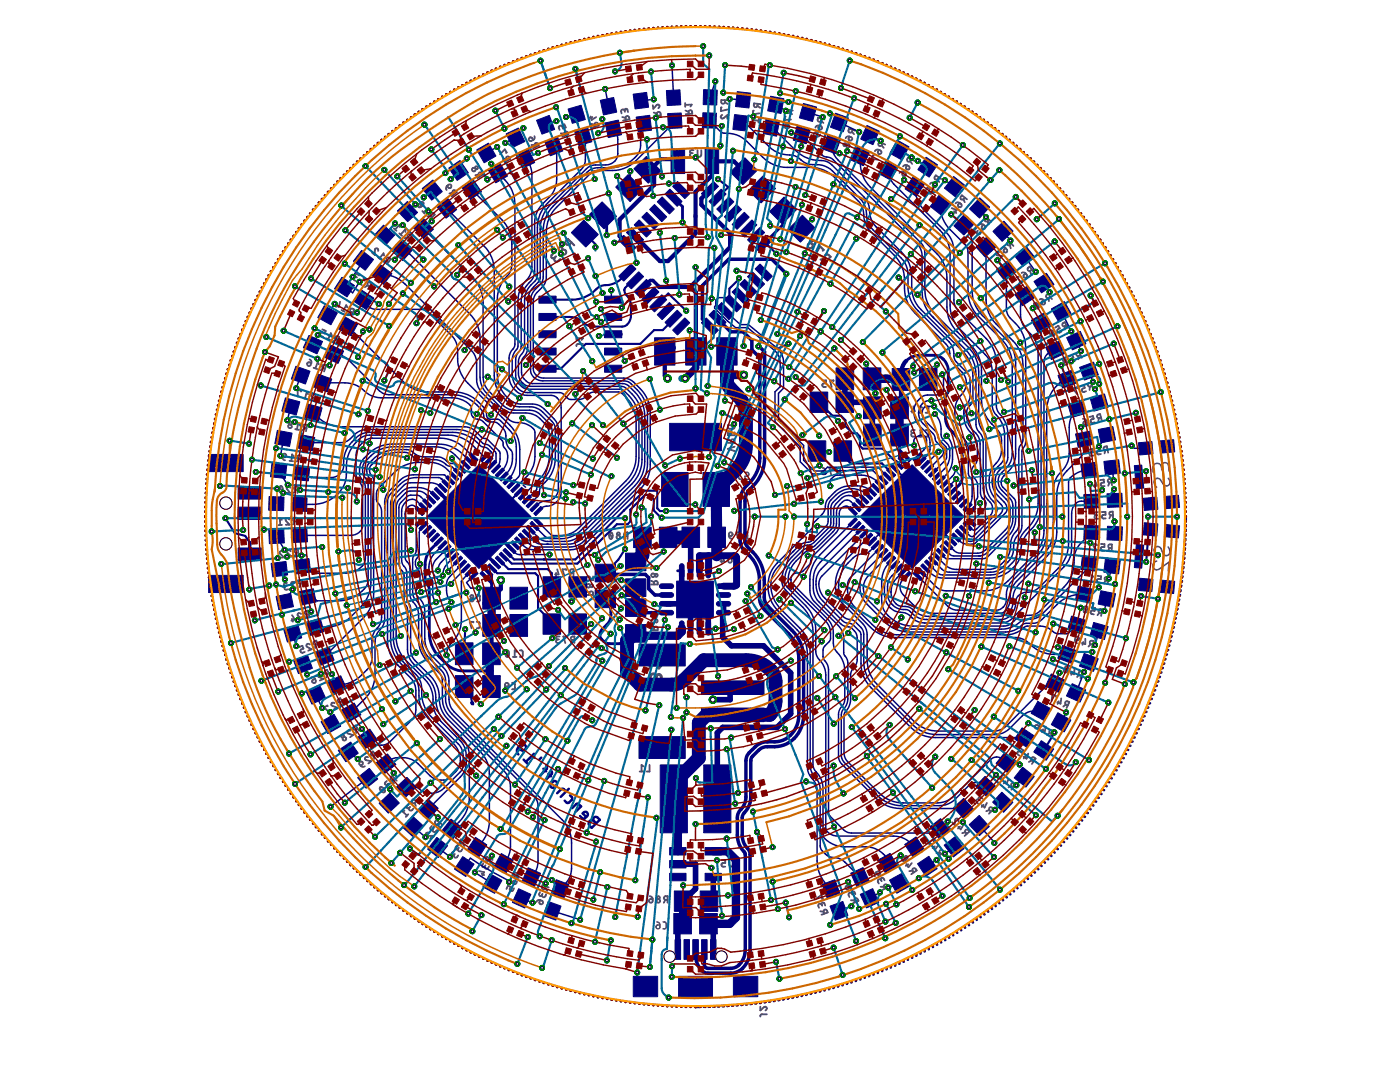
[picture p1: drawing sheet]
<svg xmlns="http://www.w3.org/2000/svg" width="279mm" height="216mm" viewBox="0 0 279 216" stroke-linecap="round" stroke-linejoin="round" font-family="sans-serif">
<g fill="none" stroke="#505050" stroke-width=".36">
<path d="M89.2 37.1l.3-.2a.37 .37 0 0 1 .5 0 .37 .37 0 0 1 0 .5 .37 .37 0 0 1-.5 0zM89.2 37.1l-.2 .5 .1 .3M90.3 38.5l-.6 .1M90.6 38.8l-.2-.3a.36 .36 0 0 1 0-.5 .36 .36 0 0 1 .5 .1l.3 .3-1.1 .8M95.5 34.9l-.6 .1M95.8 35.2l-.2-.3a.36 .36 0 0 1 .1-.5 .36 .36 0 0 1 .5 .1l.2 .3-1.1 .8M101 31.7h-.6M101 30.5l.1-.1-.3-.6-1 1M101.2 32.1l-.2-.4a.36 .36 0 0 1 .2-.4 .36 .36 0 0 1 .5 .1l.1 .3-1.1 .7M105.6 27.5l.4-.1 .4 .6-.6 .1-.2-.2zM106 28.9l.7 .1M106.7 27.2v.3l-.3 .5"/>
<path d="M106.9 29.4l-.2-.7 .4-.2 .4 .5-1.1 .6M111.9 26.6l.7 .1M112.6 24.8l.3 .6-.5 .3-.3-.6h-.4l-.2 .3 .2 .5M112.7 27.1l-.1-.4a.36 .36 0 0 1 .2-.4 .36 .36 0 0 1 .5 .2l.1 .3-1.2 .5M117.9 23.2l.2 .7 .9-.5M118 24.7l.6 .1M118.2 23.4l-.6 .1M118.8 25.3l-.1-.4a.37 .37 0 0 1 .2-.4 .37 .37 0 0 1 .5 .2l.1 .4-1.3 .3M124.2 23.3l.6 .2M124.7 22.1a.36 .36 0 0 0-.5-.3 .36 .36 0 0 0-.2 .5v.3M124.7 22.3v-.4l.2-.2 .3 .1 .1 .6M124.9 23.9v-.6l.4-.1 .3 .6-1.2 .3"/>
<path d="M130.3 21l.1 .7 .6-.7a.36 .36 0 0 1 .6 0 .36 .36 0 0 1-.2 .6M130.5 22.5l.6 .2M131.1 23.1v-.4a.36 .36 0 0 1 .3-.4 .36 .36 0 0 1 .4 .3l.1 .4-1.3 .2M136.7 20.6l.1 .7M136.8 20.9h1.2l-.2 .4M136.8 22.1l.6 .2M137.4 22.7l.1-.6a.36 .36 0 0 1 .4-.1 .36 .36 0 0 1 .2 .4l.1 .3-1.4 .1M138 30.6a.36 .36 0 0 0-.3 .3 .36 .36 0 0 0 .3 .4h.4M138.4 30h-.4l-.3 .2 .1 .3 .5 .1M139.2 30v.9a.37 .37 0 0 0 .4 .4 .37 .37 0 0 0 .4-.4v-.9M144 21.4h-.1v.8l1.3-.4M144.1 22.9a.36 .36 0 0 0-.3 .5 .36 .36 0 0 0 .6 .2l.8-.6-.1 .7"/>
<path d="M144.7 20v.4a.37 .37 0 0 1-.4 .3 .37 .37 0 0 1-.4-.4l.1-.3h1.3M144.7 20.4l.5 .3M150.4 23.6l-.3 .3 1.3 .2M150.5 22.1h-.2l-.1 .7 1.4-.2M151.2 21.1l.5 .4M151.2 20.7v.4a.37 .37 0 0 1-.4 .3 .37 .37 0 0 1-.4-.4l.1-.4 1.3 .2M151.4 23.7v.7M156.3 25a.73 .73 0 0 1 1.2 .4 .73 .73 0 0 1-1.2-.4zM156.8 23.3l-.1-.1-.2 .8 1.4-.1M157.4 25l-.9 .4M157.6 22.4l.5 .4M157.6 21.9l-.2 .6-.3 .1-.2-.3v-.5l1.3 .3"/>
<path d="M162.5 26.5l.3-.1 .3 .2-.1 .6-.6-.3zM163.4 25.1h.4a.37 .37 0 0 1 .3 .5 .37 .37 0 0 1-.5 .3 .37 .37 0 0 1-.3-.4zM163.4 25.1l-.5 .1-.2 .3M163.7 26.8l-.2 .3-.5 .1M163.9 24.1l.4 .4M164 23.7l-.1 .3a.36 .36 0 0 1-.5 .3 .36 .36 0 0 1-.2-.5l.1-.3 1.2 .3M169.5 27.2l.3 .2a.36 .36 0 0 1 .3 .4 .36 .36 0 0 1-.5 .3 .36 .36 0 0 1-.2-.5zM169.5 27.2h-.4l-.3 .4M170 26.3l.5 .5M170.1 25.9l-.1 .3a.37 .37 0 0 1-.4 .3 .37 .37 0 0 1-.3-.5l.2-.3 1.2 .4M174.4 31.1l-.2-.1-.3 .7 1.4 .2M175.4 29.9l.3 .1a.37 .37 0 0 1 .2 .5 .37 .37 0 0 1-.5 .2 .37 .37 0 0 1-.2-.4z"/>
<path d="M175.4 29.9h-.5l-.3 .3M175.9 29l.5 .5M176.1 28.6l-.4 .5-.4-.1 .2-.7 1.2 .6M180.3 34.3l.3 .2a.36 .36 0 0 1 .2 .5 .36 .36 0 0 1-.5 .1 .36 .36 0 0 1-.2-.4zM180.3 34.3h-.5l-.3 .2M181 33l.4 .2a.37 .37 0 0 1 .1 .4 .37 .37 0 0 1-.5 .2 .37 .37 0 0 1-.2-.4zM181 33l-.3-.1-.5 .3M181.7 32.2l.3 .5M181.9 31.8l-.2 .3a.36 .36 0 0 1-.5 .1 .36 .36 0 0 1-.1-.5l.1-.3 1.2 .7M184.7 38.1l.4-.7 .5 .4-.2 .3a.36 .36 0 0 0 .1 .5 .36 .36 0 0 0 .4-.1l.3-.3M186.4 36.5l.3 .2a.37 .37 0 0 1 .1 .5 .37 .37 0 0 1-.4 .2 .37 .37 0 0 1-.2-.5zM186.4 36.5l-.3-.1-.5 .3"/>
<path d="M187.1 35.8l.3 .5M187.3 35.4l-.4 .5-.4-.3 .3-.6 1 .7M192.3 39.8l.2 .5M192.5 39.4l-.5 .4a.35 .35 0 0 1-.3-.2 .35 .35 0 0 1 0-.3l.3-.3 1 .8M71.1 55.2a.37 .37 0 0 0-.6 .2 .37 .37 0 0 0 .2 .5l.3 .1M71.6 56.5l.6 .4M71.7 55l-.5-.3-.2 .1-.1 .3 .3 .3M72.8 56l-.2-.4-.7 1.1M73.4 56.9l-.6 .4M73.8 57.2l-.5-.5 .2-.4 .6 .3-.7 1.1M75.5 50.1a.35 .35 0 0 0-.3-.5 .35 .35 0 0 0-.4 .3v1l-.5-.4M75.5 51.4l.5 .4"/>
<path d="M76.6 51l-.1-.5-.8 1.1M77.2 52l-.6 .3M77.6 52.2l-.3-.2a.37 .37 0 0 1-.1-.5 .37 .37 0 0 1 .5-.1l.3 .3-.8 1M78.6 45.6l.5 .5M79.7 46.6l.5 .5M79.8 45.3l-.1-.5-.9 1M80.9 46.3l-.1-.5-.8 1M81.4 47.3l-.6 .2M81.7 47.6l-.4-.5 .3-.4 .6 .4-.9 .9M83.8 40.6l.4-.3 .3 .1a.78 .78 0 0 1-1 .9v-.3zM84.1 40.4l-.2 .9M84.3 42.1l.5 .6"/>
<path d="M85.5 42v-.5l-1 .9M85.9 43l-.6 .2M86.2 43.3l-.2-.2a.37 .37 0 0 1 0-.6 .37 .37 0 0 1 .5 0l.3 .3-1 .9M189.9 41.5l1 .4-.4 .6M190.4 42.1l.4 .4M191.5 40.5l.3 .2a.37 .37 0 0 1 .1 .5 .37 .37 0 0 1-.5 .1 .37 .37 0 0 1-.2-.5zM191.5 40.5l-.3-.1-.5 .2M194.8 45.5l-.3 .5v.2l.4 .1 .3-.3M195 46.2a.37 .37 0 0 0 0 .5 .37 .37 0 0 0 .6 0l.2-.3M196.3 44.8l.2 .3a.36 .36 0 0 1 .1 .5 .36 .36 0 0 1-.5 0 .36 .36 0 0 1-.1-.5zM196.3 44.8l-.5-.1-.3 .2M197.1 44.2l.2 .6"/>
<path d="M197.4 43.8l-.6 .4-.3-.3 .3-.6 1 .9M199.4 50.3a.36 .36 0 0 0-.6 .2 .36 .36 0 0 0 .3 .5l1 .1-.5 .5M199.9 49.5l.3-.2 .5 .2M200.4 49.8l.3-.3 .2 .3a.36 .36 0 0 1 0 .5 .36 .36 0 0 1-.5 0 .36 .36 0 0 1 0-.5zM201.5 48.9l.2 .7M201.8 48.6l-.5 .4-.3-.4 .4-.5 .8 1M203.3 55.3h-.4l.8 1M203.9 54.5l.5-.1 .3 .2M204 56.1l-.6 .4M204.3 54.9l.4-.3 .2 .2a.37 .37 0 0 1-.2 .6 .37 .37 0 0 1-.4-.5zM205.6 54l.1 .7M206 53.8l-.3 .2a.36 .36 0 0 1-.6-.1 .36 .36 0 0 1 .1-.5l.3-.2 .8 1"/>
<path d="M207.5 59.8l.4-.2 .4 .3M209.3 59.5v.6M209.6 59.2l-.3 .2a.37 .37 0 0 1-.5-.1 .37 .37 0 0 1 .1-.5l.3-.2 .7 1.1M60.1 78.1v-.1l-.7-.2v1.3M60.5 79.4l.7 .2M61.4 72.3l.7 .2-.1 .3a.37 .37 0 0 1-.6 .1 .37 .37 0 0 1 0-.6zM61.5 78.7l-.3-.4-.3 1.2M61.8 71.7l.3 .4v.4M62.4 79.4l-.5 .4M62.6 73.4l.7 .2M62.8 79.5l-.6-.3 .1-.5 .7 .1-.4 1.2M63.6 72.7l-.2-.4-.5 1.2"/>
<path d="M64.3 65.7l.7 .3-.2 .5-.4-.1a.37 .37 0 0 0-.4 .2 .37 .37 0 0 0 .1 .4l.4 .2M64.5 73.4l-.5 .5M64.9 73.6l-.6-.4 .2-.4 .6 .1-.4 1.2M65.2 67.5l.6 .3M66.2 66.9l-.2-.4-.5 1.2M67 67.7l-.5 .4M67.3 60.7l-.2 .6M67.4 67.9l-.3-.1a.37 .37 0 0 1-.2-.5 .37 .37 0 0 1 .5-.2l.3 .1-.5 1.2M67.9 60.2l-.3 1.1-.6-.4M68.2 61.9l.6 .3M69.3 61.3l-.2-.4-.6 1.1M70 62.2l-.6 .4"/>
<path d="M70.4 62.4l-.5-.4 .1-.3 .3-.1 .4 .2-.6 1.1M115 67.1v.7M115 67.5h1.4l-.3 .3M116.4 68.6l-1.2 .1-.2 .4M164.1 75.9h.7v.6h-.4a.37 .37 0 0 0-.3 .4 .37 .37 0 0 0 .3 .3h.4M166.3 76.1v-.2h-.7l.4 1.3M167.4 76.6l-.3 .6M167.8 76.6h-.4a.37 .37 0 0 1-.3-.3 .37 .37 0 0 1 .3-.4h.4v1.3M173.9 74.9h.7v.6h-.4a.36 .36 0 0 0-.3 .4 .36 .36 0 0 0 .3 .3h.4M175.4 76.2h.7M176.1 75.2l-.3-.3v1.3M176.6 75.5l.6-.1v.4a.37 .37 0 0 1-.5 .3 .37 .37 0 0 1-.1-.6z"/>
<path d="M176.6 74.8l.4 .2 .2 .4M176.8 74.9l.4 .1 .2 .2v.9l-.6 .1M178 76.1h.7M178.7 75.1l-.4-.3v1.3M179.4 74.8l.4 .1 .1 .2v.9l-.5 .1M206.4 60.9l.9 .2M206.5 60.5a.77 .77 0 0 1 .7 1 .75 .75 0 0 1-.7-1zM207.9 60.2l.4-.3 .2 .3a.37 .37 0 0 1-.1 .5 .37 .37 0 0 1-.5 0 .37 .37 0 0 1 0-.5zM209.5 66a.37 .37 0 0 1 .6 0 .37 .37 0 0 1-.1 .5l-.4 .2-.2-.4zM209.6 66.7l.3 .3h.5M210.6 65.4l.6-.4 .3 .5-.4 .2a.37 .37 0 0 0-.1 .5 .37 .37 0 0 0 .5 .2l.4-.3M212.5 65.1v.7"/>
<path d="M212.9 64.9l-.7 .2-.2-.4 .5-.4 .6 1.1M213.3 71.1l.7-.3 .2 .6-.4 .1a.37 .37 0 0 0-.1 .5 .37 .37 0 0 0 .4 .2l.4-.2M214.9 77.5v-.2l-.7 .3 .8 1.1M215.2 71v.7M215.6 77.1l.7-.3 .2 .6-.4 .1a.37 .37 0 0 0-.2 .5 .37 .37 0 0 0 .4 .2l.4-.1M215.6 70.9l-.3 .1a.36 .36 0 0 1-.5-.2 .36 .36 0 0 1 .2-.4l.3-.2 .6 1.2M217.5 77.2l-.1 .6M217.9 77l-.3 .1a.36 .36 0 0 1-.5-.2 .36 .36 0 0 1 .2-.4l.4-.2 .4 1.3M55.8 97.3l.5 .7M55.9 97h.1a.66 .66 0 0 1 .4 .6 .66 .66 0 0 1-.5 .7l-.2-.7zM56.4 91.2v.4l.5 .2M56.5 90.6a.37 .37 0 0 1 .6 .2 .37 .37 0 0 1-.3 .4h-.4z"/>
<path d="M57.8 91.9l.7 .1M57.9 97.3a.36 .36 0 0 0-.5-.3 .36 .36 0 0 0-.1 .6l.6 .7h-.7M58.6 91l-.3-.3-.2 1.3M58.9 85.6l.7 .2M58.9 97.8l-.3 .6M59.4 97.8h-.4a.36 .36 0 0 1-.3-.4 .36 .36 0 0 1 .3-.3h.4v1.3M59.6 91.6l-.4 .5M59.8 84.8l-.3-.4-.2 1.3M60 91.6h-.3a.36 .36 0 0 1-.3-.4 .36 .36 0 0 1 .4-.4l.3 .1-.1 1.3M60.7 85.4l-.4 .5M61.2 85.5l-.4-.1a.37 .37 0 0 1-.3-.4 .37 .37 0 0 1 .4-.3l.4 .1-.2 1.2M145.3 88.4h1.3v-.4a.37 .37 0 0 0-.4-.3 .37 .37 0 0 0-.3 .3v.4"/>
<path d="M145.3 86.3v.5h1.3v-.5M145.3 87.7l.6 .2M146 86.4v.4M146.6 84.8l-.1 .7-.9 .1-.3-.2v-.6h.7v.2M146.6 89.1l-1.3 .5 1.3 .4M164.1 94l.6-.1v.4a.38 .38 0 0 1-.5 .3 .38 .38 0 0 1-.1-.6zM164.1 93.4l.4 .1 .2 .4M166.2 93.5v-.1h-.7l.4 1.3M167.3 94.1l-.3 .6M167.7 94.1h-.4a.36 .36 0 0 1-.3-.4 .36 .36 0 0 1 .3-.3h.4v1.3M182.1 81.8v.6M182.2 86.4a.37 .37 0 0 0-.4 .4 .37 .37 0 0 0 .4 .3h.4"/>
<path d="M182.3 81.1l.3 1h-.8M182.6 85.8h-.6l-.2 .2 .2 .4h.4M183.3 87.1h.8M183.3 82.4h.8M184.1 86.1l-.4-.3v1.3M184.1 81.3l-.4-.2v1.3M184.7 85.8h.4l.2 .3-.1 .9-.5 .1M184.7 81.1h.4l.2 .2-.1 1-.5 .1M216.1 83.6l.5 .1 .2 .3M216.3 84.2l.5-.2 .1 .3a.38 .38 0 0 1-.4 .5 .38 .38 0 0 1-.2-.6zM217.3 89.7l.7-.1 .1 .6-.4 .1a.37 .37 0 0 0-.2 .4 .37 .37 0 0 0 .3 .3l.4-.1M217.4 83.2l.7-.2 .2 .6-.5 .1a.38 .38 0 0 0-.1 .4 .38 .38 0 0 0 .4 .3l.4-.1"/>
<path d="M218.4 96.7l.1 .5M218.5 95.9l.4 1-.7 .1M218.7 89.5l.8-.2 .1 .6-.5 .1a.36 .36 0 0 0-.2 .4 .36 .36 0 0 0 .4 .3l.4-.1M219.3 83.4l-.1 .7M219.6 95.8l.7-.1v.6h-.4a.37 .37 0 0 0-.2 .4 .37 .37 0 0 0 .3 .3h.5M219.7 83.3l-.6 .1-.2-.3 .1-.3 .5-.2 .4 1.3M220.6 89.8l-.2 .7M221 89.7l-.3 .1a.36 .36 0 0 1-.5-.3 .36 .36 0 0 1 .3-.4l.4-.1 .2 1.3M221.4 96.3l-.2 .6M221.8 96.2l-.3 .1a.36 .36 0 0 1-.4-.3 .36 .36 0 0 1 .3-.4l.3-.1 .2 1.3M56.2 103.7l-.3-.2v1.3M56.3 104.8h-.8"/>
<path d="M56.5 110.2a.35 .35 0 0 0-.5-.2 .35 .35 0 0 0 0 .6l.7 .6-.8 .1M57 117l-.3 .3a.35 .35 0 0 0 .5 .4l.4-.1M57.3 116.3l-.6 .2-.1 .2 .1 .2h.6M57.7 103.7a.36 .36 0 0 0-.5-.3 .36 .36 0 0 0-.1 .6l.7 .7h-.8M58 110a.36 .36 0 0 0-.5-.2 .36 .36 0 0 0-.1 .6l.7 .6-.7 .1M58.8 104.1l-.3 .5M58.8 116.3a.36 .36 0 0 0-.6-.2 .36 .36 0 0 0 .1 .6l.7 .6-.7 .2M59.1 110.3l-.2 .6M59.2 104l-.4 .1a.37 .37 0 0 1-.3-.4 .37 .37 0 0 1 .3-.4h.4v1.3M59.5 110.3l-.6-.1-.1-.5 .6-.2 .2 1.3M59.9 116.5l-.2 .7M60.3 116.4l-.3 .1a.36 .36 0 0 1-.5-.3 .36 .36 0 0 1 .3-.4l.4-.1 .3 1.3"/>
<path d="M95.2 118.7h.4l.2 .3v.8l-.6 .2M111 114.3v.6M111.2 113.6l.3 1h-.7M113 113.7v-.1h-.8l.4 1.3M114 114.3l-.3 .6M114.4 114.3h-.3a.36 .36 0 0 1-.4-.3 .36 .36 0 0 1 .4-.4h.3v1.3M117.1 118.7h1.3v-.4a.36 .36 0 0 0-.4-.3 .36 .36 0 0 0-.4 .3v.4M117.1 118l.5 .3M118.4 115v.8h-.6v-.5a.38 .38 0 0 0-.4-.3 .38 .38 0 0 0-.3 .3v.5M121.6 106.5l.6 .8M121.7 106.3h.1a.69 .69 0 0 1 .5 .6 .69 .69 0 0 1-.4 .6 .82 .82 0 0 1-.2-1.2zM124.8 107l-.3 .5"/>
<path d="M125.2 107h-.3a.36 .36 0 0 1-.4-.4 .36 .36 0 0 1 .4-.4h.3v1.3M130 116.6h1.3v-.3a.36 .36 0 0 0-.4-.4 .36 .36 0 0 0-.4 .4v.3M130 115.9l.5 .3M130 113.3h1.3l-.3 .4M130 112.9v.8M144 111.7v.6M144.2 111l.3 1h-.7M145.3 111v.9a.36 .36 0 0 0 .4 .4 .36 .36 0 0 0 .3-.4v-.9M145.5 106.9l.2 .5 .3 .1M145.6 106.3a.37 .37 0 0 1 .5 .1 .37 .37 0 0 1-.2 .5h-.4zM147.7 106.4v-.2h-.7l.3 1.3M148.7 106.9l-.3 .6"/>
<path d="M149.2 106.9h-.4a.36 .36 0 0 1-.4-.3 .36 .36 0 0 1 .4-.4h.4v1.3M217.4 116l.7 .1M218.2 115.1l-.3-.3-.2 1.3M218.8 102.8l-.3 .1-.1 .4 .3 .2h.5M218.9 108.8a.35 .35 0 0 0-.5-.3 .35 .35 0 0 0-.1 .6l.6 .7h-.7M219 114.9l.8 .1-.1 .6-.6-.1-.2 .4 .1 .3 .6 .1M219.1 102.2l-.5 .1-.2 .1 .2 .4h.4M219.7 108.5l.7 .1v.6l-.4-.1a.38 .38 0 0 0-.3 .4 .38 .38 0 0 0 .2 .4h.5M219.9 102.2h.7v.5h-.4a.37 .37 0 0 0-.3 .4 .37 .37 0 0 0 .3 .4l.5-.1M220.7 115.8l-.4 .6M221.1 115.9l-.6-.2 .1-.5h.6l-.2 1.3M221.4 109.3l-.3 .6"/>
<path d="M221.7 102.8l-.3 .6M221.9 109.4l-.4-.1a.36 .36 0 0 1-.3-.3 .36 .36 0 0 1 .3-.4h.4l-.1 1.3M222.1 102.8l-.7-.1v-.5l.7-.1v1.3M58.3 123.5l.1 .6M58.3 122.7l.5 .9-.7 .2M59.7 129.1l.6-.2 .3 .5-.5 .2a.38 .38 0 0 0-.1 .4 .38 .38 0 0 0 .4 .3l.4-.2M60.1 122.5a.36 .36 0 0 0-.6-.1 .36 .36 0 0 0 .1 .6l.8 .5-.7 .2M61.2 122.6l-.1 .7M61.6 122.5l-.5 .1a.35 .35 0 0 1-.3-.3 .35 .35 0 0 1 .3-.4l.3-.1 .4 1.3M61.8 128.6a.36 .36 0 0 0-.5-.1 .36 .36 0 0 0 .1 .6l.8 .5-.7 .2M62.1 135.2l.3-.1 .4 .3M62.4 135.7l.4-.3 .2 .4a.37 .37 0 0 1-.4 .5 .37 .37 0 0 1-.2-.6z"/>
<path d="M62.9 128.7v.6M63.4 128.5l-.4 .1a.36 .36 0 0 1-.4-.2 .36 .36 0 0 1 .2-.4l.3-.2 .5 1.3M64.1 134.6a.36 .36 0 0 0-.6-.1 .36 .36 0 0 0 .1 .6l.9 .4-.7 .3M65.2 134.5v.7M65.6 134.3l-.3 .2a.37 .37 0 0 1-.5-.2 .37 .37 0 0 1 .2-.5l.3-.1 .5 1.2M68.3 140l-.4 .1a.37 .37 0 0 1-.4-.1 .37 .37 0 0 1 .1-.5l.3-.2 .6 1.2M94.5 124.2v-.1h-.8l.4 1.3M95.1 124.1h.5l.1 .3v.8l-.6 .2M100.8 137l.2 .4 .4 .1M100.9 136.4a.36 .36 0 0 1 .6 0 .36 .36 0 0 1-.3 .6h-.4zM100.9 130.1l.6 .7M101 129.9l.2-.1a.78 .78 0 0 1 0 1.3 .83 .83 0 0 1-.2-1.2z"/>
<path d="M102.2 136.2l.4 .1 .2 .2-.1 .9-.5 .1M102.4 131.1h.7M103.1 130.1l-.4-.3v1.3M103.8 129.8h.4l.1 .3v.8l-.5 .2M111.3 127.6a.36 .36 0 0 0-.3 .4 .36 .36 0 0 0 .3 .3h.4M111.7 127h-.4l-.3 .2v.3l.5 .1M113.2 127.1v-.1h-.8l.4 1.3M114.2 127.7l-.3 .6M114.6 127.7h-.3a.37 .37 0 0 1-.4-.3 .37 .37 0 0 1 .4-.4h.3v1.3M130 125.8h1.3v-.4a.36 .36 0 0 0-.4-.4 .36 .36 0 0 0-.4 .4v.4M130 122v.8l.7-.6a.36 .36 0 0 1 .5 .1 .36 .36 0 0 1-.2 .5M130 125l.5 .3"/>
<path d="M210.7 139v-.1l-.6-.3-.3 1.3M211.3 139.9l-.2 .6M211.8 139.4l-.2 1-.6-.3M214 134.1l-.2 .6M214.4 133.5v1.1l-.7-.3M214.5 127.6l.2 .6 .2 .2M214.7 127.1a.37 .37 0 0 1 .6 .2 .37 .37 0 0 1-.3 .5l-.5-.2zM215.4 134.6l-.5 .5M215.8 134.8l-.5-.3v-.4l.3-.1 .5 .1-.5 1.2M216.2 128.1l-.2 .6M216.4 121.2l.4 .8M216.5 121.1l.2-.1a.76 .76 0 0 1-.2 1.2l-.2-.1-.1-.3z"/>
<path d="M216.6 127.5v1l-.7-.2M217.7 128.5l-.5 .5M217.8 121.2l.8 .1-.2 .6-.4-.1a.36 .36 0 0 0-.3 .3 .36 .36 0 0 0 .2 .4l.4 .1M218.1 128.7l-.6-.4 .1-.4h.7l-.4 1.3M219.4 122.2l-.4 .5M219.9 122.3l-.7-.2 .1-.5h.7l-.2 1.3M65.4 140.9l-.1-.1-.6 .3 1 1M66.8 140.3a.36 .36 0 0 0-.6 0 .36 .36 0 0 0 .2 .6l.9 .3-.7 .3M67.9 140.2v.6M69.9 145.8a.36 .36 0 0 0-.6 .1 .36 .36 0 0 0 .3 .5l.9 .3-.6 .4M71 145.6l.1 .7M71.4 145.4l-.3 .2a.36 .36 0 0 1-.6-.1 .36 .36 0 0 1 .2-.5l.3-.2 .7 1"/>
<path d="M71.8 152a.37 .37 0 0 1 .5 .1 .37 .37 0 0 1 0 .4l-.3 .3-.3-.4zM72 152.8l.3 .2 .5-.1M73.4 151.1a.36 .36 0 0 0-.5 .1 .36 .36 0 0 0 .3 .5l.9 .2-.6 .4M74.5 150.8l.2 .6M74.9 150.5l-.3 .2a.36 .36 0 0 1-.5 0 .36 .36 0 0 1 0-.5l.3-.3 .8 1.1M75.8 157.5l1 .1M75.9 157.1a.78 .78 0 0 1 .9 1 .75 .75 0 0 1-.9-1zM77.2 155.8l-.3 .3a.29 .29 0 0 0 0 .4 .29 .29 0 0 0 .4 .1l.2-.2M77.3 156.5l-.1 .3 .3 .3 .6-.3M78.5 155.7l.1 .6M78.8 155.4l-.3 .2a.36 .36 0 0 1-.5 0 .36 .36 0 0 1 0-.5l.3-.3 .9 1M83.1 159.9l-.6 .4-.3-.2v-.3l.3-.4 1 .9"/>
<path d="M127.7 153.9h.7M128.4 152.9l-.4-.3v1.3M129.6 152.6v1.3h-.5M195.4 159.6a.37 .37 0 0 0-.5 0 .37 .37 0 0 0 0 .5l.3 .2M196.1 159.4l-.4-.4-.3 .1-.1 .3 .3 .3M199.5 155l-.4 .4M200.1 154.5l-.4 1-.6-.5M200.7 155.9l-.4 .4M201.3 155.4l-.4 1-.6-.4M201.9 156.8l-.6 .3M202.2 157.1l-.4-.5 .3-.3 .5 .2-.8 1.1M203.6 149.3l.6 .4-.3 .5-.5-.3-.4 .2v.3l.5 .4"/>
<path d="M204.6 150.9l-.3 .4M205.2 150.4l-.3 1-.6-.4M205.9 151.7l-.6 .3M206.3 152l-.3-.3a.36 .36 0 0 1-.1-.5 .36 .36 0 0 1 .5 0l.3 .2-.8 1M206.7 144.7h.3l.4 .2-.2 .3a.38 .38 0 0 1-.6 .1 .38 .38 0 0 1 .1-.6zM207.2 144.1l.2 .3v.5M208.2 145.5l-.3 .5M208.7 145l-.2 1-.7-.3M209.5 146.3l-.5 .3M209.9 146.5l-.5-.5 .2-.3 .6 .2-.6 1.1M212.7 140.6l-.5 .4M213.1 140.8l-.3-.2a.36 .36 0 0 1-.2-.5 .36 .36 0 0 1 .5-.1l.3 .1-.5 1.2"/>
<path d="M80.7 161.8l-.4 .1 .9 .9M81.5 162.5l-.5 .5M81.5 160.5l-.3 .4v.3l.4 .1 .3-.3M81.7 161.2l-.1 .3 .2 .2h.3l.4-.3M82.8 160.2l.2 .6M85.5 166.2a.36 .36 0 0 0-.5 .2 .36 .36 0 0 0 .3 .4h1l-.4 .5M86.2 164.8l-.3 .4v.3l.4 .1 .3-.3M86.4 165.4v.2a.36 .36 0 0 0 .2 .4 .36 .36 0 0 0 .4-.1l.2-.3M87.4 164.4l.3 .6M87.7 164.1l-.3 .3a.37 .37 0 0 1-.5 0 .37 .37 0 0 1 0-.5l.2-.3 1 .8M90.4 170l-.3 .5v.2h.4l.3-.3M90.6 170.6l.1 .4 .3 .2 .4-.5"/>
<path d="M91.2 168.7l-.3 .5 .1 .2 .3 .1 .3-.3M91.5 169.4v.4l.3 .1 .5-.5M92.4 168.3l.3 .5M92.6 167.9l-.2 .3a.36 .36 0 0 1-.5 .1 .36 .36 0 0 1-.1-.5l.2-.3 1.1 .7M95.6 173.8l1 .3-.3 .6M96.1 174.3l.5 .3M96.5 172.3l-.3 .3a.29 .29 0 0 0 .2 .4 .29 .29 0 0 0 .4-.1l.1-.2M96.8 172.8a.36 .36 0 0 0 .1 .5 .36 .36 0 0 0 .5-.1l.2-.3M97.6 171.7l.4 .5M97.8 171.3l-.4 .5-.3-.1-.2-.3 .3-.4 1.1 .6M102 175.3l-.2 .6 .1 .2h.4l.2-.4M102.6 177.2l-.3 .6-.4-.1-.2-.2 .2-.5-.5-.3-.3 .7"/>
<path d="M103.1 174.7l.4 .5M103.2 175.9l-.4 .5-.4-.2v-.3M103.3 174.3l-.2 .3a.37 .37 0 0 1-.5 .2 .37 .37 0 0 1-.2-.5l.2-.3 1.2 .6M107.8 178l-.2 .5 .1 .3 .4-.1 .2-.3M107.8 179.6l.3 .1a.36 .36 0 0 1 .3 .5 .36 .36 0 0 1-.5 .2 .36 .36 0 0 1-.2-.4zM107.8 179.6l-.5 .1-.2 .3M108.8 177.3l.4 .5M108.9 176.9l-.1 .3a.36 .36 0 0 1-.4 .2 .36 .36 0 0 1-.3-.4l.2-.4 1.2 .5M109 178.5l-.4 .5h-.3l-.1-.5M129.6 179.5l.7-.1v.4a.38 .38 0 0 1-.6 .3 .38 .38 0 0 1-.1-.6zM129.7 178.8l.5 .3 .1 .3M132.8 179.6l-.3 .5"/>
<path d="M133.2 179.6h-.4a.37 .37 0 0 1-.3-.4 .37 .37 0 0 1 .3-.4h.4v1.3M144 171.6h.7v.6h-.4a.38 .38 0 0 0-.3 .4 .38 .38 0 0 0 .3 .3h.4M145.5 171.6v1a.36 .36 0 0 0 .4 .3 .36 .36 0 0 0 .4-.3v-1M164 179.3h.2l-.3-.7-1.1 .8M169.8 179.6l.7 .1M170 178.3l-.2-.2-.3 .1-.2 .3 .2 .5M170.7 178.4l-.3-.5a.29 .29 0 0 0-.3 0 .29 .29 0 0 0-.1 .4l.1 .2M174.8 174.1l.3-.2a.37 .37 0 0 1 .5 .1 .37 .37 0 0 1-.1 .5 .37 .37 0 0 1-.5 0zM174.8 174.1l-.3 .4 .1 .4M175.9 175.6l-.3-.1h-.3l-.1 .3 .2 .5M176.4 176.9l-.7 .1M176.5 175.7l-.3-.5h-.3l-.1 .2 .2 .4"/>
<path d="M176.6 177.3l-.2-.5 .1-.2 .3-.2 .4 .6-1.1 .6M180.2 171.2l.6-.4 .3 .1a.7 .7 0 0 1-.4 .7 .7 .7 0 0 1-.7 0zM180.7 170.9l-.3 .8M181.3 172.4l-.5 .4M182 172.2l-.7 .8-.4-.6M182.1 173.7l-.6 .1M182.3 174.1l-.2-.3a.37 .37 0 0 1 .1-.5 .37 .37 0 0 1 .6 .1l.1 .3-1 .7M185.1 167.9l.4 .6M186.3 167.9v-.5l-1 .8M186.6 168.9l-.5 .3M187.3 168.6l-.7 .9-.4-.6M187.5 170.1l-.6 .1"/>
<path d="M187.8 170.5l-.2-.3a.37 .37 0 0 1 0-.6 .37 .37 0 0 1 .6 .1l.2 .3-1.1 .8M191.3 163.9a.36 .36 0 0 0-.2-.5 .36 .36 0 0 0-.5 .3l-.1 .9-.5-.5M191.6 164.9l-.4 .4M192.3 164.6l-.6 .9-.5-.5M192.6 166.1l-.6 .1M192.9 166.4l-.2-.3a.36 .36 0 0 1 0-.5 .36 .36 0 0 1 .5 0l.3 .3-1 .9M196.3 160.6l-.4 .4M197 160.2l-.5 .9-.6-.4M197.4 161.6l-.6 .3M197.8 161.9l-.4-.5 .3-.3 .5 .3-.8 1M163.7 181.8l.6 .1M164 180.6l-.2-.3-.5 .2 .1 .6"/>
<path d="M164.5 182.3l-.1-.3a.36 .36 0 0 1 .2-.5 .36 .36 0 0 1 .5 .2l.1 .4-1.2 .4M164.7 180.7l-.2-.5-.3-.1-.2 .2 .1 .4M170.6 180l-.1-.3a.36 .36 0 0 1 .2-.5 .36 .36 0 0 1 .5 .2l.1 .3-1.2 .6M151.7 200.9v.7l.8-.6a.36 .36 0 0 1 .5 .1 .36 .36 0 0 1-.2 .5M153 202.4h-1.1l-.2 .4"/>
<circle cx="94.6" cy="33.8" r=".37"/>
<circle cx="95.1" cy="33.5" r=".3"/>
<circle cx="168.6" cy="28.9" r=".29"/>
<circle cx="169.2" cy="29.1" r=".36"/>
<circle cx="212.4" cy="71.9" r=".28"/>
<circle cx="212.7" cy="72.5" r=".36"/>
<circle cx="57.9" cy="85.1" r=".37"/>
<circle cx="58" cy="84.4" r=".29"/>
<circle cx="94.2" cy="119.7" r=".36"/>
<circle cx="94.2" cy="119" r=".29"/>
<circle cx="117.4" cy="116.9" r=".36"/>
<circle cx="118.1" cy="116.9" r=".29"/>
<circle cx="123.4" cy="106.5" r=".29"/>
<circle cx="123.4" cy="107.2" r=".37"/>
<circle cx="130.3" cy="114.8" r=".36"/>
<circle cx="131" cy="114.8" r=".29"/>
<circle cx="130.3" cy="123.9" r=".36"/>
<circle cx="131" cy="123.9" r=".29"/>
<circle cx="212.6" cy="133.8" r=".37"/>
<circle cx="212.9" cy="133.2" r=".3"/>
<circle cx="68.4" cy="146.9" r=".29"/>
<circle cx="68.7" cy="147.4" r=".36"/>
<circle cx="131.4" cy="179.8" r=".36"/>
<circle cx="131.4" cy="179.1" r=".29"/>
<circle cx="169.1" cy="177.1" r=".36"/>
<circle cx="169.7" cy="176.8" r=".28"/>
</g>
<path d="M129.8 132.1v1.2M129.8 132.7h2.2l-.5 .6M129.9 134.7a.61 .61 0 0 1 .7-.2 .61 .61 0 0 1 .4 .6 .5 .5 0 0 1 .5-.5 .5 .5 0 0 1 .5 .5v.6h-2.2zM131 135.1v.6" fill="none" stroke="#505050" stroke-width=".57"/>
<path d="M148 94.3h-.4l-.2 .3 .1 .9 .5 .1M148.7 94.3h.6l.1 .3-.1 .4h-.6v.6h.7M231.8 93.2a.88 .88 0 0 0-.9-.7 .88 .88 0 0 0-.8 .9v.9M231.9 93.8l-.1-.7a.71 .71 0 0 1 .6-.8 .71 .71 0 0 1 .8 .6l.1 1.1M233.2 95.4a.79 .79 0 0 1 .2 1.1 .79 .79 0 0 1-1.1 .3l-.7-1a.76 .76 0 0 0-1.1-.1 .76 .76 0 0 0 0 1.1l.3 .4M230.8 112a.86 .86 0 0 0-.7 1.1 .86 .86 0 0 0 1.3 .4l1.9-1.3-.1 1.7M233.1 109.1a.97 .97 0 0 1 .4 1 .97 .97 0 0 1-.8 .8l-.5-.3-.5-1.1a.76 .76 0 0 0-1.1-.4 .76 .76 0 0 0-.2 1.1l.1 .3M131 184.7l.7-.1v.4a.39 .39 0 0 1-.5 .3 .39 .39 0 0 1-.2-.6zM131.1 184l.5 .2 .1 .4M132.3 184h.5l.1 .3v.9l-.6 .1" fill="none" stroke="#505050" stroke-width=".3"/>
<g fill="none" stroke="#505050" stroke-width=".42">
<path d="M110.5 50.5l-.4 .4a.4 .4 0 0 0 0 .5 .4 .4 0 0 0 .6 0l.3-.2M110.7 51.4a.49 .49 0 0 0 0 .7 .49 .49 0 0 0 .7 0l.4-.4M113.6 48.8l.3 .8M114 48.4l-.3 .3a.51 .51 0 0 1-.7 0 .51 .51 0 0 1 0-.7l.3-.3 1.3 1.2M164.2 50l.2-.1-.7-.7-1 1.6M164.6 51.5l-.8 .3M165 52l-.3-.4a.49 .49 0 0 1 0-.7 .49 .49 0 0 1 .7 0l.4 .3-1.3 1.3"/>
<circle cx="111.9" cy="49.7" r=".4"/>
<circle cx="112.5" cy="50.3" r=".5"/>
<circle cx="161.7" cy="49" r=".5"/>
<circle cx="162.3" cy="48.4" r=".4"/>
</g>
<g fill="none" stroke="#000080" stroke-width=".49">
<path d="M103.5 149.1l-.3 .7 .3 .7M103.9 148.7a.63 .63 0 0 1 .9 0 .63 .63 0 0 1 .1 .8 .63 .63 0 0 1-.9 .1l-.5-.5zM104.5 151.6l.9 .9M106.6 151.2v-.8l-1.7 1.6M108 151.2l-.3 .3M108.4 153.4l.6 .5M109 152.8l.2 .6-1.5 1.4M109.4 154.4l.6 .5M110 153.8l.2 .5-1.5 1.5M110.3 156a.51 .51 0 0 1 .7 0 .51 .51 0 0 1 0 .7l-.3 .4a.5 .5 0 0 1-.7 0 .5 .5 0 0 1 0-.8zM113 157.9l-.6-.5h-.3l-.9 .9M113.5 157.4l-1.6 1.6"/>
<path d="M113.7 158.7l.5 .5-.1 .4-.8 .6-.6-.4M114.2 161.3l1.1-1 .7 .6-1.1 1.1M115.8 162.8l.7 .6 .7-.6a.53 .53 0 0 0-.1-.8 .53 .53 0 0 0-.8 .3l.7 .7M117.7 163.8l.5-.1 .4 .2a.5 .5 0 0 1-.1-.8 .5 .5 0 0 1 .8 0l.4 .5-1.6 1.6-.6-.7v-.4zM118.6 163.9l.4 .4"/>
</g>
<g fill="#000080" stroke="#000080" stroke-width=".2">
<path d="M95.6 92.7l10.4 10.4-10.4 10.3-10.4-10.3z"/>
<path d="M101.2 97.1l1.4-1.4 .4 .4-1.4 1.4z"/>
<path d="M101.9 97.9l1.4-1.4 .5 .4-1.5 1.4z"/>
<path d="M102.7 98.6l1.4-1.4 .4 .4-1.4 1.5z"/>
<path d="M103.4 99.4l1.5-1.4 .4 .4-1.4 1.4z"/>
<path d="M104.2 100.2l1.4-1.4 .5 .4-1.5 1.4z"/>
<path d="M105 100.9l1.4-1.4 .4 .4-1.4 1.5z"/>
<path d="M105.7 101.7l1.5-1.4 .4 .4-1.4 1.4z"/>
<path d="M106.5 102.5l1.4-1.5 .5 .5-1.5 1.4z"/>
<path d="M100.4 96.3l1.4-1.4 .4 .4-1.4 1.5z"/>
<path d="M101 94.1l.5 .5-1.5 1.4-.4-.4z"/>
<path d="M98.8 94.8l1.5-1.4 .4 .4-1.4 1.4z"/>
<path d="M98.1 94l1.4-1.4 .4 .4-1.4 1.5z"/>
<path d="M97.3 93.3l1.4-1.5 .4 .5-1.4 1.4z"/>
<path d="M96.5 92.5l1.5-1.4 .4 .4-1.4 1.4z"/>
<path d="M95.8 91.7l1.4-1.4 .4 .4-1.4 1.5z"/>
<path d="M88.2 110l1.4-1.4 .4 .5-1.4 1.4z"/>
<path d="M87.4 109.3l1.4-1.4 .5 .4-1.5 1.4z"/>
<path d="M86.7 108.5l1.4-1.4 .4 .4-1.4 1.4z"/>
<path d="M85.9 107.8l1.4-1.5 .4 .5-1.4 1.4z"/>
<path d="M85.1 107l1.5-1.4 .4 .4-1.4 1.4z"/>
<path d="M84.3 106.2l1.5-1.4 .4 .4-1.4 1.4z"/>
<path d="M83.6 105.5l1.4-1.5 .4 .5-1.4 1.4z"/>
<path d="M82.8 104.7l1.4-1.4 .5 .4-1.5 1.4z"/>
<path d="M89 110.8l1.4-1.4 .4 .4-1.4 1.5z"/>
<path d="M89.7 111.6l1.4-1.4 .5 .4-1.5 1.4z"/>
<path d="M90.5 112.4l1.4-1.5 .4 .5-1.4 1.4z"/>
<path d="M92.7 111.7l.4 .4-1.4 1.4-.4-.4z"/>
<path d="M92 113.9l1.5-1.4 .4 .4-1.4 1.4z"/>
<path d="M92.8 114.7l1.4-1.5 .4 .5-1.4 1.4z"/>
<path d="M93.6 115.4l1.4-1.4 .4 .4-1.4 1.4z"/>
<path d="M101.6 108.6l1.4 1.4-.4 .5-1.4-1.4z"/>
<path d="M100.8 109.4l1.4 1.4-.4 .5-1.4-1.5z"/>
<path d="M100 110.2l1.5 1.4-.5 .4-1.4-1.4z"/>
<path d="M99.3 110.9l1.4 1.5-.4 .4-1.5-1.4z"/>
<path d="M98.5 111.7l1.4 1.4-.4 .4-1.4-1.4z"/>
<path d="M97.7 112.5l1.4 1.4-.4 .4-1.4-1.4z"/>
<path d="M97 113.2l1.4 1.5-.4 .4-1.5-1.4z"/>
<path d="M96.2 114l1.4 1.4-.4 .4-1.4-1.4z"/>
<path d="M102.3 107.9l1.5 1.4-.5 .4-1.4-1.4z"/>
<path d="M103.1 107.1l1.4 1.4-.4 .4-1.4-1.4z"/>
<path d="M103.9 106.3l1.4 1.5-.4 .4-1.5-1.4z"/>
<path d="M104.6 105.6l1.5 1.4-.5 .4-1.4-1.4z"/>
<path d="M105.4 104.8l1.4 1.4-.4 .4-1.4-1.4z"/>
<path d="M106.2 104l1.4 1.5-.4 .4-1.5-1.4z"/>
<path d="M106.9 103.3l1.5 1.4-.5 .4-1.4-1.4z"/>
<path d="M88.6 95.7l1.4 1.4-.4 .4-1.4-1.4z"/>
<path d="M89.4 94.9l1.4 1.4-.4 .5-1.4-1.5z"/>
<path d="M90.1 94.1l1.5 1.5-.5 .4-1.4-1.4z"/>
<path d="M90.9 93.4l1.4 1.4-.4 .4-1.4-1.4z"/>
<path d="M91.3 93l.4-.4 1.4 1.4-.4 .5z"/>
<path d="M92 92.3l.5-.5 1.4 1.5-.4 .4z"/>
<path d="M93.2 91.1l1.4 1.4-.4 .4-1.4-1.4z"/>
<path d="M93.6 90.7l.4-.4 1.4 1.4-.4 .5z"/>
<path d="M87.8 96.5l1.5 1.4-.5 .4-1.4-1.4z"/>
<path d="M86.7 97.6l.4-.4 1.4 1.4-.4 .5z"/>
<path d="M86.3 98l1.4 1.4-.4 .4-1.4-1.4z"/>
<path d="M85.1 99.2l.5-.4 1.4 1.4-.4 .4z"/>
<path d="M84.3 99.9l.5-.4 1.4 1.4-.4 .5z"/>
<path d="M84 100.3l1.4 1.4-.4 .4-1.4-1.4z"/>
<path d="M82.8 101.5l.4-.5 1.5 1.5-.5 .4z"/>
<path d="M171.7 103.1l10.3-10.4 10.4 10.4-10.4 10.3z"/>
<path d="M174.6 110l1.5-1.4 .4 .5-1.5 1.4z"/>
<path d="M173.9 109.3l1.4-1.4 .4 .4-1.4 1.4z"/>
<path d="M173.1 108.5l1.4-1.4 .4 .4-1.4 1.4z"/>
<path d="M172.3 107.8l1.5-1.5 .4 .5-1.4 1.4z"/>
<path d="M171.6 107l1.4-1.4 .4 .4-1.4 1.4z"/>
<path d="M170.8 106.2l1.4-1.4 .4 .4-1.4 1.4z"/>
<path d="M170 105.5l1.4-1.5 .5 .5-1.4 1.4z"/>
<path d="M169.3 104.7l1.4-1.4 .4 .4-1.4 1.4z"/>
<path d="M175.4 110.8l1.4-1.4 .4 .4-1.4 1.5z"/>
<path d="M176.2 111.6l1.4-1.4 .4 .4-1.4 1.4z"/>
<path d="M176.9 112.4l1.5-1.5 .4 .5-1.4 1.4z"/>
<path d="M177.7 113.1l1.4-1.4 .4 .4-1.4 1.4z"/>
<path d="M178.5 113.9l1.4-1.4 .4 .4-1.4 1.4z"/>
<path d="M179.2 114.7l1.5-1.5 .4 .5-1.4 1.4z"/>
<path d="M180 115.4l1.4-1.4 .4 .4-1.4 1.4z"/>
<path d="M187.6 97.1l1.4-1.4 .4 .4-1.4 1.4z"/>
<path d="M188.4 97.9l1.4-1.4 .4 .4-1.4 1.4z"/>
<path d="M189.1 98.6l1.4-1.4 .5 .4-1.5 1.5z"/>
<path d="M189.9 99.4l1.4-1.4 .4 .4-1.4 1.4z"/>
<path d="M190.6 100.2l1.5-1.4 .4 .4-1.4 1.4z"/>
<path d="M191.4 100.9l1.4-1.4 .5 .4-1.4 1.5z"/>
<path d="M192.2 101.7l1.4-1.4 .4 .4-1.4 1.4z"/>
<path d="M193 102.5l1.4-1.5 .4 .5-1.4 1.4z"/>
<path d="M188.2 94.9l.5 .4-1.5 1.5-.4-.5z"/>
<path d="M186.1 95.6l1.4-1.5 .4 .5-1.4 1.4z"/>
<path d="M185.3 94.8l1.4-1.4 .4 .4-1.4 1.4z"/>
<path d="M184.5 94l1.4-1.4 .5 .4-1.5 1.5z"/>
<path d="M183.7 93.3l1.5-1.5 .4 .5-1.4 1.4z"/>
<path d="M183 92.5l1.4-1.4 .4 .4-1.4 1.4z"/>
<path d="M182.2 91.7l1.4-1.4 .5 .4-1.5 1.5z"/>
<path d="M175 95.7l1.5 1.4-.4 .4-1.5-1.4z"/>
<path d="M175.8 94.9l1.4 1.4-.4 .5-1.4-1.5z"/>
<path d="M176.2 94.6l.4-.5 1.4 1.5-.4 .4z"/>
<path d="M176.9 93.8l.5-.4 1.4 1.4-.4 .4z"/>
<path d="M177.7 93l.4-.4 1.4 1.4-.4 .5z"/>
<path d="M178.5 92.3l.4-.5 1.4 1.5-.4 .4z"/>
<path d="M179.7 91.1l1.4 1.4-.4 .4-1.5-1.4z"/>
<path d="M180 90.7l.4-.4 1.4 1.4-.4 .5z"/>
<path d="M173.9 96.9l.4-.4 1.4 1.4-.4 .4z"/>
<path d="M173.1 97.6l.4-.4 1.4 1.4-.4 .5z"/>
<path d="M172.3 98.4l.5-.4 1.4 1.4-.4 .4z"/>
<path d="M171.6 99.2l.4-.4 1.4 1.4-.4 .4z"/>
<path d="M170.8 99.9l.4-.4 1.4 1.4-.4 .5z"/>
<path d="M170.5 100.3l1.4 1.4-.5 .4-1.4-1.4z"/>
<path d="M169.3 101.5l.4-.5 1.4 1.5-.4 .4z"/>
<path d="M187.6 109.1l.4-.5 1.4 1.4-.4 .5z"/>
<path d="M186.8 109.8l.4-.4 1.5 1.4-.5 .5z"/>
<path d="M186.1 110.6l.4-.4 1.4 1.4-.4 .4z"/>
<path d="M185.7 110.9l1.4 1.5-.4 .4-1.4-1.4z"/>
<path d="M184.5 112.1l.4-.4 1.5 1.4-.5 .4z"/>
<path d="M183.7 112.9l.5-.4 1.4 1.4-.4 .4z"/>
<path d="M183 113.7l.4-.5 1.4 1.5-.4 .4z"/>
<path d="M182.2 114.4l.4-.4 1.5 1.4-.5 .4z"/>
<path d="M188.4 108.3l.4-.4 1.4 1.4-.4 .4z"/>
<path d="M189.1 107.5l.4-.4 1.5 1.4-.5 .4z"/>
<path d="M189.9 106.8l.4-.5 1.4 1.5-.4 .4z"/>
<path d="M190.6 106l.5-.4 1.4 1.4-.4 .4z"/>
<path d="M191.4 105.2l.5-.4 1.4 1.4-.5 .4z"/>
<path d="M192.2 104.5l.4-.5 1.4 1.5-.4 .4z"/>
<path d="M193 103.7l.4-.4 1.4 1.4-.4 .4z"/>
<path d="M133.2 22.7l2.8-.2 .1 3-2.7 .2z"/>
<path d="M133 18.1l2.7-.2 .2 3-2.7 .2z"/>
<path d="M127 23.4l2.7-.4 .3 3-2.6 .3z"/>
<path d="M126.4 18.8l2.7-.4 .3 3-2.7 .3z"/>
<path d="M120.8 24.5l2.6-.5 .6 2.9-2.6 .6z"/>
<path d="M119.8 20l2.7-.5 .6 2.9-2.7 .5z"/>
<path d="M114.7 26.2l2.6-.8 .8 2.9-2.6 .7z"/>
<path d="M113.4 21.8l2.6-.8 .8 2.9-2.6 .7z"/>
<path d="M108.7 28.3l2.6-1 1 2.8-2.5 1z"/>
<path d="M107.1 24l2.5-1 1.1 2.8-2.5 1z"/>
<path d="M103 30.9l2.4-1.2 1.3 2.7-2.4 1.2z"/>
<path d="M101 26.7l2.5-1.2 1.2 2.8-2.4 1.1z"/>
<path d="M97.5 33.9l2.3-1.3 1.5 2.5-2.4 1.4z"/>
<path d="M95.1 29.9l2.4-1.3 1.5 2.5-2.4 1.4z"/>
<path d="M92.2 37.4l2.2-1.6 1.7 2.5-2.2 1.5z"/>
<path d="M89.6 33.5l2.2-1.5 1.7 2.5-2.3 1.5z"/>
<path d="M87.2 41.2l2.1-1.7 1.8 2.3-2.1 1.7z"/>
<path d="M84.3 37.6l2.1-1.7 1.9 2.3-2.2 1.7z"/>
<path d="M82.5 45.4l2-1.8 2 2.1-2 1.9z"/>
<path d="M79.3 42.1l2-1.9 2 2.2-1.9 1.8z"/>
<path d="M80 48l2.2 2-1.8 2-2.3-2z"/>
<path d="M76.5 44.9l2.3 2-1.9 2-2.2-2z"/>
<path d="M75.8 52.8l2.4 1.8-1.7 2.1-2.3-1.8z"/>
<path d="M72.2 50l2.3 1.8-1.6 2.1-2.4-1.8z"/>
<path d="M72.1 57.8l2.5 1.7-1.5 2.3-2.5-1.7z"/>
<path d="M68.2 55.3l2.5 1.7-1.4 2.2-2.5-1.6z"/>
<path d="M68.8 63.2l2.6 1.4-1.3 2.4-2.6-1.4z"/>
<path d="M64.7 61l2.6 1.4-1.3 2.4-2.6-1.4z"/>
<path d="M65.8 68.8l2.8 1.2-1.1 2.5-2.8-1.2z"/>
<path d="M61.7 66.9l2.7 1.2-1.1 2.5-2.8-1.2z"/>
<path d="M63.4 74.6l2.8 1-.9 2.6-2.8-1z"/>
<path d="M59.1 73.1l2.8 1-.9 2.5-2.9-1z"/>
<path d="M61.4 80.6l2.9 .8-.7 2.6-2.9-.8z"/>
<path d="M57 79.4l2.8 .8-.7 2.6-2.9-.8z"/>
<path d="M59.9 86.7l2.9 .6-.5 2.6-2.9-.5z"/>
<path d="M55.4 85.9l2.9 .5-.5 2.7-3-.6z"/>
<path d="M58.8 92.9l3 .4-.3 2.7-3-.3z"/>
<path d="M54.3 92.5l2.9 .3-.3 2.7-2.9-.4z"/>
<path d="M58.3 99.2l3 .1-.1 2.7-3-.1z"/>
<path d="M53.7 99.1l3 .1-.1 2.7-3-.1z"/>
<path d="M58.3 105.5l2.9-.1 .2 2.7-3 .1z"/>
<path d="M53.6 105.8l3-.2 .1 2.7-2.9 .2z"/>
<path d="M58.7 111.8l3-.3 .3 2.7-3 .3z"/>
<path d="M54.1 112.4l3-.4 .3 2.7-3 .4z"/>
<path d="M59.6 118.1l2.9-.6 .6 2.6-2.9 .6z"/>
<path d="M55.1 119l2.9-.6 .6 2.7-3 .6z"/>
<path d="M61 124.2l2.9-.8 .8 2.6-2.9 .8z"/>
<path d="M56.6 125.5l2.9-.8 .7 2.6-2.8 .8z"/>
<path d="M62.9 130.2l2.8-1 1 2.5-2.8 1.1z"/>
<path d="M58.6 131.9l2.8-1.1 1 2.5-2.8 1.1z"/>
<path d="M65.3 136.1l2.7-1.3 1.1 2.5-2.7 1.3z"/>
<path d="M61.1 138l2.7-1.2 1.2 2.4-2.7 1.3z"/>
<path d="M68.1 141.7l2.6-1.4 1.3 2.3-2.6 1.5z"/>
<path d="M64.1 144l2.6-1.5 1.3 2.4-2.6 1.5z"/>
<path d="M71.3 147.2l2.5-1.7 1.5 2.2-2.4 1.7z"/>
<path d="M67.5 149.7l2.5-1.6 1.5 2.2-2.5 1.7z"/>
<path d="M75 152.3l2.3-1.9 1.7 2.1-2.3 1.9z"/>
<path d="M71.4 155.2l2.3-1.9 1.7 2.1-2.3 1.9z"/>
<path d="M79 157.1l2.2-2 1.9 2-2.2 2z"/>
<path d="M75.6 160.3l2.2-2.1 1.9 2-2.2 2.1z"/>
<path d="M85.4 159.4l2.1 1.9-2.1 2.2-2-1.9z"/>
<path d="M82.3 162.9l2 1.8-2 2.2-2-1.8z"/>
<path d="M90 163.4l2.2 1.7-1.9 2.4-2.1-1.7z"/>
<path d="M87.2 167.1l2.1 1.7-1.8 2.3-2.2-1.7z"/>
<path d="M94.9 167.1l2.3 1.5-1.7 2.5-2.2-1.5z"/>
<path d="M92.4 170.9l2.2 1.5-1.6 2.5-2.3-1.5z"/>
<path d="M100 170.3l2.4 1.3-1.4 2.6-2.4-1.3z"/>
<path d="M97.8 174.3l2.4 1.4-1.5 2.6-2.3-1.3z"/>
<path d="M105.4 173.1l2.5 1.2-1.3 2.7-2.4-1.1z"/>
<path d="M103.5 177.3l2.5 1.2-1.3 2.7-2.4-1.1z"/>
<path d="M111 175.5l2.5 1-1 2.8-2.5-.9z"/>
<path d="M109.4 179.9l2.6 .9-1.1 2.8-2.5-.9z"/>
<path d="M164.1 176.5l2.5-1 1 2.9-2.5 .9z"/>
<path d="M165.7 180.8l2.5-.9 1 2.8-2.5 .9z"/>
<path d="M169.8 174.2l2.5-1.1 1.2 2.7-2.5 1.2z"/>
<path d="M171.7 178.5l2.5-1.2 1.2 2.7-2.5 1.2z"/>
<path d="M175.3 171.6l2.4-1.3 1.4 2.6-2.4 1.3z"/>
<path d="M177.5 175.6l2.4-1.3 1.4 2.6-2.3 1.3z"/>
<path d="M180.6 168.5l2.2-1.5 1.7 2.5-2.3 1.5z"/>
<path d="M183.1 172.4l2.3-1.5 1.6 2.4-2.2 1.5z"/>
<path d="M185.6 165l2.1-1.7 1.8 2.4-2.1 1.7z"/>
<path d="M188.4 168.7l2.2-1.7 1.8 2.3-2.1 1.7z"/>
<path d="M190.3 161.1l2-1.8 2 2.2-2 1.8z"/>
<path d="M193.4 164.5l2-1.8 2 2.2-1.9 1.9z"/>
<path d="M196.6 154.9l2.2 2.1-1.9 1.9-2.2-2z"/>
<path d="M199.9 158.1l2.2 2-1.8 2-2.2-2z"/>
<path d="M200.5 150.2l2.3 1.9-1.7 2.1-2.3-1.9z"/>
<path d="M204.1 153.1l2.3 1.8-1.7 2.2-2.3-1.9z"/>
<path d="M204 145.2l2.5 1.7-1.5 2.2-2.5-1.6z"/>
<path d="M207.8 147.8l2.5 1.7-1.5 2.2-2.5-1.6z"/>
<path d="M207.1 140l2.6 1.4-1.3 2.4-2.6-1.5z"/>
<path d="M211.1 142.2l2.6 1.5-1.3 2.3-2.6-1.4z"/>
<path d="M209.8 134.5l2.7 1.2-1.1 2.5-2.7-1.3z"/>
<path d="M214 136.4l2.7 1.3-1.2 2.4-2.7-1.2z"/>
<path d="M212 128.8l2.8 1-.9 2.6-2.8-1.1z"/>
<path d="M216.4 130.4l2.8 1-1 2.6-2.8-1.1z"/>
<path d="M213.8 122.9l2.9 .9-.7 2.6-2.9-.8z"/>
<path d="M218.3 124.2l2.8 .8-.7 2.6-2.8-.8z"/>
<path d="M215.2 117l2.9 .6-.5 2.6-2.9-.6z"/>
<path d="M219.7 117.9l2.9 .6-.5 2.6-2.9-.6z"/>
<path d="M216 110.9l3 .4-.3 2.7-3-.4z"/>
<path d="M220.6 111.5l3 .3-.4 2.7-2.9-.3z"/>
<path d="M216.4 104.8l3 .1-.1 2.8-3-.2z"/>
<path d="M221 105l3 .1-.1 2.7-3-.1z"/>
<path d="M216.3 98.7l3-.1 .1 2.7-3 .1z"/>
<path d="M220.9 98.5l3-.1 .1 2.7-3 .1z"/>
<path d="M215.7 92.6l3-.3 .3 2.7-3 .3z"/>
<path d="M220.3 92.1l3-.4 .3 2.7-3 .4z"/>
<path d="M214.7 86.6l2.9-.6 .5 2.7-2.9 .6z"/>
<path d="M219.2 85.7l2.9-.6 .5 2.7-2.9 .6z"/>
<path d="M213.1 80.7l2.9-.8 .7 2.6-2.8 .8z"/>
<path d="M217.6 79.4l2.8-.8 .8 2.6-2.9 .8z"/>
<path d="M211.1 74.9l2.8-1 1 2.5-2.8 1z"/>
<path d="M215.5 73.3l2.7-1 1 2.5-2.8 1z"/>
<path d="M208.7 69.3l2.7-1.2 1.1 2.4-2.7 1.3z"/>
<path d="M212.9 67.4l2.7-1.3 1.1 2.5-2.7 1.2z"/>
<path d="M205.8 63.9l2.6-1.5 1.3 2.4-2.6 1.5z"/>
<path d="M209.8 61.6l2.6-1.4 1.4 2.3-2.6 1.5z"/>
<path d="M202.5 58.8l2.5-1.7 1.5 2.3-2.5 1.6z"/>
<path d="M206.4 56.2l2.4-1.7 1.6 2.3-2.5 1.6z"/>
<path d="M198.8 53.9l2.4-1.9 1.7 2.1-2.4 1.9z"/>
<path d="M202.5 51l2.3-1.8 1.7 2.1-2.4 1.8z"/>
<path d="M194.8 49.3l2.2-2 1.8 2-2.2 2z"/>
<path d="M198.2 46.2l2.1-2.1 1.9 2-2.2 2.1z"/>
<path d="M192.4 42.9l2 1.8-2 2.2-2-1.8z"/>
<path d="M195.5 39.5l2 1.8-2 2.2-2-1.8z"/>
<path d="M187.5 38.8l2.1 1.7-1.8 2.4-2.1-1.7z"/>
<path d="M190.3 35.2l2.2 1.7-1.9 2.3-2.1-1.7z"/>
<path d="M182.3 35.2l2.2 1.5-1.6 2.5-2.3-1.5z"/>
<path d="M184.8 31.4l2.3 1.5-1.7 2.4-2.2-1.5z"/>
<path d="M176.8 32l2.4 1.3-1.5 2.6-2.4-1.3z"/>
<path d="M179 28l2.4 1.3-1.4 2.6-2.4-1.3z"/>
<path d="M171.1 29.2l2.4 1.2-1.2 2.7-2.5-1.2z"/>
<path d="M173 25l2.5 1.2-1.3 2.7-2.4-1.2z"/>
<path d="M165.2 26.9l2.5 1-1 2.7-2.6-.9z"/>
<path d="M166.8 22.6l2.5 .9-1 2.8-2.6-.9z"/>
<path d="M159.1 25.1l2.6 .7-.8 2.9-2.6-.7z"/>
<path d="M160.3 20.6l2.7 .8-.8 2.8-2.7-.7z"/>
<path d="M152.9 23.7l2.7 .5-.6 3-2.7-.6z"/>
<path d="M153.8 19.2l2.6 .5-.5 2.9-2.7-.5z"/>
<path d="M146.6 22.9l2.7 .3-.3 2.9-2.7-.3z"/>
<path d="M147.1 18.3l2.7 .3-.3 2.9-2.7-.2z"/>
<path d="M140.3 22.5l2.7 .1-.1 3-2.7-.1z"/>
<path d="M140.4 17.9l2.8 .1-.2 3-2.7-.1z"/>
<path d="M135 116h7.4v7.3h-7.4z"/>
<path d="M131.8 152.6h5.4v13.6h-5.4z"/>
<path d="M140.4 152.6h5.5v13.6h-5.5z"/>
<path d="M140 135.9h12.5v2.7h-12.5z"/>
<path d="M140 141.3h12.5v2.7h-12.5z"/>
<path d="M127.5 128.5h9.3v4.4h-9.3z"/>
<path d="M127.5 147h9.3v4.3h-9.3z"/>
<path d="M136.1 105.2h3.5v4h-3.5z"/>
<path d="M141.3 105.2h3.5v4h-3.5z"/>
<path d="M126.4 105.2h3.6v4.1h-3.6z"/>
<path d="M131.6 105.2h3.5v4.1h-3.5z"/>
<path d="M124.8 110.4h4.1v3.5h-4.1z"/>
<path d="M124.8 115.5h4.1v3.5h-4.1z"/>
<path d="M124.8 119.5h4.1v3.5h-4.1z"/>
<path d="M124.8 124.6h4.1v3.5h-4.1z"/>
<path d="M140.3 94.3h5.3v6.7h-5.3z"/>
<path d="M132 94.3h5.3v6.7h-5.3z"/>
<path d="M133.6 174.3h3.3v1.4h-3.3z"/>
<path d="M133.6 171.7h3.3v1.5h-3.3z"/>
<path d="M133.6 169.1h3.3v1.5h-3.3z"/>
<path d="M140.7 169.1h3.3v1.5h-3.3z"/>
<path d="M140.7 174.3h3.3v1.4h-3.3z"/>
<path d="M139.6 182.3h3.6v4.1h-3.6z"/>
<path d="M134.5 182.3h3.5v4.1h-3.5z"/>
<path d="M139.7 177.8h3.6v4h-3.6z"/>
<path d="M134.6 177.8h3.5v4h-3.5z"/>
<path d="M138.3 187.5h1.1v3.9h-1.1z"/>
<path d="M140 187.5h1.1v3.9h-1.1z"/>
<path d="M141.8 187.5h1.1v3.9h-1.1z"/>
<path d="M136.5 187.5h1.1v3.9h-1.1z"/>
<path d="M134.7 187.5h1.1v3.9h-1.1z"/>
<path d="M146.4 194.8h4.8v4.1h-4.8z"/>
<path d="M135.4 194.8h6.8v4.1h-6.8z"/>
<path d="M126.4 194.8h4.9v4.1h-4.9z"/>
<path d="M130.6 67.4h4.1v5.5h-4.1z"/>
<path d="M136.8 67.4h4.1v5.5h-4.1z"/>
<path d="M143 67.4h4.1v5.5h-4.1z"/>
<path d="M133.6 84.5h10.4v5.4h-10.4z"/>
<path d="M123.5 47.9l1-.9 2.4 2.4-1 1z"/>
<path d="M125 46.4l1-1 2.4 2.5-.9 .9z"/>
<path d="M127.6 43.9l2.4 2.4-1 1-2.4-2.4z"/>
<path d="M128.1 43.3l1-.9 2.4 2.4-1 1z"/>
<path d="M130.6 40.8l2.5 2.5-1 .9-2.5-2.4z"/>
<path d="M131.2 40.3l.9-1 2.5 2.4-1 1z"/>
<path d="M132.7 38.7l1-1 2.4 2.5-1 1z"/>
<path d="M134.2 37.2l1-1 2.4 2.5-.9 .9z"/>
<path d="M142.4 36.2l1 1-2.5 2.4-.9-.9z"/>
<path d="M143.9 37.7l1 1-2.4 2.5-1-1z"/>
<path d="M143 41.7l2.5-2.4 1 1-2.5 2.4z"/>
<path d="M147 40.8l1 1-2.5 2.4-.9-.9z"/>
<path d="M146.1 44.8l2.4-2.4 1 .9-2.4 2.5z"/>
<path d="M150.1 43.9l.9 1-2.4 2.4-1-1z"/>
<path d="M151.6 45.4l1 1-2.4 2.4-1-.9z"/>
<path d="M150.7 49.4l2.4-2.4 1 .9-2.4 2.5z"/>
<path d="M150.7 53.7l1-1 2.4 2.4-1 1z"/>
<path d="M149.2 55.2l1-1 2.4 2.5-1 .9z"/>
<path d="M147.6 56.7l1-.9 2.4 2.4-.9 1z"/>
<path d="M146.1 58.3l1-1 2.4 2.4-1 1z"/>
<path d="M144.6 59.8l.9-1 2.5 2.5-1 .9z"/>
<path d="M143 61.3l1-.9 2.5 2.4-1 1z"/>
<path d="M141.5 62.9l1-1 2.4 2.4-1 1z"/>
<path d="M140 64.4l.9-1 2.5 2.5-1 .9z"/>
<path d="M134.2 65.9l2.5-2.5 .9 1-2.4 2.4z"/>
<path d="M132.7 64.3l2.4-2.4 1 1-2.4 2.4z"/>
<path d="M133.6 60.4l1 .9-2.5 2.5-.9-1z"/>
<path d="M129.6 61.3l2.5-2.5 1 1-2.5 2.4z"/>
<path d="M128.1 59.7l2.4-2.4 1 1-2.4 2.4z"/>
<path d="M129 55.8l1 .9-2.4 2.5-1-1z"/>
<path d="M125 56.7l2.5-2.5 .9 1-2.4 2.4z"/>
<path d="M123.5 55.1l2.4-2.4 1 1-2.4 2.4z"/>
<path d="M140.7 29.8h2.7v4.8h-2.7z"/>
<path d="M133.9 29.8h2.7v4.8h-2.7z"/>
<path d="M126.5 33.7l2.5-2.5 2.9 2.9-2.5 2.5z"/>
<path d="M122.9 37.3l2.5-2.5 2.8 2.9-2.4 2.5z"/>
<path d="M145.8 34.4l2.8-2.9 2.5 2.5-2.8 2.9z"/>
<path d="M149.4 38l2.9-2.9 2.5 2.5-2.9 2.9z"/>
<path d="M96.4 122.6h3.5v4.4h-3.5z"/>
<path d="M101.8 122.6h3.5v4.4h-3.5z"/>
<path d="M96.4 117.2h3.5v4.3h-3.5z"/>
<path d="M101.8 117.2h3.5v4.3h-3.5z"/>
<path d="M96.3 134.8h3.5v4.4h-3.5z"/>
<path d="M90.9 134.8h3.5v4.4h-3.5z"/>
<path d="M96.3 128.3h3.5v4.3h-3.5z"/>
<path d="M90.9 128.3h3.5v4.3h-3.5z"/>
<path d="M113.5 122.5h3.6v4.1h-3.6z"/>
<path d="M108.4 122.5h3.5v4.1h-3.5z"/>
<path d="M108.4 115.1h3.5v4h-3.5z"/>
<path d="M113.5 115.1h3.6v4h-3.6z"/>
<path d="M177.8 84.6h3.5v4.4h-3.5z"/>
<path d="M172.3 84.6h3.6v4.4h-3.6z"/>
<path d="M177.8 79.2h3.5v4.3h-3.5z"/>
<path d="M172.3 79.2h3.6v4.3h-3.6z"/>
<path d="M178.1 73.5h3.5v4.4h-3.5z"/>
<path d="M183.5 73.5h3.5v4.4h-3.5z"/>
<path d="M172.3 73.4h3.5v4.4h-3.5z"/>
<path d="M166.9 73.4h3.5v4.4h-3.5z"/>
<path d="M166.8 78.2h3.5v4.1h-3.5z"/>
<path d="M161.7 78.2h3.5v4.1h-3.5z"/>
<path d="M166.4 88h3.5v4h-3.5z"/>
<path d="M161.3 88h3.5v4h-3.5z"/>
<path d="M107.5 66h3.5v1.4h-3.5z"/>
<path d="M107.5 69.4h3.5v1.4h-3.5z"/>
<path d="M107.5 72.9h3.5v1.4h-3.5z"/>
<path d="M107.5 62.5h3.5v1.4h-3.5z"/>
<path d="M107.5 59.1h3.5v1.4h-3.5z"/>
<path d="M120.6 59.1h3.5v1.4h-3.5z"/>
<path d="M120.6 62.5h3.5v1.4h-3.5z"/>
<path d="M120.6 66h3.5v1.4h-3.5z"/>
<path d="M120.6 69.4h3.5v1.4h-3.5z"/>
<path d="M120.6 72.9h3.5v1.4h-3.5z"/>
<path d="M118.8 112.6h4v3.5h-4z"/>
<path d="M118.8 117.7h4v3.5h-4z"/>
<path d="M47.5 101.2h4.6v2.5h-4.6z"/>
<path d="M47.5 97.1h4.6v2.5h-4.6z"/>
<path d="M47.5 109.3h4.6v2.5h-4.6z"/>
<path d="M41.6 114.8h6.9v3.4h-6.9z"/>
<path d="M41.6 90.7h6.9v3.4h-6.9z"/>
<path d="M232.7 104.7l2.7 .2-.2 2.4-2.7-.2z"/>
<path d="M228.4 104.3l2.7 .2-.2 2.5-2.7-.3z"/>
<path d="M226.8 108.6l1.5 .2-.4 4.6-1.5-.2z"/>
<path d="M227.4 115.4l2.7 .2-.2 2.4-2.7-.2z"/>
<path d="M231.7 115.8l2.7 .2-.2 2.4-2.7-.2z"/>
<path d="M231.5 88l2.7-.3 .2 2.5-2.7 .2z"/>
<path d="M227.2 88.3l2.7-.2 .2 2.5-2.7 .2z"/>
<path d="M226.4 92.9l1.5-.1 .4 4.6-1.5 .1z"/>
<path d="M228.2 99.4l2.7-.2 .2 2.4-2.7 .3z"/>
<path d="M232.5 99.1l2.7-.3 .2 2.4-2.7 .3z"/>
<path d="M156.5 39.3l2.5 2.5-2.9 2.9-2.5-2.5z"/>
<path d="M157.2 45.8l2.9-2.9 2.5 2.5-2.9 2.9z"/>
<path d="M117.7 42.8l2.5-2.5 2.8 2.9-2.5 2.5z"/>
<path d="M114 46.4l2.5-2.5 2.9 2.9-2.5 2.5z"/>
</g>
<g fill="#000080" stroke="#000080" stroke-width=".2">
<path d="M143 116.7l.4-.2h1.9a.47 .47 0 0 1 .5 .5 .47 .47 0 0 1-.5 .4h-1.9a.47 .47 0 0 1-.4-.7z" fill-rule="evenodd"/>
<path d="M143 118.5l.4-.2h1.9a.47 .47 0 0 1 .5 .4 .47 .47 0 0 1-.5 .5h-1.9a.47 .47 0 0 1-.4-.7z" fill-rule="evenodd"/>
<path d="M143 120.2l.4-.2h1.9a.47 .47 0 0 1 .5 .5 .47 .47 0 0 1-.5 .4h-1.9a.47 .47 0 0 1-.4-.7z" fill-rule="evenodd"/>
<path d="M143 122l.4-.2h1.9a.47 .47 0 0 1 .5 .5 .47 .47 0 0 1-.5 .4h-1.9a.47 .47 0 0 1-.4-.7z" fill-rule="evenodd"/>
<path d="M141.1 124a.47 .47 0 0 1 .7 .4v1.9a.47 .47 0 0 1-.4 .4 .47 .47 0 0 1-.5-.4v-1.9z" fill-rule="evenodd"/>
<path d="M139.4 124a.47 .47 0 0 1 .7 .4v1.9a.47 .47 0 0 1-.5 .4 .47 .47 0 0 1-.5-.4v-1.9z" fill-rule="evenodd"/>
<path d="M137.6 124a.47 .47 0 0 1 .7 .4v1.9a.47 .47 0 0 1-.5 .4 .47 .47 0 0 1-.4-.4v-1.9z" fill-rule="evenodd"/>
<path d="M135.8 124a.47 .47 0 0 1 .7 .4v1.9a.47 .47 0 0 1-.4 .4 .47 .47 0 0 1-.5-.4v-1.9z" fill-rule="evenodd"/>
<path d="M131.7 122l.4-.2h1.9a.47 .47 0 0 1 .4 .5 .47 .47 0 0 1-.4 .4h-1.9a.47 .47 0 0 1-.4-.7z" fill-rule="evenodd"/>
<path d="M131.7 120.2l.4-.2h1.9a.47 .47 0 0 1 .4 .5 .47 .47 0 0 1-.4 .4h-1.9a.47 .47 0 0 1-.4-.7z" fill-rule="evenodd"/>
<path d="M131.7 118.5l.4-.2h1.9a.47 .47 0 0 1 .4 .4 .47 .47 0 0 1-.4 .5h-1.9a.47 .47 0 0 1-.4-.7z" fill-rule="evenodd"/>
<path d="M131.7 116.7l.4-.2h1.9a.47 .47 0 0 1 .4 .5 .47 .47 0 0 1-.4 .4h-1.9a.47 .47 0 0 1-.4-.7z" fill-rule="evenodd"/>
<path d="M135.8 112.5a.47 .47 0 0 1 .7 .4v1.9a.47 .47 0 0 1-.4 .5 .47 .47 0 0 1-.5-.5v-1.9z" fill-rule="evenodd"/>
<path d="M137.6 112.5a.47 .47 0 0 1 .7 .4v1.9a.47 .47 0 0 1-.5 .5 .47 .47 0 0 1-.4-.5v-1.9z" fill-rule="evenodd"/>
<path d="M139.4 112.5a.47 .47 0 0 1 .7 .4v1.9a.47 .47 0 0 1-.5 .5 .47 .47 0 0 1-.5-.5v-1.9z" fill-rule="evenodd"/>
<path d="M141.1 112.5a.47 .47 0 0 1 .7 .4v1.9a.47 .47 0 0 1-.4 .5 .47 .47 0 0 1-.5-.5v-1.9z" fill-rule="evenodd"/>
</g>
<g fill="none" stroke="#000080" stroke-width=".3">
<path d="M120.8 17.7l.7 3.5M130.5 19.8l-2.6 .3M134.1 13.1l.3 6.4M142.7 16.2l-1 3.2M145.6 19.7l2.7 .2M86.3 37.9l-1.7 1.5M91.5 34l-1.6 1.8M94.1 37.8l6 6a6.9 6.9 0 0 1 2.1 4.9M99.2 29.3l-2.1 1.2M99.4 34.5a8.7 8.7 0 0 1 3.2 4.9l.2 1.4v27.9l-.1 .5-.8 1.1-.3 .8v4a3.9 3.9 0 0 0 3.6 3.8h4.8a2.26 2.26 0 0 1 2 2.5v16.9a3.1 3.1 0 0 1-3.3 2.7 2.03 2.03 0 0 0-1.3 1M102.9 27.5l-2.1 1M104.8 31.6a4.4 4.4 0 0 1 1.4 3.2v18.5l-.2 1-.4 .9a7 7 0 0 0-2.2 4.7v9.2l-.1 .4-.5 .6a3.1 3.1 0 0 0-.6 1.8v2.7a3.5 3.5 0 0 0 3.1 3.7l6.6 .1a2.22 2.22 0 0 1 1.3 1l.7 .3a3.8 3.8 0 0 0 2.7-.3l1.2-1 .6-.2h5.2a2.34 2.34 0 0 1 1.4 1.1 6.9 6.9 0 0 1 2 4.8v7a6.9 6.9 0 0 1-2.1 4.8l-9.4 9.5a6 6 0 0 1-5.3 1.4l-2.8-2.6"/>
<path d="M110.5 29.2l.5 .6 .1 .8v5.2l-.3 1.6a4.4 4.4 0 0 1-1.2 2 7 7 0 0 0-2.9 4.5v10.2l-.1 .9-.4 .8a5.9 5.9 0 0 0-2.2 4.4v8.9l-.1 .6-.7 1-.3 .7v3.4a2.99 2.99 0 0 0 2.5 2.9h18.3a2.3 2.3 0 0 1 1.8 1.2 7 7 0 0 1 2 4.9v7.6a7 7 0 0 1-2 4.9l-9.6 9.5-1.5 1.1a8.6 8.6 0 0 1-4.8 .6l-1-.6-1.9-2M111 24.2l-2.1 .7M115.1 22.8l-2.1 .5M116.4 27.2l.3 .5 .1 .6v4l-.3 .8-.5 .7-6.7 6.8a6.7 6.7 0 0 0-2 4.8l-.1 9.8a2.88 2.88 0 0 1-1.3 1.7l-.3 .4a4 4 0 0 0-.9 2.6v9.3a3.3 3.3 0 0 1-1 2l-.2 .7v2.6a2.54 2.54 0 0 0 2.4 2.6h18.3a7.3 7.3 0 0 1 3.9 6.3v8.3a6.8 6.8 0 0 1-2 4.9l-10.1 10.1a4.6 4.6 0 0 1-3.3 1.3h-3.8l-.8-.2-.7-.5M122.4 25.7a2.86 2.86 0 0 1 .9 2.2v2.8a2.32 2.32 0 0 1-2.4 2.2l-2.5 .1-1.1 .4-7.5 7.5a7 7 0 0 0-2 4.9v9.6l-.2 .7a5.1 5.1 0 0 0-2.3 4v9.2l-.3 1.3-.9 1.4v2.3a2.47 2.47 0 0 0 2.2 2.2l18.3 .1a3.6 3.6 0 0 1 2.1 1.6 6.7 6.7 0 0 1 2 4.9v9a6.7 6.7 0 0 1-2 4.9l-10.5 10.4-.8 .6a3.8 3.8 0 0 1-2.1 .6l-5.8-.1-.9-.5-1.5-1.5M128.5 24.7l-.4 .5-.2 .7-.1 3.1a5 5 0 0 1-4 4.2 11.4 11.4 0 0 1-4.5 .3l-.9 .1-.9 .4-7.1 7.1a7 7 0 0 0-2 4.9l-.1 9.9a4.8 4.8 0 0 1-1.7 2.2l-.5 .7-.2 1.3v13.6a2.32 2.32 0 0 0 2.4 2.3h16.2l1 .2a8 8 0 0 1 3.7 6.5v9.7a6.7 6.7 0 0 1-2 4.9l-11 11a4 4 0 0 1-2.5 .9l-6.9-.1-.9-.4-1.5-1.4M134.7 24.1l-.2 .4-7.6 7.6a6.6 6.6 0 0 1-4.7 1.9h-2.9a2.09 2.09 0 0 0-1.5 .6l-6.7 6.8a6.9 6.9 0 0 0-2.1 4.8v9.5a5.3 5.3 0 0 1-2.1 3l-.3 .7-.2 .8v13.3a1.99 1.99 0 0 0 2.1 1.9h16l.8 .2a9.8 9.8 0 0 1 4 4.2l.5 2v10.9a6.7 6.7 0 0 1-2 4.9l-10.8 10.8-1 .7-1 .4-1.2 .2h-7.8a3.6 3.6 0 0 1-2.4-1.7M141.6 24l2.2 2.3a1.43 1.43 0 0 0 1.3 .3h.6a5.5 5.5 0 0 1 3.4 1.6l3.1 3.2a7 7 0 0 0 4.9 2h4.6a6.8 6.8 0 0 1 4.9 2l5 5 .6 1.4 .2 1a4.7 4.7 0 0 0 1.4 3.4l4.7 4.8a7.6 7.6 0 0 1 2 6.5 7 7 0 0 0 2 4.9l6.5 6.5 .4 .8 .1 .8a2.79 2.79 0 0 0 .9 2.2 6.2 6.2 0 0 1 2.3 2.7 3.5 3.5 0 0 1-1.2 3.8 7.2 7.2 0 0 0 0 7.2l1.1 1.4 .5 1.1 .2 5.6 .7 1.5v3M147.8 24.5l.7 .1 .6 .3 4.3 4.3a6.1 6.1 0 0 0 4.7 1.8 4 4 0 0 1 2.1 1.2 5 5 0 0 0 3.4 .7l1.1 .3 1 .5 6 5.9 .6 1a7.7 7.7 0 0 1 .8 3.3 4.4 4.4 0 0 0 1.1 2l5.7 5.6a4.6 4.6 0 0 1 1.3 3.2 11 11 0 0 0 .5 5.1l1.1 1.7 6.6 6.7a4 4 0 0 1 1 3.2l.2 .6 2.4 2.3 .5 .9 .1 3.9a2.47 2.47 0 0 1-.9 1.8 5.3 5.3 0 0 0 1.7 6.1l.4 .8 .2 .8 .1 2.9-.2 .7-.7 1-.3 .9M153.9 25.4l.5 .3 4.4 4.3a7.4 7.4 0 0 0 5.6 2.1 2.89 2.89 0 0 1 1.6 .8l6.7 6.8a4.5 4.5 0 0 1 .9 3 4.4 4.4 0 0 0 1.3 2.6l5 5a6.8 6.8 0 0 1 2 4.9 8 8 0 0 0 1.4 6l8.8 8.9a6.8 6.8 0 0 1 2.1 4.9v4.6l-.4 1a2.65 2.65 0 0 0-.8 2.9l.4 1.4 .6 .8a3.4 3.4 0 0 1 1.6 2.8l.1 9.8 .1 .7 .4 .5M154.8 20.9l2 1.2M160 26.9l4.3 4.2 1.4 .4 .6 .4 17 17 .4 .8 .3 .9v7.7a6.9 6.9 0 0 0 2 4.8l6.8 6.7a6.9 6.9 0 0 1 2 4.9v10a3.6 3.6 0 0 0 1.1 2.2l.3 1.3v9.3a4 4 0 0 0 1.6 2.9 2.14 2.14 0 0 1-.1 2.4l-2.8 2.7-.5 .3a1.7 1.7 0 0 1-1.3-.9"/>
<path d="M161.2 22.4l3 .9M165.9 28.8a4.5 4.5 0 0 0 1.3 3.1l16.5 16.5a2.73 2.73 0 0 1 .9 2v7.4a7 7 0 0 0 2 4.9l6.7 6.7a7 7 0 0 1 2 4.8v9.5a4.4 4.4 0 0 0 1.4 3l.1 .5v9.4a5.2 5.2 0 0 0 1.8 3.8 1.77 1.77 0 0 1-.1 2.4l-4.3 4.2h-.6l-1.3-1.3M167.5 24.4l4 1.9M171.7 31.2a7.5 7.5 0 0 0 2 6.2l13.3 13.2a6.8 6.8 0 0 1 2 4.9v5.8a6.9 6.9 0 0 0 2 4.9l2.9 2.8a6.9 6.9 0 0 1 2 4.9v5.8a7.7 7.7 0 0 0 3 5.9 3.1 3.1 0 0 1 1 2.2 7.1 7.1 0 0 1-.3 3.4l-.8 1.3M173.6 27l2.1 1.1M177.3 34l.3 1.5 .8 1.3 9.2 9.1a6.8 6.8 0 0 1 2 4.9v10.1a6.9 6.9 0 0 0 2 4.8l5 5.1a4.7 4.7 0 0 1 1.4 3.3v6.7l.2 .9 .3 .8a5.9 5.9 0 0 1 2 4.3v3.9l-.1 .8a4.6 4.6 0 0 1-1.6 2 4.4 4.4 0 0 0 .9 6 2.27 2.27 0 0 1 1.2 2.5l-6.2 6.3a3 3 0 0 1-3.9-1M179.5 29.9l2.4 1.5M182.6 37.2a7 7 0 0 0 2 4.9l4.2 4.3 .8 .9 .5 1 .3 1.7v10.3a2.92 2.92 0 0 0 .9 1.7l5.5 5.6a7 7 0 0 1 2 4.8v8.5l.3 1.1a6.8 6.8 0 0 1 2 4.4v4.9a3.2 3.2 0 0 1-1.7 2.6 3.3 3.3 0 0 0 .1 4.4 5.4 5.4 0 0 1 2 2.4l.1 .9a5.7 5.7 0 0 1-.5 3.5l-4.4 4.6-.6 .4-1 .3-3.8-.1a3.3 3.3 0 0 1-1.9-1.5h-.1M182.6 37.2h.1M183.1 32.1l2 1.3M188.6 36l1.9 1.2M71.8 56.2l-1.4 2.2-1.7-1.1"/>
<path d="M72.5 51.9l-2.1 3.3M72.6 59.8a2.72 2.72 0 0 0 2.5 1.9h8.8l.8 .1 .9 .6 4.9 4.9a5.5 5.5 0 0 1 .8 4.3 6.8 6.8 0 0 0 2 4.8l8.4 8.4a6.9 6.9 0 0 1 2 4.9v5.1l-.3 .4-1.3 1.4M76.2 54.8a6.5 6.5 0 0 1 4.6 1.9l13.6 13.6 .4 .8 .3 .9v4.2l.6 1.4 .6 .9 5 5 .7 .5 .9 .3a4.1 4.1 0 0 1 3.8 1.6l.1 5.2-.4 1.9-.9 1.6-2.7 2.8M78.8 44.6l-2 2.3M80.2 50l.7 .1 .9 .6 12 12a7 7 0 0 1 2 4.8v7.7a4.6 4.6 0 0 0 1.4 3.3l3.2 3.2 .8 .4 1.3 .3a7.9 7.9 0 0 1 4 .3 5.1 5.1 0 0 1 3.2 4.2v3.9a6.8 6.8 0 0 1-2.1 4.8l-3.2 3.3M82.9 40.8l-1.6 1.4M84.5 45.6l9.9 9.9a6.8 6.8 0 0 1 2 4.9v14.9l.3 1.5 .8 1.2 2.9 2.9 .7 .5 1.2 .4 3.4 .1a3.1 3.1 0 0 1 2.2 .8l1.8 2 .4 .7 .1 .7v5.1a7.3 7.3 0 0 1-2.8 5.6l-.3 .9-2 2M89.2 41.5l7.4 7.6a6.8 6.8 0 0 1 2 4.9v21a6.9 6.9 0 0 0 4.2 6l.9 .2a6.7 6.7 0 0 1 3.4 .2l1.2 .8 1.8 1.9 .6 .9 .1 6.3a7.5 7.5 0 0 1-2.9 5.8l-.4 1.7-1.6 1.6M102.2 48.7v4.1l-.5 1.6a7.6 7.6 0 0 0-2.4 5.4v14.9a6.2 6.2 0 0 0 4.1 5.9h3.3l.8 .3 1.1 .7 2 2 .5 .7 .3 1.4v11.8a2.44 2.44 0 0 1-2.6 2.4 3.3 3.3 0 0 0-2.1 1.3M102.2 48.7h.1M122 57.9v1.5l.4 .4M125.2 48.7v.1"/>
<path d="M162.1 43.8h-.3l-1.9 1.8M187.6 40.9a6.9 6.9 0 0 0 2.1 4.9l2.9 3 .5 1 .1 8.4a6.9 6.9 0 0 0 2 4.9l4.8 4.7a7 7 0 0 1 2 4.9v18.4a5.3 5.3 0 0 1-2.3 3.5 2.44 2.44 0 0 0 .2 3.2l1.6 1.6a2.06 2.06 0 0 1 .6 1.5 7.6 7.6 0 0 1-.3 4.1l-.9 1.4-3.8 3.8-.6 .5-1.2 .2M192.4 44.9l1.1 1.5 .5 1.8v9.8a6.9 6.9 0 0 0 2 4.9l4.7 4.7a6.8 6.8 0 0 1 2 4.8v18.2a5.6 5.6 0 0 1-2.4 4.4M195.5 41.5l1.3 1.8M196.8 49.3v10.5a6.9 6.9 0 0 0 2 4.9l3.3 3.3a6.8 6.8 0 0 1 2.1 4.9v14.9l-.2 .5-.6 .9-.1 .5v15l-.3 1.1a4.4 4.4 0 0 0-1.4 3.8 5 5 0 0 1-4.4 4h-6.3l-1.3-.2a7.2 7.2 0 0 1-2.6-2.3M200.2 46.1l1.5 1.9M200.9 54v7.6l.1 .8a4.8 4.8 0 0 0 1.7 2.1 6.9 6.9 0 0 1 2 4.9v18.8l-.1 .6-.5 .8-.2 .4v14.9l-.2 1.2a4.5 4.5 0 0 0-1.5 3.8 5.6 5.6 0 0 1-3.2 4l-1.3 .3h-8.6l-.9-.4-2-1.9M204.5 51.2l2.2 3M204.5 59.1l-.5 .7a7.3 7.3 0 0 0 .3 5.2l.7 .9a5.5 5.5 0 0 1 2.2 4.4v30.1a7.6 7.6 0 0 1-2.9 5.8 6.5 6.5 0 0 0-1.4 4.3 6.3 6.3 0 0 1-5.2 4.2h-9.8l-.8-.4-1.7-1.7M208.3 56.5l1.2 1.8M60 74.8l-.9 2.6M63.4 66.8l-.9 2"/>
<path d="M64.3 76.4h4.6a5.9 5.9 0 0 1 4.3 2 4.8 4.8 0 0 0 2.9 1h14.1a4.7 4.7 0 0 1 3.9 1.8v1.3a1.44 1.44 0 0 0 1.6 1.2l.7 .4 3.9 4a2.07 2.07 0 0 0 .8 1.8 3.8 3.8 0 0 1-1.3 4.4M66.7 70.7l1.6 .3 .9 .5 6.5 6.5 1.1 .6 .8 .2h12.7a7.1 7.1 0 0 1 6.1 3.7l.1 .3a1.47 1.47 0 0 0 2 1.4h.3a3.4 3.4 0 0 1 2.2 3.9l.3 .8 .6 .9a3.2 3.2 0 0 1 .2 2.8l-.4 1.1-1.2 1.4M66.8 60.6l-1.4 2.3M69.4 65.1l11.1 11.1a6.8 6.8 0 0 0 4.9 2h5.2a7.4 7.4 0 0 1 6.4 3.9l.1 1 .4 .4 .3 .2h1.6l1.5 1.2a6.1 6.1 0 0 1 2.1 4.3 9.6 9.6 0 0 1-.6 5l-1.1 1.6M119.9 66.8l-.4 .2M122.4 63.2l-2.5 1M144.7 62.1l3.1 2.7h1.6l5.8 4.8 .7 .8 .5 1.5v5.5l-1 1.1v5.4l5 5v2.9l2.1 2.2h1.9l.7-.8h10.1l1.9 1.9M146.3 60.5l-1.2-1.1h-1.7l-.5 .5v1l-.3 .3v.3l2.6 2.6 1.6 1.3h2.4l5.5 4.7 .7 1 .3 1.3v4.8l-1 1v5.9l5 5.1v2.9l2.4 2.5h2.7l.6-.7h8.8l2 1.9h.1M174.7 78.5l-.6 2.9M185.9 79.9a2.59 2.59 0 0 0-2.5 1.7 2.59 2.59 0 0 0 .8 2.9l2.2 2.2 .4 1.3 1.1 1.2a1.3 1.3 0 0 1 0 1.9l-2.5 2.4M187 72.7l-1.7 3M188 74.7l.3 .6v2.5l-.1 .3-.4 .4a3.8 3.8 0 0 1-2.7 .3 3.5 3.5 0 0 0-2.2 5.4l.7 .9a4.5 4.5 0 0 1 1.9 5.2l-1.6 1.7"/>
<path d="M207.8 64.4v36.4a7.5 7.5 0 0 1-2.9 5.8l-.6 1-.5 1.8a5.7 5.7 0 0 1-4.5 5.7l-1.9 .3h-9.2a4.6 4.6 0 0 1-3.5-2M210.6 69.9a2.38 2.38 0 0 0-2.3 2.3v33.7a6.7 6.7 0 0 1-2 4.8l-5.1 5.2a7 7 0 0 1-4.9 2h-7.5l-.9-.1-1.1-.7-2.9-2.9M211.8 62.1l2 4M213 75.6a2.5 2.5 0 0 0-2.1 1.3 6.9 6.9 0 0 0-2 4.9v24.4a6.7 6.7 0 0 1-2 4.8l-4.9 5a4.8 4.8 0 0 0-1.2 4 2.05 2.05 0 0 1-2 1.8h-7.7l-1.3-.3-.7-.6-6-6M214.8 68l.9 2.1M217.3 74.1l.8 2.1M218.5 77.7l.9 2.6M55.6 94l1.8 2.7M56.5 98.3l-1.4 2.2M56.6 87.5l-.6 3.7v-.2M58 81.1l-.7 2.8M61.1 88.3h6.8l.9-.1a5.3 5.3 0 0 0 2.3-1.8l1.2-.6 .9-.1h18a6.7 6.7 0 0 1 5.2 2.8l1.1 .4 1.4 1.3 .1 1.8-.8 .8"/>
<path d="M62.5 82.3a7.4 7.4 0 0 0 5.7 2.9h25a5 5 0 0 1 3 2.1l1 .3 2.5 2.5a3.7 3.7 0 0 1-.7 3.4M86 99.7a4.5 4.5 0 0 0-1.9-1.6l-2.5-.1-.7 .4a4.6 4.6 0 0 0-1.7 2.1l-.1 .8v25.8a6.7 6.7 0 0 0 1.9 4.7l3.8 3.8a6.3 6.3 0 0 1 1.7 5.2l.2 1.1 .9 1.6 4.2 4.2a5.9 5.9 0 0 1 .7 6.5l-.6 .8-6.5 6.5M86.8 98.9a5.2 5.2 0 0 0-6.2-1.1l-.3 .2a4.1 4.1 0 0 0-1.8 2.5v26.7a7 7 0 0 0 2 4.9l2.9 2.9 .5 .9 .2 .9a7.8 7.8 0 0 0 2.1 6.4l5.2 5.2 .8 1.1a6.8 6.8 0 0 1 .2 3.2l-.3 1-3.4 3.5a3.7 3.7 0 0 1-5.2 .1l-.6-.2h-1.9M88 95.5h.1M88.3 97.4l-1.1-.8-.9-.2h-4.8l-.9 .5-2.2 2.1-.3 .8-.1 .8v26.9a7 7 0 0 0 2 4.9l2.7 2.8a4.9 4.9 0 0 1 .9 3.7 6.4 6.4 0 0 0 1.8 4.4l5.1 5a4.1 4.1 0 0 1 .5 5.7l-1.3 1.2a3.3 3.3 0 0 1-3.9-.4l-2.3-2.4a5 5 0 0 0-5.8-.7l-.7 .7M89.1 96.6l-1.4-1.3h-4.7a4.5 4.5 0 0 0-3.1 1.3l-2.1 2.1-.4 1.1-.1 28a6.8 6.8 0 0 0 2.1 4.9l2.5 2.5 .8 1.2 .3 1.4v4.3l-.6 1.2-4.5 4.7a3.2 3.2 0 0 1-4.6-.6M89.9 95.8l-1.3-1.1h-6.1l-1 .2-1.3 .6-2.5 2.5a3.1 3.1 0 0 0-.9 2.1v23.3l-.1 .8-.4 .8a4.3 4.3 0 0 0-1.5 3v6.5a6.7 6.7 0 0 1-2 4.9l-2.7 2.8M90.7 95.1a7.7 7.7 0 0 0-3.3-2.6 10 10 0 0 0-4.5-.2l-1.3 .3-1.9 .8-1 .9-3.3 3.3a3 3 0 0 0-.2 2.3l.7 1.1 .3 1.2v21l-.4 1.4-1.1 1.5-.3 .8-.3 5.2a7.5 7.5 0 0 1-4.1 4.1l-1.3 .3-1.5 .2M91.4 94.3l-1.3-1.2a2.76 2.76 0 0 1-1.8-.9l-1.2-.5h-3.6l-.9-.4-.8-.7a5.2 5.2 0 0 0-3.7-.2 6.4 6.4 0 0 0-4.3 3 2.1 2.1 0 0 0 .7 1.9l.1 .6v22.4a7 7 0 0 1-2 4.9l-7.8 7.8M92.2 93.5a2.48 2.48 0 0 0-2.4-1.1l-1.8-1.1-3.4-.1a3.4 3.4 0 0 1-2.5-1.2l-.3-.1a10.5 10.5 0 0 0-5.2 .3l-1.2 .7-1 .8a2.64 2.64 0 0 0-.4 4.1v20.4a7 7 0 0 1-2 4.9 12.6 12.6 0 0 1-3.6 3.2l-1.3 .5a12.4 12.4 0 0 1-4.3 .3M92.9 92.8l-.2-.1a10.2 10.2 0 0 0-3.4-3l-1.2-.4-1.3-.1h-8.4a6.9 6.9 0 0 0-6 3.8v1.4l.5 .9a2.06 2.06 0 0 1 .6 1.5l-.1 19.3a5.2 5.2 0 0 1-3.3 3.3l-2 .5h-4.8M93.7 92a8.1 8.1 0 0 0-5.6-3.4h-9.8a7.2 7.2 0 0 0-6.4 4.2 3.4 3.4 0 0 0 .9 3.7l.1 .8v14a2.94 2.94 0 0 1-2.2 2.7l-1.8 .4h-5.7l-1.6-.5-1.3-.9"/>
<path d="M94.5 91.2a11.2 11.2 0 0 0-4-3.2l-2-.5-14.2-.1a3.8 3.8 0 0 0-3.2 3.4v3.9l.1 .7 .3 .5a2.74 2.74 0 0 1 .9 2v7a2.18 2.18 0 0 1-2.4 1.9h-10.2M96.7 91.2l-2.4-2.4a6.8 6.8 0 0 0-4.9-2h-15.7a5.2 5.2 0 0 0-4 3.6l-.3 .6a13.3 13.3 0 0 0-.3 4.2 6.7 6.7 0 0 1-6.7 5.4h-2.6M97.5 92l.8-1v-.4l-.3-.5a1.86 1.86 0 0 0-1.6-.9l-.2-.1a9.3 9.3 0 0 0-4.5-2.7l-1.4-.1h-17.1a6.4 6.4 0 0 0-4.5 4.6l-.1 1.2a2.58 2.58 0 0 1-2.5 3.2l-4.3-.1-.9-.2-.7-.5M104.4 96.8l.5 .4M163 90h2.3l.2 .2M172.5 99.7a3.2 3.2 0 0 0-5.1-.6l-1.2 1.1-.3 .8-.2 3.8-3.2 3.4a3.5 3.5 0 0 1-2.1 .7l-.5 .4a12.7 12.7 0 0 0-3.1 3.5 4.5 4.5 0 0 0-.3 4.6l2.2 2.3M173.2 98.9a4.5 4.5 0 0 0-6.4-.1 3.1 3.1 0 0 0-1.5 2.4v2.8l-.3 .8-3.2 3.3-1.3 .2a4.9 4.9 0 0 0-2.3 1.8M174 98.1a5.9 5.9 0 0 0-6.6-.6l-.8 .7a4.5 4.5 0 0 0-1.8 2.1l-.3 1.8-2 2.1-.3 .5-.1 .6-7 7.1a6.9 6.9 0 0 0 .2 9.5l3.8 3.8a7 7 0 0 1 2 4.9v22.5a4.5 4.5 0 0 0 1.5 3l.4 .8 .1 .8v14.1a7.3 7.3 0 0 0 2.8 5.6M175.6 96.6l-.5-.5a4.5 4.5 0 0 0-3.2-1.3h-4.8a1.86 1.86 0 0 0-1.4 1.2v1M182.4 88.9a1.5 1.5 0 0 1 .4-1.6 1.5 1.5 0 0 1 1.6-.4l.1 .1a2.08 2.08 0 0 1-.1 2.8l-1.1 1.1-.2 .3M186.4 81.1h-1.5a1.74 1.74 0 0 0-.3 2.8l2.3 2.4 .6 1.5 1.4 1.6v1.8l-.1 .5-2.6 2.6M186.6 82.6a5.2 5.2 0 0 1 1.2 4.4 3.4 3.4 0 0 0 1.4 1.8 4.6 4.6 0 0 1-.8 4.8l-1.4 1.5"/>
<path d="M187.3 90.1l-2.6 2.7M188.9 87l.9 1.2a8.9 8.9 0 0 1 .1 4.6l-.1 .5a6.9 6.9 0 0 1-2.1 2.5M190.7 93.4l-.1 .7-.3 .7-1.8 1.8M190.8 95.6l-1.4 1.4-.1 .4M193.9 94.1l.1 .7a4 4 0 0 1 1.1 2.2v2.1a2.7 2.7 0 0 0-.4 1.9l-.8 1M193.9 94.1h.1M194 99a3.1 3.1 0 0 1-.9 2.2M194 99h.1M196 99.3l.2 .2M196.2 99.5a1.45 1.45 0 0 1 0 2.4l-2.3 2.3M198.8 92.5a5.6 5.6 0 0 0 1 8.2l.3 .6a1.35 1.35 0 0 1-.4 1.2l-5.2 5.2a1.25 1.25 0 0 1-1.8 0l-1.1-1.2M198.8 92.5h.1"/>
<path d="M200.3 95a1.7 1.7 0 0 0-.1 2.3l2.2 2.1 .3 .6-.1 4.5-.6 1.6-.7 .8-4.2 4.2-.7 .4h-7.5l-1.2-1.2M213.6 95.4l-.3 .8v12.3a6.9 6.9 0 0 1-2.1 4.9l-3.7 3.8a3.9 3.9 0 0 1-2.9 1 2.23 2.23 0 0 0-1.9 2.7 3.2 3.2 0 0 1-2.8 2.7h-15a4.5 4.5 0 0 1-3.4-1.7l-.6-.3a3.4 3.4 0 0 1-3.8-3.1 3.9 3.9 0 0 1 .9-3.6l1.4-1.5M213.6 95.4h.1M214.9 81.6a5.2 5.2 0 0 0-1.5 3.6v5.3a5.5 5.5 0 0 1-2.1 4.2l-.8 1.4-.3 1.1v8.6a6.8 6.8 0 0 1-2 4.9l-5.3 5.3a4.8 4.8 0 0 0-1.3 3.9 2.61 2.61 0 0 1-2 2.5h-13.2a6 6 0 0 1-4.2-1.8l-1.9-1.8a2.38 2.38 0 0 1 .6-3.9M216.4 87.6a5.3 5.3 0 0 1-.3 3l-3.2 3.4a7 7 0 0 0-2 4.8v7.4a6.9 6.9 0 0 1-2 4.8l-5.5 5.5a5 5 0 0 0-1.3 4.2 2.82 2.82 0 0 1-2.9 2.3h-13.9a4.8 4.8 0 0 1-3.5-1.6 3.4 3.4 0 0 0-2.1-.4 2.85 2.85 0 0 1-1.9-2.9M217.4 93.8l-1.8 .3-1.1 .5-.9 .8M220.9 86.7l-1.6 2.4M221.9 93.3l.4 2.5M222.3 97.6l.2 2.2M225.8 88.9l.6 .6h2.3M55.2 107l1.6 2.7M55.8 113.6l.5 .5 .6 1.5"/>
<path d="M58.4 117.6l-1.2 2.1-.4 .3M61.4 119.1l.8 .1 1.1 .7M63.3 119.9h.1M83.7 102l-.9-1a1.06 1.06 0 0 0-1.6 .5l-.3 1.1v8.6l.1 .7 .5 .5 .3 .6v5.6a3.6 3.6 0 0 0 1.2 2.3l.4 .9 .1 1v4.9a5.8 5.8 0 0 0 1.8 4.2l2.4 2.4a1.96 1.96 0 0 1 .6 1.4v4.3l.3 1.1 .5 1.1 .7 .8 10.7 10.8a4.6 4.6 0 0 1 1.4 3.2v12a4.7 4.7 0 0 1-1.4 3.3M83.7 104.2l-.4 .6-.2 .7v4.4l-.7 1.7v6.7l.1 .7a5.5 5.5 0 0 1 1.7 3.6v5l.1 1.2 .7 1.7 3.4 3.6 .4 .8 .1 .8v4.3l.6 1.6 .7 .9 16.4 16.3 .5 .8 .3 1.2v11a4.5 4.5 0 0 1-1.4 3.3M84.5 101.2l-1.3-1.2a1.83 1.83 0 0 0-2.8 .9l-.2 1.1v9.8l.1 .7 .6 .8 .3 .7v5.8l.6 1 .2 .6v8.8l.3 .8 .5 .8 3.1 3.1a6.6 6.6 0 0 1 1.8 5.2 5.6 5.6 0 0 0 1.7 3.4l6.5 6.5a6.2 6.2 0 0 1 1.8 4.3v9.5a7.1 7.1 0 0 1-2.5 5.3M84.5 104.9l-.6 .7-.2 .5v4.2l-.2 .6a1.89 1.89 0 0 0 0 2.8 3.5 3.5 0 0 1 .3 2.5l-.1 .7a1.59 1.59 0 0 0-.5 1.9 4.2 4.2 0 0 1 1.6 3.2v5.4a4.9 4.9 0 0 0 1.4 3.5l2.6 2.7 .5 .8 .3 1v4.6l.3 .9 .4 .8 21.8 21.8a6.7 6.7 0 0 1 2 4.7v5a5.1 5.1 0 0 1-2.3 4.2M85.3 100.4l-1.3-1.3a2.18 2.18 0 0 0-2-.3l-.9 .3-1.2 1.4-.3 .5v11.4a3.3 3.3 0 0 0 .9 2l.1 5.8 .1 .3 .5 .6 .1 .5v8l.2 1 .6 1.4 3.3 3.3a6 6 0 0 1 1.6 5l.1 .6a5.9 5.9 0 0 0 1.7 3l3.4 3.5a4.7 4.7 0 0 1 1.5 3.4v8.3a6.9 6.9 0 0 1-2 4.9l-1.5 1.5M88.3 108.8a7.8 7.8 0 0 0-2.4 2.9 5.6 5.6 0 0 0 0 3.5l.4 .7 .2 3.3 .5 1M89.1 109.6l-2 2a2.61 2.61 0 0 0-.1 3.7l.9 .8M89.9 110.3l-2 2.1-.4 .7-.1 .7M90.7 111.1a6.2 6.2 0 0 0-2.2 2.8l-.1 1"/>
<path d="M91.4 111.9l-1.7 1.7-.2 .4M92.2 112.6l-2.5 2.5a4.3 4.3 0 0 0-.1 4.4l.5 .7M92.9 113.4l-2.7 2.7-.2 .4M93.7 114.2l-1.6 1.8v7.7a6.5 6.5 0 0 1-2.3 4.9l-.4 .8-.3 1.3M94.5 114.9l-1.4 1.3 .8 1.1h1.6M95.6 103.1l.8 6.9M102.1 109.6a2.19 2.19 0 0 0 1.3 1l6.3 .1M105.9 105.7l1.5 1.6M106.6 108h.1M107.4 107.3h.1M120.8 114.3l.3 .3M137.8 107.2h.1"/>
<path d="M137.8 112.7v1.2M158.2 110.1l-2.8 2.9a6.1 6.1 0 0 0 .5 8.6l3.8 3.8a7 7 0 0 1 2 4.9v22.4l.1 .9 .3 .8a4.6 4.6 0 0 1 1.6 3.1v11.3a3.3 3.3 0 0 0 3.2 2.4 3.2 3.2 0 0 1 1.7 .8l3 3M158.4 110l-.2 .1M158.5 119.5l.2 .2M158.7 119.7a8.8 8.8 0 0 1 3.4 5l.1 1.4v26.4l.3 1a6.2 6.2 0 0 1 1.8 3.8v9.2a2.46 2.46 0 0 0 1.8 1.9l1.9 .5 4.8 .1a4.5 4.5 0 0 1 4.4 2.9v.3M170.2 102l-.8-.8a1.31 1.31 0 0 0-1.9 1.3l-.1 2.6-.4 1-4.7 4.7a2.23 2.23 0 0 0-.6 1.6l-1.4 1.5-.4 .3a2.2 2.2 0 0 0-1.8 .7l-.3 .8 .2 .6 7.1 7.2 .9 1.3a7 7 0 0 1 .3 3.5l.3 1.2a6.7 6.7 0 0 1 2 3.7v6.8l-.3 .6-.7 .9-.2 .7v9.1l.6 1.1 6.8 6.9a6.9 6.9 0 0 0 4.9 2h12.6M170.2 104.2l-6.6 6.5a7 7 0 0 0-2 4.9 6.2 6.2 0 0 0 .4 3.7l.5 .7 5.1 5.2 .7 1.3 .1 4 .7 1 .1 .7v7.3l-.3 1.3-.7 .9-.3 .9 .1 8.7 .5 .8 6.6 6.6a7 7 0 0 0 4.9 2.1h7.5a4.5 4.5 0 0 0 3.1-1.4l3.2-3 .7-.3 1.5 .1M170.9 101.2l-1.1-1.1a1.43 1.43 0 0 0-2.2 .6l-.4 .6-.2 .7-.1 2.8-.4 1-3.6 3.7-.7 .3-1.2 .2-.5 .3a9.7 9.7 0 0 0-2.7 3.2l-.5 1.7a1.94 1.94 0 0 0 .5 1.7l6.9 7a3.8 3.8 0 0 1 .8 4.1l-1.2 1.3v1.7v.4l.9 1.4 .2 .8v28.5l.1 .6 2.9 2.9 1.2 .6h16.4a2.77 2.77 0 0 0 1.6-.8M170.9 104.9l-7.5 7.7a6.6 6.6 0 0 0-1.1 5.3l.3 1 .5 .9 4.6 4.6 .9 .6a2.37 2.37 0 0 1 2.5 2.2l-.1 4.8-.3 .9-.7 .8-.2 .7v5.1a4.7 4.7 0 0 1-1.3 3l-.1 7.8 .3 1 .4 .7 6.3 6.2a7 7 0 0 0 4.9 2h7.3l1.5-.5 1.4-.9 7.2-7.3a1.71 1.71 0 0 1 2.5 .1l.6 .6M171.7 100.4a3.4 3.4 0 0 0-1.9-1.5h-.9a3.6 3.6 0 0 0-2 1.6l-.5 .9-.1 3.4-.2 .6-3.4 3.5-.6 .3-.6 .1a1.87 1.87 0 0 0-1.4 .6 9.5 9.5 0 0 0-3.2 4l-.2 .7a2.6 2.6 0 0 0 .4 2.6l3.7 3.6a7 7 0 0 1 2 4.9v4.6l.3 .7 .4 .7M171.7 105.7l-7.8 7.9a4.8 4.8 0 0 0 .4 6.4l4.1 4.1 1.8 .5 1.5 1.6 .1 .4v5.7a6.8 6.8 0 0 0 2 4.9l8 8a6.8 6.8 0 0 0 4.9 2h17.8M172.5 106.5l-8.4 8.4a3.1 3.1 0 0 0 .5 4.4l4 4 1.6 .4 .4 .3a3.7 3.7 0 0 1 1.7 2.2l.1 5.8a6.9 6.9 0 0 0 2 4.9l6.6 6.6a7.7 7.7 0 0 0 5.9 3.1h11.7l1-.2 1.5-.7 2.9-2.8 1.1-.8a5.3 5.3 0 0 1 2.7-.2"/>
<path d="M173.2 107.3l-4.5 4.5a6.4 6.4 0 0 0-.4 8.8l3.8 3.8a3.2 3.2 0 0 1 1 2.3v5a6.8 6.8 0 0 0 2 4.9l7.3 7.3a7 7 0 0 0 4.8 2h11.2l1.3-.3 1.2-.8 7.6-7.6 .7-.5 1.4-.4M174.8 108.8a4.8 4.8 0 0 1-2 1.6l-1.1 .2a6.7 6.7 0 0 0-4 8.1l.9 1.4 5.1 5.1a6.9 6.9 0 0 0 4.9 2h24a4.7 4.7 0 0 1 3.5 1.8l1.1 .8 1.2 .5a11.6 11.6 0 0 0 4.6 .3M175.6 109.6l-.3 .1-5.8 5.8a5.2 5.2 0 0 0 1.1 5.7l3.5 3.4a6.9 6.9 0 0 0 4.8 2.1h22a5.3 5.3 0 0 0 3.7-1.6l.4-.2h2.6a4.6 4.6 0 0 1 3 1.4l.6 .1h1.9l1.8-1.7M176.3 110.3l-3.7 3.7a5 5 0 0 0 .4 6.5l3.6 3.6a6.9 6.9 0 0 0 4.8 2h19.3a5.5 5.5 0 0 0 3.6-1.6l.6-.1a3.4 3.4 0 0 0 3-.8l3-3a6.9 6.9 0 0 1 5.5-2M177.1 111.1l-3.7 3.7a3.5 3.5 0 0 0-.1 5l3.7 3.7a6.8 6.8 0 0 0 4.9 2h17.9a5.8 5.8 0 0 0 4.2-1.8l.3-.1a4.2 4.2 0 0 0 3.6-1l8.9-8.9 .4-.6 .2-.7M177.8 118.1h.1M180.1 114.2a6.2 6.2 0 0 0-2.2 2.9l-.1 1M181.6 102.4a3.4 3.4 0 0 1-3 1.1l-.5 .3-4.1 4.2M188.5 109.6l1.2 1.1 .4 .2h5.6M217.8 106.2a9.8 9.8 0 0 0-3.1 3.7l-.3 1.2a7.6 7.6 0 0 1-2.1 6.1l-4.7 4.7-.8 .5-.9 .3a4.5 4.5 0 0 0-4.2 1.8l-.6 .3-.8 .1h-18.1a6.5 6.5 0 0 1-6.1-4l-.1-1v-3.9a5.6 5.6 0 0 1 1.9-4.1M217.8 100h-2a2.18 2.18 0 0 0-1.9 2.5l-.1 7.5-.2 1.1-.5 1.1-.7 .9-10.6 10.5-1.2 .6-.9 .1h-15.2a4 4 0 0 1-3.1-1.6l-.8-.4a3.9 3.9 0 0 1-3.3-1.4 6.6 6.6 0 0 1 .2-6.9l1.1-1.4M220.9 119.5l-.5 2.4"/>
<path d="M221.9 113l-.6 2.4M222.4 104.1l.1 2.3M58.4 126.4l.7 2.5M60.5 132.6l.8 2M63 138.6l1.3 2.7M97.7 135.8l.4 1.2M136.3 120.5l2.4-.9-.9 .9M163.5 131.7h.1M163.6 131.7l.9 1.4 .3 1.6v30.6a2.32 2.32 0 0 0 2.4 1.5h11.1a5.3 5.3 0 0 1 4.2 2.2M216.3 134.1l-1.5 4.2M218 130.1l-.7 2.1M219.4 125.9l-.9 2.8"/>
<path d="M65.9 142.1l.1 2.4M69.5 150l1.9 1.4M73.4 155.3l-7.4 5.7M77.9 157.5l-.2 2.8M204.4 155.1l-1.6 1.6M212.8 142.2l-1 1.9M82.3 164.9l2.6 2.1M87.3 169.1l2.5 1.9M92.7 172.9l1.2-1.7 4.4 2.8 3.4 1.9-.1 .1M94.8 174.1l3.5 2.2M104.1 179.3l2.2 .8M175.6 178.1l-2.1 1.1"/>
<path d="M179.4 176.3l-2.1 .8M186.9 171.6l-1.8 1.2M190.4 169l-1.8 1.3M195.4 164.7l3 3.5M200.1 160.1l-1.5 1.5M110.2 181.7l5.6 1.8M169.9 180.8l-2.5 .9"/>
</g>
<g fill="none" stroke="#000080" stroke-width=".42">
<path d="M87.5 19.7l-.1 .1M88.3 19.3h-.1M89.1 18.8h-.1M89.9 18.3l-.1 .1M90.7 17.8l-.1 .1M91.5 17.4h-.1M92.4 17h-.2M93.2 16.5l-.1 .1M94 16.1h-.1M94.8 15.7h-.1M95.7 15.2l-.1 .1M96.5 14.8l-.1 .1"/>
<path d="M97.3 14.4l-.1 .1M98.2 14.1h-.1M99 13.7h-.1M99.9 13.3h-.1M100.7 12.9l-.1 .1M101.6 12.6h-.1M102.5 12.2l-.1 .1M103.3 11.9h-.1M104.2 11.5l-.1 .1M105.1 11.2l-.1 .1M105.9 10.9h.1M106.8 10.6h-.1"/>
<path d="M107.7 10.3h-.1M108.6 10h-.1M109.5 9.7l-.1 .1M110.4 9.4l-.1 .1M111.3 9.2h-.2M112.1 8.9v.1M113.1 8.7h-.2M113.9 8.4h.1M114.9 8.2h-.2M115.8 8h-.1M116.6 7.7v.1M117.6 7.6h-.1"/>
<path d="M118.5 7.3l-.1 .1M119.4 7.2h-.1M120.3 7h-.1M121.2 6.8h-.1M122.1 6.6l-.1 .1M123 6.5h.1M124 6.3l-.1 .1M124.9 6.2h-.1M125.8 6.1h-.1M126.6 6h.1M127.6 5.9h.1M128.5 5.8h.1"/>
<path d="M129.5 5.7h-.1M130.5 5.6h-.2M131.3 5.5h.1M132.2 5.4h.1M133.1 5.4h.1M134 5.3h.2M135 5.3h.1M135.9 5.2h.1M136.8 5.2h.1M137.8 5.2h.1M138.7 5.2h.2M139.7 5.2h.1"/>
<path d="M140.7 5.2h.1M141.6 5.2h.1M142.5 5.3h.1M143.5 5.3h.1M144.4 5.4h.1M145.3 5.4h.1M146.3 5.5h.1M147.2 5.6h.1M148.1 5.7h.1M149 5.8h.1M150 5.9h.1M150.9 6h.1"/>
<path d="M151.8 6.1h.1M152.7 6.2h.1M153.6 6.3l.2 .1M154.6 6.5h.1M155.5 6.6l.1 .1M156.4 6.8h.1M157.3 7h.1M158.2 7.2h.1M159.2 7.3v.1M160.1 7.6h.1M161 7.7l.1 .1M161.9 8h.1"/>
<path d="M162.8 8.2h.1M163.7 8.4h.1M164.6 8.7h.1M165.5 8.9l.1 .1M166.4 9.2h.1M167.3 9.4l.1 .1M168.1 9.7l.2 .1M169 10h.1M169.9 10.3h.1M170.8 10.6h.1M171.7 10.9h.1M172.6 11.2l.1 .1"/>
<path d="M173.4 11.5l.1 .1M174.3 11.9h.1M175.2 12.2l.1 .1M176 12.6h.1M176.9 12.9l.1 .1M177.7 13.3h.1M178.6 13.7h.1M179.5 14.1h.1M180.3 14.4l.1 .1M181.1 14.8l.1 .1M182 15.2l.1 .1M182.8 15.7h.1"/>
<path d="M183.6 16.1h.1M184.4 16.5l.2 .1M185.3 17h.1M186.1 17.4h.1M186.9 17.8l.1 .1M187.7 18.3l.1 .1M188.5 18.8h.1M189.3 19.3h.1M190.1 19.7l.1 .1M64.3 39.7h-.1M64.9 38.9l-.1 .1M65.5 38.2l-.1 .1"/>
<path d="M66.1 37.5l-.1 .1M66.7 36.9h.1M67.4 36.2l-.1 .1M68 35.5l-.1 .1M68.7 34.8l-.1 .1M69.3 34.2h-.1M70 33.5l-.1 .1M70.6 32.9h.1M71.3 32.2l-.1 .1M72 31.6h-.1M72.7 30.9l-.1 .1M73.4 30.3l-.1 .1"/>
<path d="M74.1 29.7l-.1 .1M74.8 29.1l-.1 .1M75.5 28.5l-.1 .1M76.2 27.9l-.1 .1M76.9 27.3h-.1M77.6 26.7l-.1 .1M78.3 26.1v.1M79.1 25.5l-.1 .1M79.8 25l-.1 .1M80.6 24.4l-.1 .1M81.3 23.9h-.1M82.1 23.3l-.1 .1"/>
<path d="M82.8 22.8l-.1 .1M83.6 22.3h-.1M84.4 21.8h-.1M85.2 21.2l-.1 .1M85.9 20.7v.1M86.7 20.2l-.1 .1M125.8 34.2l-.2 3.3M142.1 32.2h1.4M143.3 35.8l2.1 1.5-2.2 2.2M190.9 20.2l.1 .1M191.7 20.7l.1 .1M192.5 21.2l.1 .1"/>
<path d="M193.3 21.8h.1M194 22.3h.1M194.8 22.8l.1 .1M195.5 23.3l.1 .1M196.3 23.9h.1M197.1 24.4v.1M197.8 25l.1 .1M198.5 25.5l.1 .1M199.3 26.1v.1M200 26.7l.1 .1M200.7 27.3h.1M201.4 27.9l.1 .1"/>
<path d="M202.2 28.5v.1M202.9 29.1v.1M203.6 29.7v.1M204.3 30.3v.1M205 30.9v.1M205.6 31.6h.1M206.3 32.2l.1 .1M207 32.9h.1M207.6 33.5l.1 .1M208.3 34.2h.1M209 34.8v.1M209.6 35.5l.1 .1"/>
<path d="M210.2 36.2l.1 .1M210.9 36.9h.1M211.5 37.5l.1 .1M212.1 38.2l.1 .1M212.7 38.9l.1 .1M213.3 39.7h.1M51 59.8v.1M51.4 59v.1M51.9 58.2l-.1 .1M52.3 57.3l-.1 .1M52.7 56.5v.1M53.2 55.7l-.1 .1"/>
<path d="M53.6 54.9v.1M54.1 54.1l-.1 .1M54.6 53.3l-.1 .1M55 52.5v.1M55.5 51.7v.1M56 50.9v.1M56.5 50.1v.1M57 49.3v.1M57.5 48.6h.1M58.1 47.8l-.1 .1M58.6 47l-.1 .1M59.1 46.3v.1"/>
<path d="M59.7 45.5l-.1 .1M60.2 44.8h.1M60.8 44l-.1 .1M61.3 43.3h.1M61.9 42.5l-.1 .1M62.5 41.8l-.1 .1M63.1 41.1l-.1 .1M63.7 40.4h-.1M116.7 46.6l2.1 2.1v.6M125.2 54.4a5.6 5.6 0 0 1-4.8 2.5l-.7 .3a9.5 9.5 0 0 1-4.2 2.5l-1.3 .1h-4.9M126.7 55.9l-.7 .3-1.2 1.2a1.46 1.46 0 0 0 .5 1.9l.3 .4a5.6 5.6 0 0 1 .3 3.2 2.1 2.1 0 0 1-1.7 2.3h-5.8l-1.2-.3a5.1 5.1 0 0 0-3.5-1.7h-4.4M147.5 55.5l.1 .1-2 2v2.2l.7 .7"/>
<path d="M152.4 48.7h.6l1.9 1.9M214 40.4h.1M214.5 41.1l.1 .1M215.1 41.8l.1 .1M215.7 42.5l.1 .1M216.3 43.3h.1M216.8 44l.1 .1M217.4 44.8h.1M218 45.5v.1M218.5 46.3v.1M219 47l.1 .1M219.6 47.8v.1"/>
<path d="M220.1 48.6h.1M220.6 49.3l.1 .1M221.1 50.1l.1 .1M221.6 50.9l.1 .1M222.1 51.7l.1 .1M222.6 52.5v.1M223.1 53.3v.1M223.5 54.1l.1 .1M224 54.9v.1M224.5 55.7v.1M224.9 56.5v.1M225.3 57.3l.1 .1"/>
<path d="M225.8 58.2v.1M226.2 59v.1M226.6 59.8l.1 .1M43.7 79.9v.1M43.9 79v.1M44.2 78.1v.1M44.4 77.2v.1M44.7 76.3l-.1 .1M44.9 75.4v.1M45.2 74.5v.1M45.5 73.6l-.1 .1M45.8 72.8l-.1 .1"/>
<path d="M46.1 71.9l-.1 .1M46.4 71l-.1 .1M46.7 70.1l-.1 .1M47 69.2l-.1 .1M47.3 68.4v.1M47.6 67.5v.1M48 66.6l-.1 .1M48.3 65.8v.1M48.7 64.9v.1M49.1 64.1l-.1 .1M49.4 63.2v.1M49.8 62.4v.1"/>
<path d="M50.2 61.5v.1M50.6 60.7v.1M109.3 73.6h2.6M111.9 73.6h.1M131.3 60.5l2.1-1.9 3.5 3.4M134.4 63.7l-2.1 2.2h-1.8l-2.7 2.7h-10.9l-5 5M157.4 68.6l-2.2 1M172.9 72.6l1.1 3M227 60.7l.1 .1M227.4 61.5l.1 .1M227.8 62.4v.1M228.2 63.2v.1"/>
<path d="M228.6 64.1v.1M228.9 64.9l.1 .1M229.3 65.8v.1M229.6 66.6l.1 .1M230 67.5v.1M230.3 68.4l.1 .1M230.7 69.2v.1M231 70.1v.1M231.3 71v.1M231.6 71.9v.1M231.9 72.8v.1M232.2 73.6v.1"/>
<path d="M232.4 74.5l.1 .1M232.7 75.4v.1M233 76.3v.1M233.2 77.2v.1M233.4 78.1l.1 .1M233.7 79v.1M233.9 79.9v.1M41 99.3v.1M41.1 98.3v.1M41.1 97.4v.1M41.2 96.5v.1M41.2 95.5v.1"/>
<path d="M41.3 94.6v.1M41.4 93.7v.1M41.5 92.8v.1M41.6 91.8v.1M41.7 90.9v.1M41.8 90v.1M42 89.1l-.1 .1M42.1 88.1v.1M42.2 87.2v.1M42.4 86.3v.1M42.6 85.4l-.1 .1M42.7 84.5v.1"/>
<path d="M42.9 83.6v.1M43.1 82.7h.1M43.3 81.7v.1M43.5 80.8v.1M103.6 98.1l-4.9 5M163 90l-.3 .3M163.4 80.3l2.7 2.7h1.7l.9 .9v1.1l1.5 1.5h.8l.6 .6v1.9l.6 .5h3.9l3.3 3.3M168.2 90v.9l1.6 1.6h6.2l1.9 1.8M178.6 93.5l2.9 3v5.9M228.7 89.5h.1M234.1 80.8v.1M234.3 81.7v.1"/>
<path d="M234.5 82.7h.1M234.7 83.6v.1M234.9 84.5v.1M235.1 85.4v.1M235.2 86.3v.1M235.4 87.2v.1M235.5 88.1v.1M235.7 89.1v.1M235.8 90v.1M235.9 90.9v.1M236 91.8l.1 .1M236.1 92.8v.1"/>
<path d="M236.2 93.7v.1M236.3 94.6v.1M236.4 95.5v.1M236.5 96.5v.1M236.5 97.4v.1M236.6 98.3v.1M236.6 99.3v.1M40.9 103v.2M41 101.1v.1M41 102v.2M41 104v.1M41 104.9v.2"/>
<path d="M41 100.2v.1M41 105.9v.1M41 106.8v.1M41.1 107.7v.1M41.1 108.7v.1M41.2 109.6v.1M41.2 110.5v.1M41.3 111.4v.1M41.4 112.4v.1M41.5 113.3v.1M41.6 114.2v.1M41.7 115.1v.2"/>
<path d="M41.8 116.1v.1M41.9 117l.1 .1M42.1 117.9v.1M42.2 118.9h.1M42.4 119.8v.1M45 103.4l1.9 3 2 .5 .9 1.3M90.2 100.7l5.4 2.4 3.2 3.4M98.2 113.4l1 1h7.6l.6 .5v6.4l2.7 2.8v.4M99.8 111.9l1.7 1.7h7.8l.8 .8v2.7M115.3 116v2.8l-1.2 1.2M118.6 109.1l-3.4 3.4h-13.1l-1.3-1.4h-.3M118.7 109.1h-.1"/>
<path d="M124.5 101.9l-9.7 9.7h-12.2l-1.3-1.3M124.5 101.9l4.1-4h2.6v3.5l.5 .6h1.2M124.6 101.8l-.1 .1M124.8 109.6l-1.4 2.1-2.6 2.6M132.1 103.3h-.2l-1.4-1.5v-2.1l-1-1h-.7l-3 3v2.4l-.6 .5h-2.1l-4.5 4.5M180 101h.2l1.3 1.4M181.5 101h1.5l7 7M181.5 102.4l.5 .5v.2M229.6 105.7l-.4 .3-.5 6.1M235.4 119.6v.1M235.5 118.7v.1M235.7 117.8l-.1 .1"/>
<path d="M235.8 116.8v.1M235.9 115.9v.1M236 115v.1M236.1 114v.2M236.2 113.1v.1M236.3 112.2v.1M236.4 111.3v.1M236.5 110.3v.1M236.5 109.4v.1M236.6 108.5v.1M236.6 107.5v.1M236.6 100.2v.1"/>
<path d="M236.6 106.6v.1M236.7 101.1v.1M236.7 102v.2M236.7 104.7v.1M236.7 105.6v.1M236.7 103v.9M42.5 120.7l.1 .1M42.7 121.6v.1M42.9 122.5v.1M43.1 123.4v.1M43.3 124.3v.1M43.5 125.2v.1"/>
<path d="M43.7 126.1v.1M43.9 127v.1M44.2 128h.1M44.4 128.8v.1M44.6 129.7l.1 .1M44.9 130.6v.1M45.2 131.5v.1M45.4 132.4l.1 .1M45.7 133.3l.1 .1M46 134.2l.1 .1M46.3 135.1l.1 .1M46.6 136h.1"/>
<path d="M46.9 136.8l.1 .1M47.3 137.7v.1M47.6 138.6v.1M47.9 139.4l.1 .1M92.6 137l.2 .1a4.8 4.8 0 0 1 1.4 3.4l-.1-.3M92.8 125.5l-.2 5M97.7 135.9l.4 1.1M97.7 129.7l.4 .8M229.9 139.4v.1M230.3 138.5l-.1 .1M230.6 137.7l-.1 .1M230.9 136.8v.1"/>
<path d="M231.2 135.9v.1M231.5 135v.1M231.8 134.1v.1M232.1 133.2v.1M232.4 132.4l-.1 .1M232.6 131.5v.1M232.9 130.6v.1M233.2 129.7l-.1 .1M233.4 128.8v.1M233.7 127.8l-.1 .2M233.9 126.9l-.1 .1M234.1 126v.1"/>
<path d="M234.3 125.1v.1M234.5 124.2v.1M234.7 123.3v.1M234.9 122.4v.1M235.1 121.5l-.1 .1M235.2 120.5v.1M48.3 140.3v.1M48.7 141.2h.1M49 142l.1 .1M49.4 142.9v.1M49.8 143.7v.1M50.2 144.5v.2"/>
<path d="M50.6 145.4v.1M51 146.2v.1M51.4 147.1v.1M51.8 147.9l.1 .1M52.2 148.7l.1 .1M52.7 149.5v.1M53.1 150.4l.1 .1M53.6 151.2v.1M54 152l.1 .1M54.5 152.8l.1 .1M55 153.6v.1M55.5 154.4v.1"/>
<path d="M56 155.2v.1M56.5 156h.1M57 156.7v.1M57.5 157.5v.1M58 158.3l.1 .1M58.5 159l.1 .1M59.1 159.8v.1M70.1 142.2h1.1M94.1 140.2h.3v.4M94.1 140.2v.1M135.3 159.3l-.8 .1M196 156.2l.7 .7"/>
<path d="M210.4 146.2l-2.1 3.6M218.8 159.9l-.1 .1M219.3 159.2v.1M219.9 158.4l-.1 .1M220.4 157.6l-.1 .1M220.9 156.8v.1M221.4 156.1h.1M221.9 155.3l-.1 .1M222.4 154.5v.1M222.9 153.7l-.1 .1M223.4 152.9l-.1 .1M223.8 152.1h.1"/>
<path d="M224.3 151.2l-.1 .1M224.7 150.4v.1M225.2 149.6l-.1 .1M225.6 148.8v.1M226.1 147.9l-.1 .1M226.5 147.1l-.1 .1M226.9 146.3l-.1 .1M227.3 145.4l-.1 .1M227.7 144.6l-.1 .1M228.1 143.7l-.1 .1M228.5 142.9l-.1 .1M228.8 142v.1"/>
<path d="M229.2 141.1v.1M229.6 140.3l-.1 .1M59.6 160.6l.1 .1M60.2 161.3v.1M60.7 162.1l.1 .1M61.3 162.8v.1M61.8 163.5l.1 .1M62.4 164.3l.1 .1M63 165l.1 .1M63.6 165.7l.1 .1M64.2 166.4l.1 .1M64.8 167.1l.1 .1"/>
<path d="M65.4 167.8l.1 .1M66 168.5l.1 .1M66.7 169.2v.1M67.3 169.9l.1 .1M67.9 170.6h.1M68.6 171.3h.1M69.2 171.9l.1 .1M69.9 172.6l.1 .1M70.6 173.2v.1M71.2 173.9h.1M71.9 174.5l.1 .1M72.6 175.2h.1"/>
<path d="M73.3 175.8h.1M74 176.4l.1 .1M74.7 177l.1 .1M75.4 177.6l.1 .1M76.1 178.2l.1 .1M76.8 178.8l.1 .1M77.5 179.4l.1 .1M78.3 180h.1M200.2 179.6v.1M201 179l-.1 .1M201.7 178.4l-.1 .1M202.4 177.8l-.1 .1"/>
<path d="M203.1 177.2l-.1 .1M203.8 176.6v.1M204.5 176l-.1 .1M205.2 175.4h-.1M205.9 174.7l-.1 .1M206.6 174.1l-.1 .1M207.3 173.4l-.1 .1M207.9 172.8h-.1M208.6 172.1l-.1 .1M209.2 171.4v.1M209.9 170.8l-.1 .1M210.5 170.1v.1"/>
<path d="M211.2 169.4l-.1 .1M211.8 168.7l-.1 .1M212.4 168l-.1 .1M213 167.3v.1M213.6 166.6v.1M214.2 165.9v.1M214.8 165.2h.1M215.4 164.4l-.1 .1M216 163.7l-.1 .1M216.6 163h-.1M217.1 162.2v.1M217.7 161.5h-.1"/>
<path d="M218.2 160.7v.1M79 180.6h.1M79.7 181.1l.1 .1M80.5 181.7h.1M81.2 182.2l.1 .1M82 182.8h.1M82.7 183.3l.1 .1M83.5 183.8l.1 .1M84.3 184.4h.1M85.1 184.9h.1M85.9 185.4h.1M86.6 185.9h.1"/>
<path d="M87.4 186.4h.1M88.2 186.9h.1M89 187.3l.1 .1M89.8 187.8l.1 .1M90.6 188.3h.1M91.4 188.7l.1 .1M92.2 189.2h.2M93.1 189.6l.1 .1M93.9 190l.1 .1M94.7 190.5h.1M95.6 190.9h.1M96.4 191.3h.1"/>
<path d="M97.2 191.7h.1M98.1 192.1h.1M98.9 192.4l.1 .1M99.8 192.8l.1 .1M100.6 193.2h.1M101.5 193.5l.1 .1M102.4 193.9l.1 .1M103.2 194.2l.1 .1M104.1 194.6h.1M105 194.9h.1M105.9 195.2v.1M106.7 195.5l.1 .1"/>
<path d="M107.6 195.8l.1 .1M108.5 196.1l.1 .1M109.4 196.4h.1M110.3 196.7h.1M111.1 197h.2M112.1 197.2v.1M112.9 197.5h.2M113.9 197.7h.1M114.7 198h.2M115.7 198.2h.1M116.6 198.4h.1M117.5 198.6h.1"/>
<path d="M118.4 198.8h.1M119.3 199h.1M120.2 199.2h.1M121.1 199.3h.1M122 199.5h.1M123 199.6v.1M123.9 199.8h.1M124.8 199.9l.1 .1M153.6 199.9h-.1M154.5 199.8h-.1M155.4 199.6h-.1M156.4 199.5h-.1"/>
<path d="M157.3 199.3h-.1M158.2 199.1l-.1 .1M159.1 198.9l-.1 .1M160 198.8h-.1M161 198.5l-.2 .1M161.9 198.3l-.1 .1M162.8 198.1h-.1M163.7 197.9h-.1M164.6 197.7h-.1M165.5 197.4h-.1M166.4 197.1l-.1 .1M167.3 196.9h-.1"/>
<path d="M168.2 196.6h-.1M169.1 196.3l-.1 .1M170 196l-.1 .1M170.9 195.7l-.1 .1M171.7 195.5h-.1M172.6 195.1l-.1 .1M173.5 194.8h-.1M174.4 194.5h-.1M175.2 194.1v.1M176.1 193.8h-.1M177 193.4l-.1 .1M177.8 193.1h-.1"/>
<path d="M178.7 192.7h-.1M179.6 192.3l-.1 .1M180.4 191.9l-.1 .1M181.3 191.5l-.2 .1M182.1 191.1l-.1 .1M182.9 190.7l-.1 .1M183.8 190.3h-.1M184.6 189.8l-.1 .1M185.4 189.4l-.1 .1M186.2 189h.1M187.1 188.5l-.1 .1M187.9 188l-.1 .1"/>
<path d="M188.7 187.6h-.1M189.5 187.1l-.1 .1M190.3 186.6l-.1 .1M191.1 186.1l-.1 .1M191.9 185.6l-.1 .1M192.7 185.1l-.1 .1M193.4 184.6v.1M194.2 184.1h-.1M195 183.5l-.1 .1M195.8 183l-.1 .1M196.5 182.5h-.1M197.3 181.9l-.1 .1"/>
<path d="M198 181.4h.1M198.8 180.8h-.1M199.5 180.2l-.1 .1M125.7 200.1h.1M126.6 200.2h.1M127.6 200.3h.1M128.5 200.4h.1M129.4 200.5h.1M130.3 200.6h.2M131.3 200.7h.1M132.2 200.7h.1M133.1 200.8h.1"/>
<path d="M134 200.8h.2M135 200.9h.1M135.9 200.9h.1M136.8 200.9h.1M137.8 200.9h.1M138.7 201h.9M140.4 200.9h.1M141.4 200.9h.1M142.4 200.9h-.1M143.2 200.9h.2M144.2 200.8h.1M145.1 200.8h.1"/>
<path d="M146 200.7h.2M147 200.7h.1M147.9 200.6h.1M148.8 200.5h.1M149.9 200.4h-.1M150.8 200.3h-.1M151.7 200.2h-.1M152.7 200l-.1 .1"/>
</g>
<g fill="none" stroke="#000080" stroke-width="1.1">
<path d="M138.8 70l.1 .1M168.6 75.6v4.7h5.5l.2 .1M174.1 81.4v5.4M136.1 113.9v3.1l.1 .2M137.8 107.2v6.7M138.7 118.9l.6 .3 .3 .6v5.5M138.7 118.9a2.64 2.64 0 0 1 2.7 2.7v3.7M138.7 118.9v.7M133 120.5h3.3M137.8 120.5v4.8M138.4 120.5l.5 .1 .4 .3 .3 .7M144.4 120.5v1.8l-.2 .1v4.7l1.8 1.8h6.4l5.4 5.4v8.1l-2.7 2.7h-10.9l-1 1.1v13.2"/>
<path d="M146.2 137.2h-.5v2.4h-3.4M134.5 159.4v5.4M135.3 172.4h3.5v5l-2.6 2.5v4.4M142.3 175v4l-.8 .8M135.8 184.3h.4M136.2 184.3l-.6 .3-.3 .4v4.5M141.8 184.3h-.4l.7 .3 .2 .4v4.5"/>
</g>
<path d="M134.2 69.4l-1.5 .7M138.9 70.1v3.3l-2.2 2.1M139.6 113.9v-3h7l.3 .1 .1 .3v5.4l-.5 .3h-2.1M141.4 110.9v3" fill="none" stroke="#000080" stroke-width="1.4"/>
<g fill="none" stroke="#000080" stroke-width="1.7">
<path d="M148.5 74.8h-2.3l-1.1 1.1M174 75.6h4.8l.5 .1 .5 .3M179.5 81.4v5.4M126.9 117.3v3.9l1.1 1.1M97.1 120.4l1-1v5.4M97.7 129.7v6.2M98 135.5l-.3 .3M136.1 125.3v.7l-.9 .9h-7.8l-.5-.5M133.4 157.4l1.9 1.9v10.6M136.3 179.8v4.7M142.3 169.9h2.9l1.7 1.7v11.5l-1.3 1.2h-3.8M136.3 184.2l-.1 .1"/>
<path d="M141.4 184.3h.1"/>
</g>
<path d="M135.2 113.9h.9" fill="none" stroke="#000080" stroke-width=".55"/>
<path d="M145.1 70.1v5.8l.1 .7 .5 .8a8.6 8.6 0 0 1 2.9 3.7l.2 1.2 .1 6.6a6.8 6.8 0 0 1-2 4.8l-4 4M128.2 107.2v3.6l-1.4 1.4M133.3 107.2h4.5M137.9 107.2h-.1M126.9 126.4h-.3l-1.5 1.4v6.2l2.6 2.6h6.4l1.3-.2 1.2-.8 3.8-3.9h8.6a6.2 6.2 0 0 1 5.6 3.3l.2 1-.1 4.4-.2 1-.9 1.2h-12.6l-1.5 1.6v7.1l-6.1 6.1" fill="none" stroke="#000080" stroke-width="2.8"/>
<g fill="none" stroke="#000080" stroke-width=".85">
<path d="M129.5 34.2l1 1v1.7l-6.8 6.9v3.3l1.5 1.6M135.3 32.2l-.5-.5h-2.9l-2.1 2.2h-.6M141.7 37.9l-1.7 1.7v1.3l5.7 5.7v2.7l-7.9 8M142.4 32.2h-.3v2.9l-3.3 3.2v8.3l-5.5 5.5h-1.6l-5-5M143.5 32.2h3l1.9 2M122.3 59.7l.1 .1M131.6 57.2l6.2 .1M137.8 57.3l1.1 1.1v11.7M122.4 66.7h1.5M132.7 70.1v4.9l.5 .5M134.4 63.6v.1M180.8 72l-.3 .4a5.1 5.1 0 0 0-.7 3.3v5.4l-.3 .3"/>
<path d="M168.6 80.3h4.4l1.1 1.1M179.5 81.4h.1M99.9 115.8v1.7l-1.8 1.9M98.1 124.8v5.7"/>
</g>
<g fill="none" stroke="#000080" stroke-width=".7">
<path d="M131.6 57.2l-1.3-1.2h-.5l-1.5 1.5M156.9 54.6l-2.8-2.9h-8.7l-5.2 5.3v6.6l1.5 1.5M138.9 70.1l-.1 .1M143.2 63.6l2.6 2.6h2.5l1.8 1.7v1.9l1.5 1.6v20a7.8 7.8 0 0 1-3 5.9 4.3 4.3 0 0 0-.9 2.7v7.9l.1 .8a4.7 4.7 0 0 0 1.7 2.1 6.8 6.8 0 0 1 2.1 4.9v3.9l.4 1.3 .6 .8 4.8 4.8a6.9 6.9 0 0 1 2 4.9v11.3a5.3 5.3 0 0 1-6.3 5.3l-1.3 .3a6.8 6.8 0 0 0-2.5 2.2l-.3 .6-.1 .6v7.3a4.5 4.5 0 0 1-1.5 3.1l-.2 .7v3.8a5.6 5.6 0 0 0 1.5 3.7v19.2a3.4 3.4 0 0 1-2.9 3.7h-4.5l-.5-.2-.2-.5v-3M151.4 69.1l1.2 1.1v21.2a8.6 8.6 0 0 1-3.2 6.5l-.5 .8-.2 .9v8.6a3.5 3.5 0 0 0 1.5 2 7.8 7.8 0 0 1 2.3 5.5v3.9l.3 .8 .5 .6 4.8 4.8a7.8 7.8 0 0 1 2.3 5.6v11.3a6.2 6.2 0 0 1-7.3 6.3l-.7 .1a4.9 4.9 0 0 0-2.2 1.8l-.4 .8v7.3a5.5 5.5 0 0 1-1.6 3.7l-.1 3.9a4.7 4.7 0 0 0 1.5 3.2l.1 .7v19a4.4 4.4 0 0 1-3.9 4.7h-4.5a2.78 2.78 0 0 1-2.3-2.5l-.2-2.2M87.6 98.1l2.6 2.6M179.5 89.8v.1M49.8 108.2v2.4M95.4 110h1l2.6 2.6M95.6 103.1h3.1M99.1 106.5h-.3l.4 .2 2.9 2.9M121.1 114.6h7.7l.7 .7v2.2l1.2 1.2h2.3"/>
<path d="M128 122.3h5"/>
</g>
<path d="M134.4 39.5l1.8 1.7v3.2M120.4 43l.7 .7v3.2M156.3 42v2.8l-3.9 3.9v.2M134.4 63.7v.1M180.8 72l.8-.6 1.4-.5h3.5a3.1 3.1 0 0 1 2.8 3.2l-.1 4-.5 1.1v4.8a4.6 4.6 0 0 0 1.8 2.6l1 1.7 .4 1.3 .1 1.4v4.3l-.1 .6-.3 .6-1.6 1.6M179.5 89.8l1.4 1.4M179.5 86.8v4.6l.6 .6M87.6 108a6 6 0 0 0-2.8 4.7l.1 3.3 .7 1.1 .1 .6v8.5a6.8 6.8 0 0 0 2 4.9 6.7 6.7 0 0 0 3.7 2.7l6.3 .1M96.7 114.9l1.4 1.5M97.5 114.2l.6 .6v5.5M120.8 119.5a4 4 0 0 1-.6 6 1.58 1.58 0 0 0 .5 2.7l.6 .2h2.7l1.1-.6M120.8 113.2v1.1" fill="none" stroke="#000080" stroke-width=".57"/>
<path d="M142.9 97.7l.1 13.2" fill="none" stroke="#000080" stroke-width="2.2"/>
<path d="M129.2 33.9l1.5 1.4M135.3 32.2l-.4 .3M141.7 37.4v.5" fill="none" stroke="#000080" stroke-width=".36"/>
<circle cx="134.1" cy="13.1" r=".49" fill="#008000" stroke="#008000" stroke-width=".2"/>
<circle cx="134.1" cy="13.1" r=".28" fill="#fff" stroke="#000" stroke-width=".2"/>
<circle cx="114.4" cy="100.2" r=".49" fill="#008000" stroke="#008000" stroke-width=".2"/>
<circle cx="114.4" cy="100.2" r=".28" fill="#fff" stroke="#000" stroke-width=".2"/>
<circle cx="116.8" cy="100.5" r=".49" fill="#008000" stroke="#008000" stroke-width=".2"/>
<circle cx="116.8" cy="100.5" r=".28" fill="#fff" stroke="#000" stroke-width=".2"/>
<circle cx="141.5" cy="11.1" r=".49" fill="#008000" stroke="#008000" stroke-width=".2"/>
<circle cx="141.5" cy="11.1" r=".28" fill="#fff" stroke="#000" stroke-width=".2"/>
<circle cx="52.9" cy="70.3" r=".49" fill="#008000" stroke="#008000" stroke-width=".2"/>
<circle cx="52.9" cy="70.3" r=".28" fill="#fff" stroke="#000" stroke-width=".2"/>
<circle cx="71.3" cy="62.4" r=".49" fill="#008000" stroke="#008000" stroke-width=".2"/>
<circle cx="71.3" cy="62.4" r=".28" fill="#fff" stroke="#000" stroke-width=".2"/>
<circle cx="58.9" cy="57.1" r=".49" fill="#008000" stroke="#008000" stroke-width=".2"/>
<circle cx="58.9" cy="57.1" r=".28" fill="#fff" stroke="#000" stroke-width=".2"/>
<circle cx="87.4" cy="163.1" r=".49" fill="#008000" stroke="#008000" stroke-width=".2"/>
<circle cx="87.4" cy="163.1" r=".28" fill="#fff" stroke="#000" stroke-width=".2"/>
<circle cx="79.9" cy="170.2" r=".49" fill="#008000" stroke="#008000" stroke-width=".2"/>
<circle cx="79.9" cy="170.2" r=".28" fill="#fff" stroke="#000" stroke-width=".2"/>
<circle cx="78.1" cy="172.2" r=".49" fill="#008000" stroke="#008000" stroke-width=".2"/>
<circle cx="78.1" cy="172.2" r=".28" fill="#fff" stroke="#000" stroke-width=".2"/>
<circle cx="121.5" cy="38.6" r=".49" fill="#008000" stroke="#008000" stroke-width=".2"/>
<circle cx="121.5" cy="38.6" r=".28" fill="#fff" stroke="#000" stroke-width=".2"/>
<circle cx="122.6" cy="48.4" r=".49" fill="#008000" stroke="#008000" stroke-width=".2"/>
<circle cx="122.6" cy="48.4" r=".28" fill="#fff" stroke="#000" stroke-width=".2"/>
<circle cx="114.8" cy="13.7" r=".49" fill="#008000" stroke="#008000" stroke-width=".2"/>
<circle cx="114.8" cy="13.7" r=".28" fill="#fff" stroke="#000" stroke-width=".2"/>
<circle cx="76.3" cy="126.5" r=".49" fill="#008000" stroke="#008000" stroke-width=".2"/>
<circle cx="76.3" cy="126.5" r=".28" fill="#fff" stroke="#000" stroke-width=".2"/>
<circle cx="95.5" cy="117.3" r=".49" fill="#008000" stroke="#008000" stroke-width=".2"/>
<circle cx="95.5" cy="117.3" r=".28" fill="#fff" stroke="#000" stroke-width=".2"/>
<circle cx="95.9" cy="140.5" r=".49" fill="#008000" stroke="#008000" stroke-width=".2"/>
<circle cx="95.9" cy="140.5" r=".28" fill="#fff" stroke="#000" stroke-width=".2"/>
<circle cx="89.5" cy="121.4" r=".49" fill="#008000" stroke="#008000" stroke-width=".2"/>
<circle cx="89.5" cy="121.4" r=".28" fill="#fff" stroke="#000" stroke-width=".2"/>
<circle cx="52.2" cy="135.8" r=".49" fill="#008000" stroke="#008000" stroke-width=".2"/>
<circle cx="52.2" cy="135.8" r=".28" fill="#fff" stroke="#000" stroke-width=".2"/>
<circle cx="90.9" cy="124.7" r=".49" fill="#008000" stroke="#008000" stroke-width=".2"/>
<circle cx="90.9" cy="124.7" r=".28" fill="#fff" stroke="#000" stroke-width=".2"/>
<circle cx="117.2" cy="112.7" r=".49" fill="#008000" stroke="#008000" stroke-width=".2"/>
<circle cx="117.2" cy="112.7" r=".28" fill="#fff" stroke="#000" stroke-width=".2"/>
<circle cx="122.7" cy="14.2" r=".49" fill="#008000" stroke="#008000" stroke-width=".2"/>
<circle cx="122.7" cy="14.2" r=".28" fill="#fff" stroke="#000" stroke-width=".2"/>
<circle cx="123.7" cy="10.5" r=".49" fill="#008000" stroke="#008000" stroke-width=".2"/>
<circle cx="123.7" cy="10.5" r=".28" fill="#fff" stroke="#000" stroke-width=".2"/>
<circle cx="49.7" cy="88.5" r=".49" fill="#008000" stroke="#008000" stroke-width=".2"/>
<circle cx="49.7" cy="88.5" r=".28" fill="#fff" stroke="#000" stroke-width=".2"/>
<circle cx="96.1" cy="182.6" r=".49" fill="#008000" stroke="#008000" stroke-width=".2"/>
<circle cx="96.1" cy="182.6" r=".28" fill="#fff" stroke="#000" stroke-width=".2"/>
<circle cx="94.3" cy="185.8" r=".49" fill="#008000" stroke="#008000" stroke-width=".2"/>
<circle cx="94.3" cy="185.8" r=".28" fill="#fff" stroke="#000" stroke-width=".2"/>
<circle cx="78.8" cy="51.8" r=".49" fill="#008000" stroke="#008000" stroke-width=".2"/>
<circle cx="78.8" cy="51.8" r=".28" fill="#fff" stroke="#000" stroke-width=".2"/>
<circle cx="68.1" cy="41" r=".49" fill="#008000" stroke="#008000" stroke-width=".2"/>
<circle cx="68.1" cy="41" r=".28" fill="#fff" stroke="#000" stroke-width=".2"/>
<circle cx="78.6" cy="154.2" r=".49" fill="#008000" stroke="#008000" stroke-width=".2"/>
<circle cx="78.6" cy="154.2" r=".28" fill="#fff" stroke="#000" stroke-width=".2"/>
<circle cx="68.1" cy="165.1" r=".49" fill="#008000" stroke="#008000" stroke-width=".2"/>
<circle cx="68.1" cy="165.1" r=".28" fill="#fff" stroke="#000" stroke-width=".2"/>
<circle cx="87.8" cy="147.5" r=".49" fill="#008000" stroke="#008000" stroke-width=".2"/>
<circle cx="87.8" cy="147.5" r=".28" fill="#fff" stroke="#000" stroke-width=".2"/>
<circle cx="86.6" cy="57.1" r=".49" fill="#008000" stroke="#008000" stroke-width=".2"/>
<circle cx="86.6" cy="57.1" r=".28" fill="#fff" stroke="#000" stroke-width=".2"/>
<circle cx="100.4" cy="47.4" r=".49" fill="#008000" stroke="#008000" stroke-width=".2"/>
<circle cx="100.4" cy="47.4" r=".28" fill="#fff" stroke="#000" stroke-width=".2"/>
<circle cx="99.2" cy="45.9" r=".49" fill="#008000" stroke="#008000" stroke-width=".2"/>
<circle cx="99.2" cy="45.9" r=".28" fill="#fff" stroke="#000" stroke-width=".2"/>
<circle cx="45.8" cy="87.9" r=".49" fill="#008000" stroke="#008000" stroke-width=".2"/>
<circle cx="45.8" cy="87.9" r=".28" fill="#fff" stroke="#000" stroke-width=".2"/>
<circle cx="141.2" cy="47.3" r=".49" fill="#008000" stroke="#008000" stroke-width=".2"/>
<circle cx="141.2" cy="47.3" r=".28" fill="#fff" stroke="#000" stroke-width=".2"/>
<circle cx="140.3" cy="9.2" r=".49" fill="#008000" stroke="#008000" stroke-width=".2"/>
<circle cx="140.3" cy="9.2" r=".28" fill="#fff" stroke="#000" stroke-width=".2"/>
<circle cx="100.6" cy="127.9" r=".49" fill="#008000" stroke="#008000" stroke-width=".2"/>
<circle cx="100.6" cy="127.9" r=".28" fill="#fff" stroke="#000" stroke-width=".2"/>
<circle cx="89.1" cy="130.7" r=".49" fill="#008000" stroke="#008000" stroke-width=".2"/>
<circle cx="89.1" cy="130.7" r=".28" fill="#fff" stroke="#000" stroke-width=".2"/>
<circle cx="57.7" cy="150.4" r=".49" fill="#008000" stroke="#008000" stroke-width=".2"/>
<circle cx="57.7" cy="150.4" r=".28" fill="#fff" stroke="#000" stroke-width=".2"/>
<circle cx="123.9" cy="121.4" r=".49" fill="#008000" stroke="#008000" stroke-width=".2"/>
<circle cx="123.9" cy="121.4" r=".28" fill="#fff" stroke="#000" stroke-width=".2"/>
<circle cx="80.6" cy="176.6" r=".49" fill="#008000" stroke="#008000" stroke-width=".2"/>
<circle cx="80.6" cy="176.6" r=".28" fill="#fff" stroke="#000" stroke-width=".2"/>
<circle cx="107.7" cy="88.4" r=".49" fill="#008000" stroke="#008000" stroke-width=".2"/>
<circle cx="107.7" cy="88.4" r=".28" fill="#fff" stroke="#000" stroke-width=".2"/>
<circle cx="122" cy="95" r=".49" fill="#008000" stroke="#008000" stroke-width=".2"/>
<circle cx="122" cy="95" r=".28" fill="#fff" stroke="#000" stroke-width=".2"/>
<circle cx="123.8" cy="112.9" r=".49" fill="#008000" stroke="#008000" stroke-width=".2"/>
<circle cx="123.8" cy="112.9" r=".28" fill="#fff" stroke="#000" stroke-width=".2"/>
<circle cx="109.8" cy="17.6" r=".49" fill="#008000" stroke="#008000" stroke-width=".2"/>
<circle cx="109.8" cy="17.6" r=".28" fill="#fff" stroke="#000" stroke-width=".2"/>
<circle cx="107.9" cy="12.1" r=".49" fill="#008000" stroke="#008000" stroke-width=".2"/>
<circle cx="107.9" cy="12.1" r=".28" fill="#fff" stroke="#000" stroke-width=".2"/>
<circle cx="48.5" cy="105.8" r=".49" fill="#008000" stroke="#008000" stroke-width=".2"/>
<circle cx="48.5" cy="105.8" r=".28" fill="#fff" stroke="#000" stroke-width=".2"/>
<circle cx="105.3" cy="187" r=".49" fill="#008000" stroke="#008000" stroke-width=".2"/>
<circle cx="105.3" cy="187" r=".28" fill="#fff" stroke="#000" stroke-width=".2"/>
<circle cx="103.3" cy="192.3" r=".49" fill="#008000" stroke="#008000" stroke-width=".2"/>
<circle cx="103.3" cy="192.3" r=".28" fill="#fff" stroke="#000" stroke-width=".2"/>
<circle cx="86.1" cy="44.2" r=".49" fill="#008000" stroke="#008000" stroke-width=".2"/>
<circle cx="86.1" cy="44.2" r=".28" fill="#fff" stroke="#000" stroke-width=".2"/>
<circle cx="91.2" cy="54.8" r=".49" fill="#008000" stroke="#008000" stroke-width=".2"/>
<circle cx="91.2" cy="54.8" r=".28" fill="#fff" stroke="#000" stroke-width=".2"/>
<circle cx="114.8" cy="78.6" r=".49" fill="#008000" stroke="#008000" stroke-width=".2"/>
<circle cx="114.8" cy="78.6" r=".28" fill="#fff" stroke="#000" stroke-width=".2"/>
<circle cx="72.9" cy="33.1" r=".49" fill="#008000" stroke="#008000" stroke-width=".2"/>
<circle cx="72.9" cy="33.1" r=".28" fill="#fff" stroke="#000" stroke-width=".2"/>
<circle cx="72.2" cy="145.5" r=".49" fill="#008000" stroke="#008000" stroke-width=".2"/>
<circle cx="72.2" cy="145.5" r=".28" fill="#fff" stroke="#000" stroke-width=".2"/>
<circle cx="58.9" cy="156.4" r=".49" fill="#008000" stroke="#008000" stroke-width=".2"/>
<circle cx="58.9" cy="156.4" r=".28" fill="#fff" stroke="#000" stroke-width=".2"/>
<circle cx="42.2" cy="106" r=".49" fill="#008000" stroke="#008000" stroke-width=".2"/>
<circle cx="42.2" cy="106" r=".28" fill="#fff" stroke="#000" stroke-width=".2"/>
<circle cx="95" cy="154.8" r=".49" fill="#008000" stroke="#008000" stroke-width=".2"/>
<circle cx="95" cy="154.8" r=".28" fill="#fff" stroke="#000" stroke-width=".2"/>
<circle cx="109" cy="137.6" r=".49" fill="#008000" stroke="#008000" stroke-width=".2"/>
<circle cx="109" cy="137.6" r=".28" fill="#fff" stroke="#000" stroke-width=".2"/>
<circle cx="73" cy="173" r=".49" fill="#008000" stroke="#008000" stroke-width=".2"/>
<circle cx="73" cy="173" r=".28" fill="#fff" stroke="#000" stroke-width=".2"/>
<circle cx="98.6" cy="145.5" r=".49" fill="#008000" stroke="#008000" stroke-width=".2"/>
<circle cx="98.6" cy="145.5" r=".28" fill="#fff" stroke="#000" stroke-width=".2"/>
<circle cx="100.1" cy="146.9" r=".49" fill="#008000" stroke="#008000" stroke-width=".2"/>
<circle cx="100.1" cy="146.9" r=".28" fill="#fff" stroke="#000" stroke-width=".2"/>
<circle cx="84.1" cy="118.1" r=".49" fill="#008000" stroke="#008000" stroke-width=".2"/>
<circle cx="84.1" cy="118.1" r=".28" fill="#fff" stroke="#000" stroke-width=".2"/>
<circle cx="46.1" cy="128.3" r=".49" fill="#008000" stroke="#008000" stroke-width=".2"/>
<circle cx="46.1" cy="128.3" r=".28" fill="#fff" stroke="#000" stroke-width=".2"/>
<circle cx="138.8" cy="53.3" r=".49" fill="#008000" stroke="#008000" stroke-width=".2"/>
<circle cx="138.8" cy="53.3" r=".28" fill="#fff" stroke="#000" stroke-width=".2"/>
<circle cx="112.8" cy="133.3" r=".49" fill="#008000" stroke="#008000" stroke-width=".2"/>
<circle cx="112.8" cy="133.3" r=".28" fill="#fff" stroke="#000" stroke-width=".2"/>
<circle cx="128.8" cy="141.8" r=".49" fill="#008000" stroke="#008000" stroke-width=".2"/>
<circle cx="128.8" cy="141.8" r=".28" fill="#fff" stroke="#000" stroke-width=".2"/>
<circle cx="133.3" cy="125.2" r=".49" fill="#008000" stroke="#008000" stroke-width=".2"/>
<circle cx="133.3" cy="125.2" r=".28" fill="#fff" stroke="#000" stroke-width=".2"/>
<circle cx="138.8" cy="77.5" r=".49" fill="#008000" stroke="#008000" stroke-width=".2"/>
<circle cx="138.8" cy="77.5" r=".28" fill="#fff" stroke="#000" stroke-width=".2"/>
<circle cx="120.3" cy="84.8" r=".49" fill="#008000" stroke="#008000" stroke-width=".2"/>
<circle cx="120.3" cy="84.8" r=".28" fill="#fff" stroke="#000" stroke-width=".2"/>
<circle cx="90" cy="116.5" r=".49" fill="#008000" stroke="#008000" stroke-width=".2"/>
<circle cx="90" cy="116.5" r=".28" fill="#fff" stroke="#000" stroke-width=".2"/>
<circle cx="98.9" cy="22.1" r=".49" fill="#008000" stroke="#008000" stroke-width=".2"/>
<circle cx="98.9" cy="22.1" r=".28" fill="#fff" stroke="#000" stroke-width=".2"/>
<circle cx="100.7" cy="25.7" r=".49" fill="#008000" stroke="#008000" stroke-width=".2"/>
<circle cx="100.7" cy="25.7" r=".28" fill="#fff" stroke="#000" stroke-width=".2"/>
<circle cx="49.8" cy="117.6" r=".49" fill="#008000" stroke="#008000" stroke-width=".2"/>
<circle cx="49.8" cy="117.6" r=".28" fill="#fff" stroke="#000" stroke-width=".2"/>
<circle cx="53.7" cy="116.8" r=".49" fill="#008000" stroke="#008000" stroke-width=".2"/>
<circle cx="53.7" cy="116.8" r=".28" fill="#fff" stroke="#000" stroke-width=".2"/>
<circle cx="121.1" cy="191.6" r=".49" fill="#008000" stroke="#008000" stroke-width=".2"/>
<circle cx="121.1" cy="191.6" r=".28" fill="#fff" stroke="#000" stroke-width=".2"/>
<circle cx="121.9" cy="187.6" r=".49" fill="#008000" stroke="#008000" stroke-width=".2"/>
<circle cx="121.9" cy="187.6" r=".28" fill="#fff" stroke="#000" stroke-width=".2"/>
<circle cx="97.3" cy="35.8" r=".49" fill="#008000" stroke="#008000" stroke-width=".2"/>
<circle cx="97.3" cy="35.8" r=".28" fill="#fff" stroke="#000" stroke-width=".2"/>
<circle cx="93.6" cy="29.9" r=".49" fill="#008000" stroke="#008000" stroke-width=".2"/>
<circle cx="93.6" cy="29.9" r=".28" fill="#fff" stroke="#000" stroke-width=".2"/>
<circle cx="66.2" cy="134.5" r=".49" fill="#008000" stroke="#008000" stroke-width=".2"/>
<circle cx="66.2" cy="134.5" r=".28" fill="#fff" stroke="#000" stroke-width=".2"/>
<circle cx="60.2" cy="138.4" r=".49" fill="#008000" stroke="#008000" stroke-width=".2"/>
<circle cx="60.2" cy="138.4" r=".28" fill="#fff" stroke="#000" stroke-width=".2"/>
<circle cx="83.1" cy="64.5" r=".49" fill="#008000" stroke="#008000" stroke-width=".2"/>
<circle cx="83.1" cy="64.5" r=".28" fill="#fff" stroke="#000" stroke-width=".2"/>
<circle cx="68.8" cy="52.6" r=".49" fill="#008000" stroke="#008000" stroke-width=".2"/>
<circle cx="68.8" cy="52.6" r=".28" fill="#fff" stroke="#000" stroke-width=".2"/>
<circle cx="105.3" cy="161.9" r=".49" fill="#008000" stroke="#008000" stroke-width=".2"/>
<circle cx="105.3" cy="161.9" r=".28" fill="#fff" stroke="#000" stroke-width=".2"/>
<circle cx="118.2" cy="143.7" r=".49" fill="#008000" stroke="#008000" stroke-width=".2"/>
<circle cx="118.2" cy="143.7" r=".28" fill="#fff" stroke="#000" stroke-width=".2"/>
<circle cx="108.7" cy="163.6" r=".49" fill="#008000" stroke="#008000" stroke-width=".2"/>
<circle cx="108.7" cy="163.6" r=".28" fill="#fff" stroke="#000" stroke-width=".2"/>
<circle cx="100.5" cy="180.4" r=".49" fill="#008000" stroke="#008000" stroke-width=".2"/>
<circle cx="100.5" cy="180.4" r=".28" fill="#fff" stroke="#000" stroke-width=".2"/>
<circle cx="82" cy="105.7" r=".49" fill="#008000" stroke="#008000" stroke-width=".2"/>
<circle cx="82" cy="105.7" r=".28" fill="#fff" stroke="#000" stroke-width=".2"/>
<circle cx="52.7" cy="105.7" r=".49" fill="#008000" stroke="#008000" stroke-width=".2"/>
<circle cx="52.7" cy="105.7" r=".28" fill="#fff" stroke="#000" stroke-width=".2"/>
<circle cx="124.1" cy="61.4" r=".49" fill="#008000" stroke="#008000" stroke-width=".2"/>
<circle cx="124.1" cy="61.4" r=".28" fill="#fff" stroke="#000" stroke-width=".2"/>
<circle cx="111" cy="21.4" r=".49" fill="#008000" stroke="#008000" stroke-width=".2"/>
<circle cx="111" cy="21.4" r=".28" fill="#fff" stroke="#000" stroke-width=".2"/>
<circle cx="124.7" cy="72" r=".49" fill="#008000" stroke="#008000" stroke-width=".2"/>
<circle cx="124.7" cy="72" r=".28" fill="#fff" stroke="#000" stroke-width=".2"/>
<circle cx="119.9" cy="61.7" r=".49" fill="#008000" stroke="#008000" stroke-width=".2"/>
<circle cx="119.9" cy="61.7" r=".28" fill="#fff" stroke="#000" stroke-width=".2"/>
<circle cx="132.5" cy="110" r=".49" fill="#008000" stroke="#008000" stroke-width=".2"/>
<circle cx="132.5" cy="110" r=".28" fill="#fff" stroke="#000" stroke-width=".2"/>
<circle cx="100.8" cy="137.8" r=".49" fill="#008000" stroke="#008000" stroke-width=".2"/>
<circle cx="100.8" cy="137.8" r=".28" fill="#fff" stroke="#000" stroke-width=".2"/>
<circle cx="113.2" cy="147.8" r=".49" fill="#008000" stroke="#008000" stroke-width=".2"/>
<circle cx="113.2" cy="147.8" r=".28" fill="#fff" stroke="#000" stroke-width=".2"/>
<circle cx="90.1" cy="120.2" r=".49" fill="#008000" stroke="#008000" stroke-width=".2"/>
<circle cx="90.1" cy="120.2" r=".28" fill="#fff" stroke="#000" stroke-width=".2"/>
<circle cx="57.7" cy="132" r=".49" fill="#008000" stroke="#008000" stroke-width=".2"/>
<circle cx="57.7" cy="132" r=".28" fill="#fff" stroke="#000" stroke-width=".2"/>
<circle cx="86.1" cy="29.8" r=".49" fill="#008000" stroke="#008000" stroke-width=".2"/>
<circle cx="86.1" cy="29.8" r=".28" fill="#fff" stroke="#000" stroke-width=".2"/>
<circle cx="88.9" cy="34.5" r=".49" fill="#008000" stroke="#008000" stroke-width=".2"/>
<circle cx="88.9" cy="34.5" r=".28" fill="#fff" stroke="#000" stroke-width=".2"/>
<circle cx="50.9" cy="123.8" r=".49" fill="#008000" stroke="#008000" stroke-width=".2"/>
<circle cx="50.9" cy="123.8" r=".28" fill="#fff" stroke="#000" stroke-width=".2"/>
<circle cx="56.3" cy="122.6" r=".49" fill="#008000" stroke="#008000" stroke-width=".2"/>
<circle cx="56.3" cy="122.6" r=".28" fill="#fff" stroke="#000" stroke-width=".2"/>
<circle cx="129.7" cy="193" r=".49" fill="#008000" stroke="#008000" stroke-width=".2"/>
<circle cx="129.7" cy="193" r=".28" fill="#fff" stroke="#000" stroke-width=".2"/>
<circle cx="130.2" cy="187.5" r=".49" fill="#008000" stroke="#008000" stroke-width=".2"/>
<circle cx="130.2" cy="187.5" r=".28" fill="#fff" stroke="#000" stroke-width=".2"/>
<circle cx="107.4" cy="30.5" r=".49" fill="#008000" stroke="#008000" stroke-width=".2"/>
<circle cx="107.4" cy="30.5" r=".28" fill="#fff" stroke="#000" stroke-width=".2"/>
<circle cx="104.5" cy="25.5" r=".49" fill="#008000" stroke="#008000" stroke-width=".2"/>
<circle cx="104.5" cy="25.5" r=".28" fill="#fff" stroke="#000" stroke-width=".2"/>
<circle cx="62.1" cy="122" r=".49" fill="#008000" stroke="#008000" stroke-width=".2"/>
<circle cx="62.1" cy="122" r=".28" fill="#fff" stroke="#000" stroke-width=".2"/>
<circle cx="76.7" cy="75.9" r=".49" fill="#008000" stroke="#008000" stroke-width=".2"/>
<circle cx="76.7" cy="75.9" r=".28" fill="#fff" stroke="#000" stroke-width=".2"/>
<circle cx="62.8" cy="65.5" r=".49" fill="#008000" stroke="#008000" stroke-width=".2"/>
<circle cx="62.8" cy="65.5" r=".28" fill="#fff" stroke="#000" stroke-width=".2"/>
<circle cx="119" cy="167.9" r=".49" fill="#008000" stroke="#008000" stroke-width=".2"/>
<circle cx="119" cy="167.9" r=".28" fill="#fff" stroke="#000" stroke-width=".2"/>
<circle cx="114" cy="184.2" r=".49" fill="#008000" stroke="#008000" stroke-width=".2"/>
<circle cx="114" cy="184.2" r=".28" fill="#fff" stroke="#000" stroke-width=".2"/>
<circle cx="82.8" cy="93.6" r=".49" fill="#008000" stroke="#008000" stroke-width=".2"/>
<circle cx="82.8" cy="93.6" r=".28" fill="#fff" stroke="#000" stroke-width=".2"/>
<circle cx="55.1" cy="89.5" r=".49" fill="#008000" stroke="#008000" stroke-width=".2"/>
<circle cx="55.1" cy="89.5" r=".28" fill="#fff" stroke="#000" stroke-width=".2"/>
<circle cx="118.2" cy="72.1" r=".49" fill="#008000" stroke="#008000" stroke-width=".2"/>
<circle cx="118.2" cy="72.1" r=".28" fill="#fff" stroke="#000" stroke-width=".2"/>
<circle cx="113.6" cy="65.1" r=".49" fill="#008000" stroke="#008000" stroke-width=".2"/>
<circle cx="113.6" cy="65.1" r=".28" fill="#fff" stroke="#000" stroke-width=".2"/>
<circle cx="137.6" cy="65.9" r=".49" fill="#008000" stroke="#008000" stroke-width=".2"/>
<circle cx="137.6" cy="65.9" r=".28" fill="#fff" stroke="#000" stroke-width=".2"/>
<circle cx="93.2" cy="31.6" r=".49" fill="#008000" stroke="#008000" stroke-width=".2"/>
<circle cx="93.2" cy="31.6" r=".28" fill="#fff" stroke="#000" stroke-width=".2"/>
<circle cx="134" cy="145.6" r=".49" fill="#008000" stroke="#008000" stroke-width=".2"/>
<circle cx="134" cy="145.6" r=".28" fill="#fff" stroke="#000" stroke-width=".2"/>
<circle cx="127" cy="102.7" r=".49" fill="#008000" stroke="#008000" stroke-width=".2"/>
<circle cx="127" cy="102.7" r=".28" fill="#fff" stroke="#000" stroke-width=".2"/>
<circle cx="55.1" cy="116.6" r=".49" fill="#008000" stroke="#008000" stroke-width=".2"/>
<circle cx="55.1" cy="116.6" r=".28" fill="#fff" stroke="#000" stroke-width=".2"/>
<circle cx="89.5" cy="114" r=".49" fill="#008000" stroke="#008000" stroke-width=".2"/>
<circle cx="89.5" cy="114" r=".28" fill="#fff" stroke="#000" stroke-width=".2"/>
<circle cx="79.3" cy="35.2" r=".49" fill="#008000" stroke="#008000" stroke-width=".2"/>
<circle cx="79.3" cy="35.2" r=".28" fill="#fff" stroke="#000" stroke-width=".2"/>
<circle cx="85.5" cy="42.2" r=".49" fill="#008000" stroke="#008000" stroke-width=".2"/>
<circle cx="85.5" cy="42.2" r=".28" fill="#fff" stroke="#000" stroke-width=".2"/>
<circle cx="55.5" cy="138" r=".49" fill="#008000" stroke="#008000" stroke-width=".2"/>
<circle cx="55.5" cy="138" r=".28" fill="#fff" stroke="#000" stroke-width=".2"/>
<circle cx="64.1" cy="134.5" r=".49" fill="#008000" stroke="#008000" stroke-width=".2"/>
<circle cx="64.1" cy="134.5" r=".28" fill="#fff" stroke="#000" stroke-width=".2"/>
<circle cx="119.4" cy="26.6" r=".49" fill="#008000" stroke="#008000" stroke-width=".2"/>
<circle cx="119.4" cy="26.6" r=".28" fill="#fff" stroke="#000" stroke-width=".2"/>
<circle cx="120.2" cy="23.8" r=".49" fill="#008000" stroke="#008000" stroke-width=".2"/>
<circle cx="120.2" cy="23.8" r=".28" fill="#fff" stroke="#000" stroke-width=".2"/>
<circle cx="60.2" cy="110.8" r=".49" fill="#008000" stroke="#008000" stroke-width=".2"/>
<circle cx="60.2" cy="110.8" r=".28" fill="#fff" stroke="#000" stroke-width=".2"/>
<circle cx="57.3" cy="111.1" r=".49" fill="#008000" stroke="#008000" stroke-width=".2"/>
<circle cx="57.3" cy="111.1" r=".28" fill="#fff" stroke="#000" stroke-width=".2"/>
<circle cx="127.3" cy="182.9" r=".49" fill="#008000" stroke="#008000" stroke-width=".2"/>
<circle cx="127.3" cy="182.9" r=".28" fill="#fff" stroke="#000" stroke-width=".2"/>
<circle cx="72.5" cy="89.7" r=".49" fill="#008000" stroke="#008000" stroke-width=".2"/>
<circle cx="72.5" cy="89.7" r=".28" fill="#fff" stroke="#000" stroke-width=".2"/>
<circle cx="58.8" cy="84.2" r=".49" fill="#008000" stroke="#008000" stroke-width=".2"/>
<circle cx="58.8" cy="84.2" r=".28" fill="#fff" stroke="#000" stroke-width=".2"/>
<circle cx="81.2" cy="91.4" r=".49" fill="#008000" stroke="#008000" stroke-width=".2"/>
<circle cx="81.2" cy="91.4" r=".28" fill="#fff" stroke="#000" stroke-width=".2"/>
<circle cx="85.9" cy="82.4" r=".49" fill="#008000" stroke="#008000" stroke-width=".2"/>
<circle cx="85.9" cy="82.4" r=".28" fill="#fff" stroke="#000" stroke-width=".2"/>
<circle cx="84" cy="81.9" r=".49" fill="#008000" stroke="#008000" stroke-width=".2"/>
<circle cx="84" cy="81.9" r=".28" fill="#fff" stroke="#000" stroke-width=".2"/>
<circle cx="105" cy="72.8" r=".49" fill="#008000" stroke="#008000" stroke-width=".2"/>
<circle cx="105" cy="72.8" r=".28" fill="#fff" stroke="#000" stroke-width=".2"/>
<circle cx="80.4" cy="44.9" r=".49" fill="#008000" stroke="#008000" stroke-width=".2"/>
<circle cx="80.4" cy="44.9" r=".28" fill="#fff" stroke="#000" stroke-width=".2"/>
<circle cx="141.5" cy="91.2" r=".49" fill="#008000" stroke="#008000" stroke-width=".2"/>
<circle cx="141.5" cy="91.2" r=".28" fill="#fff" stroke="#000" stroke-width=".2"/>
<circle cx="135.7" cy="91.5" r=".49" fill="#008000" stroke="#008000" stroke-width=".2"/>
<circle cx="135.7" cy="91.5" r=".28" fill="#fff" stroke="#000" stroke-width=".2"/>
<circle cx="132.7" cy="92.9" r=".49" fill="#008000" stroke="#008000" stroke-width=".2"/>
<circle cx="132.7" cy="92.9" r=".28" fill="#fff" stroke="#000" stroke-width=".2"/>
<circle cx="98" cy="32.7" r=".49" fill="#008000" stroke="#008000" stroke-width=".2"/>
<circle cx="98" cy="32.7" r=".28" fill="#fff" stroke="#000" stroke-width=".2"/>
<circle cx="122.8" cy="183" r=".49" fill="#008000" stroke="#008000" stroke-width=".2"/>
<circle cx="122.8" cy="183" r=".28" fill="#fff" stroke="#000" stroke-width=".2"/>
<circle cx="131.6" cy="140.7" r=".49" fill="#008000" stroke="#008000" stroke-width=".2"/>
<circle cx="131.6" cy="140.7" r=".28" fill="#fff" stroke="#000" stroke-width=".2"/>
<circle cx="88.4" cy="114.9" r=".49" fill="#008000" stroke="#008000" stroke-width=".2"/>
<circle cx="88.4" cy="114.9" r=".28" fill="#fff" stroke="#000" stroke-width=".2"/>
<circle cx="59.4" cy="123.8" r=".49" fill="#008000" stroke="#008000" stroke-width=".2"/>
<circle cx="59.4" cy="123.8" r=".28" fill="#fff" stroke="#000" stroke-width=".2"/>
<circle cx="68.9" cy="46" r=".49" fill="#008000" stroke="#008000" stroke-width=".2"/>
<circle cx="68.9" cy="46" r=".28" fill="#fff" stroke="#000" stroke-width=".2"/>
<circle cx="82" cy="56.4" r=".49" fill="#008000" stroke="#008000" stroke-width=".2"/>
<circle cx="82" cy="56.4" r=".28" fill="#fff" stroke="#000" stroke-width=".2"/>
<circle cx="62" cy="150.5" r=".49" fill="#008000" stroke="#008000" stroke-width=".2"/>
<circle cx="62" cy="150.5" r=".28" fill="#fff" stroke="#000" stroke-width=".2"/>
<circle cx="76.2" cy="141.5" r=".49" fill="#008000" stroke="#008000" stroke-width=".2"/>
<circle cx="76.2" cy="141.5" r=".28" fill="#fff" stroke="#000" stroke-width=".2"/>
<circle cx="144" cy="25.1" r=".49" fill="#008000" stroke="#008000" stroke-width=".2"/>
<circle cx="144" cy="25.1" r=".28" fill="#fff" stroke="#000" stroke-width=".2"/>
<circle cx="143.8" cy="29.1" r=".49" fill="#008000" stroke="#008000" stroke-width=".2"/>
<circle cx="143.8" cy="29.1" r=".28" fill="#fff" stroke="#000" stroke-width=".2"/>
<circle cx="59.9" cy="97.8" r=".49" fill="#008000" stroke="#008000" stroke-width=".2"/>
<circle cx="59.9" cy="97.8" r=".28" fill="#fff" stroke="#000" stroke-width=".2"/>
<circle cx="71.2" cy="100.1" r=".49" fill="#008000" stroke="#008000" stroke-width=".2"/>
<circle cx="71.2" cy="100.1" r=".28" fill="#fff" stroke="#000" stroke-width=".2"/>
<circle cx="118.4" cy="179.5" r=".49" fill="#008000" stroke="#008000" stroke-width=".2"/>
<circle cx="118.4" cy="179.5" r=".28" fill="#fff" stroke="#000" stroke-width=".2"/>
<circle cx="119.8" cy="174" r=".49" fill="#008000" stroke="#008000" stroke-width=".2"/>
<circle cx="119.8" cy="174" r=".28" fill="#fff" stroke="#000" stroke-width=".2"/>
<circle cx="92.7" cy="69.9" r=".49" fill="#008000" stroke="#008000" stroke-width=".2"/>
<circle cx="92.7" cy="69.9" r=".28" fill="#fff" stroke="#000" stroke-width=".2"/>
<circle cx="80.4" cy="58.6" r=".49" fill="#008000" stroke="#008000" stroke-width=".2"/>
<circle cx="80.4" cy="58.6" r=".28" fill="#fff" stroke="#000" stroke-width=".2"/>
<circle cx="129.3" cy="159.1" r=".49" fill="#008000" stroke="#008000" stroke-width=".2"/>
<circle cx="129.3" cy="159.1" r=".28" fill="#fff" stroke="#000" stroke-width=".2"/>
<circle cx="126.8" cy="175.6" r=".49" fill="#008000" stroke="#008000" stroke-width=".2"/>
<circle cx="126.8" cy="175.6" r=".28" fill="#fff" stroke="#000" stroke-width=".2"/>
<circle cx="98" cy="82.7" r=".49" fill="#008000" stroke="#008000" stroke-width=".2"/>
<circle cx="98" cy="82.7" r=".28" fill="#fff" stroke="#000" stroke-width=".2"/>
<circle cx="100.2" cy="73.7" r=".49" fill="#008000" stroke="#008000" stroke-width=".2"/>
<circle cx="100.2" cy="73.7" r=".28" fill="#fff" stroke="#000" stroke-width=".2"/>
<circle cx="109.3" cy="80.6" r=".49" fill="#008000" stroke="#008000" stroke-width=".2"/>
<circle cx="109.3" cy="80.6" r=".28" fill="#fff" stroke="#000" stroke-width=".2"/>
<circle cx="116.4" cy="74" r=".49" fill="#008000" stroke="#008000" stroke-width=".2"/>
<circle cx="116.4" cy="74" r=".28" fill="#fff" stroke="#000" stroke-width=".2"/>
<circle cx="124.4" cy="84.5" r=".49" fill="#008000" stroke="#008000" stroke-width=".2"/>
<circle cx="124.4" cy="84.5" r=".28" fill="#fff" stroke="#000" stroke-width=".2"/>
<circle cx="138.7" cy="100.7" r=".49" fill="#008000" stroke="#008000" stroke-width=".2"/>
<circle cx="138.7" cy="100.7" r=".28" fill="#fff" stroke="#000" stroke-width=".2"/>
<circle cx="120.2" cy="131.8" r=".49" fill="#008000" stroke="#008000" stroke-width=".2"/>
<circle cx="120.2" cy="131.8" r=".28" fill="#fff" stroke="#000" stroke-width=".2"/>
<circle cx="99.9" cy="165.4" r=".49" fill="#008000" stroke="#008000" stroke-width=".2"/>
<circle cx="99.9" cy="165.4" r=".28" fill="#fff" stroke="#000" stroke-width=".2"/>
<circle cx="87.4" cy="113.8" r=".49" fill="#008000" stroke="#008000" stroke-width=".2"/>
<circle cx="87.4" cy="113.8" r=".28" fill="#fff" stroke="#000" stroke-width=".2"/>
<circle cx="66.9" cy="118.4" r=".49" fill="#008000" stroke="#008000" stroke-width=".2"/>
<circle cx="66.9" cy="118.4" r=".28" fill="#fff" stroke="#000" stroke-width=".2"/>
<circle cx="65.5" cy="98.2" r=".49" fill="#008000" stroke="#008000" stroke-width=".2"/>
<circle cx="65.5" cy="98.2" r=".28" fill="#fff" stroke="#000" stroke-width=".2"/>
<circle cx="62.1" cy="55.6" r=".49" fill="#008000" stroke="#008000" stroke-width=".2"/>
<circle cx="62.1" cy="55.6" r=".28" fill="#fff" stroke="#000" stroke-width=".2"/>
<circle cx="77.6" cy="65" r=".49" fill="#008000" stroke="#008000" stroke-width=".2"/>
<circle cx="77.6" cy="65" r=".28" fill="#fff" stroke="#000" stroke-width=".2"/>
<circle cx="68.8" cy="160.2" r=".49" fill="#008000" stroke="#008000" stroke-width=".2"/>
<circle cx="68.8" cy="160.2" r=".28" fill="#fff" stroke="#000" stroke-width=".2"/>
<circle cx="62" cy="84.8" r=".49" fill="#008000" stroke="#008000" stroke-width=".2"/>
<circle cx="62" cy="84.8" r=".28" fill="#fff" stroke="#000" stroke-width=".2"/>
<circle cx="68.7" cy="86.4" r=".49" fill="#008000" stroke="#008000" stroke-width=".2"/>
<circle cx="68.7" cy="86.4" r=".28" fill="#fff" stroke="#000" stroke-width=".2"/>
<circle cx="108.9" cy="176.3" r=".49" fill="#008000" stroke="#008000" stroke-width=".2"/>
<circle cx="108.9" cy="176.3" r=".28" fill="#fff" stroke="#000" stroke-width=".2"/>
<circle cx="111.7" cy="169.4" r=".49" fill="#008000" stroke="#008000" stroke-width=".2"/>
<circle cx="111.7" cy="169.4" r=".28" fill="#fff" stroke="#000" stroke-width=".2"/>
<circle cx="138.8" cy="31.4" r=".49" fill="#008000" stroke="#008000" stroke-width=".2"/>
<circle cx="138.8" cy="31.4" r=".28" fill="#fff" stroke="#000" stroke-width=".2"/>
<circle cx="101.4" cy="60.2" r=".49" fill="#008000" stroke="#008000" stroke-width=".2"/>
<circle cx="101.4" cy="60.2" r=".28" fill="#fff" stroke="#000" stroke-width=".2"/>
<circle cx="91.5" cy="48.9" r=".49" fill="#008000" stroke="#008000" stroke-width=".2"/>
<circle cx="91.5" cy="48.9" r=".28" fill="#fff" stroke="#000" stroke-width=".2"/>
<circle cx="117.4" cy="155.7" r=".49" fill="#008000" stroke="#008000" stroke-width=".2"/>
<circle cx="117.4" cy="155.7" r=".28" fill="#fff" stroke="#000" stroke-width=".2"/>
<circle cx="96.2" cy="85.7" r=".49" fill="#008000" stroke="#008000" stroke-width=".2"/>
<circle cx="96.2" cy="85.7" r=".28" fill="#fff" stroke="#000" stroke-width=".2"/>
<circle cx="101.9" cy="88" r=".49" fill="#008000" stroke="#008000" stroke-width=".2"/>
<circle cx="101.9" cy="88" r=".28" fill="#fff" stroke="#000" stroke-width=".2"/>
<circle cx="104.3" cy="83.4" r=".49" fill="#008000" stroke="#008000" stroke-width=".2"/>
<circle cx="104.3" cy="83.4" r=".28" fill="#fff" stroke="#000" stroke-width=".2"/>
<circle cx="118.3" cy="91.5" r=".49" fill="#008000" stroke="#008000" stroke-width=".2"/>
<circle cx="118.3" cy="91.5" r=".28" fill="#fff" stroke="#000" stroke-width=".2"/>
<circle cx="111.4" cy="121.7" r=".49" fill="#008000" stroke="#008000" stroke-width=".2"/>
<circle cx="111.4" cy="121.7" r=".28" fill="#fff" stroke="#000" stroke-width=".2"/>
<circle cx="130.6" cy="120.5" r=".49" fill="#008000" stroke="#008000" stroke-width=".2"/>
<circle cx="130.6" cy="120.5" r=".28" fill="#fff" stroke="#000" stroke-width=".2"/>
<circle cx="124" cy="115.8" r=".49" fill="#008000" stroke="#008000" stroke-width=".2"/>
<circle cx="124" cy="115.8" r=".28" fill="#fff" stroke="#000" stroke-width=".2"/>
<circle cx="71.6" cy="111.7" r=".49" fill="#008000" stroke="#008000" stroke-width=".2"/>
<circle cx="71.6" cy="111.7" r=".28" fill="#fff" stroke="#000" stroke-width=".2"/>
<circle cx="67.5" cy="110" r=".49" fill="#008000" stroke="#008000" stroke-width=".2"/>
<circle cx="67.5" cy="110" r=".28" fill="#fff" stroke="#000" stroke-width=".2"/>
<circle cx="87.9" cy="116.1" r=".49" fill="#008000" stroke="#008000" stroke-width=".2"/>
<circle cx="87.9" cy="116.1" r=".28" fill="#fff" stroke="#000" stroke-width=".2"/>
<circle cx="69.2" cy="120.8" r=".49" fill="#008000" stroke="#008000" stroke-width=".2"/>
<circle cx="69.2" cy="120.8" r=".28" fill="#fff" stroke="#000" stroke-width=".2"/>
<circle cx="72.4" cy="76" r=".49" fill="#008000" stroke="#008000" stroke-width=".2"/>
<circle cx="72.4" cy="76" r=".28" fill="#fff" stroke="#000" stroke-width=".2"/>
<circle cx="83.2" cy="148.3" r=".49" fill="#008000" stroke="#008000" stroke-width=".2"/>
<circle cx="83.2" cy="148.3" r=".28" fill="#fff" stroke="#000" stroke-width=".2"/>
<circle cx="113" cy="98.3" r=".49" fill="#008000" stroke="#008000" stroke-width=".2"/>
<circle cx="113" cy="98.3" r=".28" fill="#fff" stroke="#000" stroke-width=".2"/>
<circle cx="90.2" cy="91.5" r=".49" fill="#008000" stroke="#008000" stroke-width=".2"/>
<circle cx="90.2" cy="91.5" r=".28" fill="#fff" stroke="#000" stroke-width=".2"/>
<circle cx="74.8" cy="167" r=".49" fill="#008000" stroke="#008000" stroke-width=".2"/>
<circle cx="74.8" cy="167" r=".28" fill="#fff" stroke="#000" stroke-width=".2"/>
<circle cx="105.1" cy="137.5" r=".49" fill="#008000" stroke="#008000" stroke-width=".2"/>
<circle cx="105.1" cy="137.5" r=".28" fill="#fff" stroke="#000" stroke-width=".2"/>
<circle cx="99.5" cy="143" r=".49" fill="#008000" stroke="#008000" stroke-width=".2"/>
<circle cx="99.5" cy="143" r=".28" fill="#fff" stroke="#000" stroke-width=".2"/>
<circle cx="85.9" cy="156.2" r=".49" fill="#008000" stroke="#008000" stroke-width=".2"/>
<circle cx="85.9" cy="156.2" r=".28" fill="#fff" stroke="#000" stroke-width=".2"/>
<circle cx="74.4" cy="124.5" r=".49" fill="#008000" stroke="#008000" stroke-width=".2"/>
<circle cx="74.4" cy="124.5" r=".28" fill="#fff" stroke="#000" stroke-width=".2"/>
<circle cx="93" cy="118.2" r=".49" fill="#008000" stroke="#008000" stroke-width=".2"/>
<circle cx="93" cy="118.2" r=".28" fill="#fff" stroke="#000" stroke-width=".2"/>
<circle cx="95.1" cy="82.6" r=".49" fill="#008000" stroke="#008000" stroke-width=".2"/>
<circle cx="95.1" cy="82.6" r=".28" fill="#fff" stroke="#000" stroke-width=".2"/>
<circle cx="56.6" cy="66" r=".49" fill="#008000" stroke="#008000" stroke-width=".2"/>
<circle cx="56.6" cy="66" r=".28" fill="#fff" stroke="#000" stroke-width=".2"/>
<circle cx="65.8" cy="72.9" r=".49" fill="#008000" stroke="#008000" stroke-width=".2"/>
<circle cx="65.8" cy="72.9" r=".28" fill="#fff" stroke="#000" stroke-width=".2"/>
<circle cx="117.4" cy="51.5" r=".49" fill="#008000" stroke="#008000" stroke-width=".2"/>
<circle cx="117.4" cy="51.5" r=".28" fill="#fff" stroke="#000" stroke-width=".2"/>
<circle cx="120.2" cy="58.5" r=".49" fill="#008000" stroke="#008000" stroke-width=".2"/>
<circle cx="120.2" cy="58.5" r=".28" fill="#fff" stroke="#000" stroke-width=".2"/>
<circle cx="123.2" cy="35.1" r=".49" fill="#008000" stroke="#008000" stroke-width=".2"/>
<circle cx="123.2" cy="35.1" r=".28" fill="#fff" stroke="#000" stroke-width=".2"/>
<circle cx="127" cy="52.4" r=".49" fill="#008000" stroke="#008000" stroke-width=".2"/>
<circle cx="127" cy="52.4" r=".28" fill="#fff" stroke="#000" stroke-width=".2"/>
<circle cx="118.9" cy="55.1" r=".49" fill="#008000" stroke="#008000" stroke-width=".2"/>
<circle cx="118.9" cy="55.1" r=".28" fill="#fff" stroke="#000" stroke-width=".2"/>
<circle cx="87" cy="120.2" r=".49" fill="#008000" stroke="#008000" stroke-width=".2"/>
<circle cx="87" cy="120.2" r=".28" fill="#fff" stroke="#000" stroke-width=".2"/>
<circle cx="130.5" cy="19.8" r=".49" fill="#008000" stroke="#008000" stroke-width=".2"/>
<circle cx="130.5" cy="19.8" r=".28" fill="#fff" stroke="#000" stroke-width=".2"/>
<circle cx="129.9" cy="14.3" r=".49" fill="#008000" stroke="#008000" stroke-width=".2"/>
<circle cx="129.9" cy="14.3" r=".28" fill="#fff" stroke="#000" stroke-width=".2"/>
<circle cx="120.8" cy="17.7" r=".49" fill="#008000" stroke="#008000" stroke-width=".2"/>
<circle cx="120.8" cy="17.7" r=".28" fill="#fff" stroke="#000" stroke-width=".2"/>
<circle cx="113" cy="23.3" r=".49" fill="#008000" stroke="#008000" stroke-width=".2"/>
<circle cx="113" cy="23.3" r=".28" fill="#fff" stroke="#000" stroke-width=".2"/>
<circle cx="118.7" cy="35.7" r=".49" fill="#008000" stroke="#008000" stroke-width=".2"/>
<circle cx="118.7" cy="35.7" r=".28" fill="#fff" stroke="#000" stroke-width=".2"/>
<circle cx="71.5" cy="82.7" r=".49" fill="#008000" stroke="#008000" stroke-width=".2"/>
<circle cx="71.5" cy="82.7" r=".28" fill="#fff" stroke="#000" stroke-width=".2"/>
<circle cx="52" cy="76.9" r=".49" fill="#008000" stroke="#008000" stroke-width=".2"/>
<circle cx="52" cy="76.9" r=".28" fill="#fff" stroke="#000" stroke-width=".2"/>
<circle cx="111" cy="24.2" r=".49" fill="#008000" stroke="#008000" stroke-width=".2"/>
<circle cx="111" cy="24.2" r=".28" fill="#fff" stroke="#000" stroke-width=".2"/>
<circle cx="117.4" cy="43.5" r=".49" fill="#008000" stroke="#008000" stroke-width=".2"/>
<circle cx="117.4" cy="43.5" r=".28" fill="#fff" stroke="#000" stroke-width=".2"/>
<circle cx="75.8" cy="95.2" r=".49" fill="#008000" stroke="#008000" stroke-width=".2"/>
<circle cx="75.8" cy="95.2" r=".28" fill="#fff" stroke="#000" stroke-width=".2"/>
<circle cx="50.3" cy="91.7" r=".49" fill="#008000" stroke="#008000" stroke-width=".2"/>
<circle cx="50.3" cy="91.7" r=".28" fill="#fff" stroke="#000" stroke-width=".2"/>
<circle cx="100.8" cy="28.5" r=".49" fill="#008000" stroke="#008000" stroke-width=".2"/>
<circle cx="100.8" cy="28.5" r=".28" fill="#fff" stroke="#000" stroke-width=".2"/>
<circle cx="51.1" cy="94.2" r=".49" fill="#008000" stroke="#008000" stroke-width=".2"/>
<circle cx="51.1" cy="94.2" r=".28" fill="#fff" stroke="#000" stroke-width=".2"/>
<circle cx="112.1" cy="48.7" r=".49" fill="#008000" stroke="#008000" stroke-width=".2"/>
<circle cx="112.1" cy="48.7" r=".28" fill="#fff" stroke="#000" stroke-width=".2"/>
<circle cx="76.5" cy="97.7" r=".49" fill="#008000" stroke="#008000" stroke-width=".2"/>
<circle cx="76.5" cy="97.7" r=".28" fill="#fff" stroke="#000" stroke-width=".2"/>
<circle cx="93.5" cy="182.3" r=".49" fill="#008000" stroke="#008000" stroke-width=".2"/>
<circle cx="93.5" cy="182.3" r=".28" fill="#fff" stroke="#000" stroke-width=".2"/>
<circle cx="98.1" cy="170.8" r=".49" fill="#008000" stroke="#008000" stroke-width=".2"/>
<circle cx="98.1" cy="170.8" r=".28" fill="#fff" stroke="#000" stroke-width=".2"/>
<circle cx="99.2" cy="29.3" r=".49" fill="#008000" stroke="#008000" stroke-width=".2"/>
<circle cx="99.2" cy="29.3" r=".28" fill="#fff" stroke="#000" stroke-width=".2"/>
<circle cx="131" cy="163.2" r=".49" fill="#008000" stroke="#008000" stroke-width=".2"/>
<circle cx="131" cy="163.2" r=".28" fill="#fff" stroke="#000" stroke-width=".2"/>
<circle cx="127.2" cy="194.1" r=".49" fill="#008000" stroke="#008000" stroke-width=".2"/>
<circle cx="127.2" cy="194.1" r=".28" fill="#fff" stroke="#000" stroke-width=".2"/>
<circle cx="110.6" cy="50" r=".49" fill="#008000" stroke="#008000" stroke-width=".2"/>
<circle cx="110.6" cy="50" r=".28" fill="#fff" stroke="#000" stroke-width=".2"/>
<circle cx="110.1" cy="175.6" r=".49" fill="#008000" stroke="#008000" stroke-width=".2"/>
<circle cx="110.1" cy="175.6" r=".28" fill="#fff" stroke="#000" stroke-width=".2"/>
<circle cx="107.7" cy="186.8" r=".49" fill="#008000" stroke="#008000" stroke-width=".2"/>
<circle cx="107.7" cy="186.8" r=".28" fill="#fff" stroke="#000" stroke-width=".2"/>
<circle cx="89.9" cy="35.8" r=".49" fill="#008000" stroke="#008000" stroke-width=".2"/>
<circle cx="89.9" cy="35.8" r=".28" fill="#fff" stroke="#000" stroke-width=".2"/>
<circle cx="84.7" cy="24.9" r=".49" fill="#008000" stroke="#008000" stroke-width=".2"/>
<circle cx="84.7" cy="24.9" r=".28" fill="#fff" stroke="#000" stroke-width=".2"/>
<circle cx="43.9" cy="97" r=".49" fill="#008000" stroke="#008000" stroke-width=".2"/>
<circle cx="43.9" cy="97" r=".28" fill="#fff" stroke="#000" stroke-width=".2"/>
<circle cx="55.3" cy="97.5" r=".49" fill="#008000" stroke="#008000" stroke-width=".2"/>
<circle cx="55.3" cy="97.5" r=".28" fill="#fff" stroke="#000" stroke-width=".2"/>
<circle cx="55.4" cy="111.4" r=".49" fill="#008000" stroke="#008000" stroke-width=".2"/>
<circle cx="55.4" cy="111.4" r=".28" fill="#fff" stroke="#000" stroke-width=".2"/>
<circle cx="44.2" cy="112.5" r=".49" fill="#008000" stroke="#008000" stroke-width=".2"/>
<circle cx="44.2" cy="112.5" r=".28" fill="#fff" stroke="#000" stroke-width=".2"/>
<circle cx="110.1" cy="187.6" r=".49" fill="#008000" stroke="#008000" stroke-width=".2"/>
<circle cx="110.1" cy="187.6" r=".28" fill="#fff" stroke="#000" stroke-width=".2"/>
<circle cx="108.2" cy="193.1" r=".49" fill="#008000" stroke="#008000" stroke-width=".2"/>
<circle cx="108.2" cy="193.1" r=".28" fill="#fff" stroke="#000" stroke-width=".2"/>
<circle cx="121.2" cy="177" r=".49" fill="#008000" stroke="#008000" stroke-width=".2"/>
<circle cx="121.2" cy="177" r=".28" fill="#fff" stroke="#000" stroke-width=".2"/>
<circle cx="118.7" cy="187.9" r=".49" fill="#008000" stroke="#008000" stroke-width=".2"/>
<circle cx="118.7" cy="187.9" r=".28" fill="#fff" stroke="#000" stroke-width=".2"/>
<circle cx="84.6" cy="39.4" r=".49" fill="#008000" stroke="#008000" stroke-width=".2"/>
<circle cx="84.6" cy="39.4" r=".28" fill="#fff" stroke="#000" stroke-width=".2"/>
<circle cx="101.6" cy="57.2" r=".49" fill="#008000" stroke="#008000" stroke-width=".2"/>
<circle cx="101.6" cy="57.2" r=".28" fill="#fff" stroke="#000" stroke-width=".2"/>
<circle cx="101.1" cy="148.8" r=".49" fill="#008000" stroke="#008000" stroke-width=".2"/>
<circle cx="101.1" cy="148.8" r=".28" fill="#fff" stroke="#000" stroke-width=".2"/>
<circle cx="81.8" cy="169.3" r=".49" fill="#008000" stroke="#008000" stroke-width=".2"/>
<circle cx="81.8" cy="169.3" r=".28" fill="#fff" stroke="#000" stroke-width=".2"/>
<circle cx="82.9" cy="40.8" r=".49" fill="#008000" stroke="#008000" stroke-width=".2"/>
<circle cx="82.9" cy="40.8" r=".28" fill="#fff" stroke="#000" stroke-width=".2"/>
<circle cx="76.7" cy="33.9" r=".49" fill="#008000" stroke="#008000" stroke-width=".2"/>
<circle cx="76.7" cy="33.9" r=".28" fill="#fff" stroke="#000" stroke-width=".2"/>
<circle cx="53.1" cy="67.2" r=".49" fill="#008000" stroke="#008000" stroke-width=".2"/>
<circle cx="53.1" cy="67.2" r=".28" fill="#fff" stroke="#000" stroke-width=".2"/>
<circle cx="63.4" cy="71.6" r=".49" fill="#008000" stroke="#008000" stroke-width=".2"/>
<circle cx="63.4" cy="71.6" r=".28" fill="#fff" stroke="#000" stroke-width=".2"/>
<circle cx="73.7" cy="65.7" r=".49" fill="#008000" stroke="#008000" stroke-width=".2"/>
<circle cx="73.7" cy="65.7" r=".28" fill="#fff" stroke="#000" stroke-width=".2"/>
<circle cx="84.5" cy="51.8" r=".49" fill="#008000" stroke="#008000" stroke-width=".2"/>
<circle cx="84.5" cy="51.8" r=".28" fill="#fff" stroke="#000" stroke-width=".2"/>
<circle cx="78.8" cy="44.6" r=".49" fill="#008000" stroke="#008000" stroke-width=".2"/>
<circle cx="78.8" cy="44.6" r=".28" fill="#fff" stroke="#000" stroke-width=".2"/>
<circle cx="70.4" cy="55.2" r=".49" fill="#008000" stroke="#008000" stroke-width=".2"/>
<circle cx="70.4" cy="55.2" r=".28" fill="#fff" stroke="#000" stroke-width=".2"/>
<circle cx="72.4" cy="66.1" r=".49" fill="#008000" stroke="#008000" stroke-width=".2"/>
<circle cx="72.4" cy="66.1" r=".28" fill="#fff" stroke="#000" stroke-width=".2"/>
<circle cx="75.6" cy="60.7" r=".49" fill="#008000" stroke="#008000" stroke-width=".2"/>
<circle cx="75.6" cy="60.7" r=".28" fill="#fff" stroke="#000" stroke-width=".2"/>
<circle cx="130.9" cy="23.5" r=".49" fill="#008000" stroke="#008000" stroke-width=".2"/>
<circle cx="130.9" cy="23.5" r=".28" fill="#fff" stroke="#000" stroke-width=".2"/>
<circle cx="132.1" cy="35.2" r=".49" fill="#008000" stroke="#008000" stroke-width=".2"/>
<circle cx="132.1" cy="35.2" r=".28" fill="#fff" stroke="#000" stroke-width=".2"/>
<circle cx="71.8" cy="56.2" r=".49" fill="#008000" stroke="#008000" stroke-width=".2"/>
<circle cx="71.8" cy="56.2" r=".28" fill="#fff" stroke="#000" stroke-width=".2"/>
<circle cx="132.3" cy="25.4" r=".49" fill="#008000" stroke="#008000" stroke-width=".2"/>
<circle cx="132.3" cy="25.4" r=".28" fill="#fff" stroke="#000" stroke-width=".2"/>
<circle cx="133.5" cy="36.6" r=".49" fill="#008000" stroke="#008000" stroke-width=".2"/>
<circle cx="133.5" cy="36.6" r=".28" fill="#fff" stroke="#000" stroke-width=".2"/>
<circle cx="66.8" cy="60.6" r=".49" fill="#008000" stroke="#008000" stroke-width=".2"/>
<circle cx="66.8" cy="60.6" r=".28" fill="#fff" stroke="#000" stroke-width=".2"/>
<circle cx="130.3" cy="39.1" r=".49" fill="#008000" stroke="#008000" stroke-width=".2"/>
<circle cx="130.3" cy="39.1" r=".28" fill="#fff" stroke="#000" stroke-width=".2"/>
<circle cx="129.1" cy="27.8" r=".49" fill="#008000" stroke="#008000" stroke-width=".2"/>
<circle cx="129.1" cy="27.8" r=".28" fill="#fff" stroke="#000" stroke-width=".2"/>
<circle cx="63.4" cy="66.8" r=".49" fill="#008000" stroke="#008000" stroke-width=".2"/>
<circle cx="63.4" cy="66.8" r=".28" fill="#fff" stroke="#000" stroke-width=".2"/>
<circle cx="71.5" cy="71.2" r=".49" fill="#008000" stroke="#008000" stroke-width=".2"/>
<circle cx="71.5" cy="71.2" r=".28" fill="#fff" stroke="#000" stroke-width=".2"/>
<circle cx="77.6" cy="60.6" r=".49" fill="#008000" stroke="#008000" stroke-width=".2"/>
<circle cx="77.6" cy="60.6" r=".28" fill="#fff" stroke="#000" stroke-width=".2"/>
<circle cx="115.8" cy="183.5" r=".49" fill="#008000" stroke="#008000" stroke-width=".2"/>
<circle cx="115.8" cy="183.5" r=".28" fill="#fff" stroke="#000" stroke-width=".2"/>
<circle cx="132.7" cy="123.7" r=".49" fill="#008000" stroke="#008000" stroke-width=".2"/>
<circle cx="132.7" cy="123.7" r=".28" fill="#fff" stroke="#000" stroke-width=".2"/>
<circle cx="119.4" cy="111.7" r=".49" fill="#008000" stroke="#008000" stroke-width=".2"/>
<circle cx="119.4" cy="111.7" r=".28" fill="#fff" stroke="#000" stroke-width=".2"/>
<circle cx="129.9" cy="103" r=".49" fill="#008000" stroke="#008000" stroke-width=".2"/>
<circle cx="129.9" cy="103" r=".28" fill="#fff" stroke="#000" stroke-width=".2"/>
<circle cx="59.1" cy="77.4" r=".49" fill="#008000" stroke="#008000" stroke-width=".2"/>
<circle cx="59.1" cy="77.4" r=".28" fill="#fff" stroke="#000" stroke-width=".2"/>
<circle cx="73.4" cy="82" r=".49" fill="#008000" stroke="#008000" stroke-width=".2"/>
<circle cx="73.4" cy="82" r=".28" fill="#fff" stroke="#000" stroke-width=".2"/>
<circle cx="57.3" cy="83.9" r=".49" fill="#008000" stroke="#008000" stroke-width=".2"/>
<circle cx="57.3" cy="83.9" r=".28" fill="#fff" stroke="#000" stroke-width=".2"/>
<circle cx="73.7" cy="88.5" r=".49" fill="#008000" stroke="#008000" stroke-width=".2"/>
<circle cx="73.7" cy="88.5" r=".28" fill="#fff" stroke="#000" stroke-width=".2"/>
<circle cx="56" cy="91" r=".49" fill="#008000" stroke="#008000" stroke-width=".2"/>
<circle cx="56" cy="91" r=".28" fill="#fff" stroke="#000" stroke-width=".2"/>
<circle cx="75" cy="93.7" r=".49" fill="#008000" stroke="#008000" stroke-width=".2"/>
<circle cx="75" cy="93.7" r=".28" fill="#fff" stroke="#000" stroke-width=".2"/>
<circle cx="106.3" cy="163" r=".49" fill="#008000" stroke="#008000" stroke-width=".2"/>
<circle cx="106.3" cy="163" r=".28" fill="#fff" stroke="#000" stroke-width=".2"/>
<circle cx="111.4" cy="153.4" r=".49" fill="#008000" stroke="#008000" stroke-width=".2"/>
<circle cx="111.4" cy="153.4" r=".28" fill="#fff" stroke="#000" stroke-width=".2"/>
<circle cx="57.4" cy="96.7" r=".49" fill="#008000" stroke="#008000" stroke-width=".2"/>
<circle cx="57.4" cy="96.7" r=".28" fill="#fff" stroke="#000" stroke-width=".2"/>
<circle cx="69.4" cy="97.4" r=".49" fill="#008000" stroke="#008000" stroke-width=".2"/>
<circle cx="69.4" cy="97.4" r=".28" fill="#fff" stroke="#000" stroke-width=".2"/>
<circle cx="75.8" cy="132.7" r=".49" fill="#008000" stroke="#008000" stroke-width=".2"/>
<circle cx="75.8" cy="132.7" r=".28" fill="#fff" stroke="#000" stroke-width=".2"/>
<circle cx="117.1" cy="166.1" r=".49" fill="#008000" stroke="#008000" stroke-width=".2"/>
<circle cx="117.1" cy="166.1" r=".28" fill="#fff" stroke="#000" stroke-width=".2"/>
<circle cx="120.6" cy="155.8" r=".49" fill="#008000" stroke="#008000" stroke-width=".2"/>
<circle cx="120.6" cy="155.8" r=".28" fill="#fff" stroke="#000" stroke-width=".2"/>
<circle cx="56.5" cy="98.3" r=".49" fill="#008000" stroke="#008000" stroke-width=".2"/>
<circle cx="56.5" cy="98.3" r=".28" fill="#fff" stroke="#000" stroke-width=".2"/>
<circle cx="68.3" cy="99.3" r=".49" fill="#008000" stroke="#008000" stroke-width=".2"/>
<circle cx="68.3" cy="99.3" r=".28" fill="#fff" stroke="#000" stroke-width=".2"/>
<circle cx="78.9" cy="140" r=".49" fill="#008000" stroke="#008000" stroke-width=".2"/>
<circle cx="78.9" cy="140" r=".28" fill="#fff" stroke="#000" stroke-width=".2"/>
<circle cx="81.9" cy="137.9" r=".49" fill="#008000" stroke="#008000" stroke-width=".2"/>
<circle cx="81.9" cy="137.9" r=".28" fill="#fff" stroke="#000" stroke-width=".2"/>
<circle cx="108.9" cy="147.5" r=".49" fill="#008000" stroke="#008000" stroke-width=".2"/>
<circle cx="108.9" cy="147.5" r=".28" fill="#fff" stroke="#000" stroke-width=".2"/>
<circle cx="102.8" cy="156.5" r=".49" fill="#008000" stroke="#008000" stroke-width=".2"/>
<circle cx="102.8" cy="156.5" r=".28" fill="#fff" stroke="#000" stroke-width=".2"/>
<circle cx="56.8" cy="109.7" r=".49" fill="#008000" stroke="#008000" stroke-width=".2"/>
<circle cx="56.8" cy="109.7" r=".28" fill="#fff" stroke="#000" stroke-width=".2"/>
<circle cx="64.3" cy="109.2" r=".49" fill="#008000" stroke="#008000" stroke-width=".2"/>
<circle cx="64.3" cy="109.2" r=".28" fill="#fff" stroke="#000" stroke-width=".2"/>
<circle cx="76.5" cy="144.5" r=".49" fill="#008000" stroke="#008000" stroke-width=".2"/>
<circle cx="76.5" cy="144.5" r=".28" fill="#fff" stroke="#000" stroke-width=".2"/>
<circle cx="85" cy="138.7" r=".49" fill="#008000" stroke="#008000" stroke-width=".2"/>
<circle cx="85" cy="138.7" r=".28" fill="#fff" stroke="#000" stroke-width=".2"/>
<circle cx="59.1" cy="128.9" r=".49" fill="#008000" stroke="#008000" stroke-width=".2"/>
<circle cx="59.1" cy="128.9" r=".28" fill="#fff" stroke="#000" stroke-width=".2"/>
<circle cx="87.4" cy="118.3" r=".49" fill="#008000" stroke="#008000" stroke-width=".2"/>
<circle cx="87.4" cy="118.3" r=".28" fill="#fff" stroke="#000" stroke-width=".2"/>
<circle cx="58.4" cy="117.6" r=".49" fill="#008000" stroke="#008000" stroke-width=".2"/>
<circle cx="58.4" cy="117.6" r=".28" fill="#fff" stroke="#000" stroke-width=".2"/>
<circle cx="83.8" cy="112.5" r=".49" fill="#008000" stroke="#008000" stroke-width=".2"/>
<circle cx="83.8" cy="112.5" r=".28" fill="#fff" stroke="#000" stroke-width=".2"/>
<circle cx="82" cy="109.8" r=".49" fill="#008000" stroke="#008000" stroke-width=".2"/>
<circle cx="82" cy="109.8" r=".28" fill="#fff" stroke="#000" stroke-width=".2"/>
<circle cx="56.9" cy="115.6" r=".49" fill="#008000" stroke="#008000" stroke-width=".2"/>
<circle cx="56.9" cy="115.6" r=".28" fill="#fff" stroke="#000" stroke-width=".2"/>
<circle cx="132.9" cy="56" r=".49" fill="#008000" stroke="#008000" stroke-width=".2"/>
<circle cx="132.9" cy="56" r=".28" fill="#fff" stroke="#000" stroke-width=".2"/>
<circle cx="131.7" cy="46.4" r=".49" fill="#008000" stroke="#008000" stroke-width=".2"/>
<circle cx="131.7" cy="46.4" r=".28" fill="#fff" stroke="#000" stroke-width=".2"/>
<circle cx="61.3" cy="134.6" r=".49" fill="#008000" stroke="#008000" stroke-width=".2"/>
<circle cx="61.3" cy="134.6" r=".28" fill="#fff" stroke="#000" stroke-width=".2"/>
<circle cx="80" cy="126.9" r=".49" fill="#008000" stroke="#008000" stroke-width=".2"/>
<circle cx="80" cy="126.9" r=".28" fill="#fff" stroke="#000" stroke-width=".2"/>
<circle cx="112.5" cy="46.5" r=".49" fill="#008000" stroke="#008000" stroke-width=".2"/>
<circle cx="112.5" cy="46.5" r=".28" fill="#fff" stroke="#000" stroke-width=".2"/>
<circle cx="119" cy="60.2" r=".49" fill="#008000" stroke="#008000" stroke-width=".2"/>
<circle cx="119" cy="60.2" r=".28" fill="#fff" stroke="#000" stroke-width=".2"/>
<circle cx="135.6" cy="58.8" r=".49" fill="#008000" stroke="#008000" stroke-width=".2"/>
<circle cx="135.6" cy="58.8" r=".28" fill="#fff" stroke="#000" stroke-width=".2"/>
<circle cx="134.6" cy="47.5" r=".49" fill="#008000" stroke="#008000" stroke-width=".2"/>
<circle cx="134.6" cy="47.5" r=".28" fill="#fff" stroke="#000" stroke-width=".2"/>
<circle cx="64.3" cy="141.3" r=".49" fill="#008000" stroke="#008000" stroke-width=".2"/>
<circle cx="64.3" cy="141.3" r=".28" fill="#fff" stroke="#000" stroke-width=".2"/>
<circle cx="83" cy="130.2" r=".49" fill="#008000" stroke="#008000" stroke-width=".2"/>
<circle cx="83" cy="130.2" r=".28" fill="#fff" stroke="#000" stroke-width=".2"/>
<circle cx="111.9" cy="50.6" r=".49" fill="#008000" stroke="#008000" stroke-width=".2"/>
<circle cx="111.9" cy="50.6" r=".28" fill="#fff" stroke="#000" stroke-width=".2"/>
<circle cx="119.1" cy="63.3" r=".49" fill="#008000" stroke="#008000" stroke-width=".2"/>
<circle cx="119.1" cy="63.3" r=".28" fill="#fff" stroke="#000" stroke-width=".2"/>
<circle cx="142" cy="59.6" r=".49" fill="#008000" stroke="#008000" stroke-width=".2"/>
<circle cx="142" cy="59.6" r=".28" fill="#fff" stroke="#000" stroke-width=".2"/>
<circle cx="142.6" cy="49.4" r=".49" fill="#008000" stroke="#008000" stroke-width=".2"/>
<circle cx="142.6" cy="49.4" r=".28" fill="#fff" stroke="#000" stroke-width=".2"/>
<circle cx="97.3" cy="75.2" r=".49" fill="#008000" stroke="#008000" stroke-width=".2"/>
<circle cx="97.3" cy="75.2" r=".28" fill="#fff" stroke="#000" stroke-width=".2"/>
<circle cx="103.7" cy="79.4" r=".49" fill="#008000" stroke="#008000" stroke-width=".2"/>
<circle cx="103.7" cy="79.4" r=".28" fill="#fff" stroke="#000" stroke-width=".2"/>
<circle cx="65.9" cy="142.1" r=".49" fill="#008000" stroke="#008000" stroke-width=".2"/>
<circle cx="65.9" cy="142.1" r=".28" fill="#fff" stroke="#000" stroke-width=".2"/>
<circle cx="94.9" cy="126.2" r=".49" fill="#008000" stroke="#008000" stroke-width=".2"/>
<circle cx="94.9" cy="126.2" r=".28" fill="#fff" stroke="#000" stroke-width=".2"/>
<circle cx="103.2" cy="133.2" r=".49" fill="#008000" stroke="#008000" stroke-width=".2"/>
<circle cx="103.2" cy="133.2" r=".28" fill="#fff" stroke="#000" stroke-width=".2"/>
<circle cx="110.2" cy="127.3" r=".49" fill="#008000" stroke="#008000" stroke-width=".2"/>
<circle cx="110.2" cy="127.3" r=".28" fill="#fff" stroke="#000" stroke-width=".2"/>
<circle cx="71.4" cy="151.4" r=".49" fill="#008000" stroke="#008000" stroke-width=".2"/>
<circle cx="71.4" cy="151.4" r=".28" fill="#fff" stroke="#000" stroke-width=".2"/>
<circle cx="100.8" cy="130.1" r=".49" fill="#008000" stroke="#008000" stroke-width=".2"/>
<circle cx="100.8" cy="130.1" r=".28" fill="#fff" stroke="#000" stroke-width=".2"/>
<circle cx="111.9" cy="138.7" r=".49" fill="#008000" stroke="#008000" stroke-width=".2"/>
<circle cx="111.9" cy="138.7" r=".28" fill="#fff" stroke="#000" stroke-width=".2"/>
<circle cx="120.1" cy="129.3" r=".49" fill="#008000" stroke="#008000" stroke-width=".2"/>
<circle cx="120.1" cy="129.3" r=".28" fill="#fff" stroke="#000" stroke-width=".2"/>
<circle cx="66" cy="161" r=".49" fill="#008000" stroke="#008000" stroke-width=".2"/>
<circle cx="66" cy="161" r=".28" fill="#fff" stroke="#000" stroke-width=".2"/>
<circle cx="82.7" cy="176.9" r=".49" fill="#008000" stroke="#008000" stroke-width=".2"/>
<circle cx="82.7" cy="176.9" r=".28" fill="#fff" stroke="#000" stroke-width=".2"/>
<circle cx="109.6" cy="132.9" r=".49" fill="#008000" stroke="#008000" stroke-width=".2"/>
<circle cx="109.6" cy="132.9" r=".28" fill="#fff" stroke="#000" stroke-width=".2"/>
<circle cx="118" cy="124.5" r=".49" fill="#008000" stroke="#008000" stroke-width=".2"/>
<circle cx="118" cy="124.5" r=".28" fill="#fff" stroke="#000" stroke-width=".2"/>
<circle cx="77.9" cy="157.5" r=".49" fill="#008000" stroke="#008000" stroke-width=".2"/>
<circle cx="77.9" cy="157.5" r=".28" fill="#fff" stroke="#000" stroke-width=".2"/>
<circle cx="104.6" cy="94.2" r=".49" fill="#008000" stroke="#008000" stroke-width=".2"/>
<circle cx="104.6" cy="94.2" r=".28" fill="#fff" stroke="#000" stroke-width=".2"/>
<circle cx="114.4" cy="96.8" r=".49" fill="#008000" stroke="#008000" stroke-width=".2"/>
<circle cx="114.4" cy="96.8" r=".28" fill="#fff" stroke="#000" stroke-width=".2"/>
<circle cx="84.9" cy="167" r=".49" fill="#008000" stroke="#008000" stroke-width=".2"/>
<circle cx="84.9" cy="167" r=".28" fill="#fff" stroke="#000" stroke-width=".2"/>
<circle cx="120.2" cy="123.4" r=".49" fill="#008000" stroke="#008000" stroke-width=".2"/>
<circle cx="120.2" cy="123.4" r=".28" fill="#fff" stroke="#000" stroke-width=".2"/>
<circle cx="118.2" cy="84.8" r=".49" fill="#008000" stroke="#008000" stroke-width=".2"/>
<circle cx="118.2" cy="84.8" r=".28" fill="#fff" stroke="#000" stroke-width=".2"/>
<circle cx="108.2" cy="90.7" r=".49" fill="#008000" stroke="#008000" stroke-width=".2"/>
<circle cx="108.2" cy="90.7" r=".28" fill="#fff" stroke="#000" stroke-width=".2"/>
<circle cx="117.9" cy="94.7" r=".49" fill="#008000" stroke="#008000" stroke-width=".2"/>
<circle cx="117.9" cy="94.7" r=".28" fill="#fff" stroke="#000" stroke-width=".2"/>
<circle cx="89.8" cy="171" r=".49" fill="#008000" stroke="#008000" stroke-width=".2"/>
<circle cx="89.8" cy="171" r=".28" fill="#fff" stroke="#000" stroke-width=".2"/>
<circle cx="121.9" cy="126.4" r=".49" fill="#008000" stroke="#008000" stroke-width=".2"/>
<circle cx="121.9" cy="126.4" r=".28" fill="#fff" stroke="#000" stroke-width=".2"/>
<circle cx="131.7" cy="81.7" r=".49" fill="#008000" stroke="#008000" stroke-width=".2"/>
<circle cx="131.7" cy="81.7" r=".28" fill="#fff" stroke="#000" stroke-width=".2"/>
<circle cx="129.7" cy="75.6" r=".49" fill="#008000" stroke="#008000" stroke-width=".2"/>
<circle cx="129.7" cy="75.6" r=".28" fill="#fff" stroke="#000" stroke-width=".2"/>
<circle cx="114.2" cy="84.5" r=".49" fill="#008000" stroke="#008000" stroke-width=".2"/>
<circle cx="114.2" cy="84.5" r=".28" fill="#fff" stroke="#000" stroke-width=".2"/>
<circle cx="123.1" cy="91.3" r=".49" fill="#008000" stroke="#008000" stroke-width=".2"/>
<circle cx="123.1" cy="91.3" r=".28" fill="#fff" stroke="#000" stroke-width=".2"/>
<circle cx="101.6" cy="176" r=".49" fill="#008000" stroke="#008000" stroke-width=".2"/>
<circle cx="101.6" cy="176" r=".28" fill="#fff" stroke="#000" stroke-width=".2"/>
<circle cx="123.8" cy="125.3" r=".49" fill="#008000" stroke="#008000" stroke-width=".2"/>
<circle cx="123.8" cy="125.3" r=".28" fill="#fff" stroke="#000" stroke-width=".2"/>
<circle cx="112.9" cy="99.5" r=".49" fill="#008000" stroke="#008000" stroke-width=".2"/>
<circle cx="112.9" cy="99.5" r=".28" fill="#fff" stroke="#000" stroke-width=".2"/>
<circle cx="108.6" cy="98.8" r=".49" fill="#008000" stroke="#008000" stroke-width=".2"/>
<circle cx="108.6" cy="98.8" r=".28" fill="#fff" stroke="#000" stroke-width=".2"/>
<circle cx="94.8" cy="174.1" r=".49" fill="#008000" stroke="#008000" stroke-width=".2"/>
<circle cx="94.8" cy="174.1" r=".28" fill="#fff" stroke="#000" stroke-width=".2"/>
<circle cx="123.7" cy="123.6" r=".49" fill="#008000" stroke="#008000" stroke-width=".2"/>
<circle cx="123.7" cy="123.6" r=".28" fill="#fff" stroke="#000" stroke-width=".2"/>
<circle cx="131" cy="113.3" r=".49" fill="#008000" stroke="#008000" stroke-width=".2"/>
<circle cx="131" cy="113.3" r=".28" fill="#fff" stroke="#000" stroke-width=".2"/>
<circle cx="106.3" cy="180.1" r=".49" fill="#008000" stroke="#008000" stroke-width=".2"/>
<circle cx="106.3" cy="180.1" r=".28" fill="#fff" stroke="#000" stroke-width=".2"/>
<circle cx="124.1" cy="118.8" r=".49" fill="#008000" stroke="#008000" stroke-width=".2"/>
<circle cx="124.1" cy="118.8" r=".28" fill="#fff" stroke="#000" stroke-width=".2"/>
<circle cx="118.7" cy="110.7" r=".49" fill="#008000" stroke="#008000" stroke-width=".2"/>
<circle cx="118.7" cy="110.7" r=".28" fill="#fff" stroke="#000" stroke-width=".2"/>
<circle cx="128" cy="101.3" r=".49" fill="#008000" stroke="#008000" stroke-width=".2"/>
<circle cx="128" cy="101.3" r=".28" fill="#fff" stroke="#000" stroke-width=".2"/>
<circle cx="221.2" cy="140.2" r=".49" fill="#008000" stroke="#008000" stroke-width=".2"/>
<circle cx="221.2" cy="140.2" r=".28" fill="#fff" stroke="#000" stroke-width=".2"/>
<circle cx="211.5" cy="134.2" r=".49" fill="#008000" stroke="#008000" stroke-width=".2"/>
<circle cx="211.5" cy="134.2" r=".28" fill="#fff" stroke="#000" stroke-width=".2"/>
<circle cx="195.9" cy="129" r=".49" fill="#008000" stroke="#008000" stroke-width=".2"/>
<circle cx="195.9" cy="129" r=".28" fill="#fff" stroke="#000" stroke-width=".2"/>
<circle cx="202.7" cy="39.3" r=".49" fill="#008000" stroke="#008000" stroke-width=".2"/>
<circle cx="202.7" cy="39.3" r=".28" fill="#fff" stroke="#000" stroke-width=".2"/>
<circle cx="183.1" cy="58.8" r=".49" fill="#008000" stroke="#008000" stroke-width=".2"/>
<circle cx="183.1" cy="58.8" r=".28" fill="#fff" stroke="#000" stroke-width=".2"/>
<circle cx="180.4" cy="35.9" r=".49" fill="#008000" stroke="#008000" stroke-width=".2"/>
<circle cx="180.4" cy="35.9" r=".28" fill="#fff" stroke="#000" stroke-width=".2"/>
<circle cx="177.8" cy="39.7" r=".49" fill="#008000" stroke="#008000" stroke-width=".2"/>
<circle cx="177.8" cy="39.7" r=".28" fill="#fff" stroke="#000" stroke-width=".2"/>
<circle cx="191.6" cy="50.4" r=".49" fill="#008000" stroke="#008000" stroke-width=".2"/>
<circle cx="191.6" cy="50.4" r=".28" fill="#fff" stroke="#000" stroke-width=".2"/>
<circle cx="154.2" cy="169" r=".49" fill="#008000" stroke="#008000" stroke-width=".2"/>
<circle cx="154.2" cy="169" r=".28" fill="#fff" stroke="#000" stroke-width=".2"/>
<circle cx="198.4" cy="83.7" r=".49" fill="#008000" stroke="#008000" stroke-width=".2"/>
<circle cx="198.4" cy="83.7" r=".28" fill="#fff" stroke="#000" stroke-width=".2"/>
<circle cx="166.4" cy="152.8" r=".49" fill="#008000" stroke="#008000" stroke-width=".2"/>
<circle cx="166.4" cy="152.8" r=".28" fill="#fff" stroke="#000" stroke-width=".2"/>
<circle cx="168.3" cy="158.3" r=".49" fill="#008000" stroke="#008000" stroke-width=".2"/>
<circle cx="168.3" cy="158.3" r=".28" fill="#fff" stroke="#000" stroke-width=".2"/>
<circle cx="179.3" cy="55.4" r=".49" fill="#008000" stroke="#008000" stroke-width=".2"/>
<circle cx="179.3" cy="55.4" r=".28" fill="#fff" stroke="#000" stroke-width=".2"/>
<circle cx="190.8" cy="95.6" r=".49" fill="#008000" stroke="#008000" stroke-width=".2"/>
<circle cx="190.8" cy="95.6" r=".28" fill="#fff" stroke="#000" stroke-width=".2"/>
<circle cx="201" cy="95.9" r=".49" fill="#008000" stroke="#008000" stroke-width=".2"/>
<circle cx="201" cy="95.9" r=".28" fill="#fff" stroke="#000" stroke-width=".2"/>
<circle cx="214.7" cy="152.1" r=".49" fill="#008000" stroke="#008000" stroke-width=".2"/>
<circle cx="214.7" cy="152.1" r=".28" fill="#fff" stroke="#000" stroke-width=".2"/>
<circle cx="198.3" cy="143" r=".49" fill="#008000" stroke="#008000" stroke-width=".2"/>
<circle cx="198.3" cy="143" r=".28" fill="#fff" stroke="#000" stroke-width=".2"/>
<circle cx="210.5" cy="48.2" r=".49" fill="#008000" stroke="#008000" stroke-width=".2"/>
<circle cx="210.5" cy="48.2" r=".28" fill="#fff" stroke="#000" stroke-width=".2"/>
<circle cx="195.7" cy="59.5" r=".49" fill="#008000" stroke="#008000" stroke-width=".2"/>
<circle cx="195.7" cy="59.5" r=".28" fill="#fff" stroke="#000" stroke-width=".2"/>
<circle cx="215.7" cy="121.3" r=".49" fill="#008000" stroke="#008000" stroke-width=".2"/>
<circle cx="215.7" cy="121.3" r=".28" fill="#fff" stroke="#000" stroke-width=".2"/>
<circle cx="169.1" cy="30.2" r=".49" fill="#008000" stroke="#008000" stroke-width=".2"/>
<circle cx="169.1" cy="30.2" r=".28" fill="#fff" stroke="#000" stroke-width=".2"/>
<circle cx="166.3" cy="36.8" r=".49" fill="#008000" stroke="#008000" stroke-width=".2"/>
<circle cx="166.3" cy="36.8" r=".28" fill="#fff" stroke="#000" stroke-width=".2"/>
<circle cx="142" cy="173.2" r=".49" fill="#008000" stroke="#008000" stroke-width=".2"/>
<circle cx="142" cy="173.2" r=".28" fill="#fff" stroke="#000" stroke-width=".2"/>
<circle cx="177.5" cy="144.6" r=".49" fill="#008000" stroke="#008000" stroke-width=".2"/>
<circle cx="177.5" cy="144.6" r=".28" fill="#fff" stroke="#000" stroke-width=".2"/>
<circle cx="186" cy="157.2" r=".49" fill="#008000" stroke="#008000" stroke-width=".2"/>
<circle cx="186" cy="157.2" r=".28" fill="#fff" stroke="#000" stroke-width=".2"/>
<circle cx="160.6" cy="50.6" r=".49" fill="#008000" stroke="#008000" stroke-width=".2"/>
<circle cx="160.6" cy="50.6" r=".28" fill="#fff" stroke="#000" stroke-width=".2"/>
<circle cx="182.6" cy="118" r=".49" fill="#008000" stroke="#008000" stroke-width=".2"/>
<circle cx="182.6" cy="118" r=".28" fill="#fff" stroke="#000" stroke-width=".2"/>
<circle cx="161.2" cy="110.9" r=".49" fill="#008000" stroke="#008000" stroke-width=".2"/>
<circle cx="161.2" cy="110.9" r=".28" fill="#fff" stroke="#000" stroke-width=".2"/>
<circle cx="167.2" cy="84" r=".49" fill="#008000" stroke="#008000" stroke-width=".2"/>
<circle cx="167.2" cy="84" r=".28" fill="#fff" stroke="#000" stroke-width=".2"/>
<circle cx="160.1" cy="86.8" r=".49" fill="#008000" stroke="#008000" stroke-width=".2"/>
<circle cx="160.1" cy="86.8" r=".28" fill="#fff" stroke="#000" stroke-width=".2"/>
<circle cx="149.4" cy="77.7" r=".49" fill="#008000" stroke="#008000" stroke-width=".2"/>
<circle cx="149.4" cy="77.7" r=".28" fill="#fff" stroke="#000" stroke-width=".2"/>
<circle cx="210" cy="94.4" r=".49" fill="#008000" stroke="#008000" stroke-width=".2"/>
<circle cx="210" cy="94.4" r=".28" fill="#fff" stroke="#000" stroke-width=".2"/>
<circle cx="205.9" cy="93.9" r=".49" fill="#008000" stroke="#008000" stroke-width=".2"/>
<circle cx="205.9" cy="93.9" r=".28" fill="#fff" stroke="#000" stroke-width=".2"/>
<circle cx="190.7" cy="93.4" r=".49" fill="#008000" stroke="#008000" stroke-width=".2"/>
<circle cx="190.7" cy="93.4" r=".28" fill="#fff" stroke="#000" stroke-width=".2"/>
<circle cx="208.4" cy="119.6" r=".49" fill="#008000" stroke="#008000" stroke-width=".2"/>
<circle cx="208.4" cy="119.6" r=".28" fill="#fff" stroke="#000" stroke-width=".2"/>
<circle cx="206.7" cy="126.2" r=".49" fill="#008000" stroke="#008000" stroke-width=".2"/>
<circle cx="206.7" cy="126.2" r=".28" fill="#fff" stroke="#000" stroke-width=".2"/>
<circle cx="206.7" cy="162.7" r=".49" fill="#008000" stroke="#008000" stroke-width=".2"/>
<circle cx="206.7" cy="162.7" r=".28" fill="#fff" stroke="#000" stroke-width=".2"/>
<circle cx="193.9" cy="151.7" r=".49" fill="#008000" stroke="#008000" stroke-width=".2"/>
<circle cx="193.9" cy="151.7" r=".28" fill="#fff" stroke="#000" stroke-width=".2"/>
<circle cx="217.7" cy="59" r=".49" fill="#008000" stroke="#008000" stroke-width=".2"/>
<circle cx="217.7" cy="59" r=".28" fill="#fff" stroke="#000" stroke-width=".2"/>
<circle cx="203.6" cy="68.4" r=".49" fill="#008000" stroke="#008000" stroke-width=".2"/>
<circle cx="203.6" cy="68.4" r=".28" fill="#fff" stroke="#000" stroke-width=".2"/>
<circle cx="136.3" cy="176.7" r=".49" fill="#008000" stroke="#008000" stroke-width=".2"/>
<circle cx="136.3" cy="176.7" r=".28" fill="#fff" stroke="#000" stroke-width=".2"/>
<circle cx="217.6" cy="108.3" r=".49" fill="#008000" stroke="#008000" stroke-width=".2"/>
<circle cx="217.6" cy="108.3" r=".28" fill="#fff" stroke="#000" stroke-width=".2"/>
<circle cx="206.5" cy="106.3" r=".49" fill="#008000" stroke="#008000" stroke-width=".2"/>
<circle cx="206.5" cy="106.3" r=".28" fill="#fff" stroke="#000" stroke-width=".2"/>
<circle cx="212.1" cy="108" r=".49" fill="#008000" stroke="#008000" stroke-width=".2"/>
<circle cx="212.1" cy="108" r=".28" fill="#fff" stroke="#000" stroke-width=".2"/>
<circle cx="157.9" cy="26.4" r=".49" fill="#008000" stroke="#008000" stroke-width=".2"/>
<circle cx="157.9" cy="26.4" r=".28" fill="#fff" stroke="#000" stroke-width=".2"/>
<circle cx="157.8" cy="32.1" r=".49" fill="#008000" stroke="#008000" stroke-width=".2"/>
<circle cx="157.8" cy="32.1" r=".28" fill="#fff" stroke="#000" stroke-width=".2"/>
<circle cx="188.8" cy="130.2" r=".49" fill="#008000" stroke="#008000" stroke-width=".2"/>
<circle cx="188.8" cy="130.2" r=".28" fill="#fff" stroke="#000" stroke-width=".2"/>
<circle cx="179.9" cy="123.2" r=".49" fill="#008000" stroke="#008000" stroke-width=".2"/>
<circle cx="179.9" cy="123.2" r=".28" fill="#fff" stroke="#000" stroke-width=".2"/>
<circle cx="203.2" cy="137.8" r=".49" fill="#008000" stroke="#008000" stroke-width=".2"/>
<circle cx="203.2" cy="137.8" r=".28" fill="#fff" stroke="#000" stroke-width=".2"/>
<circle cx="143.9" cy="46.9" r=".49" fill="#008000" stroke="#008000" stroke-width=".2"/>
<circle cx="143.9" cy="46.9" r=".28" fill="#fff" stroke="#000" stroke-width=".2"/>
<circle cx="146.3" cy="30.1" r=".49" fill="#008000" stroke="#008000" stroke-width=".2"/>
<circle cx="146.3" cy="30.1" r=".28" fill="#fff" stroke="#000" stroke-width=".2"/>
<circle cx="151.8" cy="122.9" r=".49" fill="#008000" stroke="#008000" stroke-width=".2"/>
<circle cx="151.8" cy="122.9" r=".28" fill="#fff" stroke="#000" stroke-width=".2"/>
<circle cx="149.1" cy="118.4" r=".49" fill="#008000" stroke="#008000" stroke-width=".2"/>
<circle cx="149.1" cy="118.4" r=".28" fill="#fff" stroke="#000" stroke-width=".2"/>
<circle cx="158.5" cy="103.1" r=".49" fill="#008000" stroke="#008000" stroke-width=".2"/>
<circle cx="158.5" cy="103.1" r=".28" fill="#fff" stroke="#000" stroke-width=".2"/>
<circle cx="212" cy="103.1" r=".49" fill="#008000" stroke="#008000" stroke-width=".2"/>
<circle cx="212" cy="103.1" r=".28" fill="#fff" stroke="#000" stroke-width=".2"/>
<circle cx="158.8" cy="75.2" r=".49" fill="#008000" stroke="#008000" stroke-width=".2"/>
<circle cx="158.8" cy="75.2" r=".28" fill="#fff" stroke="#000" stroke-width=".2"/>
<circle cx="183.5" cy="44.9" r=".49" fill="#008000" stroke="#008000" stroke-width=".2"/>
<circle cx="183.5" cy="44.9" r=".28" fill="#fff" stroke="#000" stroke-width=".2"/>
<circle cx="188.9" cy="87" r=".49" fill="#008000" stroke="#008000" stroke-width=".2"/>
<circle cx="188.9" cy="87" r=".28" fill="#fff" stroke="#000" stroke-width=".2"/>
<circle cx="157.1" cy="97" r=".49" fill="#008000" stroke="#008000" stroke-width=".2"/>
<circle cx="157.1" cy="97" r=".28" fill="#fff" stroke="#000" stroke-width=".2"/>
<circle cx="198.4" cy="171" r=".49" fill="#008000" stroke="#008000" stroke-width=".2"/>
<circle cx="198.4" cy="171" r=".28" fill="#fff" stroke="#000" stroke-width=".2"/>
<circle cx="192.2" cy="164.1" r=".49" fill="#008000" stroke="#008000" stroke-width=".2"/>
<circle cx="192.2" cy="164.1" r=".28" fill="#fff" stroke="#000" stroke-width=".2"/>
<circle cx="222.3" cy="68.6" r=".49" fill="#008000" stroke="#008000" stroke-width=".2"/>
<circle cx="222.3" cy="68.6" r=".28" fill="#fff" stroke="#000" stroke-width=".2"/>
<circle cx="213.8" cy="72.1" r=".49" fill="#008000" stroke="#008000" stroke-width=".2"/>
<circle cx="213.8" cy="72.1" r=".28" fill="#fff" stroke="#000" stroke-width=".2"/>
<circle cx="156.8" cy="180.1" r=".49" fill="#008000" stroke="#008000" stroke-width=".2"/>
<circle cx="156.8" cy="180.1" r=".28" fill="#fff" stroke="#000" stroke-width=".2"/>
<circle cx="157.5" cy="183" r=".49" fill="#008000" stroke="#008000" stroke-width=".2"/>
<circle cx="157.5" cy="183" r=".28" fill="#fff" stroke="#000" stroke-width=".2"/>
<circle cx="217.5" cy="96.5" r=".49" fill="#008000" stroke="#008000" stroke-width=".2"/>
<circle cx="217.5" cy="96.5" r=".28" fill="#fff" stroke="#000" stroke-width=".2"/>
<circle cx="219.9" cy="97.8" r=".49" fill="#008000" stroke="#008000" stroke-width=".2"/>
<circle cx="219.9" cy="97.8" r=".28" fill="#fff" stroke="#000" stroke-width=".2"/>
<circle cx="150.3" cy="23.2" r=".49" fill="#008000" stroke="#008000" stroke-width=".2"/>
<circle cx="150.3" cy="23.2" r=".28" fill="#fff" stroke="#000" stroke-width=".2"/>
<circle cx="205.2" cy="116.5" r=".49" fill="#008000" stroke="#008000" stroke-width=".2"/>
<circle cx="205.2" cy="116.5" r=".28" fill="#fff" stroke="#000" stroke-width=".2"/>
<circle cx="219.3" cy="117.2" r=".49" fill="#008000" stroke="#008000" stroke-width=".2"/>
<circle cx="219.3" cy="117.2" r=".28" fill="#fff" stroke="#000" stroke-width=".2"/>
<circle cx="147.4" cy="37.7" r=".49" fill="#008000" stroke="#008000" stroke-width=".2"/>
<circle cx="147.4" cy="37.7" r=".28" fill="#fff" stroke="#000" stroke-width=".2"/>
<circle cx="193.4" cy="118.9" r=".49" fill="#008000" stroke="#008000" stroke-width=".2"/>
<circle cx="193.4" cy="118.9" r=".28" fill="#fff" stroke="#000" stroke-width=".2"/>
<circle cx="204.5" cy="119.2" r=".49" fill="#008000" stroke="#008000" stroke-width=".2"/>
<circle cx="204.5" cy="119.2" r=".28" fill="#fff" stroke="#000" stroke-width=".2"/>
<circle cx="175.3" cy="130.9" r=".49" fill="#008000" stroke="#008000" stroke-width=".2"/>
<circle cx="175.3" cy="130.9" r=".28" fill="#fff" stroke="#000" stroke-width=".2"/>
<circle cx="203.5" cy="152.5" r=".49" fill="#008000" stroke="#008000" stroke-width=".2"/>
<circle cx="203.5" cy="152.5" r=".28" fill="#fff" stroke="#000" stroke-width=".2"/>
<circle cx="135" cy="141.3" r=".49" fill="#008000" stroke="#008000" stroke-width=".2"/>
<circle cx="135" cy="141.3" r=".28" fill="#fff" stroke="#000" stroke-width=".2"/>
<circle cx="141.9" cy="69.2" r=".49" fill="#008000" stroke="#008000" stroke-width=".2"/>
<circle cx="141.9" cy="69.2" r=".28" fill="#fff" stroke="#000" stroke-width=".2"/>
<circle cx="169.3" cy="126.3" r=".49" fill="#008000" stroke="#008000" stroke-width=".2"/>
<circle cx="169.3" cy="126.3" r=".28" fill="#fff" stroke="#000" stroke-width=".2"/>
<circle cx="186.6" cy="82.6" r=".49" fill="#008000" stroke="#008000" stroke-width=".2"/>
<circle cx="186.6" cy="82.6" r=".28" fill="#fff" stroke="#000" stroke-width=".2"/>
<circle cx="146.5" cy="125.5" r=".49" fill="#008000" stroke="#008000" stroke-width=".2"/>
<circle cx="146.5" cy="125.5" r=".28" fill="#fff" stroke="#000" stroke-width=".2"/>
<circle cx="143.5" cy="114" r=".49" fill="#008000" stroke="#008000" stroke-width=".2"/>
<circle cx="143.5" cy="114" r=".28" fill="#fff" stroke="#000" stroke-width=".2"/>
<circle cx="171.4" cy="83" r=".49" fill="#008000" stroke="#008000" stroke-width=".2"/>
<circle cx="171.4" cy="83" r=".28" fill="#fff" stroke="#000" stroke-width=".2"/>
<circle cx="188.1" cy="178.8" r=".49" fill="#008000" stroke="#008000" stroke-width=".2"/>
<circle cx="188.1" cy="178.8" r=".28" fill="#fff" stroke="#000" stroke-width=".2"/>
<circle cx="183.4" cy="175.2" r=".49" fill="#008000" stroke="#008000" stroke-width=".2"/>
<circle cx="183.4" cy="175.2" r=".28" fill="#fff" stroke="#000" stroke-width=".2"/>
<circle cx="226.7" cy="82.4" r=".49" fill="#008000" stroke="#008000" stroke-width=".2"/>
<circle cx="226.7" cy="82.4" r=".28" fill="#fff" stroke="#000" stroke-width=".2"/>
<circle cx="221.4" cy="83.7" r=".49" fill="#008000" stroke="#008000" stroke-width=".2"/>
<circle cx="221.4" cy="83.7" r=".28" fill="#fff" stroke="#000" stroke-width=".2"/>
<circle cx="144.7" cy="13" r=".49" fill="#008000" stroke="#008000" stroke-width=".2"/>
<circle cx="144.7" cy="13" r=".28" fill="#fff" stroke="#000" stroke-width=".2"/>
<circle cx="144.3" cy="18.5" r=".49" fill="#008000" stroke="#008000" stroke-width=".2"/>
<circle cx="144.3" cy="18.5" r=".28" fill="#fff" stroke="#000" stroke-width=".2"/>
<circle cx="169.3" cy="176" r=".49" fill="#008000" stroke="#008000" stroke-width=".2"/>
<circle cx="169.3" cy="176" r=".28" fill="#fff" stroke="#000" stroke-width=".2"/>
<circle cx="171.5" cy="181.4" r=".49" fill="#008000" stroke="#008000" stroke-width=".2"/>
<circle cx="171.5" cy="181.4" r=".28" fill="#fff" stroke="#000" stroke-width=".2"/>
<circle cx="215.7" cy="85.2" r=".49" fill="#008000" stroke="#008000" stroke-width=".2"/>
<circle cx="215.7" cy="85.2" r=".28" fill="#fff" stroke="#000" stroke-width=".2"/>
<circle cx="201.4" cy="128.9" r=".49" fill="#008000" stroke="#008000" stroke-width=".2"/>
<circle cx="201.4" cy="128.9" r=".28" fill="#fff" stroke="#000" stroke-width=".2"/>
<circle cx="217.1" cy="135.4" r=".49" fill="#008000" stroke="#008000" stroke-width=".2"/>
<circle cx="217.1" cy="135.4" r=".28" fill="#fff" stroke="#000" stroke-width=".2"/>
<circle cx="160.7" cy="38.9" r=".49" fill="#008000" stroke="#008000" stroke-width=".2"/>
<circle cx="160.7" cy="38.9" r=".28" fill="#fff" stroke="#000" stroke-width=".2"/>
<circle cx="194.8" cy="112.5" r=".49" fill="#008000" stroke="#008000" stroke-width=".2"/>
<circle cx="194.8" cy="112.5" r=".28" fill="#fff" stroke="#000" stroke-width=".2"/>
<circle cx="222.5" cy="116.5" r=".49" fill="#008000" stroke="#008000" stroke-width=".2"/>
<circle cx="222.5" cy="116.5" r=".28" fill="#fff" stroke="#000" stroke-width=".2"/>
<circle cx="166.7" cy="139.1" r=".49" fill="#008000" stroke="#008000" stroke-width=".2"/>
<circle cx="166.7" cy="139.1" r=".28" fill="#fff" stroke="#000" stroke-width=".2"/>
<circle cx="147" cy="54" r=".49" fill="#008000" stroke="#008000" stroke-width=".2"/>
<circle cx="147" cy="54" r=".28" fill="#fff" stroke="#000" stroke-width=".2"/>
<circle cx="157.4" cy="20.3" r=".49" fill="#008000" stroke="#008000" stroke-width=".2"/>
<circle cx="157.4" cy="20.3" r=".28" fill="#fff" stroke="#000" stroke-width=".2"/>
<circle cx="149.9" cy="117.2" r=".49" fill="#008000" stroke="#008000" stroke-width=".2"/>
<circle cx="149.9" cy="117.2" r=".28" fill="#fff" stroke="#000" stroke-width=".2"/>
<circle cx="150.6" cy="103.1" r=".49" fill="#008000" stroke="#008000" stroke-width=".2"/>
<circle cx="150.6" cy="103.1" r=".28" fill="#fff" stroke="#000" stroke-width=".2"/>
<circle cx="156.7" cy="103.1" r=".49" fill="#008000" stroke="#008000" stroke-width=".2"/>
<circle cx="156.7" cy="103.1" r=".28" fill="#fff" stroke="#000" stroke-width=".2"/>
<circle cx="163.5" cy="134.9" r=".49" fill="#008000" stroke="#008000" stroke-width=".2"/>
<circle cx="163.5" cy="134.9" r=".28" fill="#fff" stroke="#000" stroke-width=".2"/>
<circle cx="137" cy="142.2" r=".49" fill="#008000" stroke="#008000" stroke-width=".2"/>
<circle cx="137" cy="142.2" r=".28" fill="#fff" stroke="#000" stroke-width=".2"/>
<circle cx="186.4" cy="81.1" r=".49" fill="#008000" stroke="#008000" stroke-width=".2"/>
<circle cx="186.4" cy="81.1" r=".28" fill="#fff" stroke="#000" stroke-width=".2"/>
<circle cx="137" cy="139.1" r=".49" fill="#008000" stroke="#008000" stroke-width=".2"/>
<circle cx="137" cy="139.1" r=".28" fill="#fff" stroke="#000" stroke-width=".2"/>
<circle cx="219.4" cy="76.6" r=".49" fill="#008000" stroke="#008000" stroke-width=".2"/>
<circle cx="219.4" cy="76.6" r=".28" fill="#fff" stroke="#000" stroke-width=".2"/>
<circle cx="165.6" cy="22.6" r=".49" fill="#008000" stroke="#008000" stroke-width=".2"/>
<circle cx="165.6" cy="22.6" r=".28" fill="#fff" stroke="#000" stroke-width=".2"/>
<circle cx="189.3" cy="171.3" r=".49" fill="#008000" stroke="#008000" stroke-width=".2"/>
<circle cx="189.3" cy="171.3" r=".28" fill="#fff" stroke="#000" stroke-width=".2"/>
<circle cx="178.8" cy="184.1" r=".49" fill="#008000" stroke="#008000" stroke-width=".2"/>
<circle cx="178.8" cy="184.1" r=".28" fill="#fff" stroke="#000" stroke-width=".2"/>
<circle cx="176.8" cy="180.3" r=".49" fill="#008000" stroke="#008000" stroke-width=".2"/>
<circle cx="176.8" cy="180.3" r=".28" fill="#fff" stroke="#000" stroke-width=".2"/>
<circle cx="228.7" cy="94" r=".49" fill="#008000" stroke="#008000" stroke-width=".2"/>
<circle cx="228.7" cy="94" r=".28" fill="#fff" stroke="#000" stroke-width=".2"/>
<circle cx="224.5" cy="94.5" r=".49" fill="#008000" stroke="#008000" stroke-width=".2"/>
<circle cx="224.5" cy="94.5" r=".28" fill="#fff" stroke="#000" stroke-width=".2"/>
<circle cx="156.4" cy="14.5" r=".49" fill="#008000" stroke="#008000" stroke-width=".2"/>
<circle cx="156.4" cy="14.5" r=".28" fill="#fff" stroke="#000" stroke-width=".2"/>
<circle cx="155.7" cy="18.6" r=".49" fill="#008000" stroke="#008000" stroke-width=".2"/>
<circle cx="155.7" cy="18.6" r=".28" fill="#fff" stroke="#000" stroke-width=".2"/>
<circle cx="179.7" cy="170.7" r=".49" fill="#008000" stroke="#008000" stroke-width=".2"/>
<circle cx="179.7" cy="170.7" r=".28" fill="#fff" stroke="#000" stroke-width=".2"/>
<circle cx="182.1" cy="177.6" r=".49" fill="#008000" stroke="#008000" stroke-width=".2"/>
<circle cx="182.1" cy="177.6" r=".28" fill="#fff" stroke="#000" stroke-width=".2"/>
<circle cx="211.8" cy="72.9" r=".49" fill="#008000" stroke="#008000" stroke-width=".2"/>
<circle cx="211.8" cy="72.9" r=".28" fill="#fff" stroke="#000" stroke-width=".2"/>
<circle cx="219.4" cy="72.6" r=".49" fill="#008000" stroke="#008000" stroke-width=".2"/>
<circle cx="219.4" cy="72.6" r=".28" fill="#fff" stroke="#000" stroke-width=".2"/>
<circle cx="194.5" cy="141.7" r=".49" fill="#008000" stroke="#008000" stroke-width=".2"/>
<circle cx="194.5" cy="141.7" r=".28" fill="#fff" stroke="#000" stroke-width=".2"/>
<circle cx="208.7" cy="153.4" r=".49" fill="#008000" stroke="#008000" stroke-width=".2"/>
<circle cx="208.7" cy="153.4" r=".28" fill="#fff" stroke="#000" stroke-width=".2"/>
<circle cx="171.1" cy="43.4" r=".49" fill="#008000" stroke="#008000" stroke-width=".2"/>
<circle cx="171.1" cy="43.4" r=".28" fill="#fff" stroke="#000" stroke-width=".2"/>
<circle cx="179.6" cy="27.2" r=".49" fill="#008000" stroke="#008000" stroke-width=".2"/>
<circle cx="179.6" cy="27.2" r=".28" fill="#fff" stroke="#000" stroke-width=".2"/>
<circle cx="195.6" cy="100.4" r=".49" fill="#008000" stroke="#008000" stroke-width=".2"/>
<circle cx="195.6" cy="100.4" r=".28" fill="#fff" stroke="#000" stroke-width=".2"/>
<circle cx="225" cy="103.1" r=".49" fill="#008000" stroke="#008000" stroke-width=".2"/>
<circle cx="225" cy="103.1" r=".28" fill="#fff" stroke="#000" stroke-width=".2"/>
<circle cx="157.8" cy="131.8" r=".49" fill="#008000" stroke="#008000" stroke-width=".2"/>
<circle cx="157.8" cy="131.8" r=".28" fill="#fff" stroke="#000" stroke-width=".2"/>
<circle cx="156.7" cy="145.5" r=".49" fill="#008000" stroke="#008000" stroke-width=".2"/>
<circle cx="156.7" cy="145.5" r=".28" fill="#fff" stroke="#000" stroke-width=".2"/>
<circle cx="159.2" cy="62.2" r=".49" fill="#008000" stroke="#008000" stroke-width=".2"/>
<circle cx="159.2" cy="62.2" r=".28" fill="#fff" stroke="#000" stroke-width=".2"/>
<circle cx="144.5" cy="92.3" r=".49" fill="#008000" stroke="#008000" stroke-width=".2"/>
<circle cx="144.5" cy="92.3" r=".28" fill="#fff" stroke="#000" stroke-width=".2"/>
<circle cx="185.9" cy="79.9" r=".49" fill="#008000" stroke="#008000" stroke-width=".2"/>
<circle cx="185.9" cy="79.9" r=".28" fill="#fff" stroke="#000" stroke-width=".2"/>
<circle cx="215.6" cy="64.1" r=".49" fill="#008000" stroke="#008000" stroke-width=".2"/>
<circle cx="215.6" cy="64.1" r=".28" fill="#fff" stroke="#000" stroke-width=".2"/>
<circle cx="165.7" cy="184.6" r=".49" fill="#008000" stroke="#008000" stroke-width=".2"/>
<circle cx="165.7" cy="184.6" r=".28" fill="#fff" stroke="#000" stroke-width=".2"/>
<circle cx="166.4" cy="189.1" r=".49" fill="#008000" stroke="#008000" stroke-width=".2"/>
<circle cx="166.4" cy="189.1" r=".28" fill="#fff" stroke="#000" stroke-width=".2"/>
<circle cx="168.2" cy="194.5" r=".49" fill="#008000" stroke="#008000" stroke-width=".2"/>
<circle cx="168.2" cy="194.5" r=".28" fill="#fff" stroke="#000" stroke-width=".2"/>
<circle cx="229.1" cy="103.1" r=".49" fill="#008000" stroke="#008000" stroke-width=".2"/>
<circle cx="229.1" cy="103.1" r=".28" fill="#fff" stroke="#000" stroke-width=".2"/>
<circle cx="234.9" cy="103.1" r=".49" fill="#008000" stroke="#008000" stroke-width=".2"/>
<circle cx="234.9" cy="103.1" r=".28" fill="#fff" stroke="#000" stroke-width=".2"/>
<circle cx="167.8" cy="17.5" r=".49" fill="#008000" stroke="#008000" stroke-width=".2"/>
<circle cx="167.8" cy="17.5" r=".28" fill="#fff" stroke="#000" stroke-width=".2"/>
<circle cx="169.6" cy="12.1" r=".49" fill="#008000" stroke="#008000" stroke-width=".2"/>
<circle cx="169.6" cy="12.1" r=".28" fill="#fff" stroke="#000" stroke-width=".2"/>
<circle cx="189.1" cy="163.9" r=".49" fill="#008000" stroke="#008000" stroke-width=".2"/>
<circle cx="189.1" cy="163.9" r=".28" fill="#fff" stroke="#000" stroke-width=".2"/>
<circle cx="199.6" cy="177.5" r=".49" fill="#008000" stroke="#008000" stroke-width=".2"/>
<circle cx="199.6" cy="177.5" r=".28" fill="#fff" stroke="#000" stroke-width=".2"/>
<circle cx="206.1" cy="61.5" r=".49" fill="#008000" stroke="#008000" stroke-width=".2"/>
<circle cx="206.1" cy="61.5" r=".28" fill="#fff" stroke="#000" stroke-width=".2"/>
<circle cx="220.5" cy="52.5" r=".49" fill="#008000" stroke="#008000" stroke-width=".2"/>
<circle cx="220.5" cy="52.5" r=".28" fill="#fff" stroke="#000" stroke-width=".2"/>
<circle cx="186.6" cy="151" r=".49" fill="#008000" stroke="#008000" stroke-width=".2"/>
<circle cx="186.6" cy="151" r=".28" fill="#fff" stroke="#000" stroke-width=".2"/>
<circle cx="181.8" cy="50.7" r=".49" fill="#008000" stroke="#008000" stroke-width=".2"/>
<circle cx="181.8" cy="50.7" r=".28" fill="#fff" stroke="#000" stroke-width=".2"/>
<circle cx="167.8" cy="67.9" r=".49" fill="#008000" stroke="#008000" stroke-width=".2"/>
<circle cx="167.8" cy="67.9" r=".28" fill="#fff" stroke="#000" stroke-width=".2"/>
<circle cx="199.5" cy="28.6" r=".49" fill="#008000" stroke="#008000" stroke-width=".2"/>
<circle cx="199.5" cy="28.6" r=".28" fill="#fff" stroke="#000" stroke-width=".2"/>
<circle cx="193.5" cy="87.3" r=".49" fill="#008000" stroke="#008000" stroke-width=".2"/>
<circle cx="193.5" cy="87.3" r=".28" fill="#fff" stroke="#000" stroke-width=".2"/>
<circle cx="231.6" cy="78.2" r=".49" fill="#008000" stroke="#008000" stroke-width=".2"/>
<circle cx="231.6" cy="78.2" r=".28" fill="#fff" stroke="#000" stroke-width=".2"/>
<circle cx="187.3" cy="90.1" r=".49" fill="#008000" stroke="#008000" stroke-width=".2"/>
<circle cx="187.3" cy="90.1" r=".28" fill="#fff" stroke="#000" stroke-width=".2"/>
<circle cx="136.3" cy="143.2" r=".49" fill="#008000" stroke="#008000" stroke-width=".2"/>
<circle cx="136.3" cy="143.2" r=".28" fill="#fff" stroke="#000" stroke-width=".2"/>
<circle cx="133.5" cy="199.1" r=".49" fill="#008000" stroke="#008000" stroke-width=".2"/>
<circle cx="133.5" cy="199.1" r=".28" fill="#fff" stroke="#000" stroke-width=".2"/>
<circle cx="164.5" cy="125.8" r=".49" fill="#008000" stroke="#008000" stroke-width=".2"/>
<circle cx="164.5" cy="125.8" r=".28" fill="#fff" stroke="#000" stroke-width=".2"/>
<circle cx="157.9" cy="120.3" r=".49" fill="#008000" stroke="#008000" stroke-width=".2"/>
<circle cx="157.9" cy="120.3" r=".28" fill="#fff" stroke="#000" stroke-width=".2"/>
<circle cx="133.9" cy="143.1" r=".49" fill="#008000" stroke="#008000" stroke-width=".2"/>
<circle cx="133.9" cy="143.1" r=".28" fill="#fff" stroke="#000" stroke-width=".2"/>
<circle cx="137.6" cy="128.5" r=".49" fill="#008000" stroke="#008000" stroke-width=".2"/>
<circle cx="137.6" cy="128.5" r=".28" fill="#fff" stroke="#000" stroke-width=".2"/>
<circle cx="154.7" cy="98.7" r=".49" fill="#008000" stroke="#008000" stroke-width=".2"/>
<circle cx="154.7" cy="98.7" r=".28" fill="#fff" stroke="#000" stroke-width=".2"/>
<circle cx="154.9" cy="191.9" r=".49" fill="#008000" stroke="#008000" stroke-width=".2"/>
<circle cx="154.9" cy="191.9" r=".28" fill="#fff" stroke="#000" stroke-width=".2"/>
<circle cx="155.6" cy="195.3" r=".49" fill="#008000" stroke="#008000" stroke-width=".2"/>
<circle cx="155.6" cy="195.3" r=".28" fill="#fff" stroke="#000" stroke-width=".2"/>
<circle cx="227.7" cy="118.9" r=".49" fill="#008000" stroke="#008000" stroke-width=".2"/>
<circle cx="227.7" cy="118.9" r=".28" fill="#fff" stroke="#000" stroke-width=".2"/>
<circle cx="231.1" cy="119.5" r=".49" fill="#008000" stroke="#008000" stroke-width=".2"/>
<circle cx="231.1" cy="119.5" r=".28" fill="#fff" stroke="#000" stroke-width=".2"/>
<circle cx="181.5" cy="23.5" r=".49" fill="#008000" stroke="#008000" stroke-width=".2"/>
<circle cx="181.5" cy="23.5" r=".28" fill="#fff" stroke="#000" stroke-width=".2"/>
<circle cx="183.1" cy="20.5" r=".49" fill="#008000" stroke="#008000" stroke-width=".2"/>
<circle cx="183.1" cy="20.5" r=".28" fill="#fff" stroke="#000" stroke-width=".2"/>
<circle cx="198.8" cy="154.6" r=".49" fill="#008000" stroke="#008000" stroke-width=".2"/>
<circle cx="198.8" cy="154.6" r=".28" fill="#fff" stroke="#000" stroke-width=".2"/>
<circle cx="199.1" cy="51.9" r=".49" fill="#008000" stroke="#008000" stroke-width=".2"/>
<circle cx="199.1" cy="51.9" r=".28" fill="#fff" stroke="#000" stroke-width=".2"/>
<circle cx="191.4" cy="60.3" r=".49" fill="#008000" stroke="#008000" stroke-width=".2"/>
<circle cx="191.4" cy="60.3" r=".28" fill="#fff" stroke="#000" stroke-width=".2"/>
<circle cx="211.3" cy="43.7" r=".49" fill="#008000" stroke="#008000" stroke-width=".2"/>
<circle cx="211.3" cy="43.7" r=".28" fill="#fff" stroke="#000" stroke-width=".2"/>
<circle cx="178.2" cy="158.2" r=".49" fill="#008000" stroke="#008000" stroke-width=".2"/>
<circle cx="178.2" cy="158.2" r=".28" fill="#fff" stroke="#000" stroke-width=".2"/>
<circle cx="173" cy="150.9" r=".49" fill="#008000" stroke="#008000" stroke-width=".2"/>
<circle cx="173" cy="150.9" r=".28" fill="#fff" stroke="#000" stroke-width=".2"/>
<circle cx="188" cy="74.7" r=".49" fill="#008000" stroke="#008000" stroke-width=".2"/>
<circle cx="188" cy="74.7" r=".28" fill="#fff" stroke="#000" stroke-width=".2"/>
<circle cx="176.9" cy="77.8" r=".49" fill="#008000" stroke="#008000" stroke-width=".2"/>
<circle cx="176.9" cy="77.8" r=".28" fill="#fff" stroke="#000" stroke-width=".2"/>
<circle cx="170.6" cy="116.2" r=".49" fill="#008000" stroke="#008000" stroke-width=".2"/>
<circle cx="170.6" cy="116.2" r=".28" fill="#fff" stroke="#000" stroke-width=".2"/>
<circle cx="226.2" cy="136.2" r=".49" fill="#008000" stroke="#008000" stroke-width=".2"/>
<circle cx="226.2" cy="136.2" r=".28" fill="#fff" stroke="#000" stroke-width=".2"/>
<circle cx="154.2" cy="85.2" r=".49" fill="#008000" stroke="#008000" stroke-width=".2"/>
<circle cx="154.2" cy="85.2" r=".28" fill="#fff" stroke="#000" stroke-width=".2"/>
<circle cx="156.6" cy="79.7" r=".49" fill="#008000" stroke="#008000" stroke-width=".2"/>
<circle cx="156.6" cy="79.7" r=".28" fill="#fff" stroke="#000" stroke-width=".2"/>
<circle cx="163.5" cy="86.9" r=".49" fill="#008000" stroke="#008000" stroke-width=".2"/>
<circle cx="163.5" cy="86.9" r=".28" fill="#fff" stroke="#000" stroke-width=".2"/>
<circle cx="220.1" cy="56.2" r=".49" fill="#008000" stroke="#008000" stroke-width=".2"/>
<circle cx="220.1" cy="56.2" r=".28" fill="#fff" stroke="#000" stroke-width=".2"/>
<circle cx="166.5" cy="69.5" r=".49" fill="#008000" stroke="#008000" stroke-width=".2"/>
<circle cx="166.5" cy="69.5" r=".28" fill="#fff" stroke="#000" stroke-width=".2"/>
<circle cx="211.1" cy="162.8" r=".49" fill="#008000" stroke="#008000" stroke-width=".2"/>
<circle cx="211.1" cy="162.8" r=".28" fill="#fff" stroke="#000" stroke-width=".2"/>
<circle cx="193.5" cy="179.2" r=".49" fill="#008000" stroke="#008000" stroke-width=".2"/>
<circle cx="193.5" cy="179.2" r=".28" fill="#fff" stroke="#000" stroke-width=".2"/>
<circle cx="183.5" cy="141.4" r=".49" fill="#008000" stroke="#008000" stroke-width=".2"/>
<circle cx="183.5" cy="141.4" r=".28" fill="#fff" stroke="#000" stroke-width=".2"/>
<circle cx="182.4" cy="88.9" r=".49" fill="#008000" stroke="#008000" stroke-width=".2"/>
<circle cx="182.4" cy="88.9" r=".28" fill="#fff" stroke="#000" stroke-width=".2"/>
<circle cx="161.1" cy="95.4" r=".49" fill="#008000" stroke="#008000" stroke-width=".2"/>
<circle cx="161.1" cy="95.4" r=".28" fill="#fff" stroke="#000" stroke-width=".2"/>
<circle cx="134.1" cy="192.8" r=".49" fill="#008000" stroke="#008000" stroke-width=".2"/>
<circle cx="134.1" cy="192.8" r=".28" fill="#fff" stroke="#000" stroke-width=".2"/>
<circle cx="134.1" cy="194.9" r=".49" fill="#008000" stroke="#008000" stroke-width=".2"/>
<circle cx="134.1" cy="194.9" r=".28" fill="#fff" stroke="#000" stroke-width=".2"/>
<circle cx="224.5" cy="136.5" r=".49" fill="#008000" stroke="#008000" stroke-width=".2"/>
<circle cx="224.5" cy="136.5" r=".28" fill="#fff" stroke="#000" stroke-width=".2"/>
<circle cx="205.2" cy="144.3" r=".49" fill="#008000" stroke="#008000" stroke-width=".2"/>
<circle cx="205.2" cy="144.3" r=".28" fill="#fff" stroke="#000" stroke-width=".2"/>
<circle cx="217.3" cy="151.7" r=".49" fill="#008000" stroke="#008000" stroke-width=".2"/>
<circle cx="217.3" cy="151.7" r=".28" fill="#fff" stroke="#000" stroke-width=".2"/>
<circle cx="189.8" cy="42.8" r=".49" fill="#008000" stroke="#008000" stroke-width=".2"/>
<circle cx="189.8" cy="42.8" r=".28" fill="#fff" stroke="#000" stroke-width=".2"/>
<circle cx="197.7" cy="35.9" r=".49" fill="#008000" stroke="#008000" stroke-width=".2"/>
<circle cx="197.7" cy="35.9" r=".28" fill="#fff" stroke="#000" stroke-width=".2"/>
<circle cx="199.5" cy="34" r=".49" fill="#008000" stroke="#008000" stroke-width=".2"/>
<circle cx="199.5" cy="34" r=".28" fill="#fff" stroke="#000" stroke-width=".2"/>
<circle cx="166.5" cy="165" r=".49" fill="#008000" stroke="#008000" stroke-width=".2"/>
<circle cx="166.5" cy="165" r=".28" fill="#fff" stroke="#000" stroke-width=".2"/>
<circle cx="176.7" cy="187.2" r=".49" fill="#008000" stroke="#008000" stroke-width=".2"/>
<circle cx="176.7" cy="187.2" r=".28" fill="#fff" stroke="#000" stroke-width=".2"/>
<circle cx="199.8" cy="75.8" r=".49" fill="#008000" stroke="#008000" stroke-width=".2"/>
<circle cx="199.8" cy="75.8" r=".28" fill="#fff" stroke="#000" stroke-width=".2"/>
<circle cx="223" cy="65.1" r=".49" fill="#008000" stroke="#008000" stroke-width=".2"/>
<circle cx="223" cy="65.1" r=".28" fill="#fff" stroke="#000" stroke-width=".2"/>
<circle cx="160.9" cy="155.9" r=".49" fill="#008000" stroke="#008000" stroke-width=".2"/>
<circle cx="160.9" cy="155.9" r=".28" fill="#fff" stroke="#000" stroke-width=".2"/>
<circle cx="176.8" cy="62.1" r=".49" fill="#008000" stroke="#008000" stroke-width=".2"/>
<circle cx="176.8" cy="62.1" r=".28" fill="#fff" stroke="#000" stroke-width=".2"/>
<circle cx="163.1" cy="105" r=".49" fill="#008000" stroke="#008000" stroke-width=".2"/>
<circle cx="163.1" cy="105" r=".28" fill="#fff" stroke="#000" stroke-width=".2"/>
<circle cx="161.1" cy="104.6" r=".49" fill="#008000" stroke="#008000" stroke-width=".2"/>
<circle cx="161.1" cy="104.6" r=".28" fill="#fff" stroke="#000" stroke-width=".2"/>
<circle cx="231.1" cy="110.8" r=".49" fill="#008000" stroke="#008000" stroke-width=".2"/>
<circle cx="231.1" cy="110.8" r=".28" fill="#fff" stroke="#000" stroke-width=".2"/>
<circle cx="169.9" cy="180.8" r=".49" fill="#008000" stroke="#008000" stroke-width=".2"/>
<circle cx="169.9" cy="180.8" r=".28" fill="#fff" stroke="#000" stroke-width=".2"/>
<circle cx="170.9" cy="187.8" r=".49" fill="#008000" stroke="#008000" stroke-width=".2"/>
<circle cx="170.9" cy="187.8" r=".28" fill="#fff" stroke="#000" stroke-width=".2"/>
<circle cx="175.6" cy="178.1" r=".49" fill="#008000" stroke="#008000" stroke-width=".2"/>
<circle cx="175.6" cy="178.1" r=".28" fill="#fff" stroke="#000" stroke-width=".2"/>
<circle cx="176.7" cy="183.9" r=".49" fill="#008000" stroke="#008000" stroke-width=".2"/>
<circle cx="176.7" cy="183.9" r=".28" fill="#fff" stroke="#000" stroke-width=".2"/>
<circle cx="177.3" cy="177.1" r=".49" fill="#008000" stroke="#008000" stroke-width=".2"/>
<circle cx="177.3" cy="177.1" r=".28" fill="#fff" stroke="#000" stroke-width=".2"/>
<circle cx="178.9" cy="180.5" r=".49" fill="#008000" stroke="#008000" stroke-width=".2"/>
<circle cx="178.9" cy="180.5" r=".28" fill="#fff" stroke="#000" stroke-width=".2"/>
<circle cx="186.9" cy="171.6" r=".49" fill="#008000" stroke="#008000" stroke-width=".2"/>
<circle cx="186.9" cy="171.6" r=".28" fill="#fff" stroke="#000" stroke-width=".2"/>
<circle cx="193.4" cy="181" r=".49" fill="#008000" stroke="#008000" stroke-width=".2"/>
<circle cx="193.4" cy="181" r=".28" fill="#fff" stroke="#000" stroke-width=".2"/>
<circle cx="210.5" cy="40.6" r=".49" fill="#008000" stroke="#008000" stroke-width=".2"/>
<circle cx="210.5" cy="40.6" r=".28" fill="#fff" stroke="#000" stroke-width=".2"/>
<circle cx="206.9" cy="43.8" r=".49" fill="#008000" stroke="#008000" stroke-width=".2"/>
<circle cx="206.9" cy="43.8" r=".28" fill="#fff" stroke="#000" stroke-width=".2"/>
<circle cx="188.6" cy="170.3" r=".49" fill="#008000" stroke="#008000" stroke-width=".2"/>
<circle cx="188.6" cy="170.3" r=".28" fill="#fff" stroke="#000" stroke-width=".2"/>
<circle cx="170" cy="145.1" r=".49" fill="#008000" stroke="#008000" stroke-width=".2"/>
<circle cx="170" cy="145.1" r=".28" fill="#fff" stroke="#000" stroke-width=".2"/>
<circle cx="224.7" cy="127.4" r=".49" fill="#008000" stroke="#008000" stroke-width=".2"/>
<circle cx="224.7" cy="127.4" r=".28" fill="#fff" stroke="#000" stroke-width=".2"/>
<circle cx="188.7" cy="118.9" r=".49" fill="#008000" stroke="#008000" stroke-width=".2"/>
<circle cx="188.7" cy="118.9" r=".28" fill="#fff" stroke="#000" stroke-width=".2"/>
<circle cx="198.4" cy="168.2" r=".49" fill="#008000" stroke="#008000" stroke-width=".2"/>
<circle cx="198.4" cy="168.2" r=".28" fill="#fff" stroke="#000" stroke-width=".2"/>
<circle cx="220.6" cy="136.2" r=".49" fill="#008000" stroke="#008000" stroke-width=".2"/>
<circle cx="220.6" cy="136.2" r=".28" fill="#fff" stroke="#000" stroke-width=".2"/>
<circle cx="186.6" cy="36.8" r=".49" fill="#008000" stroke="#008000" stroke-width=".2"/>
<circle cx="186.6" cy="36.8" r=".28" fill="#fff" stroke="#000" stroke-width=".2"/>
<circle cx="192.2" cy="28.9" r=".49" fill="#008000" stroke="#008000" stroke-width=".2"/>
<circle cx="192.2" cy="28.9" r=".28" fill="#fff" stroke="#000" stroke-width=".2"/>
<circle cx="198.6" cy="161.6" r=".49" fill="#008000" stroke="#008000" stroke-width=".2"/>
<circle cx="198.6" cy="161.6" r=".28" fill="#fff" stroke="#000" stroke-width=".2"/>
<circle cx="189.8" cy="151.4" r=".49" fill="#008000" stroke="#008000" stroke-width=".2"/>
<circle cx="189.8" cy="151.4" r=".28" fill="#fff" stroke="#000" stroke-width=".2"/>
<circle cx="150.5" cy="31.8" r=".49" fill="#008000" stroke="#008000" stroke-width=".2"/>
<circle cx="150.5" cy="31.8" r=".28" fill="#fff" stroke="#000" stroke-width=".2"/>
<circle cx="153.6" cy="13" r=".49" fill="#008000" stroke="#008000" stroke-width=".2"/>
<circle cx="153.6" cy="13" r=".28" fill="#fff" stroke="#000" stroke-width=".2"/>
<circle cx="167.5" cy="30.6" r=".49" fill="#008000" stroke="#008000" stroke-width=".2"/>
<circle cx="167.5" cy="30.6" r=".28" fill="#fff" stroke="#000" stroke-width=".2"/>
<circle cx="170.5" cy="19.6" r=".49" fill="#008000" stroke="#008000" stroke-width=".2"/>
<circle cx="170.5" cy="19.6" r=".28" fill="#fff" stroke="#000" stroke-width=".2"/>
<circle cx="202.8" cy="156.7" r=".49" fill="#008000" stroke="#008000" stroke-width=".2"/>
<circle cx="202.8" cy="156.7" r=".28" fill="#fff" stroke="#000" stroke-width=".2"/>
<circle cx="167.3" cy="126.9" r=".49" fill="#008000" stroke="#008000" stroke-width=".2"/>
<circle cx="167.3" cy="126.9" r=".28" fill="#fff" stroke="#000" stroke-width=".2"/>
<circle cx="159.9" cy="29.2" r=".49" fill="#008000" stroke="#008000" stroke-width=".2"/>
<circle cx="159.9" cy="29.2" r=".28" fill="#fff" stroke="#000" stroke-width=".2"/>
<circle cx="148.4" cy="69" r=".49" fill="#008000" stroke="#008000" stroke-width=".2"/>
<circle cx="148.4" cy="69" r=".28" fill="#fff" stroke="#000" stroke-width=".2"/>
<circle cx="156.3" cy="29.2" r=".49" fill="#008000" stroke="#008000" stroke-width=".2"/>
<circle cx="156.3" cy="29.2" r=".28" fill="#fff" stroke="#000" stroke-width=".2"/>
<circle cx="158.8" cy="18.2" r=".49" fill="#008000" stroke="#008000" stroke-width=".2"/>
<circle cx="158.8" cy="18.2" r=".28" fill="#fff" stroke="#000" stroke-width=".2"/>
<circle cx="210.4" cy="146.2" r=".49" fill="#008000" stroke="#008000" stroke-width=".2"/>
<circle cx="210.4" cy="146.2" r=".28" fill="#fff" stroke="#000" stroke-width=".2"/>
<circle cx="189.3" cy="133.5" r=".49" fill="#008000" stroke="#008000" stroke-width=".2"/>
<circle cx="189.3" cy="133.5" r=".28" fill="#fff" stroke="#000" stroke-width=".2"/>
<circle cx="153.7" cy="45" r=".49" fill="#008000" stroke="#008000" stroke-width=".2"/>
<circle cx="153.7" cy="45" r=".28" fill="#fff" stroke="#000" stroke-width=".2"/>
<circle cx="212.8" cy="142.2" r=".49" fill="#008000" stroke="#008000" stroke-width=".2"/>
<circle cx="212.8" cy="142.2" r=".28" fill="#fff" stroke="#000" stroke-width=".2"/>
<circle cx="216.3" cy="134.1" r=".49" fill="#008000" stroke="#008000" stroke-width=".2"/>
<circle cx="216.3" cy="134.1" r=".28" fill="#fff" stroke="#000" stroke-width=".2"/>
<circle cx="210.1" cy="131.6" r=".49" fill="#008000" stroke="#008000" stroke-width=".2"/>
<circle cx="210.1" cy="131.6" r=".28" fill="#fff" stroke="#000" stroke-width=".2"/>
<circle cx="218" cy="130.1" r=".49" fill="#008000" stroke="#008000" stroke-width=".2"/>
<circle cx="218" cy="130.1" r=".28" fill="#fff" stroke="#000" stroke-width=".2"/>
<circle cx="211.1" cy="129.2" r=".49" fill="#008000" stroke="#008000" stroke-width=".2"/>
<circle cx="211.1" cy="129.2" r=".28" fill="#fff" stroke="#000" stroke-width=".2"/>
<circle cx="143.1" cy="171.7" r=".49" fill="#008000" stroke="#008000" stroke-width=".2"/>
<circle cx="143.1" cy="171.7" r=".28" fill="#fff" stroke="#000" stroke-width=".2"/>
<circle cx="144.1" cy="182.7" r=".49" fill="#008000" stroke="#008000" stroke-width=".2"/>
<circle cx="144.1" cy="182.7" r=".28" fill="#fff" stroke="#000" stroke-width=".2"/>
<circle cx="218.5" cy="128.7" r=".49" fill="#008000" stroke="#008000" stroke-width=".2"/>
<circle cx="218.5" cy="128.7" r=".28" fill="#fff" stroke="#000" stroke-width=".2"/>
<circle cx="210.2" cy="124.4" r=".49" fill="#008000" stroke="#008000" stroke-width=".2"/>
<circle cx="210.2" cy="124.4" r=".28" fill="#fff" stroke="#000" stroke-width=".2"/>
<circle cx="154.2" cy="175.9" r=".49" fill="#008000" stroke="#008000" stroke-width=".2"/>
<circle cx="154.2" cy="175.9" r=".28" fill="#fff" stroke="#000" stroke-width=".2"/>
<circle cx="155.2" cy="181.4" r=".49" fill="#008000" stroke="#008000" stroke-width=".2"/>
<circle cx="155.2" cy="181.4" r=".28" fill="#fff" stroke="#000" stroke-width=".2"/>
<circle cx="151.1" cy="166" r=".49" fill="#008000" stroke="#008000" stroke-width=".2"/>
<circle cx="151.1" cy="166" r=".28" fill="#fff" stroke="#000" stroke-width=".2"/>
<circle cx="153.9" cy="179.6" r=".49" fill="#008000" stroke="#008000" stroke-width=".2"/>
<circle cx="153.9" cy="179.6" r=".28" fill="#fff" stroke="#000" stroke-width=".2"/>
<circle cx="220.4" cy="121.9" r=".49" fill="#008000" stroke="#008000" stroke-width=".2"/>
<circle cx="220.4" cy="121.9" r=".28" fill="#fff" stroke="#000" stroke-width=".2"/>
<circle cx="197.3" cy="116.3" r=".49" fill="#008000" stroke="#008000" stroke-width=".2"/>
<circle cx="197.3" cy="116.3" r=".28" fill="#fff" stroke="#000" stroke-width=".2"/>
<circle cx="150.3" cy="161.9" r=".49" fill="#008000" stroke="#008000" stroke-width=".2"/>
<circle cx="150.3" cy="161.9" r=".28" fill="#fff" stroke="#000" stroke-width=".2"/>
<circle cx="145" cy="167.3" r=".49" fill="#008000" stroke="#008000" stroke-width=".2"/>
<circle cx="145" cy="167.3" r=".28" fill="#fff" stroke="#000" stroke-width=".2"/>
<circle cx="145.3" cy="178.7" r=".49" fill="#008000" stroke="#008000" stroke-width=".2"/>
<circle cx="145.3" cy="178.7" r=".28" fill="#fff" stroke="#000" stroke-width=".2"/>
<circle cx="221.3" cy="115.4" r=".49" fill="#008000" stroke="#008000" stroke-width=".2"/>
<circle cx="221.3" cy="115.4" r=".28" fill="#fff" stroke="#000" stroke-width=".2"/>
<circle cx="199.6" cy="111.1" r=".49" fill="#008000" stroke="#008000" stroke-width=".2"/>
<circle cx="199.6" cy="111.1" r=".28" fill="#fff" stroke="#000" stroke-width=".2"/>
<circle cx="138.8" cy="164.4" r=".49" fill="#008000" stroke="#008000" stroke-width=".2"/>
<circle cx="138.8" cy="164.4" r=".28" fill="#fff" stroke="#000" stroke-width=".2"/>
<circle cx="222.4" cy="104.1" r=".49" fill="#008000" stroke="#008000" stroke-width=".2"/>
<circle cx="222.4" cy="104.1" r=".28" fill="#fff" stroke="#000" stroke-width=".2"/>
<circle cx="207.5" cy="105.2" r=".49" fill="#008000" stroke="#008000" stroke-width=".2"/>
<circle cx="207.5" cy="105.2" r=".28" fill="#fff" stroke="#000" stroke-width=".2"/>
<circle cx="222.3" cy="97.6" r=".49" fill="#008000" stroke="#008000" stroke-width=".2"/>
<circle cx="222.3" cy="97.6" r=".28" fill="#fff" stroke="#000" stroke-width=".2"/>
<circle cx="205.4" cy="99.7" r=".49" fill="#008000" stroke="#008000" stroke-width=".2"/>
<circle cx="205.4" cy="99.7" r=".28" fill="#fff" stroke="#000" stroke-width=".2"/>
<circle cx="222.3" cy="95.8" r=".49" fill="#008000" stroke="#008000" stroke-width=".2"/>
<circle cx="222.3" cy="95.8" r=".28" fill="#fff" stroke="#000" stroke-width=".2"/>
<circle cx="202.3" cy="96.9" r=".49" fill="#008000" stroke="#008000" stroke-width=".2"/>
<circle cx="202.3" cy="96.9" r=".28" fill="#fff" stroke="#000" stroke-width=".2"/>
<circle cx="158.7" cy="37.3" r=".49" fill="#008000" stroke="#008000" stroke-width=".2"/>
<circle cx="158.7" cy="37.3" r=".28" fill="#fff" stroke="#000" stroke-width=".2"/>
<circle cx="155.7" cy="47.8" r=".49" fill="#008000" stroke="#008000" stroke-width=".2"/>
<circle cx="155.7" cy="47.8" r=".28" fill="#fff" stroke="#000" stroke-width=".2"/>
<circle cx="219.3" cy="89.1" r=".49" fill="#008000" stroke="#008000" stroke-width=".2"/>
<circle cx="219.3" cy="89.1" r=".28" fill="#fff" stroke="#000" stroke-width=".2"/>
<circle cx="205.3" cy="90" r=".49" fill="#008000" stroke="#008000" stroke-width=".2"/>
<circle cx="205.3" cy="90" r=".28" fill="#fff" stroke="#000" stroke-width=".2"/>
<circle cx="201.2" cy="76.1" r=".49" fill="#008000" stroke="#008000" stroke-width=".2"/>
<circle cx="201.2" cy="76.1" r=".28" fill="#fff" stroke="#000" stroke-width=".2"/>
<circle cx="156.9" cy="50.3" r=".49" fill="#008000" stroke="#008000" stroke-width=".2"/>
<circle cx="156.9" cy="50.3" r=".28" fill="#fff" stroke="#000" stroke-width=".2"/>
<circle cx="160" cy="40.9" r=".49" fill="#008000" stroke="#008000" stroke-width=".2"/>
<circle cx="160" cy="40.9" r=".28" fill="#fff" stroke="#000" stroke-width=".2"/>
<circle cx="218.5" cy="77.7" r=".49" fill="#008000" stroke="#008000" stroke-width=".2"/>
<circle cx="218.5" cy="77.7" r=".28" fill="#fff" stroke="#000" stroke-width=".2"/>
<circle cx="197.4" cy="85.6" r=".49" fill="#008000" stroke="#008000" stroke-width=".2"/>
<circle cx="197.4" cy="85.6" r=".28" fill="#fff" stroke="#000" stroke-width=".2"/>
<circle cx="195.7" cy="68.1" r=".49" fill="#008000" stroke="#008000" stroke-width=".2"/>
<circle cx="195.7" cy="68.1" r=".28" fill="#fff" stroke="#000" stroke-width=".2"/>
<circle cx="191.3" cy="70.8" r=".49" fill="#008000" stroke="#008000" stroke-width=".2"/>
<circle cx="191.3" cy="70.8" r=".28" fill="#fff" stroke="#000" stroke-width=".2"/>
<circle cx="170.9" cy="47.6" r=".49" fill="#008000" stroke="#008000" stroke-width=".2"/>
<circle cx="170.9" cy="47.6" r=".28" fill="#fff" stroke="#000" stroke-width=".2"/>
<circle cx="165.7" cy="56.6" r=".49" fill="#008000" stroke="#008000" stroke-width=".2"/>
<circle cx="165.7" cy="56.6" r=".28" fill="#fff" stroke="#000" stroke-width=".2"/>
<circle cx="218.1" cy="76.2" r=".49" fill="#008000" stroke="#008000" stroke-width=".2"/>
<circle cx="218.1" cy="76.2" r=".28" fill="#fff" stroke="#000" stroke-width=".2"/>
<circle cx="200.4" cy="82.2" r=".49" fill="#008000" stroke="#008000" stroke-width=".2"/>
<circle cx="200.4" cy="82.2" r=".28" fill="#fff" stroke="#000" stroke-width=".2"/>
<circle cx="196.8" cy="76" r=".49" fill="#008000" stroke="#008000" stroke-width=".2"/>
<circle cx="196.8" cy="76" r=".28" fill="#fff" stroke="#000" stroke-width=".2"/>
<circle cx="215.7" cy="70.1" r=".49" fill="#008000" stroke="#008000" stroke-width=".2"/>
<circle cx="215.7" cy="70.1" r=".28" fill="#fff" stroke="#000" stroke-width=".2"/>
<circle cx="191.5" cy="81.3" r=".49" fill="#008000" stroke="#008000" stroke-width=".2"/>
<circle cx="191.5" cy="81.3" r=".28" fill="#fff" stroke="#000" stroke-width=".2"/>
<circle cx="213.8" cy="66.1" r=".49" fill="#008000" stroke="#008000" stroke-width=".2"/>
<circle cx="213.8" cy="66.1" r=".28" fill="#fff" stroke="#000" stroke-width=".2"/>
<circle cx="191.6" cy="77.3" r=".49" fill="#008000" stroke="#008000" stroke-width=".2"/>
<circle cx="191.6" cy="77.3" r=".28" fill="#fff" stroke="#000" stroke-width=".2"/>
<circle cx="193.9" cy="82.5" r=".49" fill="#008000" stroke="#008000" stroke-width=".2"/>
<circle cx="193.9" cy="82.5" r=".28" fill="#fff" stroke="#000" stroke-width=".2"/>
<circle cx="191.5" cy="83.4" r=".49" fill="#008000" stroke="#008000" stroke-width=".2"/>
<circle cx="191.5" cy="83.4" r=".28" fill="#fff" stroke="#000" stroke-width=".2"/>
<circle cx="209.5" cy="58.3" r=".49" fill="#008000" stroke="#008000" stroke-width=".2"/>
<circle cx="209.5" cy="58.3" r=".28" fill="#fff" stroke="#000" stroke-width=".2"/>
<circle cx="182.4" cy="74.3" r=".49" fill="#008000" stroke="#008000" stroke-width=".2"/>
<circle cx="182.4" cy="74.3" r=".28" fill="#fff" stroke="#000" stroke-width=".2"/>
<circle cx="145" cy="149.5" r=".49" fill="#008000" stroke="#008000" stroke-width=".2"/>
<circle cx="145" cy="149.5" r=".28" fill="#fff" stroke="#000" stroke-width=".2"/>
<circle cx="146.7" cy="160.3" r=".49" fill="#008000" stroke="#008000" stroke-width=".2"/>
<circle cx="146.7" cy="160.3" r=".28" fill="#fff" stroke="#000" stroke-width=".2"/>
<circle cx="206.7" cy="54.2" r=".49" fill="#008000" stroke="#008000" stroke-width=".2"/>
<circle cx="206.7" cy="54.2" r=".28" fill="#fff" stroke="#000" stroke-width=".2"/>
<circle cx="182.2" cy="73.1" r=".49" fill="#008000" stroke="#008000" stroke-width=".2"/>
<circle cx="182.2" cy="73.1" r=".28" fill="#fff" stroke="#000" stroke-width=".2"/>
<circle cx="181.2" cy="131.6" r=".49" fill="#008000" stroke="#008000" stroke-width=".2"/>
<circle cx="181.2" cy="131.6" r=".28" fill="#fff" stroke="#000" stroke-width=".2"/>
<circle cx="177.8" cy="129.2" r=".49" fill="#008000" stroke="#008000" stroke-width=".2"/>
<circle cx="177.8" cy="129.2" r=".28" fill="#fff" stroke="#000" stroke-width=".2"/>
<circle cx="147.3" cy="158.2" r=".49" fill="#008000" stroke="#008000" stroke-width=".2"/>
<circle cx="147.3" cy="158.2" r=".28" fill="#fff" stroke="#000" stroke-width=".2"/>
<circle cx="145.9" cy="147.2" r=".49" fill="#008000" stroke="#008000" stroke-width=".2"/>
<circle cx="145.9" cy="147.2" r=".28" fill="#fff" stroke="#000" stroke-width=".2"/>
<circle cx="201.7" cy="48" r=".49" fill="#008000" stroke="#008000" stroke-width=".2"/>
<circle cx="201.7" cy="48" r=".28" fill="#fff" stroke="#000" stroke-width=".2"/>
<circle cx="176.1" cy="70.3" r=".49" fill="#008000" stroke="#008000" stroke-width=".2"/>
<circle cx="176.1" cy="70.3" r=".28" fill="#fff" stroke="#000" stroke-width=".2"/>
<circle cx="166.4" cy="144.4" r=".49" fill="#008000" stroke="#008000" stroke-width=".2"/>
<circle cx="166.4" cy="144.4" r=".28" fill="#fff" stroke="#000" stroke-width=".2"/>
<circle cx="163.1" cy="139.3" r=".49" fill="#008000" stroke="#008000" stroke-width=".2"/>
<circle cx="163.1" cy="139.3" r=".28" fill="#fff" stroke="#000" stroke-width=".2"/>
<circle cx="141.8" cy="145.3" r=".49" fill="#008000" stroke="#008000" stroke-width=".2"/>
<circle cx="141.8" cy="145.3" r=".28" fill="#fff" stroke="#000" stroke-width=".2"/>
<circle cx="138.9" cy="155.3" r=".49" fill="#008000" stroke="#008000" stroke-width=".2"/>
<circle cx="138.9" cy="155.3" r=".28" fill="#fff" stroke="#000" stroke-width=".2"/>
<circle cx="196.8" cy="43.3" r=".49" fill="#008000" stroke="#008000" stroke-width=".2"/>
<circle cx="196.8" cy="43.3" r=".28" fill="#fff" stroke="#000" stroke-width=".2"/>
<circle cx="172.2" cy="68.3" r=".49" fill="#008000" stroke="#008000" stroke-width=".2"/>
<circle cx="172.2" cy="68.3" r=".28" fill="#fff" stroke="#000" stroke-width=".2"/>
<circle cx="170.6" cy="139.3" r=".49" fill="#008000" stroke="#008000" stroke-width=".2"/>
<circle cx="170.6" cy="139.3" r=".28" fill="#fff" stroke="#000" stroke-width=".2"/>
<circle cx="166.9" cy="134.9" r=".49" fill="#008000" stroke="#008000" stroke-width=".2"/>
<circle cx="166.9" cy="134.9" r=".28" fill="#fff" stroke="#000" stroke-width=".2"/>
<circle cx="188.6" cy="36" r=".49" fill="#008000" stroke="#008000" stroke-width=".2"/>
<circle cx="188.6" cy="36" r=".28" fill="#fff" stroke="#000" stroke-width=".2"/>
<circle cx="166.1" cy="65.3" r=".49" fill="#008000" stroke="#008000" stroke-width=".2"/>
<circle cx="166.1" cy="65.3" r=".28" fill="#fff" stroke="#000" stroke-width=".2"/>
<circle cx="157.5" cy="73.3" r=".49" fill="#008000" stroke="#008000" stroke-width=".2"/>
<circle cx="157.5" cy="73.3" r=".28" fill="#fff" stroke="#000" stroke-width=".2"/>
<circle cx="164.4" cy="62.1" r=".49" fill="#008000" stroke="#008000" stroke-width=".2"/>
<circle cx="164.4" cy="62.1" r=".28" fill="#fff" stroke="#000" stroke-width=".2"/>
<circle cx="163.8" cy="66.1" r=".49" fill="#008000" stroke="#008000" stroke-width=".2"/>
<circle cx="163.8" cy="66.1" r=".28" fill="#fff" stroke="#000" stroke-width=".2"/>
<circle cx="157.4" cy="75.6" r=".49" fill="#008000" stroke="#008000" stroke-width=".2"/>
<circle cx="157.4" cy="75.6" r=".28" fill="#fff" stroke="#000" stroke-width=".2"/>
<circle cx="183.1" cy="32.1" r=".49" fill="#008000" stroke="#008000" stroke-width=".2"/>
<circle cx="183.1" cy="32.1" r=".28" fill="#fff" stroke="#000" stroke-width=".2"/>
<circle cx="154.5" cy="76.1" r=".49" fill="#008000" stroke="#008000" stroke-width=".2"/>
<circle cx="154.5" cy="76.1" r=".28" fill="#fff" stroke="#000" stroke-width=".2"/>
<circle cx="159.7" cy="67.1" r=".49" fill="#008000" stroke="#008000" stroke-width=".2"/>
<circle cx="159.7" cy="67.1" r=".28" fill="#fff" stroke="#000" stroke-width=".2"/>
<circle cx="181.9" cy="31.4" r=".49" fill="#008000" stroke="#008000" stroke-width=".2"/>
<circle cx="181.9" cy="31.4" r=".28" fill="#fff" stroke="#000" stroke-width=".2"/>
<circle cx="164" cy="128" r=".49" fill="#008000" stroke="#008000" stroke-width=".2"/>
<circle cx="164" cy="128" r=".28" fill="#fff" stroke="#000" stroke-width=".2"/>
<circle cx="155.6" cy="119.6" r=".49" fill="#008000" stroke="#008000" stroke-width=".2"/>
<circle cx="155.6" cy="119.6" r=".28" fill="#fff" stroke="#000" stroke-width=".2"/>
<circle cx="175.7" cy="28.1" r=".49" fill="#008000" stroke="#008000" stroke-width=".2"/>
<circle cx="175.7" cy="28.1" r=".28" fill="#fff" stroke="#000" stroke-width=".2"/>
<circle cx="144.2" cy="82.4" r=".49" fill="#008000" stroke="#008000" stroke-width=".2"/>
<circle cx="144.2" cy="82.4" r=".28" fill="#fff" stroke="#000" stroke-width=".2"/>
<circle cx="160.4" cy="115.1" r=".49" fill="#008000" stroke="#008000" stroke-width=".2"/>
<circle cx="160.4" cy="115.1" r=".28" fill="#fff" stroke="#000" stroke-width=".2"/>
<circle cx="153.4" cy="110.8" r=".49" fill="#008000" stroke="#008000" stroke-width=".2"/>
<circle cx="153.4" cy="110.8" r=".28" fill="#fff" stroke="#000" stroke-width=".2"/>
<circle cx="142.8" cy="125.4" r=".49" fill="#008000" stroke="#008000" stroke-width=".2"/>
<circle cx="142.8" cy="125.4" r=".28" fill="#fff" stroke="#000" stroke-width=".2"/>
<circle cx="143.3" cy="134.9" r=".49" fill="#008000" stroke="#008000" stroke-width=".2"/>
<circle cx="143.3" cy="134.9" r=".28" fill="#fff" stroke="#000" stroke-width=".2"/>
<circle cx="171.5" cy="26.3" r=".49" fill="#008000" stroke="#008000" stroke-width=".2"/>
<circle cx="171.5" cy="26.3" r=".28" fill="#fff" stroke="#000" stroke-width=".2"/>
<circle cx="155.2" cy="66.6" r=".49" fill="#008000" stroke="#008000" stroke-width=".2"/>
<circle cx="155.2" cy="66.6" r=".28" fill="#fff" stroke="#000" stroke-width=".2"/>
<circle cx="175" cy="120" r=".49" fill="#008000" stroke="#008000" stroke-width=".2"/>
<circle cx="175" cy="120" r=".28" fill="#fff" stroke="#000" stroke-width=".2"/>
<circle cx="168.2" cy="116.7" r=".49" fill="#008000" stroke="#008000" stroke-width=".2"/>
<circle cx="168.2" cy="116.7" r=".28" fill="#fff" stroke="#000" stroke-width=".2"/>
<circle cx="155.2" cy="129.6" r=".49" fill="#008000" stroke="#008000" stroke-width=".2"/>
<circle cx="155.2" cy="129.6" r=".28" fill="#fff" stroke="#000" stroke-width=".2"/>
<circle cx="148.8" cy="119.9" r=".49" fill="#008000" stroke="#008000" stroke-width=".2"/>
<circle cx="148.8" cy="119.9" r=".28" fill="#fff" stroke="#000" stroke-width=".2"/>
<circle cx="164.2" cy="23.3" r=".49" fill="#008000" stroke="#008000" stroke-width=".2"/>
<circle cx="164.2" cy="23.3" r=".28" fill="#fff" stroke="#000" stroke-width=".2"/>
<circle cx="151.8" cy="63.9" r=".49" fill="#008000" stroke="#008000" stroke-width=".2"/>
<circle cx="151.8" cy="63.9" r=".28" fill="#fff" stroke="#000" stroke-width=".2"/>
<circle cx="174.7" cy="123.7" r=".49" fill="#008000" stroke="#008000" stroke-width=".2"/>
<circle cx="174.7" cy="123.7" r=".28" fill="#fff" stroke="#000" stroke-width=".2"/>
<circle cx="165.2" cy="118.2" r=".49" fill="#008000" stroke="#008000" stroke-width=".2"/>
<circle cx="165.2" cy="118.2" r=".28" fill="#fff" stroke="#000" stroke-width=".2"/>
<circle cx="156.8" cy="22.1" r=".49" fill="#008000" stroke="#008000" stroke-width=".2"/>
<circle cx="156.8" cy="22.1" r=".28" fill="#fff" stroke="#000" stroke-width=".2"/>
<circle cx="144.7" cy="79.9" r=".49" fill="#008000" stroke="#008000" stroke-width=".2"/>
<circle cx="144.7" cy="79.9" r=".28" fill="#fff" stroke="#000" stroke-width=".2"/>
<circle cx="146.5" cy="84.6" r=".49" fill="#008000" stroke="#008000" stroke-width=".2"/>
<circle cx="146.5" cy="84.6" r=".28" fill="#fff" stroke="#000" stroke-width=".2"/>
<circle cx="143.2" cy="92.9" r=".49" fill="#008000" stroke="#008000" stroke-width=".2"/>
<circle cx="143.2" cy="92.9" r=".28" fill="#fff" stroke="#000" stroke-width=".2"/>
<circle cx="145.6" cy="19.7" r=".49" fill="#008000" stroke="#008000" stroke-width=".2"/>
<circle cx="145.6" cy="19.7" r=".28" fill="#fff" stroke="#000" stroke-width=".2"/>
<circle cx="141.2" cy="77" r=".49" fill="#008000" stroke="#008000" stroke-width=".2"/>
<circle cx="141.2" cy="77" r=".28" fill="#fff" stroke="#000" stroke-width=".2"/>
<circle cx="163.6" cy="92.9" r=".49" fill="#008000" stroke="#008000" stroke-width=".2"/>
<circle cx="163.6" cy="92.9" r=".28" fill="#fff" stroke="#000" stroke-width=".2"/>
<circle cx="159.8" cy="94.4" r=".49" fill="#008000" stroke="#008000" stroke-width=".2"/>
<circle cx="159.8" cy="94.4" r=".28" fill="#fff" stroke="#000" stroke-width=".2"/>
<circle cx="158.5" cy="100.5" r=".49" fill="#008000" stroke="#008000" stroke-width=".2"/>
<circle cx="158.5" cy="100.5" r=".28" fill="#fff" stroke="#000" stroke-width=".2"/>
<circle cx="146.5" cy="101.9" r=".49" fill="#008000" stroke="#008000" stroke-width=".2"/>
<circle cx="146.5" cy="101.9" r=".28" fill="#fff" stroke="#000" stroke-width=".2"/>
<circle cx="142.7" cy="16.2" r=".49" fill="#008000" stroke="#008000" stroke-width=".2"/>
<circle cx="142.7" cy="16.2" r=".28" fill="#fff" stroke="#000" stroke-width=".2"/>
<circle cx="141.1" cy="78.5" r=".49" fill="#008000" stroke="#008000" stroke-width=".2"/>
<circle cx="141.1" cy="78.5" r=".28" fill="#fff" stroke="#000" stroke-width=".2"/>
<circle cx="163.9" cy="100.1" r=".49" fill="#008000" stroke="#008000" stroke-width=".2"/>
<circle cx="163.9" cy="100.1" r=".28" fill="#fff" stroke="#000" stroke-width=".2"/>
<circle cx="109.7" cy="110.7" r=".49" fill="#008000" stroke="#008000" stroke-width=".2"/>
<circle cx="109.7" cy="110.7" r=".28" fill="#fff" stroke="#000" stroke-width=".2"/>
<circle cx="142.3" cy="139.6" r=".72" fill="#008000" stroke="#008000" stroke-width=".2"/>
<circle cx="142.3" cy="139.6" r=".47" fill="#fff" stroke="#000" stroke-width=".2"/>
<circle cx="174.7" cy="78.5" r=".49" fill="#008000" stroke="#008000" stroke-width=".2"/>
<circle cx="174.7" cy="78.5" r=".28" fill="#fff" stroke="#000" stroke-width=".2"/>
<circle cx="187" cy="72.7" r=".49" fill="#008000" stroke="#008000" stroke-width=".2"/>
<circle cx="187" cy="72.7" r=".28" fill="#fff" stroke="#000" stroke-width=".2"/>
<circle cx="136.9" cy="62" r=".49" fill="#008000" stroke="#008000" stroke-width=".2"/>
<circle cx="136.9" cy="62" r=".28" fill="#fff" stroke="#000" stroke-width=".2"/>
<circle cx="143.3" cy="35.8" r=".49" fill="#008000" stroke="#008000" stroke-width=".2"/>
<circle cx="143.3" cy="35.8" r=".28" fill="#fff" stroke="#000" stroke-width=".2"/>
<circle cx="125.8" cy="34.2" r=".49" fill="#008000" stroke="#008000" stroke-width=".2"/>
<circle cx="125.8" cy="34.2" r=".28" fill="#fff" stroke="#000" stroke-width=".2"/>
<circle cx="119.9" cy="64.2" r=".49" fill="#008000" stroke="#008000" stroke-width=".2"/>
<circle cx="119.9" cy="64.2" r=".28" fill="#fff" stroke="#000" stroke-width=".2"/>
<circle cx="119.5" cy="67" r=".49" fill="#008000" stroke="#008000" stroke-width=".2"/>
<circle cx="119.5" cy="67" r=".28" fill="#fff" stroke="#000" stroke-width=".2"/>
<circle cx="92.8" cy="125.5" r=".49" fill="#008000" stroke="#008000" stroke-width=".2"/>
<circle cx="92.8" cy="125.5" r=".28" fill="#fff" stroke="#000" stroke-width=".2"/>
<circle cx="133.2" cy="75.5" r=".72" fill="#008000" stroke="#008000" stroke-width=".2"/>
<circle cx="133.2" cy="75.5" r=".47" fill="#fff" stroke="#000" stroke-width=".2"/>
<circle cx="172.9" cy="72.6" r=".49" fill="#008000" stroke="#008000" stroke-width=".2"/>
<circle cx="172.9" cy="72.6" r=".28" fill="#fff" stroke="#000" stroke-width=".2"/>
<circle cx="148.5" cy="74.8" r=".72" fill="#008000" stroke="#008000" stroke-width=".2"/>
<circle cx="148.5" cy="74.8" r=".47" fill="#fff" stroke="#000" stroke-width=".2"/>
<circle cx="99.9" cy="115.8" r=".72" fill="#008000" stroke="#008000" stroke-width=".2"/>
<circle cx="99.9" cy="115.8" r=".47" fill="#fff" stroke="#000" stroke-width=".2"/>
<circle cx="136.7" cy="75.5" r=".72" fill="#008000" stroke="#008000" stroke-width=".2"/>
<circle cx="136.7" cy="75.5" r=".47" fill="#fff" stroke="#000" stroke-width=".2"/>
<circle cx="118.8" cy="49.3" r=".49" fill="#008000" stroke="#008000" stroke-width=".2"/>
<circle cx="118.8" cy="49.3" r=".28" fill="#fff" stroke="#000" stroke-width=".2"/>
<circle cx="114.1" cy="120" r=".49" fill="#008000" stroke="#008000" stroke-width=".2"/>
<circle cx="114.1" cy="120" r=".28" fill="#fff" stroke="#000" stroke-width=".2"/>
<circle cx="162.1" cy="43.8" r=".49" fill="#008000" stroke="#008000" stroke-width=".2"/>
<circle cx="162.1" cy="43.8" r=".28" fill="#fff" stroke="#000" stroke-width=".2"/>
<circle cx="165.5" cy="90.2" r=".49" fill="#008000" stroke="#008000" stroke-width=".2"/>
<circle cx="165.5" cy="90.2" r=".28" fill="#fff" stroke="#000" stroke-width=".2"/>
<circle cx="122" cy="57.9" r=".49" fill="#008000" stroke="#008000" stroke-width=".2"/>
<circle cx="122" cy="57.9" r=".28" fill="#fff" stroke="#000" stroke-width=".2"/>
<circle cx="165.7" cy="97" r=".49" fill="#008000" stroke="#008000" stroke-width=".2"/>
<circle cx="165.7" cy="97" r=".28" fill="#fff" stroke="#000" stroke-width=".2"/>
<circle cx="151.4" cy="69.1" r=".49" fill="#008000" stroke="#008000" stroke-width=".2"/>
<circle cx="151.4" cy="69.1" r=".28" fill="#fff" stroke="#000" stroke-width=".2"/>
<circle cx="156.9" cy="54.6" r=".49" fill="#008000" stroke="#008000" stroke-width=".2"/>
<circle cx="156.9" cy="54.6" r=".28" fill="#fff" stroke="#000" stroke-width=".2"/>
<circle cx="147.5" cy="55.5" r=".49" fill="#008000" stroke="#008000" stroke-width=".2"/>
<circle cx="147.5" cy="55.5" r=".28" fill="#fff" stroke="#000" stroke-width=".2"/>
<circle cx="132.9" cy="102" r=".49" fill="#008000" stroke="#008000" stroke-width=".2"/>
<circle cx="132.9" cy="102" r=".28" fill="#fff" stroke="#000" stroke-width=".2"/>
<circle cx="132.1" cy="103.3" r=".49" fill="#008000" stroke="#008000" stroke-width=".2"/>
<circle cx="132.1" cy="103.3" r=".28" fill="#fff" stroke="#000" stroke-width=".2"/>
<circle cx="157.4" cy="68.6" r=".49" fill="#008000" stroke="#008000" stroke-width=".2"/>
<circle cx="157.4" cy="68.6" r=".28" fill="#fff" stroke="#000" stroke-width=".2"/>
<circle cx="124.8" cy="103.4" r=".49" fill="#008000" stroke="#008000" stroke-width=".2"/>
<circle cx="124.8" cy="103.4" r=".28" fill="#fff" stroke="#000" stroke-width=".2"/>
<circle cx="45" cy="103.4" r=".49" fill="#008000" stroke="#008000" stroke-width=".2"/>
<circle cx="45" cy="103.4" r=".28" fill="#fff" stroke="#000" stroke-width=".2"/>
<circle cx="124.8" cy="109.6" r=".49" fill="#008000" stroke="#008000" stroke-width=".2"/>
<circle cx="124.8" cy="109.6" r=".28" fill="#fff" stroke="#000" stroke-width=".2"/>
<circle cx="154.9" cy="50.6" r=".49" fill="#008000" stroke="#008000" stroke-width=".2"/>
<circle cx="154.9" cy="50.6" r=".28" fill="#fff" stroke="#000" stroke-width=".2"/>
<circle cx="228.7" cy="112.1" r=".49" fill="#008000" stroke="#008000" stroke-width=".2"/>
<circle cx="228.7" cy="112.1" r=".28" fill="#fff" stroke="#000" stroke-width=".2"/>
<circle cx="195.3" cy="109" r=".49" fill="#008000" stroke="#008000" stroke-width=".2"/>
<circle cx="195.3" cy="109" r=".28" fill="#fff" stroke="#000" stroke-width=".2"/>
<circle cx="121.1" cy="46.9" r=".49" fill="#008000" stroke="#008000" stroke-width=".2"/>
<circle cx="121.1" cy="46.9" r=".28" fill="#fff" stroke="#000" stroke-width=".2"/>
<circle cx="136.2" cy="44.4" r=".49" fill="#008000" stroke="#008000" stroke-width=".2"/>
<circle cx="136.2" cy="44.4" r=".28" fill="#fff" stroke="#000" stroke-width=".2"/>
<circle cx="225.8" cy="88.9" r=".49" fill="#008000" stroke="#008000" stroke-width=".2"/>
<circle cx="225.8" cy="88.9" r=".28" fill="#fff" stroke="#000" stroke-width=".2"/>
<circle cx="194.8" cy="94.2" r=".49" fill="#008000" stroke="#008000" stroke-width=".2"/>
<circle cx="194.8" cy="94.2" r=".28" fill="#fff" stroke="#000" stroke-width=".2"/>
<g fill="none" stroke="#069" stroke-width=".42">
<path d="M107.9 12.1l1.9 5.5M108.6 14.3l.2 .5M114.8 13.7l9.2 34.4-1.4 .3M123.7 10.5l.3 1.9a1.57 1.57 0 0 1-1.3 1.8M129.9 14.3l.6 5.5M140.3 9.2v3.5l1.2 1.1-.7 31 .4 2.5M144.7 13l-.4 5.5M153.6 13l-.1-.3-3 19.1M156.4 14.5l-.7 4.1M158.8 18.2l-2.4 10.4M169.6 12.1l-1.8 5.4M170.5 19.6l-3.9 10.3 .7 .7h.2"/>
<path d="M72.9 33.1l9.2 9.6M76.7 33.9l6.2 6.9M79.3 35.2l6.2 7M84.6 39.4l1.3-1.1 15.9 19.1M84.7 24.9l6.8 9.7-1.6 1.2M86.1 29.8l3.1 4.3-.3 .4M89.5 23.3l7 11.3M91.7 32.4l.2 .4M91.9 32.8l13.5 19.8 8.3 12.6M93.2 31.6l-1.3 1.2M96.2 34.1l.8 1.3M96.7 34.9l.3 .5"/>
<path d="M97 35.4l.3 .4M98 32.7l31.8 54.9M98.9 22.1l1.8 3.6M99.2 29.3l11 20.1M100.8 28.5l1.3 .6 .9 1.1 9.1 18.5M104.5 25.5l-.5 .3 1.9 4.1M105.8 29.7l.1 .2M105.9 29.9l.5 1 1-.4M111 21.4l.5 1.2 8.1 23.1 4.8 14.9-.3 .8M111 24.2a1.73 1.73 0 0 0-1.4 .8v.7l6.4 16.5M113 23.3a1.92 1.92 0 0 1 2.3 1.3l3.4 11.1M120.2 23.8l.2 .8a1.52 1.52 0 0 1-1 2"/>
<path d="M123.2 35.1l3.8 17.3M129.1 27.8l-.2 .1 1.4 11.2M130.8 23.4l1.3 11.8M130.8 23.4h.1M130.8 23.4l.1 .1M130.9 23.4v.1M132.3 25.4a1.56 1.56 0 0 1 1.6 1.8l.7 9.2-.1 .2h-1M144 25.1v-.1l-.3 4.4M146.3 30.1l-1.4 15-1 1.8M150.3 23.2l-.9-.1-6 44.9-.4 .8-.5 .3-.6 .1M156.4 28.6l-.1 .5M156.4 28.6l-3.3 15 .7 .7-.1 .7"/>
<path d="M157.4 20.3l-2.1 .1-6.5 34-1.8-.4M157.9 26.4l1.4 .4-1.5 5.3M158.7 37.3l.1-.2-3.1 10.7M159.9 29.2l-11.6 38.9 .1 .9M165.6 22.6l.5 .1-5.4 16.2M169.1 30.2l-19.7 47.5M179.6 27.2l.1-.2-8.6 16.4-1.8-.9-.4 .1-.2 .3-9.5 19.3v.4l-14.7 29.2v.5M180.4 35.9l-2.5 4.1-.1-.3M183.1 20.5l-1.6 3M187.1 36h.1M187.1 36l-.5 .8M192.3 28.8l-5.2 7.2"/>
<path d="M199.5 34l-8.5 9.6M199.5 28.6l-23.4 29.1M202.7 39.3l-19.7 19.7 .1-.2M58.9 57.1l9.1 5.3a3.1 3.1 0 0 0 3.3 0M62.1 55.6l15.7 9.5M68.1 41l11.3 9.8M68.8 52.6l13.8 9.8a1.47 1.47 0 0 1 .5 2.1M68.9 46l13.1 10.4M70.4 55.2l-1 1.4 6.2 4.1M78.8 44.6l-.9 1.1 6.6 6.1M79.4 50.8l.1 .1-.7 .9M79.4 50.8l7.4 6.5"/>
<path d="M80.4 44.9l9.7 9.6v.5a1.32 1.32 0 0 0 1.1 .8l15.4 15.3-1.6 1.7M80.4 58.6l13.2 10M82.1 42.7l.1 .1M82.1 42.7l2 2.1M83.7 44.4l.4 .4M84.1 44.8l.6 .6M84.7 45.4l7.5 7.8M86.1 44.2l-1.4 1.2M92.2 53.2l6.7 7.1M92.2 53.2l-1 1.6M93.2 50.8l-1.7-1.9 9.9 11.3M99.2 45.9l1.2 1.5-.3-.2"/>
<path d="M100.2 47.2l.2 .2M110.2 49.4l.1 .2M110.2 49.4l.4 .6M110.3 49.6h.1M110.6 49.4l-.3 .2M111.9 50.6l6.1 12.2 1.1 .5M112.5 46.5l6.5 13.7M116 42.2h.1M116 42.2l1.4 1.3M117.4 51.5l2.9 7.1M131.7 46.4l1.2 9.6M134.6 47.5l1 11.3"/>
<path d="M138.8 53.3v24.2M142.6 49.4v2l-.6 8.2M160 40.9l-3.1 9.4M170.6 48l.3-.4-5.2 9M176.1 57.7l-.2 .4M176.1 57.7l-8.3 10.2M183.5 44.9l-23.9 31.2-.8-.9M189.8 42.8l1.1 .9-15.2 17.5M196.8 43.3l-24.8 25.1 .2-.1M199.1 51.9l.9 1.2M200 53.1l-8.6 7.2M201.7 48l-12.3 10.9-13.4 11.4 .1-.2v.2"/>
<path d="M206.7 54.2l-20.5 15-4.2 3.4 .2 .5M209.5 58.3a1.76 1.76 0 0 0-1.2-1.3l-.8 .2-18 12.3M210.5 48.2l-14.8 11.3M210.5 40.6l-3.6 3.2M211.4 43.7l-11.4 9.4M217.7 59l.7 1.3-14.8 8.1M220.3 56.1l-42.1 24.3-1.3-2.6M220.5 52.5l-14.4 9M52 76.9l19.5 5.8M53.1 67.2l10.3 4.4M56.6 66l10.2 4.5M59.1 77.4l14.3 4.6"/>
<path d="M62.7 65.4l.4 .3M62.8 65.5l.3 .2M63.1 65.7l13.5 6.5a1.67 1.67 0 0 1 .8 2.2l-.7 1.5M63.4 66.8l8.3 4-.2 .4M66.8 70.5l7.6 3.4a1.39 1.39 0 0 1 .4 1.7l.4 .6 2 1a1.39 1.39 0 0 0 1.7-.9l.6-.2h.5l14.7 6.3M66.8 70.5l-1 2.4M72.4 76l29.5 12M93.6 68.6l15.7 12M93.6 68.6l-.9 1.3M97.3 75.2l6.4 4.2M98.9 60.3l16.4 16.7 .2 .4v.5l-.7 .7v.7l5.5 5.5M98.9 60.3l.1 .1"/>
<path d="M113.6 65.1l.1 .1M113.7 65.2l4.5 6.9M116.3 73.9l20.7 26.8M119.9 61.7l4.8 10.3M129.9 76.2l1.8 5.5M166.5 69.5l-6 7.4-1.7 .1-2.2 2.7h.2l-3.6 4.7 1 .8M175.7 61.2h.1M175.7 61.2l1.1 .9M189.5 69.5l-.3 .1M189.5 69.5l-7.1 4.8M196 67.9l-5 3.1 .3-.2M201.6 69.5l-11.4 6.2"/>
<path d="M201.9 69.3l-.3 .2M211.8 72.9l.8 2.3 1.3-.5M213.8 66.1l-22.2 11.2M214.2 74.5l-.3 .2M215.6 64.1l-11.4 5.6-2.6-.2M215.7 70.1l-6.7 2.7-.8 1.6-16.9 7M218.1 76.2l-17.3 6-.8-.1M218.5 77.7l.5 1.3-21.6 6.6M219.4 76.6a1.08 1.08 0 0 0 0-1.2 1.08 1.08 0 0 0-1.1-.5l-.7 .1-5.4 1.9-.9-.1a2.47 2.47 0 0 0-2-.3l-11.8 4.5-2.2 2.2-3.8 1.6-3.4-2.2-1.7-1.6M219.4 72.6l-5.5 2.1M222.3 68.6l-8.5 3.5M223 65.1l-23.2 10.7"/>
<path d="M231.6 78.2l-37.8 10.2M43.9 97l1.3-.1 10.1 .6M45.8 87.9l.6 .1M46.2 88h.2M46.4 88l3.3 .5M50.5 91.8l25.3 3.4M50.7 94.1l25.7 2.4 .1 1.2M55.1 89.5l-.1-.2 27.8 4.3M56 91l19 2.7M56.5 98.3l2.6 .7 9.2 .3M57.3 83.9l.8-.7 .7-.1 10.7 2.5a1.92 1.92 0 0 1 1.3 2.2l2.9 .7M57.4 96.7l12 .7"/>
<path d="M58.8 84.2a1.31 1.31 0 0 1 1.2 1.7 1.9 1.9 0 0 0 2.1 1.8l19.1 3.7M59.9 97.8l9.8 .5a1.59 1.59 0 0 1 1.5 1.8M62 84.8l7.1 1.7M84 81.9l1.9 .5M90.2 91.5a3.4 3.4 0 0 0 2.6 2.5l20.2 4.3M94.7 82.4l.1 .1M94.7 82.4l.4 .2M104.3 83.4l14 8.1M104.6 94.2h.1M104.6 94.2l9.8 2.6M107.7 88.4l14.3 6.9M108.2 90.7l9.7 4"/>
<path d="M108.6 98.8l4.3 .7M114.2 84.5l8.9 6.8M122 95v.3M122 95.3h.1M129.8 87.6v.1M129.8 87.6l2.9 5.3 3-1.4M167.2 84a1.83 1.83 0 0 0-2.7-.6l-4.4 3.4M182.4 88.9l-.9-.1-20.4 6.6M186.6 82.6l-14.6 5.9-2.5-4.2 1.9-1.3M193.5 87.3l.3 1.1M193.8 88.4l-37.4 10-1.7 .3M193.9 82.5l-2.4 .9"/>
<path d="M217.5 96.5l.2 1.5 2.2-.2M219.3 89.1l-.3-1.9-13.7 2.8M222.3 95.8l-1.3-1-18.7 2.1M222.3 97.6l-1 1.4-5.8 .4-.9-1.2-6.6 .5-2.6 1M226.7 82.4l-11 2.8M228.7 94l-4.2 .5M48.5 105.8l-6.3 .2M50.7 117.3l-.1 .1M50.7 117.3l-.9 .3M52 111.7l-6.6 .8h-1.2M52.1 111.7h-.1M52.7 105.7h-.2l28-1.1a1.25 1.25 0 0 1 1.5 1.1"/>
<path d="M53.7 116.8l-3 .5M55.4 111.4l-3.4 .3M58.7 111l2.3-.2-3.7 .3M64.3 109.2l.1-.1-7.6 .6M64.4 113.2l-8 1.1 .1 1 .4 .3M64.6 113.2h-.2M67.5 110l2.2-.2a1.7 1.7 0 0 1 1.9 1.9M82 109.8l-3.4 .4-1.2 1.6-5.9 .9-1.1-.4-6 .9M82.3 119.8l-20.6 6.3a3.1 3.1 0 0 0-2.4 1.4l-.2 .7v.7M82.9 119.6l-.6 .2M83.7 118.2l-37.6 10.1M83.8 112.5a1.21 1.21 0 0 1-.9 1.4l-23 4.7a1.25 1.25 0 0 1-1.5-1"/>
<path d="M84.1 118.1l-.4 .1M87.4 118.3l-5.1 1.5M88.4 114.9l-24.4 5.6-.6 2.2-4 1.1M90 116.5l-6.3 1.7M93 118.2h-.4l-13.7 4.8-.3 .2-1.4 .5-2.8 .8M95.5 117.3a1.7 1.7 0 0 1-.9 2.2l-42.4 16.3M114.4 100.2l2.4 .3M120.9 105.8l-41.4 5.4 .2 1.2-20.5 3.5-.9 .7-1.2 .2-.2 .2-.4 .1-1.4-.5M121 105.8h-.1M123.8 112.9l-3.2 1.9h-1.3l-19.7 11.4M124 115.8l-.7-.3-10.5 8.1-1.4-1.9M124.1 118.8a9 9 0 0 1 3.3 11l-10.1 23.7-.2 .2-10.8 26v.4"/>
<path d="M127 102.7v1.7l-.3 .4-5.8 1M128 101.3l.8 .3 .2 2.6-10.3 6.5M129.9 103v1.6l-2.5 2.5-6.5 3-1.5 1.6M132.5 110l-31.8 27.9M137 100.6l1.7 .1M143.5 114l-1.1 .5 2.8 11.4M149.1 118.4v.2l2.7 4.3M149.9 117.2l.4 .4v.1M150.1 117.5l.2 .2M150.3 117.7l40.1 52.3M150.6 103.1h6.1M158.5 103.1h53.5"/>
<path d="M161.1 104.6l-.1 1.4 2 .2 .1-1.2 68.2 5.8M161.2 110.9l.1-.3 15.9 5.4M170.6 116.2l22.7 9.4 .5-1.4 32.6 12M177 116h.2M177.2 116a765.2 765.2 0 0 0 29.3 10.2M188.7 118.9l.4 .1M189.1 119l15.2 4.9 3.4-1.3 17 4.8M193.4 118.9l.4-1.1 8.5 2.2M194.8 112.5l28.1 4.3-.4-.3M195.6 100.4l.1 1.2 29.3-1.1v2.6M197.3 116.3l20.9 4.1-.2 1 2.4 .5M199.3 111h.2"/>
<path d="M199.5 111l20.4 2.7 .9 .5 .4 .5 .1 .7M199.5 111l.1 .1M204.5 119.2l-.2 1.4-2-.6M205.2 116.5l12.5 2.3 1.6-1.6M206.5 106.3l-.1 1.4 5.5 .3M209.1 119.8l6.6 1.5M211.9 108l5.7 .3M212.1 108h-.2M222.4 104.1a1.18 1.18 0 0 1-1 1.5l-13.6-.3-.3-.1M227.7 118.9l3.4 .6M229.1 103.1h5.8M56.1 122.4l-5.2 1.4"/>
<path d="M56.1 122.4l.2 .2M58.7 121.8l-.4 .1M58.7 121.8l-2.6 .6M61.8 121.1l-3.1 .7M61.8 121.1h.1M61.8 121.1l.3 .9M64.1 134.5l-8.6 3.5M66.2 134.5l.5 .9-6.7 3.1M79.4 127.2l-18.1 7.4M79.7 139.4h.1M79.7 139.4l-.8 .6M80 126.9l-.6 .3"/>
<path d="M81.9 137.9l-2.2 1.5M82.4 130.6l-17.5 8.8-.4 .4a1.37 1.37 0 0 0-.2 1.5M83 130.2l-.7 .4M85 138.7l-8.5 5.8M89.1 130.7l.7 1.1M89.8 131.8l-32.1 18.6M90.5 137.5l-19.1 13.9M91.3 136.9l-.8 .6M94.9 126.2l-29 15.9M99.6 126.2l-9.8 5.6M99.6 126.2l1 1.7M100.8 130.1l-10.3 7.4"/>
<path d="M105.1 137.5l-30.3 29.5M109.6 132.9a5.6 5.6 0 0 1-2.8 2.1l-1.4 .6-3.8 3.2-1.4 .5-.8 .4-3.4 3.2M109.6 132.9h-.1M110.2 127.3l-7 5.9M112.8 133.3v.3M112.8 133.6l-12.8 13.4M113 133.3l-.2 .3M116.5 132.8h.1M118 124.5l-8.4 8.4M119 131.7l-.2 .9-3.5 5.6-.4 .5-3.4 1.9-.6 .7-21.1 29.7M119 131.7h.1M120.1 129.3l-.6-.4-36.8 48"/>
<path d="M120.2 123.4h.1l-20.6 22.3-6.1 6.8-.7 1.2a7 7 0 0 0-.1 3.4l-.3 .8-.4 .8-4.7 6-.5-.1-2 2.4M120.2 131.8l-20.4 33.9 .1-.3M121.2 132.2l-19.9 33.8-.6 .4a1.55 1.55 0 0 0-1.3 .3l-4.6 7.4M121.6 131.5l-.4 .7M121.9 126.4l-1 1.4a1.74 1.74 0 0 0 .3 1.5v.5l-.2 .4-1.6 .7-.3 .3-.1 .5M123.7 123.6a2.44 2.44 0 0 0-1.1 1.7l.4 1.2-.3 .7v2.3l-1.5 2.7M123.8 125.3l.1 .1 1.6 5.5v.5l-6.7 13.2a1.67 1.67 0 0 1-1.5 .5l-.6 .4-3.9 7.7-11.2 22.8M123.9 121.4l-43.1 55.3-.2-.1M130.6 120.5l1.2 .6-15.9 38.4a258.3 258.3 0 0 1-7 16.4v.4M132 129.9l-3.2 11.9M132 129.9h.1M132.7 123.7l-16.9 59.8"/>
<path d="M133.3 125.2l-1.3 4.7M137.6 128.5l-1.8-.2-1.9 14.8M137.6 128.5h.1M157.6 120.1l.3 .2M157.7 120.1l.2 .2M157.8 131.8l-2.7 1.6a3 3 0 0 0-1.8 4l7 17.1-.5 1.4 8.3 22.1-2.4 6.6M157.9 120.3l6.6 5.5M163.1 139.3l3.4 5.2M166.6 134.6l4 4.7M166.9 134.9h.1M167.4 126.9l30.1 24.3 .5 1.4 4.8 4.1M169.3 126.3l34.2 26.2"/>
<path d="M170.6 139.3h.1M177.5 129.1l3.7 2.5M178.9 124.8h.1M179 124.8l9.7 5.4M179.9 123.2l-.9 1.6M188.7 130.2l14.5 7.6M188.7 130.2h.1M189.3 133.5l21.1 12.7M195.9 129l14.9 6.6M201.4 128.9l15.7 6.5M202.3 120v.1M206.5 126.2l.1 .1"/>
<path d="M206.7 126.2h-.2M210.1 131.6l6.3 2.5M210.2 124.4l1 .3 .3 .4 6.4 1.8a1.19 1.19 0 0 1 .6 1.8M210.8 135.6l10.4 4.6M211.1 129.2l2.5 .9h4.4M211.5 134.2l-.7 1.4M62.9 150h-.1M62.9 150l-.9 .6M72.2 145.5l.9 1.3-14.2 9.6M76.2 141.5l.4-.1-13.7 8.6M78.6 154.2l.6 .9M79.2 155.1l-11.1 10"/>
<path d="M83.2 148.3l-14.4 11.9M87.8 147.5l-8.6 7.6M96 142.9l-16.8 16-1.3-1.4M96.1 142.8l-.1 .1M98.5 145.5l-25.5 27.5M98.5 145.5h.1M98.6 145.3l-.1 .2M100 147l-6 6.8 1 1M100.1 146.9l-.1 .1M101.1 148.8l-11.9 14.8M108.9 147.5l-6.1 9M109.9 156.2h.1"/>
<path d="M111.4 153.4l-4.6 8.7M113.6 147l-8.3 14.9M113.6 147l-.4 .8M118.2 143.7l-1.6-.8-.6 .1-2.4 4M120.5 155.9l-2.1 6.4M129.3 159.1l-2.5 16.8M131.6 140.7l-4.9 21.6-4 20.8M134 145.6l-3.8 41.9M136.3 143.2a873 873 0 0 0-3.2 46.2l-.7 .3-.3 .7v6.8l.1 .7a2.57 2.57 0 0 0 1.3 1.2M138.9 155.3h.1M141.8 145.3l.4 10.8h-2.7l-.5-.4-.1-.4M145 149.5l.3 .5"/>
<path d="M145.2 149.4l.1 .6M145.3 150l1.2 8.8M145.9 147.2h-.3l1.9 10.9-.2 .1M146.4 158.3l.3 2M160.9 155.9l1.6 .4 14.3 31.2M166.4 152.8l-.1 1.1 .2 1.1 1.6 3.1M168.1 158.1l.2 .3M168.1 158.1l.2 .2M170 145.1l18.6 25.2M172.6 150.2l.4 .6v.2l19.2 26.3M177.5 144.6a2 2 0 0 0-.1 2.8l8.6 9.8M183.5 141.4l13.1 10.6 .4 1.1 13 10.8 1.1-1.1"/>
<path d="M186.6 151a2.27 2.27 0 0 0 0 3.2l2.6 2.7a4.8 4.8 0 0 1-.5 7.4l10.9 13.2M189.8 151.4v-.1l9.1 8.4a.87 .87 0 0 1 .1 1.3l-.4 .6M193.9 151.7l12.8 11M194.5 141.7l-.8 1.1 15 10.6M198.3 143l-.1-.1 14.5 9.6 .9 .2a1.32 1.32 0 0 0 1.1-.6M205.2 144.3l12.1 7.4M73 173l-.1 .1M73 173h.1M87.4 163.1l-.9-.6-8.4 9.7M89.2 163.6l-5.6 6.9h-.3l-1.5-1.2M89.2 163.6h.1M97.6 171.7h.1"/>
<path d="M97.6 171.7a1.72 1.72 0 0 1 .7 2.4l-3.6 6.2M98.1 170.8l-.7 .8 .2 .1M106.8 162.1h.1M106.8 162.1l-.5 .9M108.7 163.6l-8.2 16.8M110.1 175.6l.5 .7a2.54 2.54 0 0 1-.4 1.9l-2.8 7.7v.5l.3 .4M117.7 164.5h.1M117.7 164.5l-.6 1.6M118.4 162.3h.1M118.4 162.3l-.7 2.2M119 167.9l-4.7 16.4-.3-.1M119.8 174l-1.4 5.5"/>
<path d="M121.2 177l-2.4 10.8M131 163.2l.3 .2-4.1 30.7M143.1 171.7l.7 9.4 .2 .2 .1 1.4h-.2M145 167.3l.1 .6M145.1 167.7v.2M145.1 167.9l1.2 10.8h-1M150.3 161.9l3.6 17.9M154.2 175.9l1 5.5M169.3 176l2.2 5.4M175.6 178.1l-.6 1.8 1.7 4M177.3 177.1l1.6 3.4M179.7 170.7l-.6 .7v.9l3 5.3"/>
<path d="M183.4 175.2a1.99 1.99 0 0 1 2.8 .6l1.9 3M186.9 171.6l6.5 9.4M190.4 170l.1 .2M190.4 170v.2l-1.1 1.1M192.2 164.1l6.2 6.9M192.2 177.3h.1M192.2 177.3l1.3 1.9M94.7 180.3l-.2 .3M94.7 180.3l-1.2 2M96.1 182.6l-1.8 3.2M105.3 187l-2 5.3M108.5 192.7l-.1 .2"/>
<path d="M108.5 192.7l-.3 .4M110.1 187.6l-1.6 5.1M121.9 187.6l-.8 4M130.2 187.5h.1M130.2 187.5l-.5 5.5zM134.1 192.8v2.1M154.9 191.9l.7 3.4M156.8 180.1l.7 2.9M166.4 189.1l1.8 5.4M169.9 180.8a1.2 1.2 0 0 0-1.1 1.6l2.1 5.4M176.8 180.3l2 3.8"/>
</g>
<g fill="none" stroke="#069" stroke-width=".3">
<path d="M191 43.6l-.6 .7M211.3 43.7h.1M129.7 75.6l.2 .6M190.2 75.7l-.5 .6a3.5 3.5 0 0 1-3.8 3.6M50.3 91.7l.3 .1M65.2 98.1l.3 .1M188.9 87l-1.4 1.5-29 8.6-1.4-.1M190.7 93.4a2.55 2.55 0 0 0 2.8 2l12.4-1.5v.8l4.1-.3M190.8 95.6l1.4 .8 1.5 .3 7.3-.8M66.9 118.4h.1M87.4 113.8l-20.5 4.6M87.9 116.1l-18.7 4.7"/>
<path d="M88.8 110l.7 4M117.2 112.7h.2l-26.5 12M137 100.6v.1M208.4 119.6l.7 .2M90.1 120.2l-32.4 11.8M111.9 138.7v.1M137 139.1v3.1M146.4 125.8l.1-.3-1.3 .4M120.6 155.8l-.1 .1M146.4 158.2l.1 .7M118.8 187.8l-.1 .1"/>
</g>
<path d="M158.8 18.2v.1" fill="none" stroke="#069" stroke-width=".57"/>
<circle cx="166.9" cy="134.9" r=".29" fill="#069"/>
<path d="M166.9 134.9h.1" fill="none" stroke="#069" stroke-width=".57"/>
<g fill="none" stroke="#069" stroke-width=".42">
<path d="M87.5 19.7l-.1 .1M88.3 19.3h-.1M89.1 18.8h-.1M89.9 18.3l-.1 .1M90.7 17.8l-.1 .1M91.5 17.4h-.1M92.4 17h-.2M93.2 16.5l-.1 .1M94 16.1h-.1M94.8 15.7h-.1M95.7 15.2l-.1 .1M96.5 14.8l-.1 .1"/>
<path d="M97.3 14.4l-.1 .1M98.2 14.1h-.1M99 13.7h-.1M99.9 13.3h-.1M100.7 12.9l-.1 .1M101.6 12.6h-.1M102.5 12.2l-.1 .1M103.3 11.9h-.1M104.2 11.5l-.1 .1M105.1 11.2l-.1 .1M105.9 10.9h.1M106.8 10.6h-.1"/>
<path d="M107.7 10.3h-.1M108.6 10h-.1M109.5 9.7l-.1 .1M110.4 9.4l-.1 .1M111.3 9.2h-.2M112.1 8.9v.1M113.1 8.7h-.2M113.9 8.4h.1M114.9 8.2h-.2M115.8 8h-.1M116.6 7.7v.1M117.6 7.6h-.1"/>
<path d="M118.5 7.3l-.1 .1M119.4 7.2h-.1M120.3 7h-.1M121.2 6.8h-.1M122.1 6.6l-.1 .1M123 6.5h.1M124 6.3l-.1 .1M124.9 6.2h-.1M125.8 6.1h-.1M126.6 6h.1M127.6 5.9h.1M128.5 5.8h.1"/>
<path d="M129.5 5.7h-.1M130.5 5.6h-.2M131.3 5.5h.1M132.2 5.4h.1M133.1 5.4h.1M134 5.3h.2M135 5.3h.1M135.9 5.2h.1M136.8 5.2h.1M137.8 5.2h.1M138.7 5.2h.2M139.7 5.2h.1"/>
<path d="M140.7 5.2h.1M141.6 5.2h.1M142.5 5.3h.1M142.7 16.2l-.7 30.4 .3 .9-.8 2.1-.5 10.3-.4 1-.8 16.8 1.3 .8M143.5 5.3h.1M144.4 5.4h.1M145.3 5.4h.1M145.6 19.7l-1.6 23.3-.9 .9-.2 3.3 1.3 2.5-1.8 17.7-1.5 1.3v.9l1 1.8-.7 5.6M146.3 5.5h.1M147.2 5.6h.1M148.1 5.7h.1M149 5.8h.1"/>
<path d="M150 5.9h.1M150.9 6h.1M151.8 6.1h.1M152.7 6.2h.1M153.6 6.3l.2 .1M154.6 6.5h.1M155.5 6.6l.1 .1M156.4 6.8h.1M157.3 7h.1M158.2 7.2h.1M159.2 7.3v.1M160.1 7.6h.1"/>
<path d="M161 7.7l.1 .1M161.9 8h.1M162.8 8.2h.1M163.7 8.4h.1M164.6 8.7h.1M165.5 8.9l.1 .1M166.4 9.2h.1M167.3 9.4l.1 .1M168.1 9.7l.2 .1M169 10h.1M169.9 10.3h.1M170.8 10.6h.1"/>
<path d="M171.7 10.9h.1M172.6 11.2l.1 .1M173.4 11.5l.1 .1M174.3 11.9h.1M175.2 12.2l.1 .1M176 12.6h.1M176.9 12.9l.1 .1M177.7 13.3h.1M178.6 13.7h.1M179.5 14.1h.1M180.3 14.4l.1 .1M181.1 14.8l.1 .1"/>
<path d="M182 15.2l.1 .1M182.8 15.7h.1M183.6 16.1h.1M184.4 16.5l.2 .1M185.3 17h.1M186.1 17.4h.1M186.9 17.8l.1 .1M187.7 18.3l.1 .1M188.5 18.8h.1M189.3 19.3h.1M190.1 19.7l.1 .1M64.3 39.7h-.1"/>
<path d="M64.9 38.9l-.1 .1M65.5 38.2l-.1 .1M66.1 37.5l-.1 .1M66.7 36.9h.1M67.4 36.2l-.1 .1M68 35.5l-.1 .1M68.7 34.8l-.1 .1M69.3 34.2h-.1M70 33.5l-.1 .1M70.6 32.9h.1M71.3 32.2l-.1 .1M72 31.6h-.1"/>
<path d="M72.7 30.9l-.1 .1M73.4 30.3l-.1 .1M74.1 29.7l-.1 .1M74.8 29.1l-.1 .1M75.5 28.5l-.1 .1M76.2 27.9l-.1 .1M76.9 27.3h-.1M77.6 26.7l-.1 .1M78.3 26.1v.1M79.1 25.5l-.1 .1M79.8 25l-.1 .1M80.6 24.4l-.1 .1"/>
<path d="M81.3 23.9h-.1M82.1 23.3l-.1 .1M82.8 22.8l-.1 .1M83.6 22.3h-.1M84.4 21.8h-.1M85.2 21.2l-.1 .1M85.9 20.7v.1M86.7 20.2l-.1 .1M156.8 22.1l-.2 .2v1.3l-11.9 55.3v1M164.2 23.3l-12.4 40.8M168.1 38.4l-5.1 11.6v.7l-6.5 14.7 .2 .2-8.4 16.9a1.75 1.75 0 0 1-2.4 .8M168.3 37.8l-.2 .6"/>
<path d="M171.5 26.3l-.6 2.8-15.7 37.5M175.7 28.1a2.67 2.67 0 0 0-3.6 1.3l-4 9M181.9 31.4l-1.2-.8-6.5 11.3M183.1 32.1l1.7 1.2 .1 .5-.1 .6-23.6 35.6-3.8 5.7v-.1M188.6 36l-1.8 2.3-1.5 .1-12.3 17.5-6.9 9.4M190.9 20.2l.1 .1M191.7 20.7l.1 .1M192.5 21.2l.1 .1M193.3 21.8h.1M194 22.3h.1M194.8 22.8l.1 .1M195.5 23.3l.1 .1"/>
<path d="M196.3 23.9h.1M197.1 24.4v.1M197.8 25l.1 .1M198.5 25.5l.1 .1M199.3 26.1v.1M200 26.7l.1 .1M200.7 27.3h.1M201.4 27.9l.1 .1M202.2 28.5v.1M202.9 29.1v.1M203.6 29.7v.1M204.3 30.3v.1"/>
<path d="M205 30.9v.1M205.6 31.6h.1M206.3 32.2l.1 .1M207 32.9h.1M207.6 33.5l.1 .1M208.3 34.2h.1M209 34.8v.1M209.6 35.5l.1 .1M210.2 36.2l.1 .1M210.9 36.9h.1M211.5 37.5l.1 .1M212.1 38.2l.1 .1"/>
<path d="M212.7 38.9l.1 .1M213.3 39.7h.1M51 59.8v.1M51.4 59v.1M51.9 58.2l-.1 .1M52.3 57.3l-.1 .1M52.7 56.5v.1M53.2 55.7l-.1 .1M53.6 54.9v.1M54.1 54.1l-.1 .1M54.6 53.3l-.1 .1M55 52.5v.1"/>
<path d="M55.5 51.7v.1M56 50.9v.1M56.5 50.1v.1M57 49.3v.1M57.5 48.6h.1M58.1 47.8l-.1 .1M58.6 47l-.1 .1M59.1 46.3v.1M59.7 45.5l-.1 .1M60.2 44.8h.1M60.8 44l-.1 .1M61.3 43.3h.1"/>
<path d="M61.9 42.5l-.1 .1M62.5 41.8l-.1 .1M63.1 41.1l-.1 .1M63.7 40.4h-.1M118.8 49.3v.7M147.5 55.5l-5.7 34.1 1 1.6-3.1 10.4-.4 .4h-6.4M174.2 41.9l-2 3.5-1.7-1-3.9 7.4-6.8 12.6-.1 2.7M174.2 41.9l-.2 .4M214 40.4h.1M214.5 41.1l.1 .1M215.1 41.8l.1 .1M215.7 42.5l.1 .1"/>
<path d="M216.3 43.3h.1M216.8 44l.1 .1M217.4 44.8h.1M218 45.5v.1M218.5 46.3v.1M219 47l.1 .1M219.6 47.8v.1M220.1 48.6h.1M220.6 49.3l.1 .1M221.1 50.1l.1 .1M221.6 50.9l.1 .1M222.1 51.7l.1 .1"/>
<path d="M222.6 52.5v.1M223.1 53.3v.1M223.5 54.1l.1 .1M224 54.9v.1M224.5 55.7v.1M224.9 56.5v.1M225.3 57.3l.1 .1M225.8 58.2v.1M226.2 59v.1M226.6 59.8l.1 .1M43.7 79.9v.1M43.9 79v.1"/>
<path d="M44.2 78.1v.1M44.4 77.2v.1M44.7 76.3l-.1 .1M44.9 75.4v.1M45.2 74.5v.1M45.5 73.6l-.1 .1M45.8 72.8l-.1 .1M46.1 71.9l-.1 .1M46.4 71l-.1 .1M46.7 70.1l-.1 .1M47 69.2l-.1 .1M47.3 68.4v.1"/>
<path d="M47.6 67.5v.1M48 66.6l-.1 .1M48.3 65.8v.1M48.7 64.9v.1M49.1 64.1l-.1 .1M49.4 63.2v.1M49.8 62.4v.1M50.2 61.5v.1M50.6 60.7v.1M155.5 74.3l-.1 .2M155.5 74.3l-1 1.8M157.4 68.6l-1.7 2.6-10.4 22.4-2.4 .7-2.5 8-1 1h-7.3"/>
<path d="M159.6 67.3l-4.1 7M159.7 67.1l-.1 .2M164.4 62.1l-6.9 11.2M227 60.7l.1 .1M227.4 61.5l.1 .1M227.8 62.4v.1M228.2 63.2v.1M228.6 64.1v.1M228.9 64.9l.1 .1M229.3 65.8v.1M229.6 66.6l.1 .1M230 67.5v.1"/>
<path d="M230.3 68.4l.1 .1M230.7 69.2v.1M231 70.1v.1M231.3 71v.1M231.6 71.9v.1M231.9 72.8v.1M232.2 73.6v.1M232.4 74.5l.1 .1M232.7 75.4v.1M233 76.3v.1M233.2 77.2v.1M233.4 78.1l.1 .1"/>
<path d="M233.7 79v.1M233.9 79.9v.1M41 99.3v.1M41.1 98.3v.1M41.1 97.4v.1M41.2 96.5v.1M41.2 95.5v.1M41.3 94.6v.1M41.4 93.7v.1M41.5 92.8v.1M41.6 91.8v.1M41.7 90.9v.1"/>
<path d="M41.8 90v.1M42 89.1l-.1 .1M42.1 88.1v.1M42.2 87.2v.1M42.4 86.3v.1M42.6 85.4l-.1 .1M42.7 84.5v.1M42.9 83.6v.1M43.1 82.7h.1M43.3 81.7v.1M43.5 80.8v.1M144.2 82.4l1.7 .9"/>
<path d="M145.8 83.2l.1 .1M146.5 84.6l-3.3 8.3M163.6 92.9l-3.8 1.5M196.8 93.9h-.5M196.8 93.9l-2 .3M225.8 88.9l-29 5M234.1 80.8v.1M234.3 81.7v.1M234.5 82.7h.1M234.7 83.6v.1M234.9 84.5v.1M235.1 85.4v.1"/>
<path d="M235.2 86.3v.1M235.4 87.2v.1M235.5 88.1v.1M235.7 89.1v.1M235.8 90v.1M235.9 90.9v.1M236 91.8l.1 .1M236.1 92.8v.1M236.2 93.7v.1M236.3 94.6v.1M236.4 95.5v.1M236.5 96.5v.1"/>
<path d="M236.5 97.4v.1M236.6 98.3v.1M236.6 99.3v.1M40.9 103v.2M41 101.1v.1M41 102v.2M41 104v.1M41 104.9v.2M41 100.2v.1M41 105.9v.1M41 106.8v.1M41.1 107.7v.1"/>
<path d="M41.1 108.7v.1M41.2 109.6v.1M41.2 110.5v.1M41.3 111.4v.1M41.4 112.4v.1M41.5 113.3v.1M41.6 114.2v.1M41.7 115.1v.2M41.8 116.1v.1M41.9 117l.1 .1M42.1 117.9v.1M42.2 118.9h.1"/>
<path d="M42.4 119.8v.1M45 103.4h79.8M114.7 119.6h-.9l-.2 .2v.4l.4 .1 .1-.3M146.5 101.9h.6zM148.8 119.9l5.3 9.3 1.1 .4M153.4 110.7l.7 .5M153.4 110.8l.7 .4M154.1 111.2l6.3 3.9M155.6 119.6l8.4 8.4M163.9 100.1l-5.4 .4-11.4 1.4M165.1 118.1l9.6 5.6M168.2 116.7l6.8 3.3"/>
<path d="M195.3 109l2.7 .3M196.7 109.1l1.3 .2M198 109.3l30.7 2.8M228.6 112.1h.1M235.2 119.8v.1M235.4 118.9h.1M235.5 117.9v.1M235.7 117v.1M235.8 116.1v.1M235.9 115.1v.2M236.1 114.2l-.1 .1M236.1 113.3v.1"/>
<path d="M236.2 112.4v.1M236.3 111.4v.1M236.4 110.5v.1M236.5 109.6v.1M236.5 108.7v.1M236.6 107.7v.1M236.6 106.8v.1M236.6 100.2v.1M236.6 105.9v.1M236.7 101.1v.1M236.7 102v.2M236.7 104v.1"/>
<path d="M236.7 104.9v.2M236.7 103v.2M42.5 120.7l.1 .1M42.7 121.6v.1M42.9 122.5v.1M43.1 123.4v.1M43.3 124.3v.1M43.5 125.2v.1M43.7 126.1v.1M43.9 127v.1M44.2 128h.1M44.4 128.8v.1"/>
<path d="M44.6 129.7l.1 .1M44.9 130.6v.1M45.2 131.5v.1M45.4 132.4l.1 .1M45.7 133.3l.1 .1M46 134.2l.1 .1M46.3 135.1l.1 .1M46.6 136h.1M46.9 136.8l.1 .1M47.3 137.7v.1M47.6 138.6v.1M47.9 139.4l.1 .1"/>
<path d="M142.8 125.4l-.8 .1 1.4 9.8M229.7 139.4l-.1 .1M230 138.6v.1M230.4 137.7l-.1 .1M230.7 136.8v.1M231 136h.1M231.3 135.1v.1M231.6 134.2v.1M231.9 133.3v.1M232.2 132.4v.1M232.5 131.5l-.1 .1M232.7 130.6v.1"/>
<path d="M233 129.7v.1M233.2 128.8v.1M233.5 128h-.1M233.7 127v.1M233.9 126.1v.1M234.1 125.2v.1M234.3 124.3v.1M234.5 123.4v.1M234.7 122.5v.1M234.9 121.6v.1M235.1 120.7v.1M48.3 140.3v.1"/>
<path d="M48.7 141.2h.1M49 142l.1 .1M49.4 142.9v.1M49.8 143.7v.1M50.2 144.5v.2M50.6 145.4v.1M51 146.2v.1M51.4 147.1v.1M51.8 147.9l.1 .1M52.2 148.7l.1 .1M52.7 149.5v.1M53.1 150.4l.1 .1"/>
<path d="M53.6 151.2v.1M54 152l.1 .1M54.5 152.8l.1 .1M55 153.6v.1M55.5 154.4v.1M56 155.2v.1M56.5 156h.1M57 156.7v.1M57.5 157.5v.1M58 158.3l.1 .1M58.5 159l.1 .1M59.1 159.8v.1"/>
<path d="M218.5 159.8v.1M219.1 159l-.1 .1M219.6 158.3v.1M220.1 157.5v.1M220.7 156.7l-.1 .1M221.2 156h-.1M221.7 155.2l-.1 .1M222.2 154.4l-.1 .1M222.6 153.6v.1M223.1 152.8v.1M223.6 152l-.1 .1M224 151.2v.1"/>
<path d="M224.5 150.4v.1M224.9 149.5v.1M225.4 148.7l-.1 .1M225.8 147.9v.1M226.2 147.1v.1M226.7 146.2l-.1 .1M227.1 145.4l-.1 .1M227.5 144.5l-.1 .2M227.8 143.7v.1M228.2 142.9v.1M228.6 142v.1M229 141.2h-.1"/>
<path d="M229.3 140.3v.1M59.6 160.6l.1 .1M60.2 161.3v.1M60.7 162.1l.1 .1M61.3 162.8v.1M61.8 163.5l.1 .1M62.4 164.3l.1 .1M63 165l.1 .1M63.6 165.7l.1 .1M64.2 166.4l.1 .1M64.8 167.1l.1 .1M65.4 167.8l.1 .1"/>
<path d="M66 168.5l.1 .1M66.7 169.2v.1M67.3 169.9l.1 .1M67.9 170.6h.1M68.6 171.3h.1M69.2 171.9l.1 .1M69.9 172.6l.1 .1M70.6 173.2v.1M71.2 173.9h.1M71.9 174.5l.1 .1M72.6 175.2h.1M73.3 175.8h.1"/>
<path d="M74 176.4l.1 .1M74.7 177l.1 .1M75.4 177.6l.1 .1M76.1 178.2l.1 .1M76.8 178.8l.1 .1M77.5 179.4l.1 .1M78.3 180h.1M199.3 180h.1M200.1 179.4l-.1 .1M200.8 178.8l-.1 .1M201.5 178.2l-.1 .1M202.2 177.6v.1"/>
<path d="M202.9 177v.1M203.6 176.4v.1M204.3 175.8h.1M205 175.2h.1M205.7 174.5l-.1 .1M206.4 173.9h-.1M207.1 173.2l-.1 .1M207.7 172.6l-.1 .1M208.4 171.9l-.1 .1M209 171.3h.1M209.7 170.6h-.1M210.3 169.9l-.1 .1"/>
<path d="M210.9 169.2v.1M211.6 168.5l-.1 .1M212.2 167.8l-.1 .1M212.8 167.1l-.1 .1M213.4 166.4l-.1 .1M214 165.7v.1M214.6 165l-.1 .1M215.2 164.3l-.1 .1M215.8 163.5l-.1 .1M216.3 162.8v.1M216.9 162.1l-.1 .1M217.5 161.3l-.1 .1"/>
<path d="M218 160.6v.1M79 180.6h.1M79.7 181.1l.1 .1M80.5 181.7h.1M81.2 182.2l.1 .1M82 182.8h.1M82.7 183.3l.1 .1M83.5 183.8l.1 .1M84.3 184.4h.1M85.1 184.9h.1M85.9 185.4h.1M86.6 185.9h.1"/>
<path d="M87.4 186.4h.1M88.2 186.9h.1M89 187.3l.1 .1M89.8 187.8l.1 .1M90.6 188.3h.1M91.4 188.7l.1 .1M92.2 189.2h.2M93.1 189.6l.1 .1M93.9 190l.1 .1M94.7 190.5h.1M95.6 190.9h.1M96.4 191.3h.1"/>
<path d="M97.2 191.7h.1M98.1 192.1h.1M98.9 192.4l.1 .1M99.8 192.8l.1 .1M100.6 193.2h.1M101.5 193.5l.1 .1M102.4 193.9l.1 .1M103.2 194.2l.1 .1M104.1 194.6h.1M105 194.9h.1M105.9 195.2v.1M106.7 195.5l.1 .1"/>
<path d="M107.6 195.8l.1 .1M108.5 196.1l.1 .1M109.4 196.4h.1M110.3 196.7h.1M111.1 197h.2M112.1 197.2v.1M112.9 197.5h.2M113.9 197.7h.1M114.7 198h.2M115.7 198.2h.1M116.6 198.4h.1M117.5 198.6h.1"/>
<path d="M118.4 198.8h.1M119.3 199h.1M120.2 199.2h.1M121.1 199.3h.1M122 199.5h.1M123 199.6v.1M123.9 199.8h.1M124.8 199.9l.1 .1M152.8 199.9l-.1 .1M153.8 199.8h-.2M154.7 199.6l-.1 .1M155.6 199.5h-.1"/>
<path d="M156.5 199.3h-.1M157.4 199.2h-.1M158.3 199h-.1M159.2 198.8h.1M160.1 198.6h.1M161.1 198.4h-.1M162 198.2h-.1M162.9 198h-.1M163.8 197.7h-.1M164.7 197.5h-.1M165.6 197.2l-.1 .1M166.5 197h-.1"/>
<path d="M167.4 196.7h-.1M168.3 196.4h-.2M169.1 196.1l-.1 .1M170 195.8l-.1 .1M170.9 195.5l-.1 .1M171.8 195.2l-.1 .1M172.7 194.9h-.1M173.5 194.6h-.1M174.4 194.2l-.1 .1M175.3 193.9l-.1 .1M176.1 193.5l-.1 .1M177 193.2h-.1"/>
<path d="M177.8 192.8l-.1 .1M178.7 192.4l-.1 .1M179.5 192.1h.1M180.4 191.7h-.1M181.2 191.3h-.1M182.1 190.9h-.1M182.9 190.5h-.1M183.7 190l-.1 .1M184.6 189.6l-.2 .1M185.4 189.2h-.1M186.2 188.7l-.1 .1M187 188.3h-.1"/>
<path d="M187.8 187.8l-.1 .1M188.6 187.3l-.1 .1M189.4 186.9h-.1M190.2 186.4h-.1M191 185.9h-.1M191.8 185.4h-.1M192.6 184.9h-.1M193.3 184.4h.1M194.1 183.8l-.1 .1M194.9 183.3l-.1 .1M195.6 182.8h-.1M196.4 182.2l-.1 .1"/>
<path d="M197.1 181.7h.1M197.9 181.1l-.1 .1M198.6 180.6h-.1M125.7 200.1h.1M126.6 200.2h.1M127.6 200.3h.1M128.5 200.4h.1M129.4 200.5h.1M130.3 200.6h.2M131.3 200.7h.1M132.2 200.7h.1M133.1 200.8h.1"/>
<path d="M134 200.8h.2M135 200.9h.1M135.9 200.9h.1M136.8 200.9h.1M137.8 200.9h.1M138.7 201h.2M139.7 200.9h.1M140.7 200.9h.1M141.6 200.9h.1M142.5 200.9h.1M143.5 200.8h.1M144.4 200.8h.1"/>
<path d="M145.3 200.7h.1M146.3 200.7h.1M147.3 200.6h-.1M148.2 200.5h-.1M149 200.4h.1M150 200.3h.1M150.9 200.2h.1M151.9 200.1h-.1"/>
</g>
<path d="M122.3 57.6l-.3 .3M161.8 43.6l.3 .2M119.9 64.2l.7 1.7a.87 .87 0 0 1-.2 .9 .87 .87 0 0 1-.9 .2M187 72.7l-7.4 4.3a1.96 1.96 0 0 1-2-.9 2.48 2.48 0 0 0-3.8 1.4l.9 1M165.5 90.2v.2M166.3 96.9l-.6 .1" fill="none" stroke="#069" stroke-width=".3"/>
<path d="M136.1 75.5h.6" fill="none" stroke="#069" stroke-width="1.4"/>
<path d="M156.9 54.6l-5.5 14.5" fill="none" stroke="#069" stroke-width=".7"/>
<circle cx="134.1" cy="13.1" r=".49" fill="#008000" stroke="#008000" stroke-width=".2"/>
<circle cx="134.1" cy="13.1" r=".28" fill="#fff" stroke="#000" stroke-width=".2"/>
<circle cx="114.4" cy="100.2" r=".49" fill="#008000" stroke="#008000" stroke-width=".2"/>
<circle cx="114.4" cy="100.2" r=".28" fill="#fff" stroke="#000" stroke-width=".2"/>
<circle cx="116.8" cy="100.5" r=".49" fill="#008000" stroke="#008000" stroke-width=".2"/>
<circle cx="116.8" cy="100.5" r=".28" fill="#fff" stroke="#000" stroke-width=".2"/>
<circle cx="141.5" cy="11.1" r=".49" fill="#008000" stroke="#008000" stroke-width=".2"/>
<circle cx="141.5" cy="11.1" r=".28" fill="#fff" stroke="#000" stroke-width=".2"/>
<circle cx="52.9" cy="70.3" r=".49" fill="#008000" stroke="#008000" stroke-width=".2"/>
<circle cx="52.9" cy="70.3" r=".28" fill="#fff" stroke="#000" stroke-width=".2"/>
<circle cx="71.3" cy="62.4" r=".49" fill="#008000" stroke="#008000" stroke-width=".2"/>
<circle cx="71.3" cy="62.4" r=".28" fill="#fff" stroke="#000" stroke-width=".2"/>
<circle cx="58.9" cy="57.1" r=".49" fill="#008000" stroke="#008000" stroke-width=".2"/>
<circle cx="58.9" cy="57.1" r=".28" fill="#fff" stroke="#000" stroke-width=".2"/>
<circle cx="87.4" cy="163.1" r=".49" fill="#008000" stroke="#008000" stroke-width=".2"/>
<circle cx="87.4" cy="163.1" r=".28" fill="#fff" stroke="#000" stroke-width=".2"/>
<circle cx="79.9" cy="170.2" r=".49" fill="#008000" stroke="#008000" stroke-width=".2"/>
<circle cx="79.9" cy="170.2" r=".28" fill="#fff" stroke="#000" stroke-width=".2"/>
<circle cx="78.1" cy="172.2" r=".49" fill="#008000" stroke="#008000" stroke-width=".2"/>
<circle cx="78.1" cy="172.2" r=".28" fill="#fff" stroke="#000" stroke-width=".2"/>
<circle cx="121.5" cy="38.6" r=".49" fill="#008000" stroke="#008000" stroke-width=".2"/>
<circle cx="121.5" cy="38.6" r=".28" fill="#fff" stroke="#000" stroke-width=".2"/>
<circle cx="122.6" cy="48.4" r=".49" fill="#008000" stroke="#008000" stroke-width=".2"/>
<circle cx="122.6" cy="48.4" r=".28" fill="#fff" stroke="#000" stroke-width=".2"/>
<circle cx="114.8" cy="13.7" r=".49" fill="#008000" stroke="#008000" stroke-width=".2"/>
<circle cx="114.8" cy="13.7" r=".28" fill="#fff" stroke="#000" stroke-width=".2"/>
<circle cx="76.3" cy="126.5" r=".49" fill="#008000" stroke="#008000" stroke-width=".2"/>
<circle cx="76.3" cy="126.5" r=".28" fill="#fff" stroke="#000" stroke-width=".2"/>
<circle cx="95.5" cy="117.3" r=".49" fill="#008000" stroke="#008000" stroke-width=".2"/>
<circle cx="95.5" cy="117.3" r=".28" fill="#fff" stroke="#000" stroke-width=".2"/>
<circle cx="95.9" cy="140.5" r=".49" fill="#008000" stroke="#008000" stroke-width=".2"/>
<circle cx="95.9" cy="140.5" r=".28" fill="#fff" stroke="#000" stroke-width=".2"/>
<circle cx="89.5" cy="121.4" r=".49" fill="#008000" stroke="#008000" stroke-width=".2"/>
<circle cx="89.5" cy="121.4" r=".28" fill="#fff" stroke="#000" stroke-width=".2"/>
<circle cx="52.2" cy="135.8" r=".49" fill="#008000" stroke="#008000" stroke-width=".2"/>
<circle cx="52.2" cy="135.8" r=".28" fill="#fff" stroke="#000" stroke-width=".2"/>
<circle cx="90.9" cy="124.7" r=".49" fill="#008000" stroke="#008000" stroke-width=".2"/>
<circle cx="90.9" cy="124.7" r=".28" fill="#fff" stroke="#000" stroke-width=".2"/>
<circle cx="117.2" cy="112.7" r=".49" fill="#008000" stroke="#008000" stroke-width=".2"/>
<circle cx="117.2" cy="112.7" r=".28" fill="#fff" stroke="#000" stroke-width=".2"/>
<circle cx="122.7" cy="14.2" r=".49" fill="#008000" stroke="#008000" stroke-width=".2"/>
<circle cx="122.7" cy="14.2" r=".28" fill="#fff" stroke="#000" stroke-width=".2"/>
<circle cx="123.7" cy="10.5" r=".49" fill="#008000" stroke="#008000" stroke-width=".2"/>
<circle cx="123.7" cy="10.5" r=".28" fill="#fff" stroke="#000" stroke-width=".2"/>
<circle cx="49.7" cy="88.5" r=".49" fill="#008000" stroke="#008000" stroke-width=".2"/>
<circle cx="49.7" cy="88.5" r=".28" fill="#fff" stroke="#000" stroke-width=".2"/>
<circle cx="96.1" cy="182.6" r=".49" fill="#008000" stroke="#008000" stroke-width=".2"/>
<circle cx="96.1" cy="182.6" r=".28" fill="#fff" stroke="#000" stroke-width=".2"/>
<circle cx="94.3" cy="185.8" r=".49" fill="#008000" stroke="#008000" stroke-width=".2"/>
<circle cx="94.3" cy="185.8" r=".28" fill="#fff" stroke="#000" stroke-width=".2"/>
<circle cx="78.8" cy="51.8" r=".49" fill="#008000" stroke="#008000" stroke-width=".2"/>
<circle cx="78.8" cy="51.8" r=".28" fill="#fff" stroke="#000" stroke-width=".2"/>
<circle cx="68.1" cy="41" r=".49" fill="#008000" stroke="#008000" stroke-width=".2"/>
<circle cx="68.1" cy="41" r=".28" fill="#fff" stroke="#000" stroke-width=".2"/>
<circle cx="78.6" cy="154.2" r=".49" fill="#008000" stroke="#008000" stroke-width=".2"/>
<circle cx="78.6" cy="154.2" r=".28" fill="#fff" stroke="#000" stroke-width=".2"/>
<circle cx="68.1" cy="165.1" r=".49" fill="#008000" stroke="#008000" stroke-width=".2"/>
<circle cx="68.1" cy="165.1" r=".28" fill="#fff" stroke="#000" stroke-width=".2"/>
<circle cx="87.8" cy="147.5" r=".49" fill="#008000" stroke="#008000" stroke-width=".2"/>
<circle cx="87.8" cy="147.5" r=".28" fill="#fff" stroke="#000" stroke-width=".2"/>
<circle cx="86.6" cy="57.1" r=".49" fill="#008000" stroke="#008000" stroke-width=".2"/>
<circle cx="86.6" cy="57.1" r=".28" fill="#fff" stroke="#000" stroke-width=".2"/>
<circle cx="100.4" cy="47.4" r=".49" fill="#008000" stroke="#008000" stroke-width=".2"/>
<circle cx="100.4" cy="47.4" r=".28" fill="#fff" stroke="#000" stroke-width=".2"/>
<circle cx="99.2" cy="45.9" r=".49" fill="#008000" stroke="#008000" stroke-width=".2"/>
<circle cx="99.2" cy="45.9" r=".28" fill="#fff" stroke="#000" stroke-width=".2"/>
<circle cx="45.8" cy="87.9" r=".49" fill="#008000" stroke="#008000" stroke-width=".2"/>
<circle cx="45.8" cy="87.9" r=".28" fill="#fff" stroke="#000" stroke-width=".2"/>
<circle cx="141.2" cy="47.3" r=".49" fill="#008000" stroke="#008000" stroke-width=".2"/>
<circle cx="141.2" cy="47.3" r=".28" fill="#fff" stroke="#000" stroke-width=".2"/>
<circle cx="140.3" cy="9.2" r=".49" fill="#008000" stroke="#008000" stroke-width=".2"/>
<circle cx="140.3" cy="9.2" r=".28" fill="#fff" stroke="#000" stroke-width=".2"/>
<circle cx="100.6" cy="127.9" r=".49" fill="#008000" stroke="#008000" stroke-width=".2"/>
<circle cx="100.6" cy="127.9" r=".28" fill="#fff" stroke="#000" stroke-width=".2"/>
<circle cx="89.1" cy="130.7" r=".49" fill="#008000" stroke="#008000" stroke-width=".2"/>
<circle cx="89.1" cy="130.7" r=".28" fill="#fff" stroke="#000" stroke-width=".2"/>
<circle cx="57.7" cy="150.4" r=".49" fill="#008000" stroke="#008000" stroke-width=".2"/>
<circle cx="57.7" cy="150.4" r=".28" fill="#fff" stroke="#000" stroke-width=".2"/>
<circle cx="123.9" cy="121.4" r=".49" fill="#008000" stroke="#008000" stroke-width=".2"/>
<circle cx="123.9" cy="121.4" r=".28" fill="#fff" stroke="#000" stroke-width=".2"/>
<circle cx="80.6" cy="176.6" r=".49" fill="#008000" stroke="#008000" stroke-width=".2"/>
<circle cx="80.6" cy="176.6" r=".28" fill="#fff" stroke="#000" stroke-width=".2"/>
<circle cx="107.7" cy="88.4" r=".49" fill="#008000" stroke="#008000" stroke-width=".2"/>
<circle cx="107.7" cy="88.4" r=".28" fill="#fff" stroke="#000" stroke-width=".2"/>
<circle cx="122" cy="95" r=".49" fill="#008000" stroke="#008000" stroke-width=".2"/>
<circle cx="122" cy="95" r=".28" fill="#fff" stroke="#000" stroke-width=".2"/>
<circle cx="123.8" cy="112.9" r=".49" fill="#008000" stroke="#008000" stroke-width=".2"/>
<circle cx="123.8" cy="112.9" r=".28" fill="#fff" stroke="#000" stroke-width=".2"/>
<circle cx="109.8" cy="17.6" r=".49" fill="#008000" stroke="#008000" stroke-width=".2"/>
<circle cx="109.8" cy="17.6" r=".28" fill="#fff" stroke="#000" stroke-width=".2"/>
<circle cx="107.9" cy="12.1" r=".49" fill="#008000" stroke="#008000" stroke-width=".2"/>
<circle cx="107.9" cy="12.1" r=".28" fill="#fff" stroke="#000" stroke-width=".2"/>
<circle cx="48.5" cy="105.8" r=".49" fill="#008000" stroke="#008000" stroke-width=".2"/>
<circle cx="48.5" cy="105.8" r=".28" fill="#fff" stroke="#000" stroke-width=".2"/>
<circle cx="105.3" cy="187" r=".49" fill="#008000" stroke="#008000" stroke-width=".2"/>
<circle cx="105.3" cy="187" r=".28" fill="#fff" stroke="#000" stroke-width=".2"/>
<circle cx="103.3" cy="192.3" r=".49" fill="#008000" stroke="#008000" stroke-width=".2"/>
<circle cx="103.3" cy="192.3" r=".28" fill="#fff" stroke="#000" stroke-width=".2"/>
<circle cx="86.1" cy="44.2" r=".49" fill="#008000" stroke="#008000" stroke-width=".2"/>
<circle cx="86.1" cy="44.2" r=".28" fill="#fff" stroke="#000" stroke-width=".2"/>
<circle cx="91.2" cy="54.8" r=".49" fill="#008000" stroke="#008000" stroke-width=".2"/>
<circle cx="91.2" cy="54.8" r=".28" fill="#fff" stroke="#000" stroke-width=".2"/>
<circle cx="114.8" cy="78.6" r=".49" fill="#008000" stroke="#008000" stroke-width=".2"/>
<circle cx="114.8" cy="78.6" r=".28" fill="#fff" stroke="#000" stroke-width=".2"/>
<circle cx="72.9" cy="33.1" r=".49" fill="#008000" stroke="#008000" stroke-width=".2"/>
<circle cx="72.9" cy="33.1" r=".28" fill="#fff" stroke="#000" stroke-width=".2"/>
<circle cx="72.2" cy="145.5" r=".49" fill="#008000" stroke="#008000" stroke-width=".2"/>
<circle cx="72.2" cy="145.5" r=".28" fill="#fff" stroke="#000" stroke-width=".2"/>
<circle cx="58.9" cy="156.4" r=".49" fill="#008000" stroke="#008000" stroke-width=".2"/>
<circle cx="58.9" cy="156.4" r=".28" fill="#fff" stroke="#000" stroke-width=".2"/>
<circle cx="42.2" cy="106" r=".49" fill="#008000" stroke="#008000" stroke-width=".2"/>
<circle cx="42.2" cy="106" r=".28" fill="#fff" stroke="#000" stroke-width=".2"/>
<circle cx="95" cy="154.8" r=".49" fill="#008000" stroke="#008000" stroke-width=".2"/>
<circle cx="95" cy="154.8" r=".28" fill="#fff" stroke="#000" stroke-width=".2"/>
<circle cx="109" cy="137.6" r=".49" fill="#008000" stroke="#008000" stroke-width=".2"/>
<circle cx="109" cy="137.6" r=".28" fill="#fff" stroke="#000" stroke-width=".2"/>
<circle cx="73" cy="173" r=".49" fill="#008000" stroke="#008000" stroke-width=".2"/>
<circle cx="73" cy="173" r=".28" fill="#fff" stroke="#000" stroke-width=".2"/>
<circle cx="98.6" cy="145.5" r=".49" fill="#008000" stroke="#008000" stroke-width=".2"/>
<circle cx="98.6" cy="145.5" r=".28" fill="#fff" stroke="#000" stroke-width=".2"/>
<circle cx="100.1" cy="146.9" r=".49" fill="#008000" stroke="#008000" stroke-width=".2"/>
<circle cx="100.1" cy="146.9" r=".28" fill="#fff" stroke="#000" stroke-width=".2"/>
<circle cx="84.1" cy="118.1" r=".49" fill="#008000" stroke="#008000" stroke-width=".2"/>
<circle cx="84.1" cy="118.1" r=".28" fill="#fff" stroke="#000" stroke-width=".2"/>
<circle cx="46.1" cy="128.3" r=".49" fill="#008000" stroke="#008000" stroke-width=".2"/>
<circle cx="46.1" cy="128.3" r=".28" fill="#fff" stroke="#000" stroke-width=".2"/>
<circle cx="138.8" cy="53.3" r=".49" fill="#008000" stroke="#008000" stroke-width=".2"/>
<circle cx="138.8" cy="53.3" r=".28" fill="#fff" stroke="#000" stroke-width=".2"/>
<circle cx="112.8" cy="133.3" r=".49" fill="#008000" stroke="#008000" stroke-width=".2"/>
<circle cx="112.8" cy="133.3" r=".28" fill="#fff" stroke="#000" stroke-width=".2"/>
<circle cx="128.8" cy="141.8" r=".49" fill="#008000" stroke="#008000" stroke-width=".2"/>
<circle cx="128.8" cy="141.8" r=".28" fill="#fff" stroke="#000" stroke-width=".2"/>
<circle cx="133.3" cy="125.2" r=".49" fill="#008000" stroke="#008000" stroke-width=".2"/>
<circle cx="133.3" cy="125.2" r=".28" fill="#fff" stroke="#000" stroke-width=".2"/>
<circle cx="138.8" cy="77.5" r=".49" fill="#008000" stroke="#008000" stroke-width=".2"/>
<circle cx="138.8" cy="77.5" r=".28" fill="#fff" stroke="#000" stroke-width=".2"/>
<circle cx="120.3" cy="84.8" r=".49" fill="#008000" stroke="#008000" stroke-width=".2"/>
<circle cx="120.3" cy="84.8" r=".28" fill="#fff" stroke="#000" stroke-width=".2"/>
<circle cx="90" cy="116.5" r=".49" fill="#008000" stroke="#008000" stroke-width=".2"/>
<circle cx="90" cy="116.5" r=".28" fill="#fff" stroke="#000" stroke-width=".2"/>
<circle cx="98.9" cy="22.1" r=".49" fill="#008000" stroke="#008000" stroke-width=".2"/>
<circle cx="98.9" cy="22.1" r=".28" fill="#fff" stroke="#000" stroke-width=".2"/>
<circle cx="100.7" cy="25.7" r=".49" fill="#008000" stroke="#008000" stroke-width=".2"/>
<circle cx="100.7" cy="25.7" r=".28" fill="#fff" stroke="#000" stroke-width=".2"/>
<circle cx="49.8" cy="117.6" r=".49" fill="#008000" stroke="#008000" stroke-width=".2"/>
<circle cx="49.8" cy="117.6" r=".28" fill="#fff" stroke="#000" stroke-width=".2"/>
<circle cx="53.7" cy="116.8" r=".49" fill="#008000" stroke="#008000" stroke-width=".2"/>
<circle cx="53.7" cy="116.8" r=".28" fill="#fff" stroke="#000" stroke-width=".2"/>
<circle cx="121.1" cy="191.6" r=".49" fill="#008000" stroke="#008000" stroke-width=".2"/>
<circle cx="121.1" cy="191.6" r=".28" fill="#fff" stroke="#000" stroke-width=".2"/>
<circle cx="121.9" cy="187.6" r=".49" fill="#008000" stroke="#008000" stroke-width=".2"/>
<circle cx="121.9" cy="187.6" r=".28" fill="#fff" stroke="#000" stroke-width=".2"/>
<circle cx="97.3" cy="35.8" r=".49" fill="#008000" stroke="#008000" stroke-width=".2"/>
<circle cx="97.3" cy="35.8" r=".28" fill="#fff" stroke="#000" stroke-width=".2"/>
<circle cx="93.6" cy="29.9" r=".49" fill="#008000" stroke="#008000" stroke-width=".2"/>
<circle cx="93.6" cy="29.9" r=".28" fill="#fff" stroke="#000" stroke-width=".2"/>
<circle cx="66.2" cy="134.5" r=".49" fill="#008000" stroke="#008000" stroke-width=".2"/>
<circle cx="66.2" cy="134.5" r=".28" fill="#fff" stroke="#000" stroke-width=".2"/>
<circle cx="60.2" cy="138.4" r=".49" fill="#008000" stroke="#008000" stroke-width=".2"/>
<circle cx="60.2" cy="138.4" r=".28" fill="#fff" stroke="#000" stroke-width=".2"/>
<circle cx="83.1" cy="64.5" r=".49" fill="#008000" stroke="#008000" stroke-width=".2"/>
<circle cx="83.1" cy="64.5" r=".28" fill="#fff" stroke="#000" stroke-width=".2"/>
<circle cx="68.8" cy="52.6" r=".49" fill="#008000" stroke="#008000" stroke-width=".2"/>
<circle cx="68.8" cy="52.6" r=".28" fill="#fff" stroke="#000" stroke-width=".2"/>
<circle cx="105.3" cy="161.9" r=".49" fill="#008000" stroke="#008000" stroke-width=".2"/>
<circle cx="105.3" cy="161.9" r=".28" fill="#fff" stroke="#000" stroke-width=".2"/>
<circle cx="118.2" cy="143.7" r=".49" fill="#008000" stroke="#008000" stroke-width=".2"/>
<circle cx="118.2" cy="143.7" r=".28" fill="#fff" stroke="#000" stroke-width=".2"/>
<circle cx="108.7" cy="163.6" r=".49" fill="#008000" stroke="#008000" stroke-width=".2"/>
<circle cx="108.7" cy="163.6" r=".28" fill="#fff" stroke="#000" stroke-width=".2"/>
<circle cx="100.5" cy="180.4" r=".49" fill="#008000" stroke="#008000" stroke-width=".2"/>
<circle cx="100.5" cy="180.4" r=".28" fill="#fff" stroke="#000" stroke-width=".2"/>
<circle cx="82" cy="105.7" r=".49" fill="#008000" stroke="#008000" stroke-width=".2"/>
<circle cx="82" cy="105.7" r=".28" fill="#fff" stroke="#000" stroke-width=".2"/>
<circle cx="52.7" cy="105.7" r=".49" fill="#008000" stroke="#008000" stroke-width=".2"/>
<circle cx="52.7" cy="105.7" r=".28" fill="#fff" stroke="#000" stroke-width=".2"/>
<circle cx="124.1" cy="61.4" r=".49" fill="#008000" stroke="#008000" stroke-width=".2"/>
<circle cx="124.1" cy="61.4" r=".28" fill="#fff" stroke="#000" stroke-width=".2"/>
<circle cx="111" cy="21.4" r=".49" fill="#008000" stroke="#008000" stroke-width=".2"/>
<circle cx="111" cy="21.4" r=".28" fill="#fff" stroke="#000" stroke-width=".2"/>
<circle cx="124.7" cy="72" r=".49" fill="#008000" stroke="#008000" stroke-width=".2"/>
<circle cx="124.7" cy="72" r=".28" fill="#fff" stroke="#000" stroke-width=".2"/>
<circle cx="119.9" cy="61.7" r=".49" fill="#008000" stroke="#008000" stroke-width=".2"/>
<circle cx="119.9" cy="61.7" r=".28" fill="#fff" stroke="#000" stroke-width=".2"/>
<circle cx="132.5" cy="110" r=".49" fill="#008000" stroke="#008000" stroke-width=".2"/>
<circle cx="132.5" cy="110" r=".28" fill="#fff" stroke="#000" stroke-width=".2"/>
<circle cx="100.8" cy="137.8" r=".49" fill="#008000" stroke="#008000" stroke-width=".2"/>
<circle cx="100.8" cy="137.8" r=".28" fill="#fff" stroke="#000" stroke-width=".2"/>
<circle cx="113.2" cy="147.8" r=".49" fill="#008000" stroke="#008000" stroke-width=".2"/>
<circle cx="113.2" cy="147.8" r=".28" fill="#fff" stroke="#000" stroke-width=".2"/>
<circle cx="90.1" cy="120.2" r=".49" fill="#008000" stroke="#008000" stroke-width=".2"/>
<circle cx="90.1" cy="120.2" r=".28" fill="#fff" stroke="#000" stroke-width=".2"/>
<circle cx="57.7" cy="132" r=".49" fill="#008000" stroke="#008000" stroke-width=".2"/>
<circle cx="57.7" cy="132" r=".28" fill="#fff" stroke="#000" stroke-width=".2"/>
<circle cx="86.1" cy="29.8" r=".49" fill="#008000" stroke="#008000" stroke-width=".2"/>
<circle cx="86.1" cy="29.8" r=".28" fill="#fff" stroke="#000" stroke-width=".2"/>
<circle cx="88.9" cy="34.5" r=".49" fill="#008000" stroke="#008000" stroke-width=".2"/>
<circle cx="88.9" cy="34.5" r=".28" fill="#fff" stroke="#000" stroke-width=".2"/>
<circle cx="50.9" cy="123.8" r=".49" fill="#008000" stroke="#008000" stroke-width=".2"/>
<circle cx="50.9" cy="123.8" r=".28" fill="#fff" stroke="#000" stroke-width=".2"/>
<circle cx="56.3" cy="122.6" r=".49" fill="#008000" stroke="#008000" stroke-width=".2"/>
<circle cx="56.3" cy="122.6" r=".28" fill="#fff" stroke="#000" stroke-width=".2"/>
<circle cx="129.7" cy="193" r=".49" fill="#008000" stroke="#008000" stroke-width=".2"/>
<circle cx="129.7" cy="193" r=".28" fill="#fff" stroke="#000" stroke-width=".2"/>
<circle cx="130.2" cy="187.5" r=".49" fill="#008000" stroke="#008000" stroke-width=".2"/>
<circle cx="130.2" cy="187.5" r=".28" fill="#fff" stroke="#000" stroke-width=".2"/>
<circle cx="107.4" cy="30.5" r=".49" fill="#008000" stroke="#008000" stroke-width=".2"/>
<circle cx="107.4" cy="30.5" r=".28" fill="#fff" stroke="#000" stroke-width=".2"/>
<circle cx="104.5" cy="25.5" r=".49" fill="#008000" stroke="#008000" stroke-width=".2"/>
<circle cx="104.5" cy="25.5" r=".28" fill="#fff" stroke="#000" stroke-width=".2"/>
<circle cx="62.1" cy="122" r=".49" fill="#008000" stroke="#008000" stroke-width=".2"/>
<circle cx="62.1" cy="122" r=".28" fill="#fff" stroke="#000" stroke-width=".2"/>
<circle cx="76.7" cy="75.9" r=".49" fill="#008000" stroke="#008000" stroke-width=".2"/>
<circle cx="76.7" cy="75.9" r=".28" fill="#fff" stroke="#000" stroke-width=".2"/>
<circle cx="62.8" cy="65.5" r=".49" fill="#008000" stroke="#008000" stroke-width=".2"/>
<circle cx="62.8" cy="65.5" r=".28" fill="#fff" stroke="#000" stroke-width=".2"/>
<circle cx="119" cy="167.9" r=".49" fill="#008000" stroke="#008000" stroke-width=".2"/>
<circle cx="119" cy="167.9" r=".28" fill="#fff" stroke="#000" stroke-width=".2"/>
<circle cx="114" cy="184.2" r=".49" fill="#008000" stroke="#008000" stroke-width=".2"/>
<circle cx="114" cy="184.2" r=".28" fill="#fff" stroke="#000" stroke-width=".2"/>
<circle cx="82.8" cy="93.6" r=".49" fill="#008000" stroke="#008000" stroke-width=".2"/>
<circle cx="82.8" cy="93.6" r=".28" fill="#fff" stroke="#000" stroke-width=".2"/>
<circle cx="55.1" cy="89.5" r=".49" fill="#008000" stroke="#008000" stroke-width=".2"/>
<circle cx="55.1" cy="89.5" r=".28" fill="#fff" stroke="#000" stroke-width=".2"/>
<circle cx="118.2" cy="72.1" r=".49" fill="#008000" stroke="#008000" stroke-width=".2"/>
<circle cx="118.2" cy="72.1" r=".28" fill="#fff" stroke="#000" stroke-width=".2"/>
<circle cx="113.6" cy="65.1" r=".49" fill="#008000" stroke="#008000" stroke-width=".2"/>
<circle cx="113.6" cy="65.1" r=".28" fill="#fff" stroke="#000" stroke-width=".2"/>
<circle cx="137.6" cy="65.9" r=".49" fill="#008000" stroke="#008000" stroke-width=".2"/>
<circle cx="137.6" cy="65.9" r=".28" fill="#fff" stroke="#000" stroke-width=".2"/>
<circle cx="93.2" cy="31.6" r=".49" fill="#008000" stroke="#008000" stroke-width=".2"/>
<circle cx="93.2" cy="31.6" r=".28" fill="#fff" stroke="#000" stroke-width=".2"/>
<circle cx="134" cy="145.6" r=".49" fill="#008000" stroke="#008000" stroke-width=".2"/>
<circle cx="134" cy="145.6" r=".28" fill="#fff" stroke="#000" stroke-width=".2"/>
<circle cx="127" cy="102.7" r=".49" fill="#008000" stroke="#008000" stroke-width=".2"/>
<circle cx="127" cy="102.7" r=".28" fill="#fff" stroke="#000" stroke-width=".2"/>
<circle cx="55.1" cy="116.6" r=".49" fill="#008000" stroke="#008000" stroke-width=".2"/>
<circle cx="55.1" cy="116.6" r=".28" fill="#fff" stroke="#000" stroke-width=".2"/>
<circle cx="89.5" cy="114" r=".49" fill="#008000" stroke="#008000" stroke-width=".2"/>
<circle cx="89.5" cy="114" r=".28" fill="#fff" stroke="#000" stroke-width=".2"/>
<circle cx="79.3" cy="35.2" r=".49" fill="#008000" stroke="#008000" stroke-width=".2"/>
<circle cx="79.3" cy="35.2" r=".28" fill="#fff" stroke="#000" stroke-width=".2"/>
<circle cx="85.5" cy="42.2" r=".49" fill="#008000" stroke="#008000" stroke-width=".2"/>
<circle cx="85.5" cy="42.2" r=".28" fill="#fff" stroke="#000" stroke-width=".2"/>
<circle cx="55.5" cy="138" r=".49" fill="#008000" stroke="#008000" stroke-width=".2"/>
<circle cx="55.5" cy="138" r=".28" fill="#fff" stroke="#000" stroke-width=".2"/>
<circle cx="64.1" cy="134.5" r=".49" fill="#008000" stroke="#008000" stroke-width=".2"/>
<circle cx="64.1" cy="134.5" r=".28" fill="#fff" stroke="#000" stroke-width=".2"/>
<circle cx="119.4" cy="26.6" r=".49" fill="#008000" stroke="#008000" stroke-width=".2"/>
<circle cx="119.4" cy="26.6" r=".28" fill="#fff" stroke="#000" stroke-width=".2"/>
<circle cx="120.2" cy="23.8" r=".49" fill="#008000" stroke="#008000" stroke-width=".2"/>
<circle cx="120.2" cy="23.8" r=".28" fill="#fff" stroke="#000" stroke-width=".2"/>
<circle cx="60.2" cy="110.8" r=".49" fill="#008000" stroke="#008000" stroke-width=".2"/>
<circle cx="60.2" cy="110.8" r=".28" fill="#fff" stroke="#000" stroke-width=".2"/>
<circle cx="57.3" cy="111.1" r=".49" fill="#008000" stroke="#008000" stroke-width=".2"/>
<circle cx="57.3" cy="111.1" r=".28" fill="#fff" stroke="#000" stroke-width=".2"/>
<circle cx="127.3" cy="182.9" r=".49" fill="#008000" stroke="#008000" stroke-width=".2"/>
<circle cx="127.3" cy="182.9" r=".28" fill="#fff" stroke="#000" stroke-width=".2"/>
<circle cx="72.5" cy="89.7" r=".49" fill="#008000" stroke="#008000" stroke-width=".2"/>
<circle cx="72.5" cy="89.7" r=".28" fill="#fff" stroke="#000" stroke-width=".2"/>
<circle cx="58.8" cy="84.2" r=".49" fill="#008000" stroke="#008000" stroke-width=".2"/>
<circle cx="58.8" cy="84.2" r=".28" fill="#fff" stroke="#000" stroke-width=".2"/>
<circle cx="81.2" cy="91.4" r=".49" fill="#008000" stroke="#008000" stroke-width=".2"/>
<circle cx="81.2" cy="91.4" r=".28" fill="#fff" stroke="#000" stroke-width=".2"/>
<circle cx="85.9" cy="82.4" r=".49" fill="#008000" stroke="#008000" stroke-width=".2"/>
<circle cx="85.9" cy="82.4" r=".28" fill="#fff" stroke="#000" stroke-width=".2"/>
<circle cx="84" cy="81.9" r=".49" fill="#008000" stroke="#008000" stroke-width=".2"/>
<circle cx="84" cy="81.9" r=".28" fill="#fff" stroke="#000" stroke-width=".2"/>
<circle cx="105" cy="72.8" r=".49" fill="#008000" stroke="#008000" stroke-width=".2"/>
<circle cx="105" cy="72.8" r=".28" fill="#fff" stroke="#000" stroke-width=".2"/>
<circle cx="80.4" cy="44.9" r=".49" fill="#008000" stroke="#008000" stroke-width=".2"/>
<circle cx="80.4" cy="44.9" r=".28" fill="#fff" stroke="#000" stroke-width=".2"/>
<circle cx="141.5" cy="91.2" r=".49" fill="#008000" stroke="#008000" stroke-width=".2"/>
<circle cx="141.5" cy="91.2" r=".28" fill="#fff" stroke="#000" stroke-width=".2"/>
<circle cx="135.7" cy="91.5" r=".49" fill="#008000" stroke="#008000" stroke-width=".2"/>
<circle cx="135.7" cy="91.5" r=".28" fill="#fff" stroke="#000" stroke-width=".2"/>
<circle cx="132.7" cy="92.9" r=".49" fill="#008000" stroke="#008000" stroke-width=".2"/>
<circle cx="132.7" cy="92.9" r=".28" fill="#fff" stroke="#000" stroke-width=".2"/>
<circle cx="98" cy="32.7" r=".49" fill="#008000" stroke="#008000" stroke-width=".2"/>
<circle cx="98" cy="32.7" r=".28" fill="#fff" stroke="#000" stroke-width=".2"/>
<circle cx="122.8" cy="183" r=".49" fill="#008000" stroke="#008000" stroke-width=".2"/>
<circle cx="122.8" cy="183" r=".28" fill="#fff" stroke="#000" stroke-width=".2"/>
<circle cx="131.6" cy="140.7" r=".49" fill="#008000" stroke="#008000" stroke-width=".2"/>
<circle cx="131.6" cy="140.7" r=".28" fill="#fff" stroke="#000" stroke-width=".2"/>
<circle cx="88.4" cy="114.9" r=".49" fill="#008000" stroke="#008000" stroke-width=".2"/>
<circle cx="88.4" cy="114.9" r=".28" fill="#fff" stroke="#000" stroke-width=".2"/>
<circle cx="59.4" cy="123.8" r=".49" fill="#008000" stroke="#008000" stroke-width=".2"/>
<circle cx="59.4" cy="123.8" r=".28" fill="#fff" stroke="#000" stroke-width=".2"/>
<circle cx="68.9" cy="46" r=".49" fill="#008000" stroke="#008000" stroke-width=".2"/>
<circle cx="68.9" cy="46" r=".28" fill="#fff" stroke="#000" stroke-width=".2"/>
<circle cx="82" cy="56.4" r=".49" fill="#008000" stroke="#008000" stroke-width=".2"/>
<circle cx="82" cy="56.4" r=".28" fill="#fff" stroke="#000" stroke-width=".2"/>
<circle cx="62" cy="150.5" r=".49" fill="#008000" stroke="#008000" stroke-width=".2"/>
<circle cx="62" cy="150.5" r=".28" fill="#fff" stroke="#000" stroke-width=".2"/>
<circle cx="76.2" cy="141.5" r=".49" fill="#008000" stroke="#008000" stroke-width=".2"/>
<circle cx="76.2" cy="141.5" r=".28" fill="#fff" stroke="#000" stroke-width=".2"/>
<circle cx="144" cy="25.1" r=".49" fill="#008000" stroke="#008000" stroke-width=".2"/>
<circle cx="144" cy="25.1" r=".28" fill="#fff" stroke="#000" stroke-width=".2"/>
<circle cx="143.8" cy="29.1" r=".49" fill="#008000" stroke="#008000" stroke-width=".2"/>
<circle cx="143.8" cy="29.1" r=".28" fill="#fff" stroke="#000" stroke-width=".2"/>
<circle cx="59.9" cy="97.8" r=".49" fill="#008000" stroke="#008000" stroke-width=".2"/>
<circle cx="59.9" cy="97.8" r=".28" fill="#fff" stroke="#000" stroke-width=".2"/>
<circle cx="71.2" cy="100.1" r=".49" fill="#008000" stroke="#008000" stroke-width=".2"/>
<circle cx="71.2" cy="100.1" r=".28" fill="#fff" stroke="#000" stroke-width=".2"/>
<circle cx="118.4" cy="179.5" r=".49" fill="#008000" stroke="#008000" stroke-width=".2"/>
<circle cx="118.4" cy="179.5" r=".28" fill="#fff" stroke="#000" stroke-width=".2"/>
<circle cx="119.8" cy="174" r=".49" fill="#008000" stroke="#008000" stroke-width=".2"/>
<circle cx="119.8" cy="174" r=".28" fill="#fff" stroke="#000" stroke-width=".2"/>
<circle cx="92.7" cy="69.9" r=".49" fill="#008000" stroke="#008000" stroke-width=".2"/>
<circle cx="92.7" cy="69.9" r=".28" fill="#fff" stroke="#000" stroke-width=".2"/>
<circle cx="80.4" cy="58.6" r=".49" fill="#008000" stroke="#008000" stroke-width=".2"/>
<circle cx="80.4" cy="58.6" r=".28" fill="#fff" stroke="#000" stroke-width=".2"/>
<circle cx="129.3" cy="159.1" r=".49" fill="#008000" stroke="#008000" stroke-width=".2"/>
<circle cx="129.3" cy="159.1" r=".28" fill="#fff" stroke="#000" stroke-width=".2"/>
<circle cx="126.8" cy="175.6" r=".49" fill="#008000" stroke="#008000" stroke-width=".2"/>
<circle cx="126.8" cy="175.6" r=".28" fill="#fff" stroke="#000" stroke-width=".2"/>
<circle cx="98" cy="82.7" r=".49" fill="#008000" stroke="#008000" stroke-width=".2"/>
<circle cx="98" cy="82.7" r=".28" fill="#fff" stroke="#000" stroke-width=".2"/>
<circle cx="100.2" cy="73.7" r=".49" fill="#008000" stroke="#008000" stroke-width=".2"/>
<circle cx="100.2" cy="73.7" r=".28" fill="#fff" stroke="#000" stroke-width=".2"/>
<circle cx="109.3" cy="80.6" r=".49" fill="#008000" stroke="#008000" stroke-width=".2"/>
<circle cx="109.3" cy="80.6" r=".28" fill="#fff" stroke="#000" stroke-width=".2"/>
<circle cx="116.4" cy="74" r=".49" fill="#008000" stroke="#008000" stroke-width=".2"/>
<circle cx="116.4" cy="74" r=".28" fill="#fff" stroke="#000" stroke-width=".2"/>
<circle cx="124.4" cy="84.5" r=".49" fill="#008000" stroke="#008000" stroke-width=".2"/>
<circle cx="124.4" cy="84.5" r=".28" fill="#fff" stroke="#000" stroke-width=".2"/>
<circle cx="138.7" cy="100.7" r=".49" fill="#008000" stroke="#008000" stroke-width=".2"/>
<circle cx="138.7" cy="100.7" r=".28" fill="#fff" stroke="#000" stroke-width=".2"/>
<circle cx="120.2" cy="131.8" r=".49" fill="#008000" stroke="#008000" stroke-width=".2"/>
<circle cx="120.2" cy="131.8" r=".28" fill="#fff" stroke="#000" stroke-width=".2"/>
<circle cx="99.9" cy="165.4" r=".49" fill="#008000" stroke="#008000" stroke-width=".2"/>
<circle cx="99.9" cy="165.4" r=".28" fill="#fff" stroke="#000" stroke-width=".2"/>
<circle cx="87.4" cy="113.8" r=".49" fill="#008000" stroke="#008000" stroke-width=".2"/>
<circle cx="87.4" cy="113.8" r=".28" fill="#fff" stroke="#000" stroke-width=".2"/>
<circle cx="66.9" cy="118.4" r=".49" fill="#008000" stroke="#008000" stroke-width=".2"/>
<circle cx="66.9" cy="118.4" r=".28" fill="#fff" stroke="#000" stroke-width=".2"/>
<circle cx="65.5" cy="98.2" r=".49" fill="#008000" stroke="#008000" stroke-width=".2"/>
<circle cx="65.5" cy="98.2" r=".28" fill="#fff" stroke="#000" stroke-width=".2"/>
<circle cx="62.1" cy="55.6" r=".49" fill="#008000" stroke="#008000" stroke-width=".2"/>
<circle cx="62.1" cy="55.6" r=".28" fill="#fff" stroke="#000" stroke-width=".2"/>
<circle cx="77.6" cy="65" r=".49" fill="#008000" stroke="#008000" stroke-width=".2"/>
<circle cx="77.6" cy="65" r=".28" fill="#fff" stroke="#000" stroke-width=".2"/>
<circle cx="68.8" cy="160.2" r=".49" fill="#008000" stroke="#008000" stroke-width=".2"/>
<circle cx="68.8" cy="160.2" r=".28" fill="#fff" stroke="#000" stroke-width=".2"/>
<circle cx="62" cy="84.8" r=".49" fill="#008000" stroke="#008000" stroke-width=".2"/>
<circle cx="62" cy="84.8" r=".28" fill="#fff" stroke="#000" stroke-width=".2"/>
<circle cx="68.7" cy="86.4" r=".49" fill="#008000" stroke="#008000" stroke-width=".2"/>
<circle cx="68.7" cy="86.4" r=".28" fill="#fff" stroke="#000" stroke-width=".2"/>
<circle cx="108.9" cy="176.3" r=".49" fill="#008000" stroke="#008000" stroke-width=".2"/>
<circle cx="108.9" cy="176.3" r=".28" fill="#fff" stroke="#000" stroke-width=".2"/>
<circle cx="111.7" cy="169.4" r=".49" fill="#008000" stroke="#008000" stroke-width=".2"/>
<circle cx="111.7" cy="169.4" r=".28" fill="#fff" stroke="#000" stroke-width=".2"/>
<circle cx="138.8" cy="31.4" r=".49" fill="#008000" stroke="#008000" stroke-width=".2"/>
<circle cx="138.8" cy="31.4" r=".28" fill="#fff" stroke="#000" stroke-width=".2"/>
<circle cx="101.4" cy="60.2" r=".49" fill="#008000" stroke="#008000" stroke-width=".2"/>
<circle cx="101.4" cy="60.2" r=".28" fill="#fff" stroke="#000" stroke-width=".2"/>
<circle cx="91.5" cy="48.9" r=".49" fill="#008000" stroke="#008000" stroke-width=".2"/>
<circle cx="91.5" cy="48.9" r=".28" fill="#fff" stroke="#000" stroke-width=".2"/>
<circle cx="117.4" cy="155.7" r=".49" fill="#008000" stroke="#008000" stroke-width=".2"/>
<circle cx="117.4" cy="155.7" r=".28" fill="#fff" stroke="#000" stroke-width=".2"/>
<circle cx="96.2" cy="85.7" r=".49" fill="#008000" stroke="#008000" stroke-width=".2"/>
<circle cx="96.2" cy="85.7" r=".28" fill="#fff" stroke="#000" stroke-width=".2"/>
<circle cx="101.9" cy="88" r=".49" fill="#008000" stroke="#008000" stroke-width=".2"/>
<circle cx="101.9" cy="88" r=".28" fill="#fff" stroke="#000" stroke-width=".2"/>
<circle cx="104.3" cy="83.4" r=".49" fill="#008000" stroke="#008000" stroke-width=".2"/>
<circle cx="104.3" cy="83.4" r=".28" fill="#fff" stroke="#000" stroke-width=".2"/>
<circle cx="118.3" cy="91.5" r=".49" fill="#008000" stroke="#008000" stroke-width=".2"/>
<circle cx="118.3" cy="91.5" r=".28" fill="#fff" stroke="#000" stroke-width=".2"/>
<circle cx="111.4" cy="121.7" r=".49" fill="#008000" stroke="#008000" stroke-width=".2"/>
<circle cx="111.4" cy="121.7" r=".28" fill="#fff" stroke="#000" stroke-width=".2"/>
<circle cx="130.6" cy="120.5" r=".49" fill="#008000" stroke="#008000" stroke-width=".2"/>
<circle cx="130.6" cy="120.5" r=".28" fill="#fff" stroke="#000" stroke-width=".2"/>
<circle cx="124" cy="115.8" r=".49" fill="#008000" stroke="#008000" stroke-width=".2"/>
<circle cx="124" cy="115.8" r=".28" fill="#fff" stroke="#000" stroke-width=".2"/>
<circle cx="71.6" cy="111.7" r=".49" fill="#008000" stroke="#008000" stroke-width=".2"/>
<circle cx="71.6" cy="111.7" r=".28" fill="#fff" stroke="#000" stroke-width=".2"/>
<circle cx="67.5" cy="110" r=".49" fill="#008000" stroke="#008000" stroke-width=".2"/>
<circle cx="67.5" cy="110" r=".28" fill="#fff" stroke="#000" stroke-width=".2"/>
<circle cx="87.9" cy="116.1" r=".49" fill="#008000" stroke="#008000" stroke-width=".2"/>
<circle cx="87.9" cy="116.1" r=".28" fill="#fff" stroke="#000" stroke-width=".2"/>
<circle cx="69.2" cy="120.8" r=".49" fill="#008000" stroke="#008000" stroke-width=".2"/>
<circle cx="69.2" cy="120.8" r=".28" fill="#fff" stroke="#000" stroke-width=".2"/>
<circle cx="72.4" cy="76" r=".49" fill="#008000" stroke="#008000" stroke-width=".2"/>
<circle cx="72.4" cy="76" r=".28" fill="#fff" stroke="#000" stroke-width=".2"/>
<circle cx="83.2" cy="148.3" r=".49" fill="#008000" stroke="#008000" stroke-width=".2"/>
<circle cx="83.2" cy="148.3" r=".28" fill="#fff" stroke="#000" stroke-width=".2"/>
<circle cx="113" cy="98.3" r=".49" fill="#008000" stroke="#008000" stroke-width=".2"/>
<circle cx="113" cy="98.3" r=".28" fill="#fff" stroke="#000" stroke-width=".2"/>
<circle cx="90.2" cy="91.5" r=".49" fill="#008000" stroke="#008000" stroke-width=".2"/>
<circle cx="90.2" cy="91.5" r=".28" fill="#fff" stroke="#000" stroke-width=".2"/>
<circle cx="74.8" cy="167" r=".49" fill="#008000" stroke="#008000" stroke-width=".2"/>
<circle cx="74.8" cy="167" r=".28" fill="#fff" stroke="#000" stroke-width=".2"/>
<circle cx="105.1" cy="137.5" r=".49" fill="#008000" stroke="#008000" stroke-width=".2"/>
<circle cx="105.1" cy="137.5" r=".28" fill="#fff" stroke="#000" stroke-width=".2"/>
<circle cx="99.5" cy="143" r=".49" fill="#008000" stroke="#008000" stroke-width=".2"/>
<circle cx="99.5" cy="143" r=".28" fill="#fff" stroke="#000" stroke-width=".2"/>
<circle cx="85.9" cy="156.2" r=".49" fill="#008000" stroke="#008000" stroke-width=".2"/>
<circle cx="85.9" cy="156.2" r=".28" fill="#fff" stroke="#000" stroke-width=".2"/>
<circle cx="74.4" cy="124.5" r=".49" fill="#008000" stroke="#008000" stroke-width=".2"/>
<circle cx="74.4" cy="124.5" r=".28" fill="#fff" stroke="#000" stroke-width=".2"/>
<circle cx="93" cy="118.2" r=".49" fill="#008000" stroke="#008000" stroke-width=".2"/>
<circle cx="93" cy="118.2" r=".28" fill="#fff" stroke="#000" stroke-width=".2"/>
<circle cx="95.1" cy="82.6" r=".49" fill="#008000" stroke="#008000" stroke-width=".2"/>
<circle cx="95.1" cy="82.6" r=".28" fill="#fff" stroke="#000" stroke-width=".2"/>
<circle cx="56.6" cy="66" r=".49" fill="#008000" stroke="#008000" stroke-width=".2"/>
<circle cx="56.6" cy="66" r=".28" fill="#fff" stroke="#000" stroke-width=".2"/>
<circle cx="65.8" cy="72.9" r=".49" fill="#008000" stroke="#008000" stroke-width=".2"/>
<circle cx="65.8" cy="72.9" r=".28" fill="#fff" stroke="#000" stroke-width=".2"/>
<circle cx="117.4" cy="51.5" r=".49" fill="#008000" stroke="#008000" stroke-width=".2"/>
<circle cx="117.4" cy="51.5" r=".28" fill="#fff" stroke="#000" stroke-width=".2"/>
<circle cx="120.2" cy="58.5" r=".49" fill="#008000" stroke="#008000" stroke-width=".2"/>
<circle cx="120.2" cy="58.5" r=".28" fill="#fff" stroke="#000" stroke-width=".2"/>
<circle cx="123.2" cy="35.1" r=".49" fill="#008000" stroke="#008000" stroke-width=".2"/>
<circle cx="123.2" cy="35.1" r=".28" fill="#fff" stroke="#000" stroke-width=".2"/>
<circle cx="127" cy="52.4" r=".49" fill="#008000" stroke="#008000" stroke-width=".2"/>
<circle cx="127" cy="52.4" r=".28" fill="#fff" stroke="#000" stroke-width=".2"/>
<circle cx="118.9" cy="55.1" r=".49" fill="#008000" stroke="#008000" stroke-width=".2"/>
<circle cx="118.9" cy="55.1" r=".28" fill="#fff" stroke="#000" stroke-width=".2"/>
<circle cx="87" cy="120.2" r=".49" fill="#008000" stroke="#008000" stroke-width=".2"/>
<circle cx="87" cy="120.2" r=".28" fill="#fff" stroke="#000" stroke-width=".2"/>
<circle cx="130.5" cy="19.8" r=".49" fill="#008000" stroke="#008000" stroke-width=".2"/>
<circle cx="130.5" cy="19.8" r=".28" fill="#fff" stroke="#000" stroke-width=".2"/>
<circle cx="129.9" cy="14.3" r=".49" fill="#008000" stroke="#008000" stroke-width=".2"/>
<circle cx="129.9" cy="14.3" r=".28" fill="#fff" stroke="#000" stroke-width=".2"/>
<circle cx="120.8" cy="17.7" r=".49" fill="#008000" stroke="#008000" stroke-width=".2"/>
<circle cx="120.8" cy="17.7" r=".28" fill="#fff" stroke="#000" stroke-width=".2"/>
<circle cx="113" cy="23.3" r=".49" fill="#008000" stroke="#008000" stroke-width=".2"/>
<circle cx="113" cy="23.3" r=".28" fill="#fff" stroke="#000" stroke-width=".2"/>
<circle cx="118.7" cy="35.7" r=".49" fill="#008000" stroke="#008000" stroke-width=".2"/>
<circle cx="118.7" cy="35.7" r=".28" fill="#fff" stroke="#000" stroke-width=".2"/>
<circle cx="71.5" cy="82.7" r=".49" fill="#008000" stroke="#008000" stroke-width=".2"/>
<circle cx="71.5" cy="82.7" r=".28" fill="#fff" stroke="#000" stroke-width=".2"/>
<circle cx="52" cy="76.9" r=".49" fill="#008000" stroke="#008000" stroke-width=".2"/>
<circle cx="52" cy="76.9" r=".28" fill="#fff" stroke="#000" stroke-width=".2"/>
<circle cx="111" cy="24.2" r=".49" fill="#008000" stroke="#008000" stroke-width=".2"/>
<circle cx="111" cy="24.2" r=".28" fill="#fff" stroke="#000" stroke-width=".2"/>
<circle cx="117.4" cy="43.5" r=".49" fill="#008000" stroke="#008000" stroke-width=".2"/>
<circle cx="117.4" cy="43.5" r=".28" fill="#fff" stroke="#000" stroke-width=".2"/>
<circle cx="75.8" cy="95.2" r=".49" fill="#008000" stroke="#008000" stroke-width=".2"/>
<circle cx="75.8" cy="95.2" r=".28" fill="#fff" stroke="#000" stroke-width=".2"/>
<circle cx="50.3" cy="91.7" r=".49" fill="#008000" stroke="#008000" stroke-width=".2"/>
<circle cx="50.3" cy="91.7" r=".28" fill="#fff" stroke="#000" stroke-width=".2"/>
<circle cx="100.8" cy="28.5" r=".49" fill="#008000" stroke="#008000" stroke-width=".2"/>
<circle cx="100.8" cy="28.5" r=".28" fill="#fff" stroke="#000" stroke-width=".2"/>
<circle cx="51.1" cy="94.2" r=".49" fill="#008000" stroke="#008000" stroke-width=".2"/>
<circle cx="51.1" cy="94.2" r=".28" fill="#fff" stroke="#000" stroke-width=".2"/>
<circle cx="112.1" cy="48.7" r=".49" fill="#008000" stroke="#008000" stroke-width=".2"/>
<circle cx="112.1" cy="48.7" r=".28" fill="#fff" stroke="#000" stroke-width=".2"/>
<circle cx="76.5" cy="97.7" r=".49" fill="#008000" stroke="#008000" stroke-width=".2"/>
<circle cx="76.5" cy="97.7" r=".28" fill="#fff" stroke="#000" stroke-width=".2"/>
<circle cx="93.5" cy="182.3" r=".49" fill="#008000" stroke="#008000" stroke-width=".2"/>
<circle cx="93.5" cy="182.3" r=".28" fill="#fff" stroke="#000" stroke-width=".2"/>
<circle cx="98.1" cy="170.8" r=".49" fill="#008000" stroke="#008000" stroke-width=".2"/>
<circle cx="98.1" cy="170.8" r=".28" fill="#fff" stroke="#000" stroke-width=".2"/>
<circle cx="99.2" cy="29.3" r=".49" fill="#008000" stroke="#008000" stroke-width=".2"/>
<circle cx="99.2" cy="29.3" r=".28" fill="#fff" stroke="#000" stroke-width=".2"/>
<circle cx="131" cy="163.2" r=".49" fill="#008000" stroke="#008000" stroke-width=".2"/>
<circle cx="131" cy="163.2" r=".28" fill="#fff" stroke="#000" stroke-width=".2"/>
<circle cx="127.2" cy="194.1" r=".49" fill="#008000" stroke="#008000" stroke-width=".2"/>
<circle cx="127.2" cy="194.1" r=".28" fill="#fff" stroke="#000" stroke-width=".2"/>
<circle cx="110.6" cy="50" r=".49" fill="#008000" stroke="#008000" stroke-width=".2"/>
<circle cx="110.6" cy="50" r=".28" fill="#fff" stroke="#000" stroke-width=".2"/>
<circle cx="110.1" cy="175.6" r=".49" fill="#008000" stroke="#008000" stroke-width=".2"/>
<circle cx="110.1" cy="175.6" r=".28" fill="#fff" stroke="#000" stroke-width=".2"/>
<circle cx="107.7" cy="186.8" r=".49" fill="#008000" stroke="#008000" stroke-width=".2"/>
<circle cx="107.7" cy="186.8" r=".28" fill="#fff" stroke="#000" stroke-width=".2"/>
<circle cx="89.9" cy="35.8" r=".49" fill="#008000" stroke="#008000" stroke-width=".2"/>
<circle cx="89.9" cy="35.8" r=".28" fill="#fff" stroke="#000" stroke-width=".2"/>
<circle cx="84.7" cy="24.9" r=".49" fill="#008000" stroke="#008000" stroke-width=".2"/>
<circle cx="84.7" cy="24.9" r=".28" fill="#fff" stroke="#000" stroke-width=".2"/>
<circle cx="43.9" cy="97" r=".49" fill="#008000" stroke="#008000" stroke-width=".2"/>
<circle cx="43.9" cy="97" r=".28" fill="#fff" stroke="#000" stroke-width=".2"/>
<circle cx="55.3" cy="97.5" r=".49" fill="#008000" stroke="#008000" stroke-width=".2"/>
<circle cx="55.3" cy="97.5" r=".28" fill="#fff" stroke="#000" stroke-width=".2"/>
<circle cx="55.4" cy="111.4" r=".49" fill="#008000" stroke="#008000" stroke-width=".2"/>
<circle cx="55.4" cy="111.4" r=".28" fill="#fff" stroke="#000" stroke-width=".2"/>
<circle cx="44.2" cy="112.5" r=".49" fill="#008000" stroke="#008000" stroke-width=".2"/>
<circle cx="44.2" cy="112.5" r=".28" fill="#fff" stroke="#000" stroke-width=".2"/>
<circle cx="110.1" cy="187.6" r=".49" fill="#008000" stroke="#008000" stroke-width=".2"/>
<circle cx="110.1" cy="187.6" r=".28" fill="#fff" stroke="#000" stroke-width=".2"/>
<circle cx="108.2" cy="193.1" r=".49" fill="#008000" stroke="#008000" stroke-width=".2"/>
<circle cx="108.2" cy="193.1" r=".28" fill="#fff" stroke="#000" stroke-width=".2"/>
<circle cx="121.2" cy="177" r=".49" fill="#008000" stroke="#008000" stroke-width=".2"/>
<circle cx="121.2" cy="177" r=".28" fill="#fff" stroke="#000" stroke-width=".2"/>
<circle cx="118.7" cy="187.9" r=".49" fill="#008000" stroke="#008000" stroke-width=".2"/>
<circle cx="118.7" cy="187.9" r=".28" fill="#fff" stroke="#000" stroke-width=".2"/>
<circle cx="84.6" cy="39.4" r=".49" fill="#008000" stroke="#008000" stroke-width=".2"/>
<circle cx="84.6" cy="39.4" r=".28" fill="#fff" stroke="#000" stroke-width=".2"/>
<circle cx="101.6" cy="57.2" r=".49" fill="#008000" stroke="#008000" stroke-width=".2"/>
<circle cx="101.6" cy="57.2" r=".28" fill="#fff" stroke="#000" stroke-width=".2"/>
<circle cx="101.1" cy="148.8" r=".49" fill="#008000" stroke="#008000" stroke-width=".2"/>
<circle cx="101.1" cy="148.8" r=".28" fill="#fff" stroke="#000" stroke-width=".2"/>
<circle cx="81.8" cy="169.3" r=".49" fill="#008000" stroke="#008000" stroke-width=".2"/>
<circle cx="81.8" cy="169.3" r=".28" fill="#fff" stroke="#000" stroke-width=".2"/>
<circle cx="82.9" cy="40.8" r=".49" fill="#008000" stroke="#008000" stroke-width=".2"/>
<circle cx="82.9" cy="40.8" r=".28" fill="#fff" stroke="#000" stroke-width=".2"/>
<circle cx="76.7" cy="33.9" r=".49" fill="#008000" stroke="#008000" stroke-width=".2"/>
<circle cx="76.7" cy="33.9" r=".28" fill="#fff" stroke="#000" stroke-width=".2"/>
<circle cx="53.1" cy="67.2" r=".49" fill="#008000" stroke="#008000" stroke-width=".2"/>
<circle cx="53.1" cy="67.2" r=".28" fill="#fff" stroke="#000" stroke-width=".2"/>
<circle cx="63.4" cy="71.6" r=".49" fill="#008000" stroke="#008000" stroke-width=".2"/>
<circle cx="63.4" cy="71.6" r=".28" fill="#fff" stroke="#000" stroke-width=".2"/>
<circle cx="73.7" cy="65.7" r=".49" fill="#008000" stroke="#008000" stroke-width=".2"/>
<circle cx="73.7" cy="65.7" r=".28" fill="#fff" stroke="#000" stroke-width=".2"/>
<circle cx="84.5" cy="51.8" r=".49" fill="#008000" stroke="#008000" stroke-width=".2"/>
<circle cx="84.5" cy="51.8" r=".28" fill="#fff" stroke="#000" stroke-width=".2"/>
<circle cx="78.8" cy="44.6" r=".49" fill="#008000" stroke="#008000" stroke-width=".2"/>
<circle cx="78.8" cy="44.6" r=".28" fill="#fff" stroke="#000" stroke-width=".2"/>
<circle cx="70.4" cy="55.2" r=".49" fill="#008000" stroke="#008000" stroke-width=".2"/>
<circle cx="70.4" cy="55.2" r=".28" fill="#fff" stroke="#000" stroke-width=".2"/>
<circle cx="72.4" cy="66.1" r=".49" fill="#008000" stroke="#008000" stroke-width=".2"/>
<circle cx="72.4" cy="66.1" r=".28" fill="#fff" stroke="#000" stroke-width=".2"/>
<circle cx="75.6" cy="60.7" r=".49" fill="#008000" stroke="#008000" stroke-width=".2"/>
<circle cx="75.6" cy="60.7" r=".28" fill="#fff" stroke="#000" stroke-width=".2"/>
<circle cx="130.9" cy="23.5" r=".49" fill="#008000" stroke="#008000" stroke-width=".2"/>
<circle cx="130.9" cy="23.5" r=".28" fill="#fff" stroke="#000" stroke-width=".2"/>
<circle cx="132.1" cy="35.2" r=".49" fill="#008000" stroke="#008000" stroke-width=".2"/>
<circle cx="132.1" cy="35.2" r=".28" fill="#fff" stroke="#000" stroke-width=".2"/>
<circle cx="71.8" cy="56.2" r=".49" fill="#008000" stroke="#008000" stroke-width=".2"/>
<circle cx="71.8" cy="56.2" r=".28" fill="#fff" stroke="#000" stroke-width=".2"/>
<circle cx="132.3" cy="25.4" r=".49" fill="#008000" stroke="#008000" stroke-width=".2"/>
<circle cx="132.3" cy="25.4" r=".28" fill="#fff" stroke="#000" stroke-width=".2"/>
<circle cx="133.5" cy="36.6" r=".49" fill="#008000" stroke="#008000" stroke-width=".2"/>
<circle cx="133.5" cy="36.6" r=".28" fill="#fff" stroke="#000" stroke-width=".2"/>
<circle cx="66.8" cy="60.6" r=".49" fill="#008000" stroke="#008000" stroke-width=".2"/>
<circle cx="66.8" cy="60.6" r=".28" fill="#fff" stroke="#000" stroke-width=".2"/>
<circle cx="130.3" cy="39.1" r=".49" fill="#008000" stroke="#008000" stroke-width=".2"/>
<circle cx="130.3" cy="39.1" r=".28" fill="#fff" stroke="#000" stroke-width=".2"/>
<circle cx="129.1" cy="27.8" r=".49" fill="#008000" stroke="#008000" stroke-width=".2"/>
<circle cx="129.1" cy="27.8" r=".28" fill="#fff" stroke="#000" stroke-width=".2"/>
<circle cx="63.4" cy="66.8" r=".49" fill="#008000" stroke="#008000" stroke-width=".2"/>
<circle cx="63.4" cy="66.8" r=".28" fill="#fff" stroke="#000" stroke-width=".2"/>
<circle cx="71.5" cy="71.2" r=".49" fill="#008000" stroke="#008000" stroke-width=".2"/>
<circle cx="71.5" cy="71.2" r=".28" fill="#fff" stroke="#000" stroke-width=".2"/>
<circle cx="77.6" cy="60.6" r=".49" fill="#008000" stroke="#008000" stroke-width=".2"/>
<circle cx="77.6" cy="60.6" r=".28" fill="#fff" stroke="#000" stroke-width=".2"/>
<circle cx="115.8" cy="183.5" r=".49" fill="#008000" stroke="#008000" stroke-width=".2"/>
<circle cx="115.8" cy="183.5" r=".28" fill="#fff" stroke="#000" stroke-width=".2"/>
<circle cx="132.7" cy="123.7" r=".49" fill="#008000" stroke="#008000" stroke-width=".2"/>
<circle cx="132.7" cy="123.7" r=".28" fill="#fff" stroke="#000" stroke-width=".2"/>
<circle cx="119.4" cy="111.7" r=".49" fill="#008000" stroke="#008000" stroke-width=".2"/>
<circle cx="119.4" cy="111.7" r=".28" fill="#fff" stroke="#000" stroke-width=".2"/>
<circle cx="129.9" cy="103" r=".49" fill="#008000" stroke="#008000" stroke-width=".2"/>
<circle cx="129.9" cy="103" r=".28" fill="#fff" stroke="#000" stroke-width=".2"/>
<circle cx="59.1" cy="77.4" r=".49" fill="#008000" stroke="#008000" stroke-width=".2"/>
<circle cx="59.1" cy="77.4" r=".28" fill="#fff" stroke="#000" stroke-width=".2"/>
<circle cx="73.4" cy="82" r=".49" fill="#008000" stroke="#008000" stroke-width=".2"/>
<circle cx="73.4" cy="82" r=".28" fill="#fff" stroke="#000" stroke-width=".2"/>
<circle cx="57.3" cy="83.9" r=".49" fill="#008000" stroke="#008000" stroke-width=".2"/>
<circle cx="57.3" cy="83.9" r=".28" fill="#fff" stroke="#000" stroke-width=".2"/>
<circle cx="73.7" cy="88.5" r=".49" fill="#008000" stroke="#008000" stroke-width=".2"/>
<circle cx="73.7" cy="88.5" r=".28" fill="#fff" stroke="#000" stroke-width=".2"/>
<circle cx="56" cy="91" r=".49" fill="#008000" stroke="#008000" stroke-width=".2"/>
<circle cx="56" cy="91" r=".28" fill="#fff" stroke="#000" stroke-width=".2"/>
<circle cx="75" cy="93.7" r=".49" fill="#008000" stroke="#008000" stroke-width=".2"/>
<circle cx="75" cy="93.7" r=".28" fill="#fff" stroke="#000" stroke-width=".2"/>
<circle cx="106.3" cy="163" r=".49" fill="#008000" stroke="#008000" stroke-width=".2"/>
<circle cx="106.3" cy="163" r=".28" fill="#fff" stroke="#000" stroke-width=".2"/>
<circle cx="111.4" cy="153.4" r=".49" fill="#008000" stroke="#008000" stroke-width=".2"/>
<circle cx="111.4" cy="153.4" r=".28" fill="#fff" stroke="#000" stroke-width=".2"/>
<circle cx="57.4" cy="96.7" r=".49" fill="#008000" stroke="#008000" stroke-width=".2"/>
<circle cx="57.4" cy="96.7" r=".28" fill="#fff" stroke="#000" stroke-width=".2"/>
<circle cx="69.4" cy="97.4" r=".49" fill="#008000" stroke="#008000" stroke-width=".2"/>
<circle cx="69.4" cy="97.4" r=".28" fill="#fff" stroke="#000" stroke-width=".2"/>
<circle cx="75.8" cy="132.7" r=".49" fill="#008000" stroke="#008000" stroke-width=".2"/>
<circle cx="75.8" cy="132.7" r=".28" fill="#fff" stroke="#000" stroke-width=".2"/>
<circle cx="117.1" cy="166.1" r=".49" fill="#008000" stroke="#008000" stroke-width=".2"/>
<circle cx="117.1" cy="166.1" r=".28" fill="#fff" stroke="#000" stroke-width=".2"/>
<circle cx="120.6" cy="155.8" r=".49" fill="#008000" stroke="#008000" stroke-width=".2"/>
<circle cx="120.6" cy="155.8" r=".28" fill="#fff" stroke="#000" stroke-width=".2"/>
<circle cx="56.5" cy="98.3" r=".49" fill="#008000" stroke="#008000" stroke-width=".2"/>
<circle cx="56.5" cy="98.3" r=".28" fill="#fff" stroke="#000" stroke-width=".2"/>
<circle cx="68.3" cy="99.3" r=".49" fill="#008000" stroke="#008000" stroke-width=".2"/>
<circle cx="68.3" cy="99.3" r=".28" fill="#fff" stroke="#000" stroke-width=".2"/>
<circle cx="78.9" cy="140" r=".49" fill="#008000" stroke="#008000" stroke-width=".2"/>
<circle cx="78.9" cy="140" r=".28" fill="#fff" stroke="#000" stroke-width=".2"/>
<circle cx="81.9" cy="137.9" r=".49" fill="#008000" stroke="#008000" stroke-width=".2"/>
<circle cx="81.9" cy="137.9" r=".28" fill="#fff" stroke="#000" stroke-width=".2"/>
<circle cx="108.9" cy="147.5" r=".49" fill="#008000" stroke="#008000" stroke-width=".2"/>
<circle cx="108.9" cy="147.5" r=".28" fill="#fff" stroke="#000" stroke-width=".2"/>
<circle cx="102.8" cy="156.5" r=".49" fill="#008000" stroke="#008000" stroke-width=".2"/>
<circle cx="102.8" cy="156.5" r=".28" fill="#fff" stroke="#000" stroke-width=".2"/>
<circle cx="56.8" cy="109.7" r=".49" fill="#008000" stroke="#008000" stroke-width=".2"/>
<circle cx="56.8" cy="109.7" r=".28" fill="#fff" stroke="#000" stroke-width=".2"/>
<circle cx="64.3" cy="109.2" r=".49" fill="#008000" stroke="#008000" stroke-width=".2"/>
<circle cx="64.3" cy="109.2" r=".28" fill="#fff" stroke="#000" stroke-width=".2"/>
<circle cx="76.5" cy="144.5" r=".49" fill="#008000" stroke="#008000" stroke-width=".2"/>
<circle cx="76.5" cy="144.5" r=".28" fill="#fff" stroke="#000" stroke-width=".2"/>
<circle cx="85" cy="138.7" r=".49" fill="#008000" stroke="#008000" stroke-width=".2"/>
<circle cx="85" cy="138.7" r=".28" fill="#fff" stroke="#000" stroke-width=".2"/>
<circle cx="59.1" cy="128.9" r=".49" fill="#008000" stroke="#008000" stroke-width=".2"/>
<circle cx="59.1" cy="128.9" r=".28" fill="#fff" stroke="#000" stroke-width=".2"/>
<circle cx="87.4" cy="118.3" r=".49" fill="#008000" stroke="#008000" stroke-width=".2"/>
<circle cx="87.4" cy="118.3" r=".28" fill="#fff" stroke="#000" stroke-width=".2"/>
<circle cx="58.4" cy="117.6" r=".49" fill="#008000" stroke="#008000" stroke-width=".2"/>
<circle cx="58.4" cy="117.6" r=".28" fill="#fff" stroke="#000" stroke-width=".2"/>
<circle cx="83.8" cy="112.5" r=".49" fill="#008000" stroke="#008000" stroke-width=".2"/>
<circle cx="83.8" cy="112.5" r=".28" fill="#fff" stroke="#000" stroke-width=".2"/>
<circle cx="82" cy="109.8" r=".49" fill="#008000" stroke="#008000" stroke-width=".2"/>
<circle cx="82" cy="109.8" r=".28" fill="#fff" stroke="#000" stroke-width=".2"/>
<circle cx="56.9" cy="115.6" r=".49" fill="#008000" stroke="#008000" stroke-width=".2"/>
<circle cx="56.9" cy="115.6" r=".28" fill="#fff" stroke="#000" stroke-width=".2"/>
<circle cx="132.9" cy="56" r=".49" fill="#008000" stroke="#008000" stroke-width=".2"/>
<circle cx="132.9" cy="56" r=".28" fill="#fff" stroke="#000" stroke-width=".2"/>
<circle cx="131.7" cy="46.4" r=".49" fill="#008000" stroke="#008000" stroke-width=".2"/>
<circle cx="131.7" cy="46.4" r=".28" fill="#fff" stroke="#000" stroke-width=".2"/>
<circle cx="61.3" cy="134.6" r=".49" fill="#008000" stroke="#008000" stroke-width=".2"/>
<circle cx="61.3" cy="134.6" r=".28" fill="#fff" stroke="#000" stroke-width=".2"/>
<circle cx="80" cy="126.9" r=".49" fill="#008000" stroke="#008000" stroke-width=".2"/>
<circle cx="80" cy="126.9" r=".28" fill="#fff" stroke="#000" stroke-width=".2"/>
<circle cx="112.5" cy="46.5" r=".49" fill="#008000" stroke="#008000" stroke-width=".2"/>
<circle cx="112.5" cy="46.5" r=".28" fill="#fff" stroke="#000" stroke-width=".2"/>
<circle cx="119" cy="60.2" r=".49" fill="#008000" stroke="#008000" stroke-width=".2"/>
<circle cx="119" cy="60.2" r=".28" fill="#fff" stroke="#000" stroke-width=".2"/>
<circle cx="135.6" cy="58.8" r=".49" fill="#008000" stroke="#008000" stroke-width=".2"/>
<circle cx="135.6" cy="58.8" r=".28" fill="#fff" stroke="#000" stroke-width=".2"/>
<circle cx="134.6" cy="47.5" r=".49" fill="#008000" stroke="#008000" stroke-width=".2"/>
<circle cx="134.6" cy="47.5" r=".28" fill="#fff" stroke="#000" stroke-width=".2"/>
<circle cx="64.3" cy="141.3" r=".49" fill="#008000" stroke="#008000" stroke-width=".2"/>
<circle cx="64.3" cy="141.3" r=".28" fill="#fff" stroke="#000" stroke-width=".2"/>
<circle cx="83" cy="130.2" r=".49" fill="#008000" stroke="#008000" stroke-width=".2"/>
<circle cx="83" cy="130.2" r=".28" fill="#fff" stroke="#000" stroke-width=".2"/>
<circle cx="111.9" cy="50.6" r=".49" fill="#008000" stroke="#008000" stroke-width=".2"/>
<circle cx="111.9" cy="50.6" r=".28" fill="#fff" stroke="#000" stroke-width=".2"/>
<circle cx="119.1" cy="63.3" r=".49" fill="#008000" stroke="#008000" stroke-width=".2"/>
<circle cx="119.1" cy="63.3" r=".28" fill="#fff" stroke="#000" stroke-width=".2"/>
<circle cx="142" cy="59.6" r=".49" fill="#008000" stroke="#008000" stroke-width=".2"/>
<circle cx="142" cy="59.6" r=".28" fill="#fff" stroke="#000" stroke-width=".2"/>
<circle cx="142.6" cy="49.4" r=".49" fill="#008000" stroke="#008000" stroke-width=".2"/>
<circle cx="142.6" cy="49.4" r=".28" fill="#fff" stroke="#000" stroke-width=".2"/>
<circle cx="97.3" cy="75.2" r=".49" fill="#008000" stroke="#008000" stroke-width=".2"/>
<circle cx="97.3" cy="75.2" r=".28" fill="#fff" stroke="#000" stroke-width=".2"/>
<circle cx="103.7" cy="79.4" r=".49" fill="#008000" stroke="#008000" stroke-width=".2"/>
<circle cx="103.7" cy="79.4" r=".28" fill="#fff" stroke="#000" stroke-width=".2"/>
<circle cx="65.9" cy="142.1" r=".49" fill="#008000" stroke="#008000" stroke-width=".2"/>
<circle cx="65.9" cy="142.1" r=".28" fill="#fff" stroke="#000" stroke-width=".2"/>
<circle cx="94.9" cy="126.2" r=".49" fill="#008000" stroke="#008000" stroke-width=".2"/>
<circle cx="94.9" cy="126.2" r=".28" fill="#fff" stroke="#000" stroke-width=".2"/>
<circle cx="103.2" cy="133.2" r=".49" fill="#008000" stroke="#008000" stroke-width=".2"/>
<circle cx="103.2" cy="133.2" r=".28" fill="#fff" stroke="#000" stroke-width=".2"/>
<circle cx="110.2" cy="127.3" r=".49" fill="#008000" stroke="#008000" stroke-width=".2"/>
<circle cx="110.2" cy="127.3" r=".28" fill="#fff" stroke="#000" stroke-width=".2"/>
<circle cx="71.4" cy="151.4" r=".49" fill="#008000" stroke="#008000" stroke-width=".2"/>
<circle cx="71.4" cy="151.4" r=".28" fill="#fff" stroke="#000" stroke-width=".2"/>
<circle cx="100.8" cy="130.1" r=".49" fill="#008000" stroke="#008000" stroke-width=".2"/>
<circle cx="100.8" cy="130.1" r=".28" fill="#fff" stroke="#000" stroke-width=".2"/>
<circle cx="111.9" cy="138.7" r=".49" fill="#008000" stroke="#008000" stroke-width=".2"/>
<circle cx="111.9" cy="138.7" r=".28" fill="#fff" stroke="#000" stroke-width=".2"/>
<circle cx="120.1" cy="129.3" r=".49" fill="#008000" stroke="#008000" stroke-width=".2"/>
<circle cx="120.1" cy="129.3" r=".28" fill="#fff" stroke="#000" stroke-width=".2"/>
<circle cx="66" cy="161" r=".49" fill="#008000" stroke="#008000" stroke-width=".2"/>
<circle cx="66" cy="161" r=".28" fill="#fff" stroke="#000" stroke-width=".2"/>
<circle cx="82.7" cy="176.9" r=".49" fill="#008000" stroke="#008000" stroke-width=".2"/>
<circle cx="82.7" cy="176.9" r=".28" fill="#fff" stroke="#000" stroke-width=".2"/>
<circle cx="109.6" cy="132.9" r=".49" fill="#008000" stroke="#008000" stroke-width=".2"/>
<circle cx="109.6" cy="132.9" r=".28" fill="#fff" stroke="#000" stroke-width=".2"/>
<circle cx="118" cy="124.5" r=".49" fill="#008000" stroke="#008000" stroke-width=".2"/>
<circle cx="118" cy="124.5" r=".28" fill="#fff" stroke="#000" stroke-width=".2"/>
<circle cx="77.9" cy="157.5" r=".49" fill="#008000" stroke="#008000" stroke-width=".2"/>
<circle cx="77.9" cy="157.5" r=".28" fill="#fff" stroke="#000" stroke-width=".2"/>
<circle cx="104.6" cy="94.2" r=".49" fill="#008000" stroke="#008000" stroke-width=".2"/>
<circle cx="104.6" cy="94.2" r=".28" fill="#fff" stroke="#000" stroke-width=".2"/>
<circle cx="114.4" cy="96.8" r=".49" fill="#008000" stroke="#008000" stroke-width=".2"/>
<circle cx="114.4" cy="96.8" r=".28" fill="#fff" stroke="#000" stroke-width=".2"/>
<circle cx="84.9" cy="167" r=".49" fill="#008000" stroke="#008000" stroke-width=".2"/>
<circle cx="84.9" cy="167" r=".28" fill="#fff" stroke="#000" stroke-width=".2"/>
<circle cx="120.2" cy="123.4" r=".49" fill="#008000" stroke="#008000" stroke-width=".2"/>
<circle cx="120.2" cy="123.4" r=".28" fill="#fff" stroke="#000" stroke-width=".2"/>
<circle cx="118.2" cy="84.8" r=".49" fill="#008000" stroke="#008000" stroke-width=".2"/>
<circle cx="118.2" cy="84.8" r=".28" fill="#fff" stroke="#000" stroke-width=".2"/>
<circle cx="108.2" cy="90.7" r=".49" fill="#008000" stroke="#008000" stroke-width=".2"/>
<circle cx="108.2" cy="90.7" r=".28" fill="#fff" stroke="#000" stroke-width=".2"/>
<circle cx="117.9" cy="94.7" r=".49" fill="#008000" stroke="#008000" stroke-width=".2"/>
<circle cx="117.9" cy="94.7" r=".28" fill="#fff" stroke="#000" stroke-width=".2"/>
<circle cx="89.8" cy="171" r=".49" fill="#008000" stroke="#008000" stroke-width=".2"/>
<circle cx="89.8" cy="171" r=".28" fill="#fff" stroke="#000" stroke-width=".2"/>
<circle cx="121.9" cy="126.4" r=".49" fill="#008000" stroke="#008000" stroke-width=".2"/>
<circle cx="121.9" cy="126.4" r=".28" fill="#fff" stroke="#000" stroke-width=".2"/>
<circle cx="131.7" cy="81.7" r=".49" fill="#008000" stroke="#008000" stroke-width=".2"/>
<circle cx="131.7" cy="81.7" r=".28" fill="#fff" stroke="#000" stroke-width=".2"/>
<circle cx="129.7" cy="75.6" r=".49" fill="#008000" stroke="#008000" stroke-width=".2"/>
<circle cx="129.7" cy="75.6" r=".28" fill="#fff" stroke="#000" stroke-width=".2"/>
<circle cx="114.2" cy="84.5" r=".49" fill="#008000" stroke="#008000" stroke-width=".2"/>
<circle cx="114.2" cy="84.5" r=".28" fill="#fff" stroke="#000" stroke-width=".2"/>
<circle cx="123.1" cy="91.3" r=".49" fill="#008000" stroke="#008000" stroke-width=".2"/>
<circle cx="123.1" cy="91.3" r=".28" fill="#fff" stroke="#000" stroke-width=".2"/>
<circle cx="101.6" cy="176" r=".49" fill="#008000" stroke="#008000" stroke-width=".2"/>
<circle cx="101.6" cy="176" r=".28" fill="#fff" stroke="#000" stroke-width=".2"/>
<circle cx="123.8" cy="125.3" r=".49" fill="#008000" stroke="#008000" stroke-width=".2"/>
<circle cx="123.8" cy="125.3" r=".28" fill="#fff" stroke="#000" stroke-width=".2"/>
<circle cx="112.9" cy="99.5" r=".49" fill="#008000" stroke="#008000" stroke-width=".2"/>
<circle cx="112.9" cy="99.5" r=".28" fill="#fff" stroke="#000" stroke-width=".2"/>
<circle cx="108.6" cy="98.8" r=".49" fill="#008000" stroke="#008000" stroke-width=".2"/>
<circle cx="108.6" cy="98.8" r=".28" fill="#fff" stroke="#000" stroke-width=".2"/>
<circle cx="94.8" cy="174.1" r=".49" fill="#008000" stroke="#008000" stroke-width=".2"/>
<circle cx="94.8" cy="174.1" r=".28" fill="#fff" stroke="#000" stroke-width=".2"/>
<circle cx="123.7" cy="123.6" r=".49" fill="#008000" stroke="#008000" stroke-width=".2"/>
<circle cx="123.7" cy="123.6" r=".28" fill="#fff" stroke="#000" stroke-width=".2"/>
<circle cx="131" cy="113.3" r=".49" fill="#008000" stroke="#008000" stroke-width=".2"/>
<circle cx="131" cy="113.3" r=".28" fill="#fff" stroke="#000" stroke-width=".2"/>
<circle cx="106.3" cy="180.1" r=".49" fill="#008000" stroke="#008000" stroke-width=".2"/>
<circle cx="106.3" cy="180.1" r=".28" fill="#fff" stroke="#000" stroke-width=".2"/>
<circle cx="124.1" cy="118.8" r=".49" fill="#008000" stroke="#008000" stroke-width=".2"/>
<circle cx="124.1" cy="118.8" r=".28" fill="#fff" stroke="#000" stroke-width=".2"/>
<circle cx="118.7" cy="110.7" r=".49" fill="#008000" stroke="#008000" stroke-width=".2"/>
<circle cx="118.7" cy="110.7" r=".28" fill="#fff" stroke="#000" stroke-width=".2"/>
<circle cx="128" cy="101.3" r=".49" fill="#008000" stroke="#008000" stroke-width=".2"/>
<circle cx="128" cy="101.3" r=".28" fill="#fff" stroke="#000" stroke-width=".2"/>
<circle cx="221.2" cy="140.2" r=".49" fill="#008000" stroke="#008000" stroke-width=".2"/>
<circle cx="221.2" cy="140.2" r=".28" fill="#fff" stroke="#000" stroke-width=".2"/>
<circle cx="211.5" cy="134.2" r=".49" fill="#008000" stroke="#008000" stroke-width=".2"/>
<circle cx="211.5" cy="134.2" r=".28" fill="#fff" stroke="#000" stroke-width=".2"/>
<circle cx="195.9" cy="129" r=".49" fill="#008000" stroke="#008000" stroke-width=".2"/>
<circle cx="195.9" cy="129" r=".28" fill="#fff" stroke="#000" stroke-width=".2"/>
<circle cx="202.7" cy="39.3" r=".49" fill="#008000" stroke="#008000" stroke-width=".2"/>
<circle cx="202.7" cy="39.3" r=".28" fill="#fff" stroke="#000" stroke-width=".2"/>
<circle cx="183.1" cy="58.8" r=".49" fill="#008000" stroke="#008000" stroke-width=".2"/>
<circle cx="183.1" cy="58.8" r=".28" fill="#fff" stroke="#000" stroke-width=".2"/>
<circle cx="180.4" cy="35.9" r=".49" fill="#008000" stroke="#008000" stroke-width=".2"/>
<circle cx="180.4" cy="35.9" r=".28" fill="#fff" stroke="#000" stroke-width=".2"/>
<circle cx="177.8" cy="39.7" r=".49" fill="#008000" stroke="#008000" stroke-width=".2"/>
<circle cx="177.8" cy="39.7" r=".28" fill="#fff" stroke="#000" stroke-width=".2"/>
<circle cx="191.6" cy="50.4" r=".49" fill="#008000" stroke="#008000" stroke-width=".2"/>
<circle cx="191.6" cy="50.4" r=".28" fill="#fff" stroke="#000" stroke-width=".2"/>
<circle cx="154.2" cy="169" r=".49" fill="#008000" stroke="#008000" stroke-width=".2"/>
<circle cx="154.2" cy="169" r=".28" fill="#fff" stroke="#000" stroke-width=".2"/>
<circle cx="198.4" cy="83.7" r=".49" fill="#008000" stroke="#008000" stroke-width=".2"/>
<circle cx="198.4" cy="83.7" r=".28" fill="#fff" stroke="#000" stroke-width=".2"/>
<circle cx="166.4" cy="152.8" r=".49" fill="#008000" stroke="#008000" stroke-width=".2"/>
<circle cx="166.4" cy="152.8" r=".28" fill="#fff" stroke="#000" stroke-width=".2"/>
<circle cx="168.3" cy="158.3" r=".49" fill="#008000" stroke="#008000" stroke-width=".2"/>
<circle cx="168.3" cy="158.3" r=".28" fill="#fff" stroke="#000" stroke-width=".2"/>
<circle cx="179.3" cy="55.4" r=".49" fill="#008000" stroke="#008000" stroke-width=".2"/>
<circle cx="179.3" cy="55.4" r=".28" fill="#fff" stroke="#000" stroke-width=".2"/>
<circle cx="190.8" cy="95.6" r=".49" fill="#008000" stroke="#008000" stroke-width=".2"/>
<circle cx="190.8" cy="95.6" r=".28" fill="#fff" stroke="#000" stroke-width=".2"/>
<circle cx="201" cy="95.9" r=".49" fill="#008000" stroke="#008000" stroke-width=".2"/>
<circle cx="201" cy="95.9" r=".28" fill="#fff" stroke="#000" stroke-width=".2"/>
<circle cx="214.7" cy="152.1" r=".49" fill="#008000" stroke="#008000" stroke-width=".2"/>
<circle cx="214.7" cy="152.1" r=".28" fill="#fff" stroke="#000" stroke-width=".2"/>
<circle cx="198.3" cy="143" r=".49" fill="#008000" stroke="#008000" stroke-width=".2"/>
<circle cx="198.3" cy="143" r=".28" fill="#fff" stroke="#000" stroke-width=".2"/>
<circle cx="210.5" cy="48.2" r=".49" fill="#008000" stroke="#008000" stroke-width=".2"/>
<circle cx="210.5" cy="48.2" r=".28" fill="#fff" stroke="#000" stroke-width=".2"/>
<circle cx="195.7" cy="59.5" r=".49" fill="#008000" stroke="#008000" stroke-width=".2"/>
<circle cx="195.7" cy="59.5" r=".28" fill="#fff" stroke="#000" stroke-width=".2"/>
<circle cx="215.7" cy="121.3" r=".49" fill="#008000" stroke="#008000" stroke-width=".2"/>
<circle cx="215.7" cy="121.3" r=".28" fill="#fff" stroke="#000" stroke-width=".2"/>
<circle cx="169.1" cy="30.2" r=".49" fill="#008000" stroke="#008000" stroke-width=".2"/>
<circle cx="169.1" cy="30.2" r=".28" fill="#fff" stroke="#000" stroke-width=".2"/>
<circle cx="166.3" cy="36.8" r=".49" fill="#008000" stroke="#008000" stroke-width=".2"/>
<circle cx="166.3" cy="36.8" r=".28" fill="#fff" stroke="#000" stroke-width=".2"/>
<circle cx="142" cy="173.2" r=".49" fill="#008000" stroke="#008000" stroke-width=".2"/>
<circle cx="142" cy="173.2" r=".28" fill="#fff" stroke="#000" stroke-width=".2"/>
<circle cx="177.5" cy="144.6" r=".49" fill="#008000" stroke="#008000" stroke-width=".2"/>
<circle cx="177.5" cy="144.6" r=".28" fill="#fff" stroke="#000" stroke-width=".2"/>
<circle cx="186" cy="157.2" r=".49" fill="#008000" stroke="#008000" stroke-width=".2"/>
<circle cx="186" cy="157.2" r=".28" fill="#fff" stroke="#000" stroke-width=".2"/>
<circle cx="160.6" cy="50.6" r=".49" fill="#008000" stroke="#008000" stroke-width=".2"/>
<circle cx="160.6" cy="50.6" r=".28" fill="#fff" stroke="#000" stroke-width=".2"/>
<circle cx="182.6" cy="118" r=".49" fill="#008000" stroke="#008000" stroke-width=".2"/>
<circle cx="182.6" cy="118" r=".28" fill="#fff" stroke="#000" stroke-width=".2"/>
<circle cx="161.2" cy="110.9" r=".49" fill="#008000" stroke="#008000" stroke-width=".2"/>
<circle cx="161.2" cy="110.9" r=".28" fill="#fff" stroke="#000" stroke-width=".2"/>
<circle cx="167.2" cy="84" r=".49" fill="#008000" stroke="#008000" stroke-width=".2"/>
<circle cx="167.2" cy="84" r=".28" fill="#fff" stroke="#000" stroke-width=".2"/>
<circle cx="160.1" cy="86.8" r=".49" fill="#008000" stroke="#008000" stroke-width=".2"/>
<circle cx="160.1" cy="86.8" r=".28" fill="#fff" stroke="#000" stroke-width=".2"/>
<circle cx="149.4" cy="77.7" r=".49" fill="#008000" stroke="#008000" stroke-width=".2"/>
<circle cx="149.4" cy="77.7" r=".28" fill="#fff" stroke="#000" stroke-width=".2"/>
<circle cx="210" cy="94.4" r=".49" fill="#008000" stroke="#008000" stroke-width=".2"/>
<circle cx="210" cy="94.4" r=".28" fill="#fff" stroke="#000" stroke-width=".2"/>
<circle cx="205.9" cy="93.9" r=".49" fill="#008000" stroke="#008000" stroke-width=".2"/>
<circle cx="205.9" cy="93.9" r=".28" fill="#fff" stroke="#000" stroke-width=".2"/>
<circle cx="190.7" cy="93.4" r=".49" fill="#008000" stroke="#008000" stroke-width=".2"/>
<circle cx="190.7" cy="93.4" r=".28" fill="#fff" stroke="#000" stroke-width=".2"/>
<circle cx="208.4" cy="119.6" r=".49" fill="#008000" stroke="#008000" stroke-width=".2"/>
<circle cx="208.4" cy="119.6" r=".28" fill="#fff" stroke="#000" stroke-width=".2"/>
<circle cx="206.7" cy="126.2" r=".49" fill="#008000" stroke="#008000" stroke-width=".2"/>
<circle cx="206.7" cy="126.2" r=".28" fill="#fff" stroke="#000" stroke-width=".2"/>
<circle cx="206.7" cy="162.7" r=".49" fill="#008000" stroke="#008000" stroke-width=".2"/>
<circle cx="206.7" cy="162.7" r=".28" fill="#fff" stroke="#000" stroke-width=".2"/>
<circle cx="193.9" cy="151.7" r=".49" fill="#008000" stroke="#008000" stroke-width=".2"/>
<circle cx="193.9" cy="151.7" r=".28" fill="#fff" stroke="#000" stroke-width=".2"/>
<circle cx="217.7" cy="59" r=".49" fill="#008000" stroke="#008000" stroke-width=".2"/>
<circle cx="217.7" cy="59" r=".28" fill="#fff" stroke="#000" stroke-width=".2"/>
<circle cx="203.6" cy="68.4" r=".49" fill="#008000" stroke="#008000" stroke-width=".2"/>
<circle cx="203.6" cy="68.4" r=".28" fill="#fff" stroke="#000" stroke-width=".2"/>
<circle cx="136.3" cy="176.7" r=".49" fill="#008000" stroke="#008000" stroke-width=".2"/>
<circle cx="136.3" cy="176.7" r=".28" fill="#fff" stroke="#000" stroke-width=".2"/>
<circle cx="217.6" cy="108.3" r=".49" fill="#008000" stroke="#008000" stroke-width=".2"/>
<circle cx="217.6" cy="108.3" r=".28" fill="#fff" stroke="#000" stroke-width=".2"/>
<circle cx="206.5" cy="106.3" r=".49" fill="#008000" stroke="#008000" stroke-width=".2"/>
<circle cx="206.5" cy="106.3" r=".28" fill="#fff" stroke="#000" stroke-width=".2"/>
<circle cx="212.1" cy="108" r=".49" fill="#008000" stroke="#008000" stroke-width=".2"/>
<circle cx="212.1" cy="108" r=".28" fill="#fff" stroke="#000" stroke-width=".2"/>
<circle cx="157.9" cy="26.4" r=".49" fill="#008000" stroke="#008000" stroke-width=".2"/>
<circle cx="157.9" cy="26.4" r=".28" fill="#fff" stroke="#000" stroke-width=".2"/>
<circle cx="157.8" cy="32.1" r=".49" fill="#008000" stroke="#008000" stroke-width=".2"/>
<circle cx="157.8" cy="32.1" r=".28" fill="#fff" stroke="#000" stroke-width=".2"/>
<circle cx="188.8" cy="130.2" r=".49" fill="#008000" stroke="#008000" stroke-width=".2"/>
<circle cx="188.8" cy="130.2" r=".28" fill="#fff" stroke="#000" stroke-width=".2"/>
<circle cx="179.9" cy="123.2" r=".49" fill="#008000" stroke="#008000" stroke-width=".2"/>
<circle cx="179.9" cy="123.2" r=".28" fill="#fff" stroke="#000" stroke-width=".2"/>
<circle cx="203.2" cy="137.8" r=".49" fill="#008000" stroke="#008000" stroke-width=".2"/>
<circle cx="203.2" cy="137.8" r=".28" fill="#fff" stroke="#000" stroke-width=".2"/>
<circle cx="143.9" cy="46.9" r=".49" fill="#008000" stroke="#008000" stroke-width=".2"/>
<circle cx="143.9" cy="46.9" r=".28" fill="#fff" stroke="#000" stroke-width=".2"/>
<circle cx="146.3" cy="30.1" r=".49" fill="#008000" stroke="#008000" stroke-width=".2"/>
<circle cx="146.3" cy="30.1" r=".28" fill="#fff" stroke="#000" stroke-width=".2"/>
<circle cx="151.8" cy="122.9" r=".49" fill="#008000" stroke="#008000" stroke-width=".2"/>
<circle cx="151.8" cy="122.9" r=".28" fill="#fff" stroke="#000" stroke-width=".2"/>
<circle cx="149.1" cy="118.4" r=".49" fill="#008000" stroke="#008000" stroke-width=".2"/>
<circle cx="149.1" cy="118.4" r=".28" fill="#fff" stroke="#000" stroke-width=".2"/>
<circle cx="158.5" cy="103.1" r=".49" fill="#008000" stroke="#008000" stroke-width=".2"/>
<circle cx="158.5" cy="103.1" r=".28" fill="#fff" stroke="#000" stroke-width=".2"/>
<circle cx="212" cy="103.1" r=".49" fill="#008000" stroke="#008000" stroke-width=".2"/>
<circle cx="212" cy="103.1" r=".28" fill="#fff" stroke="#000" stroke-width=".2"/>
<circle cx="158.8" cy="75.2" r=".49" fill="#008000" stroke="#008000" stroke-width=".2"/>
<circle cx="158.8" cy="75.2" r=".28" fill="#fff" stroke="#000" stroke-width=".2"/>
<circle cx="183.5" cy="44.9" r=".49" fill="#008000" stroke="#008000" stroke-width=".2"/>
<circle cx="183.5" cy="44.9" r=".28" fill="#fff" stroke="#000" stroke-width=".2"/>
<circle cx="188.9" cy="87" r=".49" fill="#008000" stroke="#008000" stroke-width=".2"/>
<circle cx="188.9" cy="87" r=".28" fill="#fff" stroke="#000" stroke-width=".2"/>
<circle cx="157.1" cy="97" r=".49" fill="#008000" stroke="#008000" stroke-width=".2"/>
<circle cx="157.1" cy="97" r=".28" fill="#fff" stroke="#000" stroke-width=".2"/>
<circle cx="198.4" cy="171" r=".49" fill="#008000" stroke="#008000" stroke-width=".2"/>
<circle cx="198.4" cy="171" r=".28" fill="#fff" stroke="#000" stroke-width=".2"/>
<circle cx="192.2" cy="164.1" r=".49" fill="#008000" stroke="#008000" stroke-width=".2"/>
<circle cx="192.2" cy="164.1" r=".28" fill="#fff" stroke="#000" stroke-width=".2"/>
<circle cx="222.3" cy="68.6" r=".49" fill="#008000" stroke="#008000" stroke-width=".2"/>
<circle cx="222.3" cy="68.6" r=".28" fill="#fff" stroke="#000" stroke-width=".2"/>
<circle cx="213.8" cy="72.1" r=".49" fill="#008000" stroke="#008000" stroke-width=".2"/>
<circle cx="213.8" cy="72.1" r=".28" fill="#fff" stroke="#000" stroke-width=".2"/>
<circle cx="156.8" cy="180.1" r=".49" fill="#008000" stroke="#008000" stroke-width=".2"/>
<circle cx="156.8" cy="180.1" r=".28" fill="#fff" stroke="#000" stroke-width=".2"/>
<circle cx="157.5" cy="183" r=".49" fill="#008000" stroke="#008000" stroke-width=".2"/>
<circle cx="157.5" cy="183" r=".28" fill="#fff" stroke="#000" stroke-width=".2"/>
<circle cx="217.5" cy="96.5" r=".49" fill="#008000" stroke="#008000" stroke-width=".2"/>
<circle cx="217.5" cy="96.5" r=".28" fill="#fff" stroke="#000" stroke-width=".2"/>
<circle cx="219.9" cy="97.8" r=".49" fill="#008000" stroke="#008000" stroke-width=".2"/>
<circle cx="219.9" cy="97.8" r=".28" fill="#fff" stroke="#000" stroke-width=".2"/>
<circle cx="150.3" cy="23.2" r=".49" fill="#008000" stroke="#008000" stroke-width=".2"/>
<circle cx="150.3" cy="23.2" r=".28" fill="#fff" stroke="#000" stroke-width=".2"/>
<circle cx="205.2" cy="116.5" r=".49" fill="#008000" stroke="#008000" stroke-width=".2"/>
<circle cx="205.2" cy="116.5" r=".28" fill="#fff" stroke="#000" stroke-width=".2"/>
<circle cx="219.3" cy="117.2" r=".49" fill="#008000" stroke="#008000" stroke-width=".2"/>
<circle cx="219.3" cy="117.2" r=".28" fill="#fff" stroke="#000" stroke-width=".2"/>
<circle cx="147.4" cy="37.7" r=".49" fill="#008000" stroke="#008000" stroke-width=".2"/>
<circle cx="147.4" cy="37.7" r=".28" fill="#fff" stroke="#000" stroke-width=".2"/>
<circle cx="193.4" cy="118.9" r=".49" fill="#008000" stroke="#008000" stroke-width=".2"/>
<circle cx="193.4" cy="118.9" r=".28" fill="#fff" stroke="#000" stroke-width=".2"/>
<circle cx="204.5" cy="119.2" r=".49" fill="#008000" stroke="#008000" stroke-width=".2"/>
<circle cx="204.5" cy="119.2" r=".28" fill="#fff" stroke="#000" stroke-width=".2"/>
<circle cx="175.3" cy="130.9" r=".49" fill="#008000" stroke="#008000" stroke-width=".2"/>
<circle cx="175.3" cy="130.9" r=".28" fill="#fff" stroke="#000" stroke-width=".2"/>
<circle cx="203.5" cy="152.5" r=".49" fill="#008000" stroke="#008000" stroke-width=".2"/>
<circle cx="203.5" cy="152.5" r=".28" fill="#fff" stroke="#000" stroke-width=".2"/>
<circle cx="135" cy="141.3" r=".49" fill="#008000" stroke="#008000" stroke-width=".2"/>
<circle cx="135" cy="141.3" r=".28" fill="#fff" stroke="#000" stroke-width=".2"/>
<circle cx="141.9" cy="69.2" r=".49" fill="#008000" stroke="#008000" stroke-width=".2"/>
<circle cx="141.9" cy="69.2" r=".28" fill="#fff" stroke="#000" stroke-width=".2"/>
<circle cx="169.3" cy="126.3" r=".49" fill="#008000" stroke="#008000" stroke-width=".2"/>
<circle cx="169.3" cy="126.3" r=".28" fill="#fff" stroke="#000" stroke-width=".2"/>
<circle cx="186.6" cy="82.6" r=".49" fill="#008000" stroke="#008000" stroke-width=".2"/>
<circle cx="186.6" cy="82.6" r=".28" fill="#fff" stroke="#000" stroke-width=".2"/>
<circle cx="146.5" cy="125.5" r=".49" fill="#008000" stroke="#008000" stroke-width=".2"/>
<circle cx="146.5" cy="125.5" r=".28" fill="#fff" stroke="#000" stroke-width=".2"/>
<circle cx="143.5" cy="114" r=".49" fill="#008000" stroke="#008000" stroke-width=".2"/>
<circle cx="143.5" cy="114" r=".28" fill="#fff" stroke="#000" stroke-width=".2"/>
<circle cx="171.4" cy="83" r=".49" fill="#008000" stroke="#008000" stroke-width=".2"/>
<circle cx="171.4" cy="83" r=".28" fill="#fff" stroke="#000" stroke-width=".2"/>
<circle cx="188.1" cy="178.8" r=".49" fill="#008000" stroke="#008000" stroke-width=".2"/>
<circle cx="188.1" cy="178.8" r=".28" fill="#fff" stroke="#000" stroke-width=".2"/>
<circle cx="183.4" cy="175.2" r=".49" fill="#008000" stroke="#008000" stroke-width=".2"/>
<circle cx="183.4" cy="175.2" r=".28" fill="#fff" stroke="#000" stroke-width=".2"/>
<circle cx="226.7" cy="82.4" r=".49" fill="#008000" stroke="#008000" stroke-width=".2"/>
<circle cx="226.7" cy="82.4" r=".28" fill="#fff" stroke="#000" stroke-width=".2"/>
<circle cx="221.4" cy="83.7" r=".49" fill="#008000" stroke="#008000" stroke-width=".2"/>
<circle cx="221.4" cy="83.7" r=".28" fill="#fff" stroke="#000" stroke-width=".2"/>
<circle cx="144.7" cy="13" r=".49" fill="#008000" stroke="#008000" stroke-width=".2"/>
<circle cx="144.7" cy="13" r=".28" fill="#fff" stroke="#000" stroke-width=".2"/>
<circle cx="144.3" cy="18.5" r=".49" fill="#008000" stroke="#008000" stroke-width=".2"/>
<circle cx="144.3" cy="18.5" r=".28" fill="#fff" stroke="#000" stroke-width=".2"/>
<circle cx="169.3" cy="176" r=".49" fill="#008000" stroke="#008000" stroke-width=".2"/>
<circle cx="169.3" cy="176" r=".28" fill="#fff" stroke="#000" stroke-width=".2"/>
<circle cx="171.5" cy="181.4" r=".49" fill="#008000" stroke="#008000" stroke-width=".2"/>
<circle cx="171.5" cy="181.4" r=".28" fill="#fff" stroke="#000" stroke-width=".2"/>
<circle cx="215.7" cy="85.2" r=".49" fill="#008000" stroke="#008000" stroke-width=".2"/>
<circle cx="215.7" cy="85.2" r=".28" fill="#fff" stroke="#000" stroke-width=".2"/>
<circle cx="201.4" cy="128.9" r=".49" fill="#008000" stroke="#008000" stroke-width=".2"/>
<circle cx="201.4" cy="128.9" r=".28" fill="#fff" stroke="#000" stroke-width=".2"/>
<circle cx="217.1" cy="135.4" r=".49" fill="#008000" stroke="#008000" stroke-width=".2"/>
<circle cx="217.1" cy="135.4" r=".28" fill="#fff" stroke="#000" stroke-width=".2"/>
<circle cx="160.7" cy="38.9" r=".49" fill="#008000" stroke="#008000" stroke-width=".2"/>
<circle cx="160.7" cy="38.9" r=".28" fill="#fff" stroke="#000" stroke-width=".2"/>
<circle cx="194.8" cy="112.5" r=".49" fill="#008000" stroke="#008000" stroke-width=".2"/>
<circle cx="194.8" cy="112.5" r=".28" fill="#fff" stroke="#000" stroke-width=".2"/>
<circle cx="222.5" cy="116.5" r=".49" fill="#008000" stroke="#008000" stroke-width=".2"/>
<circle cx="222.5" cy="116.5" r=".28" fill="#fff" stroke="#000" stroke-width=".2"/>
<circle cx="166.7" cy="139.1" r=".49" fill="#008000" stroke="#008000" stroke-width=".2"/>
<circle cx="166.7" cy="139.1" r=".28" fill="#fff" stroke="#000" stroke-width=".2"/>
<circle cx="147" cy="54" r=".49" fill="#008000" stroke="#008000" stroke-width=".2"/>
<circle cx="147" cy="54" r=".28" fill="#fff" stroke="#000" stroke-width=".2"/>
<circle cx="157.4" cy="20.3" r=".49" fill="#008000" stroke="#008000" stroke-width=".2"/>
<circle cx="157.4" cy="20.3" r=".28" fill="#fff" stroke="#000" stroke-width=".2"/>
<circle cx="149.9" cy="117.2" r=".49" fill="#008000" stroke="#008000" stroke-width=".2"/>
<circle cx="149.9" cy="117.2" r=".28" fill="#fff" stroke="#000" stroke-width=".2"/>
<circle cx="150.6" cy="103.1" r=".49" fill="#008000" stroke="#008000" stroke-width=".2"/>
<circle cx="150.6" cy="103.1" r=".28" fill="#fff" stroke="#000" stroke-width=".2"/>
<circle cx="156.7" cy="103.1" r=".49" fill="#008000" stroke="#008000" stroke-width=".2"/>
<circle cx="156.7" cy="103.1" r=".28" fill="#fff" stroke="#000" stroke-width=".2"/>
<circle cx="163.5" cy="134.9" r=".49" fill="#008000" stroke="#008000" stroke-width=".2"/>
<circle cx="163.5" cy="134.9" r=".28" fill="#fff" stroke="#000" stroke-width=".2"/>
<circle cx="137" cy="142.2" r=".49" fill="#008000" stroke="#008000" stroke-width=".2"/>
<circle cx="137" cy="142.2" r=".28" fill="#fff" stroke="#000" stroke-width=".2"/>
<circle cx="186.4" cy="81.1" r=".49" fill="#008000" stroke="#008000" stroke-width=".2"/>
<circle cx="186.4" cy="81.1" r=".28" fill="#fff" stroke="#000" stroke-width=".2"/>
<circle cx="137" cy="139.1" r=".49" fill="#008000" stroke="#008000" stroke-width=".2"/>
<circle cx="137" cy="139.1" r=".28" fill="#fff" stroke="#000" stroke-width=".2"/>
<circle cx="219.4" cy="76.6" r=".49" fill="#008000" stroke="#008000" stroke-width=".2"/>
<circle cx="219.4" cy="76.6" r=".28" fill="#fff" stroke="#000" stroke-width=".2"/>
<circle cx="165.6" cy="22.6" r=".49" fill="#008000" stroke="#008000" stroke-width=".2"/>
<circle cx="165.6" cy="22.6" r=".28" fill="#fff" stroke="#000" stroke-width=".2"/>
<circle cx="189.3" cy="171.3" r=".49" fill="#008000" stroke="#008000" stroke-width=".2"/>
<circle cx="189.3" cy="171.3" r=".28" fill="#fff" stroke="#000" stroke-width=".2"/>
<circle cx="178.8" cy="184.1" r=".49" fill="#008000" stroke="#008000" stroke-width=".2"/>
<circle cx="178.8" cy="184.1" r=".28" fill="#fff" stroke="#000" stroke-width=".2"/>
<circle cx="176.8" cy="180.3" r=".49" fill="#008000" stroke="#008000" stroke-width=".2"/>
<circle cx="176.8" cy="180.3" r=".28" fill="#fff" stroke="#000" stroke-width=".2"/>
<circle cx="228.7" cy="94" r=".49" fill="#008000" stroke="#008000" stroke-width=".2"/>
<circle cx="228.7" cy="94" r=".28" fill="#fff" stroke="#000" stroke-width=".2"/>
<circle cx="224.5" cy="94.5" r=".49" fill="#008000" stroke="#008000" stroke-width=".2"/>
<circle cx="224.5" cy="94.5" r=".28" fill="#fff" stroke="#000" stroke-width=".2"/>
<circle cx="156.4" cy="14.5" r=".49" fill="#008000" stroke="#008000" stroke-width=".2"/>
<circle cx="156.4" cy="14.5" r=".28" fill="#fff" stroke="#000" stroke-width=".2"/>
<circle cx="155.7" cy="18.6" r=".49" fill="#008000" stroke="#008000" stroke-width=".2"/>
<circle cx="155.7" cy="18.6" r=".28" fill="#fff" stroke="#000" stroke-width=".2"/>
<circle cx="179.7" cy="170.7" r=".49" fill="#008000" stroke="#008000" stroke-width=".2"/>
<circle cx="179.7" cy="170.7" r=".28" fill="#fff" stroke="#000" stroke-width=".2"/>
<circle cx="182.1" cy="177.6" r=".49" fill="#008000" stroke="#008000" stroke-width=".2"/>
<circle cx="182.1" cy="177.6" r=".28" fill="#fff" stroke="#000" stroke-width=".2"/>
<circle cx="211.8" cy="72.9" r=".49" fill="#008000" stroke="#008000" stroke-width=".2"/>
<circle cx="211.8" cy="72.9" r=".28" fill="#fff" stroke="#000" stroke-width=".2"/>
<circle cx="219.4" cy="72.6" r=".49" fill="#008000" stroke="#008000" stroke-width=".2"/>
<circle cx="219.4" cy="72.6" r=".28" fill="#fff" stroke="#000" stroke-width=".2"/>
<circle cx="194.5" cy="141.7" r=".49" fill="#008000" stroke="#008000" stroke-width=".2"/>
<circle cx="194.5" cy="141.7" r=".28" fill="#fff" stroke="#000" stroke-width=".2"/>
<circle cx="208.7" cy="153.4" r=".49" fill="#008000" stroke="#008000" stroke-width=".2"/>
<circle cx="208.7" cy="153.4" r=".28" fill="#fff" stroke="#000" stroke-width=".2"/>
<circle cx="171.1" cy="43.4" r=".49" fill="#008000" stroke="#008000" stroke-width=".2"/>
<circle cx="171.1" cy="43.4" r=".28" fill="#fff" stroke="#000" stroke-width=".2"/>
<circle cx="179.6" cy="27.2" r=".49" fill="#008000" stroke="#008000" stroke-width=".2"/>
<circle cx="179.6" cy="27.2" r=".28" fill="#fff" stroke="#000" stroke-width=".2"/>
<circle cx="195.6" cy="100.4" r=".49" fill="#008000" stroke="#008000" stroke-width=".2"/>
<circle cx="195.6" cy="100.4" r=".28" fill="#fff" stroke="#000" stroke-width=".2"/>
<circle cx="225" cy="103.1" r=".49" fill="#008000" stroke="#008000" stroke-width=".2"/>
<circle cx="225" cy="103.1" r=".28" fill="#fff" stroke="#000" stroke-width=".2"/>
<circle cx="157.8" cy="131.8" r=".49" fill="#008000" stroke="#008000" stroke-width=".2"/>
<circle cx="157.8" cy="131.8" r=".28" fill="#fff" stroke="#000" stroke-width=".2"/>
<circle cx="156.7" cy="145.5" r=".49" fill="#008000" stroke="#008000" stroke-width=".2"/>
<circle cx="156.7" cy="145.5" r=".28" fill="#fff" stroke="#000" stroke-width=".2"/>
<circle cx="159.2" cy="62.2" r=".49" fill="#008000" stroke="#008000" stroke-width=".2"/>
<circle cx="159.2" cy="62.2" r=".28" fill="#fff" stroke="#000" stroke-width=".2"/>
<circle cx="144.5" cy="92.3" r=".49" fill="#008000" stroke="#008000" stroke-width=".2"/>
<circle cx="144.5" cy="92.3" r=".28" fill="#fff" stroke="#000" stroke-width=".2"/>
<circle cx="185.9" cy="79.9" r=".49" fill="#008000" stroke="#008000" stroke-width=".2"/>
<circle cx="185.9" cy="79.9" r=".28" fill="#fff" stroke="#000" stroke-width=".2"/>
<circle cx="215.6" cy="64.1" r=".49" fill="#008000" stroke="#008000" stroke-width=".2"/>
<circle cx="215.6" cy="64.1" r=".28" fill="#fff" stroke="#000" stroke-width=".2"/>
<circle cx="165.7" cy="184.6" r=".49" fill="#008000" stroke="#008000" stroke-width=".2"/>
<circle cx="165.7" cy="184.6" r=".28" fill="#fff" stroke="#000" stroke-width=".2"/>
<circle cx="166.4" cy="189.1" r=".49" fill="#008000" stroke="#008000" stroke-width=".2"/>
<circle cx="166.4" cy="189.1" r=".28" fill="#fff" stroke="#000" stroke-width=".2"/>
<circle cx="168.2" cy="194.5" r=".49" fill="#008000" stroke="#008000" stroke-width=".2"/>
<circle cx="168.2" cy="194.5" r=".28" fill="#fff" stroke="#000" stroke-width=".2"/>
<circle cx="229.1" cy="103.1" r=".49" fill="#008000" stroke="#008000" stroke-width=".2"/>
<circle cx="229.1" cy="103.1" r=".28" fill="#fff" stroke="#000" stroke-width=".2"/>
<circle cx="234.9" cy="103.1" r=".49" fill="#008000" stroke="#008000" stroke-width=".2"/>
<circle cx="234.9" cy="103.1" r=".28" fill="#fff" stroke="#000" stroke-width=".2"/>
<circle cx="167.8" cy="17.5" r=".49" fill="#008000" stroke="#008000" stroke-width=".2"/>
<circle cx="167.8" cy="17.5" r=".28" fill="#fff" stroke="#000" stroke-width=".2"/>
<circle cx="169.6" cy="12.1" r=".49" fill="#008000" stroke="#008000" stroke-width=".2"/>
<circle cx="169.6" cy="12.1" r=".28" fill="#fff" stroke="#000" stroke-width=".2"/>
<circle cx="189.1" cy="163.9" r=".49" fill="#008000" stroke="#008000" stroke-width=".2"/>
<circle cx="189.1" cy="163.9" r=".28" fill="#fff" stroke="#000" stroke-width=".2"/>
<circle cx="199.6" cy="177.5" r=".49" fill="#008000" stroke="#008000" stroke-width=".2"/>
<circle cx="199.6" cy="177.5" r=".28" fill="#fff" stroke="#000" stroke-width=".2"/>
<circle cx="206.1" cy="61.5" r=".49" fill="#008000" stroke="#008000" stroke-width=".2"/>
<circle cx="206.1" cy="61.5" r=".28" fill="#fff" stroke="#000" stroke-width=".2"/>
<circle cx="220.5" cy="52.5" r=".49" fill="#008000" stroke="#008000" stroke-width=".2"/>
<circle cx="220.5" cy="52.5" r=".28" fill="#fff" stroke="#000" stroke-width=".2"/>
<circle cx="186.6" cy="151" r=".49" fill="#008000" stroke="#008000" stroke-width=".2"/>
<circle cx="186.6" cy="151" r=".28" fill="#fff" stroke="#000" stroke-width=".2"/>
<circle cx="181.8" cy="50.7" r=".49" fill="#008000" stroke="#008000" stroke-width=".2"/>
<circle cx="181.8" cy="50.7" r=".28" fill="#fff" stroke="#000" stroke-width=".2"/>
<circle cx="167.8" cy="67.9" r=".49" fill="#008000" stroke="#008000" stroke-width=".2"/>
<circle cx="167.8" cy="67.9" r=".28" fill="#fff" stroke="#000" stroke-width=".2"/>
<circle cx="199.5" cy="28.6" r=".49" fill="#008000" stroke="#008000" stroke-width=".2"/>
<circle cx="199.5" cy="28.6" r=".28" fill="#fff" stroke="#000" stroke-width=".2"/>
<circle cx="193.5" cy="87.3" r=".49" fill="#008000" stroke="#008000" stroke-width=".2"/>
<circle cx="193.5" cy="87.3" r=".28" fill="#fff" stroke="#000" stroke-width=".2"/>
<circle cx="231.6" cy="78.2" r=".49" fill="#008000" stroke="#008000" stroke-width=".2"/>
<circle cx="231.6" cy="78.2" r=".28" fill="#fff" stroke="#000" stroke-width=".2"/>
<circle cx="187.3" cy="90.1" r=".49" fill="#008000" stroke="#008000" stroke-width=".2"/>
<circle cx="187.3" cy="90.1" r=".28" fill="#fff" stroke="#000" stroke-width=".2"/>
<circle cx="136.3" cy="143.2" r=".49" fill="#008000" stroke="#008000" stroke-width=".2"/>
<circle cx="136.3" cy="143.2" r=".28" fill="#fff" stroke="#000" stroke-width=".2"/>
<circle cx="133.5" cy="199.1" r=".49" fill="#008000" stroke="#008000" stroke-width=".2"/>
<circle cx="133.5" cy="199.1" r=".28" fill="#fff" stroke="#000" stroke-width=".2"/>
<circle cx="164.5" cy="125.8" r=".49" fill="#008000" stroke="#008000" stroke-width=".2"/>
<circle cx="164.5" cy="125.8" r=".28" fill="#fff" stroke="#000" stroke-width=".2"/>
<circle cx="157.9" cy="120.3" r=".49" fill="#008000" stroke="#008000" stroke-width=".2"/>
<circle cx="157.9" cy="120.3" r=".28" fill="#fff" stroke="#000" stroke-width=".2"/>
<circle cx="133.9" cy="143.1" r=".49" fill="#008000" stroke="#008000" stroke-width=".2"/>
<circle cx="133.9" cy="143.1" r=".28" fill="#fff" stroke="#000" stroke-width=".2"/>
<circle cx="137.6" cy="128.5" r=".49" fill="#008000" stroke="#008000" stroke-width=".2"/>
<circle cx="137.6" cy="128.5" r=".28" fill="#fff" stroke="#000" stroke-width=".2"/>
<circle cx="154.7" cy="98.7" r=".49" fill="#008000" stroke="#008000" stroke-width=".2"/>
<circle cx="154.7" cy="98.7" r=".28" fill="#fff" stroke="#000" stroke-width=".2"/>
<circle cx="154.9" cy="191.9" r=".49" fill="#008000" stroke="#008000" stroke-width=".2"/>
<circle cx="154.9" cy="191.9" r=".28" fill="#fff" stroke="#000" stroke-width=".2"/>
<circle cx="155.6" cy="195.3" r=".49" fill="#008000" stroke="#008000" stroke-width=".2"/>
<circle cx="155.6" cy="195.3" r=".28" fill="#fff" stroke="#000" stroke-width=".2"/>
<circle cx="227.7" cy="118.9" r=".49" fill="#008000" stroke="#008000" stroke-width=".2"/>
<circle cx="227.7" cy="118.9" r=".28" fill="#fff" stroke="#000" stroke-width=".2"/>
<circle cx="231.1" cy="119.5" r=".49" fill="#008000" stroke="#008000" stroke-width=".2"/>
<circle cx="231.1" cy="119.5" r=".28" fill="#fff" stroke="#000" stroke-width=".2"/>
<circle cx="181.5" cy="23.5" r=".49" fill="#008000" stroke="#008000" stroke-width=".2"/>
<circle cx="181.5" cy="23.5" r=".28" fill="#fff" stroke="#000" stroke-width=".2"/>
<circle cx="183.1" cy="20.5" r=".49" fill="#008000" stroke="#008000" stroke-width=".2"/>
<circle cx="183.1" cy="20.5" r=".28" fill="#fff" stroke="#000" stroke-width=".2"/>
<circle cx="198.8" cy="154.6" r=".49" fill="#008000" stroke="#008000" stroke-width=".2"/>
<circle cx="198.8" cy="154.6" r=".28" fill="#fff" stroke="#000" stroke-width=".2"/>
<circle cx="199.1" cy="51.9" r=".49" fill="#008000" stroke="#008000" stroke-width=".2"/>
<circle cx="199.1" cy="51.9" r=".28" fill="#fff" stroke="#000" stroke-width=".2"/>
<circle cx="191.4" cy="60.3" r=".49" fill="#008000" stroke="#008000" stroke-width=".2"/>
<circle cx="191.4" cy="60.3" r=".28" fill="#fff" stroke="#000" stroke-width=".2"/>
<circle cx="211.3" cy="43.7" r=".49" fill="#008000" stroke="#008000" stroke-width=".2"/>
<circle cx="211.3" cy="43.7" r=".28" fill="#fff" stroke="#000" stroke-width=".2"/>
<circle cx="178.2" cy="158.2" r=".49" fill="#008000" stroke="#008000" stroke-width=".2"/>
<circle cx="178.2" cy="158.2" r=".28" fill="#fff" stroke="#000" stroke-width=".2"/>
<circle cx="173" cy="150.9" r=".49" fill="#008000" stroke="#008000" stroke-width=".2"/>
<circle cx="173" cy="150.9" r=".28" fill="#fff" stroke="#000" stroke-width=".2"/>
<circle cx="188" cy="74.7" r=".49" fill="#008000" stroke="#008000" stroke-width=".2"/>
<circle cx="188" cy="74.7" r=".28" fill="#fff" stroke="#000" stroke-width=".2"/>
<circle cx="176.9" cy="77.8" r=".49" fill="#008000" stroke="#008000" stroke-width=".2"/>
<circle cx="176.9" cy="77.8" r=".28" fill="#fff" stroke="#000" stroke-width=".2"/>
<circle cx="170.6" cy="116.2" r=".49" fill="#008000" stroke="#008000" stroke-width=".2"/>
<circle cx="170.6" cy="116.2" r=".28" fill="#fff" stroke="#000" stroke-width=".2"/>
<circle cx="226.2" cy="136.2" r=".49" fill="#008000" stroke="#008000" stroke-width=".2"/>
<circle cx="226.2" cy="136.2" r=".28" fill="#fff" stroke="#000" stroke-width=".2"/>
<circle cx="154.2" cy="85.2" r=".49" fill="#008000" stroke="#008000" stroke-width=".2"/>
<circle cx="154.2" cy="85.2" r=".28" fill="#fff" stroke="#000" stroke-width=".2"/>
<circle cx="156.6" cy="79.7" r=".49" fill="#008000" stroke="#008000" stroke-width=".2"/>
<circle cx="156.6" cy="79.7" r=".28" fill="#fff" stroke="#000" stroke-width=".2"/>
<circle cx="163.5" cy="86.9" r=".49" fill="#008000" stroke="#008000" stroke-width=".2"/>
<circle cx="163.5" cy="86.9" r=".28" fill="#fff" stroke="#000" stroke-width=".2"/>
<circle cx="220.1" cy="56.2" r=".49" fill="#008000" stroke="#008000" stroke-width=".2"/>
<circle cx="220.1" cy="56.2" r=".28" fill="#fff" stroke="#000" stroke-width=".2"/>
<circle cx="166.5" cy="69.5" r=".49" fill="#008000" stroke="#008000" stroke-width=".2"/>
<circle cx="166.5" cy="69.5" r=".28" fill="#fff" stroke="#000" stroke-width=".2"/>
<circle cx="211.1" cy="162.8" r=".49" fill="#008000" stroke="#008000" stroke-width=".2"/>
<circle cx="211.1" cy="162.8" r=".28" fill="#fff" stroke="#000" stroke-width=".2"/>
<circle cx="193.5" cy="179.2" r=".49" fill="#008000" stroke="#008000" stroke-width=".2"/>
<circle cx="193.5" cy="179.2" r=".28" fill="#fff" stroke="#000" stroke-width=".2"/>
<circle cx="183.5" cy="141.4" r=".49" fill="#008000" stroke="#008000" stroke-width=".2"/>
<circle cx="183.5" cy="141.4" r=".28" fill="#fff" stroke="#000" stroke-width=".2"/>
<circle cx="182.4" cy="88.9" r=".49" fill="#008000" stroke="#008000" stroke-width=".2"/>
<circle cx="182.4" cy="88.9" r=".28" fill="#fff" stroke="#000" stroke-width=".2"/>
<circle cx="161.1" cy="95.4" r=".49" fill="#008000" stroke="#008000" stroke-width=".2"/>
<circle cx="161.1" cy="95.4" r=".28" fill="#fff" stroke="#000" stroke-width=".2"/>
<circle cx="134.1" cy="192.8" r=".49" fill="#008000" stroke="#008000" stroke-width=".2"/>
<circle cx="134.1" cy="192.8" r=".28" fill="#fff" stroke="#000" stroke-width=".2"/>
<circle cx="134.1" cy="194.9" r=".49" fill="#008000" stroke="#008000" stroke-width=".2"/>
<circle cx="134.1" cy="194.9" r=".28" fill="#fff" stroke="#000" stroke-width=".2"/>
<circle cx="224.5" cy="136.5" r=".49" fill="#008000" stroke="#008000" stroke-width=".2"/>
<circle cx="224.5" cy="136.5" r=".28" fill="#fff" stroke="#000" stroke-width=".2"/>
<circle cx="205.2" cy="144.3" r=".49" fill="#008000" stroke="#008000" stroke-width=".2"/>
<circle cx="205.2" cy="144.3" r=".28" fill="#fff" stroke="#000" stroke-width=".2"/>
<circle cx="217.3" cy="151.7" r=".49" fill="#008000" stroke="#008000" stroke-width=".2"/>
<circle cx="217.3" cy="151.7" r=".28" fill="#fff" stroke="#000" stroke-width=".2"/>
<circle cx="189.8" cy="42.8" r=".49" fill="#008000" stroke="#008000" stroke-width=".2"/>
<circle cx="189.8" cy="42.8" r=".28" fill="#fff" stroke="#000" stroke-width=".2"/>
<circle cx="197.7" cy="35.9" r=".49" fill="#008000" stroke="#008000" stroke-width=".2"/>
<circle cx="197.7" cy="35.9" r=".28" fill="#fff" stroke="#000" stroke-width=".2"/>
<circle cx="199.5" cy="34" r=".49" fill="#008000" stroke="#008000" stroke-width=".2"/>
<circle cx="199.5" cy="34" r=".28" fill="#fff" stroke="#000" stroke-width=".2"/>
<circle cx="166.5" cy="165" r=".49" fill="#008000" stroke="#008000" stroke-width=".2"/>
<circle cx="166.5" cy="165" r=".28" fill="#fff" stroke="#000" stroke-width=".2"/>
<circle cx="176.7" cy="187.2" r=".49" fill="#008000" stroke="#008000" stroke-width=".2"/>
<circle cx="176.7" cy="187.2" r=".28" fill="#fff" stroke="#000" stroke-width=".2"/>
<circle cx="199.8" cy="75.8" r=".49" fill="#008000" stroke="#008000" stroke-width=".2"/>
<circle cx="199.8" cy="75.8" r=".28" fill="#fff" stroke="#000" stroke-width=".2"/>
<circle cx="223" cy="65.1" r=".49" fill="#008000" stroke="#008000" stroke-width=".2"/>
<circle cx="223" cy="65.1" r=".28" fill="#fff" stroke="#000" stroke-width=".2"/>
<circle cx="160.9" cy="155.9" r=".49" fill="#008000" stroke="#008000" stroke-width=".2"/>
<circle cx="160.9" cy="155.9" r=".28" fill="#fff" stroke="#000" stroke-width=".2"/>
<circle cx="176.8" cy="62.1" r=".49" fill="#008000" stroke="#008000" stroke-width=".2"/>
<circle cx="176.8" cy="62.1" r=".28" fill="#fff" stroke="#000" stroke-width=".2"/>
<circle cx="163.1" cy="105" r=".49" fill="#008000" stroke="#008000" stroke-width=".2"/>
<circle cx="163.1" cy="105" r=".28" fill="#fff" stroke="#000" stroke-width=".2"/>
<circle cx="161.1" cy="104.6" r=".49" fill="#008000" stroke="#008000" stroke-width=".2"/>
<circle cx="161.1" cy="104.6" r=".28" fill="#fff" stroke="#000" stroke-width=".2"/>
<circle cx="231.1" cy="110.8" r=".49" fill="#008000" stroke="#008000" stroke-width=".2"/>
<circle cx="231.1" cy="110.8" r=".28" fill="#fff" stroke="#000" stroke-width=".2"/>
<circle cx="169.9" cy="180.8" r=".49" fill="#008000" stroke="#008000" stroke-width=".2"/>
<circle cx="169.9" cy="180.8" r=".28" fill="#fff" stroke="#000" stroke-width=".2"/>
<circle cx="170.9" cy="187.8" r=".49" fill="#008000" stroke="#008000" stroke-width=".2"/>
<circle cx="170.9" cy="187.8" r=".28" fill="#fff" stroke="#000" stroke-width=".2"/>
<circle cx="175.6" cy="178.1" r=".49" fill="#008000" stroke="#008000" stroke-width=".2"/>
<circle cx="175.6" cy="178.1" r=".28" fill="#fff" stroke="#000" stroke-width=".2"/>
<circle cx="176.7" cy="183.9" r=".49" fill="#008000" stroke="#008000" stroke-width=".2"/>
<circle cx="176.7" cy="183.9" r=".28" fill="#fff" stroke="#000" stroke-width=".2"/>
<circle cx="177.3" cy="177.1" r=".49" fill="#008000" stroke="#008000" stroke-width=".2"/>
<circle cx="177.3" cy="177.1" r=".28" fill="#fff" stroke="#000" stroke-width=".2"/>
<circle cx="178.9" cy="180.5" r=".49" fill="#008000" stroke="#008000" stroke-width=".2"/>
<circle cx="178.9" cy="180.5" r=".28" fill="#fff" stroke="#000" stroke-width=".2"/>
<circle cx="186.9" cy="171.6" r=".49" fill="#008000" stroke="#008000" stroke-width=".2"/>
<circle cx="186.9" cy="171.6" r=".28" fill="#fff" stroke="#000" stroke-width=".2"/>
<circle cx="193.4" cy="181" r=".49" fill="#008000" stroke="#008000" stroke-width=".2"/>
<circle cx="193.4" cy="181" r=".28" fill="#fff" stroke="#000" stroke-width=".2"/>
<circle cx="210.5" cy="40.6" r=".49" fill="#008000" stroke="#008000" stroke-width=".2"/>
<circle cx="210.5" cy="40.6" r=".28" fill="#fff" stroke="#000" stroke-width=".2"/>
<circle cx="206.9" cy="43.8" r=".49" fill="#008000" stroke="#008000" stroke-width=".2"/>
<circle cx="206.9" cy="43.8" r=".28" fill="#fff" stroke="#000" stroke-width=".2"/>
<circle cx="188.6" cy="170.3" r=".49" fill="#008000" stroke="#008000" stroke-width=".2"/>
<circle cx="188.6" cy="170.3" r=".28" fill="#fff" stroke="#000" stroke-width=".2"/>
<circle cx="170" cy="145.1" r=".49" fill="#008000" stroke="#008000" stroke-width=".2"/>
<circle cx="170" cy="145.1" r=".28" fill="#fff" stroke="#000" stroke-width=".2"/>
<circle cx="224.7" cy="127.4" r=".49" fill="#008000" stroke="#008000" stroke-width=".2"/>
<circle cx="224.7" cy="127.4" r=".28" fill="#fff" stroke="#000" stroke-width=".2"/>
<circle cx="188.7" cy="118.9" r=".49" fill="#008000" stroke="#008000" stroke-width=".2"/>
<circle cx="188.7" cy="118.9" r=".28" fill="#fff" stroke="#000" stroke-width=".2"/>
<circle cx="198.4" cy="168.2" r=".49" fill="#008000" stroke="#008000" stroke-width=".2"/>
<circle cx="198.4" cy="168.2" r=".28" fill="#fff" stroke="#000" stroke-width=".2"/>
<circle cx="220.6" cy="136.2" r=".49" fill="#008000" stroke="#008000" stroke-width=".2"/>
<circle cx="220.6" cy="136.2" r=".28" fill="#fff" stroke="#000" stroke-width=".2"/>
<circle cx="186.6" cy="36.8" r=".49" fill="#008000" stroke="#008000" stroke-width=".2"/>
<circle cx="186.6" cy="36.8" r=".28" fill="#fff" stroke="#000" stroke-width=".2"/>
<circle cx="192.2" cy="28.9" r=".49" fill="#008000" stroke="#008000" stroke-width=".2"/>
<circle cx="192.2" cy="28.9" r=".28" fill="#fff" stroke="#000" stroke-width=".2"/>
<circle cx="198.6" cy="161.6" r=".49" fill="#008000" stroke="#008000" stroke-width=".2"/>
<circle cx="198.6" cy="161.6" r=".28" fill="#fff" stroke="#000" stroke-width=".2"/>
<circle cx="189.8" cy="151.4" r=".49" fill="#008000" stroke="#008000" stroke-width=".2"/>
<circle cx="189.8" cy="151.4" r=".28" fill="#fff" stroke="#000" stroke-width=".2"/>
<circle cx="150.5" cy="31.8" r=".49" fill="#008000" stroke="#008000" stroke-width=".2"/>
<circle cx="150.5" cy="31.8" r=".28" fill="#fff" stroke="#000" stroke-width=".2"/>
<circle cx="153.6" cy="13" r=".49" fill="#008000" stroke="#008000" stroke-width=".2"/>
<circle cx="153.6" cy="13" r=".28" fill="#fff" stroke="#000" stroke-width=".2"/>
<circle cx="167.5" cy="30.6" r=".49" fill="#008000" stroke="#008000" stroke-width=".2"/>
<circle cx="167.5" cy="30.6" r=".28" fill="#fff" stroke="#000" stroke-width=".2"/>
<circle cx="170.5" cy="19.6" r=".49" fill="#008000" stroke="#008000" stroke-width=".2"/>
<circle cx="170.5" cy="19.6" r=".28" fill="#fff" stroke="#000" stroke-width=".2"/>
<circle cx="202.8" cy="156.7" r=".49" fill="#008000" stroke="#008000" stroke-width=".2"/>
<circle cx="202.8" cy="156.7" r=".28" fill="#fff" stroke="#000" stroke-width=".2"/>
<circle cx="167.3" cy="126.9" r=".49" fill="#008000" stroke="#008000" stroke-width=".2"/>
<circle cx="167.3" cy="126.9" r=".28" fill="#fff" stroke="#000" stroke-width=".2"/>
<circle cx="159.9" cy="29.2" r=".49" fill="#008000" stroke="#008000" stroke-width=".2"/>
<circle cx="159.9" cy="29.2" r=".28" fill="#fff" stroke="#000" stroke-width=".2"/>
<circle cx="148.4" cy="69" r=".49" fill="#008000" stroke="#008000" stroke-width=".2"/>
<circle cx="148.4" cy="69" r=".28" fill="#fff" stroke="#000" stroke-width=".2"/>
<circle cx="156.3" cy="29.2" r=".49" fill="#008000" stroke="#008000" stroke-width=".2"/>
<circle cx="156.3" cy="29.2" r=".28" fill="#fff" stroke="#000" stroke-width=".2"/>
<circle cx="158.8" cy="18.2" r=".49" fill="#008000" stroke="#008000" stroke-width=".2"/>
<circle cx="158.8" cy="18.2" r=".28" fill="#fff" stroke="#000" stroke-width=".2"/>
<circle cx="210.4" cy="146.2" r=".49" fill="#008000" stroke="#008000" stroke-width=".2"/>
<circle cx="210.4" cy="146.2" r=".28" fill="#fff" stroke="#000" stroke-width=".2"/>
<circle cx="189.3" cy="133.5" r=".49" fill="#008000" stroke="#008000" stroke-width=".2"/>
<circle cx="189.3" cy="133.5" r=".28" fill="#fff" stroke="#000" stroke-width=".2"/>
<circle cx="153.7" cy="45" r=".49" fill="#008000" stroke="#008000" stroke-width=".2"/>
<circle cx="153.7" cy="45" r=".28" fill="#fff" stroke="#000" stroke-width=".2"/>
<circle cx="212.8" cy="142.2" r=".49" fill="#008000" stroke="#008000" stroke-width=".2"/>
<circle cx="212.8" cy="142.2" r=".28" fill="#fff" stroke="#000" stroke-width=".2"/>
<circle cx="216.3" cy="134.1" r=".49" fill="#008000" stroke="#008000" stroke-width=".2"/>
<circle cx="216.3" cy="134.1" r=".28" fill="#fff" stroke="#000" stroke-width=".2"/>
<circle cx="210.1" cy="131.6" r=".49" fill="#008000" stroke="#008000" stroke-width=".2"/>
<circle cx="210.1" cy="131.6" r=".28" fill="#fff" stroke="#000" stroke-width=".2"/>
<circle cx="218" cy="130.1" r=".49" fill="#008000" stroke="#008000" stroke-width=".2"/>
<circle cx="218" cy="130.1" r=".28" fill="#fff" stroke="#000" stroke-width=".2"/>
<circle cx="211.1" cy="129.2" r=".49" fill="#008000" stroke="#008000" stroke-width=".2"/>
<circle cx="211.1" cy="129.2" r=".28" fill="#fff" stroke="#000" stroke-width=".2"/>
<circle cx="143.1" cy="171.7" r=".49" fill="#008000" stroke="#008000" stroke-width=".2"/>
<circle cx="143.1" cy="171.7" r=".28" fill="#fff" stroke="#000" stroke-width=".2"/>
<circle cx="144.1" cy="182.7" r=".49" fill="#008000" stroke="#008000" stroke-width=".2"/>
<circle cx="144.1" cy="182.7" r=".28" fill="#fff" stroke="#000" stroke-width=".2"/>
<circle cx="218.5" cy="128.7" r=".49" fill="#008000" stroke="#008000" stroke-width=".2"/>
<circle cx="218.5" cy="128.7" r=".28" fill="#fff" stroke="#000" stroke-width=".2"/>
<circle cx="210.2" cy="124.4" r=".49" fill="#008000" stroke="#008000" stroke-width=".2"/>
<circle cx="210.2" cy="124.4" r=".28" fill="#fff" stroke="#000" stroke-width=".2"/>
<circle cx="154.2" cy="175.9" r=".49" fill="#008000" stroke="#008000" stroke-width=".2"/>
<circle cx="154.2" cy="175.9" r=".28" fill="#fff" stroke="#000" stroke-width=".2"/>
<circle cx="155.2" cy="181.4" r=".49" fill="#008000" stroke="#008000" stroke-width=".2"/>
<circle cx="155.2" cy="181.4" r=".28" fill="#fff" stroke="#000" stroke-width=".2"/>
<circle cx="151.1" cy="166" r=".49" fill="#008000" stroke="#008000" stroke-width=".2"/>
<circle cx="151.1" cy="166" r=".28" fill="#fff" stroke="#000" stroke-width=".2"/>
<circle cx="153.9" cy="179.6" r=".49" fill="#008000" stroke="#008000" stroke-width=".2"/>
<circle cx="153.9" cy="179.6" r=".28" fill="#fff" stroke="#000" stroke-width=".2"/>
<circle cx="220.4" cy="121.9" r=".49" fill="#008000" stroke="#008000" stroke-width=".2"/>
<circle cx="220.4" cy="121.9" r=".28" fill="#fff" stroke="#000" stroke-width=".2"/>
<circle cx="197.3" cy="116.3" r=".49" fill="#008000" stroke="#008000" stroke-width=".2"/>
<circle cx="197.3" cy="116.3" r=".28" fill="#fff" stroke="#000" stroke-width=".2"/>
<circle cx="150.3" cy="161.9" r=".49" fill="#008000" stroke="#008000" stroke-width=".2"/>
<circle cx="150.3" cy="161.9" r=".28" fill="#fff" stroke="#000" stroke-width=".2"/>
<circle cx="145" cy="167.3" r=".49" fill="#008000" stroke="#008000" stroke-width=".2"/>
<circle cx="145" cy="167.3" r=".28" fill="#fff" stroke="#000" stroke-width=".2"/>
<circle cx="145.3" cy="178.7" r=".49" fill="#008000" stroke="#008000" stroke-width=".2"/>
<circle cx="145.3" cy="178.7" r=".28" fill="#fff" stroke="#000" stroke-width=".2"/>
<circle cx="221.3" cy="115.4" r=".49" fill="#008000" stroke="#008000" stroke-width=".2"/>
<circle cx="221.3" cy="115.4" r=".28" fill="#fff" stroke="#000" stroke-width=".2"/>
<circle cx="199.6" cy="111.1" r=".49" fill="#008000" stroke="#008000" stroke-width=".2"/>
<circle cx="199.6" cy="111.1" r=".28" fill="#fff" stroke="#000" stroke-width=".2"/>
<circle cx="138.8" cy="164.4" r=".49" fill="#008000" stroke="#008000" stroke-width=".2"/>
<circle cx="138.8" cy="164.4" r=".28" fill="#fff" stroke="#000" stroke-width=".2"/>
<circle cx="222.4" cy="104.1" r=".49" fill="#008000" stroke="#008000" stroke-width=".2"/>
<circle cx="222.4" cy="104.1" r=".28" fill="#fff" stroke="#000" stroke-width=".2"/>
<circle cx="207.5" cy="105.2" r=".49" fill="#008000" stroke="#008000" stroke-width=".2"/>
<circle cx="207.5" cy="105.2" r=".28" fill="#fff" stroke="#000" stroke-width=".2"/>
<circle cx="222.3" cy="97.6" r=".49" fill="#008000" stroke="#008000" stroke-width=".2"/>
<circle cx="222.3" cy="97.6" r=".28" fill="#fff" stroke="#000" stroke-width=".2"/>
<circle cx="205.4" cy="99.7" r=".49" fill="#008000" stroke="#008000" stroke-width=".2"/>
<circle cx="205.4" cy="99.7" r=".28" fill="#fff" stroke="#000" stroke-width=".2"/>
<circle cx="222.3" cy="95.8" r=".49" fill="#008000" stroke="#008000" stroke-width=".2"/>
<circle cx="222.3" cy="95.8" r=".28" fill="#fff" stroke="#000" stroke-width=".2"/>
<circle cx="202.3" cy="96.9" r=".49" fill="#008000" stroke="#008000" stroke-width=".2"/>
<circle cx="202.3" cy="96.9" r=".28" fill="#fff" stroke="#000" stroke-width=".2"/>
<circle cx="158.7" cy="37.3" r=".49" fill="#008000" stroke="#008000" stroke-width=".2"/>
<circle cx="158.7" cy="37.3" r=".28" fill="#fff" stroke="#000" stroke-width=".2"/>
<circle cx="155.7" cy="47.8" r=".49" fill="#008000" stroke="#008000" stroke-width=".2"/>
<circle cx="155.7" cy="47.8" r=".28" fill="#fff" stroke="#000" stroke-width=".2"/>
<circle cx="219.3" cy="89.1" r=".49" fill="#008000" stroke="#008000" stroke-width=".2"/>
<circle cx="219.3" cy="89.1" r=".28" fill="#fff" stroke="#000" stroke-width=".2"/>
<circle cx="205.3" cy="90" r=".49" fill="#008000" stroke="#008000" stroke-width=".2"/>
<circle cx="205.3" cy="90" r=".28" fill="#fff" stroke="#000" stroke-width=".2"/>
<circle cx="201.2" cy="76.1" r=".49" fill="#008000" stroke="#008000" stroke-width=".2"/>
<circle cx="201.2" cy="76.1" r=".28" fill="#fff" stroke="#000" stroke-width=".2"/>
<circle cx="156.9" cy="50.3" r=".49" fill="#008000" stroke="#008000" stroke-width=".2"/>
<circle cx="156.9" cy="50.3" r=".28" fill="#fff" stroke="#000" stroke-width=".2"/>
<circle cx="160" cy="40.9" r=".49" fill="#008000" stroke="#008000" stroke-width=".2"/>
<circle cx="160" cy="40.9" r=".28" fill="#fff" stroke="#000" stroke-width=".2"/>
<circle cx="218.5" cy="77.7" r=".49" fill="#008000" stroke="#008000" stroke-width=".2"/>
<circle cx="218.5" cy="77.7" r=".28" fill="#fff" stroke="#000" stroke-width=".2"/>
<circle cx="197.4" cy="85.6" r=".49" fill="#008000" stroke="#008000" stroke-width=".2"/>
<circle cx="197.4" cy="85.6" r=".28" fill="#fff" stroke="#000" stroke-width=".2"/>
<circle cx="195.7" cy="68.1" r=".49" fill="#008000" stroke="#008000" stroke-width=".2"/>
<circle cx="195.7" cy="68.1" r=".28" fill="#fff" stroke="#000" stroke-width=".2"/>
<circle cx="191.3" cy="70.8" r=".49" fill="#008000" stroke="#008000" stroke-width=".2"/>
<circle cx="191.3" cy="70.8" r=".28" fill="#fff" stroke="#000" stroke-width=".2"/>
<circle cx="170.9" cy="47.6" r=".49" fill="#008000" stroke="#008000" stroke-width=".2"/>
<circle cx="170.9" cy="47.6" r=".28" fill="#fff" stroke="#000" stroke-width=".2"/>
<circle cx="165.7" cy="56.6" r=".49" fill="#008000" stroke="#008000" stroke-width=".2"/>
<circle cx="165.7" cy="56.6" r=".28" fill="#fff" stroke="#000" stroke-width=".2"/>
<circle cx="218.1" cy="76.2" r=".49" fill="#008000" stroke="#008000" stroke-width=".2"/>
<circle cx="218.1" cy="76.2" r=".28" fill="#fff" stroke="#000" stroke-width=".2"/>
<circle cx="200.4" cy="82.2" r=".49" fill="#008000" stroke="#008000" stroke-width=".2"/>
<circle cx="200.4" cy="82.2" r=".28" fill="#fff" stroke="#000" stroke-width=".2"/>
<circle cx="196.8" cy="76" r=".49" fill="#008000" stroke="#008000" stroke-width=".2"/>
<circle cx="196.8" cy="76" r=".28" fill="#fff" stroke="#000" stroke-width=".2"/>
<circle cx="215.7" cy="70.1" r=".49" fill="#008000" stroke="#008000" stroke-width=".2"/>
<circle cx="215.7" cy="70.1" r=".28" fill="#fff" stroke="#000" stroke-width=".2"/>
<circle cx="191.5" cy="81.3" r=".49" fill="#008000" stroke="#008000" stroke-width=".2"/>
<circle cx="191.5" cy="81.3" r=".28" fill="#fff" stroke="#000" stroke-width=".2"/>
<circle cx="213.8" cy="66.1" r=".49" fill="#008000" stroke="#008000" stroke-width=".2"/>
<circle cx="213.8" cy="66.1" r=".28" fill="#fff" stroke="#000" stroke-width=".2"/>
<circle cx="191.6" cy="77.3" r=".49" fill="#008000" stroke="#008000" stroke-width=".2"/>
<circle cx="191.6" cy="77.3" r=".28" fill="#fff" stroke="#000" stroke-width=".2"/>
<circle cx="193.9" cy="82.5" r=".49" fill="#008000" stroke="#008000" stroke-width=".2"/>
<circle cx="193.9" cy="82.5" r=".28" fill="#fff" stroke="#000" stroke-width=".2"/>
<circle cx="191.5" cy="83.4" r=".49" fill="#008000" stroke="#008000" stroke-width=".2"/>
<circle cx="191.5" cy="83.4" r=".28" fill="#fff" stroke="#000" stroke-width=".2"/>
<circle cx="209.5" cy="58.3" r=".49" fill="#008000" stroke="#008000" stroke-width=".2"/>
<circle cx="209.5" cy="58.3" r=".28" fill="#fff" stroke="#000" stroke-width=".2"/>
<circle cx="182.4" cy="74.3" r=".49" fill="#008000" stroke="#008000" stroke-width=".2"/>
<circle cx="182.4" cy="74.3" r=".28" fill="#fff" stroke="#000" stroke-width=".2"/>
<circle cx="145" cy="149.5" r=".49" fill="#008000" stroke="#008000" stroke-width=".2"/>
<circle cx="145" cy="149.5" r=".28" fill="#fff" stroke="#000" stroke-width=".2"/>
<circle cx="146.7" cy="160.3" r=".49" fill="#008000" stroke="#008000" stroke-width=".2"/>
<circle cx="146.7" cy="160.3" r=".28" fill="#fff" stroke="#000" stroke-width=".2"/>
<circle cx="206.7" cy="54.2" r=".49" fill="#008000" stroke="#008000" stroke-width=".2"/>
<circle cx="206.7" cy="54.2" r=".28" fill="#fff" stroke="#000" stroke-width=".2"/>
<circle cx="182.2" cy="73.1" r=".49" fill="#008000" stroke="#008000" stroke-width=".2"/>
<circle cx="182.2" cy="73.1" r=".28" fill="#fff" stroke="#000" stroke-width=".2"/>
<circle cx="181.2" cy="131.6" r=".49" fill="#008000" stroke="#008000" stroke-width=".2"/>
<circle cx="181.2" cy="131.6" r=".28" fill="#fff" stroke="#000" stroke-width=".2"/>
<circle cx="177.8" cy="129.2" r=".49" fill="#008000" stroke="#008000" stroke-width=".2"/>
<circle cx="177.8" cy="129.2" r=".28" fill="#fff" stroke="#000" stroke-width=".2"/>
<circle cx="147.3" cy="158.2" r=".49" fill="#008000" stroke="#008000" stroke-width=".2"/>
<circle cx="147.3" cy="158.2" r=".28" fill="#fff" stroke="#000" stroke-width=".2"/>
<circle cx="145.9" cy="147.2" r=".49" fill="#008000" stroke="#008000" stroke-width=".2"/>
<circle cx="145.9" cy="147.2" r=".28" fill="#fff" stroke="#000" stroke-width=".2"/>
<circle cx="201.7" cy="48" r=".49" fill="#008000" stroke="#008000" stroke-width=".2"/>
<circle cx="201.7" cy="48" r=".28" fill="#fff" stroke="#000" stroke-width=".2"/>
<circle cx="176.1" cy="70.3" r=".49" fill="#008000" stroke="#008000" stroke-width=".2"/>
<circle cx="176.1" cy="70.3" r=".28" fill="#fff" stroke="#000" stroke-width=".2"/>
<circle cx="166.4" cy="144.4" r=".49" fill="#008000" stroke="#008000" stroke-width=".2"/>
<circle cx="166.4" cy="144.4" r=".28" fill="#fff" stroke="#000" stroke-width=".2"/>
<circle cx="163.1" cy="139.3" r=".49" fill="#008000" stroke="#008000" stroke-width=".2"/>
<circle cx="163.1" cy="139.3" r=".28" fill="#fff" stroke="#000" stroke-width=".2"/>
<circle cx="141.8" cy="145.3" r=".49" fill="#008000" stroke="#008000" stroke-width=".2"/>
<circle cx="141.8" cy="145.3" r=".28" fill="#fff" stroke="#000" stroke-width=".2"/>
<circle cx="138.9" cy="155.3" r=".49" fill="#008000" stroke="#008000" stroke-width=".2"/>
<circle cx="138.9" cy="155.3" r=".28" fill="#fff" stroke="#000" stroke-width=".2"/>
<circle cx="196.8" cy="43.3" r=".49" fill="#008000" stroke="#008000" stroke-width=".2"/>
<circle cx="196.8" cy="43.3" r=".28" fill="#fff" stroke="#000" stroke-width=".2"/>
<circle cx="172.2" cy="68.3" r=".49" fill="#008000" stroke="#008000" stroke-width=".2"/>
<circle cx="172.2" cy="68.3" r=".28" fill="#fff" stroke="#000" stroke-width=".2"/>
<circle cx="170.6" cy="139.3" r=".49" fill="#008000" stroke="#008000" stroke-width=".2"/>
<circle cx="170.6" cy="139.3" r=".28" fill="#fff" stroke="#000" stroke-width=".2"/>
<circle cx="166.9" cy="134.9" r=".49" fill="#008000" stroke="#008000" stroke-width=".2"/>
<circle cx="166.9" cy="134.9" r=".28" fill="#fff" stroke="#000" stroke-width=".2"/>
<circle cx="188.6" cy="36" r=".49" fill="#008000" stroke="#008000" stroke-width=".2"/>
<circle cx="188.6" cy="36" r=".28" fill="#fff" stroke="#000" stroke-width=".2"/>
<circle cx="166.1" cy="65.3" r=".49" fill="#008000" stroke="#008000" stroke-width=".2"/>
<circle cx="166.1" cy="65.3" r=".28" fill="#fff" stroke="#000" stroke-width=".2"/>
<circle cx="157.5" cy="73.3" r=".49" fill="#008000" stroke="#008000" stroke-width=".2"/>
<circle cx="157.5" cy="73.3" r=".28" fill="#fff" stroke="#000" stroke-width=".2"/>
<circle cx="164.4" cy="62.1" r=".49" fill="#008000" stroke="#008000" stroke-width=".2"/>
<circle cx="164.4" cy="62.1" r=".28" fill="#fff" stroke="#000" stroke-width=".2"/>
<circle cx="163.8" cy="66.1" r=".49" fill="#008000" stroke="#008000" stroke-width=".2"/>
<circle cx="163.8" cy="66.1" r=".28" fill="#fff" stroke="#000" stroke-width=".2"/>
<circle cx="157.4" cy="75.6" r=".49" fill="#008000" stroke="#008000" stroke-width=".2"/>
<circle cx="157.4" cy="75.6" r=".28" fill="#fff" stroke="#000" stroke-width=".2"/>
<circle cx="183.1" cy="32.1" r=".49" fill="#008000" stroke="#008000" stroke-width=".2"/>
<circle cx="183.1" cy="32.1" r=".28" fill="#fff" stroke="#000" stroke-width=".2"/>
<circle cx="154.5" cy="76.1" r=".49" fill="#008000" stroke="#008000" stroke-width=".2"/>
<circle cx="154.5" cy="76.1" r=".28" fill="#fff" stroke="#000" stroke-width=".2"/>
<circle cx="159.7" cy="67.1" r=".49" fill="#008000" stroke="#008000" stroke-width=".2"/>
<circle cx="159.7" cy="67.1" r=".28" fill="#fff" stroke="#000" stroke-width=".2"/>
<circle cx="181.9" cy="31.4" r=".49" fill="#008000" stroke="#008000" stroke-width=".2"/>
<circle cx="181.9" cy="31.4" r=".28" fill="#fff" stroke="#000" stroke-width=".2"/>
<circle cx="164" cy="128" r=".49" fill="#008000" stroke="#008000" stroke-width=".2"/>
<circle cx="164" cy="128" r=".28" fill="#fff" stroke="#000" stroke-width=".2"/>
<circle cx="155.6" cy="119.6" r=".49" fill="#008000" stroke="#008000" stroke-width=".2"/>
<circle cx="155.6" cy="119.6" r=".28" fill="#fff" stroke="#000" stroke-width=".2"/>
<circle cx="175.7" cy="28.1" r=".49" fill="#008000" stroke="#008000" stroke-width=".2"/>
<circle cx="175.7" cy="28.1" r=".28" fill="#fff" stroke="#000" stroke-width=".2"/>
<circle cx="144.2" cy="82.4" r=".49" fill="#008000" stroke="#008000" stroke-width=".2"/>
<circle cx="144.2" cy="82.4" r=".28" fill="#fff" stroke="#000" stroke-width=".2"/>
<circle cx="160.4" cy="115.1" r=".49" fill="#008000" stroke="#008000" stroke-width=".2"/>
<circle cx="160.4" cy="115.1" r=".28" fill="#fff" stroke="#000" stroke-width=".2"/>
<circle cx="153.4" cy="110.8" r=".49" fill="#008000" stroke="#008000" stroke-width=".2"/>
<circle cx="153.4" cy="110.8" r=".28" fill="#fff" stroke="#000" stroke-width=".2"/>
<circle cx="142.8" cy="125.4" r=".49" fill="#008000" stroke="#008000" stroke-width=".2"/>
<circle cx="142.8" cy="125.4" r=".28" fill="#fff" stroke="#000" stroke-width=".2"/>
<circle cx="143.3" cy="134.9" r=".49" fill="#008000" stroke="#008000" stroke-width=".2"/>
<circle cx="143.3" cy="134.9" r=".28" fill="#fff" stroke="#000" stroke-width=".2"/>
<circle cx="171.5" cy="26.3" r=".49" fill="#008000" stroke="#008000" stroke-width=".2"/>
<circle cx="171.5" cy="26.3" r=".28" fill="#fff" stroke="#000" stroke-width=".2"/>
<circle cx="155.2" cy="66.6" r=".49" fill="#008000" stroke="#008000" stroke-width=".2"/>
<circle cx="155.2" cy="66.6" r=".28" fill="#fff" stroke="#000" stroke-width=".2"/>
<circle cx="175" cy="120" r=".49" fill="#008000" stroke="#008000" stroke-width=".2"/>
<circle cx="175" cy="120" r=".28" fill="#fff" stroke="#000" stroke-width=".2"/>
<circle cx="168.2" cy="116.7" r=".49" fill="#008000" stroke="#008000" stroke-width=".2"/>
<circle cx="168.2" cy="116.7" r=".28" fill="#fff" stroke="#000" stroke-width=".2"/>
<circle cx="155.2" cy="129.6" r=".49" fill="#008000" stroke="#008000" stroke-width=".2"/>
<circle cx="155.2" cy="129.6" r=".28" fill="#fff" stroke="#000" stroke-width=".2"/>
<circle cx="148.8" cy="119.9" r=".49" fill="#008000" stroke="#008000" stroke-width=".2"/>
<circle cx="148.8" cy="119.9" r=".28" fill="#fff" stroke="#000" stroke-width=".2"/>
<circle cx="164.2" cy="23.3" r=".49" fill="#008000" stroke="#008000" stroke-width=".2"/>
<circle cx="164.2" cy="23.3" r=".28" fill="#fff" stroke="#000" stroke-width=".2"/>
<circle cx="151.8" cy="63.9" r=".49" fill="#008000" stroke="#008000" stroke-width=".2"/>
<circle cx="151.8" cy="63.9" r=".28" fill="#fff" stroke="#000" stroke-width=".2"/>
<circle cx="174.7" cy="123.7" r=".49" fill="#008000" stroke="#008000" stroke-width=".2"/>
<circle cx="174.7" cy="123.7" r=".28" fill="#fff" stroke="#000" stroke-width=".2"/>
<circle cx="165.2" cy="118.2" r=".49" fill="#008000" stroke="#008000" stroke-width=".2"/>
<circle cx="165.2" cy="118.2" r=".28" fill="#fff" stroke="#000" stroke-width=".2"/>
<circle cx="156.8" cy="22.1" r=".49" fill="#008000" stroke="#008000" stroke-width=".2"/>
<circle cx="156.8" cy="22.1" r=".28" fill="#fff" stroke="#000" stroke-width=".2"/>
<circle cx="144.7" cy="79.9" r=".49" fill="#008000" stroke="#008000" stroke-width=".2"/>
<circle cx="144.7" cy="79.9" r=".28" fill="#fff" stroke="#000" stroke-width=".2"/>
<circle cx="146.5" cy="84.6" r=".49" fill="#008000" stroke="#008000" stroke-width=".2"/>
<circle cx="146.5" cy="84.6" r=".28" fill="#fff" stroke="#000" stroke-width=".2"/>
<circle cx="143.2" cy="92.9" r=".49" fill="#008000" stroke="#008000" stroke-width=".2"/>
<circle cx="143.2" cy="92.9" r=".28" fill="#fff" stroke="#000" stroke-width=".2"/>
<circle cx="145.6" cy="19.7" r=".49" fill="#008000" stroke="#008000" stroke-width=".2"/>
<circle cx="145.6" cy="19.7" r=".28" fill="#fff" stroke="#000" stroke-width=".2"/>
<circle cx="141.2" cy="77" r=".49" fill="#008000" stroke="#008000" stroke-width=".2"/>
<circle cx="141.2" cy="77" r=".28" fill="#fff" stroke="#000" stroke-width=".2"/>
<circle cx="163.6" cy="92.9" r=".49" fill="#008000" stroke="#008000" stroke-width=".2"/>
<circle cx="163.6" cy="92.9" r=".28" fill="#fff" stroke="#000" stroke-width=".2"/>
<circle cx="159.8" cy="94.4" r=".49" fill="#008000" stroke="#008000" stroke-width=".2"/>
<circle cx="159.8" cy="94.4" r=".28" fill="#fff" stroke="#000" stroke-width=".2"/>
<circle cx="158.5" cy="100.5" r=".49" fill="#008000" stroke="#008000" stroke-width=".2"/>
<circle cx="158.5" cy="100.5" r=".28" fill="#fff" stroke="#000" stroke-width=".2"/>
<circle cx="146.5" cy="101.9" r=".49" fill="#008000" stroke="#008000" stroke-width=".2"/>
<circle cx="146.5" cy="101.9" r=".28" fill="#fff" stroke="#000" stroke-width=".2"/>
<circle cx="142.7" cy="16.2" r=".49" fill="#008000" stroke="#008000" stroke-width=".2"/>
<circle cx="142.7" cy="16.2" r=".28" fill="#fff" stroke="#000" stroke-width=".2"/>
<circle cx="141.1" cy="78.5" r=".49" fill="#008000" stroke="#008000" stroke-width=".2"/>
<circle cx="141.1" cy="78.5" r=".28" fill="#fff" stroke="#000" stroke-width=".2"/>
<circle cx="163.9" cy="100.1" r=".49" fill="#008000" stroke="#008000" stroke-width=".2"/>
<circle cx="163.9" cy="100.1" r=".28" fill="#fff" stroke="#000" stroke-width=".2"/>
<circle cx="109.7" cy="110.7" r=".49" fill="#008000" stroke="#008000" stroke-width=".2"/>
<circle cx="109.7" cy="110.7" r=".28" fill="#fff" stroke="#000" stroke-width=".2"/>
<circle cx="142.3" cy="139.6" r=".72" fill="#008000" stroke="#008000" stroke-width=".2"/>
<circle cx="142.3" cy="139.6" r=".47" fill="#fff" stroke="#000" stroke-width=".2"/>
<circle cx="174.7" cy="78.5" r=".49" fill="#008000" stroke="#008000" stroke-width=".2"/>
<circle cx="174.7" cy="78.5" r=".28" fill="#fff" stroke="#000" stroke-width=".2"/>
<circle cx="187" cy="72.7" r=".49" fill="#008000" stroke="#008000" stroke-width=".2"/>
<circle cx="187" cy="72.7" r=".28" fill="#fff" stroke="#000" stroke-width=".2"/>
<circle cx="136.9" cy="62" r=".49" fill="#008000" stroke="#008000" stroke-width=".2"/>
<circle cx="136.9" cy="62" r=".28" fill="#fff" stroke="#000" stroke-width=".2"/>
<circle cx="143.3" cy="35.8" r=".49" fill="#008000" stroke="#008000" stroke-width=".2"/>
<circle cx="143.3" cy="35.8" r=".28" fill="#fff" stroke="#000" stroke-width=".2"/>
<circle cx="125.8" cy="34.2" r=".49" fill="#008000" stroke="#008000" stroke-width=".2"/>
<circle cx="125.8" cy="34.2" r=".28" fill="#fff" stroke="#000" stroke-width=".2"/>
<circle cx="119.9" cy="64.2" r=".49" fill="#008000" stroke="#008000" stroke-width=".2"/>
<circle cx="119.9" cy="64.2" r=".28" fill="#fff" stroke="#000" stroke-width=".2"/>
<circle cx="119.5" cy="67" r=".49" fill="#008000" stroke="#008000" stroke-width=".2"/>
<circle cx="119.5" cy="67" r=".28" fill="#fff" stroke="#000" stroke-width=".2"/>
<circle cx="92.8" cy="125.5" r=".49" fill="#008000" stroke="#008000" stroke-width=".2"/>
<circle cx="92.8" cy="125.5" r=".28" fill="#fff" stroke="#000" stroke-width=".2"/>
<circle cx="133.2" cy="75.5" r=".72" fill="#008000" stroke="#008000" stroke-width=".2"/>
<circle cx="133.2" cy="75.5" r=".47" fill="#fff" stroke="#000" stroke-width=".2"/>
<circle cx="172.9" cy="72.6" r=".49" fill="#008000" stroke="#008000" stroke-width=".2"/>
<circle cx="172.9" cy="72.6" r=".28" fill="#fff" stroke="#000" stroke-width=".2"/>
<circle cx="148.5" cy="74.8" r=".72" fill="#008000" stroke="#008000" stroke-width=".2"/>
<circle cx="148.5" cy="74.8" r=".47" fill="#fff" stroke="#000" stroke-width=".2"/>
<circle cx="99.9" cy="115.8" r=".72" fill="#008000" stroke="#008000" stroke-width=".2"/>
<circle cx="99.9" cy="115.8" r=".47" fill="#fff" stroke="#000" stroke-width=".2"/>
<circle cx="136.7" cy="75.5" r=".72" fill="#008000" stroke="#008000" stroke-width=".2"/>
<circle cx="136.7" cy="75.5" r=".47" fill="#fff" stroke="#000" stroke-width=".2"/>
<circle cx="118.8" cy="49.3" r=".49" fill="#008000" stroke="#008000" stroke-width=".2"/>
<circle cx="118.8" cy="49.3" r=".28" fill="#fff" stroke="#000" stroke-width=".2"/>
<circle cx="114.1" cy="120" r=".49" fill="#008000" stroke="#008000" stroke-width=".2"/>
<circle cx="114.1" cy="120" r=".28" fill="#fff" stroke="#000" stroke-width=".2"/>
<circle cx="162.1" cy="43.8" r=".49" fill="#008000" stroke="#008000" stroke-width=".2"/>
<circle cx="162.1" cy="43.8" r=".28" fill="#fff" stroke="#000" stroke-width=".2"/>
<circle cx="165.5" cy="90.2" r=".49" fill="#008000" stroke="#008000" stroke-width=".2"/>
<circle cx="165.5" cy="90.2" r=".28" fill="#fff" stroke="#000" stroke-width=".2"/>
<circle cx="122" cy="57.9" r=".49" fill="#008000" stroke="#008000" stroke-width=".2"/>
<circle cx="122" cy="57.9" r=".28" fill="#fff" stroke="#000" stroke-width=".2"/>
<circle cx="165.7" cy="97" r=".49" fill="#008000" stroke="#008000" stroke-width=".2"/>
<circle cx="165.7" cy="97" r=".28" fill="#fff" stroke="#000" stroke-width=".2"/>
<circle cx="151.4" cy="69.1" r=".49" fill="#008000" stroke="#008000" stroke-width=".2"/>
<circle cx="151.4" cy="69.1" r=".28" fill="#fff" stroke="#000" stroke-width=".2"/>
<circle cx="156.9" cy="54.6" r=".49" fill="#008000" stroke="#008000" stroke-width=".2"/>
<circle cx="156.9" cy="54.6" r=".28" fill="#fff" stroke="#000" stroke-width=".2"/>
<circle cx="147.5" cy="55.5" r=".49" fill="#008000" stroke="#008000" stroke-width=".2"/>
<circle cx="147.5" cy="55.5" r=".28" fill="#fff" stroke="#000" stroke-width=".2"/>
<circle cx="132.9" cy="102" r=".49" fill="#008000" stroke="#008000" stroke-width=".2"/>
<circle cx="132.9" cy="102" r=".28" fill="#fff" stroke="#000" stroke-width=".2"/>
<circle cx="132.1" cy="103.3" r=".49" fill="#008000" stroke="#008000" stroke-width=".2"/>
<circle cx="132.1" cy="103.3" r=".28" fill="#fff" stroke="#000" stroke-width=".2"/>
<circle cx="157.4" cy="68.6" r=".49" fill="#008000" stroke="#008000" stroke-width=".2"/>
<circle cx="157.4" cy="68.6" r=".28" fill="#fff" stroke="#000" stroke-width=".2"/>
<circle cx="124.8" cy="103.4" r=".49" fill="#008000" stroke="#008000" stroke-width=".2"/>
<circle cx="124.8" cy="103.4" r=".28" fill="#fff" stroke="#000" stroke-width=".2"/>
<circle cx="45" cy="103.4" r=".49" fill="#008000" stroke="#008000" stroke-width=".2"/>
<circle cx="45" cy="103.4" r=".28" fill="#fff" stroke="#000" stroke-width=".2"/>
<circle cx="124.8" cy="109.6" r=".49" fill="#008000" stroke="#008000" stroke-width=".2"/>
<circle cx="124.8" cy="109.6" r=".28" fill="#fff" stroke="#000" stroke-width=".2"/>
<circle cx="154.9" cy="50.6" r=".49" fill="#008000" stroke="#008000" stroke-width=".2"/>
<circle cx="154.9" cy="50.6" r=".28" fill="#fff" stroke="#000" stroke-width=".2"/>
<circle cx="228.7" cy="112.1" r=".49" fill="#008000" stroke="#008000" stroke-width=".2"/>
<circle cx="228.7" cy="112.1" r=".28" fill="#fff" stroke="#000" stroke-width=".2"/>
<circle cx="195.3" cy="109" r=".49" fill="#008000" stroke="#008000" stroke-width=".2"/>
<circle cx="195.3" cy="109" r=".28" fill="#fff" stroke="#000" stroke-width=".2"/>
<circle cx="121.1" cy="46.9" r=".49" fill="#008000" stroke="#008000" stroke-width=".2"/>
<circle cx="121.1" cy="46.9" r=".28" fill="#fff" stroke="#000" stroke-width=".2"/>
<circle cx="136.2" cy="44.4" r=".49" fill="#008000" stroke="#008000" stroke-width=".2"/>
<circle cx="136.2" cy="44.4" r=".28" fill="#fff" stroke="#000" stroke-width=".2"/>
<circle cx="225.8" cy="88.9" r=".49" fill="#008000" stroke="#008000" stroke-width=".2"/>
<circle cx="225.8" cy="88.9" r=".28" fill="#fff" stroke="#000" stroke-width=".2"/>
<circle cx="194.8" cy="94.2" r=".49" fill="#008000" stroke="#008000" stroke-width=".2"/>
<circle cx="194.8" cy="94.2" r=".28" fill="#fff" stroke="#000" stroke-width=".2"/>
<g fill="none" stroke="#c60" stroke-width=".42">
<path d="M106.6 12.5a96.1 96.1 0 0 0-63.7 85.1M126.5 10.1a92.5 92.5 0 0 0-32.1 10.3 114.8 114.8 0 0 0-19.5 13.7 93.8 93.8 0 0 0-25.3 40.2 90.1 90.1 0 0 0-4.4 23l-.3 .6-1.3 1.1a3.7 3.7 0 0 0-.4 2.4l.1 5.2a6 6 0 0 0 .4 3.3l.8 1.2a4.8 4.8 0 0 1 1.1 3.6 111.8 111.8 0 0 0 7.4 26.9l1.9 4 2.8 4.8-.1-.2M126.5 10.1l-2.8 .4M138.8 11.1a92.1 92.1 0 0 0-83.9 54.1l-.1 1.7-1 2.2-.9 1.2a91.8 91.8 0 0 0 25.9 102.4M138.8 11.1h.1M138.8 9.2l-4.9 .2-7.4 .7M141.5 11.1h-2.7M144.3 18.5a84.8 84.8 0 0 1 75.9 60.7 84.8 84.8 0 0 1-31.1 92.1M156 18.6h-.3a86 86 0 0 1 23.9 8.6M169.6 12.1a96.1 96.1 0 0 1 63.6 109.2 96.1 96.1 0 0 1-99.7 77.8M93.5 29.5a86.5 86.5 0 0 0-24.9 22.9M93.5 29.5l-.1 .1"/>
<path d="M100.7 25.6l-2.7 1.3-4.5 2.6M104.5 25.5a84.8 84.8 0 0 0-49.5 90.7 84.8 84.8 0 0 0 74.8 71.2M111 21.4l.1-.1-5.3 2-5.1 2.4M120.4 24.5a80.7 80.7 0 0 0-59.8 98.4M139 29.6a73.5 73.5 0 0 0-73.3 65.7 73.5 73.5 0 0 0 57.9 79.7M143.8 29.1l-.1 .6-4.9-.1M146.4 30a73.2 73.2 0 0 1 39.2 16.4M150.3 23.2a80.7 80.7 0 0 1 69.1 76.4 80.7 80.7 0 0 1-62.2 82l.3 1.4M166.3 36.8l-.1 .1a71.5 71.5 0 0 1 43.6 56.2M177.8 39.7a73.4 73.4 0 0 1 13.9 11M179.5 27.2h.1M179.6 27.2a85.9 85.9 0 0 1 39.8 45.4"/>
<path d="M183.1 20.5a94.1 94.1 0 0 1 36.6 35.2M68.6 52.4a86.2 86.2 0 0 0-16.4 53.3M68.6 52.4v.1M91.5 48.9l-.5 .8 .7-.6M99.2 45.9h.1M99.3 45.9l-3.9 3-5.7 5.1-3 3.4M101.9 57.7a57.4 57.4 0 0 0-16.4 21.3M110.6 49.4a60.6 60.6 0 0 0-31.5 64.4 60.6 60.6 0 0 0 51.9 49.4M117.4 43.5h-.5a62.9 62.9 0 0 0-41.1 51.7M179.3 55.4a62.6 62.6 0 0 1 20.4 62.5 62.6 62.6 0 0 1-46.8 46.2M183.5 44.9l2.1 1.5M185.6 46.4a73.5 73.5 0 0 1 22.4 81.5 73.5 73.5 0 0 1-69.2 48.7"/>
<path d="M210.9 43.2l1 1.2a97.4 97.4 0 0 1 7.8 11.3M219.7 55.7l.4 .5v.2M220.1 56.4a93.7 93.7 0 0 1 6.7 78.9M220.1 56.4a93.8 93.8 0 0 1 6.7 78.9M72.7 75.3l-.3 .9M77.6 65l.4 .1-.5 .9M101.4 74.5l-1.8 2.4-2.3 3.8-.6 1.4M116.2 75.6l-2.7 2.2-3.5 4.3M137.7 67.4l-6 .6-6.8 2.1-5.9 3.2M138.9 77.8a25.2 25.2 0 0 0-18 7.5M156.6 79.7l3.2 2.6 3.7 4.6M219.3 72.3l.1 .3"/>
<path d="M219.4 72.6a86.1 86.1 0 0 1-10.7 80.8M42.9 97.6a27.1 27.1 0 0 0-.5 9.9l-.2 2.1 1.5 7.2a95.8 95.8 0 0 0 59.6 75.5M42.9 97.6l-.1 .5M69 86.7l-.2 .8M69.4 85.3l-.2 .8M84.3 82l-1.4 3.7-1.3 5.2M104.2 83.7l-2.3 4.3M171.4 83l.3 .6M174.7 89.9l.2 .7M209.8 93.1v-.2v.5M209.8 93.1v.3M209.8 93.1v.4"/>
<path d="M209.8 93.1h.1M209.8 93.4v.1M209.8 93.4l.1 .5M209.8 93.5l.7 7.4v2.7l-.4 1.3a61.6 61.6 0 0 1-1.7 14.7v.7M209.8 93.6l.1 .3M209.8 93.5l.1 .4M209.8 93.6h.1M209.9 93.6v.1M209.9 93.8v.1M210 94.4l.3 4.2 .2 4.1M52.2 105.7a85.5 85.5 0 0 0 5.1 26.6l.4-.3M52.7 105.7h-.5"/>
<path d="M67.4 109.1l.1 .9M67.5 110l.3 2.8M67.7 112.1l.1 .7M67.8 112.8l.1 1M69.1 119.8l.2 1M157.9 119.8a24.7 24.7 0 0 1-19.1 8.8M52.8 135.6l-.6 .2M57.5 132.8l2.6 6.3M60.1 139.1a86.2 86.2 0 0 0 40.5 41.5M60.2 138.4l-.1 .7M60.6 122.9a80.7 80.7 0 0 0 66.7 60M60.6 122.9l-1.2 .9"/>
<path d="M69.2 120.8l.4 .8M101.5 138.5a42 42 0 0 0 11.7 9.3M105.1 137.5v.1M112.8 133.3l3.7 3.1 6.8 3.7 2.8 1 2.7 .7M163.5 134.9l-.2-.1-1.7 1.2a55.2 55.2 0 0 1-12.5 5.7l-7.1 1.2-3.2 .1-1.8-.8M208.4 120.3a71.6 71.6 0 0 1-9.7 22.2M208.4 120.3h.1M226.8 135.3l-.6 .9-.1 1a93.8 93.8 0 0 1-31.9 41.5M57.7 150.4l3.4 5.2 3.2 4.4 .5 1.7 1.8 1.1a90.4 90.4 0 0 0 27.3 22.5l.4 .5M82.6 147.5l1.2 1.5M98.6 145.5l1.5 1.4M198.3 143.1v-.1a72.1 72.1 0 0 1-11.6 13.4l-.7 .8 .1-.2a71.6 71.6 0 0 1-43.6 17.7"/>
<path d="M208.7 153.4a85.6 85.6 0 0 1-37.2 29.4l-5.8 1.8M208.7 153.4h.1M68.1 165.1h.1M123.6 175l.4 .1M123.6 175l3.2 .6M182.2 177.5l-.1 .1M189.1 171.3a82.3 82.3 0 0 1-17.6 10.1M189.1 171.3h.2M189.1 171.3l.1 .1M193 179.6a93.6 93.6 0 0 1-37.4 15.7M193.5 179.2l-.1 .1M212.1 161.5l-1.2 1.5"/>
<path d="M94.3 185.8h.1M100.5 180.4a82.7 82.7 0 0 0 21.4 7.2M121.9 187.6v.1"/>
</g>
<g fill="none" stroke="#c60" stroke-width=".3">
<path d="M107.9 12.1l-1.3 .4M114.8 13.7l.2 .5M138.8 9.2h1.5M70.4 38.7l-2.3 2.3M76.7 33.9a92.9 92.9 0 0 0-16.4 19.8l-1.9 2.2-1.1 2a79.9 79.9 0 0 0-4.4 9.2l.2 .1M84.7 24.9a95 95 0 0 0-40.8 72.1M93.4 29.6l.2 .3M98 32.7l.4 .6M100.8 25.6l-.1 .1M118.7 35.7a70.3 70.3 0 0 0-47.2 47M120.2 23.8l.2 .7M146.4 30l-.1 .1"/>
<path d="M157.8 32.1l.2 .1M58.9 57.1l.2 .2M68.6 52.5l.2 .1M80.4 44.9l1.2 1.3M84.5 51.8l-1.9 1.8-1.7 2-2.2 1.8-1.3 1.6-.8 1.2-.2 .8-2.7 4.7M85.5 42.2l.1 .3M86.6 57.1l.1 .3M99.2 45.9h.1M101.6 57.2l.3 .5M107 49.1a62.8 62.8 0 0 0-30.4 46.6l-.1 .3-.7 .5a62 62 0 0 0 4.2 30.4M107.6 48.8l-.6 .3M110.6 49.4v.6"/>
<path d="M111.9 50.6l-1-2.2a61.7 61.7 0 0 0-33.2 48.7l-.8 3.8a61.2 61.2 0 0 0 6.1 29.3M112.1 48.7l-.4-1.4a62 62 0 0 0-34.6 49.6l-.6 .8M112.5 46.5l-.8 .1-4.7 2.5M120.2 58.5a50.2 50.2 0 0 0-18.9 14.3l-1-.7-.9 .1-.7 .9 .1 1 1 .7-2.8 4.3-1.9 3.5M120.2 58.5h.2l-.2 .1M120.6 58.4l-.4 .1M127 52.4l-1.8 .4-3.1 .9-3.2 1.4M191.6 50.4l.1 .3M211.3 43.7l.2 .2M62.8 65.5l-.4 .8M75.6 60.7l-3.2 5.4M77.6 60.6l-2.5 4.3a3.8 3.8 0 0 1-1.8 2.6l-1.8 3.7"/>
<path d="M85.5 79l-1.4-.3a59.7 59.7 0 0 0-5.3 24.4l.1-.2a60.1 60.1 0 0 0 21.9 46.4l.3-.5M97.3 75.2l.1 .3M97.4 75.5a49 49 0 0 0-6.4 13.5l-1.5 1.1-.4 1.4 1 1.8a50.2 50.2 0 0 0 4.8 32.9M97.5 75.3l-.1 .2M100.2 73.7l.5 .5 .7 .3M116.4 74l-.2 1.6M118.2 72.1l.8 1.2M129.7 75.6a28.9 28.9 0 0 0-7.8 50.8M137.6 65.9l.1 1.5M138.8 77.5l.1 .3M141.9 69.2v-4.3a38.3 38.3 0 0 1 29.5 18.1M149.4 77.7l-.2-.2a27.8 27.8 0 0 1 11.7 9.1h-.6l-.2 .2"/>
<path d="M213.8 72.1l-.4 .1M45.8 87.9v3.2M55.3 97.5l-.1 9.5 .3 3.8-.1 .6M58.8 84.2l1.5 .3M68.3 99.3a77.4 77.4 0 0 0 5.7 31.1l.3 1.6M69.2 86.1l-.5 .3M69.4 97.4a73.5 73.5 0 0 0 2.9 25.5l3 6.9 .3 2.7 .2 .2M81.6 90.9l-.4 .5 .2 .1M84 81.9l.3 .1M90.2 91.5l1.4 1.5M91.6 93a48.4 48.4 0 0 0 1.4 25.3M95.1 82.6l-2.1 5.4-1.4 5"/>
<path d="M95.1 82.6h.1M96.7 82.1l1.3 .6M104.3 83.4l-.1 .3M109.3 80.6l1.2 .9M112.9 99.5a26.2 26.2 0 0 0 9.7 24.1l1.2 1.7M118.2 84.8a27.5 27.5 0 0 0 2 38.6M120.3 84.8l.6 .5M122 95a20 20 0 0 0 1.1 18.7l.7-.8M141.5 91.2l-2.6-.1-3.2 .4M157.1 97l.3 2.4 .1 2.5 1 1.2a19.3 19.3 0 0 1-8.8 16.3v-.4l-.6-.6M171.7 83.6a39.6 39.6 0 0 1 3 6.3M174.9 90.6a38.4 38.4 0 0 1-5.6 35.5v.2v-.3a38.3 38.3 0 0 1-30.6 15.3h-3.7"/>
<path d="M210 94.4h.1M219.9 97.8l-.5 1.1M221.4 83.6v.1M224.5 94.5l.5 8.6M44.2 112.5a95.2 95.2 0 0 0 64 80.6M53.7 116.8l-.4 .2M58.5 110.9l-1.2 .2M64.3 109.2a76.1 76.1 0 0 0 7.4 26.8l2.5 4.8 2.3 3.7M67.5 110h.1M67.8 112.8v.1M93 118.2v.1M93 118.3v-.1a47.3 47.3 0 0 0 12.3 19.6"/>
<path d="M123.8 112.9h.1M124 115.8l.4 .2 1.8 1.6a13.8 13.8 0 0 0 4.2 2.7l.2 .2M131 113.3h-3.8a5.7 5.7 0 0 0-5.5 3.9 5.7 5.7 0 0 0 2 6.4M156.7 103.1a18.1 18.1 0 0 1-6.8 14.1M157.9 119.8v.5M208.4 119.6v.2M218.2 117.1l1.1 .1M52.8 135.6l.2 .7M56.2 122.3l.1 .3M57.3 132.3l.2 .5M64.4 134.3l-.3 .2M69.3 120.6l-.1 .2"/>
<path d="M74.3 132h.1M74.3 132l2.3 4.3 2.3 3.7M89.5 121.4a49.7 49.7 0 0 0 9.3 15.6 .73 .73 0 0 1-.2 .9l-2.7 2.6M100.8 137.8l1 1M105.1 137.6l.1 .1M137.6 128.5l1.2 .1M169.3 126.3h.1M195.8 129h.1M203.2 137.8l.3 .3M217.5 134.8l-.4 .6M57.7 150.4h.1M133.9 143.1l.1 .1h2.3"/>
<path d="M198.7 142.5l-.4 .5M66 161l1.6 1.6a72.4 72.4 0 0 0 15.1 14.3M66.6 162.8l1.5 2.3M73 173l1.2 1.2M78.1 172.2l.7 .5M79.5 175.7l1.1 .9M98.1 164.3l1.8 1.1M111.7 169.4l.3 .3-.1-.2M116.9 173.3l2.9 .7M131 163.2h.1M138.8 176.6l-2.5 .1M142 173.2l.5 1.5"/>
<path d="M152.9 164.1l1.3 4.9M182.1 177.6l-.4 .2M191.9 163.8l.3 .3M193.5 179.2h.1M211.4 162.3l-.1 .1M100.5 180.4l.1 .2M122.9 182.2l-.1 .8M129.8 187.4l.4 .1M168.2 194.5l-.8 .4"/>
</g>
<g fill="none" stroke="#c60" stroke-width=".57">
<path d="M138.8 31.4a71.5 71.5 0 0 0-47.1 17.7M91 49.7a72 72 0 0 0-13 15.4M219.7 55.7l.4 .5M72.4 76.2a68.6 68.6 0 0 0-3 9.1M77.5 66l-3 5.5-1.8 3.8M68.8 87.5a71.8 71.8 0 0 0-1.4 21.6M69.2 86.1l-.2 .6M67.5 109.9v.1M67.5 110.8l.2 1.3M67.8 112.9v.1M67.9 113.8l1.2 6M212 103.1h.3"/>
<path d="M69.3 120.6v.2M69.6 121.6a72.1 72.1 0 0 0 13 25.9M83.2 148.3h.1M83.8 149a71.5 71.5 0 0 0 28.1 20.5"/>
</g>
<circle cx="219.7" cy="55.7" r=".29" fill="#c60"/>
<path d="M219.7 55.7h.1" fill="none" stroke="#c60" stroke-width=".57"/>
<g fill="none" stroke="#c60" stroke-width=".42">
<path d="M87.5 19.7l-.1 .1M88.3 19.3h-.1M89.1 18.8h-.1M89.9 18.3l-.1 .1M90.7 17.8l-.1 .1M91.5 17.4h-.1M92.4 17h-.2M93.2 16.5l-.1 .1M94 16.1h-.1M94.8 15.7h-.1M95.7 15.2l-.1 .1M96.5 14.8l-.1 .1"/>
<path d="M97.3 14.4l-.1 .1M98.2 14.1h-.1M99 13.7h-.1M99.9 13.3h-.1M100.7 12.9l-.1 .1M101.6 12.6h-.1M102.5 12.2l-.1 .1M103.3 11.9h-.1M104.2 11.5l-.1 .1M105.1 11.2l-.1 .1M105.9 10.9h.1M106.8 10.6h-.1"/>
<path d="M107.7 10.3h-.1M108.6 10h-.1M109.5 9.7l-.1 .1M110.4 9.4l-.1 .1M111.3 9.2h-.2M112.1 8.9v.1M113.1 8.7h-.2M113.9 8.4h.1M114.9 8.2h-.2M115.8 8h-.1M116.6 7.7v.1M117.6 7.6h-.1"/>
<path d="M118.5 7.3l-.1 .1M119.4 7.2h-.1M120.3 7h-.1M121.2 6.8h-.1M122.1 6.6l-.1 .1M123 6.5h.1M124 6.3l-.1 .1M124.9 6.2h-.1M125.8 6.1h-.1M126.6 6h.1M127.6 5.9h.1M128.5 5.8h.1"/>
<path d="M129.5 5.7h-.1M130.5 5.6h-.2M131.3 5.5h.1M132.2 5.4h.1M133.1 5.4h.1M134 5.3h.2M135 5.3h.1M135.9 5.2h.1M136.8 5.2h.1M137.8 5.2h.1M138.7 5.2h.2M139.7 5.2h.1"/>
<path d="M140.7 5.2h.1M141.6 5.2h.1M142.5 5.3h.1M143.5 5.3h.1M144.4 5.4h.1M145.3 5.4h.1M146.3 5.5h.1M147.2 5.6h.1M148.1 5.7h.1M149 5.8h.1M150 5.9h.1M150.9 6h.1"/>
<path d="M151.8 6.1h.1M152.7 6.2h.1M153.6 6.3l.2 .1M154.6 6.5h.1M155.5 6.6l.1 .1M156.4 6.8h.1M157.3 7h.1M158.2 7.2h.1M159.2 7.3v.1M160.1 7.6h.1M161 7.7l.1 .1M161.9 8h.1"/>
<path d="M162.8 8.2h.1M163.7 8.4h.1M164.6 8.7h.1M165.5 8.9l.1 .1M166.4 9.2h.1M167.3 9.4l.1 .1M168.1 9.7l.2 .1M169 10h.1M169.9 10.3h.1M170.8 10.6h.1M171.7 10.9h.1M172.6 11.2l.1 .1"/>
<path d="M173.4 11.5l.1 .1M174.3 11.9h.1M175.2 12.2l.1 .1M176 12.6h.1M176.9 12.9l.1 .1M177.7 13.3h.1M178.6 13.7h.1M179.5 14.1h.1M180.3 14.4l.1 .1M181.1 14.8l.1 .1M182 15.2l.1 .1M182.8 15.7h.1"/>
<path d="M183.6 16.1h.1M184.4 16.5l.2 .1M185.3 17h.1M186.1 17.4h.1M186.9 17.8l.1 .1M187.7 18.3l.1 .1M188.5 18.8h.1M189.3 19.3h.1M190.1 19.7l.1 .1M64.3 39.7h-.1M64.9 38.9l-.1 .1M65.5 38.2l-.1 .1"/>
<path d="M66.1 37.5l-.1 .1M66.7 36.9h.1M67.4 36.2l-.1 .1M68 35.5l-.1 .1M68.7 34.8l-.1 .1M69.3 34.2h-.1M70 33.5l-.1 .1M70.6 32.9h.1M71.3 32.2l-.1 .1M72 31.6h-.1M72.7 30.9l-.1 .1M73.4 30.3l-.1 .1"/>
<path d="M74.1 29.7l-.1 .1M74.8 29.1l-.1 .1M75.5 28.5l-.1 .1M76.2 27.9l-.1 .1M76.9 27.3h-.1M77.6 26.7l-.1 .1M78.3 26.1v.1M79.1 25.5l-.1 .1M79.8 25l-.1 .1M80.6 24.4l-.1 .1M81.3 23.9h-.1M82.1 23.3l-.1 .1"/>
<path d="M82.8 22.8l-.1 .1M83.6 22.3h-.1M84.4 21.8h-.1M85.2 21.2l-.1 .1M85.9 20.7v.1M86.7 20.2l-.1 .1M150.3 33.7a70.3 70.3 0 0 1 39.5 117.7M190.9 20.2l.1 .1M191.7 20.7l.1 .1M192.5 21.2l.1 .1M193.3 21.8h.1M194 22.3h.1"/>
<path d="M194.8 22.8l.1 .1M195.5 23.3l.1 .1M196.3 23.9h.1M197.1 24.4v.1M197.8 25l.1 .1M198.5 25.5l.1 .1M199.3 26.1v.1M199.5 34a91.8 91.8 0 0 1 30.9 76.7M200 26.7l.1 .1M200.7 27.3h.1M201.4 27.9l.1 .1M202.2 28.5v.1"/>
<path d="M202.9 29.1v.1M203.6 29.7v.1M204.3 30.3v.1M205 30.9v.1M205.6 31.6h.1M206.3 32.2l.1 .1M207 32.9h.1M207.6 33.5l.1 .1M208.3 34.2h.1M209 34.8v.1M209.6 35.5l.1 .1M210.2 36.2l.1 .1"/>
<path d="M210.9 36.9h.1M211.5 37.5l.1 .1M212.1 38.2l.1 .1M212.7 38.9l.1 .1M213.3 39.7h.1M51 59.8v.1M51.4 59v.1M51.9 58.2l-.1 .1M52.3 57.3l-.1 .1M52.7 56.5v.1M53.2 55.7l-.1 .1M53.6 54.9v.1"/>
<path d="M54.1 54.1l-.1 .1M54.6 53.3l-.1 .1M55 52.5v.1M55.5 51.7v.1M56 50.9v.1M56.5 50.1v.1M57 49.3v.1M57.5 48.6h.1M58.1 47.8l-.1 .1M58.6 47l-.1 .1M59.1 46.3v.1M59.7 45.5l-.1 .1"/>
<path d="M60.2 44.8h.1M60.8 44l-.1 .1M61.3 43.3h.1M61.9 42.5l-.1 .1M62.5 41.8l-.1 .1M63.1 41.1l-.1 .1M63.7 40.4h-.1M136.2 44.4l-.2 .1-3.9 .2-5.9 .9-5.1 1.3M136.2 44.4h.1M136.2 44.4l1.4 1.3a79.8 79.8 0 0 1 16.2 1.8v.5l.2 .4 1.5 .5M153.7 45a60 60 0 0 1 45.1 58.1h-1.4a59.1 59.1 0 0 1-7.2 29.5l-.9 .9M154.9 50.6a25.9 25.9 0 0 0 6 2.7l3.8 1.8 1.5 .5 1.5 1 1.2 1.1 1.7 1.2"/>
<path d="M155.2 48.8l.3 .1M155.5 48.9h.9l.4-.2 .3-.5a39.4 39.4 0 0 1 7.5 3.2M164.5 51.4h.1M164.6 51.4a48.2 48.2 0 0 1 14.7 11.2l.1 2.8a58.1 58.1 0 0 1 13.4 26l1.7 1.1 .3 1.7M170.6 58.9l.5 .3M170.6 58.9a52.3 52.3 0 0 1 13.6 14 53.2 53.2 0 0 1 9 26.7l-.3 9.1 2.4 .3M210.5 40.6a95.1 95.1 0 0 1-17.1 140.4M214 40.4h.1M214.5 41.1l.1 .1M215.1 41.8l.1 .1M215.7 42.5l.1 .1M216.3 43.3h.1"/>
<path d="M216.8 44l.1 .1M217.4 44.8h.1M218 45.5v.1M218.5 46.3v.1M219 47l.1 .1M219.6 47.8v.1M220.1 48.6h.1M220.6 49.3l.1 .1M221.1 50.1l.1 .1M221.6 50.9l.1 .1M222.1 51.7l.1 .1M222.6 52.5v.1"/>
<path d="M223.1 53.3v.1M223.5 54.1l.1 .1M224 54.9v.1M224.5 55.7v.1M224.9 56.5v.1M225.3 57.3l.1 .1M225.8 58.2v.1M226.2 59v.1M226.6 59.8l.1 .1M43.7 79.9v.1M43.9 79v.1M44.2 78.1v.1"/>
<path d="M44.4 77.2v.1M44.7 76.3l-.1 .1M44.9 75.4v.1M45.2 74.5v.1M45.5 73.6l-.1 .1M45.8 72.8l-.1 .1M46.1 71.9l-.1 .1M46.4 71l-.1 .1M46.7 70.1l-.1 .1M47 69.2l-.1 .1M47.3 68.4v.1M47.6 67.5v.1"/>
<path d="M48 66.6l-.1 .1M48.3 65.8v.1M48.7 64.9v.1M49.1 64.1l-.1 .1M49.4 63.2v.1M49.8 62.4v.1M50.2 61.5v.1M50.6 60.7v.1M148.8 67.2a37.2 37.2 0 0 1 18.6 59.7M151.8 63.9l3.2 1.1 3 1.5a2.36 2.36 0 0 1 2.1-.4 1.22 1.22 0 0 1 .8 .9l.5 1.5a41.4 41.4 0 0 1 13.2 55.2M155.2 66.6a7.1 7.1 0 0 1 4.3 2.1 46.1 46.1 0 0 1 10.5 9.4 40 40 0 0 1 5 41.9M166.5 69.5l2.4 2.4 .2 .8a2.11 2.11 0 0 0 1 1.7 25.6 25.6 0 0 1 4.4 5.5 1 1 0 0 0 1.3-.3 1 1 0 0 0-.1-1.3 .68 .68 0 0 1 .4-.7 .68 .68 0 0 1 .8 .2"/>
<path d="M172.2 68.3a48.2 48.2 0 0 1-1.5 71M176.1 70.3a50 50 0 0 1 10.4 18.9l-.3 1.3 .8 .6a49.7 49.7 0 0 1-20.7 53.3M180.8 74.1a51.2 51.2 0 0 1 7 14.8 1.43 1.43 0 0 1 .6 2.2 50.9 50.9 0 0 1-7.3 40.5M201.2 76.1l-.2 .9a63.8 63.8 0 0 1 4.3 13M227 60.7l.1 .1M227.4 61.5l.1 .1M227.8 62.4v.1M228.2 63.2v.1M228.6 64.1v.1M228.9 64.9l.1 .1M229.3 65.8v.1M229.6 66.6l.1 .1"/>
<path d="M230 67.5v.1M230.3 68.4l.1 .1M230.7 69.2v.1M231 70.1v.1M231.3 71v.1M231.6 71.9v.1M231.9 72.8v.1M232.2 73.6v.1M232.4 74.5l.1 .1M232.7 75.4v.1M233 76.3v.1M233.2 77.2v.1"/>
<path d="M233.4 78.1l.1 .1M233.7 79v.1M233.9 79.9v.1M41 99.3v.1M41.1 98.3v.1M41.1 97.4v.1M41.2 96.5v.1M41.2 95.5v.1M41.3 94.6v.1M41.4 93.7v.1M41.5 92.8v.1M41.6 91.8v.1"/>
<path d="M41.7 90.9v.1M41.8 90v.1M42 89.1l-.1 .1M42.1 88.1v.1M42.2 87.2v.1M42.4 86.3v.1M42.6 85.4l-.1 .1M42.7 84.5v.1M42.9 83.6v.1M43.1 82.7h.1M43.3 81.7v.1M43.5 80.8v.1"/>
<path d="M143.6 85.5a16.5 16.5 0 0 1 13.1 16.2h-1.4a17.4 17.4 0 0 1-1.9 9.1M234.1 80.8v.1M234.3 81.7v.1M234.5 82.7h.1M234.7 83.6v.1M234.9 84.5v.1M235.1 85.4v.1M235.2 86.3v.1M235.4 87.2v.1M235.5 88.1v.1M235.7 89.1v.1M235.8 90v.1"/>
<path d="M235.9 90.9v.1M236 91.8l.1 .1M236.1 92.8v.1M236.2 93.7v.1M236.3 94.6v.1M236.4 95.5v.1M236.5 96.5v.1M236.5 97.4v.1M236.6 98.3v.1M236.6 99.3v.1M40.9 103v.2M41 101.1v.1"/>
<path d="M41 102v.2M41 104v.1M41 104.9v.2M41 100.2v.1M41 105.9v.1M41 106.8v.1M41.1 107.7v.1M41.1 108.7v.1M41.2 109.6v.1M41.2 110.5v.1M41.3 111.4v.1M41.4 112.4v.1"/>
<path d="M41.5 113.3v.1M41.6 114.2v.1M41.7 115.1v.2M41.8 116.1v.1M41.9 117l.1 .1M42.1 117.9v.1M42.2 118.9h.1M42.4 119.8v.1M124.8 103.4v6.2M188.7 118.9a52.2 52.2 0 0 1-18.6 26.2M197.3 116.3a60 60 0 0 1-47 45.6M199.6 111.1a61.3 61.3 0 0 1-60.8 53.3"/>
<path d="M230.4 110.7a91.4 91.4 0 0 1-12.9 40M230.4 110.7l.7 .1M235.2 119.8v.1M235.4 118.9h.1M235.5 117.9v.1M235.7 117v.1M235.8 116.1v.1M235.9 115.1v.2M236.1 114.2l-.1 .1M236.1 113.3v.1M236.2 112.4v.1M236.3 111.4v.1"/>
<path d="M236.4 110.5v.1M236.5 109.6v.1M236.5 108.7v.1M236.6 107.7v.1M236.6 106.8v.1M236.6 100.2v.1M236.6 105.9v.1M236.7 101.1v.1M236.7 102v.2M236.7 104v.1M236.7 104.9v.2M236.7 103v.2"/>
<path d="M42.5 120.7l.1 .1M42.7 121.6v.1M42.9 122.5v.1M43.1 123.4v.1M43.3 124.3v.1M43.5 125.2v.1M43.7 126.1v.1M43.9 127v.1M44.2 128h.1M44.4 128.8v.1M44.6 129.7l.1 .1M44.9 130.6v.1"/>
<path d="M45.2 131.5v.1M45.4 132.4l.1 .1M45.7 133.3l.1 .1M46 134.2l.1 .1M46.3 135.1l.1 .1M46.6 136h.1M46.9 136.8l.1 .1M47.3 137.7v.1M47.6 138.6v.1M47.9 139.4l.1 .1M210.2 124.6a74.7 74.7 0 0 1-56 51.3M220.6 136.2a98.6 98.6 0 0 1-18.4 28.3l-3.8 3.7"/>
<path d="M229.7 139.4l-.1 .1M230 138.6v.1M230.4 137.7l-.1 .1M230.7 136.8v.1M231 136h.1M231.3 135.1v.1M231.6 134.2v.1M231.9 133.3v.1M232.2 132.4v.1M232.5 131.5l-.1 .1M232.7 130.6v.1M233 129.7v.1"/>
<path d="M233.2 128.8v.1M233.5 128h-.1M233.7 127v.1M233.9 126.1v.1M234.1 125.2v.1M234.3 124.3v.1M234.5 123.4v.1M234.7 122.5v.1M234.9 121.6v.1M235.1 120.7v.1M48.3 140.3v.1M48.7 141.2h.1"/>
<path d="M49 142l.1 .1M49.4 142.9v.1M49.8 143.7v.1M50.2 144.5v.2M50.6 145.4v.1M51 146.2v.1M51.4 147.1v.1M51.8 147.9l.1 .1M52.2 148.7l.1 .1M52.7 149.5v.1M53.1 150.4l.1 .1M53.6 151.2v.1"/>
<path d="M54 152l.1 .1M54.5 152.8l.1 .1M55 153.6v.1M55.5 154.4v.1M56 155.2v.1M56.5 156h.1M57 156.7v.1M57.5 157.5v.1M58 158.3l.1 .1M58.5 159l.1 .1M59.1 159.8v.1M217.5 150.7a91.9 91.9 0 0 1-83.4 44.2"/>
<path d="M217.5 150.7l-.2 1M218.5 159.8v.1M219.1 159l-.1 .1M219.6 158.3v.1M220.1 157.5v.1M220.7 156.7l-.1 .1M221.2 156h-.1M221.7 155.2l-.1 .1M222.2 154.4l-.1 .1M222.6 153.6v.1M223.1 152.8v.1M223.6 152l-.1 .1"/>
<path d="M224 151.2v.1M224.5 150.4v.1M224.9 149.5v.1M225.4 148.7l-.1 .1M225.8 147.9v.1M226.2 147.1v.1M226.7 146.2l-.1 .1M227.1 145.4l-.1 .1M227.5 144.5l-.1 .2M227.8 143.7v.1M228.2 142.9v.1M228.6 142v.1"/>
<path d="M229 141.2h-.1M229.3 140.3v.1M59.6 160.6l.1 .1M60.2 161.3v.1M60.7 162.1l.1 .1M61.3 162.8v.1M61.8 163.5l.1 .1M62.4 164.3l.1 .1M63 165l.1 .1M63.6 165.7l.1 .1M64.2 166.4l.1 .1M64.8 167.1l.1 .1"/>
<path d="M65.4 167.8l.1 .1M66 168.5l.1 .1M66.7 169.2v.1M67.3 169.9l.1 .1M67.9 170.6h.1M68.6 171.3h.1M69.2 171.9l.1 .1M69.9 172.6l.1 .1M70.6 173.2v.1M71.2 173.9h.1M71.9 174.5l.1 .1M72.6 175.2h.1"/>
<path d="M73.3 175.8h.1M74 176.4l.1 .1M74.7 177l.1 .1M75.4 177.6l.1 .1M76.1 178.2l.1 .1M76.8 178.8l.1 .1M77.5 179.4l.1 .1M78.3 180h.1M193.5 179.2l-.5 .4M194.2 178.7l-.7 .5M199.3 180h.1M200.1 179.4l-.1 .1"/>
<path d="M200.8 178.8l-.1 .1M201.5 178.2l-.1 .1M202.2 177.6v.1M202.9 177v.1M203.6 176.4v.1M204.3 175.8h.1M205 175.2h.1M205.7 174.5l-.1 .1M206.4 173.9h-.1M207.1 173.2l-.1 .1M207.7 172.6l-.1 .1M208.4 171.9l-.1 .1"/>
<path d="M209 171.3h.1M209.7 170.6h-.1M210.3 169.9l-.1 .1M210.9 169.2v.1M211.6 168.5l-.1 .1M212.2 167.8l-.1 .1M212.8 167.1l-.1 .1M213.4 166.4l-.1 .1M214 165.7v.1M214.6 165l-.1 .1M215.2 164.3l-.1 .1M215.8 163.5l-.1 .1"/>
<path d="M216.3 162.8v.1M216.9 162.1l-.1 .1M217.5 161.3l-.1 .1M218 160.6v.1M79 180.6h.1M79.7 181.1l.1 .1M80.5 181.7h.1M81.2 182.2l.1 .1M82 182.8h.1M82.7 183.3l.1 .1M83.5 183.8l.1 .1M84.3 184.4h.1"/>
<path d="M85.1 184.9h.1M85.9 185.4h.1M86.6 185.9h.1M87.4 186.4h.1M88.2 186.9h.1M89 187.3l.1 .1M89.8 187.8l.1 .1M90.6 188.3h.1M91.4 188.7l.1 .1M92.2 189.2h.2M93.1 189.6l.1 .1M93.9 190l.1 .1"/>
<path d="M94.7 190.5h.1M95.6 190.9h.1M96.4 191.3h.1M97.2 191.7h.1M98.1 192.1h.1M98.9 192.4l.1 .1M99.8 192.8l.1 .1M100.6 193.2h.1M101.5 193.5l.1 .1M102.4 193.9l.1 .1M103.2 194.2l.1 .1M104.1 194.6h.1"/>
<path d="M105 194.9h.1M105.9 195.2v.1M106.7 195.5l.1 .1M107.6 195.8l.1 .1M108.5 196.1l.1 .1M109.4 196.4h.1M110.3 196.7h.1M111.1 197h.2M112.1 197.2v.1M112.9 197.5h.2M113.9 197.7h.1M114.7 198h.2"/>
<path d="M115.7 198.2h.1M116.6 198.4h.1M117.5 198.6h.1M118.4 198.8h.1M119.3 199h.1M120.2 199.2h.1M121.1 199.3h.1M122 199.5h.1M123 199.6v.1M123.9 199.8h.1M124.8 199.9l.1 .1M152.8 199.9l-.1 .1"/>
<path d="M153.8 199.8h-.2M154.7 199.6l-.1 .1M155.6 199.5h-.1M156.5 199.3h-.1M157.4 199.2h-.1M158.3 199h-.1M159.2 198.8h.1M160.1 198.6h.1M161.1 198.4h-.1M162 198.2h-.1M162.9 198h-.1M163.8 197.7h-.1"/>
<path d="M164.7 197.5h-.1M165.6 197.2l-.1 .1M166.5 197h-.1M167.4 196.7h-.1M168.3 196.4h-.2M169.1 196.1l-.1 .1M170 195.8l-.1 .1M170.9 195.5l-.1 .1M171.8 195.2l-.1 .1M172.7 194.9h-.1M173.5 194.6h-.1M174.4 194.2l-.1 .1"/>
<path d="M175.3 193.9l-.1 .1M176.1 193.5l-.1 .1M177 193.2h-.1M177.8 192.8l-.1 .1M178.7 192.4l-.1 .1M179.5 192.1h.1M180.4 191.7h-.1M181.2 191.3h-.1M182.1 190.9h-.1M182.9 190.5h-.1M183.7 190l-.1 .1M184.6 189.6l-.2 .1"/>
<path d="M185.4 189.2h-.1M186.2 188.7l-.1 .1M187 188.3h-.1M187.8 187.8l-.1 .1M188.6 187.3l-.1 .1M189.4 186.9h-.1M190.2 186.4h-.1M191 185.9h-.1M191.8 185.4h-.1M192.6 184.9h-.1M193.3 184.4h.1M194.1 183.8l-.1 .1"/>
<path d="M194.9 183.3l-.1 .1M195.6 182.8h-.1M196.4 182.2l-.1 .1M197.1 181.7h.1M197.9 181.1l-.1 .1M198.6 180.6h-.1M125.7 200.1h.1M126.6 200.2h.1M127.6 200.3h.1M128.5 200.4h.1M129.4 200.5h.1M130.3 200.6h.2"/>
<path d="M131.3 200.7h.1M132.2 200.7h.1M133.1 200.8h.1M134 200.8h.2M135 200.9h.1M135.9 200.9h.1M136.8 200.9h.1M137.8 200.9h.1M138.7 201h.2M139.7 200.9h.1M140.7 200.9h.1M141.6 200.9h.1"/>
<path d="M142.5 200.9h.1M143.5 200.8h.1M144.4 200.8h.1M145.3 200.7h.1M146.3 200.7h.1M147.3 200.6h-.1M148.2 200.5h-.1M149 200.4h.1M150 200.3h.1M150.9 200.2h.1M151.9 200.1h-.1"/>
</g>
<g fill="none" stroke="#c60" stroke-width=".3">
<path d="M150.5 31.8l-.2 1.9M141.1 78.5a23.6 23.6 0 0 1 20.8 14.1 12 12 0 0 1 2.1 7.5h-.1M141.2 77a25.4 25.4 0 0 1 17.4 8.6l.4 .8a1.37 1.37 0 0 0 1.6 1.4l.4 .3 1 1.4 1.6 3.4M148.8 67.2l-.4 1.8M155.2 66.6l.1 .1M182.2 73.1l-1.4 1M191.3 70.8a74 74 0 0 1 6.1 14.8M191.6 77.3l.9 1.8 1.4 3.4M196.8 76l.7 .3a4 4 0 0 1 1.5 2.4l1.4 3.5M223 65.1l-.3 .2M144.3 82.4h-.1l-.6 3.1M167.3 126.9h.1"/>
<path d="M170.7 139.3h-.1M174.7 123.7h-.1M181.1 131.6h.1M210.2 124.4v.2M166.3 144.4h.1M170 145.1h.1M217.2 151.2l.1 .5M150.3 161.9v.1M176.6 186.9l.1 .3"/>
</g>
<path d="M147.8 74.8h.7" fill="none" stroke="#c60" stroke-width="1.7"/>
<path d="M99.9 115.8l.3 .1" fill="none" stroke="#c60" stroke-width=".85"/>
<circle cx="134.1" cy="13.1" r=".49" fill="#008000" stroke="#008000" stroke-width=".2"/>
<circle cx="134.1" cy="13.1" r=".28" fill="#fff" stroke="#000" stroke-width=".2"/>
<circle cx="114.4" cy="100.2" r=".49" fill="#008000" stroke="#008000" stroke-width=".2"/>
<circle cx="114.4" cy="100.2" r=".28" fill="#fff" stroke="#000" stroke-width=".2"/>
<circle cx="116.8" cy="100.5" r=".49" fill="#008000" stroke="#008000" stroke-width=".2"/>
<circle cx="116.8" cy="100.5" r=".28" fill="#fff" stroke="#000" stroke-width=".2"/>
<circle cx="141.5" cy="11.1" r=".49" fill="#008000" stroke="#008000" stroke-width=".2"/>
<circle cx="141.5" cy="11.1" r=".28" fill="#fff" stroke="#000" stroke-width=".2"/>
<circle cx="52.9" cy="70.3" r=".49" fill="#008000" stroke="#008000" stroke-width=".2"/>
<circle cx="52.9" cy="70.3" r=".28" fill="#fff" stroke="#000" stroke-width=".2"/>
<circle cx="71.3" cy="62.4" r=".49" fill="#008000" stroke="#008000" stroke-width=".2"/>
<circle cx="71.3" cy="62.4" r=".28" fill="#fff" stroke="#000" stroke-width=".2"/>
<circle cx="58.9" cy="57.1" r=".49" fill="#008000" stroke="#008000" stroke-width=".2"/>
<circle cx="58.9" cy="57.1" r=".28" fill="#fff" stroke="#000" stroke-width=".2"/>
<circle cx="87.4" cy="163.1" r=".49" fill="#008000" stroke="#008000" stroke-width=".2"/>
<circle cx="87.4" cy="163.1" r=".28" fill="#fff" stroke="#000" stroke-width=".2"/>
<circle cx="79.9" cy="170.2" r=".49" fill="#008000" stroke="#008000" stroke-width=".2"/>
<circle cx="79.9" cy="170.2" r=".28" fill="#fff" stroke="#000" stroke-width=".2"/>
<circle cx="78.1" cy="172.2" r=".49" fill="#008000" stroke="#008000" stroke-width=".2"/>
<circle cx="78.1" cy="172.2" r=".28" fill="#fff" stroke="#000" stroke-width=".2"/>
<circle cx="121.5" cy="38.6" r=".49" fill="#008000" stroke="#008000" stroke-width=".2"/>
<circle cx="121.5" cy="38.6" r=".28" fill="#fff" stroke="#000" stroke-width=".2"/>
<circle cx="122.6" cy="48.4" r=".49" fill="#008000" stroke="#008000" stroke-width=".2"/>
<circle cx="122.6" cy="48.4" r=".28" fill="#fff" stroke="#000" stroke-width=".2"/>
<circle cx="114.8" cy="13.7" r=".49" fill="#008000" stroke="#008000" stroke-width=".2"/>
<circle cx="114.8" cy="13.7" r=".28" fill="#fff" stroke="#000" stroke-width=".2"/>
<circle cx="76.3" cy="126.5" r=".49" fill="#008000" stroke="#008000" stroke-width=".2"/>
<circle cx="76.3" cy="126.5" r=".28" fill="#fff" stroke="#000" stroke-width=".2"/>
<circle cx="95.5" cy="117.3" r=".49" fill="#008000" stroke="#008000" stroke-width=".2"/>
<circle cx="95.5" cy="117.3" r=".28" fill="#fff" stroke="#000" stroke-width=".2"/>
<circle cx="95.9" cy="140.5" r=".49" fill="#008000" stroke="#008000" stroke-width=".2"/>
<circle cx="95.9" cy="140.5" r=".28" fill="#fff" stroke="#000" stroke-width=".2"/>
<circle cx="89.5" cy="121.4" r=".49" fill="#008000" stroke="#008000" stroke-width=".2"/>
<circle cx="89.5" cy="121.4" r=".28" fill="#fff" stroke="#000" stroke-width=".2"/>
<circle cx="52.2" cy="135.8" r=".49" fill="#008000" stroke="#008000" stroke-width=".2"/>
<circle cx="52.2" cy="135.8" r=".28" fill="#fff" stroke="#000" stroke-width=".2"/>
<circle cx="90.9" cy="124.7" r=".49" fill="#008000" stroke="#008000" stroke-width=".2"/>
<circle cx="90.9" cy="124.7" r=".28" fill="#fff" stroke="#000" stroke-width=".2"/>
<circle cx="117.2" cy="112.7" r=".49" fill="#008000" stroke="#008000" stroke-width=".2"/>
<circle cx="117.2" cy="112.7" r=".28" fill="#fff" stroke="#000" stroke-width=".2"/>
<circle cx="122.7" cy="14.2" r=".49" fill="#008000" stroke="#008000" stroke-width=".2"/>
<circle cx="122.7" cy="14.2" r=".28" fill="#fff" stroke="#000" stroke-width=".2"/>
<circle cx="123.7" cy="10.5" r=".49" fill="#008000" stroke="#008000" stroke-width=".2"/>
<circle cx="123.7" cy="10.5" r=".28" fill="#fff" stroke="#000" stroke-width=".2"/>
<circle cx="49.7" cy="88.5" r=".49" fill="#008000" stroke="#008000" stroke-width=".2"/>
<circle cx="49.7" cy="88.5" r=".28" fill="#fff" stroke="#000" stroke-width=".2"/>
<circle cx="96.1" cy="182.6" r=".49" fill="#008000" stroke="#008000" stroke-width=".2"/>
<circle cx="96.1" cy="182.6" r=".28" fill="#fff" stroke="#000" stroke-width=".2"/>
<circle cx="94.3" cy="185.8" r=".49" fill="#008000" stroke="#008000" stroke-width=".2"/>
<circle cx="94.3" cy="185.8" r=".28" fill="#fff" stroke="#000" stroke-width=".2"/>
<circle cx="78.8" cy="51.8" r=".49" fill="#008000" stroke="#008000" stroke-width=".2"/>
<circle cx="78.8" cy="51.8" r=".28" fill="#fff" stroke="#000" stroke-width=".2"/>
<circle cx="68.1" cy="41" r=".49" fill="#008000" stroke="#008000" stroke-width=".2"/>
<circle cx="68.1" cy="41" r=".28" fill="#fff" stroke="#000" stroke-width=".2"/>
<circle cx="78.6" cy="154.2" r=".49" fill="#008000" stroke="#008000" stroke-width=".2"/>
<circle cx="78.6" cy="154.2" r=".28" fill="#fff" stroke="#000" stroke-width=".2"/>
<circle cx="68.1" cy="165.1" r=".49" fill="#008000" stroke="#008000" stroke-width=".2"/>
<circle cx="68.1" cy="165.1" r=".28" fill="#fff" stroke="#000" stroke-width=".2"/>
<circle cx="87.8" cy="147.5" r=".49" fill="#008000" stroke="#008000" stroke-width=".2"/>
<circle cx="87.8" cy="147.5" r=".28" fill="#fff" stroke="#000" stroke-width=".2"/>
<circle cx="86.6" cy="57.1" r=".49" fill="#008000" stroke="#008000" stroke-width=".2"/>
<circle cx="86.6" cy="57.1" r=".28" fill="#fff" stroke="#000" stroke-width=".2"/>
<circle cx="100.4" cy="47.4" r=".49" fill="#008000" stroke="#008000" stroke-width=".2"/>
<circle cx="100.4" cy="47.4" r=".28" fill="#fff" stroke="#000" stroke-width=".2"/>
<circle cx="99.2" cy="45.9" r=".49" fill="#008000" stroke="#008000" stroke-width=".2"/>
<circle cx="99.2" cy="45.9" r=".28" fill="#fff" stroke="#000" stroke-width=".2"/>
<circle cx="45.8" cy="87.9" r=".49" fill="#008000" stroke="#008000" stroke-width=".2"/>
<circle cx="45.8" cy="87.9" r=".28" fill="#fff" stroke="#000" stroke-width=".2"/>
<circle cx="141.2" cy="47.3" r=".49" fill="#008000" stroke="#008000" stroke-width=".2"/>
<circle cx="141.2" cy="47.3" r=".28" fill="#fff" stroke="#000" stroke-width=".2"/>
<circle cx="140.3" cy="9.2" r=".49" fill="#008000" stroke="#008000" stroke-width=".2"/>
<circle cx="140.3" cy="9.2" r=".28" fill="#fff" stroke="#000" stroke-width=".2"/>
<circle cx="100.6" cy="127.9" r=".49" fill="#008000" stroke="#008000" stroke-width=".2"/>
<circle cx="100.6" cy="127.9" r=".28" fill="#fff" stroke="#000" stroke-width=".2"/>
<circle cx="89.1" cy="130.7" r=".49" fill="#008000" stroke="#008000" stroke-width=".2"/>
<circle cx="89.1" cy="130.7" r=".28" fill="#fff" stroke="#000" stroke-width=".2"/>
<circle cx="57.7" cy="150.4" r=".49" fill="#008000" stroke="#008000" stroke-width=".2"/>
<circle cx="57.7" cy="150.4" r=".28" fill="#fff" stroke="#000" stroke-width=".2"/>
<circle cx="123.9" cy="121.4" r=".49" fill="#008000" stroke="#008000" stroke-width=".2"/>
<circle cx="123.9" cy="121.4" r=".28" fill="#fff" stroke="#000" stroke-width=".2"/>
<circle cx="80.6" cy="176.6" r=".49" fill="#008000" stroke="#008000" stroke-width=".2"/>
<circle cx="80.6" cy="176.6" r=".28" fill="#fff" stroke="#000" stroke-width=".2"/>
<circle cx="107.7" cy="88.4" r=".49" fill="#008000" stroke="#008000" stroke-width=".2"/>
<circle cx="107.7" cy="88.4" r=".28" fill="#fff" stroke="#000" stroke-width=".2"/>
<circle cx="122" cy="95" r=".49" fill="#008000" stroke="#008000" stroke-width=".2"/>
<circle cx="122" cy="95" r=".28" fill="#fff" stroke="#000" stroke-width=".2"/>
<circle cx="123.8" cy="112.9" r=".49" fill="#008000" stroke="#008000" stroke-width=".2"/>
<circle cx="123.8" cy="112.9" r=".28" fill="#fff" stroke="#000" stroke-width=".2"/>
<circle cx="109.8" cy="17.6" r=".49" fill="#008000" stroke="#008000" stroke-width=".2"/>
<circle cx="109.8" cy="17.6" r=".28" fill="#fff" stroke="#000" stroke-width=".2"/>
<circle cx="107.9" cy="12.1" r=".49" fill="#008000" stroke="#008000" stroke-width=".2"/>
<circle cx="107.9" cy="12.1" r=".28" fill="#fff" stroke="#000" stroke-width=".2"/>
<circle cx="48.5" cy="105.8" r=".49" fill="#008000" stroke="#008000" stroke-width=".2"/>
<circle cx="48.5" cy="105.8" r=".28" fill="#fff" stroke="#000" stroke-width=".2"/>
<circle cx="105.3" cy="187" r=".49" fill="#008000" stroke="#008000" stroke-width=".2"/>
<circle cx="105.3" cy="187" r=".28" fill="#fff" stroke="#000" stroke-width=".2"/>
<circle cx="103.3" cy="192.3" r=".49" fill="#008000" stroke="#008000" stroke-width=".2"/>
<circle cx="103.3" cy="192.3" r=".28" fill="#fff" stroke="#000" stroke-width=".2"/>
<circle cx="86.1" cy="44.2" r=".49" fill="#008000" stroke="#008000" stroke-width=".2"/>
<circle cx="86.1" cy="44.2" r=".28" fill="#fff" stroke="#000" stroke-width=".2"/>
<circle cx="91.2" cy="54.8" r=".49" fill="#008000" stroke="#008000" stroke-width=".2"/>
<circle cx="91.2" cy="54.8" r=".28" fill="#fff" stroke="#000" stroke-width=".2"/>
<circle cx="114.8" cy="78.6" r=".49" fill="#008000" stroke="#008000" stroke-width=".2"/>
<circle cx="114.8" cy="78.6" r=".28" fill="#fff" stroke="#000" stroke-width=".2"/>
<circle cx="72.9" cy="33.1" r=".49" fill="#008000" stroke="#008000" stroke-width=".2"/>
<circle cx="72.9" cy="33.1" r=".28" fill="#fff" stroke="#000" stroke-width=".2"/>
<circle cx="72.2" cy="145.5" r=".49" fill="#008000" stroke="#008000" stroke-width=".2"/>
<circle cx="72.2" cy="145.5" r=".28" fill="#fff" stroke="#000" stroke-width=".2"/>
<circle cx="58.9" cy="156.4" r=".49" fill="#008000" stroke="#008000" stroke-width=".2"/>
<circle cx="58.9" cy="156.4" r=".28" fill="#fff" stroke="#000" stroke-width=".2"/>
<circle cx="42.2" cy="106" r=".49" fill="#008000" stroke="#008000" stroke-width=".2"/>
<circle cx="42.2" cy="106" r=".28" fill="#fff" stroke="#000" stroke-width=".2"/>
<circle cx="95" cy="154.8" r=".49" fill="#008000" stroke="#008000" stroke-width=".2"/>
<circle cx="95" cy="154.8" r=".28" fill="#fff" stroke="#000" stroke-width=".2"/>
<circle cx="109" cy="137.6" r=".49" fill="#008000" stroke="#008000" stroke-width=".2"/>
<circle cx="109" cy="137.6" r=".28" fill="#fff" stroke="#000" stroke-width=".2"/>
<circle cx="73" cy="173" r=".49" fill="#008000" stroke="#008000" stroke-width=".2"/>
<circle cx="73" cy="173" r=".28" fill="#fff" stroke="#000" stroke-width=".2"/>
<circle cx="98.6" cy="145.5" r=".49" fill="#008000" stroke="#008000" stroke-width=".2"/>
<circle cx="98.6" cy="145.5" r=".28" fill="#fff" stroke="#000" stroke-width=".2"/>
<circle cx="100.1" cy="146.9" r=".49" fill="#008000" stroke="#008000" stroke-width=".2"/>
<circle cx="100.1" cy="146.9" r=".28" fill="#fff" stroke="#000" stroke-width=".2"/>
<circle cx="84.1" cy="118.1" r=".49" fill="#008000" stroke="#008000" stroke-width=".2"/>
<circle cx="84.1" cy="118.1" r=".28" fill="#fff" stroke="#000" stroke-width=".2"/>
<circle cx="46.1" cy="128.3" r=".49" fill="#008000" stroke="#008000" stroke-width=".2"/>
<circle cx="46.1" cy="128.3" r=".28" fill="#fff" stroke="#000" stroke-width=".2"/>
<circle cx="138.8" cy="53.3" r=".49" fill="#008000" stroke="#008000" stroke-width=".2"/>
<circle cx="138.8" cy="53.3" r=".28" fill="#fff" stroke="#000" stroke-width=".2"/>
<circle cx="112.8" cy="133.3" r=".49" fill="#008000" stroke="#008000" stroke-width=".2"/>
<circle cx="112.8" cy="133.3" r=".28" fill="#fff" stroke="#000" stroke-width=".2"/>
<circle cx="128.8" cy="141.8" r=".49" fill="#008000" stroke="#008000" stroke-width=".2"/>
<circle cx="128.8" cy="141.8" r=".28" fill="#fff" stroke="#000" stroke-width=".2"/>
<circle cx="133.3" cy="125.2" r=".49" fill="#008000" stroke="#008000" stroke-width=".2"/>
<circle cx="133.3" cy="125.2" r=".28" fill="#fff" stroke="#000" stroke-width=".2"/>
<circle cx="138.8" cy="77.5" r=".49" fill="#008000" stroke="#008000" stroke-width=".2"/>
<circle cx="138.8" cy="77.5" r=".28" fill="#fff" stroke="#000" stroke-width=".2"/>
<circle cx="120.3" cy="84.8" r=".49" fill="#008000" stroke="#008000" stroke-width=".2"/>
<circle cx="120.3" cy="84.8" r=".28" fill="#fff" stroke="#000" stroke-width=".2"/>
<circle cx="90" cy="116.5" r=".49" fill="#008000" stroke="#008000" stroke-width=".2"/>
<circle cx="90" cy="116.5" r=".28" fill="#fff" stroke="#000" stroke-width=".2"/>
<circle cx="98.9" cy="22.1" r=".49" fill="#008000" stroke="#008000" stroke-width=".2"/>
<circle cx="98.9" cy="22.1" r=".28" fill="#fff" stroke="#000" stroke-width=".2"/>
<circle cx="100.7" cy="25.7" r=".49" fill="#008000" stroke="#008000" stroke-width=".2"/>
<circle cx="100.7" cy="25.7" r=".28" fill="#fff" stroke="#000" stroke-width=".2"/>
<circle cx="49.8" cy="117.6" r=".49" fill="#008000" stroke="#008000" stroke-width=".2"/>
<circle cx="49.8" cy="117.6" r=".28" fill="#fff" stroke="#000" stroke-width=".2"/>
<circle cx="53.7" cy="116.8" r=".49" fill="#008000" stroke="#008000" stroke-width=".2"/>
<circle cx="53.7" cy="116.8" r=".28" fill="#fff" stroke="#000" stroke-width=".2"/>
<circle cx="121.1" cy="191.6" r=".49" fill="#008000" stroke="#008000" stroke-width=".2"/>
<circle cx="121.1" cy="191.6" r=".28" fill="#fff" stroke="#000" stroke-width=".2"/>
<circle cx="121.9" cy="187.6" r=".49" fill="#008000" stroke="#008000" stroke-width=".2"/>
<circle cx="121.9" cy="187.6" r=".28" fill="#fff" stroke="#000" stroke-width=".2"/>
<circle cx="97.3" cy="35.8" r=".49" fill="#008000" stroke="#008000" stroke-width=".2"/>
<circle cx="97.3" cy="35.8" r=".28" fill="#fff" stroke="#000" stroke-width=".2"/>
<circle cx="93.6" cy="29.9" r=".49" fill="#008000" stroke="#008000" stroke-width=".2"/>
<circle cx="93.6" cy="29.9" r=".28" fill="#fff" stroke="#000" stroke-width=".2"/>
<circle cx="66.2" cy="134.5" r=".49" fill="#008000" stroke="#008000" stroke-width=".2"/>
<circle cx="66.2" cy="134.5" r=".28" fill="#fff" stroke="#000" stroke-width=".2"/>
<circle cx="60.2" cy="138.4" r=".49" fill="#008000" stroke="#008000" stroke-width=".2"/>
<circle cx="60.2" cy="138.4" r=".28" fill="#fff" stroke="#000" stroke-width=".2"/>
<circle cx="83.1" cy="64.5" r=".49" fill="#008000" stroke="#008000" stroke-width=".2"/>
<circle cx="83.1" cy="64.5" r=".28" fill="#fff" stroke="#000" stroke-width=".2"/>
<circle cx="68.8" cy="52.6" r=".49" fill="#008000" stroke="#008000" stroke-width=".2"/>
<circle cx="68.8" cy="52.6" r=".28" fill="#fff" stroke="#000" stroke-width=".2"/>
<circle cx="105.3" cy="161.9" r=".49" fill="#008000" stroke="#008000" stroke-width=".2"/>
<circle cx="105.3" cy="161.9" r=".28" fill="#fff" stroke="#000" stroke-width=".2"/>
<circle cx="118.2" cy="143.7" r=".49" fill="#008000" stroke="#008000" stroke-width=".2"/>
<circle cx="118.2" cy="143.7" r=".28" fill="#fff" stroke="#000" stroke-width=".2"/>
<circle cx="108.7" cy="163.6" r=".49" fill="#008000" stroke="#008000" stroke-width=".2"/>
<circle cx="108.7" cy="163.6" r=".28" fill="#fff" stroke="#000" stroke-width=".2"/>
<circle cx="100.5" cy="180.4" r=".49" fill="#008000" stroke="#008000" stroke-width=".2"/>
<circle cx="100.5" cy="180.4" r=".28" fill="#fff" stroke="#000" stroke-width=".2"/>
<circle cx="82" cy="105.7" r=".49" fill="#008000" stroke="#008000" stroke-width=".2"/>
<circle cx="82" cy="105.7" r=".28" fill="#fff" stroke="#000" stroke-width=".2"/>
<circle cx="52.7" cy="105.7" r=".49" fill="#008000" stroke="#008000" stroke-width=".2"/>
<circle cx="52.7" cy="105.7" r=".28" fill="#fff" stroke="#000" stroke-width=".2"/>
<circle cx="124.1" cy="61.4" r=".49" fill="#008000" stroke="#008000" stroke-width=".2"/>
<circle cx="124.1" cy="61.4" r=".28" fill="#fff" stroke="#000" stroke-width=".2"/>
<circle cx="111" cy="21.4" r=".49" fill="#008000" stroke="#008000" stroke-width=".2"/>
<circle cx="111" cy="21.4" r=".28" fill="#fff" stroke="#000" stroke-width=".2"/>
<circle cx="124.7" cy="72" r=".49" fill="#008000" stroke="#008000" stroke-width=".2"/>
<circle cx="124.7" cy="72" r=".28" fill="#fff" stroke="#000" stroke-width=".2"/>
<circle cx="119.9" cy="61.7" r=".49" fill="#008000" stroke="#008000" stroke-width=".2"/>
<circle cx="119.9" cy="61.7" r=".28" fill="#fff" stroke="#000" stroke-width=".2"/>
<circle cx="132.5" cy="110" r=".49" fill="#008000" stroke="#008000" stroke-width=".2"/>
<circle cx="132.5" cy="110" r=".28" fill="#fff" stroke="#000" stroke-width=".2"/>
<circle cx="100.8" cy="137.8" r=".49" fill="#008000" stroke="#008000" stroke-width=".2"/>
<circle cx="100.8" cy="137.8" r=".28" fill="#fff" stroke="#000" stroke-width=".2"/>
<circle cx="113.2" cy="147.8" r=".49" fill="#008000" stroke="#008000" stroke-width=".2"/>
<circle cx="113.2" cy="147.8" r=".28" fill="#fff" stroke="#000" stroke-width=".2"/>
<circle cx="90.1" cy="120.2" r=".49" fill="#008000" stroke="#008000" stroke-width=".2"/>
<circle cx="90.1" cy="120.2" r=".28" fill="#fff" stroke="#000" stroke-width=".2"/>
<circle cx="57.7" cy="132" r=".49" fill="#008000" stroke="#008000" stroke-width=".2"/>
<circle cx="57.7" cy="132" r=".28" fill="#fff" stroke="#000" stroke-width=".2"/>
<circle cx="86.1" cy="29.8" r=".49" fill="#008000" stroke="#008000" stroke-width=".2"/>
<circle cx="86.1" cy="29.8" r=".28" fill="#fff" stroke="#000" stroke-width=".2"/>
<circle cx="88.9" cy="34.5" r=".49" fill="#008000" stroke="#008000" stroke-width=".2"/>
<circle cx="88.9" cy="34.5" r=".28" fill="#fff" stroke="#000" stroke-width=".2"/>
<circle cx="50.9" cy="123.8" r=".49" fill="#008000" stroke="#008000" stroke-width=".2"/>
<circle cx="50.9" cy="123.8" r=".28" fill="#fff" stroke="#000" stroke-width=".2"/>
<circle cx="56.3" cy="122.6" r=".49" fill="#008000" stroke="#008000" stroke-width=".2"/>
<circle cx="56.3" cy="122.6" r=".28" fill="#fff" stroke="#000" stroke-width=".2"/>
<circle cx="129.7" cy="193" r=".49" fill="#008000" stroke="#008000" stroke-width=".2"/>
<circle cx="129.7" cy="193" r=".28" fill="#fff" stroke="#000" stroke-width=".2"/>
<circle cx="130.2" cy="187.5" r=".49" fill="#008000" stroke="#008000" stroke-width=".2"/>
<circle cx="130.2" cy="187.5" r=".28" fill="#fff" stroke="#000" stroke-width=".2"/>
<circle cx="107.4" cy="30.5" r=".49" fill="#008000" stroke="#008000" stroke-width=".2"/>
<circle cx="107.4" cy="30.5" r=".28" fill="#fff" stroke="#000" stroke-width=".2"/>
<circle cx="104.5" cy="25.5" r=".49" fill="#008000" stroke="#008000" stroke-width=".2"/>
<circle cx="104.5" cy="25.5" r=".28" fill="#fff" stroke="#000" stroke-width=".2"/>
<circle cx="62.1" cy="122" r=".49" fill="#008000" stroke="#008000" stroke-width=".2"/>
<circle cx="62.1" cy="122" r=".28" fill="#fff" stroke="#000" stroke-width=".2"/>
<circle cx="76.7" cy="75.9" r=".49" fill="#008000" stroke="#008000" stroke-width=".2"/>
<circle cx="76.7" cy="75.9" r=".28" fill="#fff" stroke="#000" stroke-width=".2"/>
<circle cx="62.8" cy="65.5" r=".49" fill="#008000" stroke="#008000" stroke-width=".2"/>
<circle cx="62.8" cy="65.5" r=".28" fill="#fff" stroke="#000" stroke-width=".2"/>
<circle cx="119" cy="167.9" r=".49" fill="#008000" stroke="#008000" stroke-width=".2"/>
<circle cx="119" cy="167.9" r=".28" fill="#fff" stroke="#000" stroke-width=".2"/>
<circle cx="114" cy="184.2" r=".49" fill="#008000" stroke="#008000" stroke-width=".2"/>
<circle cx="114" cy="184.2" r=".28" fill="#fff" stroke="#000" stroke-width=".2"/>
<circle cx="82.8" cy="93.6" r=".49" fill="#008000" stroke="#008000" stroke-width=".2"/>
<circle cx="82.8" cy="93.6" r=".28" fill="#fff" stroke="#000" stroke-width=".2"/>
<circle cx="55.1" cy="89.5" r=".49" fill="#008000" stroke="#008000" stroke-width=".2"/>
<circle cx="55.1" cy="89.5" r=".28" fill="#fff" stroke="#000" stroke-width=".2"/>
<circle cx="118.2" cy="72.1" r=".49" fill="#008000" stroke="#008000" stroke-width=".2"/>
<circle cx="118.2" cy="72.1" r=".28" fill="#fff" stroke="#000" stroke-width=".2"/>
<circle cx="113.6" cy="65.1" r=".49" fill="#008000" stroke="#008000" stroke-width=".2"/>
<circle cx="113.6" cy="65.1" r=".28" fill="#fff" stroke="#000" stroke-width=".2"/>
<circle cx="137.6" cy="65.9" r=".49" fill="#008000" stroke="#008000" stroke-width=".2"/>
<circle cx="137.6" cy="65.9" r=".28" fill="#fff" stroke="#000" stroke-width=".2"/>
<circle cx="93.2" cy="31.6" r=".49" fill="#008000" stroke="#008000" stroke-width=".2"/>
<circle cx="93.2" cy="31.6" r=".28" fill="#fff" stroke="#000" stroke-width=".2"/>
<circle cx="134" cy="145.6" r=".49" fill="#008000" stroke="#008000" stroke-width=".2"/>
<circle cx="134" cy="145.6" r=".28" fill="#fff" stroke="#000" stroke-width=".2"/>
<circle cx="127" cy="102.7" r=".49" fill="#008000" stroke="#008000" stroke-width=".2"/>
<circle cx="127" cy="102.7" r=".28" fill="#fff" stroke="#000" stroke-width=".2"/>
<circle cx="55.1" cy="116.6" r=".49" fill="#008000" stroke="#008000" stroke-width=".2"/>
<circle cx="55.1" cy="116.6" r=".28" fill="#fff" stroke="#000" stroke-width=".2"/>
<circle cx="89.5" cy="114" r=".49" fill="#008000" stroke="#008000" stroke-width=".2"/>
<circle cx="89.5" cy="114" r=".28" fill="#fff" stroke="#000" stroke-width=".2"/>
<circle cx="79.3" cy="35.2" r=".49" fill="#008000" stroke="#008000" stroke-width=".2"/>
<circle cx="79.3" cy="35.2" r=".28" fill="#fff" stroke="#000" stroke-width=".2"/>
<circle cx="85.5" cy="42.2" r=".49" fill="#008000" stroke="#008000" stroke-width=".2"/>
<circle cx="85.5" cy="42.2" r=".28" fill="#fff" stroke="#000" stroke-width=".2"/>
<circle cx="55.5" cy="138" r=".49" fill="#008000" stroke="#008000" stroke-width=".2"/>
<circle cx="55.5" cy="138" r=".28" fill="#fff" stroke="#000" stroke-width=".2"/>
<circle cx="64.1" cy="134.5" r=".49" fill="#008000" stroke="#008000" stroke-width=".2"/>
<circle cx="64.1" cy="134.5" r=".28" fill="#fff" stroke="#000" stroke-width=".2"/>
<circle cx="119.4" cy="26.6" r=".49" fill="#008000" stroke="#008000" stroke-width=".2"/>
<circle cx="119.4" cy="26.6" r=".28" fill="#fff" stroke="#000" stroke-width=".2"/>
<circle cx="120.2" cy="23.8" r=".49" fill="#008000" stroke="#008000" stroke-width=".2"/>
<circle cx="120.2" cy="23.8" r=".28" fill="#fff" stroke="#000" stroke-width=".2"/>
<circle cx="60.2" cy="110.8" r=".49" fill="#008000" stroke="#008000" stroke-width=".2"/>
<circle cx="60.2" cy="110.8" r=".28" fill="#fff" stroke="#000" stroke-width=".2"/>
<circle cx="57.3" cy="111.1" r=".49" fill="#008000" stroke="#008000" stroke-width=".2"/>
<circle cx="57.3" cy="111.1" r=".28" fill="#fff" stroke="#000" stroke-width=".2"/>
<circle cx="127.3" cy="182.9" r=".49" fill="#008000" stroke="#008000" stroke-width=".2"/>
<circle cx="127.3" cy="182.9" r=".28" fill="#fff" stroke="#000" stroke-width=".2"/>
<circle cx="72.5" cy="89.7" r=".49" fill="#008000" stroke="#008000" stroke-width=".2"/>
<circle cx="72.5" cy="89.7" r=".28" fill="#fff" stroke="#000" stroke-width=".2"/>
<circle cx="58.8" cy="84.2" r=".49" fill="#008000" stroke="#008000" stroke-width=".2"/>
<circle cx="58.8" cy="84.2" r=".28" fill="#fff" stroke="#000" stroke-width=".2"/>
<circle cx="81.2" cy="91.4" r=".49" fill="#008000" stroke="#008000" stroke-width=".2"/>
<circle cx="81.2" cy="91.4" r=".28" fill="#fff" stroke="#000" stroke-width=".2"/>
<circle cx="85.9" cy="82.4" r=".49" fill="#008000" stroke="#008000" stroke-width=".2"/>
<circle cx="85.9" cy="82.4" r=".28" fill="#fff" stroke="#000" stroke-width=".2"/>
<circle cx="84" cy="81.9" r=".49" fill="#008000" stroke="#008000" stroke-width=".2"/>
<circle cx="84" cy="81.9" r=".28" fill="#fff" stroke="#000" stroke-width=".2"/>
<circle cx="105" cy="72.8" r=".49" fill="#008000" stroke="#008000" stroke-width=".2"/>
<circle cx="105" cy="72.8" r=".28" fill="#fff" stroke="#000" stroke-width=".2"/>
<circle cx="80.4" cy="44.9" r=".49" fill="#008000" stroke="#008000" stroke-width=".2"/>
<circle cx="80.4" cy="44.9" r=".28" fill="#fff" stroke="#000" stroke-width=".2"/>
<circle cx="141.5" cy="91.2" r=".49" fill="#008000" stroke="#008000" stroke-width=".2"/>
<circle cx="141.5" cy="91.2" r=".28" fill="#fff" stroke="#000" stroke-width=".2"/>
<circle cx="135.7" cy="91.5" r=".49" fill="#008000" stroke="#008000" stroke-width=".2"/>
<circle cx="135.7" cy="91.5" r=".28" fill="#fff" stroke="#000" stroke-width=".2"/>
<circle cx="132.7" cy="92.9" r=".49" fill="#008000" stroke="#008000" stroke-width=".2"/>
<circle cx="132.7" cy="92.9" r=".28" fill="#fff" stroke="#000" stroke-width=".2"/>
<circle cx="98" cy="32.7" r=".49" fill="#008000" stroke="#008000" stroke-width=".2"/>
<circle cx="98" cy="32.7" r=".28" fill="#fff" stroke="#000" stroke-width=".2"/>
<circle cx="122.8" cy="183" r=".49" fill="#008000" stroke="#008000" stroke-width=".2"/>
<circle cx="122.8" cy="183" r=".28" fill="#fff" stroke="#000" stroke-width=".2"/>
<circle cx="131.6" cy="140.7" r=".49" fill="#008000" stroke="#008000" stroke-width=".2"/>
<circle cx="131.6" cy="140.7" r=".28" fill="#fff" stroke="#000" stroke-width=".2"/>
<circle cx="88.4" cy="114.9" r=".49" fill="#008000" stroke="#008000" stroke-width=".2"/>
<circle cx="88.4" cy="114.9" r=".28" fill="#fff" stroke="#000" stroke-width=".2"/>
<circle cx="59.4" cy="123.8" r=".49" fill="#008000" stroke="#008000" stroke-width=".2"/>
<circle cx="59.4" cy="123.8" r=".28" fill="#fff" stroke="#000" stroke-width=".2"/>
<circle cx="68.9" cy="46" r=".49" fill="#008000" stroke="#008000" stroke-width=".2"/>
<circle cx="68.9" cy="46" r=".28" fill="#fff" stroke="#000" stroke-width=".2"/>
<circle cx="82" cy="56.4" r=".49" fill="#008000" stroke="#008000" stroke-width=".2"/>
<circle cx="82" cy="56.4" r=".28" fill="#fff" stroke="#000" stroke-width=".2"/>
<circle cx="62" cy="150.5" r=".49" fill="#008000" stroke="#008000" stroke-width=".2"/>
<circle cx="62" cy="150.5" r=".28" fill="#fff" stroke="#000" stroke-width=".2"/>
<circle cx="76.2" cy="141.5" r=".49" fill="#008000" stroke="#008000" stroke-width=".2"/>
<circle cx="76.2" cy="141.5" r=".28" fill="#fff" stroke="#000" stroke-width=".2"/>
<circle cx="144" cy="25.1" r=".49" fill="#008000" stroke="#008000" stroke-width=".2"/>
<circle cx="144" cy="25.1" r=".28" fill="#fff" stroke="#000" stroke-width=".2"/>
<circle cx="143.8" cy="29.1" r=".49" fill="#008000" stroke="#008000" stroke-width=".2"/>
<circle cx="143.8" cy="29.1" r=".28" fill="#fff" stroke="#000" stroke-width=".2"/>
<circle cx="59.9" cy="97.8" r=".49" fill="#008000" stroke="#008000" stroke-width=".2"/>
<circle cx="59.9" cy="97.8" r=".28" fill="#fff" stroke="#000" stroke-width=".2"/>
<circle cx="71.2" cy="100.1" r=".49" fill="#008000" stroke="#008000" stroke-width=".2"/>
<circle cx="71.2" cy="100.1" r=".28" fill="#fff" stroke="#000" stroke-width=".2"/>
<circle cx="118.4" cy="179.5" r=".49" fill="#008000" stroke="#008000" stroke-width=".2"/>
<circle cx="118.4" cy="179.5" r=".28" fill="#fff" stroke="#000" stroke-width=".2"/>
<circle cx="119.8" cy="174" r=".49" fill="#008000" stroke="#008000" stroke-width=".2"/>
<circle cx="119.8" cy="174" r=".28" fill="#fff" stroke="#000" stroke-width=".2"/>
<circle cx="92.7" cy="69.9" r=".49" fill="#008000" stroke="#008000" stroke-width=".2"/>
<circle cx="92.7" cy="69.9" r=".28" fill="#fff" stroke="#000" stroke-width=".2"/>
<circle cx="80.4" cy="58.6" r=".49" fill="#008000" stroke="#008000" stroke-width=".2"/>
<circle cx="80.4" cy="58.6" r=".28" fill="#fff" stroke="#000" stroke-width=".2"/>
<circle cx="129.3" cy="159.1" r=".49" fill="#008000" stroke="#008000" stroke-width=".2"/>
<circle cx="129.3" cy="159.1" r=".28" fill="#fff" stroke="#000" stroke-width=".2"/>
<circle cx="126.8" cy="175.6" r=".49" fill="#008000" stroke="#008000" stroke-width=".2"/>
<circle cx="126.8" cy="175.6" r=".28" fill="#fff" stroke="#000" stroke-width=".2"/>
<circle cx="98" cy="82.7" r=".49" fill="#008000" stroke="#008000" stroke-width=".2"/>
<circle cx="98" cy="82.7" r=".28" fill="#fff" stroke="#000" stroke-width=".2"/>
<circle cx="100.2" cy="73.7" r=".49" fill="#008000" stroke="#008000" stroke-width=".2"/>
<circle cx="100.2" cy="73.7" r=".28" fill="#fff" stroke="#000" stroke-width=".2"/>
<circle cx="109.3" cy="80.6" r=".49" fill="#008000" stroke="#008000" stroke-width=".2"/>
<circle cx="109.3" cy="80.6" r=".28" fill="#fff" stroke="#000" stroke-width=".2"/>
<circle cx="116.4" cy="74" r=".49" fill="#008000" stroke="#008000" stroke-width=".2"/>
<circle cx="116.4" cy="74" r=".28" fill="#fff" stroke="#000" stroke-width=".2"/>
<circle cx="124.4" cy="84.5" r=".49" fill="#008000" stroke="#008000" stroke-width=".2"/>
<circle cx="124.4" cy="84.5" r=".28" fill="#fff" stroke="#000" stroke-width=".2"/>
<circle cx="138.7" cy="100.7" r=".49" fill="#008000" stroke="#008000" stroke-width=".2"/>
<circle cx="138.7" cy="100.7" r=".28" fill="#fff" stroke="#000" stroke-width=".2"/>
<circle cx="120.2" cy="131.8" r=".49" fill="#008000" stroke="#008000" stroke-width=".2"/>
<circle cx="120.2" cy="131.8" r=".28" fill="#fff" stroke="#000" stroke-width=".2"/>
<circle cx="99.9" cy="165.4" r=".49" fill="#008000" stroke="#008000" stroke-width=".2"/>
<circle cx="99.9" cy="165.4" r=".28" fill="#fff" stroke="#000" stroke-width=".2"/>
<circle cx="87.4" cy="113.8" r=".49" fill="#008000" stroke="#008000" stroke-width=".2"/>
<circle cx="87.4" cy="113.8" r=".28" fill="#fff" stroke="#000" stroke-width=".2"/>
<circle cx="66.9" cy="118.4" r=".49" fill="#008000" stroke="#008000" stroke-width=".2"/>
<circle cx="66.9" cy="118.4" r=".28" fill="#fff" stroke="#000" stroke-width=".2"/>
<circle cx="65.5" cy="98.2" r=".49" fill="#008000" stroke="#008000" stroke-width=".2"/>
<circle cx="65.5" cy="98.2" r=".28" fill="#fff" stroke="#000" stroke-width=".2"/>
<circle cx="62.1" cy="55.6" r=".49" fill="#008000" stroke="#008000" stroke-width=".2"/>
<circle cx="62.1" cy="55.6" r=".28" fill="#fff" stroke="#000" stroke-width=".2"/>
<circle cx="77.6" cy="65" r=".49" fill="#008000" stroke="#008000" stroke-width=".2"/>
<circle cx="77.6" cy="65" r=".28" fill="#fff" stroke="#000" stroke-width=".2"/>
<circle cx="68.8" cy="160.2" r=".49" fill="#008000" stroke="#008000" stroke-width=".2"/>
<circle cx="68.8" cy="160.2" r=".28" fill="#fff" stroke="#000" stroke-width=".2"/>
<circle cx="62" cy="84.8" r=".49" fill="#008000" stroke="#008000" stroke-width=".2"/>
<circle cx="62" cy="84.8" r=".28" fill="#fff" stroke="#000" stroke-width=".2"/>
<circle cx="68.7" cy="86.4" r=".49" fill="#008000" stroke="#008000" stroke-width=".2"/>
<circle cx="68.7" cy="86.4" r=".28" fill="#fff" stroke="#000" stroke-width=".2"/>
<circle cx="108.9" cy="176.3" r=".49" fill="#008000" stroke="#008000" stroke-width=".2"/>
<circle cx="108.9" cy="176.3" r=".28" fill="#fff" stroke="#000" stroke-width=".2"/>
<circle cx="111.7" cy="169.4" r=".49" fill="#008000" stroke="#008000" stroke-width=".2"/>
<circle cx="111.7" cy="169.4" r=".28" fill="#fff" stroke="#000" stroke-width=".2"/>
<circle cx="138.8" cy="31.4" r=".49" fill="#008000" stroke="#008000" stroke-width=".2"/>
<circle cx="138.8" cy="31.4" r=".28" fill="#fff" stroke="#000" stroke-width=".2"/>
<circle cx="101.4" cy="60.2" r=".49" fill="#008000" stroke="#008000" stroke-width=".2"/>
<circle cx="101.4" cy="60.2" r=".28" fill="#fff" stroke="#000" stroke-width=".2"/>
<circle cx="91.5" cy="48.9" r=".49" fill="#008000" stroke="#008000" stroke-width=".2"/>
<circle cx="91.5" cy="48.9" r=".28" fill="#fff" stroke="#000" stroke-width=".2"/>
<circle cx="117.4" cy="155.7" r=".49" fill="#008000" stroke="#008000" stroke-width=".2"/>
<circle cx="117.4" cy="155.7" r=".28" fill="#fff" stroke="#000" stroke-width=".2"/>
<circle cx="96.2" cy="85.7" r=".49" fill="#008000" stroke="#008000" stroke-width=".2"/>
<circle cx="96.2" cy="85.7" r=".28" fill="#fff" stroke="#000" stroke-width=".2"/>
<circle cx="101.9" cy="88" r=".49" fill="#008000" stroke="#008000" stroke-width=".2"/>
<circle cx="101.9" cy="88" r=".28" fill="#fff" stroke="#000" stroke-width=".2"/>
<circle cx="104.3" cy="83.4" r=".49" fill="#008000" stroke="#008000" stroke-width=".2"/>
<circle cx="104.3" cy="83.4" r=".28" fill="#fff" stroke="#000" stroke-width=".2"/>
<circle cx="118.3" cy="91.5" r=".49" fill="#008000" stroke="#008000" stroke-width=".2"/>
<circle cx="118.3" cy="91.5" r=".28" fill="#fff" stroke="#000" stroke-width=".2"/>
<circle cx="111.4" cy="121.7" r=".49" fill="#008000" stroke="#008000" stroke-width=".2"/>
<circle cx="111.4" cy="121.7" r=".28" fill="#fff" stroke="#000" stroke-width=".2"/>
<circle cx="130.6" cy="120.5" r=".49" fill="#008000" stroke="#008000" stroke-width=".2"/>
<circle cx="130.6" cy="120.5" r=".28" fill="#fff" stroke="#000" stroke-width=".2"/>
<circle cx="124" cy="115.8" r=".49" fill="#008000" stroke="#008000" stroke-width=".2"/>
<circle cx="124" cy="115.8" r=".28" fill="#fff" stroke="#000" stroke-width=".2"/>
<circle cx="71.6" cy="111.7" r=".49" fill="#008000" stroke="#008000" stroke-width=".2"/>
<circle cx="71.6" cy="111.7" r=".28" fill="#fff" stroke="#000" stroke-width=".2"/>
<circle cx="67.5" cy="110" r=".49" fill="#008000" stroke="#008000" stroke-width=".2"/>
<circle cx="67.5" cy="110" r=".28" fill="#fff" stroke="#000" stroke-width=".2"/>
<circle cx="87.9" cy="116.1" r=".49" fill="#008000" stroke="#008000" stroke-width=".2"/>
<circle cx="87.9" cy="116.1" r=".28" fill="#fff" stroke="#000" stroke-width=".2"/>
<circle cx="69.2" cy="120.8" r=".49" fill="#008000" stroke="#008000" stroke-width=".2"/>
<circle cx="69.2" cy="120.8" r=".28" fill="#fff" stroke="#000" stroke-width=".2"/>
<circle cx="72.4" cy="76" r=".49" fill="#008000" stroke="#008000" stroke-width=".2"/>
<circle cx="72.4" cy="76" r=".28" fill="#fff" stroke="#000" stroke-width=".2"/>
<circle cx="83.2" cy="148.3" r=".49" fill="#008000" stroke="#008000" stroke-width=".2"/>
<circle cx="83.2" cy="148.3" r=".28" fill="#fff" stroke="#000" stroke-width=".2"/>
<circle cx="113" cy="98.3" r=".49" fill="#008000" stroke="#008000" stroke-width=".2"/>
<circle cx="113" cy="98.3" r=".28" fill="#fff" stroke="#000" stroke-width=".2"/>
<circle cx="90.2" cy="91.5" r=".49" fill="#008000" stroke="#008000" stroke-width=".2"/>
<circle cx="90.2" cy="91.5" r=".28" fill="#fff" stroke="#000" stroke-width=".2"/>
<circle cx="74.8" cy="167" r=".49" fill="#008000" stroke="#008000" stroke-width=".2"/>
<circle cx="74.8" cy="167" r=".28" fill="#fff" stroke="#000" stroke-width=".2"/>
<circle cx="105.1" cy="137.5" r=".49" fill="#008000" stroke="#008000" stroke-width=".2"/>
<circle cx="105.1" cy="137.5" r=".28" fill="#fff" stroke="#000" stroke-width=".2"/>
<circle cx="99.5" cy="143" r=".49" fill="#008000" stroke="#008000" stroke-width=".2"/>
<circle cx="99.5" cy="143" r=".28" fill="#fff" stroke="#000" stroke-width=".2"/>
<circle cx="85.9" cy="156.2" r=".49" fill="#008000" stroke="#008000" stroke-width=".2"/>
<circle cx="85.9" cy="156.2" r=".28" fill="#fff" stroke="#000" stroke-width=".2"/>
<circle cx="74.4" cy="124.5" r=".49" fill="#008000" stroke="#008000" stroke-width=".2"/>
<circle cx="74.4" cy="124.5" r=".28" fill="#fff" stroke="#000" stroke-width=".2"/>
<circle cx="93" cy="118.2" r=".49" fill="#008000" stroke="#008000" stroke-width=".2"/>
<circle cx="93" cy="118.2" r=".28" fill="#fff" stroke="#000" stroke-width=".2"/>
<circle cx="95.1" cy="82.6" r=".49" fill="#008000" stroke="#008000" stroke-width=".2"/>
<circle cx="95.1" cy="82.6" r=".28" fill="#fff" stroke="#000" stroke-width=".2"/>
<circle cx="56.6" cy="66" r=".49" fill="#008000" stroke="#008000" stroke-width=".2"/>
<circle cx="56.6" cy="66" r=".28" fill="#fff" stroke="#000" stroke-width=".2"/>
<circle cx="65.8" cy="72.9" r=".49" fill="#008000" stroke="#008000" stroke-width=".2"/>
<circle cx="65.8" cy="72.9" r=".28" fill="#fff" stroke="#000" stroke-width=".2"/>
<circle cx="117.4" cy="51.5" r=".49" fill="#008000" stroke="#008000" stroke-width=".2"/>
<circle cx="117.4" cy="51.5" r=".28" fill="#fff" stroke="#000" stroke-width=".2"/>
<circle cx="120.2" cy="58.5" r=".49" fill="#008000" stroke="#008000" stroke-width=".2"/>
<circle cx="120.2" cy="58.5" r=".28" fill="#fff" stroke="#000" stroke-width=".2"/>
<circle cx="123.2" cy="35.1" r=".49" fill="#008000" stroke="#008000" stroke-width=".2"/>
<circle cx="123.2" cy="35.1" r=".28" fill="#fff" stroke="#000" stroke-width=".2"/>
<circle cx="127" cy="52.4" r=".49" fill="#008000" stroke="#008000" stroke-width=".2"/>
<circle cx="127" cy="52.4" r=".28" fill="#fff" stroke="#000" stroke-width=".2"/>
<circle cx="118.9" cy="55.1" r=".49" fill="#008000" stroke="#008000" stroke-width=".2"/>
<circle cx="118.9" cy="55.1" r=".28" fill="#fff" stroke="#000" stroke-width=".2"/>
<circle cx="87" cy="120.2" r=".49" fill="#008000" stroke="#008000" stroke-width=".2"/>
<circle cx="87" cy="120.2" r=".28" fill="#fff" stroke="#000" stroke-width=".2"/>
<circle cx="130.5" cy="19.8" r=".49" fill="#008000" stroke="#008000" stroke-width=".2"/>
<circle cx="130.5" cy="19.8" r=".28" fill="#fff" stroke="#000" stroke-width=".2"/>
<circle cx="129.9" cy="14.3" r=".49" fill="#008000" stroke="#008000" stroke-width=".2"/>
<circle cx="129.9" cy="14.3" r=".28" fill="#fff" stroke="#000" stroke-width=".2"/>
<circle cx="120.8" cy="17.7" r=".49" fill="#008000" stroke="#008000" stroke-width=".2"/>
<circle cx="120.8" cy="17.7" r=".28" fill="#fff" stroke="#000" stroke-width=".2"/>
<circle cx="113" cy="23.3" r=".49" fill="#008000" stroke="#008000" stroke-width=".2"/>
<circle cx="113" cy="23.3" r=".28" fill="#fff" stroke="#000" stroke-width=".2"/>
<circle cx="118.7" cy="35.7" r=".49" fill="#008000" stroke="#008000" stroke-width=".2"/>
<circle cx="118.7" cy="35.7" r=".28" fill="#fff" stroke="#000" stroke-width=".2"/>
<circle cx="71.5" cy="82.7" r=".49" fill="#008000" stroke="#008000" stroke-width=".2"/>
<circle cx="71.5" cy="82.7" r=".28" fill="#fff" stroke="#000" stroke-width=".2"/>
<circle cx="52" cy="76.9" r=".49" fill="#008000" stroke="#008000" stroke-width=".2"/>
<circle cx="52" cy="76.9" r=".28" fill="#fff" stroke="#000" stroke-width=".2"/>
<circle cx="111" cy="24.2" r=".49" fill="#008000" stroke="#008000" stroke-width=".2"/>
<circle cx="111" cy="24.2" r=".28" fill="#fff" stroke="#000" stroke-width=".2"/>
<circle cx="117.4" cy="43.5" r=".49" fill="#008000" stroke="#008000" stroke-width=".2"/>
<circle cx="117.4" cy="43.5" r=".28" fill="#fff" stroke="#000" stroke-width=".2"/>
<circle cx="75.8" cy="95.2" r=".49" fill="#008000" stroke="#008000" stroke-width=".2"/>
<circle cx="75.8" cy="95.2" r=".28" fill="#fff" stroke="#000" stroke-width=".2"/>
<circle cx="50.3" cy="91.7" r=".49" fill="#008000" stroke="#008000" stroke-width=".2"/>
<circle cx="50.3" cy="91.7" r=".28" fill="#fff" stroke="#000" stroke-width=".2"/>
<circle cx="100.8" cy="28.5" r=".49" fill="#008000" stroke="#008000" stroke-width=".2"/>
<circle cx="100.8" cy="28.5" r=".28" fill="#fff" stroke="#000" stroke-width=".2"/>
<circle cx="51.1" cy="94.2" r=".49" fill="#008000" stroke="#008000" stroke-width=".2"/>
<circle cx="51.1" cy="94.2" r=".28" fill="#fff" stroke="#000" stroke-width=".2"/>
<circle cx="112.1" cy="48.7" r=".49" fill="#008000" stroke="#008000" stroke-width=".2"/>
<circle cx="112.1" cy="48.7" r=".28" fill="#fff" stroke="#000" stroke-width=".2"/>
<circle cx="76.5" cy="97.7" r=".49" fill="#008000" stroke="#008000" stroke-width=".2"/>
<circle cx="76.5" cy="97.7" r=".28" fill="#fff" stroke="#000" stroke-width=".2"/>
<circle cx="93.5" cy="182.3" r=".49" fill="#008000" stroke="#008000" stroke-width=".2"/>
<circle cx="93.5" cy="182.3" r=".28" fill="#fff" stroke="#000" stroke-width=".2"/>
<circle cx="98.1" cy="170.8" r=".49" fill="#008000" stroke="#008000" stroke-width=".2"/>
<circle cx="98.1" cy="170.8" r=".28" fill="#fff" stroke="#000" stroke-width=".2"/>
<circle cx="99.2" cy="29.3" r=".49" fill="#008000" stroke="#008000" stroke-width=".2"/>
<circle cx="99.2" cy="29.3" r=".28" fill="#fff" stroke="#000" stroke-width=".2"/>
<circle cx="131" cy="163.2" r=".49" fill="#008000" stroke="#008000" stroke-width=".2"/>
<circle cx="131" cy="163.2" r=".28" fill="#fff" stroke="#000" stroke-width=".2"/>
<circle cx="127.2" cy="194.1" r=".49" fill="#008000" stroke="#008000" stroke-width=".2"/>
<circle cx="127.2" cy="194.1" r=".28" fill="#fff" stroke="#000" stroke-width=".2"/>
<circle cx="110.6" cy="50" r=".49" fill="#008000" stroke="#008000" stroke-width=".2"/>
<circle cx="110.6" cy="50" r=".28" fill="#fff" stroke="#000" stroke-width=".2"/>
<circle cx="110.1" cy="175.6" r=".49" fill="#008000" stroke="#008000" stroke-width=".2"/>
<circle cx="110.1" cy="175.6" r=".28" fill="#fff" stroke="#000" stroke-width=".2"/>
<circle cx="107.7" cy="186.8" r=".49" fill="#008000" stroke="#008000" stroke-width=".2"/>
<circle cx="107.7" cy="186.8" r=".28" fill="#fff" stroke="#000" stroke-width=".2"/>
<circle cx="89.9" cy="35.8" r=".49" fill="#008000" stroke="#008000" stroke-width=".2"/>
<circle cx="89.9" cy="35.8" r=".28" fill="#fff" stroke="#000" stroke-width=".2"/>
<circle cx="84.7" cy="24.9" r=".49" fill="#008000" stroke="#008000" stroke-width=".2"/>
<circle cx="84.7" cy="24.9" r=".28" fill="#fff" stroke="#000" stroke-width=".2"/>
<circle cx="43.9" cy="97" r=".49" fill="#008000" stroke="#008000" stroke-width=".2"/>
<circle cx="43.9" cy="97" r=".28" fill="#fff" stroke="#000" stroke-width=".2"/>
<circle cx="55.3" cy="97.5" r=".49" fill="#008000" stroke="#008000" stroke-width=".2"/>
<circle cx="55.3" cy="97.5" r=".28" fill="#fff" stroke="#000" stroke-width=".2"/>
<circle cx="55.4" cy="111.4" r=".49" fill="#008000" stroke="#008000" stroke-width=".2"/>
<circle cx="55.4" cy="111.4" r=".28" fill="#fff" stroke="#000" stroke-width=".2"/>
<circle cx="44.2" cy="112.5" r=".49" fill="#008000" stroke="#008000" stroke-width=".2"/>
<circle cx="44.2" cy="112.5" r=".28" fill="#fff" stroke="#000" stroke-width=".2"/>
<circle cx="110.1" cy="187.6" r=".49" fill="#008000" stroke="#008000" stroke-width=".2"/>
<circle cx="110.1" cy="187.6" r=".28" fill="#fff" stroke="#000" stroke-width=".2"/>
<circle cx="108.2" cy="193.1" r=".49" fill="#008000" stroke="#008000" stroke-width=".2"/>
<circle cx="108.2" cy="193.1" r=".28" fill="#fff" stroke="#000" stroke-width=".2"/>
<circle cx="121.2" cy="177" r=".49" fill="#008000" stroke="#008000" stroke-width=".2"/>
<circle cx="121.2" cy="177" r=".28" fill="#fff" stroke="#000" stroke-width=".2"/>
<circle cx="118.7" cy="187.9" r=".49" fill="#008000" stroke="#008000" stroke-width=".2"/>
<circle cx="118.7" cy="187.9" r=".28" fill="#fff" stroke="#000" stroke-width=".2"/>
<circle cx="84.6" cy="39.4" r=".49" fill="#008000" stroke="#008000" stroke-width=".2"/>
<circle cx="84.6" cy="39.4" r=".28" fill="#fff" stroke="#000" stroke-width=".2"/>
<circle cx="101.6" cy="57.2" r=".49" fill="#008000" stroke="#008000" stroke-width=".2"/>
<circle cx="101.6" cy="57.2" r=".28" fill="#fff" stroke="#000" stroke-width=".2"/>
<circle cx="101.1" cy="148.8" r=".49" fill="#008000" stroke="#008000" stroke-width=".2"/>
<circle cx="101.1" cy="148.8" r=".28" fill="#fff" stroke="#000" stroke-width=".2"/>
<circle cx="81.8" cy="169.3" r=".49" fill="#008000" stroke="#008000" stroke-width=".2"/>
<circle cx="81.8" cy="169.3" r=".28" fill="#fff" stroke="#000" stroke-width=".2"/>
<circle cx="82.9" cy="40.8" r=".49" fill="#008000" stroke="#008000" stroke-width=".2"/>
<circle cx="82.9" cy="40.8" r=".28" fill="#fff" stroke="#000" stroke-width=".2"/>
<circle cx="76.7" cy="33.9" r=".49" fill="#008000" stroke="#008000" stroke-width=".2"/>
<circle cx="76.7" cy="33.9" r=".28" fill="#fff" stroke="#000" stroke-width=".2"/>
<circle cx="53.1" cy="67.2" r=".49" fill="#008000" stroke="#008000" stroke-width=".2"/>
<circle cx="53.1" cy="67.2" r=".28" fill="#fff" stroke="#000" stroke-width=".2"/>
<circle cx="63.4" cy="71.6" r=".49" fill="#008000" stroke="#008000" stroke-width=".2"/>
<circle cx="63.4" cy="71.6" r=".28" fill="#fff" stroke="#000" stroke-width=".2"/>
<circle cx="73.7" cy="65.7" r=".49" fill="#008000" stroke="#008000" stroke-width=".2"/>
<circle cx="73.7" cy="65.7" r=".28" fill="#fff" stroke="#000" stroke-width=".2"/>
<circle cx="84.5" cy="51.8" r=".49" fill="#008000" stroke="#008000" stroke-width=".2"/>
<circle cx="84.5" cy="51.8" r=".28" fill="#fff" stroke="#000" stroke-width=".2"/>
<circle cx="78.8" cy="44.6" r=".49" fill="#008000" stroke="#008000" stroke-width=".2"/>
<circle cx="78.8" cy="44.6" r=".28" fill="#fff" stroke="#000" stroke-width=".2"/>
<circle cx="70.4" cy="55.2" r=".49" fill="#008000" stroke="#008000" stroke-width=".2"/>
<circle cx="70.4" cy="55.2" r=".28" fill="#fff" stroke="#000" stroke-width=".2"/>
<circle cx="72.4" cy="66.1" r=".49" fill="#008000" stroke="#008000" stroke-width=".2"/>
<circle cx="72.4" cy="66.1" r=".28" fill="#fff" stroke="#000" stroke-width=".2"/>
<circle cx="75.6" cy="60.7" r=".49" fill="#008000" stroke="#008000" stroke-width=".2"/>
<circle cx="75.6" cy="60.7" r=".28" fill="#fff" stroke="#000" stroke-width=".2"/>
<circle cx="130.9" cy="23.5" r=".49" fill="#008000" stroke="#008000" stroke-width=".2"/>
<circle cx="130.9" cy="23.5" r=".28" fill="#fff" stroke="#000" stroke-width=".2"/>
<circle cx="132.1" cy="35.2" r=".49" fill="#008000" stroke="#008000" stroke-width=".2"/>
<circle cx="132.1" cy="35.2" r=".28" fill="#fff" stroke="#000" stroke-width=".2"/>
<circle cx="71.8" cy="56.2" r=".49" fill="#008000" stroke="#008000" stroke-width=".2"/>
<circle cx="71.8" cy="56.2" r=".28" fill="#fff" stroke="#000" stroke-width=".2"/>
<circle cx="132.3" cy="25.4" r=".49" fill="#008000" stroke="#008000" stroke-width=".2"/>
<circle cx="132.3" cy="25.4" r=".28" fill="#fff" stroke="#000" stroke-width=".2"/>
<circle cx="133.5" cy="36.6" r=".49" fill="#008000" stroke="#008000" stroke-width=".2"/>
<circle cx="133.5" cy="36.6" r=".28" fill="#fff" stroke="#000" stroke-width=".2"/>
<circle cx="66.8" cy="60.6" r=".49" fill="#008000" stroke="#008000" stroke-width=".2"/>
<circle cx="66.8" cy="60.6" r=".28" fill="#fff" stroke="#000" stroke-width=".2"/>
<circle cx="130.3" cy="39.1" r=".49" fill="#008000" stroke="#008000" stroke-width=".2"/>
<circle cx="130.3" cy="39.1" r=".28" fill="#fff" stroke="#000" stroke-width=".2"/>
<circle cx="129.1" cy="27.8" r=".49" fill="#008000" stroke="#008000" stroke-width=".2"/>
<circle cx="129.1" cy="27.8" r=".28" fill="#fff" stroke="#000" stroke-width=".2"/>
<circle cx="63.4" cy="66.8" r=".49" fill="#008000" stroke="#008000" stroke-width=".2"/>
<circle cx="63.4" cy="66.8" r=".28" fill="#fff" stroke="#000" stroke-width=".2"/>
<circle cx="71.5" cy="71.2" r=".49" fill="#008000" stroke="#008000" stroke-width=".2"/>
<circle cx="71.5" cy="71.2" r=".28" fill="#fff" stroke="#000" stroke-width=".2"/>
<circle cx="77.6" cy="60.6" r=".49" fill="#008000" stroke="#008000" stroke-width=".2"/>
<circle cx="77.6" cy="60.6" r=".28" fill="#fff" stroke="#000" stroke-width=".2"/>
<circle cx="115.8" cy="183.5" r=".49" fill="#008000" stroke="#008000" stroke-width=".2"/>
<circle cx="115.8" cy="183.5" r=".28" fill="#fff" stroke="#000" stroke-width=".2"/>
<circle cx="132.7" cy="123.7" r=".49" fill="#008000" stroke="#008000" stroke-width=".2"/>
<circle cx="132.7" cy="123.7" r=".28" fill="#fff" stroke="#000" stroke-width=".2"/>
<circle cx="119.4" cy="111.7" r=".49" fill="#008000" stroke="#008000" stroke-width=".2"/>
<circle cx="119.4" cy="111.7" r=".28" fill="#fff" stroke="#000" stroke-width=".2"/>
<circle cx="129.9" cy="103" r=".49" fill="#008000" stroke="#008000" stroke-width=".2"/>
<circle cx="129.9" cy="103" r=".28" fill="#fff" stroke="#000" stroke-width=".2"/>
<circle cx="59.1" cy="77.4" r=".49" fill="#008000" stroke="#008000" stroke-width=".2"/>
<circle cx="59.1" cy="77.4" r=".28" fill="#fff" stroke="#000" stroke-width=".2"/>
<circle cx="73.4" cy="82" r=".49" fill="#008000" stroke="#008000" stroke-width=".2"/>
<circle cx="73.4" cy="82" r=".28" fill="#fff" stroke="#000" stroke-width=".2"/>
<circle cx="57.3" cy="83.9" r=".49" fill="#008000" stroke="#008000" stroke-width=".2"/>
<circle cx="57.3" cy="83.9" r=".28" fill="#fff" stroke="#000" stroke-width=".2"/>
<circle cx="73.7" cy="88.5" r=".49" fill="#008000" stroke="#008000" stroke-width=".2"/>
<circle cx="73.7" cy="88.5" r=".28" fill="#fff" stroke="#000" stroke-width=".2"/>
<circle cx="56" cy="91" r=".49" fill="#008000" stroke="#008000" stroke-width=".2"/>
<circle cx="56" cy="91" r=".28" fill="#fff" stroke="#000" stroke-width=".2"/>
<circle cx="75" cy="93.7" r=".49" fill="#008000" stroke="#008000" stroke-width=".2"/>
<circle cx="75" cy="93.7" r=".28" fill="#fff" stroke="#000" stroke-width=".2"/>
<circle cx="106.3" cy="163" r=".49" fill="#008000" stroke="#008000" stroke-width=".2"/>
<circle cx="106.3" cy="163" r=".28" fill="#fff" stroke="#000" stroke-width=".2"/>
<circle cx="111.4" cy="153.4" r=".49" fill="#008000" stroke="#008000" stroke-width=".2"/>
<circle cx="111.4" cy="153.4" r=".28" fill="#fff" stroke="#000" stroke-width=".2"/>
<circle cx="57.4" cy="96.7" r=".49" fill="#008000" stroke="#008000" stroke-width=".2"/>
<circle cx="57.4" cy="96.7" r=".28" fill="#fff" stroke="#000" stroke-width=".2"/>
<circle cx="69.4" cy="97.4" r=".49" fill="#008000" stroke="#008000" stroke-width=".2"/>
<circle cx="69.4" cy="97.4" r=".28" fill="#fff" stroke="#000" stroke-width=".2"/>
<circle cx="75.8" cy="132.7" r=".49" fill="#008000" stroke="#008000" stroke-width=".2"/>
<circle cx="75.8" cy="132.7" r=".28" fill="#fff" stroke="#000" stroke-width=".2"/>
<circle cx="117.1" cy="166.1" r=".49" fill="#008000" stroke="#008000" stroke-width=".2"/>
<circle cx="117.1" cy="166.1" r=".28" fill="#fff" stroke="#000" stroke-width=".2"/>
<circle cx="120.6" cy="155.8" r=".49" fill="#008000" stroke="#008000" stroke-width=".2"/>
<circle cx="120.6" cy="155.8" r=".28" fill="#fff" stroke="#000" stroke-width=".2"/>
<circle cx="56.5" cy="98.3" r=".49" fill="#008000" stroke="#008000" stroke-width=".2"/>
<circle cx="56.5" cy="98.3" r=".28" fill="#fff" stroke="#000" stroke-width=".2"/>
<circle cx="68.3" cy="99.3" r=".49" fill="#008000" stroke="#008000" stroke-width=".2"/>
<circle cx="68.3" cy="99.3" r=".28" fill="#fff" stroke="#000" stroke-width=".2"/>
<circle cx="78.9" cy="140" r=".49" fill="#008000" stroke="#008000" stroke-width=".2"/>
<circle cx="78.9" cy="140" r=".28" fill="#fff" stroke="#000" stroke-width=".2"/>
<circle cx="81.9" cy="137.9" r=".49" fill="#008000" stroke="#008000" stroke-width=".2"/>
<circle cx="81.9" cy="137.9" r=".28" fill="#fff" stroke="#000" stroke-width=".2"/>
<circle cx="108.9" cy="147.5" r=".49" fill="#008000" stroke="#008000" stroke-width=".2"/>
<circle cx="108.9" cy="147.5" r=".28" fill="#fff" stroke="#000" stroke-width=".2"/>
<circle cx="102.8" cy="156.5" r=".49" fill="#008000" stroke="#008000" stroke-width=".2"/>
<circle cx="102.8" cy="156.5" r=".28" fill="#fff" stroke="#000" stroke-width=".2"/>
<circle cx="56.8" cy="109.7" r=".49" fill="#008000" stroke="#008000" stroke-width=".2"/>
<circle cx="56.8" cy="109.7" r=".28" fill="#fff" stroke="#000" stroke-width=".2"/>
<circle cx="64.3" cy="109.2" r=".49" fill="#008000" stroke="#008000" stroke-width=".2"/>
<circle cx="64.3" cy="109.2" r=".28" fill="#fff" stroke="#000" stroke-width=".2"/>
<circle cx="76.5" cy="144.5" r=".49" fill="#008000" stroke="#008000" stroke-width=".2"/>
<circle cx="76.5" cy="144.5" r=".28" fill="#fff" stroke="#000" stroke-width=".2"/>
<circle cx="85" cy="138.7" r=".49" fill="#008000" stroke="#008000" stroke-width=".2"/>
<circle cx="85" cy="138.7" r=".28" fill="#fff" stroke="#000" stroke-width=".2"/>
<circle cx="59.1" cy="128.9" r=".49" fill="#008000" stroke="#008000" stroke-width=".2"/>
<circle cx="59.1" cy="128.9" r=".28" fill="#fff" stroke="#000" stroke-width=".2"/>
<circle cx="87.4" cy="118.3" r=".49" fill="#008000" stroke="#008000" stroke-width=".2"/>
<circle cx="87.4" cy="118.3" r=".28" fill="#fff" stroke="#000" stroke-width=".2"/>
<circle cx="58.4" cy="117.6" r=".49" fill="#008000" stroke="#008000" stroke-width=".2"/>
<circle cx="58.4" cy="117.6" r=".28" fill="#fff" stroke="#000" stroke-width=".2"/>
<circle cx="83.8" cy="112.5" r=".49" fill="#008000" stroke="#008000" stroke-width=".2"/>
<circle cx="83.8" cy="112.5" r=".28" fill="#fff" stroke="#000" stroke-width=".2"/>
<circle cx="82" cy="109.8" r=".49" fill="#008000" stroke="#008000" stroke-width=".2"/>
<circle cx="82" cy="109.8" r=".28" fill="#fff" stroke="#000" stroke-width=".2"/>
<circle cx="56.9" cy="115.6" r=".49" fill="#008000" stroke="#008000" stroke-width=".2"/>
<circle cx="56.9" cy="115.6" r=".28" fill="#fff" stroke="#000" stroke-width=".2"/>
<circle cx="132.9" cy="56" r=".49" fill="#008000" stroke="#008000" stroke-width=".2"/>
<circle cx="132.9" cy="56" r=".28" fill="#fff" stroke="#000" stroke-width=".2"/>
<circle cx="131.7" cy="46.4" r=".49" fill="#008000" stroke="#008000" stroke-width=".2"/>
<circle cx="131.7" cy="46.4" r=".28" fill="#fff" stroke="#000" stroke-width=".2"/>
<circle cx="61.3" cy="134.6" r=".49" fill="#008000" stroke="#008000" stroke-width=".2"/>
<circle cx="61.3" cy="134.6" r=".28" fill="#fff" stroke="#000" stroke-width=".2"/>
<circle cx="80" cy="126.9" r=".49" fill="#008000" stroke="#008000" stroke-width=".2"/>
<circle cx="80" cy="126.9" r=".28" fill="#fff" stroke="#000" stroke-width=".2"/>
<circle cx="112.5" cy="46.5" r=".49" fill="#008000" stroke="#008000" stroke-width=".2"/>
<circle cx="112.5" cy="46.5" r=".28" fill="#fff" stroke="#000" stroke-width=".2"/>
<circle cx="119" cy="60.2" r=".49" fill="#008000" stroke="#008000" stroke-width=".2"/>
<circle cx="119" cy="60.2" r=".28" fill="#fff" stroke="#000" stroke-width=".2"/>
<circle cx="135.6" cy="58.8" r=".49" fill="#008000" stroke="#008000" stroke-width=".2"/>
<circle cx="135.6" cy="58.8" r=".28" fill="#fff" stroke="#000" stroke-width=".2"/>
<circle cx="134.6" cy="47.5" r=".49" fill="#008000" stroke="#008000" stroke-width=".2"/>
<circle cx="134.6" cy="47.5" r=".28" fill="#fff" stroke="#000" stroke-width=".2"/>
<circle cx="64.3" cy="141.3" r=".49" fill="#008000" stroke="#008000" stroke-width=".2"/>
<circle cx="64.3" cy="141.3" r=".28" fill="#fff" stroke="#000" stroke-width=".2"/>
<circle cx="83" cy="130.2" r=".49" fill="#008000" stroke="#008000" stroke-width=".2"/>
<circle cx="83" cy="130.2" r=".28" fill="#fff" stroke="#000" stroke-width=".2"/>
<circle cx="111.9" cy="50.6" r=".49" fill="#008000" stroke="#008000" stroke-width=".2"/>
<circle cx="111.9" cy="50.6" r=".28" fill="#fff" stroke="#000" stroke-width=".2"/>
<circle cx="119.1" cy="63.3" r=".49" fill="#008000" stroke="#008000" stroke-width=".2"/>
<circle cx="119.1" cy="63.3" r=".28" fill="#fff" stroke="#000" stroke-width=".2"/>
<circle cx="142" cy="59.6" r=".49" fill="#008000" stroke="#008000" stroke-width=".2"/>
<circle cx="142" cy="59.6" r=".28" fill="#fff" stroke="#000" stroke-width=".2"/>
<circle cx="142.6" cy="49.4" r=".49" fill="#008000" stroke="#008000" stroke-width=".2"/>
<circle cx="142.6" cy="49.4" r=".28" fill="#fff" stroke="#000" stroke-width=".2"/>
<circle cx="97.3" cy="75.2" r=".49" fill="#008000" stroke="#008000" stroke-width=".2"/>
<circle cx="97.3" cy="75.2" r=".28" fill="#fff" stroke="#000" stroke-width=".2"/>
<circle cx="103.7" cy="79.4" r=".49" fill="#008000" stroke="#008000" stroke-width=".2"/>
<circle cx="103.7" cy="79.4" r=".28" fill="#fff" stroke="#000" stroke-width=".2"/>
<circle cx="65.9" cy="142.1" r=".49" fill="#008000" stroke="#008000" stroke-width=".2"/>
<circle cx="65.9" cy="142.1" r=".28" fill="#fff" stroke="#000" stroke-width=".2"/>
<circle cx="94.9" cy="126.2" r=".49" fill="#008000" stroke="#008000" stroke-width=".2"/>
<circle cx="94.9" cy="126.2" r=".28" fill="#fff" stroke="#000" stroke-width=".2"/>
<circle cx="103.2" cy="133.2" r=".49" fill="#008000" stroke="#008000" stroke-width=".2"/>
<circle cx="103.2" cy="133.2" r=".28" fill="#fff" stroke="#000" stroke-width=".2"/>
<circle cx="110.2" cy="127.3" r=".49" fill="#008000" stroke="#008000" stroke-width=".2"/>
<circle cx="110.2" cy="127.3" r=".28" fill="#fff" stroke="#000" stroke-width=".2"/>
<circle cx="71.4" cy="151.4" r=".49" fill="#008000" stroke="#008000" stroke-width=".2"/>
<circle cx="71.4" cy="151.4" r=".28" fill="#fff" stroke="#000" stroke-width=".2"/>
<circle cx="100.8" cy="130.1" r=".49" fill="#008000" stroke="#008000" stroke-width=".2"/>
<circle cx="100.8" cy="130.1" r=".28" fill="#fff" stroke="#000" stroke-width=".2"/>
<circle cx="111.9" cy="138.7" r=".49" fill="#008000" stroke="#008000" stroke-width=".2"/>
<circle cx="111.9" cy="138.7" r=".28" fill="#fff" stroke="#000" stroke-width=".2"/>
<circle cx="120.1" cy="129.3" r=".49" fill="#008000" stroke="#008000" stroke-width=".2"/>
<circle cx="120.1" cy="129.3" r=".28" fill="#fff" stroke="#000" stroke-width=".2"/>
<circle cx="66" cy="161" r=".49" fill="#008000" stroke="#008000" stroke-width=".2"/>
<circle cx="66" cy="161" r=".28" fill="#fff" stroke="#000" stroke-width=".2"/>
<circle cx="82.7" cy="176.9" r=".49" fill="#008000" stroke="#008000" stroke-width=".2"/>
<circle cx="82.7" cy="176.9" r=".28" fill="#fff" stroke="#000" stroke-width=".2"/>
<circle cx="109.6" cy="132.9" r=".49" fill="#008000" stroke="#008000" stroke-width=".2"/>
<circle cx="109.6" cy="132.9" r=".28" fill="#fff" stroke="#000" stroke-width=".2"/>
<circle cx="118" cy="124.5" r=".49" fill="#008000" stroke="#008000" stroke-width=".2"/>
<circle cx="118" cy="124.5" r=".28" fill="#fff" stroke="#000" stroke-width=".2"/>
<circle cx="77.9" cy="157.5" r=".49" fill="#008000" stroke="#008000" stroke-width=".2"/>
<circle cx="77.9" cy="157.5" r=".28" fill="#fff" stroke="#000" stroke-width=".2"/>
<circle cx="104.6" cy="94.2" r=".49" fill="#008000" stroke="#008000" stroke-width=".2"/>
<circle cx="104.6" cy="94.2" r=".28" fill="#fff" stroke="#000" stroke-width=".2"/>
<circle cx="114.4" cy="96.8" r=".49" fill="#008000" stroke="#008000" stroke-width=".2"/>
<circle cx="114.4" cy="96.8" r=".28" fill="#fff" stroke="#000" stroke-width=".2"/>
<circle cx="84.9" cy="167" r=".49" fill="#008000" stroke="#008000" stroke-width=".2"/>
<circle cx="84.9" cy="167" r=".28" fill="#fff" stroke="#000" stroke-width=".2"/>
<circle cx="120.2" cy="123.4" r=".49" fill="#008000" stroke="#008000" stroke-width=".2"/>
<circle cx="120.2" cy="123.4" r=".28" fill="#fff" stroke="#000" stroke-width=".2"/>
<circle cx="118.2" cy="84.8" r=".49" fill="#008000" stroke="#008000" stroke-width=".2"/>
<circle cx="118.2" cy="84.8" r=".28" fill="#fff" stroke="#000" stroke-width=".2"/>
<circle cx="108.2" cy="90.7" r=".49" fill="#008000" stroke="#008000" stroke-width=".2"/>
<circle cx="108.2" cy="90.7" r=".28" fill="#fff" stroke="#000" stroke-width=".2"/>
<circle cx="117.9" cy="94.7" r=".49" fill="#008000" stroke="#008000" stroke-width=".2"/>
<circle cx="117.9" cy="94.7" r=".28" fill="#fff" stroke="#000" stroke-width=".2"/>
<circle cx="89.8" cy="171" r=".49" fill="#008000" stroke="#008000" stroke-width=".2"/>
<circle cx="89.8" cy="171" r=".28" fill="#fff" stroke="#000" stroke-width=".2"/>
<circle cx="121.9" cy="126.4" r=".49" fill="#008000" stroke="#008000" stroke-width=".2"/>
<circle cx="121.9" cy="126.4" r=".28" fill="#fff" stroke="#000" stroke-width=".2"/>
<circle cx="131.7" cy="81.7" r=".49" fill="#008000" stroke="#008000" stroke-width=".2"/>
<circle cx="131.7" cy="81.7" r=".28" fill="#fff" stroke="#000" stroke-width=".2"/>
<circle cx="129.7" cy="75.6" r=".49" fill="#008000" stroke="#008000" stroke-width=".2"/>
<circle cx="129.7" cy="75.6" r=".28" fill="#fff" stroke="#000" stroke-width=".2"/>
<circle cx="114.2" cy="84.5" r=".49" fill="#008000" stroke="#008000" stroke-width=".2"/>
<circle cx="114.2" cy="84.5" r=".28" fill="#fff" stroke="#000" stroke-width=".2"/>
<circle cx="123.1" cy="91.3" r=".49" fill="#008000" stroke="#008000" stroke-width=".2"/>
<circle cx="123.1" cy="91.3" r=".28" fill="#fff" stroke="#000" stroke-width=".2"/>
<circle cx="101.6" cy="176" r=".49" fill="#008000" stroke="#008000" stroke-width=".2"/>
<circle cx="101.6" cy="176" r=".28" fill="#fff" stroke="#000" stroke-width=".2"/>
<circle cx="123.8" cy="125.3" r=".49" fill="#008000" stroke="#008000" stroke-width=".2"/>
<circle cx="123.8" cy="125.3" r=".28" fill="#fff" stroke="#000" stroke-width=".2"/>
<circle cx="112.9" cy="99.5" r=".49" fill="#008000" stroke="#008000" stroke-width=".2"/>
<circle cx="112.9" cy="99.5" r=".28" fill="#fff" stroke="#000" stroke-width=".2"/>
<circle cx="108.6" cy="98.8" r=".49" fill="#008000" stroke="#008000" stroke-width=".2"/>
<circle cx="108.6" cy="98.8" r=".28" fill="#fff" stroke="#000" stroke-width=".2"/>
<circle cx="94.8" cy="174.1" r=".49" fill="#008000" stroke="#008000" stroke-width=".2"/>
<circle cx="94.8" cy="174.1" r=".28" fill="#fff" stroke="#000" stroke-width=".2"/>
<circle cx="123.7" cy="123.6" r=".49" fill="#008000" stroke="#008000" stroke-width=".2"/>
<circle cx="123.7" cy="123.6" r=".28" fill="#fff" stroke="#000" stroke-width=".2"/>
<circle cx="131" cy="113.3" r=".49" fill="#008000" stroke="#008000" stroke-width=".2"/>
<circle cx="131" cy="113.3" r=".28" fill="#fff" stroke="#000" stroke-width=".2"/>
<circle cx="106.3" cy="180.1" r=".49" fill="#008000" stroke="#008000" stroke-width=".2"/>
<circle cx="106.3" cy="180.1" r=".28" fill="#fff" stroke="#000" stroke-width=".2"/>
<circle cx="124.1" cy="118.8" r=".49" fill="#008000" stroke="#008000" stroke-width=".2"/>
<circle cx="124.1" cy="118.8" r=".28" fill="#fff" stroke="#000" stroke-width=".2"/>
<circle cx="118.7" cy="110.7" r=".49" fill="#008000" stroke="#008000" stroke-width=".2"/>
<circle cx="118.7" cy="110.7" r=".28" fill="#fff" stroke="#000" stroke-width=".2"/>
<circle cx="128" cy="101.3" r=".49" fill="#008000" stroke="#008000" stroke-width=".2"/>
<circle cx="128" cy="101.3" r=".28" fill="#fff" stroke="#000" stroke-width=".2"/>
<circle cx="221.2" cy="140.2" r=".49" fill="#008000" stroke="#008000" stroke-width=".2"/>
<circle cx="221.2" cy="140.2" r=".28" fill="#fff" stroke="#000" stroke-width=".2"/>
<circle cx="211.5" cy="134.2" r=".49" fill="#008000" stroke="#008000" stroke-width=".2"/>
<circle cx="211.5" cy="134.2" r=".28" fill="#fff" stroke="#000" stroke-width=".2"/>
<circle cx="195.9" cy="129" r=".49" fill="#008000" stroke="#008000" stroke-width=".2"/>
<circle cx="195.9" cy="129" r=".28" fill="#fff" stroke="#000" stroke-width=".2"/>
<circle cx="202.7" cy="39.3" r=".49" fill="#008000" stroke="#008000" stroke-width=".2"/>
<circle cx="202.7" cy="39.3" r=".28" fill="#fff" stroke="#000" stroke-width=".2"/>
<circle cx="183.1" cy="58.8" r=".49" fill="#008000" stroke="#008000" stroke-width=".2"/>
<circle cx="183.1" cy="58.8" r=".28" fill="#fff" stroke="#000" stroke-width=".2"/>
<circle cx="180.4" cy="35.9" r=".49" fill="#008000" stroke="#008000" stroke-width=".2"/>
<circle cx="180.4" cy="35.9" r=".28" fill="#fff" stroke="#000" stroke-width=".2"/>
<circle cx="177.8" cy="39.7" r=".49" fill="#008000" stroke="#008000" stroke-width=".2"/>
<circle cx="177.8" cy="39.7" r=".28" fill="#fff" stroke="#000" stroke-width=".2"/>
<circle cx="191.6" cy="50.4" r=".49" fill="#008000" stroke="#008000" stroke-width=".2"/>
<circle cx="191.6" cy="50.4" r=".28" fill="#fff" stroke="#000" stroke-width=".2"/>
<circle cx="154.2" cy="169" r=".49" fill="#008000" stroke="#008000" stroke-width=".2"/>
<circle cx="154.2" cy="169" r=".28" fill="#fff" stroke="#000" stroke-width=".2"/>
<circle cx="198.4" cy="83.7" r=".49" fill="#008000" stroke="#008000" stroke-width=".2"/>
<circle cx="198.4" cy="83.7" r=".28" fill="#fff" stroke="#000" stroke-width=".2"/>
<circle cx="166.4" cy="152.8" r=".49" fill="#008000" stroke="#008000" stroke-width=".2"/>
<circle cx="166.4" cy="152.8" r=".28" fill="#fff" stroke="#000" stroke-width=".2"/>
<circle cx="168.3" cy="158.3" r=".49" fill="#008000" stroke="#008000" stroke-width=".2"/>
<circle cx="168.3" cy="158.3" r=".28" fill="#fff" stroke="#000" stroke-width=".2"/>
<circle cx="179.3" cy="55.4" r=".49" fill="#008000" stroke="#008000" stroke-width=".2"/>
<circle cx="179.3" cy="55.4" r=".28" fill="#fff" stroke="#000" stroke-width=".2"/>
<circle cx="190.8" cy="95.6" r=".49" fill="#008000" stroke="#008000" stroke-width=".2"/>
<circle cx="190.8" cy="95.6" r=".28" fill="#fff" stroke="#000" stroke-width=".2"/>
<circle cx="201" cy="95.9" r=".49" fill="#008000" stroke="#008000" stroke-width=".2"/>
<circle cx="201" cy="95.9" r=".28" fill="#fff" stroke="#000" stroke-width=".2"/>
<circle cx="214.7" cy="152.1" r=".49" fill="#008000" stroke="#008000" stroke-width=".2"/>
<circle cx="214.7" cy="152.1" r=".28" fill="#fff" stroke="#000" stroke-width=".2"/>
<circle cx="198.3" cy="143" r=".49" fill="#008000" stroke="#008000" stroke-width=".2"/>
<circle cx="198.3" cy="143" r=".28" fill="#fff" stroke="#000" stroke-width=".2"/>
<circle cx="210.5" cy="48.2" r=".49" fill="#008000" stroke="#008000" stroke-width=".2"/>
<circle cx="210.5" cy="48.2" r=".28" fill="#fff" stroke="#000" stroke-width=".2"/>
<circle cx="195.7" cy="59.5" r=".49" fill="#008000" stroke="#008000" stroke-width=".2"/>
<circle cx="195.7" cy="59.5" r=".28" fill="#fff" stroke="#000" stroke-width=".2"/>
<circle cx="215.7" cy="121.3" r=".49" fill="#008000" stroke="#008000" stroke-width=".2"/>
<circle cx="215.7" cy="121.3" r=".28" fill="#fff" stroke="#000" stroke-width=".2"/>
<circle cx="169.1" cy="30.2" r=".49" fill="#008000" stroke="#008000" stroke-width=".2"/>
<circle cx="169.1" cy="30.2" r=".28" fill="#fff" stroke="#000" stroke-width=".2"/>
<circle cx="166.3" cy="36.8" r=".49" fill="#008000" stroke="#008000" stroke-width=".2"/>
<circle cx="166.3" cy="36.8" r=".28" fill="#fff" stroke="#000" stroke-width=".2"/>
<circle cx="142" cy="173.2" r=".49" fill="#008000" stroke="#008000" stroke-width=".2"/>
<circle cx="142" cy="173.2" r=".28" fill="#fff" stroke="#000" stroke-width=".2"/>
<circle cx="177.5" cy="144.6" r=".49" fill="#008000" stroke="#008000" stroke-width=".2"/>
<circle cx="177.5" cy="144.6" r=".28" fill="#fff" stroke="#000" stroke-width=".2"/>
<circle cx="186" cy="157.2" r=".49" fill="#008000" stroke="#008000" stroke-width=".2"/>
<circle cx="186" cy="157.2" r=".28" fill="#fff" stroke="#000" stroke-width=".2"/>
<circle cx="160.6" cy="50.6" r=".49" fill="#008000" stroke="#008000" stroke-width=".2"/>
<circle cx="160.6" cy="50.6" r=".28" fill="#fff" stroke="#000" stroke-width=".2"/>
<circle cx="182.6" cy="118" r=".49" fill="#008000" stroke="#008000" stroke-width=".2"/>
<circle cx="182.6" cy="118" r=".28" fill="#fff" stroke="#000" stroke-width=".2"/>
<circle cx="161.2" cy="110.9" r=".49" fill="#008000" stroke="#008000" stroke-width=".2"/>
<circle cx="161.2" cy="110.9" r=".28" fill="#fff" stroke="#000" stroke-width=".2"/>
<circle cx="167.2" cy="84" r=".49" fill="#008000" stroke="#008000" stroke-width=".2"/>
<circle cx="167.2" cy="84" r=".28" fill="#fff" stroke="#000" stroke-width=".2"/>
<circle cx="160.1" cy="86.8" r=".49" fill="#008000" stroke="#008000" stroke-width=".2"/>
<circle cx="160.1" cy="86.8" r=".28" fill="#fff" stroke="#000" stroke-width=".2"/>
<circle cx="149.4" cy="77.7" r=".49" fill="#008000" stroke="#008000" stroke-width=".2"/>
<circle cx="149.4" cy="77.7" r=".28" fill="#fff" stroke="#000" stroke-width=".2"/>
<circle cx="210" cy="94.4" r=".49" fill="#008000" stroke="#008000" stroke-width=".2"/>
<circle cx="210" cy="94.4" r=".28" fill="#fff" stroke="#000" stroke-width=".2"/>
<circle cx="205.9" cy="93.9" r=".49" fill="#008000" stroke="#008000" stroke-width=".2"/>
<circle cx="205.9" cy="93.9" r=".28" fill="#fff" stroke="#000" stroke-width=".2"/>
<circle cx="190.7" cy="93.4" r=".49" fill="#008000" stroke="#008000" stroke-width=".2"/>
<circle cx="190.7" cy="93.4" r=".28" fill="#fff" stroke="#000" stroke-width=".2"/>
<circle cx="208.4" cy="119.6" r=".49" fill="#008000" stroke="#008000" stroke-width=".2"/>
<circle cx="208.4" cy="119.6" r=".28" fill="#fff" stroke="#000" stroke-width=".2"/>
<circle cx="206.7" cy="126.2" r=".49" fill="#008000" stroke="#008000" stroke-width=".2"/>
<circle cx="206.7" cy="126.2" r=".28" fill="#fff" stroke="#000" stroke-width=".2"/>
<circle cx="206.7" cy="162.7" r=".49" fill="#008000" stroke="#008000" stroke-width=".2"/>
<circle cx="206.7" cy="162.7" r=".28" fill="#fff" stroke="#000" stroke-width=".2"/>
<circle cx="193.9" cy="151.7" r=".49" fill="#008000" stroke="#008000" stroke-width=".2"/>
<circle cx="193.9" cy="151.7" r=".28" fill="#fff" stroke="#000" stroke-width=".2"/>
<circle cx="217.7" cy="59" r=".49" fill="#008000" stroke="#008000" stroke-width=".2"/>
<circle cx="217.7" cy="59" r=".28" fill="#fff" stroke="#000" stroke-width=".2"/>
<circle cx="203.6" cy="68.4" r=".49" fill="#008000" stroke="#008000" stroke-width=".2"/>
<circle cx="203.6" cy="68.4" r=".28" fill="#fff" stroke="#000" stroke-width=".2"/>
<circle cx="136.3" cy="176.7" r=".49" fill="#008000" stroke="#008000" stroke-width=".2"/>
<circle cx="136.3" cy="176.7" r=".28" fill="#fff" stroke="#000" stroke-width=".2"/>
<circle cx="217.6" cy="108.3" r=".49" fill="#008000" stroke="#008000" stroke-width=".2"/>
<circle cx="217.6" cy="108.3" r=".28" fill="#fff" stroke="#000" stroke-width=".2"/>
<circle cx="206.5" cy="106.3" r=".49" fill="#008000" stroke="#008000" stroke-width=".2"/>
<circle cx="206.5" cy="106.3" r=".28" fill="#fff" stroke="#000" stroke-width=".2"/>
<circle cx="212.1" cy="108" r=".49" fill="#008000" stroke="#008000" stroke-width=".2"/>
<circle cx="212.1" cy="108" r=".28" fill="#fff" stroke="#000" stroke-width=".2"/>
<circle cx="157.9" cy="26.4" r=".49" fill="#008000" stroke="#008000" stroke-width=".2"/>
<circle cx="157.9" cy="26.4" r=".28" fill="#fff" stroke="#000" stroke-width=".2"/>
<circle cx="157.8" cy="32.1" r=".49" fill="#008000" stroke="#008000" stroke-width=".2"/>
<circle cx="157.8" cy="32.1" r=".28" fill="#fff" stroke="#000" stroke-width=".2"/>
<circle cx="188.8" cy="130.2" r=".49" fill="#008000" stroke="#008000" stroke-width=".2"/>
<circle cx="188.8" cy="130.2" r=".28" fill="#fff" stroke="#000" stroke-width=".2"/>
<circle cx="179.9" cy="123.2" r=".49" fill="#008000" stroke="#008000" stroke-width=".2"/>
<circle cx="179.9" cy="123.2" r=".28" fill="#fff" stroke="#000" stroke-width=".2"/>
<circle cx="203.2" cy="137.8" r=".49" fill="#008000" stroke="#008000" stroke-width=".2"/>
<circle cx="203.2" cy="137.8" r=".28" fill="#fff" stroke="#000" stroke-width=".2"/>
<circle cx="143.9" cy="46.9" r=".49" fill="#008000" stroke="#008000" stroke-width=".2"/>
<circle cx="143.9" cy="46.9" r=".28" fill="#fff" stroke="#000" stroke-width=".2"/>
<circle cx="146.3" cy="30.1" r=".49" fill="#008000" stroke="#008000" stroke-width=".2"/>
<circle cx="146.3" cy="30.1" r=".28" fill="#fff" stroke="#000" stroke-width=".2"/>
<circle cx="151.8" cy="122.9" r=".49" fill="#008000" stroke="#008000" stroke-width=".2"/>
<circle cx="151.8" cy="122.9" r=".28" fill="#fff" stroke="#000" stroke-width=".2"/>
<circle cx="149.1" cy="118.4" r=".49" fill="#008000" stroke="#008000" stroke-width=".2"/>
<circle cx="149.1" cy="118.4" r=".28" fill="#fff" stroke="#000" stroke-width=".2"/>
<circle cx="158.5" cy="103.1" r=".49" fill="#008000" stroke="#008000" stroke-width=".2"/>
<circle cx="158.5" cy="103.1" r=".28" fill="#fff" stroke="#000" stroke-width=".2"/>
<circle cx="212" cy="103.1" r=".49" fill="#008000" stroke="#008000" stroke-width=".2"/>
<circle cx="212" cy="103.1" r=".28" fill="#fff" stroke="#000" stroke-width=".2"/>
<circle cx="158.8" cy="75.2" r=".49" fill="#008000" stroke="#008000" stroke-width=".2"/>
<circle cx="158.8" cy="75.2" r=".28" fill="#fff" stroke="#000" stroke-width=".2"/>
<circle cx="183.5" cy="44.9" r=".49" fill="#008000" stroke="#008000" stroke-width=".2"/>
<circle cx="183.5" cy="44.9" r=".28" fill="#fff" stroke="#000" stroke-width=".2"/>
<circle cx="188.9" cy="87" r=".49" fill="#008000" stroke="#008000" stroke-width=".2"/>
<circle cx="188.9" cy="87" r=".28" fill="#fff" stroke="#000" stroke-width=".2"/>
<circle cx="157.1" cy="97" r=".49" fill="#008000" stroke="#008000" stroke-width=".2"/>
<circle cx="157.1" cy="97" r=".28" fill="#fff" stroke="#000" stroke-width=".2"/>
<circle cx="198.4" cy="171" r=".49" fill="#008000" stroke="#008000" stroke-width=".2"/>
<circle cx="198.4" cy="171" r=".28" fill="#fff" stroke="#000" stroke-width=".2"/>
<circle cx="192.2" cy="164.1" r=".49" fill="#008000" stroke="#008000" stroke-width=".2"/>
<circle cx="192.2" cy="164.1" r=".28" fill="#fff" stroke="#000" stroke-width=".2"/>
<circle cx="222.3" cy="68.6" r=".49" fill="#008000" stroke="#008000" stroke-width=".2"/>
<circle cx="222.3" cy="68.6" r=".28" fill="#fff" stroke="#000" stroke-width=".2"/>
<circle cx="213.8" cy="72.1" r=".49" fill="#008000" stroke="#008000" stroke-width=".2"/>
<circle cx="213.8" cy="72.1" r=".28" fill="#fff" stroke="#000" stroke-width=".2"/>
<circle cx="156.8" cy="180.1" r=".49" fill="#008000" stroke="#008000" stroke-width=".2"/>
<circle cx="156.8" cy="180.1" r=".28" fill="#fff" stroke="#000" stroke-width=".2"/>
<circle cx="157.5" cy="183" r=".49" fill="#008000" stroke="#008000" stroke-width=".2"/>
<circle cx="157.5" cy="183" r=".28" fill="#fff" stroke="#000" stroke-width=".2"/>
<circle cx="217.5" cy="96.5" r=".49" fill="#008000" stroke="#008000" stroke-width=".2"/>
<circle cx="217.5" cy="96.5" r=".28" fill="#fff" stroke="#000" stroke-width=".2"/>
<circle cx="219.9" cy="97.8" r=".49" fill="#008000" stroke="#008000" stroke-width=".2"/>
<circle cx="219.9" cy="97.8" r=".28" fill="#fff" stroke="#000" stroke-width=".2"/>
<circle cx="150.3" cy="23.2" r=".49" fill="#008000" stroke="#008000" stroke-width=".2"/>
<circle cx="150.3" cy="23.2" r=".28" fill="#fff" stroke="#000" stroke-width=".2"/>
<circle cx="205.2" cy="116.5" r=".49" fill="#008000" stroke="#008000" stroke-width=".2"/>
<circle cx="205.2" cy="116.5" r=".28" fill="#fff" stroke="#000" stroke-width=".2"/>
<circle cx="219.3" cy="117.2" r=".49" fill="#008000" stroke="#008000" stroke-width=".2"/>
<circle cx="219.3" cy="117.2" r=".28" fill="#fff" stroke="#000" stroke-width=".2"/>
<circle cx="147.4" cy="37.7" r=".49" fill="#008000" stroke="#008000" stroke-width=".2"/>
<circle cx="147.4" cy="37.7" r=".28" fill="#fff" stroke="#000" stroke-width=".2"/>
<circle cx="193.4" cy="118.9" r=".49" fill="#008000" stroke="#008000" stroke-width=".2"/>
<circle cx="193.4" cy="118.9" r=".28" fill="#fff" stroke="#000" stroke-width=".2"/>
<circle cx="204.5" cy="119.2" r=".49" fill="#008000" stroke="#008000" stroke-width=".2"/>
<circle cx="204.5" cy="119.2" r=".28" fill="#fff" stroke="#000" stroke-width=".2"/>
<circle cx="175.3" cy="130.9" r=".49" fill="#008000" stroke="#008000" stroke-width=".2"/>
<circle cx="175.3" cy="130.9" r=".28" fill="#fff" stroke="#000" stroke-width=".2"/>
<circle cx="203.5" cy="152.5" r=".49" fill="#008000" stroke="#008000" stroke-width=".2"/>
<circle cx="203.5" cy="152.5" r=".28" fill="#fff" stroke="#000" stroke-width=".2"/>
<circle cx="135" cy="141.3" r=".49" fill="#008000" stroke="#008000" stroke-width=".2"/>
<circle cx="135" cy="141.3" r=".28" fill="#fff" stroke="#000" stroke-width=".2"/>
<circle cx="141.9" cy="69.2" r=".49" fill="#008000" stroke="#008000" stroke-width=".2"/>
<circle cx="141.9" cy="69.2" r=".28" fill="#fff" stroke="#000" stroke-width=".2"/>
<circle cx="169.3" cy="126.3" r=".49" fill="#008000" stroke="#008000" stroke-width=".2"/>
<circle cx="169.3" cy="126.3" r=".28" fill="#fff" stroke="#000" stroke-width=".2"/>
<circle cx="186.6" cy="82.6" r=".49" fill="#008000" stroke="#008000" stroke-width=".2"/>
<circle cx="186.6" cy="82.6" r=".28" fill="#fff" stroke="#000" stroke-width=".2"/>
<circle cx="146.5" cy="125.5" r=".49" fill="#008000" stroke="#008000" stroke-width=".2"/>
<circle cx="146.5" cy="125.5" r=".28" fill="#fff" stroke="#000" stroke-width=".2"/>
<circle cx="143.5" cy="114" r=".49" fill="#008000" stroke="#008000" stroke-width=".2"/>
<circle cx="143.5" cy="114" r=".28" fill="#fff" stroke="#000" stroke-width=".2"/>
<circle cx="171.4" cy="83" r=".49" fill="#008000" stroke="#008000" stroke-width=".2"/>
<circle cx="171.4" cy="83" r=".28" fill="#fff" stroke="#000" stroke-width=".2"/>
<circle cx="188.1" cy="178.8" r=".49" fill="#008000" stroke="#008000" stroke-width=".2"/>
<circle cx="188.1" cy="178.8" r=".28" fill="#fff" stroke="#000" stroke-width=".2"/>
<circle cx="183.4" cy="175.2" r=".49" fill="#008000" stroke="#008000" stroke-width=".2"/>
<circle cx="183.4" cy="175.2" r=".28" fill="#fff" stroke="#000" stroke-width=".2"/>
<circle cx="226.7" cy="82.4" r=".49" fill="#008000" stroke="#008000" stroke-width=".2"/>
<circle cx="226.7" cy="82.4" r=".28" fill="#fff" stroke="#000" stroke-width=".2"/>
<circle cx="221.4" cy="83.7" r=".49" fill="#008000" stroke="#008000" stroke-width=".2"/>
<circle cx="221.4" cy="83.7" r=".28" fill="#fff" stroke="#000" stroke-width=".2"/>
<circle cx="144.7" cy="13" r=".49" fill="#008000" stroke="#008000" stroke-width=".2"/>
<circle cx="144.7" cy="13" r=".28" fill="#fff" stroke="#000" stroke-width=".2"/>
<circle cx="144.3" cy="18.5" r=".49" fill="#008000" stroke="#008000" stroke-width=".2"/>
<circle cx="144.3" cy="18.5" r=".28" fill="#fff" stroke="#000" stroke-width=".2"/>
<circle cx="169.3" cy="176" r=".49" fill="#008000" stroke="#008000" stroke-width=".2"/>
<circle cx="169.3" cy="176" r=".28" fill="#fff" stroke="#000" stroke-width=".2"/>
<circle cx="171.5" cy="181.4" r=".49" fill="#008000" stroke="#008000" stroke-width=".2"/>
<circle cx="171.5" cy="181.4" r=".28" fill="#fff" stroke="#000" stroke-width=".2"/>
<circle cx="215.7" cy="85.2" r=".49" fill="#008000" stroke="#008000" stroke-width=".2"/>
<circle cx="215.7" cy="85.2" r=".28" fill="#fff" stroke="#000" stroke-width=".2"/>
<circle cx="201.4" cy="128.9" r=".49" fill="#008000" stroke="#008000" stroke-width=".2"/>
<circle cx="201.4" cy="128.9" r=".28" fill="#fff" stroke="#000" stroke-width=".2"/>
<circle cx="217.1" cy="135.4" r=".49" fill="#008000" stroke="#008000" stroke-width=".2"/>
<circle cx="217.1" cy="135.4" r=".28" fill="#fff" stroke="#000" stroke-width=".2"/>
<circle cx="160.7" cy="38.9" r=".49" fill="#008000" stroke="#008000" stroke-width=".2"/>
<circle cx="160.7" cy="38.9" r=".28" fill="#fff" stroke="#000" stroke-width=".2"/>
<circle cx="194.8" cy="112.5" r=".49" fill="#008000" stroke="#008000" stroke-width=".2"/>
<circle cx="194.8" cy="112.5" r=".28" fill="#fff" stroke="#000" stroke-width=".2"/>
<circle cx="222.5" cy="116.5" r=".49" fill="#008000" stroke="#008000" stroke-width=".2"/>
<circle cx="222.5" cy="116.5" r=".28" fill="#fff" stroke="#000" stroke-width=".2"/>
<circle cx="166.7" cy="139.1" r=".49" fill="#008000" stroke="#008000" stroke-width=".2"/>
<circle cx="166.7" cy="139.1" r=".28" fill="#fff" stroke="#000" stroke-width=".2"/>
<circle cx="147" cy="54" r=".49" fill="#008000" stroke="#008000" stroke-width=".2"/>
<circle cx="147" cy="54" r=".28" fill="#fff" stroke="#000" stroke-width=".2"/>
<circle cx="157.4" cy="20.3" r=".49" fill="#008000" stroke="#008000" stroke-width=".2"/>
<circle cx="157.4" cy="20.3" r=".28" fill="#fff" stroke="#000" stroke-width=".2"/>
<circle cx="149.9" cy="117.2" r=".49" fill="#008000" stroke="#008000" stroke-width=".2"/>
<circle cx="149.9" cy="117.2" r=".28" fill="#fff" stroke="#000" stroke-width=".2"/>
<circle cx="150.6" cy="103.1" r=".49" fill="#008000" stroke="#008000" stroke-width=".2"/>
<circle cx="150.6" cy="103.1" r=".28" fill="#fff" stroke="#000" stroke-width=".2"/>
<circle cx="156.7" cy="103.1" r=".49" fill="#008000" stroke="#008000" stroke-width=".2"/>
<circle cx="156.7" cy="103.1" r=".28" fill="#fff" stroke="#000" stroke-width=".2"/>
<circle cx="163.5" cy="134.9" r=".49" fill="#008000" stroke="#008000" stroke-width=".2"/>
<circle cx="163.5" cy="134.9" r=".28" fill="#fff" stroke="#000" stroke-width=".2"/>
<circle cx="137" cy="142.2" r=".49" fill="#008000" stroke="#008000" stroke-width=".2"/>
<circle cx="137" cy="142.2" r=".28" fill="#fff" stroke="#000" stroke-width=".2"/>
<circle cx="186.4" cy="81.1" r=".49" fill="#008000" stroke="#008000" stroke-width=".2"/>
<circle cx="186.4" cy="81.1" r=".28" fill="#fff" stroke="#000" stroke-width=".2"/>
<circle cx="137" cy="139.1" r=".49" fill="#008000" stroke="#008000" stroke-width=".2"/>
<circle cx="137" cy="139.1" r=".28" fill="#fff" stroke="#000" stroke-width=".2"/>
<circle cx="219.4" cy="76.6" r=".49" fill="#008000" stroke="#008000" stroke-width=".2"/>
<circle cx="219.4" cy="76.6" r=".28" fill="#fff" stroke="#000" stroke-width=".2"/>
<circle cx="165.6" cy="22.6" r=".49" fill="#008000" stroke="#008000" stroke-width=".2"/>
<circle cx="165.6" cy="22.6" r=".28" fill="#fff" stroke="#000" stroke-width=".2"/>
<circle cx="189.3" cy="171.3" r=".49" fill="#008000" stroke="#008000" stroke-width=".2"/>
<circle cx="189.3" cy="171.3" r=".28" fill="#fff" stroke="#000" stroke-width=".2"/>
<circle cx="178.8" cy="184.1" r=".49" fill="#008000" stroke="#008000" stroke-width=".2"/>
<circle cx="178.8" cy="184.1" r=".28" fill="#fff" stroke="#000" stroke-width=".2"/>
<circle cx="176.8" cy="180.3" r=".49" fill="#008000" stroke="#008000" stroke-width=".2"/>
<circle cx="176.8" cy="180.3" r=".28" fill="#fff" stroke="#000" stroke-width=".2"/>
<circle cx="228.7" cy="94" r=".49" fill="#008000" stroke="#008000" stroke-width=".2"/>
<circle cx="228.7" cy="94" r=".28" fill="#fff" stroke="#000" stroke-width=".2"/>
<circle cx="224.5" cy="94.5" r=".49" fill="#008000" stroke="#008000" stroke-width=".2"/>
<circle cx="224.5" cy="94.5" r=".28" fill="#fff" stroke="#000" stroke-width=".2"/>
<circle cx="156.4" cy="14.5" r=".49" fill="#008000" stroke="#008000" stroke-width=".2"/>
<circle cx="156.4" cy="14.5" r=".28" fill="#fff" stroke="#000" stroke-width=".2"/>
<circle cx="155.7" cy="18.6" r=".49" fill="#008000" stroke="#008000" stroke-width=".2"/>
<circle cx="155.7" cy="18.6" r=".28" fill="#fff" stroke="#000" stroke-width=".2"/>
<circle cx="179.7" cy="170.7" r=".49" fill="#008000" stroke="#008000" stroke-width=".2"/>
<circle cx="179.7" cy="170.7" r=".28" fill="#fff" stroke="#000" stroke-width=".2"/>
<circle cx="182.1" cy="177.6" r=".49" fill="#008000" stroke="#008000" stroke-width=".2"/>
<circle cx="182.1" cy="177.6" r=".28" fill="#fff" stroke="#000" stroke-width=".2"/>
<circle cx="211.8" cy="72.9" r=".49" fill="#008000" stroke="#008000" stroke-width=".2"/>
<circle cx="211.8" cy="72.9" r=".28" fill="#fff" stroke="#000" stroke-width=".2"/>
<circle cx="219.4" cy="72.6" r=".49" fill="#008000" stroke="#008000" stroke-width=".2"/>
<circle cx="219.4" cy="72.6" r=".28" fill="#fff" stroke="#000" stroke-width=".2"/>
<circle cx="194.5" cy="141.7" r=".49" fill="#008000" stroke="#008000" stroke-width=".2"/>
<circle cx="194.5" cy="141.7" r=".28" fill="#fff" stroke="#000" stroke-width=".2"/>
<circle cx="208.7" cy="153.4" r=".49" fill="#008000" stroke="#008000" stroke-width=".2"/>
<circle cx="208.7" cy="153.4" r=".28" fill="#fff" stroke="#000" stroke-width=".2"/>
<circle cx="171.1" cy="43.4" r=".49" fill="#008000" stroke="#008000" stroke-width=".2"/>
<circle cx="171.1" cy="43.4" r=".28" fill="#fff" stroke="#000" stroke-width=".2"/>
<circle cx="179.6" cy="27.2" r=".49" fill="#008000" stroke="#008000" stroke-width=".2"/>
<circle cx="179.6" cy="27.2" r=".28" fill="#fff" stroke="#000" stroke-width=".2"/>
<circle cx="195.6" cy="100.4" r=".49" fill="#008000" stroke="#008000" stroke-width=".2"/>
<circle cx="195.6" cy="100.4" r=".28" fill="#fff" stroke="#000" stroke-width=".2"/>
<circle cx="225" cy="103.1" r=".49" fill="#008000" stroke="#008000" stroke-width=".2"/>
<circle cx="225" cy="103.1" r=".28" fill="#fff" stroke="#000" stroke-width=".2"/>
<circle cx="157.8" cy="131.8" r=".49" fill="#008000" stroke="#008000" stroke-width=".2"/>
<circle cx="157.8" cy="131.8" r=".28" fill="#fff" stroke="#000" stroke-width=".2"/>
<circle cx="156.7" cy="145.5" r=".49" fill="#008000" stroke="#008000" stroke-width=".2"/>
<circle cx="156.7" cy="145.5" r=".28" fill="#fff" stroke="#000" stroke-width=".2"/>
<circle cx="159.2" cy="62.2" r=".49" fill="#008000" stroke="#008000" stroke-width=".2"/>
<circle cx="159.2" cy="62.2" r=".28" fill="#fff" stroke="#000" stroke-width=".2"/>
<circle cx="144.5" cy="92.3" r=".49" fill="#008000" stroke="#008000" stroke-width=".2"/>
<circle cx="144.5" cy="92.3" r=".28" fill="#fff" stroke="#000" stroke-width=".2"/>
<circle cx="185.9" cy="79.9" r=".49" fill="#008000" stroke="#008000" stroke-width=".2"/>
<circle cx="185.9" cy="79.9" r=".28" fill="#fff" stroke="#000" stroke-width=".2"/>
<circle cx="215.6" cy="64.1" r=".49" fill="#008000" stroke="#008000" stroke-width=".2"/>
<circle cx="215.6" cy="64.1" r=".28" fill="#fff" stroke="#000" stroke-width=".2"/>
<circle cx="165.7" cy="184.6" r=".49" fill="#008000" stroke="#008000" stroke-width=".2"/>
<circle cx="165.7" cy="184.6" r=".28" fill="#fff" stroke="#000" stroke-width=".2"/>
<circle cx="166.4" cy="189.1" r=".49" fill="#008000" stroke="#008000" stroke-width=".2"/>
<circle cx="166.4" cy="189.1" r=".28" fill="#fff" stroke="#000" stroke-width=".2"/>
<circle cx="168.2" cy="194.5" r=".49" fill="#008000" stroke="#008000" stroke-width=".2"/>
<circle cx="168.2" cy="194.5" r=".28" fill="#fff" stroke="#000" stroke-width=".2"/>
<circle cx="229.1" cy="103.1" r=".49" fill="#008000" stroke="#008000" stroke-width=".2"/>
<circle cx="229.1" cy="103.1" r=".28" fill="#fff" stroke="#000" stroke-width=".2"/>
<circle cx="234.9" cy="103.1" r=".49" fill="#008000" stroke="#008000" stroke-width=".2"/>
<circle cx="234.9" cy="103.1" r=".28" fill="#fff" stroke="#000" stroke-width=".2"/>
<circle cx="167.8" cy="17.5" r=".49" fill="#008000" stroke="#008000" stroke-width=".2"/>
<circle cx="167.8" cy="17.5" r=".28" fill="#fff" stroke="#000" stroke-width=".2"/>
<circle cx="169.6" cy="12.1" r=".49" fill="#008000" stroke="#008000" stroke-width=".2"/>
<circle cx="169.6" cy="12.1" r=".28" fill="#fff" stroke="#000" stroke-width=".2"/>
<circle cx="189.1" cy="163.9" r=".49" fill="#008000" stroke="#008000" stroke-width=".2"/>
<circle cx="189.1" cy="163.9" r=".28" fill="#fff" stroke="#000" stroke-width=".2"/>
<circle cx="199.6" cy="177.5" r=".49" fill="#008000" stroke="#008000" stroke-width=".2"/>
<circle cx="199.6" cy="177.5" r=".28" fill="#fff" stroke="#000" stroke-width=".2"/>
<circle cx="206.1" cy="61.5" r=".49" fill="#008000" stroke="#008000" stroke-width=".2"/>
<circle cx="206.1" cy="61.5" r=".28" fill="#fff" stroke="#000" stroke-width=".2"/>
<circle cx="220.5" cy="52.5" r=".49" fill="#008000" stroke="#008000" stroke-width=".2"/>
<circle cx="220.5" cy="52.5" r=".28" fill="#fff" stroke="#000" stroke-width=".2"/>
<circle cx="186.6" cy="151" r=".49" fill="#008000" stroke="#008000" stroke-width=".2"/>
<circle cx="186.6" cy="151" r=".28" fill="#fff" stroke="#000" stroke-width=".2"/>
<circle cx="181.8" cy="50.7" r=".49" fill="#008000" stroke="#008000" stroke-width=".2"/>
<circle cx="181.8" cy="50.7" r=".28" fill="#fff" stroke="#000" stroke-width=".2"/>
<circle cx="167.8" cy="67.9" r=".49" fill="#008000" stroke="#008000" stroke-width=".2"/>
<circle cx="167.8" cy="67.9" r=".28" fill="#fff" stroke="#000" stroke-width=".2"/>
<circle cx="199.5" cy="28.6" r=".49" fill="#008000" stroke="#008000" stroke-width=".2"/>
<circle cx="199.5" cy="28.6" r=".28" fill="#fff" stroke="#000" stroke-width=".2"/>
<circle cx="193.5" cy="87.3" r=".49" fill="#008000" stroke="#008000" stroke-width=".2"/>
<circle cx="193.5" cy="87.3" r=".28" fill="#fff" stroke="#000" stroke-width=".2"/>
<circle cx="231.6" cy="78.2" r=".49" fill="#008000" stroke="#008000" stroke-width=".2"/>
<circle cx="231.6" cy="78.2" r=".28" fill="#fff" stroke="#000" stroke-width=".2"/>
<circle cx="187.3" cy="90.1" r=".49" fill="#008000" stroke="#008000" stroke-width=".2"/>
<circle cx="187.3" cy="90.1" r=".28" fill="#fff" stroke="#000" stroke-width=".2"/>
<circle cx="136.3" cy="143.2" r=".49" fill="#008000" stroke="#008000" stroke-width=".2"/>
<circle cx="136.3" cy="143.2" r=".28" fill="#fff" stroke="#000" stroke-width=".2"/>
<circle cx="133.5" cy="199.1" r=".49" fill="#008000" stroke="#008000" stroke-width=".2"/>
<circle cx="133.5" cy="199.1" r=".28" fill="#fff" stroke="#000" stroke-width=".2"/>
<circle cx="164.5" cy="125.8" r=".49" fill="#008000" stroke="#008000" stroke-width=".2"/>
<circle cx="164.5" cy="125.8" r=".28" fill="#fff" stroke="#000" stroke-width=".2"/>
<circle cx="157.9" cy="120.3" r=".49" fill="#008000" stroke="#008000" stroke-width=".2"/>
<circle cx="157.9" cy="120.3" r=".28" fill="#fff" stroke="#000" stroke-width=".2"/>
<circle cx="133.9" cy="143.1" r=".49" fill="#008000" stroke="#008000" stroke-width=".2"/>
<circle cx="133.9" cy="143.1" r=".28" fill="#fff" stroke="#000" stroke-width=".2"/>
<circle cx="137.6" cy="128.5" r=".49" fill="#008000" stroke="#008000" stroke-width=".2"/>
<circle cx="137.6" cy="128.5" r=".28" fill="#fff" stroke="#000" stroke-width=".2"/>
<circle cx="154.7" cy="98.7" r=".49" fill="#008000" stroke="#008000" stroke-width=".2"/>
<circle cx="154.7" cy="98.7" r=".28" fill="#fff" stroke="#000" stroke-width=".2"/>
<circle cx="154.9" cy="191.9" r=".49" fill="#008000" stroke="#008000" stroke-width=".2"/>
<circle cx="154.9" cy="191.9" r=".28" fill="#fff" stroke="#000" stroke-width=".2"/>
<circle cx="155.6" cy="195.3" r=".49" fill="#008000" stroke="#008000" stroke-width=".2"/>
<circle cx="155.6" cy="195.3" r=".28" fill="#fff" stroke="#000" stroke-width=".2"/>
<circle cx="227.7" cy="118.9" r=".49" fill="#008000" stroke="#008000" stroke-width=".2"/>
<circle cx="227.7" cy="118.9" r=".28" fill="#fff" stroke="#000" stroke-width=".2"/>
<circle cx="231.1" cy="119.5" r=".49" fill="#008000" stroke="#008000" stroke-width=".2"/>
<circle cx="231.1" cy="119.5" r=".28" fill="#fff" stroke="#000" stroke-width=".2"/>
<circle cx="181.5" cy="23.5" r=".49" fill="#008000" stroke="#008000" stroke-width=".2"/>
<circle cx="181.5" cy="23.5" r=".28" fill="#fff" stroke="#000" stroke-width=".2"/>
<circle cx="183.1" cy="20.5" r=".49" fill="#008000" stroke="#008000" stroke-width=".2"/>
<circle cx="183.1" cy="20.5" r=".28" fill="#fff" stroke="#000" stroke-width=".2"/>
<circle cx="198.8" cy="154.6" r=".49" fill="#008000" stroke="#008000" stroke-width=".2"/>
<circle cx="198.8" cy="154.6" r=".28" fill="#fff" stroke="#000" stroke-width=".2"/>
<circle cx="199.1" cy="51.9" r=".49" fill="#008000" stroke="#008000" stroke-width=".2"/>
<circle cx="199.1" cy="51.9" r=".28" fill="#fff" stroke="#000" stroke-width=".2"/>
<circle cx="191.4" cy="60.3" r=".49" fill="#008000" stroke="#008000" stroke-width=".2"/>
<circle cx="191.4" cy="60.3" r=".28" fill="#fff" stroke="#000" stroke-width=".2"/>
<circle cx="211.3" cy="43.7" r=".49" fill="#008000" stroke="#008000" stroke-width=".2"/>
<circle cx="211.3" cy="43.7" r=".28" fill="#fff" stroke="#000" stroke-width=".2"/>
<circle cx="178.2" cy="158.2" r=".49" fill="#008000" stroke="#008000" stroke-width=".2"/>
<circle cx="178.2" cy="158.2" r=".28" fill="#fff" stroke="#000" stroke-width=".2"/>
<circle cx="173" cy="150.9" r=".49" fill="#008000" stroke="#008000" stroke-width=".2"/>
<circle cx="173" cy="150.9" r=".28" fill="#fff" stroke="#000" stroke-width=".2"/>
<circle cx="188" cy="74.7" r=".49" fill="#008000" stroke="#008000" stroke-width=".2"/>
<circle cx="188" cy="74.7" r=".28" fill="#fff" stroke="#000" stroke-width=".2"/>
<circle cx="176.9" cy="77.8" r=".49" fill="#008000" stroke="#008000" stroke-width=".2"/>
<circle cx="176.9" cy="77.8" r=".28" fill="#fff" stroke="#000" stroke-width=".2"/>
<circle cx="170.6" cy="116.2" r=".49" fill="#008000" stroke="#008000" stroke-width=".2"/>
<circle cx="170.6" cy="116.2" r=".28" fill="#fff" stroke="#000" stroke-width=".2"/>
<circle cx="226.2" cy="136.2" r=".49" fill="#008000" stroke="#008000" stroke-width=".2"/>
<circle cx="226.2" cy="136.2" r=".28" fill="#fff" stroke="#000" stroke-width=".2"/>
<circle cx="154.2" cy="85.2" r=".49" fill="#008000" stroke="#008000" stroke-width=".2"/>
<circle cx="154.2" cy="85.2" r=".28" fill="#fff" stroke="#000" stroke-width=".2"/>
<circle cx="156.6" cy="79.7" r=".49" fill="#008000" stroke="#008000" stroke-width=".2"/>
<circle cx="156.6" cy="79.7" r=".28" fill="#fff" stroke="#000" stroke-width=".2"/>
<circle cx="163.5" cy="86.9" r=".49" fill="#008000" stroke="#008000" stroke-width=".2"/>
<circle cx="163.5" cy="86.9" r=".28" fill="#fff" stroke="#000" stroke-width=".2"/>
<circle cx="220.1" cy="56.2" r=".49" fill="#008000" stroke="#008000" stroke-width=".2"/>
<circle cx="220.1" cy="56.2" r=".28" fill="#fff" stroke="#000" stroke-width=".2"/>
<circle cx="166.5" cy="69.5" r=".49" fill="#008000" stroke="#008000" stroke-width=".2"/>
<circle cx="166.5" cy="69.5" r=".28" fill="#fff" stroke="#000" stroke-width=".2"/>
<circle cx="211.1" cy="162.8" r=".49" fill="#008000" stroke="#008000" stroke-width=".2"/>
<circle cx="211.1" cy="162.8" r=".28" fill="#fff" stroke="#000" stroke-width=".2"/>
<circle cx="193.5" cy="179.2" r=".49" fill="#008000" stroke="#008000" stroke-width=".2"/>
<circle cx="193.5" cy="179.2" r=".28" fill="#fff" stroke="#000" stroke-width=".2"/>
<circle cx="183.5" cy="141.4" r=".49" fill="#008000" stroke="#008000" stroke-width=".2"/>
<circle cx="183.5" cy="141.4" r=".28" fill="#fff" stroke="#000" stroke-width=".2"/>
<circle cx="182.4" cy="88.9" r=".49" fill="#008000" stroke="#008000" stroke-width=".2"/>
<circle cx="182.4" cy="88.9" r=".28" fill="#fff" stroke="#000" stroke-width=".2"/>
<circle cx="161.1" cy="95.4" r=".49" fill="#008000" stroke="#008000" stroke-width=".2"/>
<circle cx="161.1" cy="95.4" r=".28" fill="#fff" stroke="#000" stroke-width=".2"/>
<circle cx="134.1" cy="192.8" r=".49" fill="#008000" stroke="#008000" stroke-width=".2"/>
<circle cx="134.1" cy="192.8" r=".28" fill="#fff" stroke="#000" stroke-width=".2"/>
<circle cx="134.1" cy="194.9" r=".49" fill="#008000" stroke="#008000" stroke-width=".2"/>
<circle cx="134.1" cy="194.9" r=".28" fill="#fff" stroke="#000" stroke-width=".2"/>
<circle cx="224.5" cy="136.5" r=".49" fill="#008000" stroke="#008000" stroke-width=".2"/>
<circle cx="224.5" cy="136.5" r=".28" fill="#fff" stroke="#000" stroke-width=".2"/>
<circle cx="205.2" cy="144.3" r=".49" fill="#008000" stroke="#008000" stroke-width=".2"/>
<circle cx="205.2" cy="144.3" r=".28" fill="#fff" stroke="#000" stroke-width=".2"/>
<circle cx="217.3" cy="151.7" r=".49" fill="#008000" stroke="#008000" stroke-width=".2"/>
<circle cx="217.3" cy="151.7" r=".28" fill="#fff" stroke="#000" stroke-width=".2"/>
<circle cx="189.8" cy="42.8" r=".49" fill="#008000" stroke="#008000" stroke-width=".2"/>
<circle cx="189.8" cy="42.8" r=".28" fill="#fff" stroke="#000" stroke-width=".2"/>
<circle cx="197.7" cy="35.9" r=".49" fill="#008000" stroke="#008000" stroke-width=".2"/>
<circle cx="197.7" cy="35.9" r=".28" fill="#fff" stroke="#000" stroke-width=".2"/>
<circle cx="199.5" cy="34" r=".49" fill="#008000" stroke="#008000" stroke-width=".2"/>
<circle cx="199.5" cy="34" r=".28" fill="#fff" stroke="#000" stroke-width=".2"/>
<circle cx="166.5" cy="165" r=".49" fill="#008000" stroke="#008000" stroke-width=".2"/>
<circle cx="166.5" cy="165" r=".28" fill="#fff" stroke="#000" stroke-width=".2"/>
<circle cx="176.7" cy="187.2" r=".49" fill="#008000" stroke="#008000" stroke-width=".2"/>
<circle cx="176.7" cy="187.2" r=".28" fill="#fff" stroke="#000" stroke-width=".2"/>
<circle cx="199.8" cy="75.8" r=".49" fill="#008000" stroke="#008000" stroke-width=".2"/>
<circle cx="199.8" cy="75.8" r=".28" fill="#fff" stroke="#000" stroke-width=".2"/>
<circle cx="223" cy="65.1" r=".49" fill="#008000" stroke="#008000" stroke-width=".2"/>
<circle cx="223" cy="65.1" r=".28" fill="#fff" stroke="#000" stroke-width=".2"/>
<circle cx="160.9" cy="155.9" r=".49" fill="#008000" stroke="#008000" stroke-width=".2"/>
<circle cx="160.9" cy="155.9" r=".28" fill="#fff" stroke="#000" stroke-width=".2"/>
<circle cx="176.8" cy="62.1" r=".49" fill="#008000" stroke="#008000" stroke-width=".2"/>
<circle cx="176.8" cy="62.1" r=".28" fill="#fff" stroke="#000" stroke-width=".2"/>
<circle cx="163.1" cy="105" r=".49" fill="#008000" stroke="#008000" stroke-width=".2"/>
<circle cx="163.1" cy="105" r=".28" fill="#fff" stroke="#000" stroke-width=".2"/>
<circle cx="161.1" cy="104.6" r=".49" fill="#008000" stroke="#008000" stroke-width=".2"/>
<circle cx="161.1" cy="104.6" r=".28" fill="#fff" stroke="#000" stroke-width=".2"/>
<circle cx="231.1" cy="110.8" r=".49" fill="#008000" stroke="#008000" stroke-width=".2"/>
<circle cx="231.1" cy="110.8" r=".28" fill="#fff" stroke="#000" stroke-width=".2"/>
<circle cx="169.9" cy="180.8" r=".49" fill="#008000" stroke="#008000" stroke-width=".2"/>
<circle cx="169.9" cy="180.8" r=".28" fill="#fff" stroke="#000" stroke-width=".2"/>
<circle cx="170.9" cy="187.8" r=".49" fill="#008000" stroke="#008000" stroke-width=".2"/>
<circle cx="170.9" cy="187.8" r=".28" fill="#fff" stroke="#000" stroke-width=".2"/>
<circle cx="175.6" cy="178.1" r=".49" fill="#008000" stroke="#008000" stroke-width=".2"/>
<circle cx="175.6" cy="178.1" r=".28" fill="#fff" stroke="#000" stroke-width=".2"/>
<circle cx="176.7" cy="183.9" r=".49" fill="#008000" stroke="#008000" stroke-width=".2"/>
<circle cx="176.7" cy="183.9" r=".28" fill="#fff" stroke="#000" stroke-width=".2"/>
<circle cx="177.3" cy="177.1" r=".49" fill="#008000" stroke="#008000" stroke-width=".2"/>
<circle cx="177.3" cy="177.1" r=".28" fill="#fff" stroke="#000" stroke-width=".2"/>
<circle cx="178.9" cy="180.5" r=".49" fill="#008000" stroke="#008000" stroke-width=".2"/>
<circle cx="178.9" cy="180.5" r=".28" fill="#fff" stroke="#000" stroke-width=".2"/>
<circle cx="186.9" cy="171.6" r=".49" fill="#008000" stroke="#008000" stroke-width=".2"/>
<circle cx="186.9" cy="171.6" r=".28" fill="#fff" stroke="#000" stroke-width=".2"/>
<circle cx="193.4" cy="181" r=".49" fill="#008000" stroke="#008000" stroke-width=".2"/>
<circle cx="193.4" cy="181" r=".28" fill="#fff" stroke="#000" stroke-width=".2"/>
<circle cx="210.5" cy="40.6" r=".49" fill="#008000" stroke="#008000" stroke-width=".2"/>
<circle cx="210.5" cy="40.6" r=".28" fill="#fff" stroke="#000" stroke-width=".2"/>
<circle cx="206.9" cy="43.8" r=".49" fill="#008000" stroke="#008000" stroke-width=".2"/>
<circle cx="206.9" cy="43.8" r=".28" fill="#fff" stroke="#000" stroke-width=".2"/>
<circle cx="188.6" cy="170.3" r=".49" fill="#008000" stroke="#008000" stroke-width=".2"/>
<circle cx="188.6" cy="170.3" r=".28" fill="#fff" stroke="#000" stroke-width=".2"/>
<circle cx="170" cy="145.1" r=".49" fill="#008000" stroke="#008000" stroke-width=".2"/>
<circle cx="170" cy="145.1" r=".28" fill="#fff" stroke="#000" stroke-width=".2"/>
<circle cx="224.7" cy="127.4" r=".49" fill="#008000" stroke="#008000" stroke-width=".2"/>
<circle cx="224.7" cy="127.4" r=".28" fill="#fff" stroke="#000" stroke-width=".2"/>
<circle cx="188.7" cy="118.9" r=".49" fill="#008000" stroke="#008000" stroke-width=".2"/>
<circle cx="188.7" cy="118.9" r=".28" fill="#fff" stroke="#000" stroke-width=".2"/>
<circle cx="198.4" cy="168.2" r=".49" fill="#008000" stroke="#008000" stroke-width=".2"/>
<circle cx="198.4" cy="168.2" r=".28" fill="#fff" stroke="#000" stroke-width=".2"/>
<circle cx="220.6" cy="136.2" r=".49" fill="#008000" stroke="#008000" stroke-width=".2"/>
<circle cx="220.6" cy="136.2" r=".28" fill="#fff" stroke="#000" stroke-width=".2"/>
<circle cx="186.6" cy="36.8" r=".49" fill="#008000" stroke="#008000" stroke-width=".2"/>
<circle cx="186.6" cy="36.8" r=".28" fill="#fff" stroke="#000" stroke-width=".2"/>
<circle cx="192.2" cy="28.9" r=".49" fill="#008000" stroke="#008000" stroke-width=".2"/>
<circle cx="192.2" cy="28.9" r=".28" fill="#fff" stroke="#000" stroke-width=".2"/>
<circle cx="198.6" cy="161.6" r=".49" fill="#008000" stroke="#008000" stroke-width=".2"/>
<circle cx="198.6" cy="161.6" r=".28" fill="#fff" stroke="#000" stroke-width=".2"/>
<circle cx="189.8" cy="151.4" r=".49" fill="#008000" stroke="#008000" stroke-width=".2"/>
<circle cx="189.8" cy="151.4" r=".28" fill="#fff" stroke="#000" stroke-width=".2"/>
<circle cx="150.5" cy="31.8" r=".49" fill="#008000" stroke="#008000" stroke-width=".2"/>
<circle cx="150.5" cy="31.8" r=".28" fill="#fff" stroke="#000" stroke-width=".2"/>
<circle cx="153.6" cy="13" r=".49" fill="#008000" stroke="#008000" stroke-width=".2"/>
<circle cx="153.6" cy="13" r=".28" fill="#fff" stroke="#000" stroke-width=".2"/>
<circle cx="167.5" cy="30.6" r=".49" fill="#008000" stroke="#008000" stroke-width=".2"/>
<circle cx="167.5" cy="30.6" r=".28" fill="#fff" stroke="#000" stroke-width=".2"/>
<circle cx="170.5" cy="19.6" r=".49" fill="#008000" stroke="#008000" stroke-width=".2"/>
<circle cx="170.5" cy="19.6" r=".28" fill="#fff" stroke="#000" stroke-width=".2"/>
<circle cx="202.8" cy="156.7" r=".49" fill="#008000" stroke="#008000" stroke-width=".2"/>
<circle cx="202.8" cy="156.7" r=".28" fill="#fff" stroke="#000" stroke-width=".2"/>
<circle cx="167.3" cy="126.9" r=".49" fill="#008000" stroke="#008000" stroke-width=".2"/>
<circle cx="167.3" cy="126.9" r=".28" fill="#fff" stroke="#000" stroke-width=".2"/>
<circle cx="159.9" cy="29.2" r=".49" fill="#008000" stroke="#008000" stroke-width=".2"/>
<circle cx="159.9" cy="29.2" r=".28" fill="#fff" stroke="#000" stroke-width=".2"/>
<circle cx="148.4" cy="69" r=".49" fill="#008000" stroke="#008000" stroke-width=".2"/>
<circle cx="148.4" cy="69" r=".28" fill="#fff" stroke="#000" stroke-width=".2"/>
<circle cx="156.3" cy="29.2" r=".49" fill="#008000" stroke="#008000" stroke-width=".2"/>
<circle cx="156.3" cy="29.2" r=".28" fill="#fff" stroke="#000" stroke-width=".2"/>
<circle cx="158.8" cy="18.2" r=".49" fill="#008000" stroke="#008000" stroke-width=".2"/>
<circle cx="158.8" cy="18.2" r=".28" fill="#fff" stroke="#000" stroke-width=".2"/>
<circle cx="210.4" cy="146.2" r=".49" fill="#008000" stroke="#008000" stroke-width=".2"/>
<circle cx="210.4" cy="146.2" r=".28" fill="#fff" stroke="#000" stroke-width=".2"/>
<circle cx="189.3" cy="133.5" r=".49" fill="#008000" stroke="#008000" stroke-width=".2"/>
<circle cx="189.3" cy="133.5" r=".28" fill="#fff" stroke="#000" stroke-width=".2"/>
<circle cx="153.7" cy="45" r=".49" fill="#008000" stroke="#008000" stroke-width=".2"/>
<circle cx="153.7" cy="45" r=".28" fill="#fff" stroke="#000" stroke-width=".2"/>
<circle cx="212.8" cy="142.2" r=".49" fill="#008000" stroke="#008000" stroke-width=".2"/>
<circle cx="212.8" cy="142.2" r=".28" fill="#fff" stroke="#000" stroke-width=".2"/>
<circle cx="216.3" cy="134.1" r=".49" fill="#008000" stroke="#008000" stroke-width=".2"/>
<circle cx="216.3" cy="134.1" r=".28" fill="#fff" stroke="#000" stroke-width=".2"/>
<circle cx="210.1" cy="131.6" r=".49" fill="#008000" stroke="#008000" stroke-width=".2"/>
<circle cx="210.1" cy="131.6" r=".28" fill="#fff" stroke="#000" stroke-width=".2"/>
<circle cx="218" cy="130.1" r=".49" fill="#008000" stroke="#008000" stroke-width=".2"/>
<circle cx="218" cy="130.1" r=".28" fill="#fff" stroke="#000" stroke-width=".2"/>
<circle cx="211.1" cy="129.2" r=".49" fill="#008000" stroke="#008000" stroke-width=".2"/>
<circle cx="211.1" cy="129.2" r=".28" fill="#fff" stroke="#000" stroke-width=".2"/>
<circle cx="143.1" cy="171.7" r=".49" fill="#008000" stroke="#008000" stroke-width=".2"/>
<circle cx="143.1" cy="171.7" r=".28" fill="#fff" stroke="#000" stroke-width=".2"/>
<circle cx="144.1" cy="182.7" r=".49" fill="#008000" stroke="#008000" stroke-width=".2"/>
<circle cx="144.1" cy="182.7" r=".28" fill="#fff" stroke="#000" stroke-width=".2"/>
<circle cx="218.5" cy="128.7" r=".49" fill="#008000" stroke="#008000" stroke-width=".2"/>
<circle cx="218.5" cy="128.7" r=".28" fill="#fff" stroke="#000" stroke-width=".2"/>
<circle cx="210.2" cy="124.4" r=".49" fill="#008000" stroke="#008000" stroke-width=".2"/>
<circle cx="210.2" cy="124.4" r=".28" fill="#fff" stroke="#000" stroke-width=".2"/>
<circle cx="154.2" cy="175.9" r=".49" fill="#008000" stroke="#008000" stroke-width=".2"/>
<circle cx="154.2" cy="175.9" r=".28" fill="#fff" stroke="#000" stroke-width=".2"/>
<circle cx="155.2" cy="181.4" r=".49" fill="#008000" stroke="#008000" stroke-width=".2"/>
<circle cx="155.2" cy="181.4" r=".28" fill="#fff" stroke="#000" stroke-width=".2"/>
<circle cx="151.1" cy="166" r=".49" fill="#008000" stroke="#008000" stroke-width=".2"/>
<circle cx="151.1" cy="166" r=".28" fill="#fff" stroke="#000" stroke-width=".2"/>
<circle cx="153.9" cy="179.6" r=".49" fill="#008000" stroke="#008000" stroke-width=".2"/>
<circle cx="153.9" cy="179.6" r=".28" fill="#fff" stroke="#000" stroke-width=".2"/>
<circle cx="220.4" cy="121.9" r=".49" fill="#008000" stroke="#008000" stroke-width=".2"/>
<circle cx="220.4" cy="121.9" r=".28" fill="#fff" stroke="#000" stroke-width=".2"/>
<circle cx="197.3" cy="116.3" r=".49" fill="#008000" stroke="#008000" stroke-width=".2"/>
<circle cx="197.3" cy="116.3" r=".28" fill="#fff" stroke="#000" stroke-width=".2"/>
<circle cx="150.3" cy="161.9" r=".49" fill="#008000" stroke="#008000" stroke-width=".2"/>
<circle cx="150.3" cy="161.9" r=".28" fill="#fff" stroke="#000" stroke-width=".2"/>
<circle cx="145" cy="167.3" r=".49" fill="#008000" stroke="#008000" stroke-width=".2"/>
<circle cx="145" cy="167.3" r=".28" fill="#fff" stroke="#000" stroke-width=".2"/>
<circle cx="145.3" cy="178.7" r=".49" fill="#008000" stroke="#008000" stroke-width=".2"/>
<circle cx="145.3" cy="178.7" r=".28" fill="#fff" stroke="#000" stroke-width=".2"/>
<circle cx="221.3" cy="115.4" r=".49" fill="#008000" stroke="#008000" stroke-width=".2"/>
<circle cx="221.3" cy="115.4" r=".28" fill="#fff" stroke="#000" stroke-width=".2"/>
<circle cx="199.6" cy="111.1" r=".49" fill="#008000" stroke="#008000" stroke-width=".2"/>
<circle cx="199.6" cy="111.1" r=".28" fill="#fff" stroke="#000" stroke-width=".2"/>
<circle cx="138.8" cy="164.4" r=".49" fill="#008000" stroke="#008000" stroke-width=".2"/>
<circle cx="138.8" cy="164.4" r=".28" fill="#fff" stroke="#000" stroke-width=".2"/>
<circle cx="222.4" cy="104.1" r=".49" fill="#008000" stroke="#008000" stroke-width=".2"/>
<circle cx="222.4" cy="104.1" r=".28" fill="#fff" stroke="#000" stroke-width=".2"/>
<circle cx="207.5" cy="105.2" r=".49" fill="#008000" stroke="#008000" stroke-width=".2"/>
<circle cx="207.5" cy="105.2" r=".28" fill="#fff" stroke="#000" stroke-width=".2"/>
<circle cx="222.3" cy="97.6" r=".49" fill="#008000" stroke="#008000" stroke-width=".2"/>
<circle cx="222.3" cy="97.6" r=".28" fill="#fff" stroke="#000" stroke-width=".2"/>
<circle cx="205.4" cy="99.7" r=".49" fill="#008000" stroke="#008000" stroke-width=".2"/>
<circle cx="205.4" cy="99.7" r=".28" fill="#fff" stroke="#000" stroke-width=".2"/>
<circle cx="222.3" cy="95.8" r=".49" fill="#008000" stroke="#008000" stroke-width=".2"/>
<circle cx="222.3" cy="95.8" r=".28" fill="#fff" stroke="#000" stroke-width=".2"/>
<circle cx="202.3" cy="96.9" r=".49" fill="#008000" stroke="#008000" stroke-width=".2"/>
<circle cx="202.3" cy="96.9" r=".28" fill="#fff" stroke="#000" stroke-width=".2"/>
<circle cx="158.7" cy="37.3" r=".49" fill="#008000" stroke="#008000" stroke-width=".2"/>
<circle cx="158.7" cy="37.3" r=".28" fill="#fff" stroke="#000" stroke-width=".2"/>
<circle cx="155.7" cy="47.8" r=".49" fill="#008000" stroke="#008000" stroke-width=".2"/>
<circle cx="155.7" cy="47.8" r=".28" fill="#fff" stroke="#000" stroke-width=".2"/>
<circle cx="219.3" cy="89.1" r=".49" fill="#008000" stroke="#008000" stroke-width=".2"/>
<circle cx="219.3" cy="89.1" r=".28" fill="#fff" stroke="#000" stroke-width=".2"/>
<circle cx="205.3" cy="90" r=".49" fill="#008000" stroke="#008000" stroke-width=".2"/>
<circle cx="205.3" cy="90" r=".28" fill="#fff" stroke="#000" stroke-width=".2"/>
<circle cx="201.2" cy="76.1" r=".49" fill="#008000" stroke="#008000" stroke-width=".2"/>
<circle cx="201.2" cy="76.1" r=".28" fill="#fff" stroke="#000" stroke-width=".2"/>
<circle cx="156.9" cy="50.3" r=".49" fill="#008000" stroke="#008000" stroke-width=".2"/>
<circle cx="156.9" cy="50.3" r=".28" fill="#fff" stroke="#000" stroke-width=".2"/>
<circle cx="160" cy="40.9" r=".49" fill="#008000" stroke="#008000" stroke-width=".2"/>
<circle cx="160" cy="40.9" r=".28" fill="#fff" stroke="#000" stroke-width=".2"/>
<circle cx="218.5" cy="77.7" r=".49" fill="#008000" stroke="#008000" stroke-width=".2"/>
<circle cx="218.5" cy="77.7" r=".28" fill="#fff" stroke="#000" stroke-width=".2"/>
<circle cx="197.4" cy="85.6" r=".49" fill="#008000" stroke="#008000" stroke-width=".2"/>
<circle cx="197.4" cy="85.6" r=".28" fill="#fff" stroke="#000" stroke-width=".2"/>
<circle cx="195.7" cy="68.1" r=".49" fill="#008000" stroke="#008000" stroke-width=".2"/>
<circle cx="195.7" cy="68.1" r=".28" fill="#fff" stroke="#000" stroke-width=".2"/>
<circle cx="191.3" cy="70.8" r=".49" fill="#008000" stroke="#008000" stroke-width=".2"/>
<circle cx="191.3" cy="70.8" r=".28" fill="#fff" stroke="#000" stroke-width=".2"/>
<circle cx="170.9" cy="47.6" r=".49" fill="#008000" stroke="#008000" stroke-width=".2"/>
<circle cx="170.9" cy="47.6" r=".28" fill="#fff" stroke="#000" stroke-width=".2"/>
<circle cx="165.7" cy="56.6" r=".49" fill="#008000" stroke="#008000" stroke-width=".2"/>
<circle cx="165.7" cy="56.6" r=".28" fill="#fff" stroke="#000" stroke-width=".2"/>
<circle cx="218.1" cy="76.2" r=".49" fill="#008000" stroke="#008000" stroke-width=".2"/>
<circle cx="218.1" cy="76.2" r=".28" fill="#fff" stroke="#000" stroke-width=".2"/>
<circle cx="200.4" cy="82.2" r=".49" fill="#008000" stroke="#008000" stroke-width=".2"/>
<circle cx="200.4" cy="82.2" r=".28" fill="#fff" stroke="#000" stroke-width=".2"/>
<circle cx="196.8" cy="76" r=".49" fill="#008000" stroke="#008000" stroke-width=".2"/>
<circle cx="196.8" cy="76" r=".28" fill="#fff" stroke="#000" stroke-width=".2"/>
<circle cx="215.7" cy="70.1" r=".49" fill="#008000" stroke="#008000" stroke-width=".2"/>
<circle cx="215.7" cy="70.1" r=".28" fill="#fff" stroke="#000" stroke-width=".2"/>
<circle cx="191.5" cy="81.3" r=".49" fill="#008000" stroke="#008000" stroke-width=".2"/>
<circle cx="191.5" cy="81.3" r=".28" fill="#fff" stroke="#000" stroke-width=".2"/>
<circle cx="213.8" cy="66.1" r=".49" fill="#008000" stroke="#008000" stroke-width=".2"/>
<circle cx="213.8" cy="66.1" r=".28" fill="#fff" stroke="#000" stroke-width=".2"/>
<circle cx="191.6" cy="77.3" r=".49" fill="#008000" stroke="#008000" stroke-width=".2"/>
<circle cx="191.6" cy="77.3" r=".28" fill="#fff" stroke="#000" stroke-width=".2"/>
<circle cx="193.9" cy="82.5" r=".49" fill="#008000" stroke="#008000" stroke-width=".2"/>
<circle cx="193.9" cy="82.5" r=".28" fill="#fff" stroke="#000" stroke-width=".2"/>
<circle cx="191.5" cy="83.4" r=".49" fill="#008000" stroke="#008000" stroke-width=".2"/>
<circle cx="191.5" cy="83.4" r=".28" fill="#fff" stroke="#000" stroke-width=".2"/>
<circle cx="209.5" cy="58.3" r=".49" fill="#008000" stroke="#008000" stroke-width=".2"/>
<circle cx="209.5" cy="58.3" r=".28" fill="#fff" stroke="#000" stroke-width=".2"/>
<circle cx="182.4" cy="74.3" r=".49" fill="#008000" stroke="#008000" stroke-width=".2"/>
<circle cx="182.4" cy="74.3" r=".28" fill="#fff" stroke="#000" stroke-width=".2"/>
<circle cx="145" cy="149.5" r=".49" fill="#008000" stroke="#008000" stroke-width=".2"/>
<circle cx="145" cy="149.5" r=".28" fill="#fff" stroke="#000" stroke-width=".2"/>
<circle cx="146.7" cy="160.3" r=".49" fill="#008000" stroke="#008000" stroke-width=".2"/>
<circle cx="146.7" cy="160.3" r=".28" fill="#fff" stroke="#000" stroke-width=".2"/>
<circle cx="206.7" cy="54.2" r=".49" fill="#008000" stroke="#008000" stroke-width=".2"/>
<circle cx="206.7" cy="54.2" r=".28" fill="#fff" stroke="#000" stroke-width=".2"/>
<circle cx="182.2" cy="73.1" r=".49" fill="#008000" stroke="#008000" stroke-width=".2"/>
<circle cx="182.2" cy="73.1" r=".28" fill="#fff" stroke="#000" stroke-width=".2"/>
<circle cx="181.2" cy="131.6" r=".49" fill="#008000" stroke="#008000" stroke-width=".2"/>
<circle cx="181.2" cy="131.6" r=".28" fill="#fff" stroke="#000" stroke-width=".2"/>
<circle cx="177.8" cy="129.2" r=".49" fill="#008000" stroke="#008000" stroke-width=".2"/>
<circle cx="177.8" cy="129.2" r=".28" fill="#fff" stroke="#000" stroke-width=".2"/>
<circle cx="147.3" cy="158.2" r=".49" fill="#008000" stroke="#008000" stroke-width=".2"/>
<circle cx="147.3" cy="158.2" r=".28" fill="#fff" stroke="#000" stroke-width=".2"/>
<circle cx="145.9" cy="147.2" r=".49" fill="#008000" stroke="#008000" stroke-width=".2"/>
<circle cx="145.9" cy="147.2" r=".28" fill="#fff" stroke="#000" stroke-width=".2"/>
<circle cx="201.7" cy="48" r=".49" fill="#008000" stroke="#008000" stroke-width=".2"/>
<circle cx="201.7" cy="48" r=".28" fill="#fff" stroke="#000" stroke-width=".2"/>
<circle cx="176.1" cy="70.3" r=".49" fill="#008000" stroke="#008000" stroke-width=".2"/>
<circle cx="176.1" cy="70.3" r=".28" fill="#fff" stroke="#000" stroke-width=".2"/>
<circle cx="166.4" cy="144.4" r=".49" fill="#008000" stroke="#008000" stroke-width=".2"/>
<circle cx="166.4" cy="144.4" r=".28" fill="#fff" stroke="#000" stroke-width=".2"/>
<circle cx="163.1" cy="139.3" r=".49" fill="#008000" stroke="#008000" stroke-width=".2"/>
<circle cx="163.1" cy="139.3" r=".28" fill="#fff" stroke="#000" stroke-width=".2"/>
<circle cx="141.8" cy="145.3" r=".49" fill="#008000" stroke="#008000" stroke-width=".2"/>
<circle cx="141.8" cy="145.3" r=".28" fill="#fff" stroke="#000" stroke-width=".2"/>
<circle cx="138.9" cy="155.3" r=".49" fill="#008000" stroke="#008000" stroke-width=".2"/>
<circle cx="138.9" cy="155.3" r=".28" fill="#fff" stroke="#000" stroke-width=".2"/>
<circle cx="196.8" cy="43.3" r=".49" fill="#008000" stroke="#008000" stroke-width=".2"/>
<circle cx="196.8" cy="43.3" r=".28" fill="#fff" stroke="#000" stroke-width=".2"/>
<circle cx="172.2" cy="68.3" r=".49" fill="#008000" stroke="#008000" stroke-width=".2"/>
<circle cx="172.2" cy="68.3" r=".28" fill="#fff" stroke="#000" stroke-width=".2"/>
<circle cx="170.6" cy="139.3" r=".49" fill="#008000" stroke="#008000" stroke-width=".2"/>
<circle cx="170.6" cy="139.3" r=".28" fill="#fff" stroke="#000" stroke-width=".2"/>
<circle cx="166.9" cy="134.9" r=".49" fill="#008000" stroke="#008000" stroke-width=".2"/>
<circle cx="166.9" cy="134.9" r=".28" fill="#fff" stroke="#000" stroke-width=".2"/>
<circle cx="188.6" cy="36" r=".49" fill="#008000" stroke="#008000" stroke-width=".2"/>
<circle cx="188.6" cy="36" r=".28" fill="#fff" stroke="#000" stroke-width=".2"/>
<circle cx="166.1" cy="65.3" r=".49" fill="#008000" stroke="#008000" stroke-width=".2"/>
<circle cx="166.1" cy="65.3" r=".28" fill="#fff" stroke="#000" stroke-width=".2"/>
<circle cx="157.5" cy="73.3" r=".49" fill="#008000" stroke="#008000" stroke-width=".2"/>
<circle cx="157.5" cy="73.3" r=".28" fill="#fff" stroke="#000" stroke-width=".2"/>
<circle cx="164.4" cy="62.1" r=".49" fill="#008000" stroke="#008000" stroke-width=".2"/>
<circle cx="164.4" cy="62.1" r=".28" fill="#fff" stroke="#000" stroke-width=".2"/>
<circle cx="163.8" cy="66.1" r=".49" fill="#008000" stroke="#008000" stroke-width=".2"/>
<circle cx="163.8" cy="66.1" r=".28" fill="#fff" stroke="#000" stroke-width=".2"/>
<circle cx="157.4" cy="75.6" r=".49" fill="#008000" stroke="#008000" stroke-width=".2"/>
<circle cx="157.4" cy="75.6" r=".28" fill="#fff" stroke="#000" stroke-width=".2"/>
<circle cx="183.1" cy="32.1" r=".49" fill="#008000" stroke="#008000" stroke-width=".2"/>
<circle cx="183.1" cy="32.1" r=".28" fill="#fff" stroke="#000" stroke-width=".2"/>
<circle cx="154.5" cy="76.1" r=".49" fill="#008000" stroke="#008000" stroke-width=".2"/>
<circle cx="154.5" cy="76.1" r=".28" fill="#fff" stroke="#000" stroke-width=".2"/>
<circle cx="159.7" cy="67.1" r=".49" fill="#008000" stroke="#008000" stroke-width=".2"/>
<circle cx="159.7" cy="67.1" r=".28" fill="#fff" stroke="#000" stroke-width=".2"/>
<circle cx="181.9" cy="31.4" r=".49" fill="#008000" stroke="#008000" stroke-width=".2"/>
<circle cx="181.9" cy="31.4" r=".28" fill="#fff" stroke="#000" stroke-width=".2"/>
<circle cx="164" cy="128" r=".49" fill="#008000" stroke="#008000" stroke-width=".2"/>
<circle cx="164" cy="128" r=".28" fill="#fff" stroke="#000" stroke-width=".2"/>
<circle cx="155.6" cy="119.6" r=".49" fill="#008000" stroke="#008000" stroke-width=".2"/>
<circle cx="155.6" cy="119.6" r=".28" fill="#fff" stroke="#000" stroke-width=".2"/>
<circle cx="175.7" cy="28.1" r=".49" fill="#008000" stroke="#008000" stroke-width=".2"/>
<circle cx="175.7" cy="28.1" r=".28" fill="#fff" stroke="#000" stroke-width=".2"/>
<circle cx="144.2" cy="82.4" r=".49" fill="#008000" stroke="#008000" stroke-width=".2"/>
<circle cx="144.2" cy="82.4" r=".28" fill="#fff" stroke="#000" stroke-width=".2"/>
<circle cx="160.4" cy="115.1" r=".49" fill="#008000" stroke="#008000" stroke-width=".2"/>
<circle cx="160.4" cy="115.1" r=".28" fill="#fff" stroke="#000" stroke-width=".2"/>
<circle cx="153.4" cy="110.8" r=".49" fill="#008000" stroke="#008000" stroke-width=".2"/>
<circle cx="153.4" cy="110.8" r=".28" fill="#fff" stroke="#000" stroke-width=".2"/>
<circle cx="142.8" cy="125.4" r=".49" fill="#008000" stroke="#008000" stroke-width=".2"/>
<circle cx="142.8" cy="125.4" r=".28" fill="#fff" stroke="#000" stroke-width=".2"/>
<circle cx="143.3" cy="134.9" r=".49" fill="#008000" stroke="#008000" stroke-width=".2"/>
<circle cx="143.3" cy="134.9" r=".28" fill="#fff" stroke="#000" stroke-width=".2"/>
<circle cx="171.5" cy="26.3" r=".49" fill="#008000" stroke="#008000" stroke-width=".2"/>
<circle cx="171.5" cy="26.3" r=".28" fill="#fff" stroke="#000" stroke-width=".2"/>
<circle cx="155.2" cy="66.6" r=".49" fill="#008000" stroke="#008000" stroke-width=".2"/>
<circle cx="155.2" cy="66.6" r=".28" fill="#fff" stroke="#000" stroke-width=".2"/>
<circle cx="175" cy="120" r=".49" fill="#008000" stroke="#008000" stroke-width=".2"/>
<circle cx="175" cy="120" r=".28" fill="#fff" stroke="#000" stroke-width=".2"/>
<circle cx="168.2" cy="116.7" r=".49" fill="#008000" stroke="#008000" stroke-width=".2"/>
<circle cx="168.2" cy="116.7" r=".28" fill="#fff" stroke="#000" stroke-width=".2"/>
<circle cx="155.2" cy="129.6" r=".49" fill="#008000" stroke="#008000" stroke-width=".2"/>
<circle cx="155.2" cy="129.6" r=".28" fill="#fff" stroke="#000" stroke-width=".2"/>
<circle cx="148.8" cy="119.9" r=".49" fill="#008000" stroke="#008000" stroke-width=".2"/>
<circle cx="148.8" cy="119.9" r=".28" fill="#fff" stroke="#000" stroke-width=".2"/>
<circle cx="164.2" cy="23.3" r=".49" fill="#008000" stroke="#008000" stroke-width=".2"/>
<circle cx="164.2" cy="23.3" r=".28" fill="#fff" stroke="#000" stroke-width=".2"/>
<circle cx="151.8" cy="63.9" r=".49" fill="#008000" stroke="#008000" stroke-width=".2"/>
<circle cx="151.8" cy="63.9" r=".28" fill="#fff" stroke="#000" stroke-width=".2"/>
<circle cx="174.7" cy="123.7" r=".49" fill="#008000" stroke="#008000" stroke-width=".2"/>
<circle cx="174.7" cy="123.7" r=".28" fill="#fff" stroke="#000" stroke-width=".2"/>
<circle cx="165.2" cy="118.2" r=".49" fill="#008000" stroke="#008000" stroke-width=".2"/>
<circle cx="165.2" cy="118.2" r=".28" fill="#fff" stroke="#000" stroke-width=".2"/>
<circle cx="156.8" cy="22.1" r=".49" fill="#008000" stroke="#008000" stroke-width=".2"/>
<circle cx="156.8" cy="22.1" r=".28" fill="#fff" stroke="#000" stroke-width=".2"/>
<circle cx="144.7" cy="79.9" r=".49" fill="#008000" stroke="#008000" stroke-width=".2"/>
<circle cx="144.7" cy="79.9" r=".28" fill="#fff" stroke="#000" stroke-width=".2"/>
<circle cx="146.5" cy="84.6" r=".49" fill="#008000" stroke="#008000" stroke-width=".2"/>
<circle cx="146.5" cy="84.6" r=".28" fill="#fff" stroke="#000" stroke-width=".2"/>
<circle cx="143.2" cy="92.9" r=".49" fill="#008000" stroke="#008000" stroke-width=".2"/>
<circle cx="143.2" cy="92.9" r=".28" fill="#fff" stroke="#000" stroke-width=".2"/>
<circle cx="145.6" cy="19.7" r=".49" fill="#008000" stroke="#008000" stroke-width=".2"/>
<circle cx="145.6" cy="19.7" r=".28" fill="#fff" stroke="#000" stroke-width=".2"/>
<circle cx="141.2" cy="77" r=".49" fill="#008000" stroke="#008000" stroke-width=".2"/>
<circle cx="141.2" cy="77" r=".28" fill="#fff" stroke="#000" stroke-width=".2"/>
<circle cx="163.6" cy="92.9" r=".49" fill="#008000" stroke="#008000" stroke-width=".2"/>
<circle cx="163.6" cy="92.9" r=".28" fill="#fff" stroke="#000" stroke-width=".2"/>
<circle cx="159.8" cy="94.4" r=".49" fill="#008000" stroke="#008000" stroke-width=".2"/>
<circle cx="159.8" cy="94.4" r=".28" fill="#fff" stroke="#000" stroke-width=".2"/>
<circle cx="158.5" cy="100.5" r=".49" fill="#008000" stroke="#008000" stroke-width=".2"/>
<circle cx="158.5" cy="100.5" r=".28" fill="#fff" stroke="#000" stroke-width=".2"/>
<circle cx="146.5" cy="101.9" r=".49" fill="#008000" stroke="#008000" stroke-width=".2"/>
<circle cx="146.5" cy="101.9" r=".28" fill="#fff" stroke="#000" stroke-width=".2"/>
<circle cx="142.7" cy="16.2" r=".49" fill="#008000" stroke="#008000" stroke-width=".2"/>
<circle cx="142.7" cy="16.2" r=".28" fill="#fff" stroke="#000" stroke-width=".2"/>
<circle cx="141.1" cy="78.5" r=".49" fill="#008000" stroke="#008000" stroke-width=".2"/>
<circle cx="141.1" cy="78.5" r=".28" fill="#fff" stroke="#000" stroke-width=".2"/>
<circle cx="163.9" cy="100.1" r=".49" fill="#008000" stroke="#008000" stroke-width=".2"/>
<circle cx="163.9" cy="100.1" r=".28" fill="#fff" stroke="#000" stroke-width=".2"/>
<circle cx="109.7" cy="110.7" r=".49" fill="#008000" stroke="#008000" stroke-width=".2"/>
<circle cx="109.7" cy="110.7" r=".28" fill="#fff" stroke="#000" stroke-width=".2"/>
<circle cx="142.3" cy="139.6" r=".72" fill="#008000" stroke="#008000" stroke-width=".2"/>
<circle cx="142.3" cy="139.6" r=".47" fill="#fff" stroke="#000" stroke-width=".2"/>
<circle cx="174.7" cy="78.5" r=".49" fill="#008000" stroke="#008000" stroke-width=".2"/>
<circle cx="174.7" cy="78.5" r=".28" fill="#fff" stroke="#000" stroke-width=".2"/>
<circle cx="187" cy="72.7" r=".49" fill="#008000" stroke="#008000" stroke-width=".2"/>
<circle cx="187" cy="72.7" r=".28" fill="#fff" stroke="#000" stroke-width=".2"/>
<circle cx="136.9" cy="62" r=".49" fill="#008000" stroke="#008000" stroke-width=".2"/>
<circle cx="136.9" cy="62" r=".28" fill="#fff" stroke="#000" stroke-width=".2"/>
<circle cx="143.3" cy="35.8" r=".49" fill="#008000" stroke="#008000" stroke-width=".2"/>
<circle cx="143.3" cy="35.8" r=".28" fill="#fff" stroke="#000" stroke-width=".2"/>
<circle cx="125.8" cy="34.2" r=".49" fill="#008000" stroke="#008000" stroke-width=".2"/>
<circle cx="125.8" cy="34.2" r=".28" fill="#fff" stroke="#000" stroke-width=".2"/>
<circle cx="119.9" cy="64.2" r=".49" fill="#008000" stroke="#008000" stroke-width=".2"/>
<circle cx="119.9" cy="64.2" r=".28" fill="#fff" stroke="#000" stroke-width=".2"/>
<circle cx="119.5" cy="67" r=".49" fill="#008000" stroke="#008000" stroke-width=".2"/>
<circle cx="119.5" cy="67" r=".28" fill="#fff" stroke="#000" stroke-width=".2"/>
<circle cx="92.8" cy="125.5" r=".49" fill="#008000" stroke="#008000" stroke-width=".2"/>
<circle cx="92.8" cy="125.5" r=".28" fill="#fff" stroke="#000" stroke-width=".2"/>
<circle cx="133.2" cy="75.5" r=".72" fill="#008000" stroke="#008000" stroke-width=".2"/>
<circle cx="133.2" cy="75.5" r=".47" fill="#fff" stroke="#000" stroke-width=".2"/>
<circle cx="172.9" cy="72.6" r=".49" fill="#008000" stroke="#008000" stroke-width=".2"/>
<circle cx="172.9" cy="72.6" r=".28" fill="#fff" stroke="#000" stroke-width=".2"/>
<circle cx="148.5" cy="74.8" r=".72" fill="#008000" stroke="#008000" stroke-width=".2"/>
<circle cx="148.5" cy="74.8" r=".47" fill="#fff" stroke="#000" stroke-width=".2"/>
<circle cx="99.9" cy="115.8" r=".72" fill="#008000" stroke="#008000" stroke-width=".2"/>
<circle cx="99.9" cy="115.8" r=".47" fill="#fff" stroke="#000" stroke-width=".2"/>
<circle cx="136.7" cy="75.5" r=".72" fill="#008000" stroke="#008000" stroke-width=".2"/>
<circle cx="136.7" cy="75.5" r=".47" fill="#fff" stroke="#000" stroke-width=".2"/>
<circle cx="118.8" cy="49.3" r=".49" fill="#008000" stroke="#008000" stroke-width=".2"/>
<circle cx="118.8" cy="49.3" r=".28" fill="#fff" stroke="#000" stroke-width=".2"/>
<circle cx="114.1" cy="120" r=".49" fill="#008000" stroke="#008000" stroke-width=".2"/>
<circle cx="114.1" cy="120" r=".28" fill="#fff" stroke="#000" stroke-width=".2"/>
<circle cx="162.1" cy="43.8" r=".49" fill="#008000" stroke="#008000" stroke-width=".2"/>
<circle cx="162.1" cy="43.8" r=".28" fill="#fff" stroke="#000" stroke-width=".2"/>
<circle cx="165.5" cy="90.2" r=".49" fill="#008000" stroke="#008000" stroke-width=".2"/>
<circle cx="165.5" cy="90.2" r=".28" fill="#fff" stroke="#000" stroke-width=".2"/>
<circle cx="122" cy="57.9" r=".49" fill="#008000" stroke="#008000" stroke-width=".2"/>
<circle cx="122" cy="57.9" r=".28" fill="#fff" stroke="#000" stroke-width=".2"/>
<circle cx="165.7" cy="97" r=".49" fill="#008000" stroke="#008000" stroke-width=".2"/>
<circle cx="165.7" cy="97" r=".28" fill="#fff" stroke="#000" stroke-width=".2"/>
<circle cx="151.4" cy="69.1" r=".49" fill="#008000" stroke="#008000" stroke-width=".2"/>
<circle cx="151.4" cy="69.1" r=".28" fill="#fff" stroke="#000" stroke-width=".2"/>
<circle cx="156.9" cy="54.6" r=".49" fill="#008000" stroke="#008000" stroke-width=".2"/>
<circle cx="156.9" cy="54.6" r=".28" fill="#fff" stroke="#000" stroke-width=".2"/>
<circle cx="147.5" cy="55.5" r=".49" fill="#008000" stroke="#008000" stroke-width=".2"/>
<circle cx="147.5" cy="55.5" r=".28" fill="#fff" stroke="#000" stroke-width=".2"/>
<circle cx="132.9" cy="102" r=".49" fill="#008000" stroke="#008000" stroke-width=".2"/>
<circle cx="132.9" cy="102" r=".28" fill="#fff" stroke="#000" stroke-width=".2"/>
<circle cx="132.1" cy="103.3" r=".49" fill="#008000" stroke="#008000" stroke-width=".2"/>
<circle cx="132.1" cy="103.3" r=".28" fill="#fff" stroke="#000" stroke-width=".2"/>
<circle cx="157.4" cy="68.6" r=".49" fill="#008000" stroke="#008000" stroke-width=".2"/>
<circle cx="157.4" cy="68.6" r=".28" fill="#fff" stroke="#000" stroke-width=".2"/>
<circle cx="124.8" cy="103.4" r=".49" fill="#008000" stroke="#008000" stroke-width=".2"/>
<circle cx="124.8" cy="103.4" r=".28" fill="#fff" stroke="#000" stroke-width=".2"/>
<circle cx="45" cy="103.4" r=".49" fill="#008000" stroke="#008000" stroke-width=".2"/>
<circle cx="45" cy="103.4" r=".28" fill="#fff" stroke="#000" stroke-width=".2"/>
<circle cx="124.8" cy="109.6" r=".49" fill="#008000" stroke="#008000" stroke-width=".2"/>
<circle cx="124.8" cy="109.6" r=".28" fill="#fff" stroke="#000" stroke-width=".2"/>
<circle cx="154.9" cy="50.6" r=".49" fill="#008000" stroke="#008000" stroke-width=".2"/>
<circle cx="154.9" cy="50.6" r=".28" fill="#fff" stroke="#000" stroke-width=".2"/>
<circle cx="228.7" cy="112.1" r=".49" fill="#008000" stroke="#008000" stroke-width=".2"/>
<circle cx="228.7" cy="112.1" r=".28" fill="#fff" stroke="#000" stroke-width=".2"/>
<circle cx="195.3" cy="109" r=".49" fill="#008000" stroke="#008000" stroke-width=".2"/>
<circle cx="195.3" cy="109" r=".28" fill="#fff" stroke="#000" stroke-width=".2"/>
<circle cx="121.1" cy="46.9" r=".49" fill="#008000" stroke="#008000" stroke-width=".2"/>
<circle cx="121.1" cy="46.9" r=".28" fill="#fff" stroke="#000" stroke-width=".2"/>
<circle cx="136.2" cy="44.4" r=".49" fill="#008000" stroke="#008000" stroke-width=".2"/>
<circle cx="136.2" cy="44.4" r=".28" fill="#fff" stroke="#000" stroke-width=".2"/>
<circle cx="225.8" cy="88.9" r=".49" fill="#008000" stroke="#008000" stroke-width=".2"/>
<circle cx="225.8" cy="88.9" r=".28" fill="#fff" stroke="#000" stroke-width=".2"/>
<circle cx="194.8" cy="94.2" r=".49" fill="#008000" stroke="#008000" stroke-width=".2"/>
<circle cx="194.8" cy="94.2" r=".28" fill="#fff" stroke="#000" stroke-width=".2"/>
<g fill="#800000" stroke="#800000" stroke-width=".2">
<path d="M137.2 12.2h1.1v1.1h-1.1z"/>
<path d="M139.3 12.2h1.1v1.1h-1.1z"/>
<path d="M139.3 14.4h1.1v1.1h-1.1z"/>
<path d="M137.2 14.4h1.1v1.1h-1.1z"/>
<path d="M124.8 13.3l1.1-.2 .1 1.1-1 .2z"/>
<path d="M127 13l1.1-.2 .1 1.1-1.1 .2z"/>
<path d="M127.3 15.1l1.1-.1 .1 1.1-1.1 .1z"/>
<path d="M125.1 15.4l1.1-.1 .1 1.1-1 .1z"/>
<path d="M112.7 16l1.1-.3 .3 1.1-1.1 .3z"/>
<path d="M114.8 15.4l1.1-.3 .3 1.1-1.1 .3z"/>
<path d="M115.4 17.5l1-.3 .3 1.1-1 .3z"/>
<path d="M113.3 18.1l1.1-.3 .2 1.1-1 .3z"/>
<path d="M101.1 20.4l1-.4 .4 1-1 .4z"/>
<path d="M103.1 19.5l1-.4 .4 1-1 .4z"/>
<path d="M104 21.5l1-.4 .4 1-1 .4z"/>
<path d="M102 22.4l1-.5 .4 1-1 .5z"/>
<path d="M90.2 26.3l.9-.6 .6 .9-.9 .6z"/>
<path d="M92.1 25.2l.9-.6 .6 .9-1 .6z"/>
<path d="M93.2 27l.9-.5 .6 .9-1 .5z"/>
<path d="M91.3 28.2l1-.6 .5 .9-.9 .6z"/>
<path d="M80.2 33.6l.8-.7 .7 .9-.8 .7z"/>
<path d="M81.9 32.3l.8-.7 .7 .8-.8 .7z"/>
<path d="M83.2 33.9l.9-.6 .7 .8-.9 .7z"/>
<path d="M81.6 35.3l.8-.7 .7 .9-.8 .7z"/>
<path d="M72 41.4l.8 .8-.7 .8-.8-.8z"/>
<path d="M73.5 39.9l.8 .7-.7 .8-.8-.7z"/>
<path d="M75.1 41.4l.8 .7-.8 .8-.7-.8z"/>
<path d="M73.6 42.9l.8 .8-.7 .8-.8-.8z"/>
<path d="M64.3 51.1l.9 .7-.7 .8-.9-.6z"/>
<path d="M65.5 49.3l.9 .7-.6 .9-.9-.7z"/>
<path d="M67.3 50.6l.9 .6-.7 .9-.8-.6z"/>
<path d="M66 52.4l.9 .6-.6 .9-.9-.6z"/>
<path d="M57.9 61.8l.9 .5-.5 .9-.9-.5z"/>
<path d="M58.9 59.8l.9 .5-.5 1-.9-.5z"/>
<path d="M60.8 60.8l1 .5-.5 1-1-.5z"/>
<path d="M59.8 62.8l1 .4-.5 1-1-.5z"/>
<path d="M53 73.2l1 .3-.3 1-1.1-.3z"/>
<path d="M53.7 71.1l1.1 .4-.4 1-1-.4z"/>
<path d="M55.8 71.8l1 .4-.4 1-1-.3z"/>
<path d="M55.1 73.9l1 .4-.4 1-1-.4z"/>
<path d="M49.7 85.1l1.1 .2-.2 1.1-1.1-.2z"/>
<path d="M50.2 83l1 .2-.2 1.1-1-.2z"/>
<path d="M52.3 83.4l1.1 .3-.3 1-1-.2z"/>
<path d="M51.9 85.6l1 .2-.2 1-1.1-.2z"/>
<path d="M48.1 97.4l1.1 .1-.1 1.1-1.1-.1z"/>
<path d="M48.3 95.2l1 .1v1.1l-1.1-.1z"/>
<path d="M50.4 95.4l1.1 .1-.1 1.1-1-.1z"/>
<path d="M50.3 97.6h1.1l-.1 1.1h-1.1z"/>
<path d="M48.2 109.8l1.1-.1v1.1l-1 .1z"/>
<path d="M48 107.7l1.1-.1 .1 1.1-1.1 .1z"/>
<path d="M50.2 107.5l1.1-.1 .1 1.1-1.1 .1z"/>
<path d="M50.4 109.7l1-.1 .1 1.1-1.1 .1z"/>
<path d="M50 122.1l1-.2 .2 1-1 .3z"/>
<path d="M49.5 120l1.1-.2 .2 1-1.1 .2z"/>
<path d="M51.6 119.5l1.1-.2 .2 1.1-1 .2z"/>
<path d="M52.1 121.7l1-.3 .3 1.1-1.1 .2z"/>
<path d="M53.4 134l1-.3 .4 1-1.1 .3z"/>
<path d="M52.6 132l1.1-.4 .3 1-1 .4z"/>
<path d="M54.7 131.3l1-.4 .4 1-1 .4z"/>
<path d="M55.4 133.3l1-.4 .4 1.1-1 .3z"/>
<path d="M58.4 145.4l.9-.5 .5 .9-.9 .5z"/>
<path d="M57.4 143.4l.9-.5 .5 1-.9 .5z"/>
<path d="M59.3 142.5l1-.6 .5 1-1 .5z"/>
<path d="M60.3 144.4l1-.5 .5 .9-1 .5z"/>
<path d="M64.9 155.9l.9-.6 .6 .9-.9 .6z"/>
<path d="M63.6 154.2l.9-.7 .7 .9-.9 .6z"/>
<path d="M65.4 152.9l.9-.6 .6 .9-.9 .6z"/>
<path d="M66.7 154.7l.8-.6 .7 .8-.9 .7z"/>
<path d="M72.8 165.5l.8-.7 .7 .7-.8 .8z"/>
<path d="M71.3 163.9l.8-.7 .7 .8-.8 .7z"/>
<path d="M72.9 162.4l.8-.7 .7 .8-.8 .7z"/>
<path d="M74.4 164l.7-.7 .8 .8-.8 .7z"/>
<path d="M82.6 173.1l.8 .7-.7 .8-.8-.7z"/>
<path d="M80.9 171.7l.8 .7-.7 .8-.8-.6z"/>
<path d="M82.3 170l.8 .7-.7 .8-.8-.6z"/>
<path d="M83.9 171.4l.9 .7-.7 .8-.9-.7z"/>
<path d="M92.6 180.1l1 .5-.6 1-.9-.6z"/>
<path d="M90.8 178.9l.9 .6-.6 .9-.9-.5z"/>
<path d="M91.9 177.1l.9 .6-.5 .9-1-.6z"/>
<path d="M93.7 178.2l1 .6-.6 .9-.9-.5z"/>
<path d="M103.5 185.7l1 .4-.4 1-1-.5z"/>
<path d="M101.5 184.8l1 .4-.4 1-1-.4z"/>
<path d="M102.4 182.8l1 .4-.4 1-1-.4z"/>
<path d="M104.4 183.7l1 .4-.4 1-1-.4z"/>
<path d="M115.1 189.7l1.1 .3-.3 1-1.1-.3z"/>
<path d="M113 189.1l1.1 .3-.3 1-1.1-.3z"/>
<path d="M113.6 187l1 .3-.2 1-1.1-.3z"/>
<path d="M115.7 187.6l1 .3-.3 1-1-.3z"/>
<path d="M127.1 192.1l1.1 .2-.1 1-1.1-.1z"/>
<path d="M125 191.8l1 .2-.1 1-1.1-.1z"/>
<path d="M125.3 189.7l1 .1-.1 1.1-1.1-.2z"/>
<path d="M127.4 189.9l1.1 .2-.1 1.1-1.1-.2z"/>
<path d="M139.3 192.8h1.1v1.2h-1.1z"/>
<path d="M137.2 192.8h1.1v1.2h-1.1z"/>
<path d="M137.2 190.7h1.1v1.1h-1.1z"/>
<path d="M139.3 190.7h1.1v1.1h-1.1z"/>
<path d="M151.6 192l1.1-.2 .1 1.1-1.1 .1z"/>
<path d="M149.4 192.3l1.1-.2 .1 1.1-1 .1z"/>
<path d="M149.1 190.1l1.1-.2 .1 1.1-1 .2z"/>
<path d="M151.3 189.8l1.1-.1 .1 1-1.1 .2z"/>
<path d="M163.6 189.4l1-.3 .3 1-1 .3z"/>
<path d="M161.5 190l1-.3 .3 1-1 .3z"/>
<path d="M160.9 187.9l1-.3 .3 1-1 .3z"/>
<path d="M163 187.3l1-.3 .3 1-1 .3z"/>
<path d="M175.1 185.2l1-.4 .4 1-1 .4z"/>
<path d="M173.1 186.1l1-.4 .4 .9-1 .5z"/>
<path d="M172.2 184.1l1-.4 .5 1-1 .4z"/>
<path d="M174.2 183.2l1-.4 .4 1-1 .4z"/>
<path d="M185.9 179.5l1-.6 .5 1-.9 .5z"/>
<path d="M184.1 180.6l.9-.5 .6 .9-1 .6z"/>
<path d="M182.9 178.8l1-.6 .5 1-.9 .5z"/>
<path d="M184.8 177.7l.9-.6 .6 .9-.9 .6z"/>
<path d="M195.9 172.4l.8-.7 .7 .9-.8 .6z"/>
<path d="M194.2 173.8l.9-.7 .6 .8-.8 .7z"/>
<path d="M192.8 172.1l.9-.7 .7 .8-.9 .7z"/>
<path d="M194.5 170.7l.9-.7 .6 .9-.8 .6z"/>
<path d="M205.5 163.2l.8 .7-.7 .8-.8-.7z"/>
<path d="M204.1 164.8l.8 .7-.8 .8-.8-.8z"/>
<path d="M202.5 163.3l.8 .7-.8 .8-.8-.7z"/>
<path d="M204 161.7l.7 .7-.7 .8-.8-.7z"/>
<path d="M213.1 153.5l.9 .7-.6 .8-.9-.6z"/>
<path d="M211.9 155.3l.8 .6-.6 .9-.9-.6z"/>
<path d="M210.1 154.1l.9 .6-.7 .9-.9-.7z"/>
<path d="M211.3 152.3l.9 .6-.6 .9-.9-.6z"/>
<path d="M219.3 142.9l.9 .5-.4 1-1-.5z"/>
<path d="M218.3 144.9l.9 .5-.5 .9-.9-.5z"/>
<path d="M216.4 143.9l.9 .5-.5 .9-.9-.5z"/>
<path d="M217.4 141.9l.9 .6-.5 .9-.9-.5z"/>
<path d="M224 131.6l1 .4-.4 1-1-.4z"/>
<path d="M223.2 133.7l1.1 .3-.4 1-1-.3z"/>
<path d="M221.2 132.9l1 .4-.4 1-1-.3z"/>
<path d="M221.9 130.9l1 .4-.3 1-1-.4z"/>
<path d="M227.1 119.8l1 .2-.2 1-1.1-.2z"/>
<path d="M226.6 121.9l1.1 .2-.2 1.1-1.1-.3z"/>
<path d="M224.5 121.4l1.1 .3-.3 1-1-.2z"/>
<path d="M224.9 119.3l1.1 .2-.2 1.1-1.1-.2z"/>
<path d="M228.5 107.6l1.1 .1-.1 1.1-1.1-.1z"/>
<path d="M228.3 109.7l1.1 .1v1.1l-1.1-.1z"/>
<path d="M226.2 109.6l1.1 .1-.1 1.1-1.1-.1z"/>
<path d="M226.3 107.4l1.1 .1v1.1l-1.1-.1z"/>
<path d="M228.3 95.3l1.1-.1v1.1l-1.1 .1z"/>
<path d="M228.4 97.5l1.1-.1 .1 1.1-1.1 .1z"/>
<path d="M226.3 97.6h1.1v1.1h-1.1z"/>
<path d="M226.1 95.5l1.1-.1 .1 1.1-1.1 .1z"/>
<path d="M226.4 83.2l1.1-.2 .2 1.1-1.1 .2z"/>
<path d="M226.8 85.3l1.1-.2 .2 1.1-1 .2z"/>
<path d="M224.7 85.8l1.1-.2 .2 1-1.1 .2z"/>
<path d="M224.3 83.7l1-.3 .3 1.1-1.1 .2z"/>
<path d="M222.9 71.5l1-.4 .4 1-1.1 .4z"/>
<path d="M223.6 73.5l1-.3 .4 1-1 .3z"/>
<path d="M221.6 74.3l1-.4 .3 1-1 .4z"/>
<path d="M220.8 72.2l1-.4 .4 1.1-1 .3z"/>
<path d="M217.8 60.3l.9-.5 .5 1-.9 .5z"/>
<path d="M218.8 62.3l1-.5 .4 .9-.9 .5z"/>
<path d="M216.9 63.2l.9-.4 .5 .9-.9 .5z"/>
<path d="M215.9 61.3l.9-.5 .5 1-.9 .5z"/>
<path d="M211.2 50l.9-.7 .6 .9-.8 .7z"/>
<path d="M212.5 51.8l.9-.7 .6 .9-.9 .6z"/>
<path d="M210.7 53l.9-.6 .6 .9-.9 .6z"/>
<path d="M209.4 51.2l.9-.6 .7 .9-.9 .6z"/>
<path d="M203.3 40.6l.8-.7 .8 .8-.8 .7z"/>
<path d="M204.8 42.2l.8-.8 .7 .8-.8 .8z"/>
<path d="M203.2 43.7l.8-.8 .7 .8-.7 .8z"/>
<path d="M201.7 42.1l.8-.7 .8 .7-.8 .8z"/>
<path d="M194.9 31.6l.8 .7-.6 .8-.9-.7z"/>
<path d="M196.6 32.9l.8 .7-.7 .9-.8-.7z"/>
<path d="M195.2 34.6l.8 .7-.6 .9-.9-.7z"/>
<path d="M193.5 33.3l.9 .6-.7 .9-.9-.7z"/>
<path d="M184.6 24.6l1 .6-.6 .9-.9-.6z"/>
<path d="M186.5 25.7l.9 .6-.5 .9-1-.6z"/>
<path d="M185.4 27.6l.9 .6-.6 .9-.9-.6z"/>
<path d="M183.5 26.5l.9 .5-.5 .9-1-.5z"/>
<path d="M173.5 19.1l1 .4-.4 1-1-.4z"/>
<path d="M175.5 20l1 .4-.4 1-1-.4z"/>
<path d="M174.6 21.9l1 .5-.4 1-1-.5z"/>
<path d="M172.7 21.1l1 .4-.5 1-1-.4z"/>
<path d="M161.8 15.1l1 .3-.3 1.1-1-.3z"/>
<path d="M163.9 15.7l1 .3-.3 1.1-1-.3z"/>
<path d="M163.3 17.8l1 .3-.3 1.1-1-.3z"/>
<path d="M161.2 17.2l1 .3-.3 1.1-1-.3z"/>
<path d="M149.6 12.8l1 .2-.1 1.1-1.1-.2z"/>
<path d="M151.7 13.1l1.1 .2-.1 1.1-1.1-.2z"/>
<path d="M151.4 15.3l1.1 .1-.1 1.1-1.1-.1z"/>
<path d="M149.3 15l1 .1-.1 1.1-1.1-.1z"/>
<path d="M137.2 23.5h1.1v1.1h-1.1z"/>
<path d="M139.3 23.5h1.1v1.1h-1.1z"/>
<path d="M139.3 25.7h1.1v1.1h-1.1z"/>
<path d="M137.2 25.7h1.1v1.1h-1.1z"/>
<path d="M124.8 24.7l1-.1 .2 1-1.1 .2z"/>
<path d="M126.9 24.4l1.1-.2 .1 1.1-1 .2z"/>
<path d="M127.2 26.5l1.1-.1 .2 1-1.1 .2z"/>
<path d="M125.1 26.9l1.1-.2 .1 1.1-1 .1z"/>
<path d="M112.7 27.9l1-.3 .3 1-1 .3z"/>
<path d="M114.7 27.2l1.1-.3 .3 1-1 .4z"/>
<path d="M115.4 29.3l1-.3 .4 1-1.1 .3z"/>
<path d="M113.3 30l1.1-.4 .3 1-1 .4z"/>
<path d="M101.2 32.9l1-.5 .5 1-1 .5z"/>
<path d="M103.2 31.9l.9-.5 .5 1-.9 .5z"/>
<path d="M104.1 33.9l1-.5 .5 .9-1 .5z"/>
<path d="M102.2 34.8l1-.4 .5 .9-1 .5z"/>
<path d="M90.7 39.6l.9-.6 .6 .9-.8 .6z"/>
<path d="M92.5 38.4l.8-.7 .7 .9-.9 .7z"/>
<path d="M93.7 40.1l.9-.6 .7 .9-.9 .6z"/>
<path d="M92 41.4l.9-.6 .6 .9-.9 .6z"/>
<path d="M81.4 48l.7-.8 .8 .8-.8 .7z"/>
<path d="M82.9 46.4l.8-.7 .8 .7-.8 .8z"/>
<path d="M85.2 47.2l.8 .8-.8 .7-.7-.7z"/>
<path d="M82.9 49.5l.8-.8 .8 .8-.8 .8z"/>
<path d="M74.1 56.7l.9 .7-.7 .9-.8-.7z"/>
<path d="M75.4 55l.9 .6-.7 .9-.9-.6z"/>
<path d="M77.1 56.3l.9 .6-.6 .9-.9-.7z"/>
<path d="M75.9 58l.9 .7-.7 .8-.9-.6z"/>
<path d="M67.6 67.4l1 .5-.5 1-.9-.5z"/>
<path d="M68.6 65.5l1 .5-.5 1-.9-.5z"/>
<path d="M70.6 66.5l.9 .5-.4 .9-1-.4z"/>
<path d="M69.6 68.4l.9 .5-.4 1-1-.5z"/>
<path d="M62.9 79l1.1 .3-.4 1.1-1-.4z"/>
<path d="M63.6 76.9l1.1 .4-.4 1-1-.3z"/>
<path d="M65.7 77.6l1 .4-.3 1-1-.4z"/>
<path d="M65 79.7l1 .3-.3 1-1-.3z"/>
<path d="M60.1 91.2l1.1 .1-.2 1.1-1.1-.2z"/>
<path d="M60.5 89l1 .2-.1 1.1-1.1-.2z"/>
<path d="M62.6 89.4l1.1 .1-.2 1.1-1.1-.2z"/>
<path d="M62.3 91.5l1 .2-.1 1.1-1.1-.2z"/>
<path d="M59.2 103.6h1.1v1.1h-1.1z"/>
<path d="M59.2 101.5h1.1v1.1h-1.1z"/>
<path d="M61.4 101.5h1.1v1.1h-1.1z"/>
<path d="M61.4 103.6h1.1v1.1h-1.1z"/>
<path d="M60.3 116.1l1.1-.2 .1 1.1-1 .1z"/>
<path d="M59.9 113.9l1.1-.2 .2 1.1-1.1 .2z"/>
<path d="M62.1 113.6l1.1-.2 .1 1.1-1 .2z"/>
<path d="M62.4 115.7l1.1-.2 .2 1.1-1.1 .2z"/>
<path d="M63.3 128.2l1-.4 .4 1.1-1.1 .3z"/>
<path d="M62.6 126.1l1-.3 .4 1-1.1 .3z"/>
<path d="M64.7 125.5l1-.4 .3 1.1-1 .3z"/>
<path d="M65.4 127.5l1-.3 .3 1-1 .3z"/>
<path d="M68.2 139.7l.9-.5 .5 1-1 .5z"/>
<path d="M67.2 137.8l.9-.5 .5 .9-1 .5z"/>
<path d="M69.1 136.8l1-.5 .4 .9-.9 .6z"/>
<path d="M70.1 138.7l1-.5 .4 1-.9 .5z"/>
<path d="M74.7 150.3l.9-.6 .7 .8-.9 .7z"/>
<path d="M73.5 148.5l.8-.6 .7 .9-.9 .6z"/>
<path d="M75.2 147.3l.9-.7 .7 .9-.9 .6z"/>
<path d="M76.5 149l.9-.6 .6 .9-.9 .6z"/>
<path d="M82.9 159.7l.8-.7 .8 .7-.8 .8z"/>
<path d="M81.4 158.2l.7-.8 .8 .8-.8 .8z"/>
<path d="M82.9 156.7l.8-.8 .8 .8-.8 .7z"/>
<path d="M84.5 158.2l.7-.8 .8 .8-.8 .8z"/>
<path d="M93.1 166.9l.9 .6-.7 .9-.8-.6z"/>
<path d="M91.4 165.6l.8 .7-.6 .9-.9-.7z"/>
<path d="M92.6 163.9l.9 .6-.6 .9-.9-.6z"/>
<path d="M94.4 165.1l.9 .7-.7 .9-.9-.7z"/>
<path d="M103.7 173.3l.9 .5-.5 .9-.9-.5z"/>
<path d="M101.7 172.3l1 .5-.5 .9-1-.5z"/>
<path d="M102.7 170.3l1 .5-.5 1-1-.5z"/>
<path d="M104.6 171.3l1 .5-.5 1-1-.5z"/>
<path d="M115.1 177.9l1 .3-.3 1.1-1.1-.4z"/>
<path d="M113 177.2l1 .4-.3 1-1-.3z"/>
<path d="M113.7 175.2l1 .3-.3 1-1.1-.3z"/>
<path d="M115.7 175.8l1.1 .4-.4 1-1-.3z"/>
<path d="M127.1 180.7l1 .2-.1 1-1.1-.1z"/>
<path d="M124.9 180.4l1.1 .1-.2 1.1-1-.2z"/>
<path d="M125.3 178.2l1 .2-.1 1.1-1.1-.2z"/>
<path d="M127.4 178.6l1.1 .1-.2 1.1-1.1-.2z"/>
<path d="M139.3 181.6h1.1v1.1h-1.1z"/>
<path d="M137.2 181.6h1.1v1.1h-1.1z"/>
<path d="M137.2 179.4h1.1v1.1h-1.1z"/>
<path d="M139.3 179.4h1.1v1.1h-1.1z"/>
<path d="M151.6 180.5l1.1-.1 .2 1-1.1 .2z"/>
<path d="M149.5 180.9l1.1-.2 .1 1.1-1.1 .1z"/>
<path d="M149.1 178.7l1.1-.1 .2 1-1.1 .2z"/>
<path d="M151.3 178.4l1.1-.2 .1 1.1-1.1 .2z"/>
<path d="M163.6 177.6l1-.4 .4 1.1-1.1 .3z"/>
<path d="M161.5 178.2l1.1-.3 .3 1-1 .4z"/>
<path d="M160.8 176.2l1.1-.4 .3 1.1-1 .3z"/>
<path d="M162.9 175.5l1-.3 .4 1-1 .3z"/>
<path d="M174.9 172.8l1-.5 .5 .9-1 .5z"/>
<path d="M173 173.8l1-.5 .5 .9-1 .5z"/>
<path d="M172 171.8l1-.5 .5 1-1 .5z"/>
<path d="M173.9 170.8l1-.5 .5 1-1 .5z"/>
<path d="M185.4 166.3l.9-.7 .6 .9-.9 .7z"/>
<path d="M183.6 167.5l.9-.6 .6 .9-.8 .6z"/>
<path d="M182.4 165.8l.8-.7 .7 .9-.9 .7z"/>
<path d="M184.1 164.5l.9-.6 .6 .9-.9 .6z"/>
<path d="M194.7 158.2l.8-.8 .7 .8-.7 .8z"/>
<path d="M193.9 159l.8 .7-.8 .8-.7-.8z"/>
<path d="M191.6 158.2l.8-.8 .8 .8-.8 .8z"/>
<path d="M193.9 155.9l.8 .8-.8 .7-.7-.7z"/>
<path d="M203.3 147.9l.9 .6-.7 .9-.9-.6z"/>
<path d="M202 149.7l.9 .6-.7 .9-.8-.7z"/>
<path d="M200.2 148.4l.9 .6-.6 .9-.9-.6z"/>
<path d="M201.5 146.6l.9 .7-.6 .8-.9-.6z"/>
<path d="M209.5 137.3l1 .5-.5 .9-1-.5z"/>
<path d="M208.5 139.2l1 .5-.5 1-1-.5z"/>
<path d="M206.6 138.2l.9 .5-.4 1-1-.5z"/>
<path d="M207.6 136.3l.9 .5-.5 1-.9-.6z"/>
<path d="M214 125.8l1 .3-.3 1-1.1-.3z"/>
<path d="M213.3 127.8l1 .4-.3 1-1-.3z"/>
<path d="M211.2 127.2l1.1 .3-.4 1-1-.3z"/>
<path d="M211.9 125.1l1 .4-.3 1-1-.3z"/>
<path d="M216.6 113.7l1.1 .2-.2 1.1-1.1-.2z"/>
<path d="M216.3 115.9l1 .2-.1 1-1.1-.1z"/>
<path d="M214.1 115.5l1.1 .2-.2 1.1-1-.2z"/>
<path d="M214.5 113.4l1 .2-.2 1.1-1-.2z"/>
<path d="M217.3 101.5h1.1v1.1h-1.1z"/>
<path d="M217.3 103.6h1.1v1.1h-1.1z"/>
<path d="M215.1 103.6h1.1v1.1h-1.1z"/>
<path d="M215.1 101.5h1.1v1.1h-1.1z"/>
<path d="M216.1 89.2l1.1-.2 .1 1.1-1 .2z"/>
<path d="M216.4 91.3l1.1-.1 .2 1-1.1 .2z"/>
<path d="M214.3 91.7l1-.2 .2 1.1-1 .2z"/>
<path d="M214 89.5l1-.1 .2 1-1.1 .2z"/>
<path d="M213 77.3l1-.4 .3 1.1-1 .3z"/>
<path d="M213.6 79.3l1.1-.3 .3 1-1 .4z"/>
<path d="M211.6 80l1-.3 .3 1-1 .3z"/>
<path d="M210.9 78l1-.4 .4 1-1.1 .4z"/>
<path d="M208 66l1-.5 .5 1-1 .5z"/>
<path d="M209 67.9l1-.5 .5 1-1 .5z"/>
<path d="M207.1 68.9l.9-.5 .5 1-.9 .5z"/>
<path d="M206.1 67l1-.5 .4 1-.9 .4z"/>
<path d="M201.4 55.6l.8-.6 .7 .9-.9 .6z"/>
<path d="M202.6 57.4l.9-.7 .7 .9-.9 .7z"/>
<path d="M200.9 58.7l.9-.7 .6 .9-.9 .6z"/>
<path d="M199.6 56.9l.9-.6 .6 .8-.9 .7z"/>
<path d="M193.9 45.7l.8 .7-.8 .8-.7-.8z"/>
<path d="M194.7 48l.8-.8 .7 .8-.7 .7z"/>
<path d="M193.9 48.7l.8 .8-.8 .8-.7-.8z"/>
<path d="M191.6 48l.8-.8 .8 .8-.8 .7z"/>
<path d="M184.3 37.7l.8 .7-.6 .9-.9-.7z"/>
<path d="M186 39l.9 .6-.6 .9-.9-.6z"/>
<path d="M184.7 40.8l.9 .6-.6 .9-.9-.6z"/>
<path d="M183 39.5l.9 .6-.7 .9-.8-.6z"/>
<path d="M173.5 31.4l1 .5-.5 1-1-.5z"/>
<path d="M175.4 32.4l1 .5-.5 1-1-.5z"/>
<path d="M174.4 34.4l1 .4-.5 1-1-.5z"/>
<path d="M172.5 33.4l1 .5-.5 .9-1-.5z"/>
<path d="M161.9 26.9l1 .3-.3 1.1-1.1-.4z"/>
<path d="M163.9 27.6l1.1 .3-.4 1-1-.3z"/>
<path d="M163.3 29.6l1 .4-.4 1-1-.4z"/>
<path d="M161.2 29l1 .3-.3 1-1.1-.3z"/>
<path d="M149.6 24.2l1.1 .2-.1 1.1-1.1-.2z"/>
<path d="M151.8 24.6l1.1 .1-.2 1.1-1.1-.2z"/>
<path d="M151.4 26.7l1.1 .2-.1 1-1.1-.1z"/>
<path d="M149.3 26.4l1.1 .1-.2 1.1-1.1-.2z"/>
<path d="M137.2 34.8h1.1v1.1h-1.1z"/>
<path d="M139.3 34.8h1.1v1.1h-1.1z"/>
<path d="M139.3 37h1.1v1.1h-1.1z"/>
<path d="M137.2 37h1.1v1.1h-1.1z"/>
<path d="M124.7 36.2l1-.2 .2 1.1-1 .2z"/>
<path d="M126.8 35.9l1.1-.3 .2 1.1-1.1 .2z"/>
<path d="M127.2 38l1.1-.2 .2 1.1-1.1 .2z"/>
<path d="M125.1 38.4l1-.2 .2 1-1 .3z"/>
<path d="M112.6 40l1-.4 .4 1-1 .4z"/>
<path d="M114.6 39.2l1.1-.4 .4 1-1.1 .4z"/>
<path d="M115.4 41.2l1-.4 .4 1-1 .4z"/>
<path d="M113.4 42l1-.4 .4 1-1 .4z"/>
<path d="M101.5 45.9l.9-.6 .6 .9-1 .6z"/>
<path d="M103.3 44.7l.9-.5 .6 .9-.9 .6z"/>
<path d="M104.5 46.6l.9-.6 .6 .9-1 .6z"/>
<path d="M102.6 47.7l.9-.6 .6 1-.9 .5z"/>
<path d="M91.6 53.7l.8-.7 .7 .8-.8 .7z"/>
<path d="M93.2 52.2l.8-.7 .7 .8-.8 .7z"/>
<path d="M94.7 53.8l.8-.7 .7 .8-.8 .8z"/>
<path d="M93.1 55.3l.8-.7 .7 .8-.8 .7z"/>
<path d="M84 62.4l.9 .6-.7 .9-.9-.7z"/>
<path d="M85.3 60.6l.8 .7-.6 .8-.9-.6z"/>
<path d="M87 61.9l.9 .7-.7 .9-.8-.7z"/>
<path d="M85.7 63.7l.9 .6-.7 .9-.8-.7z"/>
<path d="M77.4 73.1l1 .5-.5 1-1-.5z"/>
<path d="M78.4 71.2l1 .5-.5 .9-1-.4z"/>
<path d="M80.3 72.2l1 .4-.5 1-.9-.5z"/>
<path d="M79.4 74.1l.9 .5-.4 .9-1-.4z"/>
<path d="M73 84.9l1 .3-.3 1.1-1-.3z"/>
<path d="M73.6 82.8l1 .3-.3 1.1-1-.3z"/>
<path d="M75.6 83.4l1.1 .3-.3 1.1-1-.3z"/>
<path d="M75.1 85.5l1 .3-.3 1-1-.2z"/>
<path d="M70.8 97.3l1 .1-.1 1.1-1-.1z"/>
<path d="M71 95.2h1l-.1 1.1-1.1-.1z"/>
<path d="M73.1 95.4l1.1 .1-.1 1-1.1-.1z"/>
<path d="M72.9 97.5l1.1 .1-.1 1.1-1.1-.1z"/>
<path d="M70.8 109.9l1.1-.1 .1 1.1-1 .1z"/>
<path d="M70.7 107.8l1-.1 .1 1-1 .1z"/>
<path d="M72.8 107.6l1.1-.1 .1 1-1.1 .1z"/>
<path d="M73 109.7l1.1-.1 .1 1.1-1.1 .1z"/>
<path d="M73.3 122.3l1-.3 .3 1-1 .3z"/>
<path d="M72.7 120.2l1-.3 .3 1-1 .3z"/>
<path d="M74.8 119.6l1-.3 .3 1.1-1 .2z"/>
<path d="M75.4 121.7l1-.3 .3 1-1.1 .3z"/>
<path d="M77.9 134l1-.5 .5 1-1 .5z"/>
<path d="M76.9 132.1l1-.5 .5 .9-1 .5z"/>
<path d="M78.9 131.1l1-.5 .4 1-.9 .5z"/>
<path d="M79.9 133l.9-.4 .5 .9-1 .5z"/>
<path d="M84.6 144.7l.9-.7 .6 .9-.8 .6z"/>
<path d="M83.3 142.9l.9-.6 .7 .9-.9 .6z"/>
<path d="M85.1 141.6l.8-.6 .7 .8-.9 .7z"/>
<path d="M86.4 143.4l.8-.7 .7 .9-.9 .6z"/>
<path d="M93.9 153.1l.8 .7-.7 .8-.8-.7z"/>
<path d="M92.3 151.7l.8 .7-.7 .8-.8-.7z"/>
<path d="M93.8 150.1l.8 .7-.7 .8-.8-.7z"/>
<path d="M95.4 151.5l.8 .8-.7 .8-.8-.8z"/>
<path d="M103.9 160.5l.9 .6-.6 .9-.9-.6z"/>
<path d="M102 159.4l1 .5-.6 1-.9-.6z"/>
<path d="M103.2 157.5l.9 .6-.6 .9-.9-.5z"/>
<path d="M105 158.7l1 .5-.6 .9-.9-.5z"/>
<path d="M115 165.9l1.1 .4-.4 1-1.1-.3z"/>
<path d="M113 165.2l1 .4-.4 1-1-.4z"/>
<path d="M113.8 163.1l1 .4-.4 1-1-.4z"/>
<path d="M115.8 163.9l1 .4-.4 1-1-.4z"/>
<path d="M127 169.2l1.1 .2-.2 1.1-1.1-.2z"/>
<path d="M124.9 168.8l1 .3-.2 1-1-.2z"/>
<path d="M125.3 166.7l1 .2-.2 1.1-1-.2z"/>
<path d="M127.4 167.1l1.1 .2-.2 1.1-1.1-.2z"/>
<path d="M139.3 170.3h1.1v1.1h-1.1z"/>
<path d="M137.2 170.3h1.1v1.1h-1.1z"/>
<path d="M137.2 168.1h1.1v1.1h-1.1z"/>
<path d="M139.3 168.1h1.1v1.1h-1.1z"/>
<path d="M151.7 169.1l1.1-.3 .2 1.1-1.1 .2z"/>
<path d="M149.6 169.4l1-.2 .2 1.1-1 .2z"/>
<path d="M149.2 167.3l1-.2 .2 1.1-1 .2z"/>
<path d="M151.3 166.9l1.1-.2 .2 1.1-1.1 .2z"/>
<path d="M163.6 165.6l1-.4 .4 1-1 .4z"/>
<path d="M161.6 166.3l1-.4 .4 1.1-1 .3z"/>
<path d="M160.8 164.3l1-.4 .4 1-1 .4z"/>
<path d="M162.8 163.5l1-.4 .4 1-1 .4z"/>
<path d="M174.6 159.9l1-.5 .5 .9-.9 .6z"/>
<path d="M172.8 161.1l.9-.6 .6 .9-.9 .6z"/>
<path d="M171.7 159.2l.9-.5 .6 .9-1 .5z"/>
<path d="M173.5 158.1l.9-.6 .6 1-.9 .5z"/>
<path d="M184.5 152.4l.8-.7 .7 .8-.8 .7z"/>
<path d="M182.9 153.8l.8-.7 .7 .8-.8 .7z"/>
<path d="M181.4 152.3l.8-.8 .8 .8-.8 .8z"/>
<path d="M183 150.8l.8-.7 .8 .8-.8 .7z"/>
<path d="M193.4 142.3l.9 .6-.7 .9-.8-.6z"/>
<path d="M192.1 144l.9 .7-.7 .8-.8-.6z"/>
<path d="M190.4 142.7l.9 .7-.7 .8-.9-.6z"/>
<path d="M191.7 141l.9 .6-.7 .9-.8-.7z"/>
<path d="M199.7 131.6l1 .5-.5 .9-1-.5z"/>
<path d="M198.7 133.5l1 .5-.5 1-1-.5z"/>
<path d="M196.8 132.6l1 .4-.5 1-1-.5z"/>
<path d="M197.8 130.6l.9 .5-.5 1-.9-.5z"/>
<path d="M203.9 119.9l1.1 .3-.4 1-1-.3z"/>
<path d="M203.3 122l1 .3-.3 1-1-.3z"/>
<path d="M201.2 121.4l1.1 .3-.3 1-1.1-.3z"/>
<path d="M201.8 119.3l1.1 .3-.3 1-1.1-.2z"/>
<path d="M205.9 107.7l1.1 .1-.1 1-1.1-.1z"/>
<path d="M205.7 109.8l1.1 .1-.1 1.1-1.1-.1z"/>
<path d="M203.5 109.6l1.1 .1-.1 1.1-1.1-.1z"/>
<path d="M203.7 107.5l1.1 .1-.1 1-1.1-.1z"/>
<path d="M205.6 95.2h1.1l.1 1-1.1 .1z"/>
<path d="M205.8 97.4l1.1-.1 .1 1.1-1.1 .1z"/>
<path d="M203.6 97.6l1.1-.1 .1 1.1-1.1 .1z"/>
<path d="M203.4 95.5l1.1-.1 .1 1-1.1 .1z"/>
<path d="M203 83.1l1-.3 .3 1.1-1 .3z"/>
<path d="M203.6 85.2l1-.3 .4 1.1-1.1 .3z"/>
<path d="M201.5 85.8l1.1-.3 .3 1.1-1.1 .2z"/>
<path d="M200.9 83.7l1.1-.3 .3 1.1-1.1 .3z"/>
<path d="M198.2 71.7l1-.5 .5 1-1 .4z"/>
<path d="M199.2 73.6l1-.5 .5 1-1 .5z"/>
<path d="M197.3 74.6l.9-.5 .5 1-.9 .4z"/>
<path d="M196.3 72.6l1-.4 .5 .9-1 .5z"/>
<path d="M191.5 61.3l.8-.7 .7 .9-.9 .6z"/>
<path d="M192.8 63l.8-.6 .7 .8-.9 .7z"/>
<path d="M191.1 64.3l.8-.6 .7 .8-.9 .7z"/>
<path d="M189.7 62.6l.9-.7 .7 .9-.9 .7z"/>
<path d="M183.6 51.5l.8 .7-.7 .8-.8-.7z"/>
<path d="M185.2 53l.8 .7-.7 .8-.8-.7z"/>
<path d="M183.8 54.6l.8 .7-.8 .8-.8-.7z"/>
<path d="M182.2 53.1l.8 .7-.8 .9-.8-.8z"/>
<path d="M173.4 44.2l.9 .5-.6 1-.9-.6z"/>
<path d="M175.2 45.3l.9 .6-.5 .9-1-.6z"/>
<path d="M174.1 47.1l.9 .6-.6 .9-.9-.5z"/>
<path d="M172.2 46l1 .6-.6 .9-.9-.6z"/>
<path d="M162 38.8l1 .4-.4 1-1-.4z"/>
<path d="M164 39.6l1 .4-.4 1-1-.4z"/>
<path d="M163.2 41.6l1 .4-.4 1-1-.4z"/>
<path d="M161.2 40.8l1 .4-.4 1-1-.4z"/>
<path d="M149.8 35.6l1 .3-.2 1-1-.2z"/>
<path d="M151.9 36l1.1 .2-.2 1.1-1.1-.2z"/>
<path d="M151.5 38.2l1.1 .2-.2 1.1-1.1-.3z"/>
<path d="M149.4 37.8l1 .2-.2 1.1-1-.2z"/>
<path d="M137.2 45.7h1.1v1.1h-1.1z"/>
<path d="M139.3 45.7h1.1v1.1h-1.1z"/>
<path d="M139.3 47.8h1.1v1.1h-1.1z"/>
<path d="M137.2 47.8h1.1v1.1h-1.1z"/>
<path d="M124.4 47.5l1.1-.3 .3 1.1-1.1 .2z"/>
<path d="M126.6 47l1-.3 .3 1.1-1.1 .2z"/>
<path d="M127 49.1l1.1-.2 .3 1-1.1 .3z"/>
<path d="M124.9 49.6l1.1-.3 .2 1.1-1 .3z"/>
<path d="M112.4 52.1l1-.5 .5 1-1 .4z"/>
<path d="M114.4 51.1l1-.4 .4 .9-.9 .5z"/>
<path d="M115.3 53.1l1-.5 .5 1-1 .5z"/>
<path d="M113.4 54l1-.4 .4 .9-.9 .5z"/>
<path d="M101.7 59.2l.9-.7 .7 .9-.9 .6z"/>
<path d="M103.4 57.8l.9-.6 .7 .8-.9 .7z"/>
<path d="M104.8 59.5l.8-.6 .7 .8-.8 .7z"/>
<path d="M103.1 60.9l.8-.7 .7 .9-.8 .7z"/>
<path d="M93.6 67.7l.8 .7-.7 .8-.8-.6z"/>
<path d="M94.9 66l.9 .7-.7 .8-.8-.6z"/>
<path d="M96.6 67.4l.9 .7-.7 .8-.9-.7z"/>
<path d="M95.3 69.1l.8 .6-.7 .9-.8-.7z"/>
<path d="M86.8 78.7l1 .4-.4 1-1-.5z"/>
<path d="M87.8 76.7l1 .5-.5 .9-1-.4z"/>
<path d="M89.7 77.6l1 .5-.4 1-1-.5z"/>
<path d="M88.8 79.6l1 .5-.5 .9-1-.4z"/>
<path d="M82.7 90.8l1.1 .3-.3 1-1-.2z"/>
<path d="M83.2 88.7l1 .3-.2 1-1-.2z"/>
<path d="M85.3 89.2l1.1 .3-.3 1-1-.2z"/>
<path d="M84.8 91.3l1.1 .3-.3 1-1-.2z"/>
<path d="M81.4 103.6h1.1v1.1h-1.1z"/>
<path d="M81.4 101.5h1.1v1.1h-1.1z"/>
<path d="M83.6 101.5h1.1v1.1h-1.1z"/>
<path d="M83.6 103.6h1.1v1.1h-1.1z"/>
<path d="M83 116.4l1-.3 .2 1.1-1 .3z"/>
<path d="M82.5 114.3l1-.3 .3 1.1-1.1 .2z"/>
<path d="M84.6 113.8l1-.3 .3 1.1-1.1 .3z"/>
<path d="M85.1 115.9l1-.2 .3 1-1.1 .3z"/>
<path d="M87.3 128.5l1-.5 .5 1-1 .5z"/>
<path d="M86.4 126.5l1-.5 .4 1-1 .5z"/>
<path d="M88.3 125.6l1-.5 .5 1-1 .5z"/>
<path d="M89.3 127.5l1-.4 .4 .9-1 .5z"/>
<path d="M94.3 139.3l.8-.7 .7 .9-.9 .6z"/>
<path d="M92.9 137.6l.8-.7 .7 .9-.8 .7z"/>
<path d="M94.6 136.2l.8-.6 .7 .8-.8 .7z"/>
<path d="M95.9 137.9l.9-.6 .7 .8-.9 .7z"/>
<path d="M104.1 147.5l.9 .6-.7 .9-.9-.7z"/>
<path d="M102.4 146.1l.9 .7-.7 .8-.9-.6z"/>
<path d="M103.8 144.4l.8 .7-.7 .8-.8-.6z"/>
<path d="M105.5 145.8l.8 .6-.7 .9-.8-.7z"/>
<path d="M114.9 154.1l.9 .4-.4 1-1-.5z"/>
<path d="M112.9 153.1l1 .5-.5 1-1-.5z"/>
<path d="M113.9 151.2l.9 .4-.4 1-1-.5z"/>
<path d="M115.8 152.1l1 .5-.5 1-1-.5z"/>
<path d="M126.8 158.1l1.1 .3-.3 1-1-.2z"/>
<path d="M124.7 157.6l1.1 .3-.3 1-1.1-.2z"/>
<path d="M125.2 155.5l1 .3-.2 1-1.1-.2z"/>
<path d="M127.3 156l1.1 .3-.3 1-1.1-.2z"/>
<path d="M139.3 159.4h1.1v1.1h-1.1z"/>
<path d="M137.2 159.4h1.1v1.1h-1.1z"/>
<path d="M137.2 157.2h1.1v1.1h-1.1z"/>
<path d="M139.3 157.2h1.1v1.1h-1.1z"/>
<path d="M151.9 157.9l1-.3 .3 1.1-1.1 .2z"/>
<path d="M149.8 158.4l1-.3 .3 1.1-1.1 .2z"/>
<path d="M149.3 156.3l1-.3 .3 1.1-1.1 .2z"/>
<path d="M151.4 155.8l1-.3 .3 1.1-1.1 .2z"/>
<path d="M163.7 153.6l1-.5 .5 1-1 .5z"/>
<path d="M161.8 154.5l1-.4 .4 .9-.9 .5z"/>
<path d="M160.8 152.6l1-.5 .5 1-1 .5z"/>
<path d="M162.8 151.6l1-.4 .5 .9-1 .5z"/>
<path d="M174.3 146.8l.9-.7 .7 .9-.9 .6z"/>
<path d="M172.7 148.1l.8-.6 .7 .8-.9 .7z"/>
<path d="M171.3 146.4l.8-.6 .7 .8-.8 .7z"/>
<path d="M173 145.1l.8-.7 .7 .9-.8 .6z"/>
<path d="M183.9 136.9l.8 .7-.7 .9-.8-.7z"/>
<path d="M182.5 138.6l.9 .7-.7 .8-.9-.6z"/>
<path d="M180.8 137.3l.9 .6-.7 .9-.9-.7z"/>
<path d="M182.2 135.6l.8 .6-.6 .9-.9-.7z"/>
<path d="M190.3 126l.9 .5-.4 1-1-.5z"/>
<path d="M189.3 128l1 .5-.5 1-1-.5z"/>
<path d="M187.4 127.1l.9 .4-.4 1-1-.5z"/>
<path d="M188.3 125.1l1 .5-.5 1-.9-.5z"/>
<path d="M194.1 114l1.1 .3-.3 1-1.1-.2z"/>
<path d="M193.6 116.1l1.1 .3-.3 1.1-1-.3z"/>
<path d="M191.5 115.7l1.1 .2-.3 1.1-1-.3z"/>
<path d="M192 113.5l1 .3-.2 1.1-1.1-.3z"/>
<path d="M195.1 101.5h1.1v1.1h-1.1z"/>
<path d="M195.1 103.6h1.1v1.1h-1.1z"/>
<path d="M193 103.6h1.1v1.1h-1.1z"/>
<path d="M193 101.5h1.1v1.1h-1.1z"/>
<path d="M193.4 89l1-.3 .3 1.1-1.1 .2z"/>
<path d="M193.8 91.1l1.1-.3 .3 1.1-1.1 .2z"/>
<path d="M191.7 91.6l1.1-.3 .2 1.1-1 .2z"/>
<path d="M191.3 89.5l1-.3 .3 1.1-1.1 .2z"/>
<path d="M188.8 77.2l1-.5 .5 1-1 .4z"/>
<path d="M189.8 79.1l1-.4 .4 .9-.9 .5z"/>
<path d="M187.9 80.1l.9-.5 .5 1-1 .4z"/>
<path d="M186.9 78.1l1-.5 .4 1-.9 .5z"/>
<path d="M181.8 66.7l.9-.7 .7 .9-.9 .6z"/>
<path d="M183.2 68.4l.8-.7 .7 .9-.8 .6z"/>
<path d="M181.5 69.7l.9-.6 .6 .8-.8 .7z"/>
<path d="M180.1 68.1l.9-.7 .7 .8-.9 .7z"/>
<path d="M173.3 57.2l.9 .6-.7 .9-.8-.7z"/>
<path d="M175 58.5l.9 .7-.7 .8-.9-.6z"/>
<path d="M173.7 60.2l.8 .7-.7 .9-.8-.7z"/>
<path d="M172 58.9l.8 .6-.7 .9-.8-.7z"/>
<path d="M162.3 50.7l.9 .4-.4 1-1-.5z"/>
<path d="M164.2 51.6l1 .5-.5 .9-1-.4z"/>
<path d="M163.3 53.6l1 .4-.5 1-1-.5z"/>
<path d="M161.3 52.6l1 .5-.5 1-1-.5z"/>
<path d="M150 46.7l1.1 .3-.3 1-1-.2z"/>
<path d="M152.1 47.2l1.1 .3-.3 1-1-.2z"/>
<path d="M151.6 49.3l1.1 .3-.3 1.1-1-.3z"/>
<path d="M149.5 48.9l1.1 .2-.3 1.1-1-.3z"/>
<path d="M137.2 57h1.1v1.1h-1.1z"/>
<path d="M139.3 57h1.1v1.1h-1.1z"/>
<path d="M139.3 59.1h1.1v1.1h-1.1z"/>
<path d="M137.2 59.1h1.1v1.1h-1.1z"/>
<path d="M125.3 59l1.1-.3 .2 1-1 .3z"/>
<path d="M127.4 58.4l1.1-.3 .2 1.1-1 .3z"/>
<path d="M128 60.5l1-.3 .3 1.1-1.1 .3z"/>
<path d="M125.9 61.1l1-.3 .3 1-1 .3z"/>
<path d="M114.3 64l1-.6 .5 1-.9 .5z"/>
<path d="M116.2 62.9l1-.6 .5 1-.9 .5z"/>
<path d="M117.3 64.8l1-.6 .5 1-.9 .5z"/>
<path d="M115.4 65.8l1-.5 .5 1-.9 .5z"/>
<path d="M105.1 71.6l.7-.7 .8 .7-.8 .8z"/>
<path d="M107.4 69.3l.7 .8-.7 .8-.8-.8z"/>
<path d="M108.9 70.9l.8 .7-.8 .8-.8-.8z"/>
<path d="M107.4 72.4l.7 .8-.7 .7-.8-.7z"/>
<path d="M98.6 80.5l.9 .5-.5 1-.9-.6z"/>
<path d="M99.7 78.6l.9 .6-.5 .9-.9-.5z"/>
<path d="M101.6 79.7l.9 .5-.5 1-1-.6z"/>
<path d="M100.5 81.6l.9 .5-.5 1-1-.6z"/>
<path d="M94.1 91.7l1.1 .2-.3 1.1-1-.3z"/>
<path d="M94.7 89.6l1.1 .3-.3 1-1.1-.3z"/>
<path d="M96.8 90.1l1.1 .3-.3 1.1-1.1-.3z"/>
<path d="M96.2 92.2l1.1 .3-.3 1.1-1.1-.3z"/>
<path d="M92.7 103.6h1.1v1.1h-1.1z"/>
<path d="M92.7 101.5h1.1v1.1h-1.1z"/>
<path d="M94.9 101.5h1.1v1.1h-1.1z"/>
<path d="M94.9 103.6h1.1v1.1h-1.1z"/>
<path d="M94.4 115.5l1.1-.2 .3 1-1.1 .3z"/>
<path d="M93.9 113.4l1-.2 .3 1-1.1 .3z"/>
<path d="M95.9 112.9l1.1-.3 .3 1-1.1 .3z"/>
<path d="M96.5 115l1.1-.3 .3 1-1.1 .3z"/>
<path d="M99.2 126.6l.9-.5 .5 .9-.9 .6z"/>
<path d="M98.1 124.7l.9-.5 .5 .9-.9 .6z"/>
<path d="M99.9 123.6l1-.5 .5 .9-.9 .6z"/>
<path d="M101 125.5l1-.5 .5 .9-.9 .5z"/>
<path d="M106.6 136.1l.8-.8 .7 .8-.7 .7z"/>
<path d="M105.8 133.8l.8 .7-.8 .8-.7-.8z"/>
<path d="M107.4 132.2l.7 .8-.7 .8-.8-.8z"/>
<path d="M108.9 133.8l.8 .7-.8 .8-.8-.8z"/>
<path d="M116.8 142.3l.9 .6-.5 .9-1-.5z"/>
<path d="M114.9 141.2l.9 .6-.5 .9-1-.5z"/>
<path d="M116 139.4l.9 .5-.5 1-1-.6z"/>
<path d="M117.9 140.5l.9 .5-.5 .9-1-.5z"/>
<path d="M127.7 146.7l1 .3-.2 1-1.1-.3z"/>
<path d="M125.6 146.1l1 .3-.2 1.1-1.1-.3z"/>
<path d="M126.2 144l1 .3-.3 1.1-1-.3z"/>
<path d="M128.2 144.6l1.1 .3-.3 1-1-.3z"/>
<path d="M139.3 148.1h1.1v1.1h-1.1z"/>
<path d="M137.2 148.1h1.1v1.1h-1.1z"/>
<path d="M137.2 145.9h1.1v1.1h-1.1z"/>
<path d="M139.3 145.9h1.1v1.1h-1.1z"/>
<path d="M151 146.4l1-.3 .3 1.1-1 .3z"/>
<path d="M148.9 147l1-.3 .3 1-1 .3z"/>
<path d="M148.3 144.9l1.1-.3 .2 1-1 .3z"/>
<path d="M150.4 144.3l1.1-.3 .2 1.1-1 .3z"/>
<path d="M161.8 141.8l.9-.6 .6 1-1 .5z"/>
<path d="M159.9 142.9l.9-.6 .6 1-1 .5z"/>
<path d="M158.8 141l1-.5 .5 .9-.9 .5z"/>
<path d="M160.7 139.9l.9-.5 .6 .9-1 .6z"/>
<path d="M171.8 133.8l.8 .7-.8 .8-.8-.8z"/>
<path d="M169.5 136.1l.8-.8 .7 .8-.7 .7z"/>
<path d="M168.7 133.8l.8 .7-.8 .8-.7-.8z"/>
<path d="M169.5 133l.8-.8 .7 .8-.7 .8z"/>
<path d="M178.6 124.2l1 .5-.6 1-.9-.6z"/>
<path d="M177.5 126.1l1 .5-.6 1-.9-.6z"/>
<path d="M175.6 125l1 .5-.6 .9-.9-.5z"/>
<path d="M176.7 123.1l1 .5-.6 1-.9-.6z"/>
<path d="M182.7 113.2l1.1 .2-.3 1.1-1.1-.3z"/>
<path d="M182.2 115.3l1 .2-.3 1.1-1-.3z"/>
<path d="M180.1 114.7l1 .3-.3 1-1-.3z"/>
<path d="M180.6 112.6l1.1 .3-.3 1-1.1-.3z"/>
<path d="M183.8 101.5h1.1v1.1h-1.1z"/>
<path d="M183.8 103.6h1.1v1.1h-1.1z"/>
<path d="M181.7 103.6h1.1v1.1h-1.1z"/>
<path d="M181.7 101.5h1.1v1.1h-1.1z"/>
<path d="M181.9 89.9l1-.3 .3 1-1 .3z"/>
<path d="M182.4 91.9l1.1-.2 .3 1-1.1 .3z"/>
<path d="M180.3 92.5l1.1-.3 .3 1.1-1.1 .3z"/>
<path d="M179.8 90.4l1-.3 .3 1.1-1 .3z"/>
<path d="M177 79.2l.9-.6 .6 1-1 .5z"/>
<path d="M178.1 81l.9-.5 .6 .9-1 .6z"/>
<path d="M176.2 82.1l.9-.5 .6 .9-1 .6z"/>
<path d="M175.1 80.2l.9-.5 .6 .9-1 .6z"/>
<path d="M169.5 70.1l.8-.8 .7 .8-.7 .8z"/>
<path d="M171 71.6l.8-.7 .8 .7-.8 .8z"/>
<path d="M169.5 73.2l.8-.8 .7 .8-.7 .7z"/>
<path d="M168 71.6l.7-.7 .8 .7-.8 .8z"/>
<path d="M160.4 62.3l1 .6-.6 .9-.9-.5z"/>
<path d="M162.3 63.4l1 .6-.6 .9-.9-.5z"/>
<path d="M161.2 65.3l1 .5-.6 1-.9-.5z"/>
<path d="M159.4 64.2l.9 .6-.5 .9-1-.5z"/>
<path d="M149.2 58.1l1 .3-.3 1.1-1-.3z"/>
<path d="M151.3 58.7l1 .3-.3 1-1-.3z"/>
<path d="M150.7 60.8l1 .3-.2 1-1.1-.3z"/>
<path d="M148.6 60.2l1 .3-.2 1.1-1.1-.3z"/>
<path d="M137.2 68.2h1.1v1.1h-1.1z"/>
<path d="M139.3 68.2h1.1v1.1h-1.1z"/>
<path d="M139.3 70.3h1.1v1.1h-1.1z"/>
<path d="M137.2 70.3h1.1v1.1h-1.1z"/>
<path d="M125.3 70.8l1.1-.4 .3 1.1-1 .3z"/>
<path d="M127.4 70.1l1-.4 .4 1-1.1 .4z"/>
<path d="M128.1 72.1l1-.3 .4 1-1 .3z"/>
<path d="M126.1 72.9l1-.4 .4 1-1.1 .4z"/>
<path d="M115.1 77.4l.9-.7 .6 .8-.8 .7z"/>
<path d="M116.8 76l.8-.7 .7 .8-.8 .7z"/>
<path d="M118.2 77.6l.8-.7 .7 .9-.8 .7z"/>
<path d="M116.5 79l.8-.7 .7 .9-.8 .7z"/>
<path d="M108.3 86.1l.9 .5-.5 1-.9-.6z"/>
<path d="M109.4 84.2l.9 .6-.5 .9-1-.5z"/>
<path d="M111.3 85.3l.9 .5-.5 1-1-.6z"/>
<path d="M110.2 87.2l.9 .5-.5 1-1-.6z"/>
<path d="M104.3 97.6l1.1 .1-.2 1.1-1.1-.2z"/>
<path d="M104.7 95.4l1.1 .2-.2 1.1-1.1-.2z"/>
<path d="M106.8 95.8l1.1 .2-.2 1-1-.1z"/>
<path d="M106.5 97.9l1 .2-.2 1.1-1-.2z"/>
<path d="M104.5 109.7l1.1-.2 .2 1.1-1.1 .1z"/>
<path d="M104.1 107.5l1.1-.1 .2 1-1.1 .2z"/>
<path d="M106.3 107.2l1-.2 .2 1.1-1 .1z"/>
<path d="M106.7 109.3l1-.2 .2 1.1-1.1 .2z"/>
<path d="M108.8 121l1-.5 .5 .9-.9 .6z"/>
<path d="M107.8 119.1l.9-.5 .5 .9-.9 .6z"/>
<path d="M109.6 118l1-.5 .5 .9-.9 .6z"/>
<path d="M110.7 119.9l1-.5 .5 .9-.9 .6z"/>
<path d="M117.5 129.3l.8 .7-.7 .9-.8-.7z"/>
<path d="M115.8 128l.8 .7-.6 .8-.9-.7z"/>
<path d="M117.2 126.3l.8 .7-.7 .8-.8-.7z"/>
<path d="M118.9 127.7l.8 .7-.7 .8-.8-.7z"/>
<path d="M127.7 135.1l1.1 .3-.4 1.1-1-.4z"/>
<path d="M125.7 134.3l1 .4-.3 1-1.1-.4z"/>
<path d="M126.4 132.3l1.1 .4-.4 1-1-.4z"/>
<path d="M128.5 133l1 .4-.4 1-1-.4z"/>
<path d="M139.3 136.9h1.1v1.1h-1.1z"/>
<path d="M137.2 136.9h1.1v1.1h-1.1z"/>
<path d="M137.2 134.7h1.1v1.1h-1.1z"/>
<path d="M139.3 134.7h1.1v1.1h-1.1z"/>
<path d="M150.9 134.7l1-.4 .4 1-1 .4z"/>
<path d="M148.8 135.4l1.1-.3 .3 1-1 .4z"/>
<path d="M148.1 133.4l1-.4 .4 1-1 .4z"/>
<path d="M150.2 132.7l1-.4 .3 1-1 .4z"/>
<path d="M161 128.7l.8-.7 .7 .8-.8 .7z"/>
<path d="M159.3 130l.8-.7 .7 .9-.8 .7z"/>
<path d="M157.9 128.4l.8-.7 .7 .8-.8 .7z"/>
<path d="M159.6 127l.8-.7 .7 .8-.8 .7z"/>
<path d="M168.9 118.6l1 .5-.6 1-.9-.6z"/>
<path d="M167.9 120.5l.9 .5-.6 1-.9-.6z"/>
<path d="M166 119.4l.9 .5-.5 1-1-.6z"/>
<path d="M167 117.5l1 .5-.6 1-.9-.6z"/>
<path d="M172.4 107.4l1.1 .1-.2 1.1-1.1-.2z"/>
<path d="M172 109.5l1.1 .2-.2 1-1-.1z"/>
<path d="M169.9 109.1l1.1 .2-.2 1.1-1.1-.2z"/>
<path d="M170.3 107l1 .2-.1 1-1.1-.1z"/>
<path d="M171.9 95.6l1-.2 .2 1.1-1.1 .2z"/>
<path d="M172.2 97.7l1.1-.1 .2 1-1.1 .2z"/>
<path d="M170.1 98.1l1.1-.2 .1 1.1-1 .2z"/>
<path d="M169.7 96l1.1-.2 .2 1.1-1.1 .1z"/>
<path d="M167.3 84.8l.9-.6 .6 1-.9 .5z"/>
<path d="M168.4 86.6l.9-.5 .6 .9-1 .6z"/>
<path d="M166.5 87.7l.9-.5 .6 .9-1 .6z"/>
<path d="M165.4 85.8l1-.5 .5 .9-.9 .6z"/>
<path d="M160 75.3l.8 .7-.7 .8-.8-.7z"/>
<path d="M161.7 76.7l.8 .7-.7 .8-.8-.7z"/>
<path d="M160.3 78.3l.8 .7-.7 .9-.8-.7z"/>
<path d="M158.6 76.9l.8 .7-.7 .9-.8-.7z"/>
<path d="M149.2 69.7l1 .4-.3 1-1.1-.4z"/>
<path d="M151.3 70.4l1 .4-.4 1-1-.3z"/>
<path d="M150.5 72.5l1 .4-.3 1-1-.4z"/>
<path d="M148.5 71.8l1 .3-.4 1-1-.3z"/>
<path d="M137.2 79h1.1v1.1h-1.1z"/>
<path d="M139.3 79h1.1v1.1h-1.1z"/>
<path d="M139.3 81.2h1.1v1.1h-1.1z"/>
<path d="M137.2 81.2h1.1v1.1h-1.1z"/>
<path d="M126.9 82.1l1-.5 .5 1-1 .5z"/>
<path d="M128.9 81.2l.9-.5 .5 1-1 .4z"/>
<path d="M129.8 83.1l1-.5 .5 1-1 .5z"/>
<path d="M127.8 84.1l1-.5 .5 1-1 .4z"/>
<path d="M119.7 88.5l.8 .7-.7 .8-.8-.7z"/>
<path d="M121 86.8l.9 .7-.7 .8-.9-.6z"/>
<path d="M122.7 88.2l.8 .6-.6 .9-.9-.7z"/>
<path d="M121.3 89.9l.9 .6-.7 .9-.8-.7z"/>
<path d="M115.2 98.3l1.1 .2-.3 1-1-.2z"/>
<path d="M115.7 96.1l1.1 .3-.3 1-1-.2z"/>
<path d="M117.8 96.6l1.1 .3-.3 1-1-.2z"/>
<path d="M117.3 98.7l1.1 .3-.2 1-1.1-.2z"/>
<path d="M115.5 109l1-.3 .3 1.1-1.1 .2z"/>
<path d="M115 106.8l1-.2 .3 1.1-1.1 .2z"/>
<path d="M117.1 106.4l1.1-.3 .2 1.1-1.1 .2z"/>
<path d="M117.6 108.5l1-.3 .3 1.1-1.1 .2z"/>
<path d="M120.3 118.5l.9-.7 .7 .9-.9 .7z"/>
<path d="M119 116.8l.8-.7 .7 .9-.8 .7z"/>
<path d="M120.7 115.5l.8-.7 .7 .8-.9 .7z"/>
<path d="M122 117.2l.9-.7 .6 .8-.8 .7z"/>
<path d="M129.3 124l1 .5-.5 1-.9-.5z"/>
<path d="M127.4 123.1l1 .4-.5 1-1-.4z"/>
<path d="M128.3 121.1l1 .5-.5 1-1-.5z"/>
<path d="M130.3 122.1l1 .4-.5 1-1-.5z"/>
<path d="M139.3 126h1.1v1.1h-1.1z"/>
<path d="M137.2 126h1.1v1.1h-1.1z"/>
<path d="M137.2 123.9h1.1v1.1h-1.1z"/>
<path d="M139.3 123.9h1.1v1.1h-1.1z"/>
<path d="M149.3 123.5l.9-.4 .5 1-.9 .4z"/>
<path d="M147.3 124.5l1-.5 .5 1-1 .5z"/>
<path d="M146.4 122.5l.9-.4 .5 .9-.9 .5z"/>
<path d="M148.3 121.6l1-.5 .5 1-1 .5z"/>
<path d="M157.8 116.1l.8 .7-.6 .9-.9-.7z"/>
<path d="M156.4 117.8l.9 .7-.7 .9-.8-.7z"/>
<path d="M154.7 116.5l.9 .7-.7 .8-.8-.7z"/>
<path d="M156.1 114.8l.9 .7-.7 .8-.9-.7z"/>
<path d="M161.6 106.6l1 .2-.2 1.1-1.1-.2z"/>
<path d="M161.1 108.7l1.1 .3-.3 1-1-.2z"/>
<path d="M159 108.2l1 .3-.2 1-1.1-.2z"/>
<path d="M159.5 106.1l1 .3-.2 1-1.1-.2z"/>
<path d="M160.9 96.4l1-.3 .3 1.1-1.1 .2z"/>
<path d="M161.3 98.5l1.1-.2 .2 1-1 .2z"/>
<path d="M159.2 99l1.1-.3 .2 1.1-1 .2z"/>
<path d="M158.7 96.9l1.1-.3 .2 1.1-1 .2z"/>
<path d="M155.8 87.5l.8-.7 .7 .9-.9 .6z"/>
<path d="M157.1 89.2l.9-.7 .6 .8-.8 .7z"/>
<path d="M155.4 90.5l.9-.6 .7 .8-.9 .7z"/>
<path d="M154.1 88.8l.8-.6 .7 .8-.9 .7z"/>
<path d="M147.8 80.7l1 .5-.5 .9-1-.4z"/>
<path d="M149.8 81.6l.9 .5-.5 1-.9-.5z"/>
<path d="M148.8 83.6l1 .5-.5 .9-1-.4z"/>
<path d="M146.9 82.6l.9 .5-.5 1-.9-.5z"/>
<path d="M137.2 90.6h1.1v1.1h-1.1z"/>
<path d="M139.3 90.6h1.1v1.1h-1.1z"/>
<path d="M139.3 92.8h1.1v1.1h-1.1z"/>
<path d="M137.2 92.8h1.1v1.1h-1.1z"/>
<path d="M127.7 97.3l1 .6-.6 .9-.9-.5z"/>
<path d="M128.8 95.4l1 .6-.6 .9-.9-.5z"/>
<path d="M130.7 96.5l.9 .5-.5 1-.9-.5z"/>
<path d="M129.6 98.4l1 .5-.6 1-.9-.6z"/>
<path d="M128.3 109.8l.9-.6 .6 1-1 .5z"/>
<path d="M127.2 107.9l.9-.5 .6 .9-1 .6z"/>
<path d="M129.1 106.8l.9-.5 .6 .9-1 .6z"/>
<path d="M130.2 108.7l.9-.5 .5 .9-.9 .5z"/>
<path d="M139.3 114.5h1.1v1.1h-1.1z"/>
<path d="M137.2 114.5h1.1v1.1h-1.1z"/>
<path d="M137.2 112.3h1.1v1.1h-1.1z"/>
<path d="M139.3 112.3h1.1v1.1h-1.1z"/>
<path d="M149.5 107.4l.9 .5-.5 1-1-.6z"/>
<path d="M148.4 109.2l1 .6-.6 .9-.9-.5z"/>
<path d="M146.5 108.2l1 .5-.6 .9-.9-.5z"/>
<path d="M147.6 106.3l.9 .5-.5 1-.9-.6z"/>
<path d="M147.9 96l.9-.6 .6 1-1 .5z"/>
<path d="M148.9 97.9l1-.6 .5 1-.9 .5z"/>
<path d="M147.1 98.9l.9-.5 .5 .9-.9 .6z"/>
<path d="M146 97l.9-.5 .6 1-1 .5z"/>
<path d="M139.3 101.5h1.1v1.1h-1.1z"/>
<path d="M139.3 103.6h1.1v1.1h-1.1z"/>
<path d="M137.2 103.6h1.1v1.1h-1.1z"/>
<path d="M137.2 101.5h1.1v1.1h-1.1z"/>
</g>
<g fill="none" stroke="#800000" stroke-width=".28">
<path d="M137.7 13.8a88.9 88.9 0 0 0-45.8 13.4M138.8 15.9a87.3 87.3 0 0 0-76.7 45.6M138.8 11.8a91.4 91.4 0 0 0-80.3 47.8M150.2 14.6a89.1 89.1 0 0 1 44 18.5M151.9 16.8l6.9 1.4M152.7 12.8a91.3 91.3 0 0 1 44.5 20.1M160.6 18.6a86.4 86.4 0 0 1 34 17.5M90.7 27.9a90 90 0 0 0-30.9 33.6M115.2 38.5a68.8 68.8 0 0 0-42.8 82.3M137.1 36.4l-2.4 .2a67.1 67.1 0 0 0-9.3 1.2M137.4 25.1a77.7 77.7 0 0 0-62.6 33.5M138.8 34.4a70.2 70.2 0 0 0-10.5 .7"/>
<path d="M138.8 23.1a79.8 79.8 0 0 0-64.1 32.1M138.8 27.2a75.6 75.6 0 0 0-60.7 30.4M138.9 38.5a68.3 68.3 0 0 0-9.9 .7M150 37.4l5.5 1.1 4.7 1.4M150.7 26l5.7 1.1 3.7 1M151.8 39.8a64.6 64.6 0 0 1 45.3 35.3M151.9 28.3a74.9 74.9 0 0 1 32.4 14M152.4 24.2a79 79 0 0 1 34.3 14.8M152.5 35.7a68.8 68.8 0 0 1 48.3 37.6M160.1 28.1h.1M160.1 28.1a76.6 76.6 0 0 1 23.7 11.3M186.7 39h.1"/>
<path d="M78.1 57.6h.1M112.9 41.7a66.7 66.7 0 0 0-37.9 80.7M112.9 41.7h.1M113.6 53.3a55.7 55.7 0 0 0-17.7 85.4M114.7 50.5a57.4 57.4 0 0 0-27.6 26.7 57.7 57.7 0 0 0 5.9 61.1M116.5 54.3a53.5 53.5 0 0 0-20.2 81.3M116.6 42.4a64.7 64.7 0 0 0-40.1 77.3M137.6 58.7a42.6 42.6 0 0 0-11.9 1.9M137.6 47.3l-1.7 .1a55.7 55.7 0 0 0-10.9 1.6M138.8 45.2a64.2 64.2 0 0 0-11.7 1.2M138.9 49.4l-5.5 .2-5.2 .8M139 56.5a49.3 49.3 0 0 0-18.2 3.7"/>
<path d="M149.6 59.9a48.2 48.2 0 0 1 17.9 9l2.1 2.1a31.3 31.3 0 0 1 7.1 8.8l2.3 3.9 1.6 3.7 .9 2.9M150.1 48.4a56.1 56.1 0 0 1 22.5 10.3M151.8 51a54.4 54.4 0 0 1 21.2 10.6M152.1 58.4a46.6 46.6 0 0 1 31.5 31M152.8 47a56.1 56.1 0 0 1 22.8 11.4M160.7 40.1a66.7 66.7 0 0 1 37.3 32.2M193.1 47.1a77.9 77.9 0 0 1 18.1 84.9M193.4 50.4a75.9 75.9 0 0 1 12.5 88.2M196.2 47.3a80 80 0 0 1 13.4 93.2M203.2 41.3a89.1 89.1 0 0 1 21.5 86.1M203.3 44.4a87.2 87.2 0 0 1 17.4 88.7M206.3 41.6a91.2 91.2 0 0 1 18.3 92.9"/>
<path d="M207.6 43.1h.1M53 71.7a91.6 91.6 0 0 0-1.7 57.6M54.3 74.5a89.2 89.2 0 0 0 19.4 89.6M56.9 73.1a87.1 87.1 0 0 0 17.4 88.6M68.5 64.9a80 80 0 0 0 12.4 93.4M68.5 69.3a78 78 0 0 0 15.9 89.6M72.1 66.9a75.9 75.9 0 0 0 11.7 88.4M116.2 62.3a45.5 45.5 0 0 0-17.1 16.7M118.9 61.1l-2.7 1.3M122.2 61.9a44.4 44.4 0 0 0-27.4 34.6 45.6 45.6 0 0 0-.4 7.8M127.7 69.5l-1.8 .5-7.3 4-3.9 3.2-5.9 7.2-2.4 4.5-2.1 6.7M137.6 69.9a51.7 51.7 0 0 0-10 1.9l-1.4 .6a51.5 51.5 0 0 0-8.8 5.2 59.4 59.4 0 0 0-7.1 8.4l-1.2 2.3-.9 2.4a33.2 33.2 0 0 0-2.2 7.5"/>
<path d="M138.9 78.5a24.5 24.5 0 0 0-23.7 18M138.9 72.1l-6.2 .6-5.9 1.8-6.1 3.4-3.2 2.5-5.4 6.6-2 3.8-1.8 5.7M139 60.7a42.6 42.6 0 0 0-42.5 41.3M139.1 67.8h-1.8l-7.8 1.2-1.8 .5M149 71.4a35.9 35.9 0 0 1 13.4 8.3 32.7 32.7 0 0 1 8.9 16.4M151 62.4a43.1 43.1 0 0 1 17.9 10.8 30.6 30.6 0 0 1 7.3 9.9l2.3 4.8 .8 2.3 .7 2.8M152.1 70.3l7.5 4.1 3.3 2.8 5.9 7.1 2.6 4.8 2.5 7.9M157 77.8l3.4 2.8 4.3 5.2 2.4 4.3 2.1 6.9M181.5 70.6a51.7 51.7 0 0 1 9.9 21.6M181.8 67.5l.1 .1a51.9 51.9 0 0 1 6.7 10.4l2.9 5.4v1a55.9 55.9 0 0 1-27.5 68.4M184.7 67.9a59.9 59.9 0 0 1 10.7 22.7M131.7 81.7a22.5 22.5 0 0 0-15.1 17.4"/>
<path d="M137.6 80.6a21.6 21.6 0 0 0-5.5 1M138.9 82.6a20.2 20.2 0 0 0-19.6 14.9M139.9 92.2a10.9 10.9 0 0 0-10.6 5.4 10.9 10.9 0 0 0 .7 11.9M139.9 94.5l-1.1-.3-3.5 .7-2.8 1.9-1.9 2.8-.7 3.4 .8 3.5M140.1 90.2l-1.4-.3-4.5 .9-4.9 3.3-2.4 3.5-1.1 5.4 1.1 5.5M146.9 99.5l.7 3.5-.7 3.5-1.9 2.8-2.8 1.9-3.4 .7-1-.2M147.6 96.6a10.9 10.9 0 0 1-7.7 17.3M147.6 82.4a22.9 22.9 0 0 1 12.5 12.8l.5 1.9M148.6 85.4l2.9 1.6 1.3 1.1 3.6 4.4 .6 1 1.9 6.2M150.6 81.6a23.8 23.8 0 0 1 12.5 16.6M150.7 97.5l1.1 5.5-1.1 5.7-2.1 3.1-5.3 3.5-4.5 .9-1.2-.2M191.4 92.2a53.5 53.5 0 0 1-30.3 59.6"/>
<path d="M191.4 92.2h.1M195.5 91.4a57.9 57.9 0 0 1-32.7 64.3M201.2 86.4a64.6 64.6 0 0 1-40.1 77.3M202.6 83.7a65.4 65.4 0 0 1 2.8 16M205.2 85.3a68.7 68.7 0 0 1-42.5 82.3M205.4 99.7h.1M205.4 99.7a66.6 66.6 0 0 1-41.4 65.1M93.6 114a46.4 46.4 0 0 0 25.1 31.3l6.9 2.5M96.1 115.7a40.2 40.2 0 0 0 2.7 7.1 41.3 41.3 0 0 0 8.7 12 34 34 0 0 0 9.9 7.3l4.2 2.3 6.7 2M97.6 113.1a40.8 40.8 0 0 0 11.4 20.2 25.9 25.9 0 0 0 7.7 6l4.3 2.5 5.4 2M104.1 111.3l1.6 5 2.8 5.1 6.5 7.9 3 2.5 7.7 4.2M106.3 110a36.5 36.5 0 0 0 4.4 10.6"/>
<path d="M108.1 108.7l2 6.6 1.3 2.3 1.2 2.2 4.5 5.6M114.7 108.2a24.9 24.9 0 0 0 10.4 15.5l2.2 1.2M117.2 109.3a20 20 0 0 0 4.9 9 20.4 20.4 0 0 0 8 5.6M118.7 107.3l1.1 3.6M119.8 110.9a21.2 21.2 0 0 0 6.9 8.8l2.4 1.2M119.8 110.9l.3 .6M126.9 108.5l2.3 3.5M126.9 108.5h.1M158.2 108.6l-1.4 4.6a25 25 0 0 1-9.9 8.7l-5.3 1.6h-2.7M160.4 115.1a25.9 25.9 0 0 1-11.9 10.8l-4.6 1.5-5 .5M161 107.2l-1.3 5-.7 1.5-3.3 4.3-4.3 3.9-6.3 3.1a13.3 13.3 0 0 1-4.9 .6M162.5 110.1l-.7 2.4-.9 1.6"/>
<path d="M169.4 109.5l-1.8 5.8-2.9 5.3-3.8 4.6-4.6 3.8-5.3 2.9-5.8 1.8-6.3 .6M171.8 107.8a33.1 33.1 0 0 1-31.7 28.5M173.4 110.4l-2.2 7.3-2.2 4.1-6.1 7.5-2 1.6-1 .8-8 4.4-5.9 1.8-6.7 .7M181.3 104.2l-.3 5.1-2.3 9-1.7 3.6-2.2 3.6M183.4 103.3l-.1 5.4a76.1 76.1 0 0 1-3.3 12.1l-5.4 9.4a52.9 52.9 0 0 1-18.8 14.3 78.8 78.8 0 0 1-11.1 2.9l-4.7 .2M52.5 132.8a90.6 90.6 0 0 0 18.7 31.7M76.7 132.5a68.7 68.7 0 0 0 48.3 37.9M79.6 133.8l2.2 3.8M80.6 130.9a64.6 64.6 0 0 0 45.4 35.4M81.9 137.9l.1 .1M82 137.9a66.6 66.6 0 0 0 34.9 28.2M114.6 125.7l2 2.1 1.7 1.4"/>
<path d="M117.1 125.4l4.4 3.6 5.3 2.9M117.1 125.4h.1M124.2 132.9l4.3 1.8M166.7 135.1l-2 1.8-7.6 4.6-5.8 2.2-5.7 1.4-4 .2M174.9 125.5l-1.9 3.1-4.2 4.6-1.9 1.7M178.8 127.5a46.5 46.5 0 0 1-39.7 22.4M211.2 132h.1M211.2 132l-2.5 5.5M224.7 127.5l-1.5 4.5M101.5 147.3a57.5 57.5 0 0 0 23.4 11.9M104.5 144.3a54.6 54.6 0 0 0 21.2 10.7M104.9 147.4a55.9 55.9 0 0 0 22.4 10.3"/>
<path d="M149.7 155.6l-5.3 .8-5.5 .3M150.8 159.7a69.9 69.9 0 0 1-12 1.2M151.6 157.4a52.9 52.9 0 0 1-11.6 1.4M199.6 148.5a75.7 75.7 0 0 1-61.9 30.4M199.6 148.5h.1M202.5 148a77.8 77.8 0 0 1-62.4 33M202.8 151.1a79.7 79.7 0 0 1-65 32M215.6 144.3a87.2 87.2 0 0 1-67.9 45.5M218.5 143.2a89.3 89.3 0 0 1-72.8 48.9M219.4 146.1a91.3 91.3 0 0 1-69.6 47.6M80.8 173.6a91.1 91.1 0 0 0 44.1 19.7M83.3 170.3a90.1 90.1 0 0 0 19 12"/>
<path d="M83.7 173.3a87.5 87.5 0 0 0 23.7 13.3M90.9 167.2a78.9 78.9 0 0 0 34.1 14.7M93.4 163.9a75.3 75.3 0 0 0 31.6 13.8M93.7 166.6a77.4 77.4 0 0 0 33.2 13.5M117.4 166.2a67.1 67.1 0 0 0 10.2 2.6M149.6 166.7l-.9 .2a60.1 60.1 0 0 1-10.9 .7M150.3 170.9l-1 .1a74.1 74.1 0 0 1-11.6 .8M152.2 168.4a68.2 68.2 0 0 1-12.3 1.3M103.1 182.6a87.9 87.9 0 0 0 22.4 6.7M107.7 186.8l2 .7M109.7 187.5h.1M110.1 187.6a88.7 88.7 0 0 0 17.3 4"/>
<path d="M140.1 192.3h1M148.4 193.9l-4.9 .4-4.7 .1"/>
</g>
<g fill="none" stroke="#800000" stroke-width=".3">
<path d="M104.2 18.6l-.4 1.2M113.4 16.4l-3.6 1.2M114.4 17.2l-.4 .5v.8M116.1 17.9l.9 .7M116.7 14.5l-1.2 1.3M125.4 13.7l-2.7 .5M126.4 14.7l-.7 .7v.5M127.9 15.6l1.3 .8M129.2 12.3l-1.6 1.1M134 11.9l.1 1.2M137.7 13.8v1.1M138.8 11.8l1.1 1"/>
<path d="M139.9 14.9l-1.1 1M141.5 11.1v2.7h-2.5l-1.3-1M144.7 13l5.3 .4M150.2 14.6h.1M150.2 14.6l-.5 1M151.9 15.9v.9M152.7 12.8l-.5 .9M156.4 14.5l5.7 1.3M158.8 18.2l1.8 .4M161.8 16.8l-.3 1.1M163.6 18.5l-.2 .9M164.5 15.5l-.3 .9"/>
<path d="M167.8 17.5l6 2.3M176.2 19.8l-.4 .9M73.6 39.2l-.1 1.4M81 33.7l-1.7 1.5M82.2 34.1l-.2 .1v.9l.3 .3M83.1 30.7l-.4 1.6M86 33.7l-2 .3M90.6 28h1.1l.4 .3M91 26.5l-4.9 3.3M91.5 39.8l-4.8 3.7-.6 .7M91.9 27.2v.9M92.8 37.6l.4 .9"/>
<path d="M93.1 24.1l-.3 1.2M96 27.1l-2.1 .1M101.6 34.5l1.4 .6M101.8 20.7l-2.9 1.4M102 33.1l-4.7 2.7M102.1 21.7l.6 .1v.8M103 31.5l.9 .7M104.7 21.8l1.2 .5M104.9 34.1l.5 .8M112.5 29.7l1.5 .6M113.3 28.2l-5.9 2.3M115.2 38.5l.2-.1-.1 1.1"/>
<path d="M115.2 26.6l.2 1M116.1 29.6l.1 1M121.5 38.6l-6.5 2.2-1.7-.5M123.2 35.1l2.1 1.6M124.9 26.4l.8 .9M125.4 25.2l-6 1.4M125.4 37.8l.3 1M127.7 23.9l-.2 .9M127.8 38.4l1.2 .8M127.9 27v1M128.3 35.1l-.9 1.2M129.1 27.8h.1"/>
<path d="M130.3 39.1h.2M131.9 23.4l-1 .1M132.1 34.7v.5M133.3 25.3l-1 .1M133.5 36.6h-.2M137.1 36.4l.6 1.1M137.4 25.1l.3 1.1M137.7 24l1.1 1 5.2 .1M138.8 31.4l2.2 2.2v2.5l-.3 .3h-1.9l-1.1-1.1M138.8 34.4l1.1 .9M138.8 23.1l1.1 .9M139.9 37.5l-1 1"/>
<path d="M139.9 26.2l-1.1 1M150 37.4l-.2 1M150.2 36.3l-1.3 1-1.5 .4M150.3 23.2l-.2 1.6M150.7 26l-.9 1M151.9 27.3v1M151.9 38.8l-.1 1M152.4 24.2l-.1 1M152.5 35.7l-.2 1M157.9 26.4h-.1l4.4 1.2M158.7 37.3h.2M160.1 28.1l-.2 1.1"/>
<path d="M160.7 38.9l1.6 .6M161.8 28.6l-.3 1M163.6 30.3l-.3 .9h-.1M164.7 39.4l-.4 .9M164.7 27.4l-.4 .8M169.1 30.2l4.6 2M173.2 33.1l-.5 1M173.4 20.8l-.2-.1-.3 1.1M174.2 36h.1M174.7 35.1l-.5 .9M174.9 22.6l-.4 .9h-.1M176.1 32.3l-.4 .8"/>
<path d="M180.4 35.9l4 2.6M181.5 23.5l3.3 1.8M183.8 39.4l-.7 .9M184.2 26.2l-.5 1M185.5 28.3l-.6 .8M186.6 36.8l-.7 1.6M186.7 39l-.6 .8M187.3 25.7l-.6 .8M192.2 28.9l.1 .2M194.2 33.1l-.6 .9M195 32.3l.3 1.7 2.4 1.9M195.3 35.4l-.7 .7"/>
<path d="M197.2 32.9l-.5 .8M58.5 59.6l.6 1M64.4 51.9l-2.3 3.7M65.3 49l.3 1.1M65.6 52v.6l.6 .5M68.9 51l-1.5 .4M72.1 42.2l-3.2 3.8M73.7 42.1l-.1 1.6M74.2 57.5l-2.9 4.9M74.8 58.6l.9 .1M75.5 55.8l-.8-.6-2.9 1M75.7 58.7l.3 .1"/>
<path d="M75.7 58.7l-1.1 1.4-2.6 4-1.8-1-.3-.7-3.1-1.8M77.1 41.4l-2 .7M77.3 57l2 1.4-1.7 2.2M82.1 48l-3.3 3.8M82.4 49.3l1.3 .2M83.6 45.1l.1 1.3M85.2 48l1.4 .1M91.8 40.9l1 .6M92.4 53.7l-1.2 1.1M92.4 55.3l1.4 .1M93.1 51.8l.9 .5M94.5 40.3l.3 1"/>
<path d="M95.4 53.9l.6 .9M101.5 47.8l1.9 .1M102.2 46l-1.8 1.4M102.5 59.3l-1.1 .9M103.2 44.3l.9 .6M103.7 57l.5 .9M105.2 46.8l.4 .9M105.6 59.6l.7 .9M112.9 41.7l1.2 .6M113.6 53.3l.5 1M114.7 50.5l.4 .9M116.1 53.3l.4 1"/>
<path d="M116.1 41.5l.5 .9M117.4 51.5l-2.7 1.3-1.5-.5M125 49l.6 1M125.1 47.9l-2.5 .5M127.1 46.4l.1 1M127.7 49.5l.5 .9M127.8 58l.3 .8M132 45.7v.4l-.3 .3M132.9 56v.5l.5 .4M136 58.7l-.4 .1M137.6 58.7l.1 1M137.6 47.3l.1 1.1"/>
<path d="M137.7 46.2l1.2 1.1h2.3M138.8 53.3v.4l2.4 1.8v2.8l-.3 .3h-2l-1.2-1.1M138.8 45.2l1.1 1M139 56.5l.9 1M139.9 48.4l-1 1h3.7M139.9 59.7l-.9 1M142 59.6l-.2-.1v1.3l-3-.1M143.9 46.9h2.3l4.2 .5M147 54l3.5 .7-.9 4.1M149.6 59.9l-.6 1M150.1 48.4l-.2 1.1M152 50l-.2 1"/>
<path d="M152.1 58.4l-.4 1M152.8 47l-.3 .9M160.6 50.6l1.9 .8M160.7 40.1l-.5-.2-.2 1M162 40.6l-.5 .9M162 52.3l-.4 1M163.5 42.3l-.3 .9M163.5 54.3l-.4 .9M164.7 51.4l-.2 .9M165.4 56.5l.3 .1M171.1 43.4l2.4 1.5M171.2 47.2l-.3 .4"/>
<path d="M172.6 58.7l-.5 .9M173 45.8l-.6 1M174.3 47.9l-.5 .9M175.6 58.4l-.5 .9M176 45.3l-.6 .7M179.3 55.4l.9 .8-4.4 5.1-2-1.6-.4-1.8M181.8 50.7l1.9 1.6M183 53.1l-.8 .8M183.8 55.4l-.7 .6M184.9 41.5l-.6 .8M185.9 53l-.6 .7M189.8 42.8l4.1 3.6"/>
<path d="M193.1 47.1l-.7 .9M193.9 49.5l-.5 .9M196.2 47.3l-.7 .7M201.2 56.3l-.8 .7M201.6 58.8l-.7 .6M203.2 41.3l-.7 .8M204 43.7l-.7 .7M204.1 56.9l-.7 .6M206.3 41.6l-.7 .6M207.6 43.1l-.7 .7M210.5 48.2l1.5 1.9M211 50.7l-.8 .7"/>
<path d="M211.5 53.1l-.9 .6M214.1 51.5l-.9 .4M217.7 59l.8 1.6M51.4 76.8l.6 .1M52.9 70.3l2.7 .9-.8 1.9-1.5 .8M53 71.7l.2 .1h.9M54.3 74.5h.9l.2 .1M56.1 72.5h.2l.6 .6M58.1 62.5l-1.5 3.5M59.8 61.5l-.1 .5 .3 .4v1.1M62.1 61.5l-1.1 .1M63.2 77l.8 .6"/>
<path d="M63.3 79.7l-1.3 5.1M63.4 71.6l1.5 .7M64.4 79.9l1 .5M67.1 78.3h-1.1M67.9 68.2l-2.1 4.7M68.5 64.9l.4 1.3M68.5 69.3h.1M69.8 69.2l-1.2 .1M71.1 64.4l-2.5 4.9M71.1 64.3v.1M71.1 64.3l2.6 1.4M72.4 66.1h.1l-.4 .8-1.3 .3"/>
<path d="M77.7 73.9l-1 2M77.9 71.2l.7 .7M79.6 74.8l-1.5 .7M80.6 72.9l1 .2M84.1 63.1l-1 1.4M85 60.3l.4 1.1M85.8 64.4l-1.2-.2-.2 .3M87.1 79.4l-1.2 3M87.1 62.7l.9 .6-.9 1.1M88 77.4l-.9-.3-1.4 2.9M88.1 79.8l.9 .5M90 78.4l1 .5"/>
<path d="M93.7 68.5l-1 1.4M94.2 66.3l.8 .5M94.5 69.2l.9 .6M96.7 68.1l.9 .6M99.9 79.4l-.8-.4-1.5 .7-1.2 2.4M103.2 60.1l.7 .9M105.8 71.6l-.8 1.2M106.5 72.6l.9 .6M106.7 69.6l.7 .5M108.9 71.6l.7 .9M115.1 64.2l-1.5 .9M115.4 65.3l.8 .8"/>
<path d="M115.9 77.4l-1.1 1.2M116.2 62.3l.1 .1M116.2 62.4h.1M116.3 62.4l.7 .7M116.4 78.6l.9 .5M117 75.4l.5 .7M118 65l.5 .9M118.9 77.7l.7 1M120.8 60.2h-1.8l-.1 .9M124.1 61.4l-2.3-.2-1.9 .5M125.7 60.6l-.6 1.7-1.6 .5-1.3-.9M125.9 60.5l.6 .9"/>
<path d="M126 71.1l-1.3 .9M126.2 72.4l.6 .8M127.7 69.5l.4 .9M128.6 60.9l.5 1M128.8 72.5l.4 1.3M137.6 69.9l.1 1M137.6 65.9l3.3 1.1 .1 2.4-.5 .5h-1.6l-1.2-1.2M137.7 79.6l1 1h2.3l-.8 8.8 1.6 .4-.3 1.4M138.9 78.5l1 1.1M139.1 67.8l.8 .9M139.9 70.9l-1 1.2M141.9 69.2v-.3l1.1 .1a27.7 27.7 0 0 1 6.5 1.4"/>
<path d="M144.7 79.9l1.3 .6M149 71.4l-.2 1.1M150.9 73.2l.1 1.3 3.5 1.6 2.5 1.7M151.1 61.4l-.1 1M152.1 70.3l-.5 .8M158.8 75.2l1.3 .9M159.2 62.2l1.5 .9M159.2 76.9l-.5 .8M160.1 66.4l-.4 .7M160.3 79.1l-.7 .8M160.4 64.2l-.8 .8M161.4 66.1l-.5 .8"/>
<path d="M162.5 76.8l-.8 .6M163 63.3l-.5 .9M167.8 67.9l2.5 2.2M169.6 71l-.9 .6M170.3 73.2l-.8 .6M172.4 70.7l-.6 .9M173.8 61l-.8 .6M176.7 79.8l-.8 .7M176.8 62.1l4.2 4.4 1.6 .3M176.9 77.8l.8 1.6M181.8 67.5l-.9 .6M182.3 69.8l-.8 .8"/>
<path d="M183.7 73.5l-1.3 .8M184.7 67.9l-.7 .6M188 74.7l1.6 2.7M188.6 78l-1 .4M191.2 61.9l-.7 .8M191.4 60.3l.8 1.1M191.4 79.1l-.9 .3M191.8 64.4l-.8 .6M194.3 62.5l-.8 .6M195.7 68.1v.3M197 75.1l-.2 .9M198 72.3l-1 .6"/>
<path d="M198 74.8l-.9 .3M199 71.9l-.3 1.9 .9 1.6M200.8 73.3l-.9 .6M206.1 61.5l2.6 4.7M207.8 69.2l-.9 .5M207.8 66.8l-1 .4M210.6 67.7l-.9 .5M211.8 72.9l1.9 4.7M212.6 77.8l-1 .5M215.3 79.4l-1 .3M217.6 61.1l-1 .5M217.6 63.5l-.9 .4"/>
<path d="M220.4 62.1l-.9 .4M221.2 74.6l.2 .4 .8-.4M222.3 68.6l1.3 3.2M222.6 72.2l-1.1 .3M225.3 73.6l-1 .3M47.9 94.8l.9 1M48.6 98l-.2 5.4 .1 2.4M49.6 83.6l1 .1M49.7 97.6l.6 .5h.5M50.1 85.8l-.4 2.7M51.1 94.2l.9 .1M51.4 85.1v.2l.9 .9"/>
<path d="M52 94.8l-1.1 1.2M53.7 83.9h-.8l-.2 .2M60 89.3l.9 .3M60.6 91.8l-.5 3.5-.2 2.5M61.6 92.1h1.1M64.3 88.4l-.2 1.5-1 .1M70.6 94.7l.8 1.1M71.2 97.9v2.2M73.2 82.6l.7 .9M73.3 85.6l-.8 4.1M73.4 98.1l-1.1 .8M73.6 95.9l1 .4"/>
<path d="M75.4 86.2l-1.2 .2M77.2 83.9l-1.2 .2M82.7 89.3l.9 .1M83.1 91.5l-.3 2.1M84.2 91.7l1 .3M85.7 89.9l1.1 .2M95.6 92.7l1 .2M96.2 85.7l-1.2 1-1 2.9-.3 1.2 .8 1.5M96.4 82.1a44.8 44.8 0 0 0-4.9 18.2l.9 1.5 .9 .2M96.4 82.1l-.6 1 2.1 1-1.1 2.6-1 1.3-.7 2.2M97.2 90.8l1 .4M98.8 81.2l-.8 1.5"/>
<path d="M99.8 81.7l.9 .6M101.8 80.5l.9 .6M104.3 95.6l.8 .4M104.3 95.6h.1M104.6 94.2l-.1 .7M104.8 98.2l-.2 1.4 9.7 1.1 .1-.5M106 98.2l.9 .4M107.3 96.4l1 .1 .3 2.3M108.2 90.6v.1M108.5 86.8l-.8 1.6M108.8 84.4l.8 .6M109.5 87.6l.9 .3"/>
<path d="M109.5 87.6h.1M111.5 86l.9 .6M113 98.3l2.6 .6a24.2 24.2 0 0 0 .3 5.8l-22.1 .7-.5-.5v-.7M115.2 96.5l.5 .2M115.7 96.7l.4 .1M115.7 96.7l-1.3 .1M116.6 99.1l1.2 .3M118.2 84.8l2.9 2.8M118.2 97.3l1.1 .2M119.7 89.3l-1.4 2.2M120.4 86.9l.1 .1M120.4 90.1l1 .5"/>
<path d="M122.5 90.9l.6 .4M122.8 88.9l.8 .7M127.6 82.4l-3.2 2.1M127.8 83.5l.8 .8M127.9 98l-.6 2.4-.3 2.3M128.2 95.7l.8 .5M128.8 98.6l1 .5M129 80.6l.6 .8M130.5 83.4l.5 .8M130.9 97.3l1 .5M132.1 81.6l-.4 .1M137.6 92.2l.1 1.1"/>
<path d="M137.6 80.6l.1 1.1M137.7 91.1l-2 .4M139.9 93.3v1.2M139.9 81.7l-1 .9M139.9 92.2l1.6 .2-1.3 3.2h-2.5v6.4M140.1 90.2l-.2 .9M143.2 92.9l1.9 .7 1.2 1.2 1.2 1.9M144.5 92.3l1.3 .6 1.4 1.2 1.4 2.1M146 80.5l.3-.8 1.7 .6 2.6 1.3-.6 .8M146 80.5l-3.4 9.9a11.3 11.3 0 0 1 7.3 5.7l.8 1.4M147.5 96.7l-.8 .6M147.6 96.6l-.1 .1"/>
<path d="M147.6 82.4l-1.1 2.2M147.8 99.1l-.9 .4M148 81.4l-1.3-.5-2.2 6.5 1.9 .8 4.1 3 3.4 4.9 .8 2.6M149.1 84.3l-.5 1.1M150.7 97.5l-1 .5M154.2 85.2l.8 .7 1.5 1.7M155.7 88.1l-.9 .8M156.2 90.6l-.7 .8M158.8 88.6l-.9 .7M159.3 99.5l-.4 .2M159.3 99.5l-.8 1M159.9 99.4l-.6 .1"/>
<path d="M160.6 97.1l-1.2 .2M161.1 95.4l.4 1.4-.6 1.6a20.8 20.8 0 0 1 .2 6.2M163.1 98.2l-1.1 .7M167.1 85.6l-.9 .4M167.2 84l.8 1M167.2 87.9l-1 .6M169.2 97l1.5 1.6M170 86.4l-.9 .4M171.3 96.1l-1 .3M172.5 96l-.8 1.4 .3 3.8M173.9 97l-1.1 1.2M176.9 82.3l-.7 .8"/>
<path d="M179.6 80.3h.1l-.9 .9M181 92.9l-1 .1M181.5 90.3l-1.1 .5M182.4 88.9l.1 1.3M183.6 89.4l.4 1.3-.9 1.6M188.6 80.3l-1 .4M190.8 95.6l.3 4.8-6.8 .2M192.3 80.9l-.8 .4M192.4 92l-1 .2M193 89.7l-1.1 .2M193.5 87.3l.5 2.1M195.4 90.6l.1 .9h-1"/>
<path d="M202.2 86.2l-1 .2M202.6 83.7l-1 .4M203.1 96.7l-.8 .2M203.7 83.5l-1.3-1-4 1.2M204 95.9l1.1 .1M204.2 98.1l-1 .2M205.2 85.3l-.9 .3M205.9 93.9l.3 1.9M207.3 97.8l-.9 .1M212.3 80.4l-1 .1M214.9 92.1l-1 .1M215.6 89.8l-1 .2"/>
<path d="M215.7 85.2l1 4.4M217.5 96.5l.3 5.5M218 91.6l-1 .2M225.3 86.2l-.9 .3M225.8 98.1h1M226 83.9l-1.1 .2M226.7 82.4l.3 1.3M227.8 95.9l-1.1 .1M228.4 85.5l-.9 .3M228.7 94l.2 1.8M229 98l1 .1M47.6 107.2l1 1"/>
<path d="M48.8 110.3l1 7.3M49 119.7l.8 .7h.3M49.7 108.6v.4l1.2 1.2M49.8 108.9h-.1M51.7 107.2l-.9 .8M53 118.3v1l-.7 .7M58.8 101.7l1 .3M59.6 114.2l1 .2M59.8 104.2l.4 6.6M60.9 116.5l1.2 5.5M61.9 104.2l-1 .3M62.7 114h1"/>
<path d="M62.9 101.7l-1 .3M63.1 116.2l-1 .6M71.2 108.2l-.9 .4M71.4 110.4h.1M71.5 110.4l.1 1.3M72.5 110l1.1 .2M74.4 107.2l-1 .9M76.5 119.7l-1.1 .3M81 102h.9M81.9 104.2l.1 1.5M82 109.8l-.6 .1M83.1 114.7l-.9 .3"/>
<path d="M83.6 116.8l.5 1.3M84.1 102l1.2 .1M84.1 104.2l-1 .1M85.7 116.3l-1 .3M86.3 114l-1.1 .2M94.5 113.8l-.9 .2M95.1 115.9l.4 1.4M95.4 104.2l-1 .1M95.4 102h1.1M97.2 115.4l-1.1 .3M97.6 113.1l-1 .2M104.8 108l-1.1 1.2 .4 2.1"/>
<path d="M105.6 105l.3 3.9-.8 1.2M106.9 107.6l1.2 1.1M107.3 109.7l-1 .3M108.5 119.3l-1 .3M109.7 110.7h.2M111.4 117.6l-1 .6M115.6 107.3l-.9 .9M116.8 100.5v2.8l.3 1.9-.7 .1 .6 2.7-.9 1.4 1.1 3.3M117.2 109.3h.1M117.8 106.8l.9 .5M118.2 108.9l-1 .4M119.7 116.9l-.8 .7"/>
<path d="M121.1 118.6l3 3-.2-.2M122.2 115l-.8 .5M122.8 117.2l-1 .7M124.1 118.8l-.8 .8M127.9 108.1l-1 .4M129 110l1.3 .7 2.2-.7M130.7 106.5l-.9 .5M130.9 108.9l-.9 .6M137.7 104.2l-7.2 1.6M137.7 115l-.1 1M137.8 111.7l-.1 1.1M138.7 100.7l1.2 1.3"/>
<path d="M139.9 104.2l-8.7 9.2-.9-.5-1.1-.9M139.9 112.8v1.1M143.5 114l-3.6 1M145.7 108.2l1 .7M147.4 101.8l-.9 .1M147.8 107l.9 .5M148.6 110l.8 .6M148.8 119.9l.4 .7M150.6 103.1l-.2 2-.7 3M153.8 116.8l1 .4M155.6 119.6l.8 .8M156.2 115.5l.4 1.3"/>
<path d="M156.5 118.6l.4 1.2M158.2 108.6l1.2 .3M159.9 106.8l1.1 .4M160.9 114.1l-.5 1M161.2 110.9l-.3 1.1-1.5 2.7-1.5 2.2M161.5 109.4l1 .7M163.1 105l10 .8-.3 2.2M165.2 119.6l1 .5M165.2 118.2l.6 .4M167.2 118.2l1 .6-.1 .2M168.2 116.7l.8 .4M169.4 109.5l.9 .2"/>
<path d="M170.6 116.2l-1.5 3.1M170.7 107.6l1.1 .2M172 101.2l-9.6 .4v1.5l-.4 4.2M172.5 110.1l.9 .3M179.5 115.1l.9 .3M181 113.3l1.2 .4M182.2 102l1.2 1.3M182.2 104.2h-.9M182.5 115.9l-.7 1.8-1 2.7 1.8 .7M183.1 113.8l1.4 .4-1.2 4-.7-.2M184.3 100.6l.1 1.4M184.3 100.6l-12.3 .6"/>
<path d="M184.4 104.2h2a47.6 47.6 0 0 1-2.9 15.6l-.9 1.3M190.9 116.1l1 .2M192.4 114.2l1 .3M193.4 118.9l-.8 2.6-2.1 5.3M193.5 102l1.1 .1M193.5 104.2h-1M194 116.8l.9 .2M194.8 112.5l-.3 2.2M195.6 100.4l.1 1.6M195.7 104.2h.9M202.2 120l1 .4M203 110l1 .2"/>
<path d="M204.2 108.1h1.1M205.2 116.5l-.9 4.1M206.2 110.4h1M206.5 106.3l-.1 1.9M213.6 116.1l1 .1M214.9 114l1.1 .1M215.7 102l1 .1M215.7 104.2h-1M216.7 116.5l1 .1M217.6 108.3l-.6 6.1M217.8 104.2h1M225.3 120l1.1 .2"/>
<path d="M225.7 110.2h1M226.8 108l1.1 .1M227.7 118.9l-.2 1.5M228.9 110.3l.9 .1M229.1 103.1l-.1 5.1M50.6 122.5l.3 1.3M51.3 129.3l1.2 3.5M51.4 121.1l.9 1h.4M52.2 132l.3 .3M52.5 132.8h.1M52.5 132.3h.8M52.5 132.3v.5"/>
<path d="M54.1 134.3l1.4 3.7M54.8 133.3l.3 .3h1M54.8 133.3v.1M56.1 130.7l-.7 .7v.2M63.3 126.5l-1 .2M64 128.5l1 2.4 1.2 3.6M66 127.9l-1.1 .2M66.1 125l-.7 .8M66.7 137.8l1.2 .2M68.9 139.9l.9 1.9 2.4 3.7M70.4 135.9l-.6 1.1M70.8 138.9l-1.2 .1"/>
<path d="M73.3 120.6l-.9 .2M73.9 122.7l.5 1.8M76 122.1l-1 .3M76.3 126.5h.1M76.3 126.5l1 2.4 1.8 3.6-.5 1.8M76.7 132.5l-.9 .2M77.7 132.3l-.9 .4M80.6 133.3l-1 .5M80.6 130.9l-1 .4M81.8 137.6l.2 .4M87.1 126.8l-.8 .5M88 128.7l1.1 2"/>
<path d="M90 127.8l-.9 .5M90.1 125.4l-1.1 .4M93.7 137.7l-.7 .6M95 139.4l.9 1.1M96.3 135.6l-.9 .7M96.7 138l-.8 .7M98.8 124.9l-.9 .6M99.9 126.8h.1M99.9 126.8l.7 1.1M101.5 123.5l-.8 .3M101.8 125.7l-1 .6M105.8 134.5l-.7 .8"/>
<path d="M107.4 136.1l1.6 1.5M108.2 132.5l-.1-.2-.7 .7M108.9 134.5l-.7 .9M109.6 132.9l-.6 .4M109.6 121.2l1.8 .5M110.7 120.6l.8-.5 4.2 4.7-1.1 .9M111.9 138.7l.4 .3M112.1 125.8l-1.9 1.5M115.9 128.7l-.6 .9M116.6 139.3l-.4 .8M117.5 130.1l2.7 1.7M118 124.5l-.8 .9"/>
<path d="M118 126.1l-.7 1M118.3 129.2l.6-.7 1.2 .8 3.6 2.1 .5 1.5M124.2 123l-.5 .6M126 135l-.3 1M126.8 131.9v1.1M127.6 123.8l-.5 1 .2 .1M128.1 135.8l-1.4 3.7 2.5 .8 2.4 .4M128.6 121.9l.5-1 2.3 1.1 1.6 .4-.3 1.3M128.8 133.7l-.3 1M129.6 124.8l1.1 .3 2.6 .1M130.5 122.8l-.4 1.1M136.5 138.4l.5 .7z"/>
<path d="M137.7 137.5l1.6 1.1M137.7 126.6l1.2 1.3M138.9 123.5l-1.2 .9M138.9 134.3l-1.2 1M139.9 137.5l-1.1-1.1h-1.9l-.4 .5v1.5M139.9 135.3l.2 1M139.9 124.4l.3 1.2M143.2 125.4h-.4M143.3 134.9l.2 1.2M146.5 125.5l-4 1.1h-2.6l-1.2-1.1-3.7-.1v15.9M146.9 121.9l.2 .9M148 124.8l.8 1"/>
<path d="M148.4 132.7l.4 1M149.1 121.9l.8 .7M149.5 135.8l.6 .9M150.9 133l.5 .9M151.8 122.9l-1.8 .9M157.8 131.8l-2.6 1.6-3.6 1.6M157.9 127.7l.8 .8M160.1 130.1l.8 .8M160.3 127.1l.8 .8M163.1 139.3l.6 .7M164.5 125.8h.2l-3 2.9M166.7 135.1h.1"/>
<path d="M166.7 139.1l-4.2 2.9M166.9 134.9l-.2 .2M168 133.9l.7 .6M168 121.2l.9 .5M168.9 121.7l.1 .1M170.3 136.1l.8 1M170.3 133l.7 .9M174.8 125.5l1.1 .2M175.3 130.9l-2 2.4-1.5 1.2M176.9 123.8l1 .7M179.9 123.2l-1.1 1.7M180.1 137.3l.8 .7"/>
<path d="M182.3 136.3l.8 .6M182.6 121.1l-2.7 5.3-1.1 1.1-1.1-.7M182.6 139.4l.6 .7M186.7 127.3l.9 .5M188.6 125.8l1 .4M188.8 130.2a63.4 63.4 0 0 1-4.8 7.5M189.6 128.7l.8 .5M196 133l1 .3M198 131.3l1 .5M199 134.3l.8 .4M200.7 121.8l.9 .3M201.4 128.9l-1.5 3.4"/>
<path d="M203.7 122.7l.9 .3M205.9 138.6l.9 .3M207.8 137l.9 .5M208.7 139.9l4.1 2.3M210.1 131.6l1.1 .4M211.5 134.2l-1.8 3.8M211.6 127.9l-.4 .3-.1 1-1-.1M212.3 125.8l1 .4M213.7 128.5l.8 .5M215.7 121.3l-1.4 5.2M220.7 133.1l.8 .5M222.2 131.6l1 .4"/>
<path d="M223.6 134.3l1 .2M223.9 121.9l1 .2M224.3 132.3l-1.5 1-.8 2.3 2.5 .9M224.7 127.4v.1M227 122.5l.9 .4M56.9 143.4l.3 .3h.9M59.1 145.6l2.9 4.9M59.8 144.6v.1M59.8 144.7h.1M60.5 141.5v.7l-.5 .5M61 144.6h-1.2M63.1 154.1l.1 .2h1.2"/>
<path d="M65.6 156.1l1.7 2.3 1.5 1.8M66 154.7l1.4 .1M66.5 151.8v.9l-.3 .3M74.2 148.7l-.9 .4M75.5 150.4l3.1 3.8M76.3 146.1l-.3 1.3M77.3 149.1l-1 .6M82.1 158.2l-1.2 .1M83.7 159.7l3.7 3.4M83.8 155.3l-.1 1.4M84.1 143l-.9 .5M85.2 158.2l-.8 .7"/>
<path d="M85.4 144.8l2.4 2.7M85.9 156.2l1.4 1.3-2.1 2.3 4.1 3.6 3.6 2.6 .3 1.7M86.7 141.1l-.9 .6M87.1 143.5l-.8 .7M92.4 152.4l-.7 .7M94 153.9l1 .9M94.6 150.1l-.8 .7M95.4 152.3l-.7 .8M99.5 143l2.4 2.1 1.7 1.2 .6 1.9M102.5 146.9l-.6 .7-.4-.3M102.8 156.5l.2 .3M103.9 157.3l-.5 1"/>
<path d="M104.5 144.3l-.6 .9M105.2 159.4l-.5 1M105.6 146.5l-.7 .9M108.9 147.5h.1M111.4 153.4l.9 1.1M113.2 153.8l-.6 .8M114.6 150.8l-.5 1.1M115.1 142l-.5 1M115.1 154.8l2.3 .9M116.1 152.8l-.5 1M117 143.1l1.2 .6M118 141.2l-.6 .9"/>
<path d="M120.6 155.8l.2 .1M125.1 158.3l-.2 .9M125.7 155l-.1 1.2M126 146.8l-.4 1M126.4 143.8h.3l-.2 .9M127.2 158.8l2.1 .3M127.7 156.7l-.4 1M128.6 145.3l-.3 1.1M134 145.6l-.5 2.8-2.4-.3-3-.7M136.3 143.2l.4 4.5 2.3-.1 .9 1M137.7 160l1.1 .9M137.7 148.6l1.4 1.3"/>
<path d="M138.9 156.7l-1.2 1.1M138.9 155.3l.1 1.4M138.9 145.5l-1.2 1M139.9 157.8l.1 1M139.9 146.5l.1 1.1M148.7 144.3l.3 1M149.6 147.4l.5 1.1M149.7 155.6l.2 1.1M150.4 158.8l.4 .9M151.1 144.7l.4 1.2M152 156.2l-.4 1.2M156.7 145.5l-5 1.3"/>
<path d="M159 140.4l.6 .8M160.7 143.1l.6 1.2M160.9 155.9l-8.4 2.4M161.1 151.8l-.1 .1 .6 .9M161.4 140.1l.5 1.1M162.5 154.8l.3 .9M163.5 151.9l.5 .9M166.4 152.8l-1.9 1M171.3 145.7l.8 .8M172 158.5l.4 .9M172.8 151a58.7 58.7 0 0 1-33 10.8l-3.1 .1v-2.9l1.7-.1 1.5 1.1M172.8 151h.1"/>
<path d="M173.4 148.2l.6 .7M173.8 145.2l.7 .8M174.3 158.3l.5 .9M177.5 144.6l-2.4 2.3M178.2 158.2l-2.8 1.9M181.5 151.5l.7 .8M183.5 141.4l-.5 .4a46.4 46.4 0 0 1-10.2 9.2M183.7 153.9l.5 .8M183.8 150.8l.9 .7M186.6 151l-1.3 1.4M189.7 142.8l.8 .7M191.8 157.4l-.2 .1 .8 .7"/>
<path d="M191.8 141.7l.9 .6M192.2 144.8l.7 .6M193.9 159.7l.7 .7M193.9 156.7l.7 .8M194.5 141.7l-1 1.3M198.8 154.6l-3.3 3.6M199.6 148.5l.8 .6M201.6 147.4l.9 .7v-.1M202.1 150.4l.7 .7M205.2 144.3l-2 2.7 .2 1.7M209.4 154.3l.8 .5M211.5 153l.8 .6"/>
<path d="M212 156.1l.7 .6M214.7 152.1l-1.5 2.2M215.6 144.3l1 .3M217.6 142.7l.9 .5M218.5 145.6l.9 .5M221.2 140.2l-1.7 3.5M72.1 163.9l-.6 .6h-.3M73.5 165.5l1.5 1.6-.2-.1M73.7 164.1l.1 .1M73.8 164.2h.1M73.8 164.2l.4 .5M74.2 164.7h.1"/>
<path d="M74.3 161.7l-.7 .8M75.1 164l-.6 .7h-.3M79.9 170.2l2.7 2.1 .1 1.5M81 172.5l-.2 .2v.9M81.8 169.3l1.9 1.3M83.3 170.3h-.5l-.5 .5M84 172.1l-.6 .7 .3 .5M91 179.7l-.6 .5v.3l.8 .5M91.5 166.4l-.6 .8M91.7 176.4l.4 .4v1M93.4 163.9l-.6 .7M93.9 179l-.6 .6h-.4"/>
<path d="M94.5 165.9l-.8 .7M98.1 170.8l-.5 .9M102 173l-.6 .8M102.2 160.1l-.3 .9M103.2 170.1l-.2 1M103.9 174l5 2.3M104.1 161.2l1.2 .7 1.4 .2 2 1.5M104.9 172.1l-1 .7M106.3 163l-.3 .5M110.1 175.6h.1M113.3 165.9l-.2 .9M113.3 177.9l-.6 .8"/>
<path d="M114 174.8v1.1M114.5 162.9l-.4 1M115.3 166.6l3.7 1.3M115.4 178.6l3 .9M116.1 176.5l-.7 1M116.1 164.6l-.4 1M116.9 166.1h.1M117.3 166.2l.8 .3M121.1 176.8l.1 .2M125 177.7l.7 1.1M125.3 169.5l-.3 .9M126 166.3l-.3 1"/>
<path d="M127.4 169.9l2.9 .4-1.3 9.8-1.5 1.2-.2 1.6M127.8 167.7l-.2 1.1M127.9 179.2l-1 .9M136.3 176.7v4.4h2.6l1 1M137.7 178.9v1.1M137.7 170.8v1M137.8 167.6l-.1 1.1M138.8 164.4v3.2M139.9 170.8l-1.6-1h-1.4l-.4 .4v1.6l.4 .6 3.9-.1 1.2 .9M139.9 168.7v1M139.9 180l.2 1M149.4 178.2l.4 1"/>
<path d="M149.6 166.7l.2 1M150.2 169.9l.1 1M151.1 166l.8 .9 .3 1.5M151.9 178.8l.2 1.1M154.1 179.5l-.2 .1M154.2 169l-1.9 .5M161.1 163.7l.4 .9M161.2 175.6l.3 .9M162.2 178.6l.4 .9M162.3 166.6l.4 1M163.5 163.9l.5 .9M163.6 175.9l.4 1 1.5-.5"/>
<path d="M166.5 165l-2.2 .9M169.3 176l-5 1.9M172.4 171.2l.3 .9M173.5 161.2l.6 .9M173.7 174l.4 .9M174.7 171.1l.7 .9M179.7 170.7l-4 2.3M182.6 165.1l.5 .8M183.2 178.1l.5 .9M184.4 167.7l.5 .8M184.9 164.6l.6 .9M185.5 177.8l.6 1"/>
<path d="M188.1 178.8l-1.4 .9M189.1 163.9l-1.8 1.7-1.2 .8M192.9 171.4l.7 .7M195 173.8l.5 .8M195.3 170.8l.6 .9M198.4 171l-1.7 1.5M201.8 163.3l.7 .7M204 162.5l.7 .7M204.1 165.5l.6 .8M206.7 162.7l-1.1 1.2M92.8 180.8l3.3 1.8M93.5 182.3l.2 .1"/>
<path d="M101.8 185.5v.4l-.5 .5M102.3 182.3l.8 .3M103.1 182.6l-.4 .5v.4M103.1 182.6l.6 .3M103.8 186.4l1.5 .6M104.7 184.4l-.7 .7v.2M107.4 186.6h.3M109.7 187.5l.4 .1M113.4 189.8l-.8 .7h-.1M114.1 186.7v.8l-.1 .2M115.5 190.4l5.6 1.2M116.1 188.3l-.9 .9"/>
<path d="M118.7 187.9l.9 .2M125.4 181l-.4 .9M125.4 192.4v.4l-.5 .5 2.3 .8M125.5 189.3v.8l.2 .2M127.6 192.7l2.1 .3M127.9 190.6v.6l-.5 .4M134.1 192.8l.5-.5h4l1.3 1.1M137.7 193.4l1.1 1M137.7 182.1l.1 1M139.9 191.2l.2 1.1M144.1 182.7h.1M144.1 182.7v.2l-1.2 .1"/>
<path d="M145.7 192.1l-1.7 .6h-1.4l-1.5-.4M147.7 189.8l-1.9 .2a2.96 2.96 0 0 0-3.5-.3l-.7 .3-2.8 .2-1.1 1M149.7 189.5v1.1M150 192.7l.1 1-1.7 .2M150.1 181.3l.2 1M151.9 190.3l.1 1M154.9 191.9l-2.7 .5M156.8 180.1l-4.5 .9M161.4 187.3l.1 1M162.1 190.4l.3 .9M163.6 187.7l.4 1M166.4 189.1l-2.2 .7"/>
<path d="M170.9 187.8l.2 .7M172.7 183.4l.2 1M173.8 186.4l.4 .9M174.9 183.5l.5 1M178.8 184.1l-3 1.4M184.8 180.8l.5 .9"/>
</g>
<g fill="none" stroke="#800000" stroke-width=".42">
<path d="M87.5 19.7l-.1 .1M88.3 19.3h-.1M89.1 18.8h-.1M89.9 18.3l-.1 .1M90.7 17.8l-.1 .1M91.5 17.4h-.1M92.4 17h-.2M93.2 16.5l-.1 .1M94 16.1h-.1M94.8 15.7h-.1M95.7 15.2l-.1 .1M96.5 14.8l-.1 .1"/>
<path d="M97.3 14.4l-.1 .1M98.2 14.1h-.1M99 13.7h-.1M99.9 13.3h-.1M100.7 12.9l-.1 .1M101.6 12.6h-.1M102.5 12.2l-.1 .1M103.3 11.9h-.1M104.2 11.5l-.1 .1M105.1 11.2l-.1 .1M105.9 10.9h.1M106.8 10.6h-.1"/>
<path d="M107.7 10.3h-.1M108.6 10h-.1M109.5 9.7l-.1 .1M110.4 9.4l-.1 .1M111.3 9.2h-.2M112.1 8.9v.1M113.1 8.7h-.2M113.9 8.4h.1M114.9 8.2h-.2M115.8 8h-.1M116.6 7.7v.1M117.6 7.6h-.1"/>
<path d="M118.5 7.3l-.1 .1M119.4 7.2h-.1M120.3 7h-.1M121.2 6.8h-.1M122.1 6.6l-.1 .1M123 6.5h.1M124 6.3l-.1 .1M124.9 6.2h-.1M125.8 6.1h-.1M126.6 6h.1M127.6 5.9h.1M128.5 5.8h.1"/>
<path d="M129.5 5.7h-.1M130.5 5.6h-.2M131.3 5.5h.1M132.2 5.4h.1M133.1 5.4h.1M134 5.3h.2M135 5.3h.1M135.9 5.2h.1M136.8 5.2h.1M137.8 5.2h.1M138.7 5.2h.2M139.7 5.2h.1"/>
<path d="M140.7 5.2h.1M141.6 5.2h.1M142.5 5.3h.1M143.5 5.3h.1M144.4 5.4h.1M145.3 5.4h.1M146.3 5.5h.1M147.2 5.6h.1M148.1 5.7h.1M149 5.8h.1M150 5.9h.1M150.9 6h.1"/>
<path d="M151.8 6.1h.1M152.7 6.2h.1M153.6 6.3l.2 .1M154.6 6.5h.1M155.5 6.6l.1 .1M156.4 6.8h.1M157.3 7h.1M158.2 7.2h.1M159.2 7.3v.1M160.1 7.6h.1M161 7.7l.1 .1M161.9 8h.1"/>
<path d="M162.8 8.2h.1M163.7 8.4h.1M164.6 8.7h.1M165.5 8.9l.1 .1M166.4 9.2h.1M167.3 9.4l.1 .1M168.1 9.7l.2 .1M169 10h.1M169.9 10.3h.1M170.8 10.6h.1M171.7 10.9h.1M172.6 11.2l.1 .1"/>
<path d="M173.4 11.5l.1 .1M174.3 11.9h.1M175.2 12.2l.1 .1M176 12.6h.1M176.9 12.9l.1 .1M177.7 13.3h.1M178.6 13.7h.1M179.5 14.1h.1M180.3 14.4l.1 .1M181.1 14.8l.1 .1M182 15.2l.1 .1M182.8 15.7h.1"/>
<path d="M183.6 16.1h.1M184.4 16.5l.2 .1M185.3 17h.1M186.1 17.4h.1M186.9 17.8l.1 .1M187.7 18.3l.1 .1M188.5 18.8h.1M189.3 19.3h.1M190.1 19.7l.1 .1M64.3 39.7h-.1M64.9 38.9l-.1 .1M65.5 38.2l-.1 .1"/>
<path d="M66.1 37.5l-.1 .1M66.7 36.9h.1M67.4 36.2l-.1 .1M68 35.5l-.1 .1M68.7 34.8l-.1 .1M69.3 34.2h-.1M70 33.5l-.1 .1M70.6 32.9h.1M71.3 32.2l-.1 .1M72 31.6h-.1M72.7 30.9l-.1 .1M73.4 30.3l-.1 .1"/>
<path d="M74.1 29.7l-.1 .1M74.8 29.1l-.1 .1M75.5 28.5l-.1 .1M76.2 27.9l-.1 .1M76.9 27.3h-.1M77.6 26.7l-.1 .1M78.3 26.1v.1M79.1 25.5l-.1 .1M79.8 25l-.1 .1M80.6 24.4l-.1 .1M81.3 23.9h-.1M82.1 23.3l-.1 .1"/>
<path d="M82.8 22.8l-.1 .1M83.6 22.3h-.1M84.4 21.8h-.1M85.2 21.2l-.1 .1M85.9 20.7v.1M86.7 20.2l-.1 .1M143.3 35.8l.3-.3v.6l-.2-.1M190.9 20.2l.1 .1M191.7 20.7l.1 .1M192.5 21.2l.1 .1M193.3 21.8h.1M194 22.3h.1"/>
<path d="M194.8 22.8l.1 .1M195.5 23.3l.1 .1M196.3 23.9h.1M197.1 24.4v.1M197.8 25l.1 .1M198.5 25.5l.1 .1M199.3 26.1v.1M200 26.7l.1 .1M200.7 27.3h.1M201.4 27.9l.1 .1M202.2 28.5v.1M202.7 39.3l1.4 1.3"/>
<path d="M202.9 29.1v.1M203.6 29.7v.1M204.3 30.3v.1M205 30.9v.1M205.6 31.6h.1M206.3 32.2l.1 .1M207 32.9h.1M207.6 33.5l.1 .1M208.3 34.2h.1M209 34.8v.1M209.6 35.5l.1 .1M210.2 36.2l.1 .1"/>
<path d="M210.9 36.9h.1M211.5 37.5l.1 .1M212.1 38.2l.1 .1M212.7 38.9l.1 .1M213.3 39.7h.1M51 59.8v.1M51.4 59v.1M51.9 58.2l-.1 .1M52.3 57.3l-.1 .1M52.7 56.5v.1M53.2 55.7l-.1 .1M53.6 54.9v.1"/>
<path d="M54.1 54.1l-.1 .1M54.6 53.3l-.1 .1M55 52.5v.1M55.5 51.7v.1M56 50.9v.1M56.5 50.1v.1M57 49.3v.1M57.5 48.6h.1M58.1 47.8l-.1 .1M58.6 47l-.1 .1M59.1 46.3v.1M59.7 45.5l-.1 .1"/>
<path d="M60.2 44.8h.1M60.8 44l-.1 .1M61.3 43.3h.1M61.9 42.5l-.1 .1M62.5 41.8l-.1 .1M63.1 41.1l-.1 .1M63.7 40.4h-.1M126 59.4h.1M126 59.4l-.8 .8M199.1 51.9l3 3.9M214 40.4h.1M214.5 41.1l.1 .1"/>
<path d="M215.1 41.8l.1 .1M215.7 42.5l.1 .1M216.3 43.3h.1M216.8 44l.1 .1M217.4 44.8h.1M218 45.5v.1M218.5 46.3v.1M219 47l.1 .1M219.6 47.8v.1M220.1 48.6h.1M220.6 49.3l.1 .1M221.1 50.1l.1 .1"/>
<path d="M221.6 50.9l.1 .1M222.1 51.7l.1 .1M222.6 52.5v.1M223.1 53.3v.1M223.5 54.1l.1 .1M224 54.9v.1M224.5 55.7v.1M224.9 56.5v.1M225.3 57.3l.1 .1M225.8 58.2v.1M226.2 59v.1M226.6 59.8l.1 .1"/>
<path d="M43.7 79.9v.1M43.9 79v.1M44.2 78.1v.1M44.4 77.2v.1M44.7 76.3l-.1 .1M44.9 75.4v.1M45.2 74.5v.1M45.5 73.6l-.1 .1M45.8 72.8l-.1 .1M46.1 71.9l-.1 .1M46.4 71l-.1 .1M46.7 70.1l-.1 .1"/>
<path d="M47 69.2l-.1 .1M47.3 68.4v.1M47.6 67.5v.1M48 66.6l-.1 .1M48.3 65.8v.1M48.7 64.9v.1M49.1 64.1l-.1 .1M49.4 63.2v.1M49.8 62.4v.1M50.2 61.5v.1M50.6 60.7v.1M125.2 60.2l-1.1 1.2"/>
<path d="M125.2 60.2h.1M132.6 74.1h14.5l.2 .2v1l.7 .7h1.1l1.2 1.3v1.1l9.4 9.4h1l6.4 6.3M136.9 62v.2M163.8 66.1l.1 .1M164.4 62.1l-.9 1.4M199.6 75.4l.2 .4M200 73.8l1.2 2.3M227 60.7l.1 .1M227.4 61.5l.1 .1M227.8 62.4v.1M228.2 63.2v.1M228.6 64.1v.1"/>
<path d="M228.9 64.9l.1 .1M229.3 65.8v.1M229.6 66.6l.1 .1M230 67.5v.1M230.3 68.4l.1 .1M230.7 69.2v.1M231 70.1v.1M231.3 71v.1M231.6 71.9v.1M231.9 72.8v.1M232.2 73.6v.1M232.4 74.5l.1 .1"/>
<path d="M232.7 75.4v.1M233 76.3v.1M233.2 77.2v.1M233.4 78.1l.1 .1M233.7 79v.1M233.9 79.9v.1M41 99.3v.1M41.1 98.3v.1M41.1 97.4v.1M41.2 96.5v.1M41.2 95.5v.1M41.3 94.6v.1"/>
<path d="M41.4 93.7v.1M41.5 92.8v.1M41.6 91.8v.1M41.7 90.9v.1M41.8 90v.1M42 89.1l-.1 .1M42.1 88.1v.1M42.2 87.2v.1M42.4 86.3v.1M42.6 85.4l-.1 .1M42.7 84.5v.1M42.9 83.6v.1"/>
<path d="M43.1 82.7h.1M43.3 81.7v.1M43.5 80.8v.1M234.1 80.8v.1M234.3 81.7v.1M234.5 82.7h.1M234.7 83.6v.1M234.9 84.5v.1M235.1 85.4v.1M235.2 86.3v.1M235.4 87.2v.1M235.5 88.1v.1"/>
<path d="M235.7 89.1v.1M235.8 90v.1M235.9 90.9v.1M236 91.8l.1 .1M236.1 92.8v.1M236.2 93.7v.1M236.3 94.6v.1M236.4 95.5v.1M236.5 96.5v.1M236.5 97.4v.1M236.6 98.3v.1M236.6 99.3v.1"/>
<path d="M40.9 103v.2M41 101.1v.1M41 102v.2M41 104v.1M41 104.9v.2M41 100.2v.1M41 105.9v.1M41 106.8v.1M41.1 107.7v.1M41.1 108.7v.1M41.2 109.6v.1M41.2 110.5v.1"/>
<path d="M41.3 111.4v.1M41.4 112.4v.1M41.5 113.3v.1M41.6 114.2v.1M41.7 115.1v.2M41.8 116.1v.1M41.9 117l.1 .1M42.1 117.9v.1M42.2 118.9h.1M42.4 119.8v.1M118.7 110.7h-1.1M120.1 111.5l-.7 .2"/>
<path d="M235.2 119.8v.1M235.4 118.9h.1M235.5 117.9v.1M235.7 117v.1M235.8 116.1v.1M235.9 115.1v.2M236.1 114.2l-.1 .1M236.1 113.3v.1M236.2 112.4v.1M236.3 111.4v.1M236.4 110.5v.1M236.5 109.6v.1"/>
<path d="M236.5 108.7v.1M236.6 107.7v.1M236.6 106.8v.1M236.6 100.2v.1M236.6 105.9v.1M236.7 101.1v.1M236.7 102v.2M236.7 104v.1M236.7 104.9v.2M236.7 103v.2M42.5 120.7l.1 .1M42.7 121.6v.1"/>
<path d="M42.9 122.5v.1M43.1 123.4v.1M43.3 124.3v.1M43.5 125.2v.1M43.7 126.1v.1M43.9 127v.1M44.2 128h.1M44.4 128.8v.1M44.6 129.7l.1 .1M44.9 130.6v.1M45.2 131.5v.1M45.4 132.4l.1 .1"/>
<path d="M45.7 133.3l.1 .1M46 134.2l.1 .1M46.3 135.1l.1 .1M46.6 136h.1M46.9 136.8l.1 .1M47.3 137.7v.1M47.6 138.6v.1M47.9 139.4l.1 .1M92.8 125.5v.2M221.5 133.6l-.9 2.6M229.7 139.4l-.1 .1M230 138.6v.1"/>
<path d="M230.4 137.7l-.1 .1M230.7 136.8v.1M231 136h.1M231.3 135.1v.1M231.6 134.2v.1M231.9 133.3v.1M232.2 132.4v.1M232.5 131.5l-.1 .1M232.7 130.6v.1M233 129.7v.1M233.2 128.8v.1M233.5 128h-.1"/>
<path d="M233.7 127v.1M233.9 126.1v.1M234.1 125.2v.1M234.3 124.3v.1M234.5 123.4v.1M234.7 122.5v.1M234.9 121.6v.1M235.1 120.7v.1M48.3 140.3v.1M48.7 141.2h.1M49 142l.1 .1M49.4 142.9v.1"/>
<path d="M49.8 143.7v.1M50.2 144.5v.2M50.6 145.4v.1M51 146.2v.1M51.4 147.1v.1M51.8 147.9l.1 .1M52.2 148.7l.1 .1M52.7 149.5v.1M53.1 150.4l.1 .1M53.6 151.2v.1M54 152l.1 .1M54.5 152.8l.1 .1"/>
<path d="M55 153.6v.1M55.5 154.4v.1M56 155.2v.1M56.5 156h.1M57 156.7v.1M57.5 157.5v.1M58 158.3l.1 .1M58.5 159l.1 .1M59.1 159.8v.1M141.8 145.3l-2.9 .2M218.5 159.8v.1M219.1 159l-.1 .1"/>
<path d="M219.6 158.3v.1M220.1 157.5v.1M220.7 156.7l-.1 .1M221.2 156h-.1M221.7 155.2l-.1 .1M222.2 154.4l-.1 .1M222.6 153.6v.1M223.1 152.8v.1M223.6 152l-.1 .1M224 151.2v.1M224.5 150.4v.1M224.9 149.5v.1"/>
<path d="M225.4 148.7l-.1 .1M225.8 147.9v.1M226.2 147.1v.1M226.7 146.2l-.1 .1M227.1 145.4l-.1 .1M227.5 144.5l-.1 .2M227.8 143.7v.1M228.2 142.9v.1M228.6 142v.1M229 141.2h-.1M229.3 140.3v.1M59.6 160.6l.1 .1"/>
<path d="M60.2 161.3v.1M60.7 162.1l.1 .1M61.3 162.8v.1M61.8 163.5l.1 .1M62.4 164.3l.1 .1M63 165l.1 .1M63.6 165.7l.1 .1M64.2 166.4l.1 .1M64.8 167.1l.1 .1M65.4 167.8l.1 .1M66 168.5l.1 .1M66.7 169.2v.1"/>
<path d="M67.3 169.9l.1 .1M67.9 170.6h.1M68.6 171.3h.1M69.2 171.9l.1 .1M69.9 172.6l.1 .1M70.6 173.2v.1M71.2 173.9h.1M71.9 174.5l.1 .1M72.6 175.2h.1M73.3 175.8h.1M74 176.4l.1 .1M74.7 177l.1 .1"/>
<path d="M75.4 177.6l.1 .1M76.1 178.2l.1 .1M76.8 178.8l.1 .1M77.5 179.4l.1 .1M78.3 180h.1M116.9 166.1h.2M117.1 166.1l.3 .1M117.1 166.1l.2 .1M199.3 180h.1M200.1 179.4l-.1 .1M200.8 178.8l-.1 .1M201.5 178.2l-.1 .1"/>
<path d="M202.2 177.6v.1M202.9 177v.1M203.6 176.4v.1M204.3 175.8h.1M205 175.2h.1M205.7 174.5l-.1 .1M206.4 173.9h-.1M207.1 173.2l-.1 .1M207.7 172.6l-.1 .1M208.4 171.9l-.1 .1M209 171.3h.1M209.7 170.6h-.1"/>
<path d="M210.3 169.9l-.1 .1M210.9 169.2v.1M211.6 168.5l-.1 .1M212.2 167.8l-.1 .1M212.8 167.1l-.1 .1M213.4 166.4l-.1 .1M214 165.7v.1M214.6 165l-.1 .1M215.2 164.3l-.1 .1M215.8 163.5l-.1 .1M216.3 162.8v.1M216.9 162.1l-.1 .1"/>
<path d="M217.5 161.3l-.1 .1M218 160.6v.1M79 180.6h.1M79.7 181.1l.1 .1M80.5 181.7h.1M81.2 182.2l.1 .1M82 182.8h.1M82.7 183.3l.1 .1M83.5 183.8l.1 .1M84.3 184.4h.1M85.1 184.9h.1M85.9 185.4h.1"/>
<path d="M86.6 185.9h.1M87.4 186.4h.1M88.2 186.9h.1M89 187.3l.1 .1M89.8 187.8l.1 .1M90.6 188.3h.1M91.4 188.7l.1 .1M92.2 189.2h.2M93.1 189.6l.1 .1M93.9 190l.1 .1M94.7 190.5h.1M95.6 190.9h.1"/>
<path d="M96.4 191.3h.1M97.2 191.7h.1M98.1 192.1h.1M98.9 192.4l.1 .1M99.8 192.8l.1 .1M100.6 193.2h.1M101.5 193.5l.1 .1M102.4 193.9l.1 .1M103.2 194.2l.1 .1M104.1 194.6h.1M105 194.9h.1M105.9 195.2v.1"/>
<path d="M106.7 195.5l.1 .1M107.4 186.6l.1 .2M107.5 186.8h.2M107.6 195.8l.1 .1M108.5 196.1l.1 .1M109.4 196.4h.1M110.3 196.7h.1M111.1 197h.2M112.1 197.2v.1M112.9 197.5h.2M113.9 197.7h.1M114.7 198h.2"/>
<path d="M115.7 198.2h.1M116.6 198.4h.1M117.5 198.6h.1M118.4 198.8h.1M119.3 199h.1M120.2 199.2h.1M121.1 199.3h.1M122 199.5h.1M123 199.6v.1M123.9 199.8h.1M124.8 199.9l.1 .1M152.8 199.9l-.1 .1"/>
<path d="M153.8 199.8h-.2M154.7 199.6l-.1 .1M155.6 199.5h-.1M156.5 199.3h-.1M157.4 199.2h-.1M158.3 199h-.1M159.2 198.8h.1M160.1 198.6h.1M161.1 198.4h-.1M162 198.2h-.1M162.9 198h-.1M163.8 197.7h-.1"/>
<path d="M164.7 197.5h-.1M165.6 197.2l-.1 .1M166.5 197h-.1M167.4 196.7h-.1M168.3 196.4h-.2M169.1 196.1l-.1 .1M170 195.8l-.1 .1M170.9 195.5l-.1 .1M171.8 195.2l-.1 .1M172.7 194.9h-.1M173.5 194.6h-.1M174.4 194.2l-.1 .1"/>
<path d="M175.3 193.9l-.1 .1M176.1 193.5l-.1 .1M177 193.2h-.1M177.8 192.8l-.1 .1M178.7 192.4l-.1 .1M179.5 192.1h.1M180.4 191.7h-.1M181.2 191.3h-.1M182.1 190.9h-.1M182.9 190.5h-.1M183.7 190l-.1 .1M184.6 189.6l-.2 .1"/>
<path d="M185.4 189.2h-.1M186.2 188.7l-.1 .1M187 188.3h-.1M187.8 187.8l-.1 .1M188.6 187.3l-.1 .1M189.4 186.9h-.1M190.2 186.4h-.1M191 185.9h-.1M191.8 185.4h-.1M192.6 184.9h-.1M193.3 184.4h.1M194.1 183.8l-.1 .1"/>
<path d="M194.9 183.3l-.1 .1M195.6 182.8h-.1M196.4 182.2l-.1 .1M197.1 181.7h.1M197.9 181.1l-.1 .1M198.6 180.6h-.1M125.7 200.1h.1M126.6 200.2h.1M127.6 200.3h.1M128.5 200.4h.1M129.4 200.5h.1M130.3 200.6h.2"/>
<path d="M131.3 200.7h.1M132.2 200.7h.1M133.1 200.8h.1M134 200.8h.2M135 200.9h.1M135.9 200.9h.1M136.8 200.9h.1M137.8 200.9h.1M138.7 201h.2M139.7 200.9h.1M140.7 200.9h.1M141.6 200.9h.1"/>
<path d="M142.5 200.9h.1M143.5 200.8h.1M144.4 200.8h.1M145.3 200.7h.1M146.3 200.7h.1M147.3 200.6h-.1M148.2 200.5h-.1M149 200.4h.1M150 200.3h.1M150.9 200.2h.1M151.9 200.1h-.1"/>
</g>
<path d="M158.8 18.2h.1M159.8 94.4h.1" fill="none" stroke="#800000" stroke-width=".57"/>
<path d="M133.2 75.5h.1" fill="none" stroke="#800000" stroke-width=".85"/>
<circle cx="134.1" cy="13.1" r=".49" fill="#008000" stroke="#008000" stroke-width=".2"/>
<circle cx="134.1" cy="13.1" r=".28" fill="#fff" stroke="#000" stroke-width=".2"/>
<circle cx="114.4" cy="100.2" r=".49" fill="#008000" stroke="#008000" stroke-width=".2"/>
<circle cx="114.4" cy="100.2" r=".28" fill="#fff" stroke="#000" stroke-width=".2"/>
<circle cx="116.8" cy="100.5" r=".49" fill="#008000" stroke="#008000" stroke-width=".2"/>
<circle cx="116.8" cy="100.5" r=".28" fill="#fff" stroke="#000" stroke-width=".2"/>
<circle cx="141.5" cy="11.1" r=".49" fill="#008000" stroke="#008000" stroke-width=".2"/>
<circle cx="141.5" cy="11.1" r=".28" fill="#fff" stroke="#000" stroke-width=".2"/>
<circle cx="52.9" cy="70.3" r=".49" fill="#008000" stroke="#008000" stroke-width=".2"/>
<circle cx="52.9" cy="70.3" r=".28" fill="#fff" stroke="#000" stroke-width=".2"/>
<circle cx="71.3" cy="62.4" r=".49" fill="#008000" stroke="#008000" stroke-width=".2"/>
<circle cx="71.3" cy="62.4" r=".28" fill="#fff" stroke="#000" stroke-width=".2"/>
<circle cx="58.9" cy="57.1" r=".49" fill="#008000" stroke="#008000" stroke-width=".2"/>
<circle cx="58.9" cy="57.1" r=".28" fill="#fff" stroke="#000" stroke-width=".2"/>
<circle cx="87.4" cy="163.1" r=".49" fill="#008000" stroke="#008000" stroke-width=".2"/>
<circle cx="87.4" cy="163.1" r=".28" fill="#fff" stroke="#000" stroke-width=".2"/>
<circle cx="79.9" cy="170.2" r=".49" fill="#008000" stroke="#008000" stroke-width=".2"/>
<circle cx="79.9" cy="170.2" r=".28" fill="#fff" stroke="#000" stroke-width=".2"/>
<circle cx="78.1" cy="172.2" r=".49" fill="#008000" stroke="#008000" stroke-width=".2"/>
<circle cx="78.1" cy="172.2" r=".28" fill="#fff" stroke="#000" stroke-width=".2"/>
<circle cx="121.5" cy="38.6" r=".49" fill="#008000" stroke="#008000" stroke-width=".2"/>
<circle cx="121.5" cy="38.6" r=".28" fill="#fff" stroke="#000" stroke-width=".2"/>
<circle cx="122.6" cy="48.4" r=".49" fill="#008000" stroke="#008000" stroke-width=".2"/>
<circle cx="122.6" cy="48.4" r=".28" fill="#fff" stroke="#000" stroke-width=".2"/>
<circle cx="114.8" cy="13.7" r=".49" fill="#008000" stroke="#008000" stroke-width=".2"/>
<circle cx="114.8" cy="13.7" r=".28" fill="#fff" stroke="#000" stroke-width=".2"/>
<circle cx="76.3" cy="126.5" r=".49" fill="#008000" stroke="#008000" stroke-width=".2"/>
<circle cx="76.3" cy="126.5" r=".28" fill="#fff" stroke="#000" stroke-width=".2"/>
<circle cx="95.5" cy="117.3" r=".49" fill="#008000" stroke="#008000" stroke-width=".2"/>
<circle cx="95.5" cy="117.3" r=".28" fill="#fff" stroke="#000" stroke-width=".2"/>
<circle cx="95.9" cy="140.5" r=".49" fill="#008000" stroke="#008000" stroke-width=".2"/>
<circle cx="95.9" cy="140.5" r=".28" fill="#fff" stroke="#000" stroke-width=".2"/>
<circle cx="89.5" cy="121.4" r=".49" fill="#008000" stroke="#008000" stroke-width=".2"/>
<circle cx="89.5" cy="121.4" r=".28" fill="#fff" stroke="#000" stroke-width=".2"/>
<circle cx="52.2" cy="135.8" r=".49" fill="#008000" stroke="#008000" stroke-width=".2"/>
<circle cx="52.2" cy="135.8" r=".28" fill="#fff" stroke="#000" stroke-width=".2"/>
<circle cx="90.9" cy="124.7" r=".49" fill="#008000" stroke="#008000" stroke-width=".2"/>
<circle cx="90.9" cy="124.7" r=".28" fill="#fff" stroke="#000" stroke-width=".2"/>
<circle cx="117.2" cy="112.7" r=".49" fill="#008000" stroke="#008000" stroke-width=".2"/>
<circle cx="117.2" cy="112.7" r=".28" fill="#fff" stroke="#000" stroke-width=".2"/>
<circle cx="122.7" cy="14.2" r=".49" fill="#008000" stroke="#008000" stroke-width=".2"/>
<circle cx="122.7" cy="14.2" r=".28" fill="#fff" stroke="#000" stroke-width=".2"/>
<circle cx="123.7" cy="10.5" r=".49" fill="#008000" stroke="#008000" stroke-width=".2"/>
<circle cx="123.7" cy="10.5" r=".28" fill="#fff" stroke="#000" stroke-width=".2"/>
<circle cx="49.7" cy="88.5" r=".49" fill="#008000" stroke="#008000" stroke-width=".2"/>
<circle cx="49.7" cy="88.5" r=".28" fill="#fff" stroke="#000" stroke-width=".2"/>
<circle cx="96.1" cy="182.6" r=".49" fill="#008000" stroke="#008000" stroke-width=".2"/>
<circle cx="96.1" cy="182.6" r=".28" fill="#fff" stroke="#000" stroke-width=".2"/>
<circle cx="94.3" cy="185.8" r=".49" fill="#008000" stroke="#008000" stroke-width=".2"/>
<circle cx="94.3" cy="185.8" r=".28" fill="#fff" stroke="#000" stroke-width=".2"/>
<circle cx="78.8" cy="51.8" r=".49" fill="#008000" stroke="#008000" stroke-width=".2"/>
<circle cx="78.8" cy="51.8" r=".28" fill="#fff" stroke="#000" stroke-width=".2"/>
<circle cx="68.1" cy="41" r=".49" fill="#008000" stroke="#008000" stroke-width=".2"/>
<circle cx="68.1" cy="41" r=".28" fill="#fff" stroke="#000" stroke-width=".2"/>
<circle cx="78.6" cy="154.2" r=".49" fill="#008000" stroke="#008000" stroke-width=".2"/>
<circle cx="78.6" cy="154.2" r=".28" fill="#fff" stroke="#000" stroke-width=".2"/>
<circle cx="68.1" cy="165.1" r=".49" fill="#008000" stroke="#008000" stroke-width=".2"/>
<circle cx="68.1" cy="165.1" r=".28" fill="#fff" stroke="#000" stroke-width=".2"/>
<circle cx="87.8" cy="147.5" r=".49" fill="#008000" stroke="#008000" stroke-width=".2"/>
<circle cx="87.8" cy="147.5" r=".28" fill="#fff" stroke="#000" stroke-width=".2"/>
<circle cx="86.6" cy="57.1" r=".49" fill="#008000" stroke="#008000" stroke-width=".2"/>
<circle cx="86.6" cy="57.1" r=".28" fill="#fff" stroke="#000" stroke-width=".2"/>
<circle cx="100.4" cy="47.4" r=".49" fill="#008000" stroke="#008000" stroke-width=".2"/>
<circle cx="100.4" cy="47.4" r=".28" fill="#fff" stroke="#000" stroke-width=".2"/>
<circle cx="99.2" cy="45.9" r=".49" fill="#008000" stroke="#008000" stroke-width=".2"/>
<circle cx="99.2" cy="45.9" r=".28" fill="#fff" stroke="#000" stroke-width=".2"/>
<circle cx="45.8" cy="87.9" r=".49" fill="#008000" stroke="#008000" stroke-width=".2"/>
<circle cx="45.8" cy="87.9" r=".28" fill="#fff" stroke="#000" stroke-width=".2"/>
<circle cx="141.2" cy="47.3" r=".49" fill="#008000" stroke="#008000" stroke-width=".2"/>
<circle cx="141.2" cy="47.3" r=".28" fill="#fff" stroke="#000" stroke-width=".2"/>
<circle cx="140.3" cy="9.2" r=".49" fill="#008000" stroke="#008000" stroke-width=".2"/>
<circle cx="140.3" cy="9.2" r=".28" fill="#fff" stroke="#000" stroke-width=".2"/>
<circle cx="100.6" cy="127.9" r=".49" fill="#008000" stroke="#008000" stroke-width=".2"/>
<circle cx="100.6" cy="127.9" r=".28" fill="#fff" stroke="#000" stroke-width=".2"/>
<circle cx="89.1" cy="130.7" r=".49" fill="#008000" stroke="#008000" stroke-width=".2"/>
<circle cx="89.1" cy="130.7" r=".28" fill="#fff" stroke="#000" stroke-width=".2"/>
<circle cx="57.7" cy="150.4" r=".49" fill="#008000" stroke="#008000" stroke-width=".2"/>
<circle cx="57.7" cy="150.4" r=".28" fill="#fff" stroke="#000" stroke-width=".2"/>
<circle cx="123.9" cy="121.4" r=".49" fill="#008000" stroke="#008000" stroke-width=".2"/>
<circle cx="123.9" cy="121.4" r=".28" fill="#fff" stroke="#000" stroke-width=".2"/>
<circle cx="80.6" cy="176.6" r=".49" fill="#008000" stroke="#008000" stroke-width=".2"/>
<circle cx="80.6" cy="176.6" r=".28" fill="#fff" stroke="#000" stroke-width=".2"/>
<circle cx="107.7" cy="88.4" r=".49" fill="#008000" stroke="#008000" stroke-width=".2"/>
<circle cx="107.7" cy="88.4" r=".28" fill="#fff" stroke="#000" stroke-width=".2"/>
<circle cx="122" cy="95" r=".49" fill="#008000" stroke="#008000" stroke-width=".2"/>
<circle cx="122" cy="95" r=".28" fill="#fff" stroke="#000" stroke-width=".2"/>
<circle cx="123.8" cy="112.9" r=".49" fill="#008000" stroke="#008000" stroke-width=".2"/>
<circle cx="123.8" cy="112.9" r=".28" fill="#fff" stroke="#000" stroke-width=".2"/>
<circle cx="109.8" cy="17.6" r=".49" fill="#008000" stroke="#008000" stroke-width=".2"/>
<circle cx="109.8" cy="17.6" r=".28" fill="#fff" stroke="#000" stroke-width=".2"/>
<circle cx="107.9" cy="12.1" r=".49" fill="#008000" stroke="#008000" stroke-width=".2"/>
<circle cx="107.9" cy="12.1" r=".28" fill="#fff" stroke="#000" stroke-width=".2"/>
<circle cx="48.5" cy="105.8" r=".49" fill="#008000" stroke="#008000" stroke-width=".2"/>
<circle cx="48.5" cy="105.8" r=".28" fill="#fff" stroke="#000" stroke-width=".2"/>
<circle cx="105.3" cy="187" r=".49" fill="#008000" stroke="#008000" stroke-width=".2"/>
<circle cx="105.3" cy="187" r=".28" fill="#fff" stroke="#000" stroke-width=".2"/>
<circle cx="103.3" cy="192.3" r=".49" fill="#008000" stroke="#008000" stroke-width=".2"/>
<circle cx="103.3" cy="192.3" r=".28" fill="#fff" stroke="#000" stroke-width=".2"/>
<circle cx="86.1" cy="44.2" r=".49" fill="#008000" stroke="#008000" stroke-width=".2"/>
<circle cx="86.1" cy="44.2" r=".28" fill="#fff" stroke="#000" stroke-width=".2"/>
<circle cx="91.2" cy="54.8" r=".49" fill="#008000" stroke="#008000" stroke-width=".2"/>
<circle cx="91.2" cy="54.8" r=".28" fill="#fff" stroke="#000" stroke-width=".2"/>
<circle cx="114.8" cy="78.6" r=".49" fill="#008000" stroke="#008000" stroke-width=".2"/>
<circle cx="114.8" cy="78.6" r=".28" fill="#fff" stroke="#000" stroke-width=".2"/>
<circle cx="72.9" cy="33.1" r=".49" fill="#008000" stroke="#008000" stroke-width=".2"/>
<circle cx="72.9" cy="33.1" r=".28" fill="#fff" stroke="#000" stroke-width=".2"/>
<circle cx="72.2" cy="145.5" r=".49" fill="#008000" stroke="#008000" stroke-width=".2"/>
<circle cx="72.2" cy="145.5" r=".28" fill="#fff" stroke="#000" stroke-width=".2"/>
<circle cx="58.9" cy="156.4" r=".49" fill="#008000" stroke="#008000" stroke-width=".2"/>
<circle cx="58.9" cy="156.4" r=".28" fill="#fff" stroke="#000" stroke-width=".2"/>
<circle cx="42.2" cy="106" r=".49" fill="#008000" stroke="#008000" stroke-width=".2"/>
<circle cx="42.2" cy="106" r=".28" fill="#fff" stroke="#000" stroke-width=".2"/>
<circle cx="95" cy="154.8" r=".49" fill="#008000" stroke="#008000" stroke-width=".2"/>
<circle cx="95" cy="154.8" r=".28" fill="#fff" stroke="#000" stroke-width=".2"/>
<circle cx="109" cy="137.6" r=".49" fill="#008000" stroke="#008000" stroke-width=".2"/>
<circle cx="109" cy="137.6" r=".28" fill="#fff" stroke="#000" stroke-width=".2"/>
<circle cx="73" cy="173" r=".49" fill="#008000" stroke="#008000" stroke-width=".2"/>
<circle cx="73" cy="173" r=".28" fill="#fff" stroke="#000" stroke-width=".2"/>
<circle cx="98.6" cy="145.5" r=".49" fill="#008000" stroke="#008000" stroke-width=".2"/>
<circle cx="98.6" cy="145.5" r=".28" fill="#fff" stroke="#000" stroke-width=".2"/>
<circle cx="100.1" cy="146.9" r=".49" fill="#008000" stroke="#008000" stroke-width=".2"/>
<circle cx="100.1" cy="146.9" r=".28" fill="#fff" stroke="#000" stroke-width=".2"/>
<circle cx="84.1" cy="118.1" r=".49" fill="#008000" stroke="#008000" stroke-width=".2"/>
<circle cx="84.1" cy="118.1" r=".28" fill="#fff" stroke="#000" stroke-width=".2"/>
<circle cx="46.1" cy="128.3" r=".49" fill="#008000" stroke="#008000" stroke-width=".2"/>
<circle cx="46.1" cy="128.3" r=".28" fill="#fff" stroke="#000" stroke-width=".2"/>
<circle cx="138.8" cy="53.3" r=".49" fill="#008000" stroke="#008000" stroke-width=".2"/>
<circle cx="138.8" cy="53.3" r=".28" fill="#fff" stroke="#000" stroke-width=".2"/>
<circle cx="112.8" cy="133.3" r=".49" fill="#008000" stroke="#008000" stroke-width=".2"/>
<circle cx="112.8" cy="133.3" r=".28" fill="#fff" stroke="#000" stroke-width=".2"/>
<circle cx="128.8" cy="141.8" r=".49" fill="#008000" stroke="#008000" stroke-width=".2"/>
<circle cx="128.8" cy="141.8" r=".28" fill="#fff" stroke="#000" stroke-width=".2"/>
<circle cx="133.3" cy="125.2" r=".49" fill="#008000" stroke="#008000" stroke-width=".2"/>
<circle cx="133.3" cy="125.2" r=".28" fill="#fff" stroke="#000" stroke-width=".2"/>
<circle cx="138.8" cy="77.5" r=".49" fill="#008000" stroke="#008000" stroke-width=".2"/>
<circle cx="138.8" cy="77.5" r=".28" fill="#fff" stroke="#000" stroke-width=".2"/>
<circle cx="120.3" cy="84.8" r=".49" fill="#008000" stroke="#008000" stroke-width=".2"/>
<circle cx="120.3" cy="84.8" r=".28" fill="#fff" stroke="#000" stroke-width=".2"/>
<circle cx="90" cy="116.5" r=".49" fill="#008000" stroke="#008000" stroke-width=".2"/>
<circle cx="90" cy="116.5" r=".28" fill="#fff" stroke="#000" stroke-width=".2"/>
<circle cx="98.9" cy="22.1" r=".49" fill="#008000" stroke="#008000" stroke-width=".2"/>
<circle cx="98.9" cy="22.1" r=".28" fill="#fff" stroke="#000" stroke-width=".2"/>
<circle cx="100.7" cy="25.7" r=".49" fill="#008000" stroke="#008000" stroke-width=".2"/>
<circle cx="100.7" cy="25.7" r=".28" fill="#fff" stroke="#000" stroke-width=".2"/>
<circle cx="49.8" cy="117.6" r=".49" fill="#008000" stroke="#008000" stroke-width=".2"/>
<circle cx="49.8" cy="117.6" r=".28" fill="#fff" stroke="#000" stroke-width=".2"/>
<circle cx="53.7" cy="116.8" r=".49" fill="#008000" stroke="#008000" stroke-width=".2"/>
<circle cx="53.7" cy="116.8" r=".28" fill="#fff" stroke="#000" stroke-width=".2"/>
<circle cx="121.1" cy="191.6" r=".49" fill="#008000" stroke="#008000" stroke-width=".2"/>
<circle cx="121.1" cy="191.6" r=".28" fill="#fff" stroke="#000" stroke-width=".2"/>
<circle cx="121.9" cy="187.6" r=".49" fill="#008000" stroke="#008000" stroke-width=".2"/>
<circle cx="121.9" cy="187.6" r=".28" fill="#fff" stroke="#000" stroke-width=".2"/>
<circle cx="97.3" cy="35.8" r=".49" fill="#008000" stroke="#008000" stroke-width=".2"/>
<circle cx="97.3" cy="35.8" r=".28" fill="#fff" stroke="#000" stroke-width=".2"/>
<circle cx="93.6" cy="29.9" r=".49" fill="#008000" stroke="#008000" stroke-width=".2"/>
<circle cx="93.6" cy="29.9" r=".28" fill="#fff" stroke="#000" stroke-width=".2"/>
<circle cx="66.2" cy="134.5" r=".49" fill="#008000" stroke="#008000" stroke-width=".2"/>
<circle cx="66.2" cy="134.5" r=".28" fill="#fff" stroke="#000" stroke-width=".2"/>
<circle cx="60.2" cy="138.4" r=".49" fill="#008000" stroke="#008000" stroke-width=".2"/>
<circle cx="60.2" cy="138.4" r=".28" fill="#fff" stroke="#000" stroke-width=".2"/>
<circle cx="83.1" cy="64.5" r=".49" fill="#008000" stroke="#008000" stroke-width=".2"/>
<circle cx="83.1" cy="64.5" r=".28" fill="#fff" stroke="#000" stroke-width=".2"/>
<circle cx="68.8" cy="52.6" r=".49" fill="#008000" stroke="#008000" stroke-width=".2"/>
<circle cx="68.8" cy="52.6" r=".28" fill="#fff" stroke="#000" stroke-width=".2"/>
<circle cx="105.3" cy="161.9" r=".49" fill="#008000" stroke="#008000" stroke-width=".2"/>
<circle cx="105.3" cy="161.9" r=".28" fill="#fff" stroke="#000" stroke-width=".2"/>
<circle cx="118.2" cy="143.7" r=".49" fill="#008000" stroke="#008000" stroke-width=".2"/>
<circle cx="118.2" cy="143.7" r=".28" fill="#fff" stroke="#000" stroke-width=".2"/>
<circle cx="108.7" cy="163.6" r=".49" fill="#008000" stroke="#008000" stroke-width=".2"/>
<circle cx="108.7" cy="163.6" r=".28" fill="#fff" stroke="#000" stroke-width=".2"/>
<circle cx="100.5" cy="180.4" r=".49" fill="#008000" stroke="#008000" stroke-width=".2"/>
<circle cx="100.5" cy="180.4" r=".28" fill="#fff" stroke="#000" stroke-width=".2"/>
<circle cx="82" cy="105.7" r=".49" fill="#008000" stroke="#008000" stroke-width=".2"/>
<circle cx="82" cy="105.7" r=".28" fill="#fff" stroke="#000" stroke-width=".2"/>
<circle cx="52.7" cy="105.7" r=".49" fill="#008000" stroke="#008000" stroke-width=".2"/>
<circle cx="52.7" cy="105.7" r=".28" fill="#fff" stroke="#000" stroke-width=".2"/>
<circle cx="124.1" cy="61.4" r=".49" fill="#008000" stroke="#008000" stroke-width=".2"/>
<circle cx="124.1" cy="61.4" r=".28" fill="#fff" stroke="#000" stroke-width=".2"/>
<circle cx="111" cy="21.4" r=".49" fill="#008000" stroke="#008000" stroke-width=".2"/>
<circle cx="111" cy="21.4" r=".28" fill="#fff" stroke="#000" stroke-width=".2"/>
<circle cx="124.7" cy="72" r=".49" fill="#008000" stroke="#008000" stroke-width=".2"/>
<circle cx="124.7" cy="72" r=".28" fill="#fff" stroke="#000" stroke-width=".2"/>
<circle cx="119.9" cy="61.7" r=".49" fill="#008000" stroke="#008000" stroke-width=".2"/>
<circle cx="119.9" cy="61.7" r=".28" fill="#fff" stroke="#000" stroke-width=".2"/>
<circle cx="132.5" cy="110" r=".49" fill="#008000" stroke="#008000" stroke-width=".2"/>
<circle cx="132.5" cy="110" r=".28" fill="#fff" stroke="#000" stroke-width=".2"/>
<circle cx="100.8" cy="137.8" r=".49" fill="#008000" stroke="#008000" stroke-width=".2"/>
<circle cx="100.8" cy="137.8" r=".28" fill="#fff" stroke="#000" stroke-width=".2"/>
<circle cx="113.2" cy="147.8" r=".49" fill="#008000" stroke="#008000" stroke-width=".2"/>
<circle cx="113.2" cy="147.8" r=".28" fill="#fff" stroke="#000" stroke-width=".2"/>
<circle cx="90.1" cy="120.2" r=".49" fill="#008000" stroke="#008000" stroke-width=".2"/>
<circle cx="90.1" cy="120.2" r=".28" fill="#fff" stroke="#000" stroke-width=".2"/>
<circle cx="57.7" cy="132" r=".49" fill="#008000" stroke="#008000" stroke-width=".2"/>
<circle cx="57.7" cy="132" r=".28" fill="#fff" stroke="#000" stroke-width=".2"/>
<circle cx="86.1" cy="29.8" r=".49" fill="#008000" stroke="#008000" stroke-width=".2"/>
<circle cx="86.1" cy="29.8" r=".28" fill="#fff" stroke="#000" stroke-width=".2"/>
<circle cx="88.9" cy="34.5" r=".49" fill="#008000" stroke="#008000" stroke-width=".2"/>
<circle cx="88.9" cy="34.5" r=".28" fill="#fff" stroke="#000" stroke-width=".2"/>
<circle cx="50.9" cy="123.8" r=".49" fill="#008000" stroke="#008000" stroke-width=".2"/>
<circle cx="50.9" cy="123.8" r=".28" fill="#fff" stroke="#000" stroke-width=".2"/>
<circle cx="56.3" cy="122.6" r=".49" fill="#008000" stroke="#008000" stroke-width=".2"/>
<circle cx="56.3" cy="122.6" r=".28" fill="#fff" stroke="#000" stroke-width=".2"/>
<circle cx="129.7" cy="193" r=".49" fill="#008000" stroke="#008000" stroke-width=".2"/>
<circle cx="129.7" cy="193" r=".28" fill="#fff" stroke="#000" stroke-width=".2"/>
<circle cx="130.2" cy="187.5" r=".49" fill="#008000" stroke="#008000" stroke-width=".2"/>
<circle cx="130.2" cy="187.5" r=".28" fill="#fff" stroke="#000" stroke-width=".2"/>
<circle cx="107.4" cy="30.5" r=".49" fill="#008000" stroke="#008000" stroke-width=".2"/>
<circle cx="107.4" cy="30.5" r=".28" fill="#fff" stroke="#000" stroke-width=".2"/>
<circle cx="104.5" cy="25.5" r=".49" fill="#008000" stroke="#008000" stroke-width=".2"/>
<circle cx="104.5" cy="25.5" r=".28" fill="#fff" stroke="#000" stroke-width=".2"/>
<circle cx="62.1" cy="122" r=".49" fill="#008000" stroke="#008000" stroke-width=".2"/>
<circle cx="62.1" cy="122" r=".28" fill="#fff" stroke="#000" stroke-width=".2"/>
<circle cx="76.7" cy="75.9" r=".49" fill="#008000" stroke="#008000" stroke-width=".2"/>
<circle cx="76.7" cy="75.9" r=".28" fill="#fff" stroke="#000" stroke-width=".2"/>
<circle cx="62.8" cy="65.5" r=".49" fill="#008000" stroke="#008000" stroke-width=".2"/>
<circle cx="62.8" cy="65.5" r=".28" fill="#fff" stroke="#000" stroke-width=".2"/>
<circle cx="119" cy="167.9" r=".49" fill="#008000" stroke="#008000" stroke-width=".2"/>
<circle cx="119" cy="167.9" r=".28" fill="#fff" stroke="#000" stroke-width=".2"/>
<circle cx="114" cy="184.2" r=".49" fill="#008000" stroke="#008000" stroke-width=".2"/>
<circle cx="114" cy="184.2" r=".28" fill="#fff" stroke="#000" stroke-width=".2"/>
<circle cx="82.8" cy="93.6" r=".49" fill="#008000" stroke="#008000" stroke-width=".2"/>
<circle cx="82.8" cy="93.6" r=".28" fill="#fff" stroke="#000" stroke-width=".2"/>
<circle cx="55.1" cy="89.5" r=".49" fill="#008000" stroke="#008000" stroke-width=".2"/>
<circle cx="55.1" cy="89.5" r=".28" fill="#fff" stroke="#000" stroke-width=".2"/>
<circle cx="118.2" cy="72.1" r=".49" fill="#008000" stroke="#008000" stroke-width=".2"/>
<circle cx="118.2" cy="72.1" r=".28" fill="#fff" stroke="#000" stroke-width=".2"/>
<circle cx="113.6" cy="65.1" r=".49" fill="#008000" stroke="#008000" stroke-width=".2"/>
<circle cx="113.6" cy="65.1" r=".28" fill="#fff" stroke="#000" stroke-width=".2"/>
<circle cx="137.6" cy="65.9" r=".49" fill="#008000" stroke="#008000" stroke-width=".2"/>
<circle cx="137.6" cy="65.9" r=".28" fill="#fff" stroke="#000" stroke-width=".2"/>
<circle cx="93.2" cy="31.6" r=".49" fill="#008000" stroke="#008000" stroke-width=".2"/>
<circle cx="93.2" cy="31.6" r=".28" fill="#fff" stroke="#000" stroke-width=".2"/>
<circle cx="134" cy="145.6" r=".49" fill="#008000" stroke="#008000" stroke-width=".2"/>
<circle cx="134" cy="145.6" r=".28" fill="#fff" stroke="#000" stroke-width=".2"/>
<circle cx="127" cy="102.7" r=".49" fill="#008000" stroke="#008000" stroke-width=".2"/>
<circle cx="127" cy="102.7" r=".28" fill="#fff" stroke="#000" stroke-width=".2"/>
<circle cx="55.1" cy="116.6" r=".49" fill="#008000" stroke="#008000" stroke-width=".2"/>
<circle cx="55.1" cy="116.6" r=".28" fill="#fff" stroke="#000" stroke-width=".2"/>
<circle cx="89.5" cy="114" r=".49" fill="#008000" stroke="#008000" stroke-width=".2"/>
<circle cx="89.5" cy="114" r=".28" fill="#fff" stroke="#000" stroke-width=".2"/>
<circle cx="79.3" cy="35.2" r=".49" fill="#008000" stroke="#008000" stroke-width=".2"/>
<circle cx="79.3" cy="35.2" r=".28" fill="#fff" stroke="#000" stroke-width=".2"/>
<circle cx="85.5" cy="42.2" r=".49" fill="#008000" stroke="#008000" stroke-width=".2"/>
<circle cx="85.5" cy="42.2" r=".28" fill="#fff" stroke="#000" stroke-width=".2"/>
<circle cx="55.5" cy="138" r=".49" fill="#008000" stroke="#008000" stroke-width=".2"/>
<circle cx="55.5" cy="138" r=".28" fill="#fff" stroke="#000" stroke-width=".2"/>
<circle cx="64.1" cy="134.5" r=".49" fill="#008000" stroke="#008000" stroke-width=".2"/>
<circle cx="64.1" cy="134.5" r=".28" fill="#fff" stroke="#000" stroke-width=".2"/>
<circle cx="119.4" cy="26.6" r=".49" fill="#008000" stroke="#008000" stroke-width=".2"/>
<circle cx="119.4" cy="26.6" r=".28" fill="#fff" stroke="#000" stroke-width=".2"/>
<circle cx="120.2" cy="23.8" r=".49" fill="#008000" stroke="#008000" stroke-width=".2"/>
<circle cx="120.2" cy="23.8" r=".28" fill="#fff" stroke="#000" stroke-width=".2"/>
<circle cx="60.2" cy="110.8" r=".49" fill="#008000" stroke="#008000" stroke-width=".2"/>
<circle cx="60.2" cy="110.8" r=".28" fill="#fff" stroke="#000" stroke-width=".2"/>
<circle cx="57.3" cy="111.1" r=".49" fill="#008000" stroke="#008000" stroke-width=".2"/>
<circle cx="57.3" cy="111.1" r=".28" fill="#fff" stroke="#000" stroke-width=".2"/>
<circle cx="127.3" cy="182.9" r=".49" fill="#008000" stroke="#008000" stroke-width=".2"/>
<circle cx="127.3" cy="182.9" r=".28" fill="#fff" stroke="#000" stroke-width=".2"/>
<circle cx="72.5" cy="89.7" r=".49" fill="#008000" stroke="#008000" stroke-width=".2"/>
<circle cx="72.5" cy="89.7" r=".28" fill="#fff" stroke="#000" stroke-width=".2"/>
<circle cx="58.8" cy="84.2" r=".49" fill="#008000" stroke="#008000" stroke-width=".2"/>
<circle cx="58.8" cy="84.2" r=".28" fill="#fff" stroke="#000" stroke-width=".2"/>
<circle cx="81.2" cy="91.4" r=".49" fill="#008000" stroke="#008000" stroke-width=".2"/>
<circle cx="81.2" cy="91.4" r=".28" fill="#fff" stroke="#000" stroke-width=".2"/>
<circle cx="85.9" cy="82.4" r=".49" fill="#008000" stroke="#008000" stroke-width=".2"/>
<circle cx="85.9" cy="82.4" r=".28" fill="#fff" stroke="#000" stroke-width=".2"/>
<circle cx="84" cy="81.9" r=".49" fill="#008000" stroke="#008000" stroke-width=".2"/>
<circle cx="84" cy="81.9" r=".28" fill="#fff" stroke="#000" stroke-width=".2"/>
<circle cx="105" cy="72.8" r=".49" fill="#008000" stroke="#008000" stroke-width=".2"/>
<circle cx="105" cy="72.8" r=".28" fill="#fff" stroke="#000" stroke-width=".2"/>
<circle cx="80.4" cy="44.9" r=".49" fill="#008000" stroke="#008000" stroke-width=".2"/>
<circle cx="80.4" cy="44.9" r=".28" fill="#fff" stroke="#000" stroke-width=".2"/>
<circle cx="141.5" cy="91.2" r=".49" fill="#008000" stroke="#008000" stroke-width=".2"/>
<circle cx="141.5" cy="91.2" r=".28" fill="#fff" stroke="#000" stroke-width=".2"/>
<circle cx="135.7" cy="91.5" r=".49" fill="#008000" stroke="#008000" stroke-width=".2"/>
<circle cx="135.7" cy="91.5" r=".28" fill="#fff" stroke="#000" stroke-width=".2"/>
<circle cx="132.7" cy="92.9" r=".49" fill="#008000" stroke="#008000" stroke-width=".2"/>
<circle cx="132.7" cy="92.9" r=".28" fill="#fff" stroke="#000" stroke-width=".2"/>
<circle cx="98" cy="32.7" r=".49" fill="#008000" stroke="#008000" stroke-width=".2"/>
<circle cx="98" cy="32.7" r=".28" fill="#fff" stroke="#000" stroke-width=".2"/>
<circle cx="122.8" cy="183" r=".49" fill="#008000" stroke="#008000" stroke-width=".2"/>
<circle cx="122.8" cy="183" r=".28" fill="#fff" stroke="#000" stroke-width=".2"/>
<circle cx="131.6" cy="140.7" r=".49" fill="#008000" stroke="#008000" stroke-width=".2"/>
<circle cx="131.6" cy="140.7" r=".28" fill="#fff" stroke="#000" stroke-width=".2"/>
<circle cx="88.4" cy="114.9" r=".49" fill="#008000" stroke="#008000" stroke-width=".2"/>
<circle cx="88.4" cy="114.9" r=".28" fill="#fff" stroke="#000" stroke-width=".2"/>
<circle cx="59.4" cy="123.8" r=".49" fill="#008000" stroke="#008000" stroke-width=".2"/>
<circle cx="59.4" cy="123.8" r=".28" fill="#fff" stroke="#000" stroke-width=".2"/>
<circle cx="68.9" cy="46" r=".49" fill="#008000" stroke="#008000" stroke-width=".2"/>
<circle cx="68.9" cy="46" r=".28" fill="#fff" stroke="#000" stroke-width=".2"/>
<circle cx="82" cy="56.4" r=".49" fill="#008000" stroke="#008000" stroke-width=".2"/>
<circle cx="82" cy="56.4" r=".28" fill="#fff" stroke="#000" stroke-width=".2"/>
<circle cx="62" cy="150.5" r=".49" fill="#008000" stroke="#008000" stroke-width=".2"/>
<circle cx="62" cy="150.5" r=".28" fill="#fff" stroke="#000" stroke-width=".2"/>
<circle cx="76.2" cy="141.5" r=".49" fill="#008000" stroke="#008000" stroke-width=".2"/>
<circle cx="76.2" cy="141.5" r=".28" fill="#fff" stroke="#000" stroke-width=".2"/>
<circle cx="144" cy="25.1" r=".49" fill="#008000" stroke="#008000" stroke-width=".2"/>
<circle cx="144" cy="25.1" r=".28" fill="#fff" stroke="#000" stroke-width=".2"/>
<circle cx="143.8" cy="29.1" r=".49" fill="#008000" stroke="#008000" stroke-width=".2"/>
<circle cx="143.8" cy="29.1" r=".28" fill="#fff" stroke="#000" stroke-width=".2"/>
<circle cx="59.9" cy="97.8" r=".49" fill="#008000" stroke="#008000" stroke-width=".2"/>
<circle cx="59.9" cy="97.8" r=".28" fill="#fff" stroke="#000" stroke-width=".2"/>
<circle cx="71.2" cy="100.1" r=".49" fill="#008000" stroke="#008000" stroke-width=".2"/>
<circle cx="71.2" cy="100.1" r=".28" fill="#fff" stroke="#000" stroke-width=".2"/>
<circle cx="118.4" cy="179.5" r=".49" fill="#008000" stroke="#008000" stroke-width=".2"/>
<circle cx="118.4" cy="179.5" r=".28" fill="#fff" stroke="#000" stroke-width=".2"/>
<circle cx="119.8" cy="174" r=".49" fill="#008000" stroke="#008000" stroke-width=".2"/>
<circle cx="119.8" cy="174" r=".28" fill="#fff" stroke="#000" stroke-width=".2"/>
<circle cx="92.7" cy="69.9" r=".49" fill="#008000" stroke="#008000" stroke-width=".2"/>
<circle cx="92.7" cy="69.9" r=".28" fill="#fff" stroke="#000" stroke-width=".2"/>
<circle cx="80.4" cy="58.6" r=".49" fill="#008000" stroke="#008000" stroke-width=".2"/>
<circle cx="80.4" cy="58.6" r=".28" fill="#fff" stroke="#000" stroke-width=".2"/>
<circle cx="129.3" cy="159.1" r=".49" fill="#008000" stroke="#008000" stroke-width=".2"/>
<circle cx="129.3" cy="159.1" r=".28" fill="#fff" stroke="#000" stroke-width=".2"/>
<circle cx="126.8" cy="175.6" r=".49" fill="#008000" stroke="#008000" stroke-width=".2"/>
<circle cx="126.8" cy="175.6" r=".28" fill="#fff" stroke="#000" stroke-width=".2"/>
<circle cx="98" cy="82.7" r=".49" fill="#008000" stroke="#008000" stroke-width=".2"/>
<circle cx="98" cy="82.7" r=".28" fill="#fff" stroke="#000" stroke-width=".2"/>
<circle cx="100.2" cy="73.7" r=".49" fill="#008000" stroke="#008000" stroke-width=".2"/>
<circle cx="100.2" cy="73.7" r=".28" fill="#fff" stroke="#000" stroke-width=".2"/>
<circle cx="109.3" cy="80.6" r=".49" fill="#008000" stroke="#008000" stroke-width=".2"/>
<circle cx="109.3" cy="80.6" r=".28" fill="#fff" stroke="#000" stroke-width=".2"/>
<circle cx="116.4" cy="74" r=".49" fill="#008000" stroke="#008000" stroke-width=".2"/>
<circle cx="116.4" cy="74" r=".28" fill="#fff" stroke="#000" stroke-width=".2"/>
<circle cx="124.4" cy="84.5" r=".49" fill="#008000" stroke="#008000" stroke-width=".2"/>
<circle cx="124.4" cy="84.5" r=".28" fill="#fff" stroke="#000" stroke-width=".2"/>
<circle cx="138.7" cy="100.7" r=".49" fill="#008000" stroke="#008000" stroke-width=".2"/>
<circle cx="138.7" cy="100.7" r=".28" fill="#fff" stroke="#000" stroke-width=".2"/>
<circle cx="120.2" cy="131.8" r=".49" fill="#008000" stroke="#008000" stroke-width=".2"/>
<circle cx="120.2" cy="131.8" r=".28" fill="#fff" stroke="#000" stroke-width=".2"/>
<circle cx="99.9" cy="165.4" r=".49" fill="#008000" stroke="#008000" stroke-width=".2"/>
<circle cx="99.9" cy="165.4" r=".28" fill="#fff" stroke="#000" stroke-width=".2"/>
<circle cx="87.4" cy="113.8" r=".49" fill="#008000" stroke="#008000" stroke-width=".2"/>
<circle cx="87.4" cy="113.8" r=".28" fill="#fff" stroke="#000" stroke-width=".2"/>
<circle cx="66.9" cy="118.4" r=".49" fill="#008000" stroke="#008000" stroke-width=".2"/>
<circle cx="66.9" cy="118.4" r=".28" fill="#fff" stroke="#000" stroke-width=".2"/>
<circle cx="65.5" cy="98.2" r=".49" fill="#008000" stroke="#008000" stroke-width=".2"/>
<circle cx="65.5" cy="98.2" r=".28" fill="#fff" stroke="#000" stroke-width=".2"/>
<circle cx="62.1" cy="55.6" r=".49" fill="#008000" stroke="#008000" stroke-width=".2"/>
<circle cx="62.1" cy="55.6" r=".28" fill="#fff" stroke="#000" stroke-width=".2"/>
<circle cx="77.6" cy="65" r=".49" fill="#008000" stroke="#008000" stroke-width=".2"/>
<circle cx="77.6" cy="65" r=".28" fill="#fff" stroke="#000" stroke-width=".2"/>
<circle cx="68.8" cy="160.2" r=".49" fill="#008000" stroke="#008000" stroke-width=".2"/>
<circle cx="68.8" cy="160.2" r=".28" fill="#fff" stroke="#000" stroke-width=".2"/>
<circle cx="62" cy="84.8" r=".49" fill="#008000" stroke="#008000" stroke-width=".2"/>
<circle cx="62" cy="84.8" r=".28" fill="#fff" stroke="#000" stroke-width=".2"/>
<circle cx="68.7" cy="86.4" r=".49" fill="#008000" stroke="#008000" stroke-width=".2"/>
<circle cx="68.7" cy="86.4" r=".28" fill="#fff" stroke="#000" stroke-width=".2"/>
<circle cx="108.9" cy="176.3" r=".49" fill="#008000" stroke="#008000" stroke-width=".2"/>
<circle cx="108.9" cy="176.3" r=".28" fill="#fff" stroke="#000" stroke-width=".2"/>
<circle cx="111.7" cy="169.4" r=".49" fill="#008000" stroke="#008000" stroke-width=".2"/>
<circle cx="111.7" cy="169.4" r=".28" fill="#fff" stroke="#000" stroke-width=".2"/>
<circle cx="138.8" cy="31.4" r=".49" fill="#008000" stroke="#008000" stroke-width=".2"/>
<circle cx="138.8" cy="31.4" r=".28" fill="#fff" stroke="#000" stroke-width=".2"/>
<circle cx="101.4" cy="60.2" r=".49" fill="#008000" stroke="#008000" stroke-width=".2"/>
<circle cx="101.4" cy="60.2" r=".28" fill="#fff" stroke="#000" stroke-width=".2"/>
<circle cx="91.5" cy="48.9" r=".49" fill="#008000" stroke="#008000" stroke-width=".2"/>
<circle cx="91.5" cy="48.9" r=".28" fill="#fff" stroke="#000" stroke-width=".2"/>
<circle cx="117.4" cy="155.7" r=".49" fill="#008000" stroke="#008000" stroke-width=".2"/>
<circle cx="117.4" cy="155.7" r=".28" fill="#fff" stroke="#000" stroke-width=".2"/>
<circle cx="96.2" cy="85.7" r=".49" fill="#008000" stroke="#008000" stroke-width=".2"/>
<circle cx="96.2" cy="85.7" r=".28" fill="#fff" stroke="#000" stroke-width=".2"/>
<circle cx="101.9" cy="88" r=".49" fill="#008000" stroke="#008000" stroke-width=".2"/>
<circle cx="101.9" cy="88" r=".28" fill="#fff" stroke="#000" stroke-width=".2"/>
<circle cx="104.3" cy="83.4" r=".49" fill="#008000" stroke="#008000" stroke-width=".2"/>
<circle cx="104.3" cy="83.4" r=".28" fill="#fff" stroke="#000" stroke-width=".2"/>
<circle cx="118.3" cy="91.5" r=".49" fill="#008000" stroke="#008000" stroke-width=".2"/>
<circle cx="118.3" cy="91.5" r=".28" fill="#fff" stroke="#000" stroke-width=".2"/>
<circle cx="111.4" cy="121.7" r=".49" fill="#008000" stroke="#008000" stroke-width=".2"/>
<circle cx="111.4" cy="121.7" r=".28" fill="#fff" stroke="#000" stroke-width=".2"/>
<circle cx="130.6" cy="120.5" r=".49" fill="#008000" stroke="#008000" stroke-width=".2"/>
<circle cx="130.6" cy="120.5" r=".28" fill="#fff" stroke="#000" stroke-width=".2"/>
<circle cx="124" cy="115.8" r=".49" fill="#008000" stroke="#008000" stroke-width=".2"/>
<circle cx="124" cy="115.8" r=".28" fill="#fff" stroke="#000" stroke-width=".2"/>
<circle cx="71.6" cy="111.7" r=".49" fill="#008000" stroke="#008000" stroke-width=".2"/>
<circle cx="71.6" cy="111.7" r=".28" fill="#fff" stroke="#000" stroke-width=".2"/>
<circle cx="67.5" cy="110" r=".49" fill="#008000" stroke="#008000" stroke-width=".2"/>
<circle cx="67.5" cy="110" r=".28" fill="#fff" stroke="#000" stroke-width=".2"/>
<circle cx="87.9" cy="116.1" r=".49" fill="#008000" stroke="#008000" stroke-width=".2"/>
<circle cx="87.9" cy="116.1" r=".28" fill="#fff" stroke="#000" stroke-width=".2"/>
<circle cx="69.2" cy="120.8" r=".49" fill="#008000" stroke="#008000" stroke-width=".2"/>
<circle cx="69.2" cy="120.8" r=".28" fill="#fff" stroke="#000" stroke-width=".2"/>
<circle cx="72.4" cy="76" r=".49" fill="#008000" stroke="#008000" stroke-width=".2"/>
<circle cx="72.4" cy="76" r=".28" fill="#fff" stroke="#000" stroke-width=".2"/>
<circle cx="83.2" cy="148.3" r=".49" fill="#008000" stroke="#008000" stroke-width=".2"/>
<circle cx="83.2" cy="148.3" r=".28" fill="#fff" stroke="#000" stroke-width=".2"/>
<circle cx="113" cy="98.3" r=".49" fill="#008000" stroke="#008000" stroke-width=".2"/>
<circle cx="113" cy="98.3" r=".28" fill="#fff" stroke="#000" stroke-width=".2"/>
<circle cx="90.2" cy="91.5" r=".49" fill="#008000" stroke="#008000" stroke-width=".2"/>
<circle cx="90.2" cy="91.5" r=".28" fill="#fff" stroke="#000" stroke-width=".2"/>
<circle cx="74.8" cy="167" r=".49" fill="#008000" stroke="#008000" stroke-width=".2"/>
<circle cx="74.8" cy="167" r=".28" fill="#fff" stroke="#000" stroke-width=".2"/>
<circle cx="105.1" cy="137.5" r=".49" fill="#008000" stroke="#008000" stroke-width=".2"/>
<circle cx="105.1" cy="137.5" r=".28" fill="#fff" stroke="#000" stroke-width=".2"/>
<circle cx="99.5" cy="143" r=".49" fill="#008000" stroke="#008000" stroke-width=".2"/>
<circle cx="99.5" cy="143" r=".28" fill="#fff" stroke="#000" stroke-width=".2"/>
<circle cx="85.9" cy="156.2" r=".49" fill="#008000" stroke="#008000" stroke-width=".2"/>
<circle cx="85.9" cy="156.2" r=".28" fill="#fff" stroke="#000" stroke-width=".2"/>
<circle cx="74.4" cy="124.5" r=".49" fill="#008000" stroke="#008000" stroke-width=".2"/>
<circle cx="74.4" cy="124.5" r=".28" fill="#fff" stroke="#000" stroke-width=".2"/>
<circle cx="93" cy="118.2" r=".49" fill="#008000" stroke="#008000" stroke-width=".2"/>
<circle cx="93" cy="118.2" r=".28" fill="#fff" stroke="#000" stroke-width=".2"/>
<circle cx="95.1" cy="82.6" r=".49" fill="#008000" stroke="#008000" stroke-width=".2"/>
<circle cx="95.1" cy="82.6" r=".28" fill="#fff" stroke="#000" stroke-width=".2"/>
<circle cx="56.6" cy="66" r=".49" fill="#008000" stroke="#008000" stroke-width=".2"/>
<circle cx="56.6" cy="66" r=".28" fill="#fff" stroke="#000" stroke-width=".2"/>
<circle cx="65.8" cy="72.9" r=".49" fill="#008000" stroke="#008000" stroke-width=".2"/>
<circle cx="65.8" cy="72.9" r=".28" fill="#fff" stroke="#000" stroke-width=".2"/>
<circle cx="117.4" cy="51.5" r=".49" fill="#008000" stroke="#008000" stroke-width=".2"/>
<circle cx="117.4" cy="51.5" r=".28" fill="#fff" stroke="#000" stroke-width=".2"/>
<circle cx="120.2" cy="58.5" r=".49" fill="#008000" stroke="#008000" stroke-width=".2"/>
<circle cx="120.2" cy="58.5" r=".28" fill="#fff" stroke="#000" stroke-width=".2"/>
<circle cx="123.2" cy="35.1" r=".49" fill="#008000" stroke="#008000" stroke-width=".2"/>
<circle cx="123.2" cy="35.1" r=".28" fill="#fff" stroke="#000" stroke-width=".2"/>
<circle cx="127" cy="52.4" r=".49" fill="#008000" stroke="#008000" stroke-width=".2"/>
<circle cx="127" cy="52.4" r=".28" fill="#fff" stroke="#000" stroke-width=".2"/>
<circle cx="118.9" cy="55.1" r=".49" fill="#008000" stroke="#008000" stroke-width=".2"/>
<circle cx="118.9" cy="55.1" r=".28" fill="#fff" stroke="#000" stroke-width=".2"/>
<circle cx="87" cy="120.2" r=".49" fill="#008000" stroke="#008000" stroke-width=".2"/>
<circle cx="87" cy="120.2" r=".28" fill="#fff" stroke="#000" stroke-width=".2"/>
<circle cx="130.5" cy="19.8" r=".49" fill="#008000" stroke="#008000" stroke-width=".2"/>
<circle cx="130.5" cy="19.8" r=".28" fill="#fff" stroke="#000" stroke-width=".2"/>
<circle cx="129.9" cy="14.3" r=".49" fill="#008000" stroke="#008000" stroke-width=".2"/>
<circle cx="129.9" cy="14.3" r=".28" fill="#fff" stroke="#000" stroke-width=".2"/>
<circle cx="120.8" cy="17.7" r=".49" fill="#008000" stroke="#008000" stroke-width=".2"/>
<circle cx="120.8" cy="17.7" r=".28" fill="#fff" stroke="#000" stroke-width=".2"/>
<circle cx="113" cy="23.3" r=".49" fill="#008000" stroke="#008000" stroke-width=".2"/>
<circle cx="113" cy="23.3" r=".28" fill="#fff" stroke="#000" stroke-width=".2"/>
<circle cx="118.7" cy="35.7" r=".49" fill="#008000" stroke="#008000" stroke-width=".2"/>
<circle cx="118.7" cy="35.7" r=".28" fill="#fff" stroke="#000" stroke-width=".2"/>
<circle cx="71.5" cy="82.7" r=".49" fill="#008000" stroke="#008000" stroke-width=".2"/>
<circle cx="71.5" cy="82.7" r=".28" fill="#fff" stroke="#000" stroke-width=".2"/>
<circle cx="52" cy="76.9" r=".49" fill="#008000" stroke="#008000" stroke-width=".2"/>
<circle cx="52" cy="76.9" r=".28" fill="#fff" stroke="#000" stroke-width=".2"/>
<circle cx="111" cy="24.2" r=".49" fill="#008000" stroke="#008000" stroke-width=".2"/>
<circle cx="111" cy="24.2" r=".28" fill="#fff" stroke="#000" stroke-width=".2"/>
<circle cx="117.4" cy="43.5" r=".49" fill="#008000" stroke="#008000" stroke-width=".2"/>
<circle cx="117.4" cy="43.5" r=".28" fill="#fff" stroke="#000" stroke-width=".2"/>
<circle cx="75.8" cy="95.2" r=".49" fill="#008000" stroke="#008000" stroke-width=".2"/>
<circle cx="75.8" cy="95.2" r=".28" fill="#fff" stroke="#000" stroke-width=".2"/>
<circle cx="50.3" cy="91.7" r=".49" fill="#008000" stroke="#008000" stroke-width=".2"/>
<circle cx="50.3" cy="91.7" r=".28" fill="#fff" stroke="#000" stroke-width=".2"/>
<circle cx="100.8" cy="28.5" r=".49" fill="#008000" stroke="#008000" stroke-width=".2"/>
<circle cx="100.8" cy="28.5" r=".28" fill="#fff" stroke="#000" stroke-width=".2"/>
<circle cx="51.1" cy="94.2" r=".49" fill="#008000" stroke="#008000" stroke-width=".2"/>
<circle cx="51.1" cy="94.2" r=".28" fill="#fff" stroke="#000" stroke-width=".2"/>
<circle cx="112.1" cy="48.7" r=".49" fill="#008000" stroke="#008000" stroke-width=".2"/>
<circle cx="112.1" cy="48.7" r=".28" fill="#fff" stroke="#000" stroke-width=".2"/>
<circle cx="76.5" cy="97.7" r=".49" fill="#008000" stroke="#008000" stroke-width=".2"/>
<circle cx="76.5" cy="97.7" r=".28" fill="#fff" stroke="#000" stroke-width=".2"/>
<circle cx="93.5" cy="182.3" r=".49" fill="#008000" stroke="#008000" stroke-width=".2"/>
<circle cx="93.5" cy="182.3" r=".28" fill="#fff" stroke="#000" stroke-width=".2"/>
<circle cx="98.1" cy="170.8" r=".49" fill="#008000" stroke="#008000" stroke-width=".2"/>
<circle cx="98.1" cy="170.8" r=".28" fill="#fff" stroke="#000" stroke-width=".2"/>
<circle cx="99.2" cy="29.3" r=".49" fill="#008000" stroke="#008000" stroke-width=".2"/>
<circle cx="99.2" cy="29.3" r=".28" fill="#fff" stroke="#000" stroke-width=".2"/>
<circle cx="131" cy="163.2" r=".49" fill="#008000" stroke="#008000" stroke-width=".2"/>
<circle cx="131" cy="163.2" r=".28" fill="#fff" stroke="#000" stroke-width=".2"/>
<circle cx="127.2" cy="194.1" r=".49" fill="#008000" stroke="#008000" stroke-width=".2"/>
<circle cx="127.2" cy="194.1" r=".28" fill="#fff" stroke="#000" stroke-width=".2"/>
<circle cx="110.6" cy="50" r=".49" fill="#008000" stroke="#008000" stroke-width=".2"/>
<circle cx="110.6" cy="50" r=".28" fill="#fff" stroke="#000" stroke-width=".2"/>
<circle cx="110.1" cy="175.6" r=".49" fill="#008000" stroke="#008000" stroke-width=".2"/>
<circle cx="110.1" cy="175.6" r=".28" fill="#fff" stroke="#000" stroke-width=".2"/>
<circle cx="107.7" cy="186.8" r=".49" fill="#008000" stroke="#008000" stroke-width=".2"/>
<circle cx="107.7" cy="186.8" r=".28" fill="#fff" stroke="#000" stroke-width=".2"/>
<circle cx="89.9" cy="35.8" r=".49" fill="#008000" stroke="#008000" stroke-width=".2"/>
<circle cx="89.9" cy="35.8" r=".28" fill="#fff" stroke="#000" stroke-width=".2"/>
<circle cx="84.7" cy="24.9" r=".49" fill="#008000" stroke="#008000" stroke-width=".2"/>
<circle cx="84.7" cy="24.9" r=".28" fill="#fff" stroke="#000" stroke-width=".2"/>
<circle cx="43.9" cy="97" r=".49" fill="#008000" stroke="#008000" stroke-width=".2"/>
<circle cx="43.9" cy="97" r=".28" fill="#fff" stroke="#000" stroke-width=".2"/>
<circle cx="55.3" cy="97.5" r=".49" fill="#008000" stroke="#008000" stroke-width=".2"/>
<circle cx="55.3" cy="97.5" r=".28" fill="#fff" stroke="#000" stroke-width=".2"/>
<circle cx="55.4" cy="111.4" r=".49" fill="#008000" stroke="#008000" stroke-width=".2"/>
<circle cx="55.4" cy="111.4" r=".28" fill="#fff" stroke="#000" stroke-width=".2"/>
<circle cx="44.2" cy="112.5" r=".49" fill="#008000" stroke="#008000" stroke-width=".2"/>
<circle cx="44.2" cy="112.5" r=".28" fill="#fff" stroke="#000" stroke-width=".2"/>
<circle cx="110.1" cy="187.6" r=".49" fill="#008000" stroke="#008000" stroke-width=".2"/>
<circle cx="110.1" cy="187.6" r=".28" fill="#fff" stroke="#000" stroke-width=".2"/>
<circle cx="108.2" cy="193.1" r=".49" fill="#008000" stroke="#008000" stroke-width=".2"/>
<circle cx="108.2" cy="193.1" r=".28" fill="#fff" stroke="#000" stroke-width=".2"/>
<circle cx="121.2" cy="177" r=".49" fill="#008000" stroke="#008000" stroke-width=".2"/>
<circle cx="121.2" cy="177" r=".28" fill="#fff" stroke="#000" stroke-width=".2"/>
<circle cx="118.7" cy="187.9" r=".49" fill="#008000" stroke="#008000" stroke-width=".2"/>
<circle cx="118.7" cy="187.9" r=".28" fill="#fff" stroke="#000" stroke-width=".2"/>
<circle cx="84.6" cy="39.4" r=".49" fill="#008000" stroke="#008000" stroke-width=".2"/>
<circle cx="84.6" cy="39.4" r=".28" fill="#fff" stroke="#000" stroke-width=".2"/>
<circle cx="101.6" cy="57.2" r=".49" fill="#008000" stroke="#008000" stroke-width=".2"/>
<circle cx="101.6" cy="57.2" r=".28" fill="#fff" stroke="#000" stroke-width=".2"/>
<circle cx="101.1" cy="148.8" r=".49" fill="#008000" stroke="#008000" stroke-width=".2"/>
<circle cx="101.1" cy="148.8" r=".28" fill="#fff" stroke="#000" stroke-width=".2"/>
<circle cx="81.8" cy="169.3" r=".49" fill="#008000" stroke="#008000" stroke-width=".2"/>
<circle cx="81.8" cy="169.3" r=".28" fill="#fff" stroke="#000" stroke-width=".2"/>
<circle cx="82.9" cy="40.8" r=".49" fill="#008000" stroke="#008000" stroke-width=".2"/>
<circle cx="82.9" cy="40.8" r=".28" fill="#fff" stroke="#000" stroke-width=".2"/>
<circle cx="76.7" cy="33.9" r=".49" fill="#008000" stroke="#008000" stroke-width=".2"/>
<circle cx="76.7" cy="33.9" r=".28" fill="#fff" stroke="#000" stroke-width=".2"/>
<circle cx="53.1" cy="67.2" r=".49" fill="#008000" stroke="#008000" stroke-width=".2"/>
<circle cx="53.1" cy="67.2" r=".28" fill="#fff" stroke="#000" stroke-width=".2"/>
<circle cx="63.4" cy="71.6" r=".49" fill="#008000" stroke="#008000" stroke-width=".2"/>
<circle cx="63.4" cy="71.6" r=".28" fill="#fff" stroke="#000" stroke-width=".2"/>
<circle cx="73.7" cy="65.7" r=".49" fill="#008000" stroke="#008000" stroke-width=".2"/>
<circle cx="73.7" cy="65.7" r=".28" fill="#fff" stroke="#000" stroke-width=".2"/>
<circle cx="84.5" cy="51.8" r=".49" fill="#008000" stroke="#008000" stroke-width=".2"/>
<circle cx="84.5" cy="51.8" r=".28" fill="#fff" stroke="#000" stroke-width=".2"/>
<circle cx="78.8" cy="44.6" r=".49" fill="#008000" stroke="#008000" stroke-width=".2"/>
<circle cx="78.8" cy="44.6" r=".28" fill="#fff" stroke="#000" stroke-width=".2"/>
<circle cx="70.4" cy="55.2" r=".49" fill="#008000" stroke="#008000" stroke-width=".2"/>
<circle cx="70.4" cy="55.2" r=".28" fill="#fff" stroke="#000" stroke-width=".2"/>
<circle cx="72.4" cy="66.1" r=".49" fill="#008000" stroke="#008000" stroke-width=".2"/>
<circle cx="72.4" cy="66.1" r=".28" fill="#fff" stroke="#000" stroke-width=".2"/>
<circle cx="75.6" cy="60.7" r=".49" fill="#008000" stroke="#008000" stroke-width=".2"/>
<circle cx="75.6" cy="60.7" r=".28" fill="#fff" stroke="#000" stroke-width=".2"/>
<circle cx="130.9" cy="23.5" r=".49" fill="#008000" stroke="#008000" stroke-width=".2"/>
<circle cx="130.9" cy="23.5" r=".28" fill="#fff" stroke="#000" stroke-width=".2"/>
<circle cx="132.1" cy="35.2" r=".49" fill="#008000" stroke="#008000" stroke-width=".2"/>
<circle cx="132.1" cy="35.2" r=".28" fill="#fff" stroke="#000" stroke-width=".2"/>
<circle cx="71.8" cy="56.2" r=".49" fill="#008000" stroke="#008000" stroke-width=".2"/>
<circle cx="71.8" cy="56.2" r=".28" fill="#fff" stroke="#000" stroke-width=".2"/>
<circle cx="132.3" cy="25.4" r=".49" fill="#008000" stroke="#008000" stroke-width=".2"/>
<circle cx="132.3" cy="25.4" r=".28" fill="#fff" stroke="#000" stroke-width=".2"/>
<circle cx="133.5" cy="36.6" r=".49" fill="#008000" stroke="#008000" stroke-width=".2"/>
<circle cx="133.5" cy="36.6" r=".28" fill="#fff" stroke="#000" stroke-width=".2"/>
<circle cx="66.8" cy="60.6" r=".49" fill="#008000" stroke="#008000" stroke-width=".2"/>
<circle cx="66.8" cy="60.6" r=".28" fill="#fff" stroke="#000" stroke-width=".2"/>
<circle cx="130.3" cy="39.1" r=".49" fill="#008000" stroke="#008000" stroke-width=".2"/>
<circle cx="130.3" cy="39.1" r=".28" fill="#fff" stroke="#000" stroke-width=".2"/>
<circle cx="129.1" cy="27.8" r=".49" fill="#008000" stroke="#008000" stroke-width=".2"/>
<circle cx="129.1" cy="27.8" r=".28" fill="#fff" stroke="#000" stroke-width=".2"/>
<circle cx="63.4" cy="66.8" r=".49" fill="#008000" stroke="#008000" stroke-width=".2"/>
<circle cx="63.4" cy="66.8" r=".28" fill="#fff" stroke="#000" stroke-width=".2"/>
<circle cx="71.5" cy="71.2" r=".49" fill="#008000" stroke="#008000" stroke-width=".2"/>
<circle cx="71.5" cy="71.2" r=".28" fill="#fff" stroke="#000" stroke-width=".2"/>
<circle cx="77.6" cy="60.6" r=".49" fill="#008000" stroke="#008000" stroke-width=".2"/>
<circle cx="77.6" cy="60.6" r=".28" fill="#fff" stroke="#000" stroke-width=".2"/>
<circle cx="115.8" cy="183.5" r=".49" fill="#008000" stroke="#008000" stroke-width=".2"/>
<circle cx="115.8" cy="183.5" r=".28" fill="#fff" stroke="#000" stroke-width=".2"/>
<circle cx="132.7" cy="123.7" r=".49" fill="#008000" stroke="#008000" stroke-width=".2"/>
<circle cx="132.7" cy="123.7" r=".28" fill="#fff" stroke="#000" stroke-width=".2"/>
<circle cx="119.4" cy="111.7" r=".49" fill="#008000" stroke="#008000" stroke-width=".2"/>
<circle cx="119.4" cy="111.7" r=".28" fill="#fff" stroke="#000" stroke-width=".2"/>
<circle cx="129.9" cy="103" r=".49" fill="#008000" stroke="#008000" stroke-width=".2"/>
<circle cx="129.9" cy="103" r=".28" fill="#fff" stroke="#000" stroke-width=".2"/>
<circle cx="59.1" cy="77.4" r=".49" fill="#008000" stroke="#008000" stroke-width=".2"/>
<circle cx="59.1" cy="77.4" r=".28" fill="#fff" stroke="#000" stroke-width=".2"/>
<circle cx="73.4" cy="82" r=".49" fill="#008000" stroke="#008000" stroke-width=".2"/>
<circle cx="73.4" cy="82" r=".28" fill="#fff" stroke="#000" stroke-width=".2"/>
<circle cx="57.3" cy="83.9" r=".49" fill="#008000" stroke="#008000" stroke-width=".2"/>
<circle cx="57.3" cy="83.9" r=".28" fill="#fff" stroke="#000" stroke-width=".2"/>
<circle cx="73.7" cy="88.5" r=".49" fill="#008000" stroke="#008000" stroke-width=".2"/>
<circle cx="73.7" cy="88.5" r=".28" fill="#fff" stroke="#000" stroke-width=".2"/>
<circle cx="56" cy="91" r=".49" fill="#008000" stroke="#008000" stroke-width=".2"/>
<circle cx="56" cy="91" r=".28" fill="#fff" stroke="#000" stroke-width=".2"/>
<circle cx="75" cy="93.7" r=".49" fill="#008000" stroke="#008000" stroke-width=".2"/>
<circle cx="75" cy="93.7" r=".28" fill="#fff" stroke="#000" stroke-width=".2"/>
<circle cx="106.3" cy="163" r=".49" fill="#008000" stroke="#008000" stroke-width=".2"/>
<circle cx="106.3" cy="163" r=".28" fill="#fff" stroke="#000" stroke-width=".2"/>
<circle cx="111.4" cy="153.4" r=".49" fill="#008000" stroke="#008000" stroke-width=".2"/>
<circle cx="111.4" cy="153.4" r=".28" fill="#fff" stroke="#000" stroke-width=".2"/>
<circle cx="57.4" cy="96.7" r=".49" fill="#008000" stroke="#008000" stroke-width=".2"/>
<circle cx="57.4" cy="96.7" r=".28" fill="#fff" stroke="#000" stroke-width=".2"/>
<circle cx="69.4" cy="97.4" r=".49" fill="#008000" stroke="#008000" stroke-width=".2"/>
<circle cx="69.4" cy="97.4" r=".28" fill="#fff" stroke="#000" stroke-width=".2"/>
<circle cx="75.8" cy="132.7" r=".49" fill="#008000" stroke="#008000" stroke-width=".2"/>
<circle cx="75.8" cy="132.7" r=".28" fill="#fff" stroke="#000" stroke-width=".2"/>
<circle cx="117.1" cy="166.1" r=".49" fill="#008000" stroke="#008000" stroke-width=".2"/>
<circle cx="117.1" cy="166.1" r=".28" fill="#fff" stroke="#000" stroke-width=".2"/>
<circle cx="120.6" cy="155.8" r=".49" fill="#008000" stroke="#008000" stroke-width=".2"/>
<circle cx="120.6" cy="155.8" r=".28" fill="#fff" stroke="#000" stroke-width=".2"/>
<circle cx="56.5" cy="98.3" r=".49" fill="#008000" stroke="#008000" stroke-width=".2"/>
<circle cx="56.5" cy="98.3" r=".28" fill="#fff" stroke="#000" stroke-width=".2"/>
<circle cx="68.3" cy="99.3" r=".49" fill="#008000" stroke="#008000" stroke-width=".2"/>
<circle cx="68.3" cy="99.3" r=".28" fill="#fff" stroke="#000" stroke-width=".2"/>
<circle cx="78.9" cy="140" r=".49" fill="#008000" stroke="#008000" stroke-width=".2"/>
<circle cx="78.9" cy="140" r=".28" fill="#fff" stroke="#000" stroke-width=".2"/>
<circle cx="81.9" cy="137.9" r=".49" fill="#008000" stroke="#008000" stroke-width=".2"/>
<circle cx="81.9" cy="137.9" r=".28" fill="#fff" stroke="#000" stroke-width=".2"/>
<circle cx="108.9" cy="147.5" r=".49" fill="#008000" stroke="#008000" stroke-width=".2"/>
<circle cx="108.9" cy="147.5" r=".28" fill="#fff" stroke="#000" stroke-width=".2"/>
<circle cx="102.8" cy="156.5" r=".49" fill="#008000" stroke="#008000" stroke-width=".2"/>
<circle cx="102.8" cy="156.5" r=".28" fill="#fff" stroke="#000" stroke-width=".2"/>
<circle cx="56.8" cy="109.7" r=".49" fill="#008000" stroke="#008000" stroke-width=".2"/>
<circle cx="56.8" cy="109.7" r=".28" fill="#fff" stroke="#000" stroke-width=".2"/>
<circle cx="64.3" cy="109.2" r=".49" fill="#008000" stroke="#008000" stroke-width=".2"/>
<circle cx="64.3" cy="109.2" r=".28" fill="#fff" stroke="#000" stroke-width=".2"/>
<circle cx="76.5" cy="144.5" r=".49" fill="#008000" stroke="#008000" stroke-width=".2"/>
<circle cx="76.5" cy="144.5" r=".28" fill="#fff" stroke="#000" stroke-width=".2"/>
<circle cx="85" cy="138.7" r=".49" fill="#008000" stroke="#008000" stroke-width=".2"/>
<circle cx="85" cy="138.7" r=".28" fill="#fff" stroke="#000" stroke-width=".2"/>
<circle cx="59.1" cy="128.9" r=".49" fill="#008000" stroke="#008000" stroke-width=".2"/>
<circle cx="59.1" cy="128.9" r=".28" fill="#fff" stroke="#000" stroke-width=".2"/>
<circle cx="87.4" cy="118.3" r=".49" fill="#008000" stroke="#008000" stroke-width=".2"/>
<circle cx="87.4" cy="118.3" r=".28" fill="#fff" stroke="#000" stroke-width=".2"/>
<circle cx="58.4" cy="117.6" r=".49" fill="#008000" stroke="#008000" stroke-width=".2"/>
<circle cx="58.4" cy="117.6" r=".28" fill="#fff" stroke="#000" stroke-width=".2"/>
<circle cx="83.8" cy="112.5" r=".49" fill="#008000" stroke="#008000" stroke-width=".2"/>
<circle cx="83.8" cy="112.5" r=".28" fill="#fff" stroke="#000" stroke-width=".2"/>
<circle cx="82" cy="109.8" r=".49" fill="#008000" stroke="#008000" stroke-width=".2"/>
<circle cx="82" cy="109.8" r=".28" fill="#fff" stroke="#000" stroke-width=".2"/>
<circle cx="56.9" cy="115.6" r=".49" fill="#008000" stroke="#008000" stroke-width=".2"/>
<circle cx="56.9" cy="115.6" r=".28" fill="#fff" stroke="#000" stroke-width=".2"/>
<circle cx="132.9" cy="56" r=".49" fill="#008000" stroke="#008000" stroke-width=".2"/>
<circle cx="132.9" cy="56" r=".28" fill="#fff" stroke="#000" stroke-width=".2"/>
<circle cx="131.7" cy="46.4" r=".49" fill="#008000" stroke="#008000" stroke-width=".2"/>
<circle cx="131.7" cy="46.4" r=".28" fill="#fff" stroke="#000" stroke-width=".2"/>
<circle cx="61.3" cy="134.6" r=".49" fill="#008000" stroke="#008000" stroke-width=".2"/>
<circle cx="61.3" cy="134.6" r=".28" fill="#fff" stroke="#000" stroke-width=".2"/>
<circle cx="80" cy="126.9" r=".49" fill="#008000" stroke="#008000" stroke-width=".2"/>
<circle cx="80" cy="126.9" r=".28" fill="#fff" stroke="#000" stroke-width=".2"/>
<circle cx="112.5" cy="46.5" r=".49" fill="#008000" stroke="#008000" stroke-width=".2"/>
<circle cx="112.5" cy="46.5" r=".28" fill="#fff" stroke="#000" stroke-width=".2"/>
<circle cx="119" cy="60.2" r=".49" fill="#008000" stroke="#008000" stroke-width=".2"/>
<circle cx="119" cy="60.2" r=".28" fill="#fff" stroke="#000" stroke-width=".2"/>
<circle cx="135.6" cy="58.8" r=".49" fill="#008000" stroke="#008000" stroke-width=".2"/>
<circle cx="135.6" cy="58.8" r=".28" fill="#fff" stroke="#000" stroke-width=".2"/>
<circle cx="134.6" cy="47.5" r=".49" fill="#008000" stroke="#008000" stroke-width=".2"/>
<circle cx="134.6" cy="47.5" r=".28" fill="#fff" stroke="#000" stroke-width=".2"/>
<circle cx="64.3" cy="141.3" r=".49" fill="#008000" stroke="#008000" stroke-width=".2"/>
<circle cx="64.3" cy="141.3" r=".28" fill="#fff" stroke="#000" stroke-width=".2"/>
<circle cx="83" cy="130.2" r=".49" fill="#008000" stroke="#008000" stroke-width=".2"/>
<circle cx="83" cy="130.2" r=".28" fill="#fff" stroke="#000" stroke-width=".2"/>
<circle cx="111.9" cy="50.6" r=".49" fill="#008000" stroke="#008000" stroke-width=".2"/>
<circle cx="111.9" cy="50.6" r=".28" fill="#fff" stroke="#000" stroke-width=".2"/>
<circle cx="119.1" cy="63.3" r=".49" fill="#008000" stroke="#008000" stroke-width=".2"/>
<circle cx="119.1" cy="63.3" r=".28" fill="#fff" stroke="#000" stroke-width=".2"/>
<circle cx="142" cy="59.6" r=".49" fill="#008000" stroke="#008000" stroke-width=".2"/>
<circle cx="142" cy="59.6" r=".28" fill="#fff" stroke="#000" stroke-width=".2"/>
<circle cx="142.6" cy="49.4" r=".49" fill="#008000" stroke="#008000" stroke-width=".2"/>
<circle cx="142.6" cy="49.4" r=".28" fill="#fff" stroke="#000" stroke-width=".2"/>
<circle cx="97.3" cy="75.2" r=".49" fill="#008000" stroke="#008000" stroke-width=".2"/>
<circle cx="97.3" cy="75.2" r=".28" fill="#fff" stroke="#000" stroke-width=".2"/>
<circle cx="103.7" cy="79.4" r=".49" fill="#008000" stroke="#008000" stroke-width=".2"/>
<circle cx="103.7" cy="79.4" r=".28" fill="#fff" stroke="#000" stroke-width=".2"/>
<circle cx="65.9" cy="142.1" r=".49" fill="#008000" stroke="#008000" stroke-width=".2"/>
<circle cx="65.9" cy="142.1" r=".28" fill="#fff" stroke="#000" stroke-width=".2"/>
<circle cx="94.9" cy="126.2" r=".49" fill="#008000" stroke="#008000" stroke-width=".2"/>
<circle cx="94.9" cy="126.2" r=".28" fill="#fff" stroke="#000" stroke-width=".2"/>
<circle cx="103.2" cy="133.2" r=".49" fill="#008000" stroke="#008000" stroke-width=".2"/>
<circle cx="103.2" cy="133.2" r=".28" fill="#fff" stroke="#000" stroke-width=".2"/>
<circle cx="110.2" cy="127.3" r=".49" fill="#008000" stroke="#008000" stroke-width=".2"/>
<circle cx="110.2" cy="127.3" r=".28" fill="#fff" stroke="#000" stroke-width=".2"/>
<circle cx="71.4" cy="151.4" r=".49" fill="#008000" stroke="#008000" stroke-width=".2"/>
<circle cx="71.4" cy="151.4" r=".28" fill="#fff" stroke="#000" stroke-width=".2"/>
<circle cx="100.8" cy="130.1" r=".49" fill="#008000" stroke="#008000" stroke-width=".2"/>
<circle cx="100.8" cy="130.1" r=".28" fill="#fff" stroke="#000" stroke-width=".2"/>
<circle cx="111.9" cy="138.7" r=".49" fill="#008000" stroke="#008000" stroke-width=".2"/>
<circle cx="111.9" cy="138.7" r=".28" fill="#fff" stroke="#000" stroke-width=".2"/>
<circle cx="120.1" cy="129.3" r=".49" fill="#008000" stroke="#008000" stroke-width=".2"/>
<circle cx="120.1" cy="129.3" r=".28" fill="#fff" stroke="#000" stroke-width=".2"/>
<circle cx="66" cy="161" r=".49" fill="#008000" stroke="#008000" stroke-width=".2"/>
<circle cx="66" cy="161" r=".28" fill="#fff" stroke="#000" stroke-width=".2"/>
<circle cx="82.7" cy="176.9" r=".49" fill="#008000" stroke="#008000" stroke-width=".2"/>
<circle cx="82.7" cy="176.9" r=".28" fill="#fff" stroke="#000" stroke-width=".2"/>
<circle cx="109.6" cy="132.9" r=".49" fill="#008000" stroke="#008000" stroke-width=".2"/>
<circle cx="109.6" cy="132.9" r=".28" fill="#fff" stroke="#000" stroke-width=".2"/>
<circle cx="118" cy="124.5" r=".49" fill="#008000" stroke="#008000" stroke-width=".2"/>
<circle cx="118" cy="124.5" r=".28" fill="#fff" stroke="#000" stroke-width=".2"/>
<circle cx="77.9" cy="157.5" r=".49" fill="#008000" stroke="#008000" stroke-width=".2"/>
<circle cx="77.9" cy="157.5" r=".28" fill="#fff" stroke="#000" stroke-width=".2"/>
<circle cx="104.6" cy="94.2" r=".49" fill="#008000" stroke="#008000" stroke-width=".2"/>
<circle cx="104.6" cy="94.2" r=".28" fill="#fff" stroke="#000" stroke-width=".2"/>
<circle cx="114.4" cy="96.8" r=".49" fill="#008000" stroke="#008000" stroke-width=".2"/>
<circle cx="114.4" cy="96.8" r=".28" fill="#fff" stroke="#000" stroke-width=".2"/>
<circle cx="84.9" cy="167" r=".49" fill="#008000" stroke="#008000" stroke-width=".2"/>
<circle cx="84.9" cy="167" r=".28" fill="#fff" stroke="#000" stroke-width=".2"/>
<circle cx="120.2" cy="123.4" r=".49" fill="#008000" stroke="#008000" stroke-width=".2"/>
<circle cx="120.2" cy="123.4" r=".28" fill="#fff" stroke="#000" stroke-width=".2"/>
<circle cx="118.2" cy="84.8" r=".49" fill="#008000" stroke="#008000" stroke-width=".2"/>
<circle cx="118.2" cy="84.8" r=".28" fill="#fff" stroke="#000" stroke-width=".2"/>
<circle cx="108.2" cy="90.7" r=".49" fill="#008000" stroke="#008000" stroke-width=".2"/>
<circle cx="108.2" cy="90.7" r=".28" fill="#fff" stroke="#000" stroke-width=".2"/>
<circle cx="117.9" cy="94.7" r=".49" fill="#008000" stroke="#008000" stroke-width=".2"/>
<circle cx="117.9" cy="94.7" r=".28" fill="#fff" stroke="#000" stroke-width=".2"/>
<circle cx="89.8" cy="171" r=".49" fill="#008000" stroke="#008000" stroke-width=".2"/>
<circle cx="89.8" cy="171" r=".28" fill="#fff" stroke="#000" stroke-width=".2"/>
<circle cx="121.9" cy="126.4" r=".49" fill="#008000" stroke="#008000" stroke-width=".2"/>
<circle cx="121.9" cy="126.4" r=".28" fill="#fff" stroke="#000" stroke-width=".2"/>
<circle cx="131.7" cy="81.7" r=".49" fill="#008000" stroke="#008000" stroke-width=".2"/>
<circle cx="131.7" cy="81.7" r=".28" fill="#fff" stroke="#000" stroke-width=".2"/>
<circle cx="129.7" cy="75.6" r=".49" fill="#008000" stroke="#008000" stroke-width=".2"/>
<circle cx="129.7" cy="75.6" r=".28" fill="#fff" stroke="#000" stroke-width=".2"/>
<circle cx="114.2" cy="84.5" r=".49" fill="#008000" stroke="#008000" stroke-width=".2"/>
<circle cx="114.2" cy="84.5" r=".28" fill="#fff" stroke="#000" stroke-width=".2"/>
<circle cx="123.1" cy="91.3" r=".49" fill="#008000" stroke="#008000" stroke-width=".2"/>
<circle cx="123.1" cy="91.3" r=".28" fill="#fff" stroke="#000" stroke-width=".2"/>
<circle cx="101.6" cy="176" r=".49" fill="#008000" stroke="#008000" stroke-width=".2"/>
<circle cx="101.6" cy="176" r=".28" fill="#fff" stroke="#000" stroke-width=".2"/>
<circle cx="123.8" cy="125.3" r=".49" fill="#008000" stroke="#008000" stroke-width=".2"/>
<circle cx="123.8" cy="125.3" r=".28" fill="#fff" stroke="#000" stroke-width=".2"/>
<circle cx="112.9" cy="99.5" r=".49" fill="#008000" stroke="#008000" stroke-width=".2"/>
<circle cx="112.9" cy="99.5" r=".28" fill="#fff" stroke="#000" stroke-width=".2"/>
<circle cx="108.6" cy="98.8" r=".49" fill="#008000" stroke="#008000" stroke-width=".2"/>
<circle cx="108.6" cy="98.8" r=".28" fill="#fff" stroke="#000" stroke-width=".2"/>
<circle cx="94.8" cy="174.1" r=".49" fill="#008000" stroke="#008000" stroke-width=".2"/>
<circle cx="94.8" cy="174.1" r=".28" fill="#fff" stroke="#000" stroke-width=".2"/>
<circle cx="123.7" cy="123.6" r=".49" fill="#008000" stroke="#008000" stroke-width=".2"/>
<circle cx="123.7" cy="123.6" r=".28" fill="#fff" stroke="#000" stroke-width=".2"/>
<circle cx="131" cy="113.3" r=".49" fill="#008000" stroke="#008000" stroke-width=".2"/>
<circle cx="131" cy="113.3" r=".28" fill="#fff" stroke="#000" stroke-width=".2"/>
<circle cx="106.3" cy="180.1" r=".49" fill="#008000" stroke="#008000" stroke-width=".2"/>
<circle cx="106.3" cy="180.1" r=".28" fill="#fff" stroke="#000" stroke-width=".2"/>
<circle cx="124.1" cy="118.8" r=".49" fill="#008000" stroke="#008000" stroke-width=".2"/>
<circle cx="124.1" cy="118.8" r=".28" fill="#fff" stroke="#000" stroke-width=".2"/>
<circle cx="118.7" cy="110.7" r=".49" fill="#008000" stroke="#008000" stroke-width=".2"/>
<circle cx="118.7" cy="110.7" r=".28" fill="#fff" stroke="#000" stroke-width=".2"/>
<circle cx="128" cy="101.3" r=".49" fill="#008000" stroke="#008000" stroke-width=".2"/>
<circle cx="128" cy="101.3" r=".28" fill="#fff" stroke="#000" stroke-width=".2"/>
<circle cx="221.2" cy="140.2" r=".49" fill="#008000" stroke="#008000" stroke-width=".2"/>
<circle cx="221.2" cy="140.2" r=".28" fill="#fff" stroke="#000" stroke-width=".2"/>
<circle cx="211.5" cy="134.2" r=".49" fill="#008000" stroke="#008000" stroke-width=".2"/>
<circle cx="211.5" cy="134.2" r=".28" fill="#fff" stroke="#000" stroke-width=".2"/>
<circle cx="195.9" cy="129" r=".49" fill="#008000" stroke="#008000" stroke-width=".2"/>
<circle cx="195.9" cy="129" r=".28" fill="#fff" stroke="#000" stroke-width=".2"/>
<circle cx="202.7" cy="39.3" r=".49" fill="#008000" stroke="#008000" stroke-width=".2"/>
<circle cx="202.7" cy="39.3" r=".28" fill="#fff" stroke="#000" stroke-width=".2"/>
<circle cx="183.1" cy="58.8" r=".49" fill="#008000" stroke="#008000" stroke-width=".2"/>
<circle cx="183.1" cy="58.8" r=".28" fill="#fff" stroke="#000" stroke-width=".2"/>
<circle cx="180.4" cy="35.9" r=".49" fill="#008000" stroke="#008000" stroke-width=".2"/>
<circle cx="180.4" cy="35.9" r=".28" fill="#fff" stroke="#000" stroke-width=".2"/>
<circle cx="177.8" cy="39.7" r=".49" fill="#008000" stroke="#008000" stroke-width=".2"/>
<circle cx="177.8" cy="39.7" r=".28" fill="#fff" stroke="#000" stroke-width=".2"/>
<circle cx="191.6" cy="50.4" r=".49" fill="#008000" stroke="#008000" stroke-width=".2"/>
<circle cx="191.6" cy="50.4" r=".28" fill="#fff" stroke="#000" stroke-width=".2"/>
<circle cx="154.2" cy="169" r=".49" fill="#008000" stroke="#008000" stroke-width=".2"/>
<circle cx="154.2" cy="169" r=".28" fill="#fff" stroke="#000" stroke-width=".2"/>
<circle cx="198.4" cy="83.7" r=".49" fill="#008000" stroke="#008000" stroke-width=".2"/>
<circle cx="198.4" cy="83.7" r=".28" fill="#fff" stroke="#000" stroke-width=".2"/>
<circle cx="166.4" cy="152.8" r=".49" fill="#008000" stroke="#008000" stroke-width=".2"/>
<circle cx="166.4" cy="152.8" r=".28" fill="#fff" stroke="#000" stroke-width=".2"/>
<circle cx="168.3" cy="158.3" r=".49" fill="#008000" stroke="#008000" stroke-width=".2"/>
<circle cx="168.3" cy="158.3" r=".28" fill="#fff" stroke="#000" stroke-width=".2"/>
<circle cx="179.3" cy="55.4" r=".49" fill="#008000" stroke="#008000" stroke-width=".2"/>
<circle cx="179.3" cy="55.4" r=".28" fill="#fff" stroke="#000" stroke-width=".2"/>
<circle cx="190.8" cy="95.6" r=".49" fill="#008000" stroke="#008000" stroke-width=".2"/>
<circle cx="190.8" cy="95.6" r=".28" fill="#fff" stroke="#000" stroke-width=".2"/>
<circle cx="201" cy="95.9" r=".49" fill="#008000" stroke="#008000" stroke-width=".2"/>
<circle cx="201" cy="95.9" r=".28" fill="#fff" stroke="#000" stroke-width=".2"/>
<circle cx="214.7" cy="152.1" r=".49" fill="#008000" stroke="#008000" stroke-width=".2"/>
<circle cx="214.7" cy="152.1" r=".28" fill="#fff" stroke="#000" stroke-width=".2"/>
<circle cx="198.3" cy="143" r=".49" fill="#008000" stroke="#008000" stroke-width=".2"/>
<circle cx="198.3" cy="143" r=".28" fill="#fff" stroke="#000" stroke-width=".2"/>
<circle cx="210.5" cy="48.2" r=".49" fill="#008000" stroke="#008000" stroke-width=".2"/>
<circle cx="210.5" cy="48.2" r=".28" fill="#fff" stroke="#000" stroke-width=".2"/>
<circle cx="195.7" cy="59.5" r=".49" fill="#008000" stroke="#008000" stroke-width=".2"/>
<circle cx="195.7" cy="59.5" r=".28" fill="#fff" stroke="#000" stroke-width=".2"/>
<circle cx="215.7" cy="121.3" r=".49" fill="#008000" stroke="#008000" stroke-width=".2"/>
<circle cx="215.7" cy="121.3" r=".28" fill="#fff" stroke="#000" stroke-width=".2"/>
<circle cx="169.1" cy="30.2" r=".49" fill="#008000" stroke="#008000" stroke-width=".2"/>
<circle cx="169.1" cy="30.2" r=".28" fill="#fff" stroke="#000" stroke-width=".2"/>
<circle cx="166.3" cy="36.8" r=".49" fill="#008000" stroke="#008000" stroke-width=".2"/>
<circle cx="166.3" cy="36.8" r=".28" fill="#fff" stroke="#000" stroke-width=".2"/>
<circle cx="142" cy="173.2" r=".49" fill="#008000" stroke="#008000" stroke-width=".2"/>
<circle cx="142" cy="173.2" r=".28" fill="#fff" stroke="#000" stroke-width=".2"/>
<circle cx="177.5" cy="144.6" r=".49" fill="#008000" stroke="#008000" stroke-width=".2"/>
<circle cx="177.5" cy="144.6" r=".28" fill="#fff" stroke="#000" stroke-width=".2"/>
<circle cx="186" cy="157.2" r=".49" fill="#008000" stroke="#008000" stroke-width=".2"/>
<circle cx="186" cy="157.2" r=".28" fill="#fff" stroke="#000" stroke-width=".2"/>
<circle cx="160.6" cy="50.6" r=".49" fill="#008000" stroke="#008000" stroke-width=".2"/>
<circle cx="160.6" cy="50.6" r=".28" fill="#fff" stroke="#000" stroke-width=".2"/>
<circle cx="182.6" cy="118" r=".49" fill="#008000" stroke="#008000" stroke-width=".2"/>
<circle cx="182.6" cy="118" r=".28" fill="#fff" stroke="#000" stroke-width=".2"/>
<circle cx="161.2" cy="110.9" r=".49" fill="#008000" stroke="#008000" stroke-width=".2"/>
<circle cx="161.2" cy="110.9" r=".28" fill="#fff" stroke="#000" stroke-width=".2"/>
<circle cx="167.2" cy="84" r=".49" fill="#008000" stroke="#008000" stroke-width=".2"/>
<circle cx="167.2" cy="84" r=".28" fill="#fff" stroke="#000" stroke-width=".2"/>
<circle cx="160.1" cy="86.8" r=".49" fill="#008000" stroke="#008000" stroke-width=".2"/>
<circle cx="160.1" cy="86.8" r=".28" fill="#fff" stroke="#000" stroke-width=".2"/>
<circle cx="149.4" cy="77.7" r=".49" fill="#008000" stroke="#008000" stroke-width=".2"/>
<circle cx="149.4" cy="77.7" r=".28" fill="#fff" stroke="#000" stroke-width=".2"/>
<circle cx="210" cy="94.4" r=".49" fill="#008000" stroke="#008000" stroke-width=".2"/>
<circle cx="210" cy="94.4" r=".28" fill="#fff" stroke="#000" stroke-width=".2"/>
<circle cx="205.9" cy="93.9" r=".49" fill="#008000" stroke="#008000" stroke-width=".2"/>
<circle cx="205.9" cy="93.9" r=".28" fill="#fff" stroke="#000" stroke-width=".2"/>
<circle cx="190.7" cy="93.4" r=".49" fill="#008000" stroke="#008000" stroke-width=".2"/>
<circle cx="190.7" cy="93.4" r=".28" fill="#fff" stroke="#000" stroke-width=".2"/>
<circle cx="208.4" cy="119.6" r=".49" fill="#008000" stroke="#008000" stroke-width=".2"/>
<circle cx="208.4" cy="119.6" r=".28" fill="#fff" stroke="#000" stroke-width=".2"/>
<circle cx="206.7" cy="126.2" r=".49" fill="#008000" stroke="#008000" stroke-width=".2"/>
<circle cx="206.7" cy="126.2" r=".28" fill="#fff" stroke="#000" stroke-width=".2"/>
<circle cx="206.7" cy="162.7" r=".49" fill="#008000" stroke="#008000" stroke-width=".2"/>
<circle cx="206.7" cy="162.7" r=".28" fill="#fff" stroke="#000" stroke-width=".2"/>
<circle cx="193.9" cy="151.7" r=".49" fill="#008000" stroke="#008000" stroke-width=".2"/>
<circle cx="193.9" cy="151.7" r=".28" fill="#fff" stroke="#000" stroke-width=".2"/>
<circle cx="217.7" cy="59" r=".49" fill="#008000" stroke="#008000" stroke-width=".2"/>
<circle cx="217.7" cy="59" r=".28" fill="#fff" stroke="#000" stroke-width=".2"/>
<circle cx="203.6" cy="68.4" r=".49" fill="#008000" stroke="#008000" stroke-width=".2"/>
<circle cx="203.6" cy="68.4" r=".28" fill="#fff" stroke="#000" stroke-width=".2"/>
<circle cx="136.3" cy="176.7" r=".49" fill="#008000" stroke="#008000" stroke-width=".2"/>
<circle cx="136.3" cy="176.7" r=".28" fill="#fff" stroke="#000" stroke-width=".2"/>
<circle cx="217.6" cy="108.3" r=".49" fill="#008000" stroke="#008000" stroke-width=".2"/>
<circle cx="217.6" cy="108.3" r=".28" fill="#fff" stroke="#000" stroke-width=".2"/>
<circle cx="206.5" cy="106.3" r=".49" fill="#008000" stroke="#008000" stroke-width=".2"/>
<circle cx="206.5" cy="106.3" r=".28" fill="#fff" stroke="#000" stroke-width=".2"/>
<circle cx="212.1" cy="108" r=".49" fill="#008000" stroke="#008000" stroke-width=".2"/>
<circle cx="212.1" cy="108" r=".28" fill="#fff" stroke="#000" stroke-width=".2"/>
<circle cx="157.9" cy="26.4" r=".49" fill="#008000" stroke="#008000" stroke-width=".2"/>
<circle cx="157.9" cy="26.4" r=".28" fill="#fff" stroke="#000" stroke-width=".2"/>
<circle cx="157.8" cy="32.1" r=".49" fill="#008000" stroke="#008000" stroke-width=".2"/>
<circle cx="157.8" cy="32.1" r=".28" fill="#fff" stroke="#000" stroke-width=".2"/>
<circle cx="188.8" cy="130.2" r=".49" fill="#008000" stroke="#008000" stroke-width=".2"/>
<circle cx="188.8" cy="130.2" r=".28" fill="#fff" stroke="#000" stroke-width=".2"/>
<circle cx="179.9" cy="123.2" r=".49" fill="#008000" stroke="#008000" stroke-width=".2"/>
<circle cx="179.9" cy="123.2" r=".28" fill="#fff" stroke="#000" stroke-width=".2"/>
<circle cx="203.2" cy="137.8" r=".49" fill="#008000" stroke="#008000" stroke-width=".2"/>
<circle cx="203.2" cy="137.8" r=".28" fill="#fff" stroke="#000" stroke-width=".2"/>
<circle cx="143.9" cy="46.9" r=".49" fill="#008000" stroke="#008000" stroke-width=".2"/>
<circle cx="143.9" cy="46.9" r=".28" fill="#fff" stroke="#000" stroke-width=".2"/>
<circle cx="146.3" cy="30.1" r=".49" fill="#008000" stroke="#008000" stroke-width=".2"/>
<circle cx="146.3" cy="30.1" r=".28" fill="#fff" stroke="#000" stroke-width=".2"/>
<circle cx="151.8" cy="122.9" r=".49" fill="#008000" stroke="#008000" stroke-width=".2"/>
<circle cx="151.8" cy="122.9" r=".28" fill="#fff" stroke="#000" stroke-width=".2"/>
<circle cx="149.1" cy="118.4" r=".49" fill="#008000" stroke="#008000" stroke-width=".2"/>
<circle cx="149.1" cy="118.4" r=".28" fill="#fff" stroke="#000" stroke-width=".2"/>
<circle cx="158.5" cy="103.1" r=".49" fill="#008000" stroke="#008000" stroke-width=".2"/>
<circle cx="158.5" cy="103.1" r=".28" fill="#fff" stroke="#000" stroke-width=".2"/>
<circle cx="212" cy="103.1" r=".49" fill="#008000" stroke="#008000" stroke-width=".2"/>
<circle cx="212" cy="103.1" r=".28" fill="#fff" stroke="#000" stroke-width=".2"/>
<circle cx="158.8" cy="75.2" r=".49" fill="#008000" stroke="#008000" stroke-width=".2"/>
<circle cx="158.8" cy="75.2" r=".28" fill="#fff" stroke="#000" stroke-width=".2"/>
<circle cx="183.5" cy="44.9" r=".49" fill="#008000" stroke="#008000" stroke-width=".2"/>
<circle cx="183.5" cy="44.9" r=".28" fill="#fff" stroke="#000" stroke-width=".2"/>
<circle cx="188.9" cy="87" r=".49" fill="#008000" stroke="#008000" stroke-width=".2"/>
<circle cx="188.9" cy="87" r=".28" fill="#fff" stroke="#000" stroke-width=".2"/>
<circle cx="157.1" cy="97" r=".49" fill="#008000" stroke="#008000" stroke-width=".2"/>
<circle cx="157.1" cy="97" r=".28" fill="#fff" stroke="#000" stroke-width=".2"/>
<circle cx="198.4" cy="171" r=".49" fill="#008000" stroke="#008000" stroke-width=".2"/>
<circle cx="198.4" cy="171" r=".28" fill="#fff" stroke="#000" stroke-width=".2"/>
<circle cx="192.2" cy="164.1" r=".49" fill="#008000" stroke="#008000" stroke-width=".2"/>
<circle cx="192.2" cy="164.1" r=".28" fill="#fff" stroke="#000" stroke-width=".2"/>
<circle cx="222.3" cy="68.6" r=".49" fill="#008000" stroke="#008000" stroke-width=".2"/>
<circle cx="222.3" cy="68.6" r=".28" fill="#fff" stroke="#000" stroke-width=".2"/>
<circle cx="213.8" cy="72.1" r=".49" fill="#008000" stroke="#008000" stroke-width=".2"/>
<circle cx="213.8" cy="72.1" r=".28" fill="#fff" stroke="#000" stroke-width=".2"/>
<circle cx="156.8" cy="180.1" r=".49" fill="#008000" stroke="#008000" stroke-width=".2"/>
<circle cx="156.8" cy="180.1" r=".28" fill="#fff" stroke="#000" stroke-width=".2"/>
<circle cx="157.5" cy="183" r=".49" fill="#008000" stroke="#008000" stroke-width=".2"/>
<circle cx="157.5" cy="183" r=".28" fill="#fff" stroke="#000" stroke-width=".2"/>
<circle cx="217.5" cy="96.5" r=".49" fill="#008000" stroke="#008000" stroke-width=".2"/>
<circle cx="217.5" cy="96.5" r=".28" fill="#fff" stroke="#000" stroke-width=".2"/>
<circle cx="219.9" cy="97.8" r=".49" fill="#008000" stroke="#008000" stroke-width=".2"/>
<circle cx="219.9" cy="97.8" r=".28" fill="#fff" stroke="#000" stroke-width=".2"/>
<circle cx="150.3" cy="23.2" r=".49" fill="#008000" stroke="#008000" stroke-width=".2"/>
<circle cx="150.3" cy="23.2" r=".28" fill="#fff" stroke="#000" stroke-width=".2"/>
<circle cx="205.2" cy="116.5" r=".49" fill="#008000" stroke="#008000" stroke-width=".2"/>
<circle cx="205.2" cy="116.5" r=".28" fill="#fff" stroke="#000" stroke-width=".2"/>
<circle cx="219.3" cy="117.2" r=".49" fill="#008000" stroke="#008000" stroke-width=".2"/>
<circle cx="219.3" cy="117.2" r=".28" fill="#fff" stroke="#000" stroke-width=".2"/>
<circle cx="147.4" cy="37.7" r=".49" fill="#008000" stroke="#008000" stroke-width=".2"/>
<circle cx="147.4" cy="37.7" r=".28" fill="#fff" stroke="#000" stroke-width=".2"/>
<circle cx="193.4" cy="118.9" r=".49" fill="#008000" stroke="#008000" stroke-width=".2"/>
<circle cx="193.4" cy="118.9" r=".28" fill="#fff" stroke="#000" stroke-width=".2"/>
<circle cx="204.5" cy="119.2" r=".49" fill="#008000" stroke="#008000" stroke-width=".2"/>
<circle cx="204.5" cy="119.2" r=".28" fill="#fff" stroke="#000" stroke-width=".2"/>
<circle cx="175.3" cy="130.9" r=".49" fill="#008000" stroke="#008000" stroke-width=".2"/>
<circle cx="175.3" cy="130.9" r=".28" fill="#fff" stroke="#000" stroke-width=".2"/>
<circle cx="203.5" cy="152.5" r=".49" fill="#008000" stroke="#008000" stroke-width=".2"/>
<circle cx="203.5" cy="152.5" r=".28" fill="#fff" stroke="#000" stroke-width=".2"/>
<circle cx="135" cy="141.3" r=".49" fill="#008000" stroke="#008000" stroke-width=".2"/>
<circle cx="135" cy="141.3" r=".28" fill="#fff" stroke="#000" stroke-width=".2"/>
<circle cx="141.9" cy="69.2" r=".49" fill="#008000" stroke="#008000" stroke-width=".2"/>
<circle cx="141.9" cy="69.2" r=".28" fill="#fff" stroke="#000" stroke-width=".2"/>
<circle cx="169.3" cy="126.3" r=".49" fill="#008000" stroke="#008000" stroke-width=".2"/>
<circle cx="169.3" cy="126.3" r=".28" fill="#fff" stroke="#000" stroke-width=".2"/>
<circle cx="186.6" cy="82.6" r=".49" fill="#008000" stroke="#008000" stroke-width=".2"/>
<circle cx="186.6" cy="82.6" r=".28" fill="#fff" stroke="#000" stroke-width=".2"/>
<circle cx="146.5" cy="125.5" r=".49" fill="#008000" stroke="#008000" stroke-width=".2"/>
<circle cx="146.5" cy="125.5" r=".28" fill="#fff" stroke="#000" stroke-width=".2"/>
<circle cx="143.5" cy="114" r=".49" fill="#008000" stroke="#008000" stroke-width=".2"/>
<circle cx="143.5" cy="114" r=".28" fill="#fff" stroke="#000" stroke-width=".2"/>
<circle cx="171.4" cy="83" r=".49" fill="#008000" stroke="#008000" stroke-width=".2"/>
<circle cx="171.4" cy="83" r=".28" fill="#fff" stroke="#000" stroke-width=".2"/>
<circle cx="188.1" cy="178.8" r=".49" fill="#008000" stroke="#008000" stroke-width=".2"/>
<circle cx="188.1" cy="178.8" r=".28" fill="#fff" stroke="#000" stroke-width=".2"/>
<circle cx="183.4" cy="175.2" r=".49" fill="#008000" stroke="#008000" stroke-width=".2"/>
<circle cx="183.4" cy="175.2" r=".28" fill="#fff" stroke="#000" stroke-width=".2"/>
<circle cx="226.7" cy="82.4" r=".49" fill="#008000" stroke="#008000" stroke-width=".2"/>
<circle cx="226.7" cy="82.4" r=".28" fill="#fff" stroke="#000" stroke-width=".2"/>
<circle cx="221.4" cy="83.7" r=".49" fill="#008000" stroke="#008000" stroke-width=".2"/>
<circle cx="221.4" cy="83.7" r=".28" fill="#fff" stroke="#000" stroke-width=".2"/>
<circle cx="144.7" cy="13" r=".49" fill="#008000" stroke="#008000" stroke-width=".2"/>
<circle cx="144.7" cy="13" r=".28" fill="#fff" stroke="#000" stroke-width=".2"/>
<circle cx="144.3" cy="18.5" r=".49" fill="#008000" stroke="#008000" stroke-width=".2"/>
<circle cx="144.3" cy="18.5" r=".28" fill="#fff" stroke="#000" stroke-width=".2"/>
<circle cx="169.3" cy="176" r=".49" fill="#008000" stroke="#008000" stroke-width=".2"/>
<circle cx="169.3" cy="176" r=".28" fill="#fff" stroke="#000" stroke-width=".2"/>
<circle cx="171.5" cy="181.4" r=".49" fill="#008000" stroke="#008000" stroke-width=".2"/>
<circle cx="171.5" cy="181.4" r=".28" fill="#fff" stroke="#000" stroke-width=".2"/>
<circle cx="215.7" cy="85.2" r=".49" fill="#008000" stroke="#008000" stroke-width=".2"/>
<circle cx="215.7" cy="85.2" r=".28" fill="#fff" stroke="#000" stroke-width=".2"/>
<circle cx="201.4" cy="128.9" r=".49" fill="#008000" stroke="#008000" stroke-width=".2"/>
<circle cx="201.4" cy="128.9" r=".28" fill="#fff" stroke="#000" stroke-width=".2"/>
<circle cx="217.1" cy="135.4" r=".49" fill="#008000" stroke="#008000" stroke-width=".2"/>
<circle cx="217.1" cy="135.4" r=".28" fill="#fff" stroke="#000" stroke-width=".2"/>
<circle cx="160.7" cy="38.9" r=".49" fill="#008000" stroke="#008000" stroke-width=".2"/>
<circle cx="160.7" cy="38.9" r=".28" fill="#fff" stroke="#000" stroke-width=".2"/>
<circle cx="194.8" cy="112.5" r=".49" fill="#008000" stroke="#008000" stroke-width=".2"/>
<circle cx="194.8" cy="112.5" r=".28" fill="#fff" stroke="#000" stroke-width=".2"/>
<circle cx="222.5" cy="116.5" r=".49" fill="#008000" stroke="#008000" stroke-width=".2"/>
<circle cx="222.5" cy="116.5" r=".28" fill="#fff" stroke="#000" stroke-width=".2"/>
<circle cx="166.7" cy="139.1" r=".49" fill="#008000" stroke="#008000" stroke-width=".2"/>
<circle cx="166.7" cy="139.1" r=".28" fill="#fff" stroke="#000" stroke-width=".2"/>
<circle cx="147" cy="54" r=".49" fill="#008000" stroke="#008000" stroke-width=".2"/>
<circle cx="147" cy="54" r=".28" fill="#fff" stroke="#000" stroke-width=".2"/>
<circle cx="157.4" cy="20.3" r=".49" fill="#008000" stroke="#008000" stroke-width=".2"/>
<circle cx="157.4" cy="20.3" r=".28" fill="#fff" stroke="#000" stroke-width=".2"/>
<circle cx="149.9" cy="117.2" r=".49" fill="#008000" stroke="#008000" stroke-width=".2"/>
<circle cx="149.9" cy="117.2" r=".28" fill="#fff" stroke="#000" stroke-width=".2"/>
<circle cx="150.6" cy="103.1" r=".49" fill="#008000" stroke="#008000" stroke-width=".2"/>
<circle cx="150.6" cy="103.1" r=".28" fill="#fff" stroke="#000" stroke-width=".2"/>
<circle cx="156.7" cy="103.1" r=".49" fill="#008000" stroke="#008000" stroke-width=".2"/>
<circle cx="156.7" cy="103.1" r=".28" fill="#fff" stroke="#000" stroke-width=".2"/>
<circle cx="163.5" cy="134.9" r=".49" fill="#008000" stroke="#008000" stroke-width=".2"/>
<circle cx="163.5" cy="134.9" r=".28" fill="#fff" stroke="#000" stroke-width=".2"/>
<circle cx="137" cy="142.2" r=".49" fill="#008000" stroke="#008000" stroke-width=".2"/>
<circle cx="137" cy="142.2" r=".28" fill="#fff" stroke="#000" stroke-width=".2"/>
<circle cx="186.4" cy="81.1" r=".49" fill="#008000" stroke="#008000" stroke-width=".2"/>
<circle cx="186.4" cy="81.1" r=".28" fill="#fff" stroke="#000" stroke-width=".2"/>
<circle cx="137" cy="139.1" r=".49" fill="#008000" stroke="#008000" stroke-width=".2"/>
<circle cx="137" cy="139.1" r=".28" fill="#fff" stroke="#000" stroke-width=".2"/>
<circle cx="219.4" cy="76.6" r=".49" fill="#008000" stroke="#008000" stroke-width=".2"/>
<circle cx="219.4" cy="76.6" r=".28" fill="#fff" stroke="#000" stroke-width=".2"/>
<circle cx="165.6" cy="22.6" r=".49" fill="#008000" stroke="#008000" stroke-width=".2"/>
<circle cx="165.6" cy="22.6" r=".28" fill="#fff" stroke="#000" stroke-width=".2"/>
<circle cx="189.3" cy="171.3" r=".49" fill="#008000" stroke="#008000" stroke-width=".2"/>
<circle cx="189.3" cy="171.3" r=".28" fill="#fff" stroke="#000" stroke-width=".2"/>
<circle cx="178.8" cy="184.1" r=".49" fill="#008000" stroke="#008000" stroke-width=".2"/>
<circle cx="178.8" cy="184.1" r=".28" fill="#fff" stroke="#000" stroke-width=".2"/>
<circle cx="176.8" cy="180.3" r=".49" fill="#008000" stroke="#008000" stroke-width=".2"/>
<circle cx="176.8" cy="180.3" r=".28" fill="#fff" stroke="#000" stroke-width=".2"/>
<circle cx="228.7" cy="94" r=".49" fill="#008000" stroke="#008000" stroke-width=".2"/>
<circle cx="228.7" cy="94" r=".28" fill="#fff" stroke="#000" stroke-width=".2"/>
<circle cx="224.5" cy="94.5" r=".49" fill="#008000" stroke="#008000" stroke-width=".2"/>
<circle cx="224.5" cy="94.5" r=".28" fill="#fff" stroke="#000" stroke-width=".2"/>
<circle cx="156.4" cy="14.5" r=".49" fill="#008000" stroke="#008000" stroke-width=".2"/>
<circle cx="156.4" cy="14.5" r=".28" fill="#fff" stroke="#000" stroke-width=".2"/>
<circle cx="155.7" cy="18.6" r=".49" fill="#008000" stroke="#008000" stroke-width=".2"/>
<circle cx="155.7" cy="18.6" r=".28" fill="#fff" stroke="#000" stroke-width=".2"/>
<circle cx="179.7" cy="170.7" r=".49" fill="#008000" stroke="#008000" stroke-width=".2"/>
<circle cx="179.7" cy="170.7" r=".28" fill="#fff" stroke="#000" stroke-width=".2"/>
<circle cx="182.1" cy="177.6" r=".49" fill="#008000" stroke="#008000" stroke-width=".2"/>
<circle cx="182.1" cy="177.6" r=".28" fill="#fff" stroke="#000" stroke-width=".2"/>
<circle cx="211.8" cy="72.9" r=".49" fill="#008000" stroke="#008000" stroke-width=".2"/>
<circle cx="211.8" cy="72.9" r=".28" fill="#fff" stroke="#000" stroke-width=".2"/>
<circle cx="219.4" cy="72.6" r=".49" fill="#008000" stroke="#008000" stroke-width=".2"/>
<circle cx="219.4" cy="72.6" r=".28" fill="#fff" stroke="#000" stroke-width=".2"/>
<circle cx="194.5" cy="141.7" r=".49" fill="#008000" stroke="#008000" stroke-width=".2"/>
<circle cx="194.5" cy="141.7" r=".28" fill="#fff" stroke="#000" stroke-width=".2"/>
<circle cx="208.7" cy="153.4" r=".49" fill="#008000" stroke="#008000" stroke-width=".2"/>
<circle cx="208.7" cy="153.4" r=".28" fill="#fff" stroke="#000" stroke-width=".2"/>
<circle cx="171.1" cy="43.4" r=".49" fill="#008000" stroke="#008000" stroke-width=".2"/>
<circle cx="171.1" cy="43.4" r=".28" fill="#fff" stroke="#000" stroke-width=".2"/>
<circle cx="179.6" cy="27.2" r=".49" fill="#008000" stroke="#008000" stroke-width=".2"/>
<circle cx="179.6" cy="27.2" r=".28" fill="#fff" stroke="#000" stroke-width=".2"/>
<circle cx="195.6" cy="100.4" r=".49" fill="#008000" stroke="#008000" stroke-width=".2"/>
<circle cx="195.6" cy="100.4" r=".28" fill="#fff" stroke="#000" stroke-width=".2"/>
<circle cx="225" cy="103.1" r=".49" fill="#008000" stroke="#008000" stroke-width=".2"/>
<circle cx="225" cy="103.1" r=".28" fill="#fff" stroke="#000" stroke-width=".2"/>
<circle cx="157.8" cy="131.8" r=".49" fill="#008000" stroke="#008000" stroke-width=".2"/>
<circle cx="157.8" cy="131.8" r=".28" fill="#fff" stroke="#000" stroke-width=".2"/>
<circle cx="156.7" cy="145.5" r=".49" fill="#008000" stroke="#008000" stroke-width=".2"/>
<circle cx="156.7" cy="145.5" r=".28" fill="#fff" stroke="#000" stroke-width=".2"/>
<circle cx="159.2" cy="62.2" r=".49" fill="#008000" stroke="#008000" stroke-width=".2"/>
<circle cx="159.2" cy="62.2" r=".28" fill="#fff" stroke="#000" stroke-width=".2"/>
<circle cx="144.5" cy="92.3" r=".49" fill="#008000" stroke="#008000" stroke-width=".2"/>
<circle cx="144.5" cy="92.3" r=".28" fill="#fff" stroke="#000" stroke-width=".2"/>
<circle cx="185.9" cy="79.9" r=".49" fill="#008000" stroke="#008000" stroke-width=".2"/>
<circle cx="185.9" cy="79.9" r=".28" fill="#fff" stroke="#000" stroke-width=".2"/>
<circle cx="215.6" cy="64.1" r=".49" fill="#008000" stroke="#008000" stroke-width=".2"/>
<circle cx="215.6" cy="64.1" r=".28" fill="#fff" stroke="#000" stroke-width=".2"/>
<circle cx="165.7" cy="184.6" r=".49" fill="#008000" stroke="#008000" stroke-width=".2"/>
<circle cx="165.7" cy="184.6" r=".28" fill="#fff" stroke="#000" stroke-width=".2"/>
<circle cx="166.4" cy="189.1" r=".49" fill="#008000" stroke="#008000" stroke-width=".2"/>
<circle cx="166.4" cy="189.1" r=".28" fill="#fff" stroke="#000" stroke-width=".2"/>
<circle cx="168.2" cy="194.5" r=".49" fill="#008000" stroke="#008000" stroke-width=".2"/>
<circle cx="168.2" cy="194.5" r=".28" fill="#fff" stroke="#000" stroke-width=".2"/>
<circle cx="229.1" cy="103.1" r=".49" fill="#008000" stroke="#008000" stroke-width=".2"/>
<circle cx="229.1" cy="103.1" r=".28" fill="#fff" stroke="#000" stroke-width=".2"/>
<circle cx="234.9" cy="103.1" r=".49" fill="#008000" stroke="#008000" stroke-width=".2"/>
<circle cx="234.9" cy="103.1" r=".28" fill="#fff" stroke="#000" stroke-width=".2"/>
<circle cx="167.8" cy="17.5" r=".49" fill="#008000" stroke="#008000" stroke-width=".2"/>
<circle cx="167.8" cy="17.5" r=".28" fill="#fff" stroke="#000" stroke-width=".2"/>
<circle cx="169.6" cy="12.1" r=".49" fill="#008000" stroke="#008000" stroke-width=".2"/>
<circle cx="169.6" cy="12.1" r=".28" fill="#fff" stroke="#000" stroke-width=".2"/>
<circle cx="189.1" cy="163.9" r=".49" fill="#008000" stroke="#008000" stroke-width=".2"/>
<circle cx="189.1" cy="163.9" r=".28" fill="#fff" stroke="#000" stroke-width=".2"/>
<circle cx="199.6" cy="177.5" r=".49" fill="#008000" stroke="#008000" stroke-width=".2"/>
<circle cx="199.6" cy="177.5" r=".28" fill="#fff" stroke="#000" stroke-width=".2"/>
<circle cx="206.1" cy="61.5" r=".49" fill="#008000" stroke="#008000" stroke-width=".2"/>
<circle cx="206.1" cy="61.5" r=".28" fill="#fff" stroke="#000" stroke-width=".2"/>
<circle cx="220.5" cy="52.5" r=".49" fill="#008000" stroke="#008000" stroke-width=".2"/>
<circle cx="220.5" cy="52.5" r=".28" fill="#fff" stroke="#000" stroke-width=".2"/>
<circle cx="186.6" cy="151" r=".49" fill="#008000" stroke="#008000" stroke-width=".2"/>
<circle cx="186.6" cy="151" r=".28" fill="#fff" stroke="#000" stroke-width=".2"/>
<circle cx="181.8" cy="50.7" r=".49" fill="#008000" stroke="#008000" stroke-width=".2"/>
<circle cx="181.8" cy="50.7" r=".28" fill="#fff" stroke="#000" stroke-width=".2"/>
<circle cx="167.8" cy="67.9" r=".49" fill="#008000" stroke="#008000" stroke-width=".2"/>
<circle cx="167.8" cy="67.9" r=".28" fill="#fff" stroke="#000" stroke-width=".2"/>
<circle cx="199.5" cy="28.6" r=".49" fill="#008000" stroke="#008000" stroke-width=".2"/>
<circle cx="199.5" cy="28.6" r=".28" fill="#fff" stroke="#000" stroke-width=".2"/>
<circle cx="193.5" cy="87.3" r=".49" fill="#008000" stroke="#008000" stroke-width=".2"/>
<circle cx="193.5" cy="87.3" r=".28" fill="#fff" stroke="#000" stroke-width=".2"/>
<circle cx="231.6" cy="78.2" r=".49" fill="#008000" stroke="#008000" stroke-width=".2"/>
<circle cx="231.6" cy="78.2" r=".28" fill="#fff" stroke="#000" stroke-width=".2"/>
<circle cx="187.3" cy="90.1" r=".49" fill="#008000" stroke="#008000" stroke-width=".2"/>
<circle cx="187.3" cy="90.1" r=".28" fill="#fff" stroke="#000" stroke-width=".2"/>
<circle cx="136.3" cy="143.2" r=".49" fill="#008000" stroke="#008000" stroke-width=".2"/>
<circle cx="136.3" cy="143.2" r=".28" fill="#fff" stroke="#000" stroke-width=".2"/>
<circle cx="133.5" cy="199.1" r=".49" fill="#008000" stroke="#008000" stroke-width=".2"/>
<circle cx="133.5" cy="199.1" r=".28" fill="#fff" stroke="#000" stroke-width=".2"/>
<circle cx="164.5" cy="125.8" r=".49" fill="#008000" stroke="#008000" stroke-width=".2"/>
<circle cx="164.5" cy="125.8" r=".28" fill="#fff" stroke="#000" stroke-width=".2"/>
<circle cx="157.9" cy="120.3" r=".49" fill="#008000" stroke="#008000" stroke-width=".2"/>
<circle cx="157.9" cy="120.3" r=".28" fill="#fff" stroke="#000" stroke-width=".2"/>
<circle cx="133.9" cy="143.1" r=".49" fill="#008000" stroke="#008000" stroke-width=".2"/>
<circle cx="133.9" cy="143.1" r=".28" fill="#fff" stroke="#000" stroke-width=".2"/>
<circle cx="137.6" cy="128.5" r=".49" fill="#008000" stroke="#008000" stroke-width=".2"/>
<circle cx="137.6" cy="128.5" r=".28" fill="#fff" stroke="#000" stroke-width=".2"/>
<circle cx="154.7" cy="98.7" r=".49" fill="#008000" stroke="#008000" stroke-width=".2"/>
<circle cx="154.7" cy="98.7" r=".28" fill="#fff" stroke="#000" stroke-width=".2"/>
<circle cx="154.9" cy="191.9" r=".49" fill="#008000" stroke="#008000" stroke-width=".2"/>
<circle cx="154.9" cy="191.9" r=".28" fill="#fff" stroke="#000" stroke-width=".2"/>
<circle cx="155.6" cy="195.3" r=".49" fill="#008000" stroke="#008000" stroke-width=".2"/>
<circle cx="155.6" cy="195.3" r=".28" fill="#fff" stroke="#000" stroke-width=".2"/>
<circle cx="227.7" cy="118.9" r=".49" fill="#008000" stroke="#008000" stroke-width=".2"/>
<circle cx="227.7" cy="118.9" r=".28" fill="#fff" stroke="#000" stroke-width=".2"/>
<circle cx="231.1" cy="119.5" r=".49" fill="#008000" stroke="#008000" stroke-width=".2"/>
<circle cx="231.1" cy="119.5" r=".28" fill="#fff" stroke="#000" stroke-width=".2"/>
<circle cx="181.5" cy="23.5" r=".49" fill="#008000" stroke="#008000" stroke-width=".2"/>
<circle cx="181.5" cy="23.5" r=".28" fill="#fff" stroke="#000" stroke-width=".2"/>
<circle cx="183.1" cy="20.5" r=".49" fill="#008000" stroke="#008000" stroke-width=".2"/>
<circle cx="183.1" cy="20.5" r=".28" fill="#fff" stroke="#000" stroke-width=".2"/>
<circle cx="198.8" cy="154.6" r=".49" fill="#008000" stroke="#008000" stroke-width=".2"/>
<circle cx="198.8" cy="154.6" r=".28" fill="#fff" stroke="#000" stroke-width=".2"/>
<circle cx="199.1" cy="51.9" r=".49" fill="#008000" stroke="#008000" stroke-width=".2"/>
<circle cx="199.1" cy="51.9" r=".28" fill="#fff" stroke="#000" stroke-width=".2"/>
<circle cx="191.4" cy="60.3" r=".49" fill="#008000" stroke="#008000" stroke-width=".2"/>
<circle cx="191.4" cy="60.3" r=".28" fill="#fff" stroke="#000" stroke-width=".2"/>
<circle cx="211.3" cy="43.7" r=".49" fill="#008000" stroke="#008000" stroke-width=".2"/>
<circle cx="211.3" cy="43.7" r=".28" fill="#fff" stroke="#000" stroke-width=".2"/>
<circle cx="178.2" cy="158.2" r=".49" fill="#008000" stroke="#008000" stroke-width=".2"/>
<circle cx="178.2" cy="158.2" r=".28" fill="#fff" stroke="#000" stroke-width=".2"/>
<circle cx="173" cy="150.9" r=".49" fill="#008000" stroke="#008000" stroke-width=".2"/>
<circle cx="173" cy="150.9" r=".28" fill="#fff" stroke="#000" stroke-width=".2"/>
<circle cx="188" cy="74.7" r=".49" fill="#008000" stroke="#008000" stroke-width=".2"/>
<circle cx="188" cy="74.7" r=".28" fill="#fff" stroke="#000" stroke-width=".2"/>
<circle cx="176.9" cy="77.8" r=".49" fill="#008000" stroke="#008000" stroke-width=".2"/>
<circle cx="176.9" cy="77.8" r=".28" fill="#fff" stroke="#000" stroke-width=".2"/>
<circle cx="170.6" cy="116.2" r=".49" fill="#008000" stroke="#008000" stroke-width=".2"/>
<circle cx="170.6" cy="116.2" r=".28" fill="#fff" stroke="#000" stroke-width=".2"/>
<circle cx="226.2" cy="136.2" r=".49" fill="#008000" stroke="#008000" stroke-width=".2"/>
<circle cx="226.2" cy="136.2" r=".28" fill="#fff" stroke="#000" stroke-width=".2"/>
<circle cx="154.2" cy="85.2" r=".49" fill="#008000" stroke="#008000" stroke-width=".2"/>
<circle cx="154.2" cy="85.2" r=".28" fill="#fff" stroke="#000" stroke-width=".2"/>
<circle cx="156.6" cy="79.7" r=".49" fill="#008000" stroke="#008000" stroke-width=".2"/>
<circle cx="156.6" cy="79.7" r=".28" fill="#fff" stroke="#000" stroke-width=".2"/>
<circle cx="163.5" cy="86.9" r=".49" fill="#008000" stroke="#008000" stroke-width=".2"/>
<circle cx="163.5" cy="86.9" r=".28" fill="#fff" stroke="#000" stroke-width=".2"/>
<circle cx="220.1" cy="56.2" r=".49" fill="#008000" stroke="#008000" stroke-width=".2"/>
<circle cx="220.1" cy="56.2" r=".28" fill="#fff" stroke="#000" stroke-width=".2"/>
<circle cx="166.5" cy="69.5" r=".49" fill="#008000" stroke="#008000" stroke-width=".2"/>
<circle cx="166.5" cy="69.5" r=".28" fill="#fff" stroke="#000" stroke-width=".2"/>
<circle cx="211.1" cy="162.8" r=".49" fill="#008000" stroke="#008000" stroke-width=".2"/>
<circle cx="211.1" cy="162.8" r=".28" fill="#fff" stroke="#000" stroke-width=".2"/>
<circle cx="193.5" cy="179.2" r=".49" fill="#008000" stroke="#008000" stroke-width=".2"/>
<circle cx="193.5" cy="179.2" r=".28" fill="#fff" stroke="#000" stroke-width=".2"/>
<circle cx="183.5" cy="141.4" r=".49" fill="#008000" stroke="#008000" stroke-width=".2"/>
<circle cx="183.5" cy="141.4" r=".28" fill="#fff" stroke="#000" stroke-width=".2"/>
<circle cx="182.4" cy="88.9" r=".49" fill="#008000" stroke="#008000" stroke-width=".2"/>
<circle cx="182.4" cy="88.9" r=".28" fill="#fff" stroke="#000" stroke-width=".2"/>
<circle cx="161.1" cy="95.4" r=".49" fill="#008000" stroke="#008000" stroke-width=".2"/>
<circle cx="161.1" cy="95.4" r=".28" fill="#fff" stroke="#000" stroke-width=".2"/>
<circle cx="134.1" cy="192.8" r=".49" fill="#008000" stroke="#008000" stroke-width=".2"/>
<circle cx="134.1" cy="192.8" r=".28" fill="#fff" stroke="#000" stroke-width=".2"/>
<circle cx="134.1" cy="194.9" r=".49" fill="#008000" stroke="#008000" stroke-width=".2"/>
<circle cx="134.1" cy="194.9" r=".28" fill="#fff" stroke="#000" stroke-width=".2"/>
<circle cx="224.5" cy="136.5" r=".49" fill="#008000" stroke="#008000" stroke-width=".2"/>
<circle cx="224.5" cy="136.5" r=".28" fill="#fff" stroke="#000" stroke-width=".2"/>
<circle cx="205.2" cy="144.3" r=".49" fill="#008000" stroke="#008000" stroke-width=".2"/>
<circle cx="205.2" cy="144.3" r=".28" fill="#fff" stroke="#000" stroke-width=".2"/>
<circle cx="217.3" cy="151.7" r=".49" fill="#008000" stroke="#008000" stroke-width=".2"/>
<circle cx="217.3" cy="151.7" r=".28" fill="#fff" stroke="#000" stroke-width=".2"/>
<circle cx="189.8" cy="42.8" r=".49" fill="#008000" stroke="#008000" stroke-width=".2"/>
<circle cx="189.8" cy="42.8" r=".28" fill="#fff" stroke="#000" stroke-width=".2"/>
<circle cx="197.7" cy="35.9" r=".49" fill="#008000" stroke="#008000" stroke-width=".2"/>
<circle cx="197.7" cy="35.9" r=".28" fill="#fff" stroke="#000" stroke-width=".2"/>
<circle cx="199.5" cy="34" r=".49" fill="#008000" stroke="#008000" stroke-width=".2"/>
<circle cx="199.5" cy="34" r=".28" fill="#fff" stroke="#000" stroke-width=".2"/>
<circle cx="166.5" cy="165" r=".49" fill="#008000" stroke="#008000" stroke-width=".2"/>
<circle cx="166.5" cy="165" r=".28" fill="#fff" stroke="#000" stroke-width=".2"/>
<circle cx="176.7" cy="187.2" r=".49" fill="#008000" stroke="#008000" stroke-width=".2"/>
<circle cx="176.7" cy="187.2" r=".28" fill="#fff" stroke="#000" stroke-width=".2"/>
<circle cx="199.8" cy="75.8" r=".49" fill="#008000" stroke="#008000" stroke-width=".2"/>
<circle cx="199.8" cy="75.8" r=".28" fill="#fff" stroke="#000" stroke-width=".2"/>
<circle cx="223" cy="65.1" r=".49" fill="#008000" stroke="#008000" stroke-width=".2"/>
<circle cx="223" cy="65.1" r=".28" fill="#fff" stroke="#000" stroke-width=".2"/>
<circle cx="160.9" cy="155.9" r=".49" fill="#008000" stroke="#008000" stroke-width=".2"/>
<circle cx="160.9" cy="155.9" r=".28" fill="#fff" stroke="#000" stroke-width=".2"/>
<circle cx="176.8" cy="62.1" r=".49" fill="#008000" stroke="#008000" stroke-width=".2"/>
<circle cx="176.8" cy="62.1" r=".28" fill="#fff" stroke="#000" stroke-width=".2"/>
<circle cx="163.1" cy="105" r=".49" fill="#008000" stroke="#008000" stroke-width=".2"/>
<circle cx="163.1" cy="105" r=".28" fill="#fff" stroke="#000" stroke-width=".2"/>
<circle cx="161.1" cy="104.6" r=".49" fill="#008000" stroke="#008000" stroke-width=".2"/>
<circle cx="161.1" cy="104.6" r=".28" fill="#fff" stroke="#000" stroke-width=".2"/>
<circle cx="231.1" cy="110.8" r=".49" fill="#008000" stroke="#008000" stroke-width=".2"/>
<circle cx="231.1" cy="110.8" r=".28" fill="#fff" stroke="#000" stroke-width=".2"/>
<circle cx="169.9" cy="180.8" r=".49" fill="#008000" stroke="#008000" stroke-width=".2"/>
<circle cx="169.9" cy="180.8" r=".28" fill="#fff" stroke="#000" stroke-width=".2"/>
<circle cx="170.9" cy="187.8" r=".49" fill="#008000" stroke="#008000" stroke-width=".2"/>
<circle cx="170.9" cy="187.8" r=".28" fill="#fff" stroke="#000" stroke-width=".2"/>
<circle cx="175.6" cy="178.1" r=".49" fill="#008000" stroke="#008000" stroke-width=".2"/>
<circle cx="175.6" cy="178.1" r=".28" fill="#fff" stroke="#000" stroke-width=".2"/>
<circle cx="176.7" cy="183.9" r=".49" fill="#008000" stroke="#008000" stroke-width=".2"/>
<circle cx="176.7" cy="183.9" r=".28" fill="#fff" stroke="#000" stroke-width=".2"/>
<circle cx="177.3" cy="177.1" r=".49" fill="#008000" stroke="#008000" stroke-width=".2"/>
<circle cx="177.3" cy="177.1" r=".28" fill="#fff" stroke="#000" stroke-width=".2"/>
<circle cx="178.9" cy="180.5" r=".49" fill="#008000" stroke="#008000" stroke-width=".2"/>
<circle cx="178.9" cy="180.5" r=".28" fill="#fff" stroke="#000" stroke-width=".2"/>
<circle cx="186.9" cy="171.6" r=".49" fill="#008000" stroke="#008000" stroke-width=".2"/>
<circle cx="186.9" cy="171.6" r=".28" fill="#fff" stroke="#000" stroke-width=".2"/>
<circle cx="193.4" cy="181" r=".49" fill="#008000" stroke="#008000" stroke-width=".2"/>
<circle cx="193.4" cy="181" r=".28" fill="#fff" stroke="#000" stroke-width=".2"/>
<circle cx="210.5" cy="40.6" r=".49" fill="#008000" stroke="#008000" stroke-width=".2"/>
<circle cx="210.5" cy="40.6" r=".28" fill="#fff" stroke="#000" stroke-width=".2"/>
<circle cx="206.9" cy="43.8" r=".49" fill="#008000" stroke="#008000" stroke-width=".2"/>
<circle cx="206.9" cy="43.8" r=".28" fill="#fff" stroke="#000" stroke-width=".2"/>
<circle cx="188.6" cy="170.3" r=".49" fill="#008000" stroke="#008000" stroke-width=".2"/>
<circle cx="188.6" cy="170.3" r=".28" fill="#fff" stroke="#000" stroke-width=".2"/>
<circle cx="170" cy="145.1" r=".49" fill="#008000" stroke="#008000" stroke-width=".2"/>
<circle cx="170" cy="145.1" r=".28" fill="#fff" stroke="#000" stroke-width=".2"/>
<circle cx="224.7" cy="127.4" r=".49" fill="#008000" stroke="#008000" stroke-width=".2"/>
<circle cx="224.7" cy="127.4" r=".28" fill="#fff" stroke="#000" stroke-width=".2"/>
<circle cx="188.7" cy="118.9" r=".49" fill="#008000" stroke="#008000" stroke-width=".2"/>
<circle cx="188.7" cy="118.9" r=".28" fill="#fff" stroke="#000" stroke-width=".2"/>
<circle cx="198.4" cy="168.2" r=".49" fill="#008000" stroke="#008000" stroke-width=".2"/>
<circle cx="198.4" cy="168.2" r=".28" fill="#fff" stroke="#000" stroke-width=".2"/>
<circle cx="220.6" cy="136.2" r=".49" fill="#008000" stroke="#008000" stroke-width=".2"/>
<circle cx="220.6" cy="136.2" r=".28" fill="#fff" stroke="#000" stroke-width=".2"/>
<circle cx="186.6" cy="36.8" r=".49" fill="#008000" stroke="#008000" stroke-width=".2"/>
<circle cx="186.6" cy="36.8" r=".28" fill="#fff" stroke="#000" stroke-width=".2"/>
<circle cx="192.2" cy="28.9" r=".49" fill="#008000" stroke="#008000" stroke-width=".2"/>
<circle cx="192.2" cy="28.9" r=".28" fill="#fff" stroke="#000" stroke-width=".2"/>
<circle cx="198.6" cy="161.6" r=".49" fill="#008000" stroke="#008000" stroke-width=".2"/>
<circle cx="198.6" cy="161.6" r=".28" fill="#fff" stroke="#000" stroke-width=".2"/>
<circle cx="189.8" cy="151.4" r=".49" fill="#008000" stroke="#008000" stroke-width=".2"/>
<circle cx="189.8" cy="151.4" r=".28" fill="#fff" stroke="#000" stroke-width=".2"/>
<circle cx="150.5" cy="31.8" r=".49" fill="#008000" stroke="#008000" stroke-width=".2"/>
<circle cx="150.5" cy="31.8" r=".28" fill="#fff" stroke="#000" stroke-width=".2"/>
<circle cx="153.6" cy="13" r=".49" fill="#008000" stroke="#008000" stroke-width=".2"/>
<circle cx="153.6" cy="13" r=".28" fill="#fff" stroke="#000" stroke-width=".2"/>
<circle cx="167.5" cy="30.6" r=".49" fill="#008000" stroke="#008000" stroke-width=".2"/>
<circle cx="167.5" cy="30.6" r=".28" fill="#fff" stroke="#000" stroke-width=".2"/>
<circle cx="170.5" cy="19.6" r=".49" fill="#008000" stroke="#008000" stroke-width=".2"/>
<circle cx="170.5" cy="19.6" r=".28" fill="#fff" stroke="#000" stroke-width=".2"/>
<circle cx="202.8" cy="156.7" r=".49" fill="#008000" stroke="#008000" stroke-width=".2"/>
<circle cx="202.8" cy="156.7" r=".28" fill="#fff" stroke="#000" stroke-width=".2"/>
<circle cx="167.3" cy="126.9" r=".49" fill="#008000" stroke="#008000" stroke-width=".2"/>
<circle cx="167.3" cy="126.9" r=".28" fill="#fff" stroke="#000" stroke-width=".2"/>
<circle cx="159.9" cy="29.2" r=".49" fill="#008000" stroke="#008000" stroke-width=".2"/>
<circle cx="159.9" cy="29.2" r=".28" fill="#fff" stroke="#000" stroke-width=".2"/>
<circle cx="148.4" cy="69" r=".49" fill="#008000" stroke="#008000" stroke-width=".2"/>
<circle cx="148.4" cy="69" r=".28" fill="#fff" stroke="#000" stroke-width=".2"/>
<circle cx="156.3" cy="29.2" r=".49" fill="#008000" stroke="#008000" stroke-width=".2"/>
<circle cx="156.3" cy="29.2" r=".28" fill="#fff" stroke="#000" stroke-width=".2"/>
<circle cx="158.8" cy="18.2" r=".49" fill="#008000" stroke="#008000" stroke-width=".2"/>
<circle cx="158.8" cy="18.2" r=".28" fill="#fff" stroke="#000" stroke-width=".2"/>
<circle cx="210.4" cy="146.2" r=".49" fill="#008000" stroke="#008000" stroke-width=".2"/>
<circle cx="210.4" cy="146.2" r=".28" fill="#fff" stroke="#000" stroke-width=".2"/>
<circle cx="189.3" cy="133.5" r=".49" fill="#008000" stroke="#008000" stroke-width=".2"/>
<circle cx="189.3" cy="133.5" r=".28" fill="#fff" stroke="#000" stroke-width=".2"/>
<circle cx="153.7" cy="45" r=".49" fill="#008000" stroke="#008000" stroke-width=".2"/>
<circle cx="153.7" cy="45" r=".28" fill="#fff" stroke="#000" stroke-width=".2"/>
<circle cx="212.8" cy="142.2" r=".49" fill="#008000" stroke="#008000" stroke-width=".2"/>
<circle cx="212.8" cy="142.2" r=".28" fill="#fff" stroke="#000" stroke-width=".2"/>
<circle cx="216.3" cy="134.1" r=".49" fill="#008000" stroke="#008000" stroke-width=".2"/>
<circle cx="216.3" cy="134.1" r=".28" fill="#fff" stroke="#000" stroke-width=".2"/>
<circle cx="210.1" cy="131.6" r=".49" fill="#008000" stroke="#008000" stroke-width=".2"/>
<circle cx="210.1" cy="131.6" r=".28" fill="#fff" stroke="#000" stroke-width=".2"/>
<circle cx="218" cy="130.1" r=".49" fill="#008000" stroke="#008000" stroke-width=".2"/>
<circle cx="218" cy="130.1" r=".28" fill="#fff" stroke="#000" stroke-width=".2"/>
<circle cx="211.1" cy="129.2" r=".49" fill="#008000" stroke="#008000" stroke-width=".2"/>
<circle cx="211.1" cy="129.2" r=".28" fill="#fff" stroke="#000" stroke-width=".2"/>
<circle cx="143.1" cy="171.7" r=".49" fill="#008000" stroke="#008000" stroke-width=".2"/>
<circle cx="143.1" cy="171.7" r=".28" fill="#fff" stroke="#000" stroke-width=".2"/>
<circle cx="144.1" cy="182.7" r=".49" fill="#008000" stroke="#008000" stroke-width=".2"/>
<circle cx="144.1" cy="182.7" r=".28" fill="#fff" stroke="#000" stroke-width=".2"/>
<circle cx="218.5" cy="128.7" r=".49" fill="#008000" stroke="#008000" stroke-width=".2"/>
<circle cx="218.5" cy="128.7" r=".28" fill="#fff" stroke="#000" stroke-width=".2"/>
<circle cx="210.2" cy="124.4" r=".49" fill="#008000" stroke="#008000" stroke-width=".2"/>
<circle cx="210.2" cy="124.4" r=".28" fill="#fff" stroke="#000" stroke-width=".2"/>
<circle cx="154.2" cy="175.9" r=".49" fill="#008000" stroke="#008000" stroke-width=".2"/>
<circle cx="154.2" cy="175.9" r=".28" fill="#fff" stroke="#000" stroke-width=".2"/>
<circle cx="155.2" cy="181.4" r=".49" fill="#008000" stroke="#008000" stroke-width=".2"/>
<circle cx="155.2" cy="181.4" r=".28" fill="#fff" stroke="#000" stroke-width=".2"/>
<circle cx="151.1" cy="166" r=".49" fill="#008000" stroke="#008000" stroke-width=".2"/>
<circle cx="151.1" cy="166" r=".28" fill="#fff" stroke="#000" stroke-width=".2"/>
<circle cx="153.9" cy="179.6" r=".49" fill="#008000" stroke="#008000" stroke-width=".2"/>
<circle cx="153.9" cy="179.6" r=".28" fill="#fff" stroke="#000" stroke-width=".2"/>
<circle cx="220.4" cy="121.9" r=".49" fill="#008000" stroke="#008000" stroke-width=".2"/>
<circle cx="220.4" cy="121.9" r=".28" fill="#fff" stroke="#000" stroke-width=".2"/>
<circle cx="197.3" cy="116.3" r=".49" fill="#008000" stroke="#008000" stroke-width=".2"/>
<circle cx="197.3" cy="116.3" r=".28" fill="#fff" stroke="#000" stroke-width=".2"/>
<circle cx="150.3" cy="161.9" r=".49" fill="#008000" stroke="#008000" stroke-width=".2"/>
<circle cx="150.3" cy="161.9" r=".28" fill="#fff" stroke="#000" stroke-width=".2"/>
<circle cx="145" cy="167.3" r=".49" fill="#008000" stroke="#008000" stroke-width=".2"/>
<circle cx="145" cy="167.3" r=".28" fill="#fff" stroke="#000" stroke-width=".2"/>
<circle cx="145.3" cy="178.7" r=".49" fill="#008000" stroke="#008000" stroke-width=".2"/>
<circle cx="145.3" cy="178.7" r=".28" fill="#fff" stroke="#000" stroke-width=".2"/>
<circle cx="221.3" cy="115.4" r=".49" fill="#008000" stroke="#008000" stroke-width=".2"/>
<circle cx="221.3" cy="115.4" r=".28" fill="#fff" stroke="#000" stroke-width=".2"/>
<circle cx="199.6" cy="111.1" r=".49" fill="#008000" stroke="#008000" stroke-width=".2"/>
<circle cx="199.6" cy="111.1" r=".28" fill="#fff" stroke="#000" stroke-width=".2"/>
<circle cx="138.8" cy="164.4" r=".49" fill="#008000" stroke="#008000" stroke-width=".2"/>
<circle cx="138.8" cy="164.4" r=".28" fill="#fff" stroke="#000" stroke-width=".2"/>
<circle cx="222.4" cy="104.1" r=".49" fill="#008000" stroke="#008000" stroke-width=".2"/>
<circle cx="222.4" cy="104.1" r=".28" fill="#fff" stroke="#000" stroke-width=".2"/>
<circle cx="207.5" cy="105.2" r=".49" fill="#008000" stroke="#008000" stroke-width=".2"/>
<circle cx="207.5" cy="105.2" r=".28" fill="#fff" stroke="#000" stroke-width=".2"/>
<circle cx="222.3" cy="97.6" r=".49" fill="#008000" stroke="#008000" stroke-width=".2"/>
<circle cx="222.3" cy="97.6" r=".28" fill="#fff" stroke="#000" stroke-width=".2"/>
<circle cx="205.4" cy="99.7" r=".49" fill="#008000" stroke="#008000" stroke-width=".2"/>
<circle cx="205.4" cy="99.7" r=".28" fill="#fff" stroke="#000" stroke-width=".2"/>
<circle cx="222.3" cy="95.8" r=".49" fill="#008000" stroke="#008000" stroke-width=".2"/>
<circle cx="222.3" cy="95.8" r=".28" fill="#fff" stroke="#000" stroke-width=".2"/>
<circle cx="202.3" cy="96.9" r=".49" fill="#008000" stroke="#008000" stroke-width=".2"/>
<circle cx="202.3" cy="96.9" r=".28" fill="#fff" stroke="#000" stroke-width=".2"/>
<circle cx="158.7" cy="37.3" r=".49" fill="#008000" stroke="#008000" stroke-width=".2"/>
<circle cx="158.7" cy="37.3" r=".28" fill="#fff" stroke="#000" stroke-width=".2"/>
<circle cx="155.7" cy="47.8" r=".49" fill="#008000" stroke="#008000" stroke-width=".2"/>
<circle cx="155.7" cy="47.8" r=".28" fill="#fff" stroke="#000" stroke-width=".2"/>
<circle cx="219.3" cy="89.1" r=".49" fill="#008000" stroke="#008000" stroke-width=".2"/>
<circle cx="219.3" cy="89.1" r=".28" fill="#fff" stroke="#000" stroke-width=".2"/>
<circle cx="205.3" cy="90" r=".49" fill="#008000" stroke="#008000" stroke-width=".2"/>
<circle cx="205.3" cy="90" r=".28" fill="#fff" stroke="#000" stroke-width=".2"/>
<circle cx="201.2" cy="76.1" r=".49" fill="#008000" stroke="#008000" stroke-width=".2"/>
<circle cx="201.2" cy="76.1" r=".28" fill="#fff" stroke="#000" stroke-width=".2"/>
<circle cx="156.9" cy="50.3" r=".49" fill="#008000" stroke="#008000" stroke-width=".2"/>
<circle cx="156.9" cy="50.3" r=".28" fill="#fff" stroke="#000" stroke-width=".2"/>
<circle cx="160" cy="40.9" r=".49" fill="#008000" stroke="#008000" stroke-width=".2"/>
<circle cx="160" cy="40.9" r=".28" fill="#fff" stroke="#000" stroke-width=".2"/>
<circle cx="218.5" cy="77.7" r=".49" fill="#008000" stroke="#008000" stroke-width=".2"/>
<circle cx="218.5" cy="77.7" r=".28" fill="#fff" stroke="#000" stroke-width=".2"/>
<circle cx="197.4" cy="85.6" r=".49" fill="#008000" stroke="#008000" stroke-width=".2"/>
<circle cx="197.4" cy="85.6" r=".28" fill="#fff" stroke="#000" stroke-width=".2"/>
<circle cx="195.7" cy="68.1" r=".49" fill="#008000" stroke="#008000" stroke-width=".2"/>
<circle cx="195.7" cy="68.1" r=".28" fill="#fff" stroke="#000" stroke-width=".2"/>
<circle cx="191.3" cy="70.8" r=".49" fill="#008000" stroke="#008000" stroke-width=".2"/>
<circle cx="191.3" cy="70.8" r=".28" fill="#fff" stroke="#000" stroke-width=".2"/>
<circle cx="170.9" cy="47.6" r=".49" fill="#008000" stroke="#008000" stroke-width=".2"/>
<circle cx="170.9" cy="47.6" r=".28" fill="#fff" stroke="#000" stroke-width=".2"/>
<circle cx="165.7" cy="56.6" r=".49" fill="#008000" stroke="#008000" stroke-width=".2"/>
<circle cx="165.7" cy="56.6" r=".28" fill="#fff" stroke="#000" stroke-width=".2"/>
<circle cx="218.1" cy="76.2" r=".49" fill="#008000" stroke="#008000" stroke-width=".2"/>
<circle cx="218.1" cy="76.2" r=".28" fill="#fff" stroke="#000" stroke-width=".2"/>
<circle cx="200.4" cy="82.2" r=".49" fill="#008000" stroke="#008000" stroke-width=".2"/>
<circle cx="200.4" cy="82.2" r=".28" fill="#fff" stroke="#000" stroke-width=".2"/>
<circle cx="196.8" cy="76" r=".49" fill="#008000" stroke="#008000" stroke-width=".2"/>
<circle cx="196.8" cy="76" r=".28" fill="#fff" stroke="#000" stroke-width=".2"/>
<circle cx="215.7" cy="70.1" r=".49" fill="#008000" stroke="#008000" stroke-width=".2"/>
<circle cx="215.7" cy="70.1" r=".28" fill="#fff" stroke="#000" stroke-width=".2"/>
<circle cx="191.5" cy="81.3" r=".49" fill="#008000" stroke="#008000" stroke-width=".2"/>
<circle cx="191.5" cy="81.3" r=".28" fill="#fff" stroke="#000" stroke-width=".2"/>
<circle cx="213.8" cy="66.1" r=".49" fill="#008000" stroke="#008000" stroke-width=".2"/>
<circle cx="213.8" cy="66.1" r=".28" fill="#fff" stroke="#000" stroke-width=".2"/>
<circle cx="191.6" cy="77.3" r=".49" fill="#008000" stroke="#008000" stroke-width=".2"/>
<circle cx="191.6" cy="77.3" r=".28" fill="#fff" stroke="#000" stroke-width=".2"/>
<circle cx="193.9" cy="82.5" r=".49" fill="#008000" stroke="#008000" stroke-width=".2"/>
<circle cx="193.9" cy="82.5" r=".28" fill="#fff" stroke="#000" stroke-width=".2"/>
<circle cx="191.5" cy="83.4" r=".49" fill="#008000" stroke="#008000" stroke-width=".2"/>
<circle cx="191.5" cy="83.4" r=".28" fill="#fff" stroke="#000" stroke-width=".2"/>
<circle cx="209.5" cy="58.3" r=".49" fill="#008000" stroke="#008000" stroke-width=".2"/>
<circle cx="209.5" cy="58.3" r=".28" fill="#fff" stroke="#000" stroke-width=".2"/>
<circle cx="182.4" cy="74.3" r=".49" fill="#008000" stroke="#008000" stroke-width=".2"/>
<circle cx="182.4" cy="74.3" r=".28" fill="#fff" stroke="#000" stroke-width=".2"/>
<circle cx="145" cy="149.5" r=".49" fill="#008000" stroke="#008000" stroke-width=".2"/>
<circle cx="145" cy="149.5" r=".28" fill="#fff" stroke="#000" stroke-width=".2"/>
<circle cx="146.7" cy="160.3" r=".49" fill="#008000" stroke="#008000" stroke-width=".2"/>
<circle cx="146.7" cy="160.3" r=".28" fill="#fff" stroke="#000" stroke-width=".2"/>
<circle cx="206.7" cy="54.2" r=".49" fill="#008000" stroke="#008000" stroke-width=".2"/>
<circle cx="206.7" cy="54.2" r=".28" fill="#fff" stroke="#000" stroke-width=".2"/>
<circle cx="182.2" cy="73.1" r=".49" fill="#008000" stroke="#008000" stroke-width=".2"/>
<circle cx="182.2" cy="73.1" r=".28" fill="#fff" stroke="#000" stroke-width=".2"/>
<circle cx="181.2" cy="131.6" r=".49" fill="#008000" stroke="#008000" stroke-width=".2"/>
<circle cx="181.2" cy="131.6" r=".28" fill="#fff" stroke="#000" stroke-width=".2"/>
<circle cx="177.8" cy="129.2" r=".49" fill="#008000" stroke="#008000" stroke-width=".2"/>
<circle cx="177.8" cy="129.2" r=".28" fill="#fff" stroke="#000" stroke-width=".2"/>
<circle cx="147.3" cy="158.2" r=".49" fill="#008000" stroke="#008000" stroke-width=".2"/>
<circle cx="147.3" cy="158.2" r=".28" fill="#fff" stroke="#000" stroke-width=".2"/>
<circle cx="145.9" cy="147.2" r=".49" fill="#008000" stroke="#008000" stroke-width=".2"/>
<circle cx="145.9" cy="147.2" r=".28" fill="#fff" stroke="#000" stroke-width=".2"/>
<circle cx="201.7" cy="48" r=".49" fill="#008000" stroke="#008000" stroke-width=".2"/>
<circle cx="201.7" cy="48" r=".28" fill="#fff" stroke="#000" stroke-width=".2"/>
<circle cx="176.1" cy="70.3" r=".49" fill="#008000" stroke="#008000" stroke-width=".2"/>
<circle cx="176.1" cy="70.3" r=".28" fill="#fff" stroke="#000" stroke-width=".2"/>
<circle cx="166.4" cy="144.4" r=".49" fill="#008000" stroke="#008000" stroke-width=".2"/>
<circle cx="166.4" cy="144.4" r=".28" fill="#fff" stroke="#000" stroke-width=".2"/>
<circle cx="163.1" cy="139.3" r=".49" fill="#008000" stroke="#008000" stroke-width=".2"/>
<circle cx="163.1" cy="139.3" r=".28" fill="#fff" stroke="#000" stroke-width=".2"/>
<circle cx="141.8" cy="145.3" r=".49" fill="#008000" stroke="#008000" stroke-width=".2"/>
<circle cx="141.8" cy="145.3" r=".28" fill="#fff" stroke="#000" stroke-width=".2"/>
<circle cx="138.9" cy="155.3" r=".49" fill="#008000" stroke="#008000" stroke-width=".2"/>
<circle cx="138.9" cy="155.3" r=".28" fill="#fff" stroke="#000" stroke-width=".2"/>
<circle cx="196.8" cy="43.3" r=".49" fill="#008000" stroke="#008000" stroke-width=".2"/>
<circle cx="196.8" cy="43.3" r=".28" fill="#fff" stroke="#000" stroke-width=".2"/>
<circle cx="172.2" cy="68.3" r=".49" fill="#008000" stroke="#008000" stroke-width=".2"/>
<circle cx="172.2" cy="68.3" r=".28" fill="#fff" stroke="#000" stroke-width=".2"/>
<circle cx="170.6" cy="139.3" r=".49" fill="#008000" stroke="#008000" stroke-width=".2"/>
<circle cx="170.6" cy="139.3" r=".28" fill="#fff" stroke="#000" stroke-width=".2"/>
<circle cx="166.9" cy="134.9" r=".49" fill="#008000" stroke="#008000" stroke-width=".2"/>
<circle cx="166.9" cy="134.9" r=".28" fill="#fff" stroke="#000" stroke-width=".2"/>
<circle cx="188.6" cy="36" r=".49" fill="#008000" stroke="#008000" stroke-width=".2"/>
<circle cx="188.6" cy="36" r=".28" fill="#fff" stroke="#000" stroke-width=".2"/>
<circle cx="166.1" cy="65.3" r=".49" fill="#008000" stroke="#008000" stroke-width=".2"/>
<circle cx="166.1" cy="65.3" r=".28" fill="#fff" stroke="#000" stroke-width=".2"/>
<circle cx="157.5" cy="73.3" r=".49" fill="#008000" stroke="#008000" stroke-width=".2"/>
<circle cx="157.5" cy="73.3" r=".28" fill="#fff" stroke="#000" stroke-width=".2"/>
<circle cx="164.4" cy="62.1" r=".49" fill="#008000" stroke="#008000" stroke-width=".2"/>
<circle cx="164.4" cy="62.1" r=".28" fill="#fff" stroke="#000" stroke-width=".2"/>
<circle cx="163.8" cy="66.1" r=".49" fill="#008000" stroke="#008000" stroke-width=".2"/>
<circle cx="163.8" cy="66.1" r=".28" fill="#fff" stroke="#000" stroke-width=".2"/>
<circle cx="157.4" cy="75.6" r=".49" fill="#008000" stroke="#008000" stroke-width=".2"/>
<circle cx="157.4" cy="75.6" r=".28" fill="#fff" stroke="#000" stroke-width=".2"/>
<circle cx="183.1" cy="32.1" r=".49" fill="#008000" stroke="#008000" stroke-width=".2"/>
<circle cx="183.1" cy="32.1" r=".28" fill="#fff" stroke="#000" stroke-width=".2"/>
<circle cx="154.5" cy="76.1" r=".49" fill="#008000" stroke="#008000" stroke-width=".2"/>
<circle cx="154.5" cy="76.1" r=".28" fill="#fff" stroke="#000" stroke-width=".2"/>
<circle cx="159.7" cy="67.1" r=".49" fill="#008000" stroke="#008000" stroke-width=".2"/>
<circle cx="159.7" cy="67.1" r=".28" fill="#fff" stroke="#000" stroke-width=".2"/>
<circle cx="181.9" cy="31.4" r=".49" fill="#008000" stroke="#008000" stroke-width=".2"/>
<circle cx="181.9" cy="31.4" r=".28" fill="#fff" stroke="#000" stroke-width=".2"/>
<circle cx="164" cy="128" r=".49" fill="#008000" stroke="#008000" stroke-width=".2"/>
<circle cx="164" cy="128" r=".28" fill="#fff" stroke="#000" stroke-width=".2"/>
<circle cx="155.6" cy="119.6" r=".49" fill="#008000" stroke="#008000" stroke-width=".2"/>
<circle cx="155.6" cy="119.6" r=".28" fill="#fff" stroke="#000" stroke-width=".2"/>
<circle cx="175.7" cy="28.1" r=".49" fill="#008000" stroke="#008000" stroke-width=".2"/>
<circle cx="175.7" cy="28.1" r=".28" fill="#fff" stroke="#000" stroke-width=".2"/>
<circle cx="144.2" cy="82.4" r=".49" fill="#008000" stroke="#008000" stroke-width=".2"/>
<circle cx="144.2" cy="82.4" r=".28" fill="#fff" stroke="#000" stroke-width=".2"/>
<circle cx="160.4" cy="115.1" r=".49" fill="#008000" stroke="#008000" stroke-width=".2"/>
<circle cx="160.4" cy="115.1" r=".28" fill="#fff" stroke="#000" stroke-width=".2"/>
<circle cx="153.4" cy="110.8" r=".49" fill="#008000" stroke="#008000" stroke-width=".2"/>
<circle cx="153.4" cy="110.8" r=".28" fill="#fff" stroke="#000" stroke-width=".2"/>
<circle cx="142.8" cy="125.4" r=".49" fill="#008000" stroke="#008000" stroke-width=".2"/>
<circle cx="142.8" cy="125.4" r=".28" fill="#fff" stroke="#000" stroke-width=".2"/>
<circle cx="143.3" cy="134.9" r=".49" fill="#008000" stroke="#008000" stroke-width=".2"/>
<circle cx="143.3" cy="134.9" r=".28" fill="#fff" stroke="#000" stroke-width=".2"/>
<circle cx="171.5" cy="26.3" r=".49" fill="#008000" stroke="#008000" stroke-width=".2"/>
<circle cx="171.5" cy="26.3" r=".28" fill="#fff" stroke="#000" stroke-width=".2"/>
<circle cx="155.2" cy="66.6" r=".49" fill="#008000" stroke="#008000" stroke-width=".2"/>
<circle cx="155.2" cy="66.6" r=".28" fill="#fff" stroke="#000" stroke-width=".2"/>
<circle cx="175" cy="120" r=".49" fill="#008000" stroke="#008000" stroke-width=".2"/>
<circle cx="175" cy="120" r=".28" fill="#fff" stroke="#000" stroke-width=".2"/>
<circle cx="168.2" cy="116.7" r=".49" fill="#008000" stroke="#008000" stroke-width=".2"/>
<circle cx="168.2" cy="116.7" r=".28" fill="#fff" stroke="#000" stroke-width=".2"/>
<circle cx="155.2" cy="129.6" r=".49" fill="#008000" stroke="#008000" stroke-width=".2"/>
<circle cx="155.2" cy="129.6" r=".28" fill="#fff" stroke="#000" stroke-width=".2"/>
<circle cx="148.8" cy="119.9" r=".49" fill="#008000" stroke="#008000" stroke-width=".2"/>
<circle cx="148.8" cy="119.9" r=".28" fill="#fff" stroke="#000" stroke-width=".2"/>
<circle cx="164.2" cy="23.3" r=".49" fill="#008000" stroke="#008000" stroke-width=".2"/>
<circle cx="164.2" cy="23.3" r=".28" fill="#fff" stroke="#000" stroke-width=".2"/>
<circle cx="151.8" cy="63.9" r=".49" fill="#008000" stroke="#008000" stroke-width=".2"/>
<circle cx="151.8" cy="63.9" r=".28" fill="#fff" stroke="#000" stroke-width=".2"/>
<circle cx="174.7" cy="123.7" r=".49" fill="#008000" stroke="#008000" stroke-width=".2"/>
<circle cx="174.7" cy="123.7" r=".28" fill="#fff" stroke="#000" stroke-width=".2"/>
<circle cx="165.2" cy="118.2" r=".49" fill="#008000" stroke="#008000" stroke-width=".2"/>
<circle cx="165.2" cy="118.2" r=".28" fill="#fff" stroke="#000" stroke-width=".2"/>
<circle cx="156.8" cy="22.1" r=".49" fill="#008000" stroke="#008000" stroke-width=".2"/>
<circle cx="156.8" cy="22.1" r=".28" fill="#fff" stroke="#000" stroke-width=".2"/>
<circle cx="144.7" cy="79.9" r=".49" fill="#008000" stroke="#008000" stroke-width=".2"/>
<circle cx="144.7" cy="79.9" r=".28" fill="#fff" stroke="#000" stroke-width=".2"/>
<circle cx="146.5" cy="84.6" r=".49" fill="#008000" stroke="#008000" stroke-width=".2"/>
<circle cx="146.5" cy="84.6" r=".28" fill="#fff" stroke="#000" stroke-width=".2"/>
<circle cx="143.2" cy="92.9" r=".49" fill="#008000" stroke="#008000" stroke-width=".2"/>
<circle cx="143.2" cy="92.9" r=".28" fill="#fff" stroke="#000" stroke-width=".2"/>
<circle cx="145.6" cy="19.7" r=".49" fill="#008000" stroke="#008000" stroke-width=".2"/>
<circle cx="145.6" cy="19.7" r=".28" fill="#fff" stroke="#000" stroke-width=".2"/>
<circle cx="141.2" cy="77" r=".49" fill="#008000" stroke="#008000" stroke-width=".2"/>
<circle cx="141.2" cy="77" r=".28" fill="#fff" stroke="#000" stroke-width=".2"/>
<circle cx="163.6" cy="92.9" r=".49" fill="#008000" stroke="#008000" stroke-width=".2"/>
<circle cx="163.6" cy="92.9" r=".28" fill="#fff" stroke="#000" stroke-width=".2"/>
<circle cx="159.8" cy="94.4" r=".49" fill="#008000" stroke="#008000" stroke-width=".2"/>
<circle cx="159.8" cy="94.4" r=".28" fill="#fff" stroke="#000" stroke-width=".2"/>
<circle cx="158.5" cy="100.5" r=".49" fill="#008000" stroke="#008000" stroke-width=".2"/>
<circle cx="158.5" cy="100.5" r=".28" fill="#fff" stroke="#000" stroke-width=".2"/>
<circle cx="146.5" cy="101.9" r=".49" fill="#008000" stroke="#008000" stroke-width=".2"/>
<circle cx="146.5" cy="101.9" r=".28" fill="#fff" stroke="#000" stroke-width=".2"/>
<circle cx="142.7" cy="16.2" r=".49" fill="#008000" stroke="#008000" stroke-width=".2"/>
<circle cx="142.7" cy="16.2" r=".28" fill="#fff" stroke="#000" stroke-width=".2"/>
<circle cx="141.1" cy="78.5" r=".49" fill="#008000" stroke="#008000" stroke-width=".2"/>
<circle cx="141.1" cy="78.5" r=".28" fill="#fff" stroke="#000" stroke-width=".2"/>
<circle cx="163.9" cy="100.1" r=".49" fill="#008000" stroke="#008000" stroke-width=".2"/>
<circle cx="163.9" cy="100.1" r=".28" fill="#fff" stroke="#000" stroke-width=".2"/>
<circle cx="109.7" cy="110.7" r=".49" fill="#008000" stroke="#008000" stroke-width=".2"/>
<circle cx="109.7" cy="110.7" r=".28" fill="#fff" stroke="#000" stroke-width=".2"/>
<circle cx="142.3" cy="139.6" r=".72" fill="#008000" stroke="#008000" stroke-width=".2"/>
<circle cx="142.3" cy="139.6" r=".47" fill="#fff" stroke="#000" stroke-width=".2"/>
<circle cx="174.7" cy="78.5" r=".49" fill="#008000" stroke="#008000" stroke-width=".2"/>
<circle cx="174.7" cy="78.5" r=".28" fill="#fff" stroke="#000" stroke-width=".2"/>
<circle cx="187" cy="72.7" r=".49" fill="#008000" stroke="#008000" stroke-width=".2"/>
<circle cx="187" cy="72.7" r=".28" fill="#fff" stroke="#000" stroke-width=".2"/>
<circle cx="136.9" cy="62" r=".49" fill="#008000" stroke="#008000" stroke-width=".2"/>
<circle cx="136.9" cy="62" r=".28" fill="#fff" stroke="#000" stroke-width=".2"/>
<circle cx="143.3" cy="35.8" r=".49" fill="#008000" stroke="#008000" stroke-width=".2"/>
<circle cx="143.3" cy="35.8" r=".28" fill="#fff" stroke="#000" stroke-width=".2"/>
<circle cx="125.8" cy="34.2" r=".49" fill="#008000" stroke="#008000" stroke-width=".2"/>
<circle cx="125.8" cy="34.2" r=".28" fill="#fff" stroke="#000" stroke-width=".2"/>
<circle cx="119.9" cy="64.2" r=".49" fill="#008000" stroke="#008000" stroke-width=".2"/>
<circle cx="119.9" cy="64.2" r=".28" fill="#fff" stroke="#000" stroke-width=".2"/>
<circle cx="119.5" cy="67" r=".49" fill="#008000" stroke="#008000" stroke-width=".2"/>
<circle cx="119.5" cy="67" r=".28" fill="#fff" stroke="#000" stroke-width=".2"/>
<circle cx="92.8" cy="125.5" r=".49" fill="#008000" stroke="#008000" stroke-width=".2"/>
<circle cx="92.8" cy="125.5" r=".28" fill="#fff" stroke="#000" stroke-width=".2"/>
<circle cx="133.2" cy="75.5" r=".72" fill="#008000" stroke="#008000" stroke-width=".2"/>
<circle cx="133.2" cy="75.5" r=".47" fill="#fff" stroke="#000" stroke-width=".2"/>
<circle cx="172.9" cy="72.6" r=".49" fill="#008000" stroke="#008000" stroke-width=".2"/>
<circle cx="172.9" cy="72.6" r=".28" fill="#fff" stroke="#000" stroke-width=".2"/>
<circle cx="148.5" cy="74.8" r=".72" fill="#008000" stroke="#008000" stroke-width=".2"/>
<circle cx="148.5" cy="74.8" r=".47" fill="#fff" stroke="#000" stroke-width=".2"/>
<circle cx="99.9" cy="115.8" r=".72" fill="#008000" stroke="#008000" stroke-width=".2"/>
<circle cx="99.9" cy="115.8" r=".47" fill="#fff" stroke="#000" stroke-width=".2"/>
<circle cx="136.7" cy="75.5" r=".72" fill="#008000" stroke="#008000" stroke-width=".2"/>
<circle cx="136.7" cy="75.5" r=".47" fill="#fff" stroke="#000" stroke-width=".2"/>
<circle cx="118.8" cy="49.3" r=".49" fill="#008000" stroke="#008000" stroke-width=".2"/>
<circle cx="118.8" cy="49.3" r=".28" fill="#fff" stroke="#000" stroke-width=".2"/>
<circle cx="114.1" cy="120" r=".49" fill="#008000" stroke="#008000" stroke-width=".2"/>
<circle cx="114.1" cy="120" r=".28" fill="#fff" stroke="#000" stroke-width=".2"/>
<circle cx="162.1" cy="43.8" r=".49" fill="#008000" stroke="#008000" stroke-width=".2"/>
<circle cx="162.1" cy="43.8" r=".28" fill="#fff" stroke="#000" stroke-width=".2"/>
<circle cx="165.5" cy="90.2" r=".49" fill="#008000" stroke="#008000" stroke-width=".2"/>
<circle cx="165.5" cy="90.2" r=".28" fill="#fff" stroke="#000" stroke-width=".2"/>
<circle cx="122" cy="57.9" r=".49" fill="#008000" stroke="#008000" stroke-width=".2"/>
<circle cx="122" cy="57.9" r=".28" fill="#fff" stroke="#000" stroke-width=".2"/>
<circle cx="165.7" cy="97" r=".49" fill="#008000" stroke="#008000" stroke-width=".2"/>
<circle cx="165.7" cy="97" r=".28" fill="#fff" stroke="#000" stroke-width=".2"/>
<circle cx="151.4" cy="69.1" r=".49" fill="#008000" stroke="#008000" stroke-width=".2"/>
<circle cx="151.4" cy="69.1" r=".28" fill="#fff" stroke="#000" stroke-width=".2"/>
<circle cx="156.9" cy="54.6" r=".49" fill="#008000" stroke="#008000" stroke-width=".2"/>
<circle cx="156.9" cy="54.6" r=".28" fill="#fff" stroke="#000" stroke-width=".2"/>
<circle cx="147.5" cy="55.5" r=".49" fill="#008000" stroke="#008000" stroke-width=".2"/>
<circle cx="147.5" cy="55.5" r=".28" fill="#fff" stroke="#000" stroke-width=".2"/>
<circle cx="132.9" cy="102" r=".49" fill="#008000" stroke="#008000" stroke-width=".2"/>
<circle cx="132.9" cy="102" r=".28" fill="#fff" stroke="#000" stroke-width=".2"/>
<circle cx="132.1" cy="103.3" r=".49" fill="#008000" stroke="#008000" stroke-width=".2"/>
<circle cx="132.1" cy="103.3" r=".28" fill="#fff" stroke="#000" stroke-width=".2"/>
<circle cx="157.4" cy="68.6" r=".49" fill="#008000" stroke="#008000" stroke-width=".2"/>
<circle cx="157.4" cy="68.6" r=".28" fill="#fff" stroke="#000" stroke-width=".2"/>
<circle cx="124.8" cy="103.4" r=".49" fill="#008000" stroke="#008000" stroke-width=".2"/>
<circle cx="124.8" cy="103.4" r=".28" fill="#fff" stroke="#000" stroke-width=".2"/>
<circle cx="45" cy="103.4" r=".49" fill="#008000" stroke="#008000" stroke-width=".2"/>
<circle cx="45" cy="103.4" r=".28" fill="#fff" stroke="#000" stroke-width=".2"/>
<circle cx="124.8" cy="109.6" r=".49" fill="#008000" stroke="#008000" stroke-width=".2"/>
<circle cx="124.8" cy="109.6" r=".28" fill="#fff" stroke="#000" stroke-width=".2"/>
<circle cx="154.9" cy="50.6" r=".49" fill="#008000" stroke="#008000" stroke-width=".2"/>
<circle cx="154.9" cy="50.6" r=".28" fill="#fff" stroke="#000" stroke-width=".2"/>
<circle cx="228.7" cy="112.1" r=".49" fill="#008000" stroke="#008000" stroke-width=".2"/>
<circle cx="228.7" cy="112.1" r=".28" fill="#fff" stroke="#000" stroke-width=".2"/>
<circle cx="195.3" cy="109" r=".49" fill="#008000" stroke="#008000" stroke-width=".2"/>
<circle cx="195.3" cy="109" r=".28" fill="#fff" stroke="#000" stroke-width=".2"/>
<circle cx="121.1" cy="46.9" r=".49" fill="#008000" stroke="#008000" stroke-width=".2"/>
<circle cx="121.1" cy="46.9" r=".28" fill="#fff" stroke="#000" stroke-width=".2"/>
<circle cx="136.2" cy="44.4" r=".49" fill="#008000" stroke="#008000" stroke-width=".2"/>
<circle cx="136.2" cy="44.4" r=".28" fill="#fff" stroke="#000" stroke-width=".2"/>
<circle cx="225.8" cy="88.9" r=".49" fill="#008000" stroke="#008000" stroke-width=".2"/>
<circle cx="225.8" cy="88.9" r=".28" fill="#fff" stroke="#000" stroke-width=".2"/>
<circle cx="194.8" cy="94.2" r=".49" fill="#008000" stroke="#008000" stroke-width=".2"/>
<circle cx="194.8" cy="94.2" r=".28" fill="#fff" stroke="#000" stroke-width=".2"/>
<circle cx="138.8" cy="103.1" r="97.7" fill="none" stroke="#f90" stroke-width=".42"/>
<circle cx="144" cy="190.9" r="1.14" fill="none" stroke="#f90" stroke-width=".2"/>
<circle cx="144" cy="190.9" r="1.14" fill="#fff" stroke="#000" stroke-width=".2"/>
<circle cx="133.6" cy="190.9" r="1.14" fill="none" stroke="#f90" stroke-width=".2"/>
<circle cx="133.6" cy="190.9" r="1.14" fill="#fff" stroke="#000" stroke-width=".2"/>
<circle cx="45.1" cy="108.5" r="1.23" fill="none" stroke="#f90" stroke-width=".2"/>
<circle cx="45.1" cy="108.5" r="1.23" fill="#fff" stroke="#000" stroke-width=".2"/>
<circle cx="45.1" cy="100.4" r="1.23" fill="none" stroke="#f90" stroke-width=".2"/>
<circle cx="45.1" cy="100.4" r="1.23" fill="#fff" stroke="#000" stroke-width=".2"/>
</svg>
